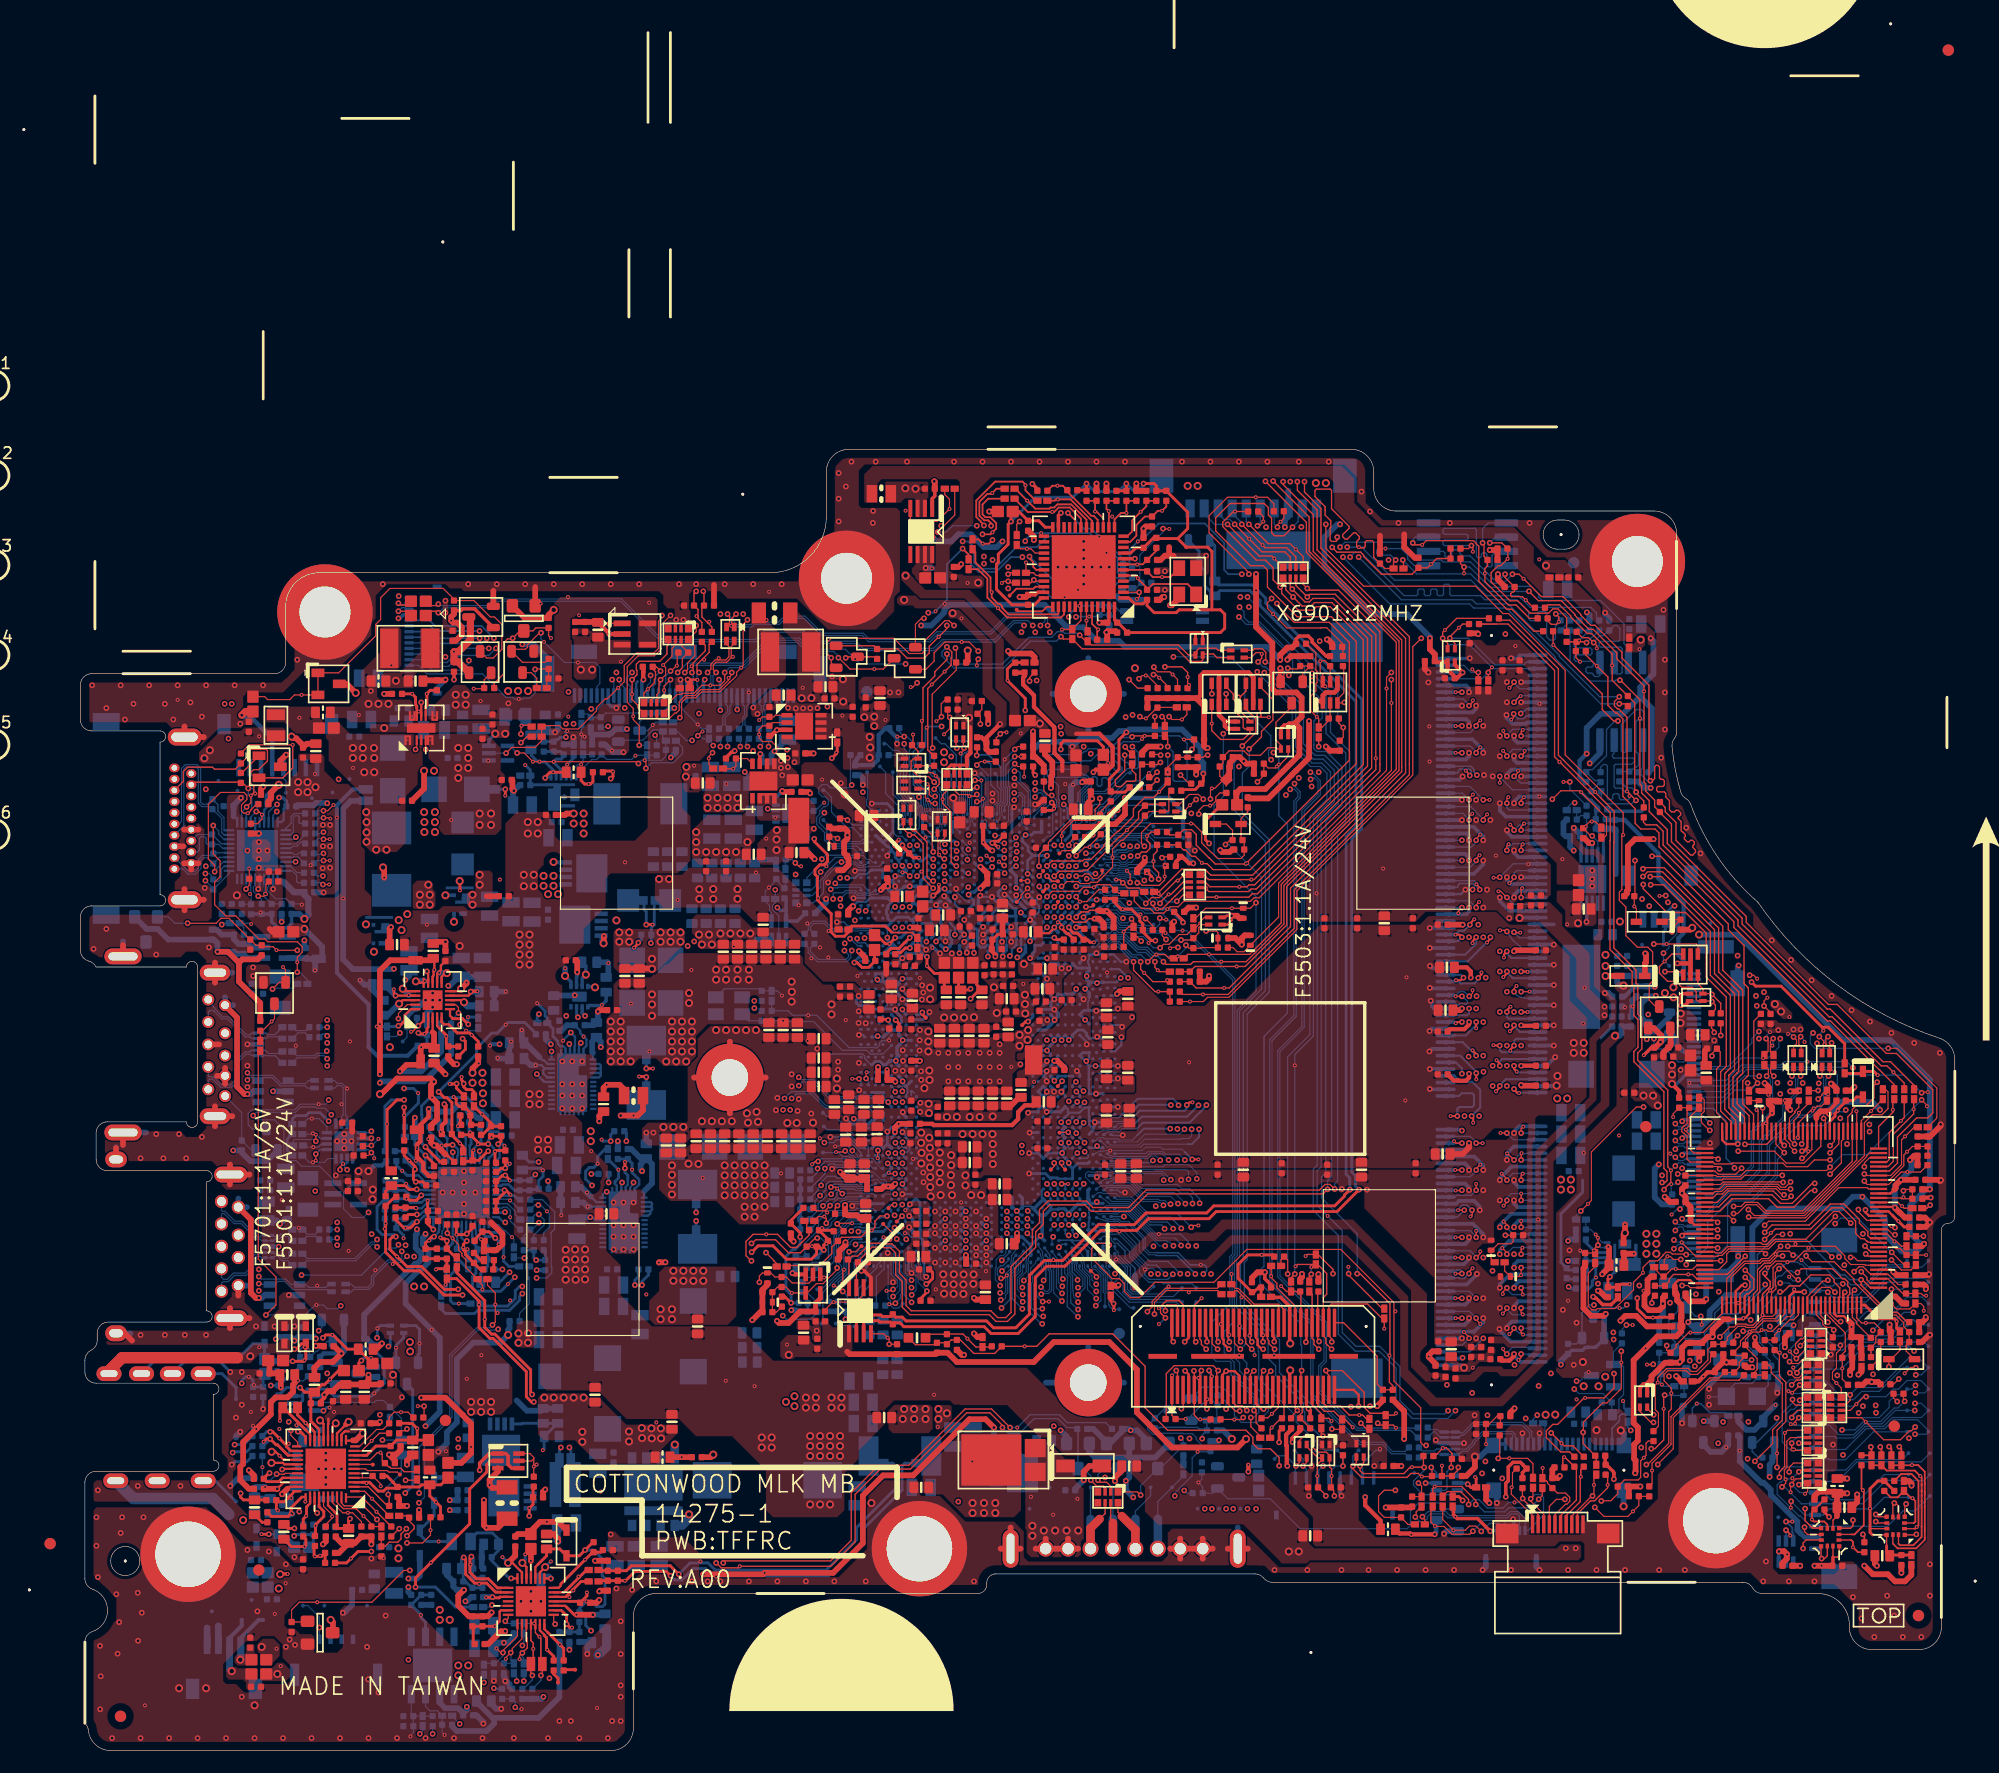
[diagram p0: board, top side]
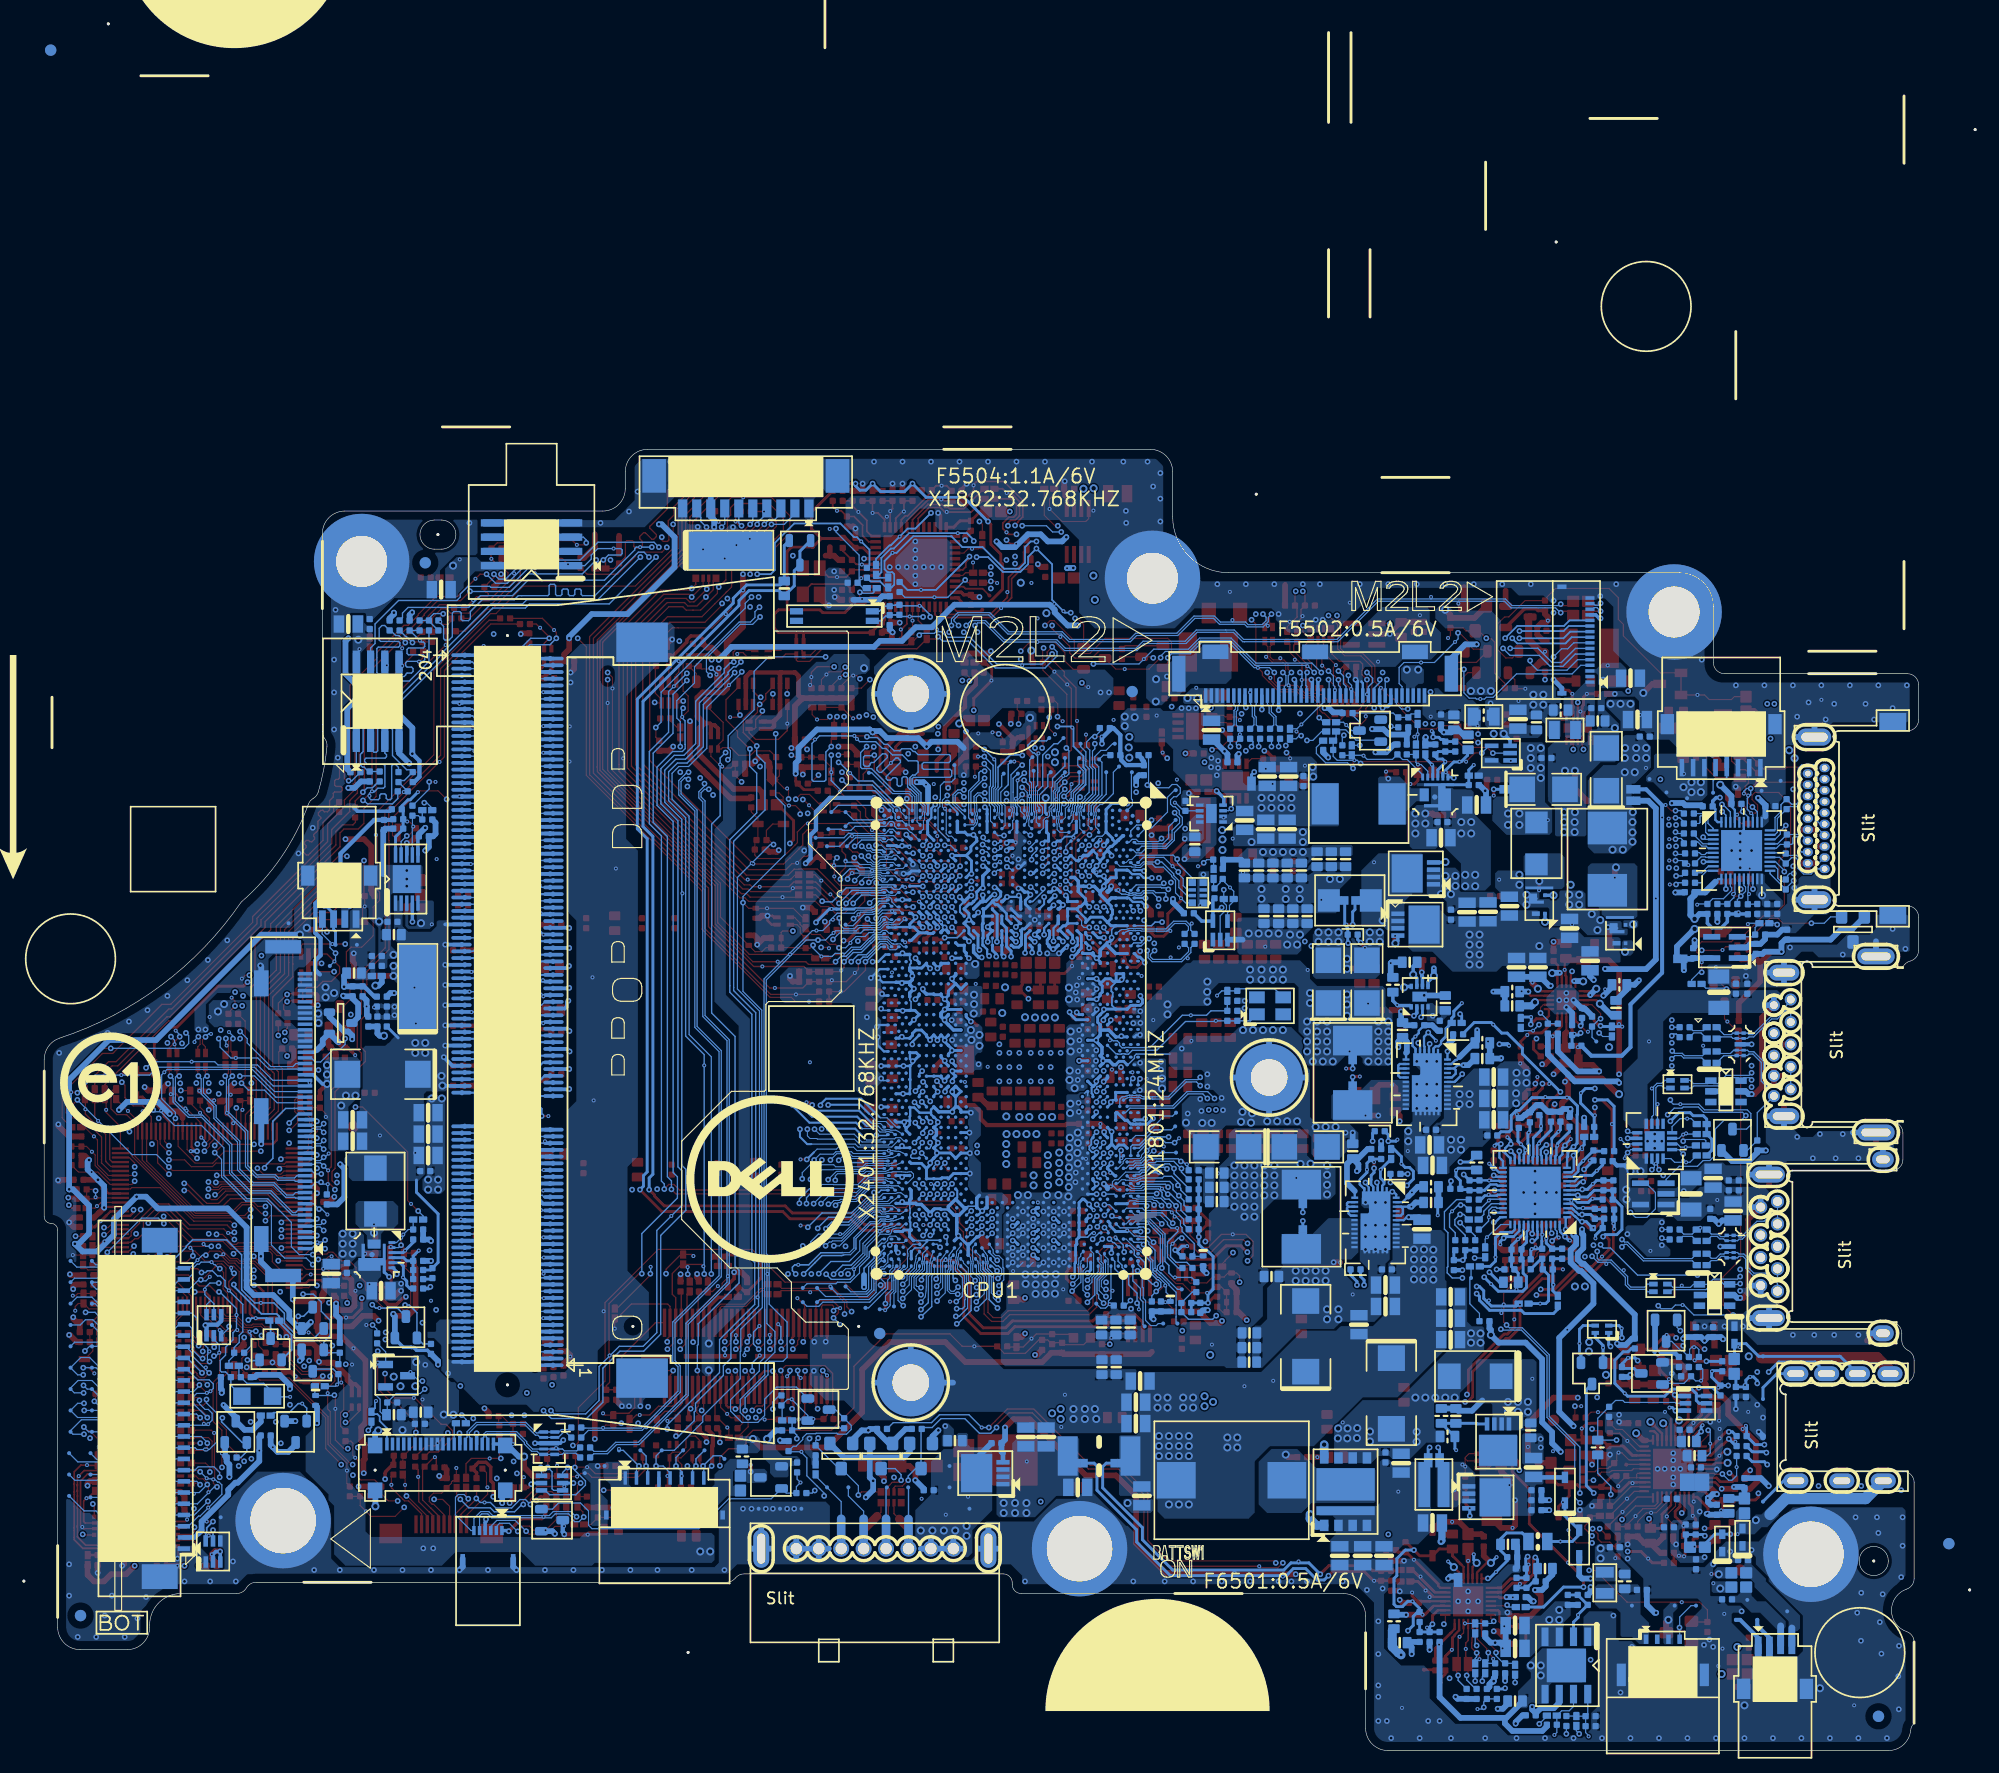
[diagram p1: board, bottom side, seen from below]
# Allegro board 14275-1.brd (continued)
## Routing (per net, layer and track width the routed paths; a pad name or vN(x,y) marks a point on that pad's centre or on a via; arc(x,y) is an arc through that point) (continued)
+VCCCLK5: length 9.6
  TOP w0.254: v2(79.36,67.91) 79.25,67.81 C2122.1 78.29,67.99 R2111.2
  L3 w0.127: v2(75.42,72.11) 75.94,71.59 75.94,70.49 76.36,70.07
  L3 w0.254: v2(79.36,67.91) 78.52,67.91 76.36,70.07
  BOTTOM w0.254: CPU1.L19 75.42,72.64 v2(75.42,72.11)
+VCCCOREG0: length 1.2
  TOP w0.254: v2(75.06,65.8) 75.06,65.63 TP701.1
  BOTTOM w0.254: CPU1.K32 74.86,65.61 v2(75.06,65.8)
+VCCCOREG1: length 1.5
  TOP w0.254: TP707.1 84.28,64.99 v2(84.49,64.99)
  BOTTOM w0.254: v2(84.49,64.99) 84.91,65.41 CPU1.AK32
+VCCDSW_1P0: length 3
  TOP w0.254: C2103.1 85.92,83.81 86.62,83.81 86.77,83.97 v1(86.8,83.97) 86.8,84.3 v2(86.59,84.51)
  BOTTOM w0.127: v2(86.59,84.51) 86.57,84.51 85.69,83.63 CPU1.AL1
+VCCFUSEPRG: length 3.6
  TOP w0.254: v2(72.63,72.46) 72.63,72.44 72.13,71.93 v1(72.13,71.92) 72.12,71.93 71.77,71.93 71.01,72.69 R703.1
  BOTTOM w0.254: v2(72.63,72.46) 73.15,72.46 CPU1.G20
+VCCGT: length 16.9
  BOTTOM w0.114: v2(80.76,46.11) 81.09,45.79 CPU1.AC67 ; CPU1.W71 79.26,43.19 78.93,43.51 ; CPU1.AC71 81.09,43.19 v2(80.76,43.51) ; CPU1.AA71 80.17,43.19 79.85,43.51 ; v2(79.85,44.81) 80.17,44.49 CPU1.AA69 ; v2(76.19,46.11) 76.51,45.79 CPU1.N67 ; v2(79.85,46.11) 80.17,45.79 CPU1.AA67 ; CPU1.AC69 81.09,44.49 v2(80.76,44.81) ; CPU1.AA66 80.17,46.44 v2(79.85,46.76) ; CPU1.U71 78.34,43.19 v2(78.02,43.51)
  BOTTOM w0.127: CPU1.A53 69.47,53.71 68.48,54.7 v2(66.86,54.7) ; 74.07,58.39 CPU1.J43 74.19,58.75 74.35,58.59 ; CPU1.A58 69.78,51.36 69.41,51.36 69.22,51.55 68.9,51.55 68.45,52 67.28,52 67.14,51.86 v2(67.01,51.86) ; v2(68.82,48.56) 69.01,48.75 CPU1.A62
  BOTTOM w0.203: CPU1.J60 v2(73.28,49.61)
  BOTTOM w0.254: v2(68.94,56.33) 69.04,56.23 69.87,56.23 CPU1.A48
  BOTTOM w0.305: v2(69.36,46.27) 69.36,46.27 CPU1.A66
  vias: v1(55.48,51.05) v1(62.47,51.45) v1(74.23,52.75) v1(76.26,41.12) v1(78.52,48.86) v1(80.73,42.74) v2(74.89,57.75) v2(74.86,56.94) v2(75.14,51.53) v2(75.17,50.67) v2(76.19,48.06) v2(76.19,46.76) v2(76.19,44.81) v2(76.19,43.51) v2(77.1,48.06) v2(77.1,46.76) v2(77.1,46.11) v2(77.1,44.81) v2(77.1,43.51) v2(78.02,48.06) v2(78.02,46.76) v2(78.02,46.11) v2(78.02,44.81) v2(78.93,47.41) v2(78.93,46.76) v2(79.85,48.06) v2(79.85,44.16) v2(80.76,47.41) v2(80.76,44.16) v3(52.74,52.16) v3(52.74,51.33) v3(52.74,50.44) v3(52.74,49.57) v3(54.21,52.32) v3(55.1,52.3) v3(57.44,52.16) v3(57.44,51.28) v3(57.44,50.39) v3(57.44,49.5) v3(58.33,52.16) v3(58.33,51.28) v3(58.33,50.39) v3(58.33,49.5) v3(59.21,52.16) v3(59.21,51.28) v3(59.21,50.39) v3(59.21,49.5) v3(59.21,48.48) v3(59.21,47.59) v3(60.1,52.16) v3(60.1,51.28) v3(60.1,50.39) v3(60.1,49.5) v3(60.1,48.48) v3(60.1,47.59) v3(60.99,52.16) v3(60.99,51.28) v3(60.99,50.39) v3(60.99,49.5) v3(60.99,48.48) v3(74.95,54.18) v3(74.96,55.09) v3(74.99,53.28) v3(74.96,52.34) v3(75.62,57.66) v3(75.65,56.83) v3(75.67,54.63) v3(75.72,53.74) v3(75.72,52.88) v3(75.75,51.99) v3(75.76,51.12) v3(75.76,50.23) v3(75.8,49.4) v3(76.61,53.31) v3(76.61,52.39) v3(76.61,51.5) v3(76.61,50.67) v3(76.69,49.52) v3(76.92,42.45) v3(76.99,41.62) v3(76.99,40.73) v3(77.63,53.08) v3(77.63,52.19) v3(77.6,51.3) v3(77.6,50.41) v3(77.71,49.52) v3(77.84,41.56) v3(77.84,40.72) v3(77.86,42.45) v3(78.74,42.45) v3(78.72,41.56) v3(78.72,40.71) v3(78.9,51.28) v3(78.9,50.39) v3(79.41,49.52) v3(79.63,42.45) v3(79.61,41.61) v3(80.3,49.52)
+VCCIO: length 80
  TOP w0.381: R9906.1 107.93,28.6 107.49,28.15 107.49,27.21 107.55,27.15 107.55,25.42 v2(107.6,25.37) ; R801.1 75.95,55.87 76.07,55.76 83.06,55.76 83.6,56.3 83.6,56.92 84.2,57.52 84.92,57.52 PC1035.1
  L3 w0.305: v2(107.6,25.37) 107.6,25.59 107.14,26.05 105.82,26.05 105.42,26.46 98.1,26.46 94.39,30.17 87.94,30.17 84.87,33.24 84.87,42 83.53,43.34 83.53,44.09 82.02,45.6 82.02,48.98 82.78,49.73 82.78,56.93 83.85,58.01 83.85,58.9 84.49,59.53
  L4 w0.102: 75.85,72.36 75.85,71.72
  L6 w0.508: v2(86.14,60.57) 84.84,60.57 84.61,60.8 84.61,62.3 85.27,62.96 85.27,65.35 84.92,65.7 v3(84.23,65.7)
  BOTTOM w0.254: v2(86.14,59.66) 86.14,59.83 CPU1.AM42 86.14,60.41 v2(86.14,60.57) 86.13,60.58 CPU1.AL42
  vias: v1(67.93,92.27) v1(84.06,68.34) v3(70.36,90.37) v3(70.42,89.43) v3(70.36,88.51) v3(84.21,67.38) v3(84.21,66.54)
+VCCMPHYGTAON_1P0_LS_SIP: length 12
  L6 w0.254: v2(82.23,70.78) 82.07,70.94 82.07,70.99 81.62,71.45 80.17,71.45 79.01,72.61 78.92,72.61 v2(78.8,72.74)
  BOTTOM w0.102: CPU1.AF20 82.58,72.42 82.58,71.8 CPU1.AF21
  BOTTOM w0.178: v2(77.12,72.15) 77.12,73.32 CPU1.N18
  BOTTOM w0.254: CPU1.T20 78.52,72.58 78.64,72.58 v2(78.8,72.74) ; v2(82.23,70.78) 82.23,71 82.57,71.34 CPU1.AF21
  BOTTOM w0.305: CPU1.P15 77.04,76.18 v2(77.01,76.18) ; CPU1.N17 CPU1.N18 ; CPU1.N15 76.59,75.69 v2(76.28,75.38) 76.63,75.04 CPU1.N16 ; v2(77.12,75.36) 77.44,75.04 CPU1.P16 ; v2(78.8,72.74) 78.45,73.09 CPU1.T19
  vias: v1(61.14,81.3) v2(65.39,82.19) v3(62.08,82.06) v3(62.06,81.22) v3(62.06,80.28)
+VCCPAZIO: length 38
  TOP w0.254: v2(84.23,92.73) 84.23,93.8 82.66,95.37 v1(82.66,95.4) 82.63,95.42 82.63,96.41 83.2,96.98 R2101.2 83.36,97 R2102.2
  L4 w0.254: v2(83.73,71.37) 84.65,71.37 85.17,71.88 85.17,72.42 82.99,74.6 82.99,75.98 82.9,76.07 82.9,78.42 82.89,78.43 82.89,82.34 81.14,84.09 79.71,84.09 79.22,84.58 79.22,89.1 79.41,89.29 79.41,91.4 79.83,91.82 79.83,91.82 80.17,92.17 83.73,92.17 84.23,92.68 v2(84.23,92.73)
  BOTTOM w0.254: v2(83.73,71.37) 83.85,71.49 83.85,72.7 CPU1.AJ19
+VCCPDSW_3P3: length 33.7
  TOP w0.254: v2(95.83,72.21) 95.49,72.21 94.72,72.98 R1703.1 94.72,73.68 94.44,73.96 94.44,74.26 93.7,75.01 v1(92.91,75.01) 92.79,75.01 92.23,75.56 R1707.1 92.13,75.96 91.45,75.96 R1723.1 ; R1711.2 91.19,89.49 90.67,90.01 87.67,90.01 87.41,89.75 v2(87.41,89.25)
  L3 w0.254: v2(80.91,70.78) 80.91,70.94 81.44,71.47 83.09,71.47 83.84,72.22 v2(83.84,74.71)
  L4 w0.254: v2(95.83,72.21) 95.83,72.01 95.71,71.89 95.71,71.55 95.12,70.96 93.23,70.96 92.34,71.85 86.52,71.85 86.27,72.1
  BOTTOM w0.254: v2(80.91,70.78) 80.91,71.28 81.31,71.69 81.31,72.91 81.31,72.91 81.31,73.32 CPU1.AD18 CPU1.AD17 ; CPU1.AJ17 84.16,74.39 v2(83.84,74.71)
+VCCPRTC_3P3: length 36
  TOP w0.254: C2117.1 98.3,73.98 v2(98.3,73.82) ; v2(100.62,80.87) 100.29,81.2 100.29,82.91 101.7,84.31 R2106.2 ; C2118.1 87,72.29 v2(86.82,72.47)
  L3 w0.254: v2(86.82,72.47) 91.47,72.47 92.1,73.09 98,73.09 98.3,73.4 v2(98.3,73.82) 98.59,74.11 98.59,76.93 100.62,78.97 v2(100.62,80.87)
  BOTTOM w0.127: CPU1.AK19 85.7,72.47 v2(86.82,72.47) ; CPU1.BB14 92,75.73 92.68,75.73 93.23,75.17 93.35,75.17 93.41,75.11 94.8,75.11 94.9,75.01
  BOTTOM w0.254: v2(98.3,73.82) 97.1,75.02 v1(96.91,75.02) 96.47,75.02 96.46,75.01 94.9,75.01
+VCCSA: length 2
  TOP w0.508: R735.1 71.84,69.23
  BOTTOM w0.127: CPU1.G27 73.29,68.03 v2(73.29,67.9) 73.29,67.76 CPU1.G28
  vias: v1(53.25,75.84) v1(60.23,78.28) v1(64.04,75.36) v1(65.95,71.6) v1(69.27,69.06) v1(74.84,68.88) v2(75.04,68.22) v2(75.01,66.95) v2(75.14,67.58) v3(51.59,77.69) v3(52.48,77.69) v3(55.18,76.78) v3(55.18,75.93) v3(56.42,76.8) v3(56.42,75.91) v3(58.58,76.8) v3(58.58,75.93) v3(75.75,68.01) v3(75.75,66.97) v3(84.11,70.12)
+VCCSFR: length 1.3
  BOTTOM w0.203: CPU1.K20 74.96,72.37 74.96,71.85 CPU1.K21
  BOTTOM w0.254: CPU1.K21 75.39,71.42 v2(75.39,71.39)
  vias: v1(75.95,71.57)
+VCCST_CPU: length 84.3
  TOP w0.254: R603.2 67.07,46.38 R723.1 66.64,45.58 R726.1 66.28,45.07 v2(66.28,44.62) 66.17,44.62 65.87,44.93 R727.1 65.63,44.26 65.18,43.81 62.93,43.81 61.74,45 60.42,45 59.86,44.43 v2(59.84,44.43)
  L4 w0.254: v2(67.44,73.86) 67.42,73.88 65.79,73.88 64.55,72.64 64.55,63.6 60.51,59.56 60.51,58.77 58.81,57.07 58.81,56.56 58.91,56.46 58.91,55.64 59.29,55.26 60.99,55.26 61.85,54.41 61.85,47.76 59.81,45.72 59.62,45.72 59.32,45.42 59.32,44.95 v2(59.84,44.43) 59.98,44.43 60.58,43.84 60.58,43.42 54.76,37.61 48.73,37.61 45.46,40.88 42.79,40.88 41.45,42.22 41.45,42.9 v2(40.63,43.72)
  BOTTOM w0.127: v2(67.44,73.86) 68.07,73.86 68.39,73.53 CPU1.A18
  BOTTOM w0.254: v1(65.21,44.96) 65.21,44.97 65.66,44.97 66.01,44.62 v2(66.28,44.62) 65.72,44.06 R419.1 ; PR4621.1 PR4622.1 40.42,43.94 v2(40.63,43.72) PC4610.1 41.43,44.48 PR4623.2
+VCCSTG: length 84.8
  TOP w0.254: v2(63.35,39.91) 62.8,40.46 R1722.1 ; R703.2 70.8,70.47 C4008.1 70.28,69.82 69.67,69.82 69.24,70.25 v2(68.99,70.25) ; R4042.2 67.47,89.05 v1(67.39,88.97) 67.39,88.87 v2(66.99,88.46) ; R423.2 63.33,47.25 C717.1 64.17,46.15 v2(64.17,45.79)
  L4 w0.254: v2(63.35,39.91) 62.97,40.29 62.97,42.95 61.7,44.22 61.7,46.22 63,47.51 63,54.57 61.32,56.25 61.32,57.09 61.12,57.29 61.12,59.31 65.18,63.37 65.18,69.56 65.92,70.3 68.76,70.3 68.81,70.25 v2(68.99,70.25) 69.1,70.25 70.47,71.61 70.47,72.64 69.61,73.5 68.83,73.5 68.49,73.85 68.49,74.44 68.15,74.77 66.89,74.77 65.96,75.7 65.96,77.41 66.45,77.9 66.48,77.9 66.86,78.28 66.86,82.49 67.06,82.7 67.06,85.92 66.96,86.02 66.96,86.63 67.06,86.74 67.06,88.39 v2(66.99,88.46)
  BOTTOM w0.254: v2(68.99,70.25) 68.99,70.32 69.41,70.73 69.59,70.73 CPU1.A22 ; PR4624.1 R401.1 64.83,39.91 R2440.1 v2(63.35,39.91) 63.35,40.66 62.9,41.12 62.9,44.06 63.51,44.67 63.71,44.67 64.17,45.13 v2(64.17,45.79) 64.18,45.8 R421.2 R416.2 R417.2 R408.2 R422.2 R409.2
+VDD18: length 30.5
  TOP w0.203: 22.64,21.3 22.08,21.87 HDA27.38 ; HDA27.18 21.28,28.63 21.11,28.8
  TOP w0.254: C2728.1 20,31.95 v2(19.59,32.35) ; C2728.1 20.54,31.63 C2727.1 20.54,29.37 21.11,28.8 ; C2728.1 21.52,32.61 21.75,32.61 v1(22.26,33.11) 23.02,33.88 R2725.2 ; 22.64,21.3 22.88,21.07 22.88,20.08 C2712.1 22.93,19.81 C2726.1 23.91,20.54 v2(24.04,20.67)
  L6 w0.254: v2(24.04,20.67) 23.78,20.92 23.78,25.49 19.59,29.69 v2(19.59,32.35)
  BOTTOM w0.254: R2916.1 18.36,32.35 v2(19.59,32.35)
+VDDQ_CPU_CLK: length 0.6
  BOTTOM w0.254: v2(86.16,61.46) 86.16,61.35 CPU1.AM40
  vias: v1(85.02,59.61)
AV1_TP: length 5.9
  BOTTOM w0.102: TP2307.1 93.33,87.17 91.47,85.31 90.02,85.31 89.73,85.02 CPU1.AV1
AV71_TP: length 2
  TOP w0.102: TP2304.1 90.58,42.26 v2(90.58,42.22)
  BOTTOM w0.102: v2(90.58,42.22) 90.58,42.31 89.8,43.09 CPU1.AV71
AVDD5V: length 28.8
  TOP w0.203: 18.03,24.31 HDA27.29
  TOP w0.254: 18.03,24.31 17.69,23.97 16.61,23.97 C2713.1 16.35,24.29 16.8,24.74 v2(16.86,24.74) ; R2722.2 R2726.2 23.79,35.78 22.52,37.05 v1(22.46,37.05) 21.88,37.05 v2(21.62,36.8)
  L4 w0.254: v2(16.86,24.74) 16.86,24.41 17.18,24.1 18.07,24.1 18.57,24.61 18.57,27.65 17.24,28.99 17.24,30.64 16.29,31.59 16.29,33.11 16.67,33.5 19.11,33.5 21.62,36 v2(21.62,36.8)
GND: length 1427.7
  TOP w0.114: v2(160.05,21.05) 160.26,20.84 U7001.7 ; U7002.6 153.83,18.77 153.58,18.51 v2(153.58,18.02) ; U7002.5 153.96,19.27 153.7,19.53 v2(153.7,19.91) ; U7002.7 155.18,17.16 v2(155.23,17.11) 155.48,17.11 155.74,17.37 U7002.8 ; U7001.8 160.18,20.28 v2(160.05,20.41) ; U7001.5 162.08,21.81 161.83,22.07 v2(161.71,22.07) 161.58,21.93 U7001.6
  TOP w0.203: v2(109.48,30.48) 109.48,30.61 109.3,30.79 XDP1.49 ; KBC24.64 146.36,54.43 146.71,54.07 v2(147.75,54.07) ; RN1703.1 102.25,73.63 102.62,74 v2(102.62,74.42) 102.2,74.42 102.05,74.28 RN1703.2 ; XDP1.38 106.3,36.92 106.43,36.8 v2(106.43,36.45) ; XDP1.59 113.51,32.16 113.95,31.72 v2(113.95,30.7) ; v2(142.79,45.91) 142.95,46.07 KBC24.84 ; XDP1.14 100.3,36.92 100.43,36.8 v2(100.43,36.45) ; XDP1.7 98.8,33.53 v2(98.48,33.85) ; XDP1.26 103.3,36.58 v2(103.43,36.45) ; KBC24.124 157.16,40.73 v2(157.29,40.86) ; XDP1.20 101.8,36.75 101.91,36.64 101.91,36.26 v2(102.39,35.78) ; v2(105.44,35.78) 105.32,35.78 104.93,36.16 104.93,36.67 104.8,36.8 XDP1.32 ; XDP1.31 104.8,30.92 105.28,30.45 v2(105.48,30.45) 105.53,30.45 105.69,30.6 106.13,30.6 106.3,30.78 XDP1.37 ; KBC24.17 159.45,47.67 159.14,47.98 v2(159.14,48.2) ; v2(100.43,30.47) 100.3,30.6 XDP1.13 ; KBC24.100 147.56,40.94 148.11,41.5 v2(148.39,41.5) ; XDP1.19 101.8,33.49 v2(102.14,33.83) 102.9,33.83 103.3,33.43 XDP1.25 ; KBC24.51 151.56,54.28 v2(151.9,53.94) ; v2(86.82,73.38) 86.82,73.35 86.34,72.87 85.5,72.87 PC1038.2 ; v2(97.43,36.45) 97.3,36.58 XDP1.2 ; U4001.11 v2(30.39,93.44) ; XDP1.50 109.3,36.47 v2(109.25,36.42) ; PU4401.22 v2(41.94,15.33) ; v2(98.45,36.44) 98.8,36.8 XDP1.8
  TOP w0.254: v2(155.89,20.84) 155.48,21.24 R7019.1 ; v2(29.81,56.42) 29.7,56.31 PG4601.2 ; C2121.2 81.78,72.76 C2120.2 ; C9901.2 106.86,28.48 v2(106.86,27.48)
  TOP w0.305: U6901.35 85.34,103.26 85.12,103.03 C6903.2 ; C9904.2 106.14,41.52 105.59,42.07 v2(105.59,42.64) ; U4101.1 75.94,111.61 76.17,111.84 C4102.2 ; PQ4407.4 38.45,25.17 38.13,25.49 38.13,26.26 37.91,26.48 PQ4407.1 36.45,26.48 35.59,25.62 v2(35.59,24.99) ; U6901.47 91.69,100.71 C6904.2 ; v2(87.41,110.33) 87.19,110.11 U6901.23 ; v2(58.33,89.12) 58.2,88.99 58.03,88.99 57.55,88.51 C1719.2 ; v2(69.63,42.77) 69.88,42.77 70.48,42.17 THM261.5 ; v2(109.48,30.48) 109.63,30.32 C9903.2 ; v2(84.87,112.92) 85.31,112.48 R6908.1 ; U6901.8 v2(94.01,106.26)
  TOP w0.356: U1701.3 63.75,42.45 63.74,42.46 63.58,42.46 v2(63.48,42.56) ; v2(21.75,31.72) 21.75,31.46 21.43,31.15 C2727.2
  TOP w0.381: v2(81.57,70.78) 81.57,70.96 81.25,71.28 C2108.2 81.25,72.23 C2121.2 ; v2(127.8,35.35) 127.78,35.33 127.78,35.15 127.39,34.77 126.71,34.77 C1206.2 ; C4033.2 61.57,90.47 v2(62.08,90.98) 62.1,91 U4002.3 ; PR4652.2 32.23,55.71 32.55,56.04 32.55,57.52 v2(32.44,57.63) ; U5501.2 v2(47.15,99.54) 47.15,99.56 C5505.2 ; C1211.2 128.44,61.05 v2(128.44,61.05) ; EC5501.2 50.2,96.55 50.2,96.15 50.17,96.13 50.17,95.58 50.2,95.55 v2(50.2,95.47) ; C1212.2 128.48,64.61 v2(128.44,64.65) ; v2(123.8,60.34) 123.8,59.99 123.52,59.71 122.86,59.71 122.83,59.73 122.43,59.73 122.05,60.11 122.05,60.13 C1221.2 ; R2449.1 142.53,58.79 v3(141.89,59.43) ; C1207.2 123.6,69.82 123.95,69.47 v2(123.95,68.91) ; v2(85.1,84.34) 85.38,84.34 85.77,84.74 C2103.2 ; v2(123.8,64.95) 123.8,64.73 123.38,64.31 122.09,64.31 C1213.2
  TOP w0.406: Q1701.4 112.06,94.6 111.79,94.33 111.03,94.33 110.76,94.06 Q1701.1 110.59,93.56 v2(110.13,93.56)
  TOP w0.508: EC8915.2 30.64,85.76 v3(30.64,87.34) ; v2(94.14,112.95) R6914.1 R6916.1 ; EC8926.2 27.57,73.27 v2(27.69,73.4) ; C1154.2 87.73,60.86 87.1,61.49 v2(86.82,61.49) ; C2405.2 141.08,40.37 v2(141.08,39.85) 141.08,39.6 140.74,39.26 139.82,39.26 139.43,39.65 139.43,40.54 139.71,40.81 139.71,41.95 140.01,42.26 R2436.2 ; R2717.2 23.04,17.62 C2726.2 ; USB2.4 14.08,40.56 ; v2(144.32,34.76) 144.32,35.22 C2420.2 C2413.2 ; v2(106.97,96.48) 107,96.45 Q1802.S ; v2(157.77,33.5) 157.77,33.9 157.96,34.09 R2454.2 157.89,35.08 C2428.2 ; 13.33,37.66 USB2.11 ; USB2.11 15.07,38.55 ; USB2.11 13.33,39.44 ; v2(163.24,23.62) 163.24,23.8 163.01,24.03 R7007.1 ; C2402.2 149.68,58.79 C2423.2 150.53,59.12 v2(150.15,59.51) ; 57.9,56.81 HS1.1 ; HS1.1 57.9,63.19 ; HS1.1 61.09,60 ; HS1.1 54.71,60 ; EC1705.2 103.79,72.68 103.54,72.42 v2(103.54,71.85) 102.95,72.43 EC1711.2 ; PR4517.2 32.8,61.69 33.31,61.18 v2(33.56,61.18) ; 9.88,78.54 HDMI1.2 ; HDMI1.2 9.24,79.1 ; HDMI1.2 10.52,79.1 ; v2(123.16,66.15) 123.02,66.01 C1209.2 ; C2713.2 15.46,24.54 v2(15.02,24.99) ; EC6503.2 123.54,24.48 124.31,25.25 v3(124.31,26.21) ; v2(80.25,78.79) 80.84,78.2 C2107.2 C2106.2 80.7,77.31 v2(80.25,76.86) ; PC4524.2 31.6,72.1 v2(32.54,72.1) PC4513.2 ; v2(68.15,48.63) 68.17,48.62 R406.2 68.26,47.85 68.39,47.72 69.22,47.72 69.5,47.44 PC1033.2 ; C2409.2 R2448.2 164.89,54.74 165.84,55.69 v2(165.84,55.82) ; v2(115.6,30.7) 116.11,31.21 R9931.2 ; v2(135.29,40.99) 135.4,40.99 135.97,40.42 PC5110.2 ; v2(105.59,42.64) 104.94,42.64 104.44,42.14 C9902.2 ; v2(97.14,102.1) 97.31,102.1 97.95,102.74 X6901.4 ; 67.51,78.48 68.01,78.48 68.49,78.95 68.49,79.48 68.38,79.59 68.38,79.72 C2116.2 68.09,80 EC1702.2 68.09,81.01 68.38,81.3 v2(68.38,81.6) 68.38,81.96 68.14,82.2 EC1706.2 66.94,82.2 66.78,82.35 R1717.2 ; C2411.2 156.55,59.02 156.12,59.45 v2(156.05,59.45) ; v2(42.58,18.64) 42.58,18.89 42.17,19.3 PC4422.2 ; v2(25.69,33.5) 25.69,33.01 C2708.2 ; C1220.2 127.9,71.34 v2(127.8,71.25) ; C4032.2 64.62,88.89 v2(65.36,88.89) ; PD4301.3 23.74,95.09 v3(24.54,94.29) ; 98.05,17.11 BATT1.7 ; BATT1.7 98.94,18 ; BATT1.7 98.05,18.89 ; BATT1.7 97.16,18 ; C9905.2 108.74,42.05 108.9,42.21 v2(108.9,42.49) ; v2(128.44,59.33) 128.49,59.28 C1222.2 ; C2429.2 165.64,50.88 165.78,50.75 v2(165.87,50.84) ; 9.28,74.91 HDMI1.20 ; HDMI1.20 9.28,76.79 ; HDMI1.20 10.99,75.85 ; C2708.2 26.66,32.63 C2722.2 ; C2708.2 C2706.2 23.11,32.63 C2711.2 22.07,32.04 v2(21.75,31.72) ; v2(16.3,85.93) 16.1,85.73 C5701.1 ; R2445.1 142.73,32.92 v2(142.27,33.38) ; 12,70.24 USB1.11 12,68.46 ; v2(96.3,89.5) 95.16,89.5 94.65,88.99 R1825.2 ; v2(92.23,24.02) 92.23,24.35 92.84,24.96 EC8931.2 ; 82.04,18 BATT1.9 ; BATT1.9 83.81,18 ; BATT1.9 82.93,19.88 ; 12.9,59.44 USB1.4 ; USB1.4 12.19,60.15 ; USB1.4 12.9,60.86 ; EC5504.2 56.48,103.92 ; C7007.2 158.4,22.17 v2(158.4,22.83) ; EC2502.2 126.97,103.78 126.37,104.38 v2(126.37,104.87) ; v2(92.54,41.5) 92.48,41.43 R602.2 ; v2(141.24,49.37) 141.69,48.91 C2410.2 ; C715.2 83.7,58.24 82.94,57.47 PC1008.2 ; 10.52,82.1 HDMI1.8 9.24,82.1 ; EC8903.2 22.64,36.04 v2(23.27,35.4) 22.51,34.64 21.37,34.64 20.86,34.13 C2728.2 ; EC4301.2 20.19,89.76 EC4302.2 19.84,89.63 19.23,90.25 18.97,90.25 v3(18.83,90.39) ; v2(79.66,40.35) 79.81,40.2 PC1034.2 ; v2(92.41,67.46) 92.64,67.68 PC1058.2 ; 97.44,106.52 97.06,106.52 ; 97.06,106.52 TP6901.1 ; 97.06,106.52 96.68,106.52 96.3,106.14 C6902.2 ; v3(50.96,69.69) 50.93,69.72 PC1012.2 PC1013.2 ; R2510.2 144.81,62.39 144.81,61.21 C2417.2 ; PQ4301.E 36.81,103.4 ; C1148.2 78.96,44.13 v2(78.93,44.16) ; 10.99,90.35 HDMI1.21 9.28,91.29 ; v2(86.52,85.82) 86.52,85.94 86.54,85.97 86.54,86.86 86.65,86.96 86.65,88.13 85.99,88.79 C1106.2 ; C4102.2 76.17,113.1 v2(76.12,113.15) ; C4015.2 38.51,86.47 38.51,85.69 v2(38.64,85.57) ; R1823.2 80.93,92.36 v2(80.93,91.53) ; v2(92.46,83.85) 92.23,83.85 R2019.2 ; v2(68.21,45.31) 68.21,45.08 67.66,44.54 67.66,43.91 C2608.2 ; v2(83.5,46.11) 83.5,45.44 PC1044.2 ; C2726.2 23.3,18.48 22.77,19.02 C2712.2 ; C2726.2 24.45,18.48 C2701.1 C2723.1 v2(25.94,18.38) ; v2(164.88,37.05) 164.81,37.05 164.17,36.42 EC1707.2 ; v2(164.81,42.46) 164.73,42.38 C2414.2 ; v2(59.9,38.37) 60.61,39.08 R1719.2 EC1708.2 C1711.2 60.8,41.08 61.25,41.52 EC1709.2 ; C6907.2 v2(94.77,108.93) 94.96,109.12 R6918.1 ; 9.18,80.61 8.39,80.61 HDMI1.5 ; C1182.2 64.86,80.05 v2(65.45,79.47) ; 12,55.66 USB1.12 ; USB1.12 13.54,56.55 ; USB1.12 12,57.44 ; 4.6,36.54 3.95,37.2 USB2.12 ; PD4304.A 89.95,25.37 89.44,24.86 v2(89.44,24.1) ; R6910.1 v2(90.58,112.95) ; C4101.2 78.28,105.52 v2(78.52,105.76) ; v2(123.8,54.15) 123.8,53.75 123.22,53.18 C1208.2 ; C6905.2 92.3,99.79 91.57,99.79 v2(91.47,99.69) 91.54,99.62 R6907.2 ; EC8906.2 43.21,83.41 43.34,83.53 v3(43.97,83.53) ; v2(46.13,65.88) 46.26,66.01 EC1001.2 ; R1816.2 EC1808.2 107.92,97.57 v2(107.6,97.25) ; C2721.2 28.42,22.47 C2714.2 v2(29.12,21.81) ; EC8913.2 24.23,55.15 ; C7003.2 v2(162.34,15.84) ; C6903.2 84.3,102.84 v2(83.73,102.84) ; R402.2 v2(110.37,42.46) ; v2(161.29,37.97) 161.29,37.4 C2426.2 EC6601.2 ; EC1902.2 EC1901.1 100.36,68.55 100.62,68.8 v2(100.62,69.06) ; v2(125.64,107.03) 126.21,107.03 EC2503.2 EC2501.2 ; BATT1.8 100.05,18.89 ; BATT1.8 100.94,18 ; BATT1.8 99.16,18 ; BATT1.8 100.05,17.11 ; C6906.2 96.22,102.58 96.48,102.84 v2(96.63,102.84) ; Q2505.S 141.73,64.01 141.76,63.97 141.76,63.12 141.76,62.87 C2421.2 141.12,62.22 C2416.2 ; v2(120.17,96.11) 119.86,96.42 EC8910.2 ; C1102.2 74.83,61.5 v2(74.84,61.49) ; 102.29,18 BATT1.10 104.06,18 ; EC1712.2 111.6,98.67 111.22,99.05 v2(111.12,99.05) ; C1805.2 EC1806.2 103.93,87.98 103.72,88.2 v2(103.71,88.2) 103.35,88.56 C1806.2 102.74,88.34 102.46,88.06 EC1807.2 102.41,87.68 G1801.1 ; USB2.10 15.07,51.35 ; USB2.10 13.33,52.24 ; USB2.10 13.33,50.46 ; C2710.2 29.12,25.85 v2(29.12,25.49) ; C2709.2 26.58,29.18 v2(26.7,29.3) ; PR4501.2 35.47,61.31 34.96,60.8 v3(34.96,60.42) ; R6912.1 v2(91.47,112.95) ; R2611.2 79.98,36.86 v2(79.66,37.18) ; R1715.2 EC1703.2 C1701.2 99.47,87.53 v2(99.47,87.01) ; v2(46.26,56.1) 46.26,56.58 PC4709.2 ; v2(111.03,89.5) 111.4,89.13 C1710.2 ; C2406.2 143.1,40.44 143.49,40.05 144.74,40.05 144.92,40.23 v2(144.94,40.23) ; v2(102.62,74.42) 103.11,74.42 103.34,74.2 EC1704.2 ; D2601.A v3(135.96,69.06) ; R601.2 70.12,50.76 PC1074.2 PC1069.2 68.31,51 v2(67.72,51.58) ; USB1.13 3.8,71.81 ; C7004.2 159.98,16.66 v2(160.15,16.48) ; USB1.7 12.36,62.95 ; C2112.2 94.2,78.55 94.88,79.23 v2(94.88,79.6) ; C716.2 68.45,74.89 68.83,75.26 v2(68.89,75.26) ; C1183.2 82.2,72.8 C2120.2 ; C5516.2 30.6,95.41 C4002.2 32.48,95.41 v2(32.54,95.47) ; v2(134.78,80.91) 134.5,80.91 134.06,81.34 PC5119.2 ; C717.2 63.33,45.63 v2(63.58,45.38) ; C4001.2 v2(27.08,94.2) ; C1216.2 124.56,99.6 v2(124.62,99.54) ; v2(65.06,85.34) 64.93,85.46 C4031.2 ; EC8907.2 36.23,76.17 ; v2(44.29,69.38) 44.29,70.32 EC8908.2 ; v2(117.76,25.37) C6503.2 ; PC4527.2 31.55,61.28 v2(32.54,60.29) ; v2(123.22,73.63) C1210.2 ; C2117.2 98.78,75.15 v2(99.47,75.15) ; C5505.2 46.09,100.62 C5507.2 C5508.1 ; C4008.2 69.97,70.69 v2(69.4,71.27) ; v2(15.91,81.76) 15.89,81.74 R5414.1 ; C1104.2 89.85,84.5 v2(90.2,84.85) 90.08,84.98 R1502.2 ; EC2701.2 28.04,25.86 v2(27.51,26.38) 28.13,26.38 28.54,26.8 C2707.2 ; C6901.2 85,108.24 v2(85,107.92) ; C2418.2 164.47,46.68 v2(164.88,47.08) 164.45,47.52 C2412.2 ; USB1.14 3.8,53.98 ; C6904.2 v2(90.84,100.55) ; PD4302.1 40.55,103.73 ; EC2708.2 v2(30.19,21.45) ; USB2.13 3.18,53.72
  L3 w0.508: 127.17,95.88 v2(127.17,95.25) ; 127.17,95.88 128.07,95.88 128.44,95.51 v2(128.44,95.25) v2(128.44,93.45) 129.41,93.45 129.98,92.88 129.98,87.95 129.31,87.28 129.31,78.72 v2(128.44,77.85) 129.32,76.97 129.32,60.21 v2(128.44,59.33) ; 127.17,95.88 126.31,96.74 122.46,96.74 120.94,95.22 v2(120.17,95.22) 118.33,95.22 112.62,89.5 v2(111.03,89.5) 111.03,88.99 110.2,88.17 109.7,88.17 108.87,87.34 108.87,86.96 v2(108.62,86.71) 108.49,86.84 107.88,86.84 106.33,85.28 106.33,83.15 99.47,76.29 v2(99.47,75.15) 99.47,73.59 99.25,73.36 99.25,71.28 98.95,70.98 ; HDMI1.2 10.52,79.1 ; HDMI1.2 9.88,78.54 ; HDMI1.2 9.24,79.1 ; 100.05,17.11 BATT1.8 ; BATT1.8 100.94,18 ; BATT1.8 99.16,18 ; BATT1.8 100.05,18.89 ; 98.05,17.11 BATT1.7 ; BATT1.7 98.05,18.89 ; BATT1.7 97.16,18 ; BATT1.7 98.94,18 ; USB1.13 3.8,71.94 ; 12,55.66 USB1.12 12,57.44 ; USB1.4 12.9,60.86 ; USB1.4 13.61,60.15 ; USB1.4 12.9,59.44 ; USB1.4 12.19,60.15 ; 104.06,18 BATT1.10 102.29,18 ; 13.33,52.24 USB2.10 13.33,50.46 ; HDMI1.20 9.28,76.79 ; HDMI1.20 9.28,74.91 ; HDMI1.20 10.99,75.85 ; 9.28,89.41 HDMI1.21 ; HDMI1.21 10.99,90.35 ; HDMI1.21 9.28,91.29 ; USB1.14 5.86,55.1 ; 82.04,18 BATT1.9 ; BATT1.9 83.81,18 ; BATT1.9 82.93,19.88 ; 12.58,45.71 USB2.7 12.58,44.19 ; USB2.12 4.46,37.2 ; 13.33,37.66 USB2.11 ; USB2.11 13.33,39.44 ; USB2.11 15.07,38.55 ; 14.08,42.21 USB2.4 14.08,40.69 ; 12,68.46 USB1.11 12,70.24 ; USB1.7 11.4,63.66 ; USB2.13 3.18,53.66
  L4 w0.508: HDMI1.21 10.99,90.35 ; HDMI1.21 9.28,89.41 ; HDMI1.21 9.28,91.29 ; BATT1.7 98.94,18 ; BATT1.7 97.16,18 ; BATT1.7 98.05,17.11 ; BATT1.7 98.05,18.89 ; 12,70.24 USB1.11 12,68.46 ; USB2.4 14.08,42.21 ; USB2.4 14.84,41.45 ; USB2.4 14.08,40.69 ; 99.16,18 BATT1.8 ; BATT1.8 100.94,18 ; BATT1.8 100.05,18.89 ; BATT1.8 100.05,17.11 ; USB1.7 12.21,62.95 ; USB1.13 3.8,72.06 ; USB1.12 13.54,56.55 ; USB1.12 12,57.44 ; USB1.12 12,55.66 ; USB2.11 15.07,38.55 ; USB2.11 13.33,37.66 ; USB2.11 13.33,39.44 ; HDMI1.2 10.52,79.1 ; HDMI1.2 9.88,78.54 ; HDMI1.2 9.24,79.1 ; BATT1.9 82.93,19.88 ; BATT1.9 82.04,18 ; BATT1.9 83.81,18 ; USB1.14 5.73,55.1 ; 12.58,44.19 USB2.7 12.58,45.71 ; 104.06,18 BATT1.10 102.29,18 ; 12.9,59.44 USB1.4 ; USB1.4 12.19,60.15 ; USB1.4 12.9,60.86 ; 9.28,76.79 HDMI1.20 9.28,74.91 ; 13.33,50.46 USB2.10 13.33,52.24 ; USB2.12 4.46,37.2 ; USB2.13 3.18,53.66
  L6 w0.508: 82.04,18 BATT1.9 ; BATT1.9 82.93,19.88 ; BATT1.9 83.81,18 ; BATT1.8 100.94,18 ; BATT1.8 100.05,17.11 ; BATT1.8 99.16,18 ; BATT1.8 100.05,18.89 ; v2(15.02,24.99) 16.03,23.98 20.1,23.98 v2(21.24,25.11) ; USB2.4 14.08,42.21 ; USB2.4 14.08,40.69 ; USB2.4 14.84,41.45 ; HS1.1 59.91,60 ; HS1.1 57.9,57.99 ; HS1.1 57.9,62.01 ; HS1.1 55.89,60 ; BATT1.7 98.94,18 ; BATT1.7 98.05,17.11 ; BATT1.7 97.16,18 ; BATT1.7 98.05,18.89 ; 12.19,60.15 USB1.4 ; USB1.4 12.9,60.86 ; USB1.4 12.9,59.44 ; 13.33,50.46 USB2.10 13.33,52.24 ; 12.58,45.71 USB2.7 12.58,44.19 ; 12,55.66 USB1.12 12,57.44 ; HDMI1.8 10.79,82.1 ; USB2.11 13.33,39.44 ; USB2.11 15.07,38.55 ; USB2.11 13.33,37.66 ; HDMI1.2 10.2,79.1 10.57,79.47 ; 104.06,18 BATT1.10 102.29,18 ; HDMI1.20 9.28,76.79 ; HDMI1.20 10.99,75.85 ; HDMI1.20 9.28,74.91 ; 12,70.24 USB1.11 12,68.46
  BOTTOM w0.089: CPU1.B62 70.3,49.01 69.78,49.01 69.67,48.96 68.48,48.96 v2(68.15,48.63) ; v2(84.11,41.9) 84.5,42.3 84.5,43.29 84.47,43.43 84.47,43.59 84.52,43.78 84.52,43.95 CPU1.AK69 ; 68.36,51.58 68.61,51.33 68.93,51.33 69.7,51.02 69.82,50.97 70.02,50.97 70.15,51.03 70.36,51.03 CPU1.B58
  BOTTOM w0.102: CPU1.B66 70.34,46.27 69.93,45.87 69.43,45.87 69.38,45.81 68.71,45.81 v2(68.21,45.31) ; CPU1.G5 73.26,81.51 72.79,81.51 CPU1.F4
  BOTTOM w0.114: 66.74,62.09 69.74,62.09 69.9,61.93 69.9,61.72 70.48,61.14 CPU1.B39
  BOTTOM w0.127: v2(82.12,39.46) 82.86,40.2 82.86,42.35 83.4,42.89 CPU1.AG71 ; CPU1.AW64 89.94,47.9 89.91,47.93 89.91,48.31 89.94,48.35 CPU1.AW62 ; CPU1.D18 71.94,73.17 v2(71.94,72.48) ; CPU1.AT68 89.15,45.46 89.16,45.47 CPU1.AV68 ; CPU1.AT68 88.38,45.49 87.26,45.49 CPU1.AP68 ; CPU1.AT68 88.41,45.35 88.77,44.99 88.77,44.98 88.93,44.81 89.47,44.81 CPU1.AV69 ; v2(88.89,41.96) 88.89,42.18 88.41,42.66 CPU1.AT71 ; CPU1.AW32 89.82,66.1 89.82,66.77 89.94,66.88 CPU1.AW30 ; CPU1.AK63 84.74,48.53 84.1,48.53 CPU1.AH63 ; CPU1.AM71 86.07,43.5 86.07,42.11 v2(85.87,41.91) ; v2(92.49,59.91) 92.3,59.73 CPU1.BB43 ; CPU1.K67 74.08,45.77 73.69,46.15 CPU1.G66 ; v2(93.12,49.75) 92.7,49.75 92.49,49.96 CPU1.BB60 ; CPU1.AP70 87.46,44.01 87.46,42.16 v2(87.58,42.04) ; CPU1.BB64 v2(93.02,47.61) ; v2(95.62,52.6) 95.43,52.42 94.17,52.42 94.02,52.56 CPU1.BB55
  BOTTOM w0.152: v2(49.31,50.64) 49.31,50.52 49.02,50.23 PU4803.5 ; CPU1.AW26 89.94,70.07 89.83,70.18 89.83,70.42 89.94,70.52 CPU1.AW23 ; CPU1.L4 75.47,81.48 76.11,81.48 CPU1.N6 ; v2(73.29,53.33) 73.44,53.34 73.69,53.34 73.93,53.58 73.93,53.86 73.75,54.04 73.75,54.5 CPU1.G52 73.55,54.69 73.55,54.87 v2(73.29,55.14) ; CPU1.D26 71.58,68.48 71.97,68.09 71.97,67.69 71.85,67.57 71.85,67.19 71.92,67.12 71.92,66.44 CPU1.D30
  BOTTOM w0.178: CPU1.G45 73.61,58.47 73.72,58.59 73.72,59.09 CPU1.G43 ; CPU1.AW66 89.88,46.49 89.88,47.1 89.94,47.16 CPU1.AW64 ; CPU1.AM60 85.7,49.92 85.7,49.29 CPU1.AM61
  BOTTOM w0.203: CPU1.AR45 87.8,58.39 v2(87.45,58.73) 87.44,58.74 87.44,58.74 87.42,58.76 87.8,59.14 CPU1.AR43 ; CPU1.AW43 89.9,59.79 ; 89.9,59.79 89.9,60.99 CPU1.AW41 ; 89.9,59.79 89.9,59.02 89.94,58.98 CPU1.AW45 v2(90.53,58.55) ; CPU1.AR52 87.42,54.26 v2(87.42,54.19) ; IOBD1.6 142.95,47.25 v2(142.79,47.41) ; CPU1.L17 CPU1.L18 CPU1.K18 ; 49.66,95.32 49.66,95.27 49.55,95.16 LCD1.29 ; CPU1.BA28 92.35,68.49 v2(92.74,68.88) ; CPU1.AW12 88.8,77.07 v2(88.77,77.04) ; CPU1.BB26 92.62,69.67 v2(93.4,68.88) ; U5701.35 15.58,82.08 v2(15.91,81.76) ; v2(90.64,63.63) 90.52,63.51 CPU1.AW36 ; CPU1.AP42 87.32,60.12 87.33,60.13 87.7,60.13 87.71,60.12 CPU1.AR42 CPU1.AT42 ; CPU1.B10 70.47,78.49 70.11,78.13 69.41,78.13 69.07,77.79 v2(68.36,77.79) ; 88.04,56.86 88.04,57.13 CPU1.AR46 ; 88.04,56.86 89.07,56.86 89.53,57.33 89.93,57.33 ; 88.04,56.86 88.04,56.71 CPU1.AR48 87.76,56.47 87.43,56.13 v2(87.43,56.02) 87.43,55.89 87.77,55.55 ; CPU1.AW18 CPU1.BA18 91.19,73.41 91.23,73.38 91.81,73.38 91.84,73.41 CPU1.BB18 ; CPU1.K70 CPU1.K71 75.23,43.44 75.23,42.41 v2(75.41,42.23) ; CPU1.G6 73.24,79.87 73.24,79.61 CPU1.F8 72.96,79.19 v2(73.28,78.87) ; CPU1.K16 75.02,74.94 74.26,74.18 CPU1.H18 ; v2(92.41,67.46) 92.27,67.31 CPU1.BB30 ; 89.93,57.33 89.9,57.3 89.9,56.56 89.94,56.53 CPU1.AW49 ; 89.93,57.33 CPU1.AW47 ; CPU1.E46 72.02,57.67 v2(72.02,57.8) 71.83,57.99 CPU1.D45 ; PU4803.31 45.9,47.28 45.64,47.54 v2(45.46,47.54) ; 89.92,62.21 89.92,61.66 89.72,61.46 v2(89.68,61.46) 89.68,61.28 89.93,61.03 CPU1.AW41 ; CPU1.AH13 83.97,75.96 CPU1.AJ15 ; CPU1.AW49 90.29,56.14 90.41,56.02 v2(90.43,56.02) 90.43,55.68 CPU1.AW50 90.2,55.52 89.94,55.78 CPU1.AW49 ; CPU1.AP18 87.15,73.71 v2(86.82,73.38) ; CPU1.AM45 CPU1.AM46 ; v2(142.79,45.91) 142.95,45.75 IOBD1.3 ; U5701.15 15.98,76.93 v2(15.86,76.8) ; CPU1.AD20 81.71,72.42 81.71,71.81 CPU1.AD21 ; v2(87.66,84.34) 88.02,83.99 88.02,83.16 88.34,82.84 CPU1.AT2 ; CPU1.G10 73.61,78.37 73.19,77.95 v2(72.63,77.95) ; CPU1.AW41 v2(90.49,61.03) CPU1.BA41 ; v2(82.86,70.83) 83.04,71.01 83.04,71.42 CPU1.AG21 83.45,71.83 83.45,72.4 CPU1.AG20 ; v2(44.61,63.09) 44.45,62.92 PU4701.5 ; CPU1.B14 70.4,76.01 70.05,75.65 69.27,75.65 v2(68.89,75.26) ; v2(92.8,63.59) 92.8,62.89 92.24,62.33 CPU1.BB38 ; PU4701.3 43.65,62.94 v2(43.59,62.99) ; v2(92.87,64.52) 92.71,64.68 CPU1.BB34 ; PU4701.31 41.36,59.6 41.29,59.68 41.21,59.76 40.69,60.28 v2(40.69,60.31) ; CPU1.AH64 83.84,47.74 v2(83.47,48.1) 83.6,48.1 83.88,48.39 CPU1.AH63 ; DIMM1.133 123.07,76.35 v2(123.48,76.75) ; CPU1.AP58 CPU1.AR58 88.37,50.98 ; U5701.8 v2(19.18,79.23) ; CPU1.AW53 90.47,53.74 v2(90.63,53.9) ; CPU1.L8 75.1,79.33 CPU1.J8 ; v2(87.47,77.95) 87.8,77.63 CPU1.AR11 ; CPU1.AP63 CPU1.AN63
  BOTTOM w0.229: CPU1.AB18 81.31,74.15 81.31,74.62 CPU1.AD16
  BOTTOM w0.254: CPU1.AL32 v2(86.82,66.07) 86.5,66.39 CPU1.AN30 86.5,66.66 v2(86.82,66.98) ; CPU1.D39 71.28,61.44 70.86,61.44 CPU1.B39 ; 71.54,78.49 CPU1.D10 ; 71.54,78.49 CPU1.D11 71.99,77.81 CPU1.E11 72.63,77.82 v2(72.63,77.95) ; 71.54,78.49 CPU1.B10 ; CPU1.BB6 CPU1.BA6 91.07,80.59 90.69,80.59 v2(90.62,80.65) 90.6,80.63 CPU1.AW6 ; CPU1.N6 76.79,81.09 v2(77.07,80.8) ; CPU1.AT2 CPU1.AT4 88.34,81.7 CPU1.AR5 ; CPU1.D34 71.14,63.62 v2(71.07,63.69) 71,63.62 CPU1.B34 ; 87.47,63.43 87.47,63.46 CPU1.AR35 88.12,63.46 v2(88.12,63.34) 88.45,63.67 CPU1.AT35 88.9,64.23 89.4,64.23 89.69,63.93 89.69,63.75 CPU1.AW36 ; 87.47,63.43 v2(87.47,63.32) ; 87.47,63.43 87.15,63.76 CPU1.AP35 86.82,63.46 v2(86.82,63.32) ; CPU1.N10 76.85,78.83 v2(76.99,78.83) ; CPU1.U67 78.8,45.46 v2(78.93,45.46) ; CPU1.E15 72.31,75.61 71.98,75.28 71.98,75.05 71.86,74.94 71.86,74.57 71.98,74.45 71.98,74.17 CPU1.E18 ; v2(90.63,53.9) 90.79,53.74 CPU1.BA53 ; v2(74.09,42.57) 74.09,42.57 74.07,42.57 73.8,42.84 CPU1.H71 ; CPU1.AW26 89.27,69.76 89.27,69.76 88.87,69.76 CPU1.AT23 88.45,70.05 v2(88.12,69.72) ; CPU1.D62 CPU1.B62 ; CPU1.BA32 90.6,65.98 v2(90.57,65.95) 90.53,65.98 CPU1.AW32 89.47,65.98 CPU1.AU32 89.56,65.14 v2(89.57,65.14) 89.57,65.14 89.92,64.78 CPU1.AW34 ; v2(86.82,66.98) 87.15,67.31 CPU1.AP28 87.21,67.38 87.74,67.38 CPU1.AR28 CPU1.AT28 ; v2(86.82,66.98) 86.5,67.31 CPU1.AN28 86.5,67.7 CPU1.AM27 ; v2(84.58,51.44) 84.58,51.44 CPU1.AL58 86.04,51.44 CPU1.AN58 86.58,51.06 87.07,51.06 CPU1.AP58 ; CPU1.AW16 89.77,74.64 v2(89.42,74.3) 89.42,74.19 89.94,73.67 CPU1.AW18 89.58,73.41 CPU1.AU20 ; CPU1.AL38 v2(86.17,62.41) ; v2(86.17,62.41) 86.5,62.08 CPU1.AN38 ; v2(86.17,62.41) 86.17,62.54 CPU1.AN37 86.82,63.19 v2(86.82,63.32) ; CPU1.AP63 87.22,48.3 87.73,48.3 CPU1.AR63 ; CPU1.AW14 90.56,75.83 90.58,75.86 v2(90.6,75.86) 90.62,75.83 CPU1.BA14 ; PR4656.1 v2(47.09,50.64) ; v2(80.25,78.79) 80.04,78.79 CPU1.W9 ; v2(87.47,78.87) 87.48,78.87 87.48,79 CPU1.AR8 ; CPU1.AK8 86.17,79.78 v2(86.17,79.78) 86.17,79.65 CPU1.AM8 ; CPU1.AK8 84.44,79.32 v2(84.44,78.16) 84.58,78.16 CPU1.AK11 ; CPU1.AK8 84.49,80.2 84.49,80.56 CPU1.AH6 83.97,81.34 v2(84.26,81.63) 84.8,81.63 CPU1.AJ4 CPU1.AL4 ; CPU1.AF17 CPU1.AG17 ; CPU1.AG17 83.36,74.44 83.36,74.99 CPU1.AG16 83.22,75.04 CPU1.AF15 ; CPU1.AG17 CPU1.AG18 83.47,73.67 83.47,73.15 CPU1.AG19 CPU1.AG20 ; CPU1.AJ15 84.45,75.48 84.64,75.48 CPU1.AK16 84.66,74.62 84.66,74.06 v2(84.66,74.06) 84.57,74.06 CPU1.AJ18 ; v2(69.37,67.28) 69.37,67.13 69.2,66.95 69.2,66.63 69.4,66.43 69.77,66.43 69.78,66.44 70.04,66.44 70.05,66.43 70.23,66.43 CPU1.B30 CPU1.D30 72.6,66.1 v2(72.63,66.07) 72.63,65.94 CPU1.F32 73.18,65.38 73.18,64.92 CPU1.F33 ; CPU1.F27 72.51,68.8 72.04,68.8 71.82,68.58 CPU1.D26 71.54,68.62 CPU1.D25 CPU1.C25 ; CPU1.F27 72.96,68.48 v2(73.28,68.81) 73.29,68.81 CPU1.J25 ; CPU1.F27 72.78,68.17 72.78,67.62 CPU1.F28 72.96,67.3 v2(73.28,66.98) CPU1.J28 ; CPU1.AK18 84.66,73.32 84.66,72.86 CPU1.AJ20 ; CPU1.AL52 84.62,55.09 v2(84.62,55.09) ; v2(84.66,70.63) 84.91,70.87 84.91,71.1 CPU1.AK22 85.08,71.27 CPU1.AK21 85.62,71.79 CPU1.AM21 ; CPU1.AR23 87.8,70.15 87.47,69.82 v2(87.47,69.72) 87.15,70.05 CPU1.AP23 CPU1.AN23 ; CPU1.W13 79.41,76.53 v2(79.18,76.3) 79.18,76.25 79.63,75.79 79.63,75.46 CPU1.V16 ; CPU1.AW57 90.43,51.26 90.57,51.12 v2(90.61,51.12) 90.61,51.14 90.73,51.26 CPU1.BA57 ; v2(87.52,53.27) 86.31,53.27 CPU1.AM55 85.83,52.81 CPU1.AL55 84.59,53.26 v2(84.58,53.25) ; v2(87.52,53.27) 87.52,53.08 CPU1.AR55 88.11,52.49 v2(88.11,52.39) 88.11,52.23 CPU1.AT56 ; v2(87.52,53.27) 87.52,53.45 CPU1.AR53 87.42,54.09 v2(87.42,54.19) ; CPU1.AD19 CPU1.AD20 ; v2(75.69,65.83) 75.69,65.72 75.12,65.15 CPU1.J32 ; v2(77.1,45.46) 76.97,45.46 CPU1.N68 ; CPU1.AR16 87.48,74.43 87.48,74.3 v2(87.47,74.3) ; CPU1.D48 71.58,56.82 CPU1.D47 71.44,56.86 70.76,56.19 CPU1.B48 70.23,55.85 70.05,55.85 70.04,55.84 69.78,55.84 69.77,55.85 69.4,55.85 69.39,55.85 68.74,55.85 68.25,56.34 v2(68.25,56.35) ; v2(83.47,48.1) 83.19,48.39 CPU1.AF63 ; v2(90.49,78.17) 90.02,78.17 CPU1.AW10 89.78,78.41 CPU1.AU10 ; CPU1.AB21 80.84,71.79 80.67,71.62 80.22,71.62 CPU1.Y21 79.98,71.86 79.98,72.36 CPU1.Y20 79.97,72.52 79.97,73 CPU1.Y19 79.89,73.25 79.71,73.25 CPU1.V18 ; CPU1.AU20 89.07,72.9 88.47,72.9 CPU1.AT20 88.38,72.92 88.3,72.84 87.88,72.84 CPU1.AR20 ; CPU1.AU20 89.8,72.22 CPU1.AW21 ; CPU1.Y17 80.24,74.39 CPU1.AB16 ; CPU1.U66 78.63,46.28 78.77,46.28 v2(78.93,46.11) ; CPU1.AP42 87.15,60.03 v2(86.83,59.71) ; CPU1.AR15 88.12,75.34 v2(88.12,75.21) ; CPU1.E50 72.31,55.54 v2(71.94,55.17) 71.94,55.17 71.94,54.07 CPU1.D53 71.3,53.98 70.83,53.98 CPU1.B53 ; CPU1.AU15 88.78,75.35 88.78,75.21 v2(88.77,75.21) ; v2(79.16,78.2) 78.92,78.2 CPU1.U10 ; CPU1.T2 CPU1.T4 77.57,81.69 CPU1.R6 77.89,81.09 v2(78.12,80.86) ; CPU1.G48 73.31,56.76 v2(73.31,56.91) ; CPU1.B18 CPU1.D18 72,73.53 CPU1.E18 ; CPU1.F68 CPU1.D69 71.93,44.46 71.96,44.42 v2(71.96,44.36) ; CPU1.L2 CPU1.L4 ; v2(86.82,63.32) 86.8,63.35 86.8,63.48 CPU1.AN35 ; CPU1.AD21 81.73,70.95 v2(81.57,70.78) ; CPU1.BA66 CPU1.AY66 90.46,46.41 CPU1.AW66 89.95,46.26 89.95,45.81 CPU1.AV68 ; v2(85.6,45.89) 84.84,45.14 CPU1.AK68 84.61,45.14 CPU1.AH67 83.83,45.79 v2(83.5,46.11) ; v2(90.64,63.63) 90.78,63.63 90.9,63.51 CPU1.BA36 ; CPU1.P21 77.68,71.93 77.68,72.27 77.54,72.41 CPU1.P20 77.48,72.5 77.48,73.03 CPU1.P19 ; v2(78.93,44.81) 78.8,44.81 CPU1.U69 ; v2(85.48,77.03) 85.48,76.95 CPU1.AM13 ; CPU1.AW50 90.26,55.28 CPU1.AW51 ; CPU1.AW38 89.92,62.21 89.36,62.21 CPU1.AU38 89.58,61.46 v2(89.68,61.46) ; v2(77.1,47.41) 76.97,47.41 CPU1.N65 ; CPU1.AF10 83.26,78.85 v2(83.41,78.85) ; CPU1.AF4 CPU1.AF2 CPU1.AF1 83.04,83.9 83.24,84.1 v2(83.24,84.1) ; v2(73.3,59.66) 73.3,59.48 73.58,59.21 CPU1.G43 74.07,59.67 CPU1.J42 ; CPU1.N13 76.8,76.84 v2(77.05,76.84) 77.35,76.53 CPU1.R13 ; CPU1.D45 71.58,58.03 CPU1.D44 CPU1.B44 ; CPU1.BA45 v2(90.53,58.55) ; 68.36,51.58 v2(67.72,51.58) ; v2(73.31,63.32) CPU1.J35 ; CPU1.AF15 82.43,75.83 82.18,75.83 81.83,76.18 CPU1.AD13 82.25,76.95 v2(82.38,76.95) ; CPU1.AF15 82.29,75.41 82.1,75.41 CPU1.AD16 ; v2(83.42,76.89) 83.61,76.89 CPU1.AH13 ; CPU1.AD8 82.15,79.78 v2(82.36,79.57) ; CPU1.L17 CPU1.L16 CPU1.K16 74.81,75.25 74.68,75.25 CPU1.H15 74.26,75.93 CPU1.J13 ; v2(84.49,56.86) 84.6,56.92 CPU1.AL48 85.37,57.1 85.65,57.38 CPU1.AM46 ; CPU1.U64 78.8,48.06 v2(78.93,48.06) ; CPU1.F8 72.64,79.65 72.64,79.91 CPU1.E6 72.31,80.34 72.04,80.61 71.91,80.61 CPU1.D6 71.86,81.23 71.86,81.32 72.4,81.86 CPU1.F4 CPU1.F2 CPU1.F1 72.43,83.9 71.91,84.42 v2(70.55,84.42) ; CPU1.L8 75.62,79.78 75.94,79.47 v2(76.04,79.47) ; CPU1.B14 CPU1.D14 ; CPU1.L20 76.51,73.09 CPU1.N19 76.26,73.52 76.08,73.52 CPU1.L18 ; CPU1.AP38 87.15,61.82 v2(86.82,61.49) 86.82,61.36 CPU1.AN40 ; CPU1.F23 72.96,70.31 v2(73.28,70.64) ; v2(74.84,61.49) CPU1.J38 ; v2(78.93,44.16) 78.9,44.16 78.57,43.84 CPU1.U70 ; CPU1.E18 72.77,74.3 73.8,74.3 CPU1.H18 ; v2(90.61,48.91) 90.74,48.78 CPU1.BA62 ; CPU1.AW8 89.65,79.2 89.65,79.01 v2(89.65,79) ; CPU1.AM27 86.17,68.68 v2(86.17,68.81) ; CPU1.AM27 85.83,68.35 CPU1.AL28 85.37,67.9 CPU1.AK27 ; CPU1.D58 71.65,51.23 CPU1.E56 72.31,52 v2(71.96,52.34) ; CPU1.G55 73.31,53.11 v2(73.29,53.33) ; CPU1.G22 73.65,71.05 74.49,71.05 CPU1.K22 ; v2(86.82,78.87) 86.82,78.74 CPU1.AP10 ; CPU1.G58 73.61,50.85 v2(73.28,50.52) 73.28,50.39 CPU1.G60 ; CPU1.AA68 80.63,45.46 v2(80.76,45.46) ; CPU1.G63 73.95,48.59 v2(73.95,48.69) 74.41,49.15 CPU1.K61 74.85,48.84 CPU1.K63 CPU1.K64 CPU1.K65 CPU1.K66 CPU1.K67 75.05,45.56 CPU1.K68 75.16,45.05 CPU1.K70 ; CPU1.AW55 89.82,52.35 88.9,52.35 CPU1.AT56 ; 88.37,50.98 CPU1.AT58 CPU1.AT56 ; v2(90.43,56.02) 91.11,56.02 CPU1.BA49 ; CPU1.AM45 85.39,58.75 CPU1.AL45 85.83,59.21 CPU1.AM43 ; CPU1.AA2 CPU1.AA4 ; CPU1.B22 CPU1.D22 ; CPU1.AV70 CPU1.AV69 ; CPU1.B66 CPU1.D66 72.09,46.79 72.09,47.01 CPU1.E65
  BOTTOM w0.305: v2(86.84,65.13) 86.84,65.23 86.5,65.57 CPU1.AN32 ; v2(86.84,65.13) 87.15,65.44 CPU1.AP32 87.15,65.74 v2(86.82,66.07) ; v2(86.84,65.13) 86.81,65.01 CPU1.AN33 86.04,64.24 CPU1.AL35 ; 86.82,73.3 86.5,72.97 CPU1.AN20 ; 86.82,73.3 87.15,72.97 CPU1.AP20 ; 86.82,73.3 v2(86.82,73.38) ; v2(80.25,76.86) 80.02,76.86 CPU1.W13 ; v2(87.47,74.3) 87.47,74.17 CPU1.AP18 ; 72.96,64.23 CPU1.F33 ; 72.96,64.23 CPU1.F35 73.31,63.43 v2(73.31,63.32) 73.31,63.22 CPU1.F37 72.8,62.71 72.8,62.11 CPU1.F38 72.7,61.69 v2(72.7,61.49) ; 72.96,64.23 72.19,64.23 CPU1.D34 ; LCD1.28 50.05,95.32 v2(50.2,95.47) ; v2(44.29,69.38) 44.29,69.05 44.23,68.99 PU5002.6 ; CPU1.D14 71.97,76.01 CPU1.E15 72.96,76.32 CPU1.F13 ; IOBD1.18 142.95,53.25 v2(142.8,53.1) ; v2(123.35,27.4) U6001.3 U6001.8 121.1,27.4 v2(120.82,27.68) ; CPU1.E53 72.28,53.72 71.94,54.07 ; CPU1.AW23 90.46,70.97 v2(90.58,71.09) 90.71,70.97 CPU1.BA23 ; CPU1.AW28 89.94,68.28 v2(89.57,67.91) 89.94,67.54 CPU1.AW30 ; CPU1.AW28 89.71,68.72 v2(89.71,69.04) 89.71,69.31 89.94,69.54 CPU1.AW26 ; CPU1.AW28 90.52,68.49 v2(90.63,68.42) 90.65,68.49 CPU1.BA28 ; v2(57.06,92.74) 57.06,92.93 57.05,92.94 LCD1.14 57.05,95.35 v2(56.93,95.47) ; CPU1.G6 74.05,79.8 74.44,79.8 CPU1.J8 ; PC5113.2 132.82,41.19 v2(132.67,41.34) ; v2(83.42,76.89) 83.42,77.96 CPU1.AF10 ; CPU1.C25 70.89,68.89 v2(71.05,68.73) 71.2,68.58 CPU1.D26 ; 83.73,49.5 83.96,49.26 CPU1.AH63 ; HDD1.24 126.13,27.33 HDD1.20 ; 74.91,77.06 74.45,77.06 74.43,77.04 v2(73.93,77.04) 73.48,77.04 73.02,76.58 CPU1.F13 ; 74.91,77.06 CPU1.J13 ; 74.91,77.06 CPU1.J11 75.25,77.83 CPU1.L11 ; v2(73.93,75.21) 74.26,75.54 CPU1.H15 ; CPU1.C5 70.95,81.55 71.35,81.15 71.37,81.15 CPU1.D6 ; LCD1.34 47.05,93.35 47.32,93.08 47.65,93.08 v2(47.78,92.94) 48.05,93.21 LCD1.32 ; v2(55.66,95.47) 55.55,95.36 LCD1.17 ; CPU1.F13 72.64,76.91 v2(72.64,77.04) 72.64,77.17 CPU1.E11 ; CPU1.U63 78.61,48.39 v2(78.93,48.06) ; v2(142.8,54.6) 142.95,54.75 IOBD1.21 ; v2(59.98,92.99) 60.05,93.06 LCD1.8 ; CPU1.AW62 90.48,48.78 v2(90.61,48.91) ; CPU1.AW62 89.94,49.09 89.82,49.21 89.82,49.94 CPU1.AW60 ; CPU1.AW62 89.41,48.78 89.31,48.69 88.9,48.69 CPU1.AT63 88.12,47.91 ; v2(130.08,28.29) 130.05,28.26 HDD1.14 ; v2(84.66,74.06) 84.76,74.06 CPU1.AK18 ; CPU1.P21 77.54,71.71 77.27,71.44 v2(77.15,71.44) 77.04,71.44 CPU1.N21 ; U3401.14 25.94,54.57 v2(25.94,54.58) ; TP1.4 112.3,22.95 112.33,22.92 112.33,22.8 v2(112.43,22.7) ; v2(72.7,61.49) 72.15,61.49 71.8,61.14 CPU1.D39 ; v2(72.7,61.49) 72.7,61.29 CPU1.F40 ; v2(80.76,46.76) 80.61,46.76 80.3,47.07 CPU1.AA65 ; 83.05,49.33 CPU1.AF63 ; CPU1.E6 71.94,79.88 v2(71.94,79.77) ; IOBD1.32 143.12,60.25 142.3,59.43 v3(141.89,59.43) ; v2(127.72,20.62) 127.72,20.41 127.79,20.34 DB3.4 ; v2(88.12,47.78) 88.12,47.91 ; 88.12,47.91 CPU1.AR63 ; CPU1.G10 73.61,78.47 73.28,78.8 v2(73.28,78.87) ; CPU1.AL64 85.53,47.74 CPU1.AK63 85.08,48.39 CPU1.AM61 86.5,48.5 CPU1.AN63 86,47.74 CPU1.AL64 ; CPU1.AL64 CPU1.AL65 CPU1.AL66 85.75,46.04 v2(85.6,45.89) 85.6,45.82 CPU1.AM68 ; CPU1.E21 72.31,71.79 CPU1.D22 ; CPU1.E21 72.22,72.01 71.94,72.29 v2(71.94,72.48) ; CPU1.E21 72.96,71.36 CPU1.F22 72.96,70.86 73.18,70.64 v2(73.28,70.64) 73.61,70.96 CPU1.G22 ; CPU1.T21 78.38,71.1 v2(78.37,71.09) ; CPU1.AN43 86.8,58.91 v2(86.8,58.74) ; v2(58.55,92.8) LCD1.11 ; v2(86.83,59.71) 86.83,59.79 CPU1.AN42 ; v2(88.77,67.9) 88.77,67.76 CPU1.AT28 ; U4004.3 36.42,90.07 v3(36.99,90.65) ; v2(73.3,59.66) 73.3,59.78 CPU1.F42 ; v2(28.35,100.93) 28.47,100.93 28.79,101.25 HOMBD1.13 ; HDD1.17 128.55,28.28 v2(128.56,28.29) ; CPU1.AM25 85.85,69.13 v2(86.17,68.81) ; CPU1.AM43 86.15,58.91 v2(86.15,58.73) 86.15,58.6 CPU1.AM45 ; PU5102.8 v2(134.78,80.91) ; LCD1.21 53.55,95.42 v2(53.5,95.47) ; CPU1.AR46 87.36,56.94 v2(86.14,56.94) 86.14,57.09 CPU1.AM46 ; CPU1.AR50 87.77,55.55 87.56,55.34 87.56,54.87 CPU1.AR52 ; v2(134.27,73.88) 134.28,73.89 PU5102.4 ; CPU1.AK68 CPU1.AK69 ; v2(142.8,56.1) 142.95,56.25 IOBD1.24 ; CPU1.AL2 CPU1.AL4
  BOTTOM w0.33: v2(124.43,93.15) 124.43,92.87 124.11,92.55 DIMM1.187 ; DIMM1.46 127.56,47.85 126.53,46.83 v2(126.53,46.65) ; DIMM1.11 124.24,37.35 125.07,38.17 v2(125.07,38.55) ; v2(125.07,45.75) 125.07,46.03 124.14,46.95 DIMM1.43 ; DIMM1.170 127.57,87.45 127.17,87.05 v2(127.17,86.85) ; DIMM1.162 128.27,85.05 127.8,84.59 v2(127.8,84.45) ; DIMM1.60 127.57,52.05 126.53,51.02 v2(126.53,50.85) ; DIMM1.179 124.1,90.15 125.07,89.18 v2(125.07,88.95) ; v2(123.8,45.75) 123.8,45.48 123.47,45.15 DIMM1.37 ; v2(125.07,51.75) 125.07,52.15 124.27,52.95 DIMM1.63 ; v2(127.8,46.65) 127.8,46.84 128.22,47.25 DIMM1.44 ; DIMM1.3 123.15,34.95 v2(123.22,35.02) ; v2(123.8,49.95) 123.8,50.19 123.44,50.55 DIMM1.55 ; DIMM1.167 122.94,86.55 v2(123.22,86.84) ; DIMM1.173 123.52,88.35 123.8,88.63 v2(123.8,88.95) ; v2(126.53,41.25) 126.53,41.54 127.44,42.45 DIMM1.28 ; DIMM1.48 128.12,48.45 128.12,48.45 127.8,48.77 v2(127.8,49.05) ; v2(127.17,37.65) 127.17,37.81 127.61,38.25 DIMM1.14 ; DIMM1.136 127.55,77.25 127.17,77.63 v2(127.17,77.85) ; v2(123.16,55.27) 123.08,55.35 DIMM1.71 ; v2(127.8,35.35) 127.8,35.21 128.37,34.65 DIMM1.2 ; v2(127.8,80.25) 127.8,80.02 128.18,79.65 DIMM1.144 ; DIMM1.128 128.61,74.85 128.61,74.86 128.51,74.86 128.5,74.86 127.4,74.86 126.53,75.73 v2(126.53,76.05) ; v2(123.16,84.75) DIMM1.161 ; v2(128.44,95.25) DIMM1.196 ; v2(126.5,37.58) 126.5,37.46 127.51,36.45 DIMM1.8 ; v2(123.8,38.55) 123.8,38.34 123.4,37.95 DIMM1.13 ; v2(127.8,76.05) 127.8,76.28 128.18,76.65 DIMM1.134 ; DIMM1.26 128.26,41.85 127.8,41.39 v2(127.8,41.25) ; v2(128.44,77.85) DIMM1.138 ; v2(127.8,43.05) 127.8,43.31 128.14,43.65 DIMM1.32 ; v2(127.8,50.85) 127.8,50.65 128.21,50.25 DIMM1.54 ; DIMM1.20 128.22,40.05 127.8,39.64 v2(127.8,39.45) ; DIMM1.178 128.11,89.85 127.8,90.15 v2(127.8,90.45) ; v2(123.16,93.15) DIMM1.189 ; DIMM1.185 123.54,91.95 123.8,91.7 v2(123.8,91.35) ; DIMM1.25 123.59,41.55 124.5,42.46 v2(124.5,42.49) ; DIMM1.155 v2(123.16,82.95) ; DIMM1.153 124.2,82.35 125.07,81.49 v2(125.07,81.15) ; v2(127.17,82.05) 127.17,81.9 127.61,81.45 DIMM1.150 ; DIMM1.66 127.79,53.85 127.17,53.23 v2(127.17,52.65) ; DIMM1.195 123.54,94.95 123.8,94.7 v2(123.8,94.35) ; v2(123.16,36.75) DIMM1.9 ; v2(123.8,75.15) 123.8,74.79 123.56,74.55 DIMM1.127 ; DIMM1.49 122.64,48.75 122.89,49.01 124.24,49.01 124.75,48.51 v2(124.75,48.18) ; DIMM1.184 128.97,91.65 128.86,91.54 127.66,91.54 127.13,92.07 v2(127.13,92.32) ; v2(123.8,40.33) 123.8,40.08 123.47,39.75 DIMM1.19 ; v2(126.53,44.25) 126.53,44.6 127.38,45.45 DIMM1.38 ; DIMM1.31 123.33,43.35 123.8,43.81 v2(123.8,43.95) ; DIMM1.156 127.09,83.25 126.53,83.8 v2(126.53,84.45) ; v2(128.44,93.45) DIMM1.190 ; DIMM1.172 128.06,88.05 127.8,88.31 v2(127.8,88.65) ; DIMM1.139 124.21,78.15 125.07,79 v2(125.07,79.35) ; DIMM1.61 123.42,52.35 123.8,51.97 v2(123.8,51.75) ; v2(123.8,54.15) 123.8,53.91 123.44,53.55 DIMM1.65 ; DIMM1.151 122.92,81.75 122.93,81.77 123.59,81.77 123.8,81.56 v2(123.8,81.15) ; DIMM1.72 128.27,55.65 127.89,55.28 127.89,55.14 v2(127.8,55.05) ; v2(128.44,86.85) DIMM1.168 ; v2(123.8,79.35) 123.8,79.61 123.45,79.95 DIMM1.145
  BOTTOM w0.356: v2(14.89,62.96) EU3601.3
  BOTTOM w0.381: R4203.2 137.67,67.21 138.58,68.13 R4207.2 ; Q1702.1 152.63,37.81 v2(152.73,37.92) 152.68,37.97 151.66,37.97 151.33,38.3 Q1702.4 ; v2(21.75,31.72) 21.64,31.61 U2901.1 ; C4026.2 21.69,35.4 v2(23.27,35.4) ; v2(40.67,42.83) PC4610.2
  BOTTOM w0.406: v2(17.69,44.93) EU3603.3 ; HOMBD1.17 31.8,94.71 32.54,95.45 v2(32.54,95.47)
  BOTTOM w0.508: HS3.1 86.08,32.8 ; HS3.1 89.85,35.99 ; HS3.1 93.04,32.8 ; 14.84,41.45 USB2.4 14.08,40.69 ; 54.71,60 HS1.1 ; HS1.1 57.9,63.19 ; HS1.1 57.9,56.81 ; HS1.1 61.09,60 ; PC4511.2 PC4512.2 33.73,68.98 32.93,68.18 v2(32.8,68.18) ; v2(145.2,32.25) 145.2,32.29 145.19,32.3 145.19,32.58 146.1,33.49 148.12,33.49 148.32,33.29 C2424.1 ; 9.28,91.29 HDMI1.21 10.99,90.35 ; USB1.14 5.86,55.1 ; C3513.2 17.51,47.26 v2(17.81,46.96) 18.26,47.4 R3501.2 ; 98.05,17.11 BATT1.7 ; BATT1.7 98.05,18.89 ; BATT1.7 97.16,18 ; BATT1.7 98.94,18 ; C2610.2 101.44,27.59 v2(101.51,27.65) ; v3(137.32,28.54) 137.6,28.26 HDD1.22 ; v2(107.37,109.06) 107.37,109.7 107.68,110 DB1.8 107.68,112.31 ; 9.28,74.91 HDMI1.20 ; HDMI1.20 9.28,76.79 ; HDMI1.20 10.99,75.85 ; D4303.1 87.92,28.01 v2(87.38,28.54) ; PC5304.2 PC5302.2 37.32,9.62 v2(37.75,9.62) 38.16,9.62 38.64,10.1 PC4435.2 ; EC8909.2 69.5,86.95 69.76,86.7 v2(69.76,86.07) ; Q6503.S 121.8,19.56 v2(121.57,19.33) ; v2(48.42,88.99) 47.47,88.99 46.77,89.69 PC5220.2 ; PC5219.2 39.15,86.07 v2(38.64,85.57) 38.56,85.49 PC5214.2 ; v2(23.27,35.4) 23.5,35.62 Q4007.S ; v2(130.08,16.1) 129.79,16.39 DB3.8 ; v2(30.77,66.9) 30.07,66.2 PR4502.2 29.94,66.13 29.75,66.13 29.12,65.5 PR4503.2 ; v2(43.94,90.34) 43.94,90.31 43.97,90.28 PR5209.1 PR5213.2 ; 13.54,56.55 USB1.12 12,55.66 ; PC5303.2 36.63,4.16 37.07,3.73 v2(37.52,3.73) ; IOBD1.53 v2(147.75,54.07) ; C4014.2 66.47,75.61 v2(66.47,75.91) ; USB2.11 13.33,39.44 ; USB2.11 13.33,37.66 ; USB2.11 15.07,38.55 ; v3(137.57,21.77) 137.57,22.8 137.6,22.83 HDD1.21 ; BATT1.10 103.18,19.88 ; BATT1.10 104.06,18 ; BATT1.10 102.29,18 ; v2(132.62,45.43) 132.75,45.56 PR5106.1 PC5138.2 ; v3(124.31,26.21) 124.79,26.21 125.78,27.2 HDD1.24 ; C5702.1 19.35,84.27 20.8,84.27 21.01,84.47 21.98,84.47 v2(22,84.45) ; v2(45.46,47.54) 44.51,47.54 PC4806.2 ; v2(19.97,72.23) 19.97,71.66 PC5309.2 ; v2(35.92,2.41) 35.92,2.53 35.31,3.14 PC5301.2 ; v2(21.69,76.5) 20.89,76.5 C5703.1 ; R2417.2 140.75,38.5 141.08,38.83 v2(141.08,39.85) ; PR4520.2 30.89,65.75 v2(31.4,66.26) ; USB1.11 12,70.24 ; USB1.11 12,68.46 ; USB1.11 13.54,69.35 ; C7002.2 12.16,73.18 12.6,72.74 PC5307.2 13.68,72.33 14.1,71.91 PC5308.2 14.98,71.91 15.3,71.6 PU5302.2 ; EC2506.2 134.53,101.24 v2(134.3,101.47) ; PC4436.2 v2(36.86,6.22) ; 82.04,18 BATT1.9 ; BATT1.9 83.81,18 ; BATT1.9 82.93,19.88 ; EC4305.2 90.31,28.67 91.47,27.51 D4302.1 91.78,27.37 92.86,28.45 EC4306.2 93.5,28.67 v2(93.63,28.54) 94.22,28.54 95.03,27.73 D4301.1 ; BATT1.8 100.94,18 ; BATT1.8 100.05,18.89 ; BATT1.8 99.16,18 ; BATT1.8 100.05,17.11 ; HS2.1 93.04,94.2 ; HS2.1 89.85,97.39 ; HS2.1 86.66,94.2 ; HS2.1 89.85,91.01 ; v2(45.19,8.6) 45.19,9.21 PC4438.2 45.54,9.68 PR4445.2 ; v2(147.83,69.99) 147.75,69.91 IOBD1.54 ; PC4437.2 37.75,6.57 37.88,6.44 v2(37.88,6.19) 37.93,6.14 38.04,6.14 38.26,5.92 38.26,5.68 38.45,5.49 PR4404.2 ; v2(139.99,85.82) 139.44,85.82 138.86,86.39 EC2504.2 ; PC4807.2 v2(50.45,55.09) ; v2(89.44,24.1) 88.69,23.35 EC4304.2 ; v2(156.78,44.01) 156.78,44.03 156.8,44.05 KB1.28 ; R4301.2 EC4307.1 ; v2(142.78,29.18) 142.78,30.64 C2403.2 ; v2(41.94,62.96) 41.5,63.4 PR4653.1 ; C2604.2 140.37,69.08 v2(140.37,68.09) 140.33,68.13 C2503.2 R4207.2 ; USB2.13 3.18,53.79 ; PC5120.2 132.21,82.71 132.21,81.72 132.43,81.5 PC5116.2 132.81,80.55 v2(133.13,80.23) ; C6501.2 24.23,12.99 23.53,12.29 v2(23.4,12.29) ; 13.33,52.24 USB2.10 15.07,51.35 ; v2(125,16.1) 125.29,16.39 DB3.7 ; HDD1.23 126.27,22.93 v2(126.27,22.07) ; SPI252.4 135.46,88.92 v2(134.55,88) ; USB2.12 4.46,37.2 ; PC4305.2 v2(32.93,21.43) ; C1718.2 61.61,88.82 v2(61.88,89.08) 62.92,90.13 C5514.2 ; Q2408.S 144.15,34.93 v2(144.32,34.76) ; v2(29.24,14.57) 29.24,14.13 PR5304.2 ; v2(46.13,65.88) 46.13,65.03 PC4707.2 45.76,64.66 PC4708.2 ; v2(63.48,42.56) 63.79,42.87 EC401.2 ; PC4522.2 29.29,69.03 v2(28.96,68.7) ; EC1701.2 R1714.2 R604.2 68.36,38.6 v2(68.21,38.45) ; C1804.1 92.39,102.9 92.7,102.58 94.98,102.58 ; PC1054.2 60.41,79.42 C4034.2 62,78.63 EC4001.2 ; IOBD1.52 147.78,45.57 v2(147.78,44.06) 147.78,43.58 146.55,42.35 IOBD1.51 145.41,42.35 144.94,41.88 v2(144.94,40.23) ; PC5111.2 136.7,82.19 EC8914.2 136.87,82.01 136.87,78.13 ; v2(135.92,101.44) 135.92,101.31 136.3,100.93 EC2505.2 ; EU3602.2 v2(17.18,58.77) ; PC4808.2 v2(47.91,54.32) ; PC4303.2 PC4304.2 v2(32.93,22.32) ; v2(44.08,67.33) 44.06,67.32 42.21,67.32 PC5001.2 ; v2(151.28,31.89) 151.27,31.9 151.27,32.16 151.35,32.24 C2425.1 ; PR4661.2 v2(29.81,56.42) ; PG4410.2 41.76,15.51 v2(41.94,15.33) ; USB1.13 3.8,72.15 ; C1803.1 91.73,99.94 v2(91.47,99.69) ; U4005.3 60.27,72.29 ; v2(25.69,33.5) 25.88,33.31 C4027.2 ; PC5226.2 40.57,90.54 41.03,91 C5503.2 41.66,90.77 v2(42.32,90.77) 42.58,91.03 EC5502.2 ; LCD1.45 41.65,97.38 40.41,98.61 v2(39.4,98.61) ; v2(132.62,43.66) PR5104.2 ; v2(17.94,73.88) R5418.1 ; EU3604.2 v2(18.57,40.61)
  BOTTOM w0.635: PC4411.2 42.5,18.71 v2(42.58,18.64)
  vias: v1(5.75,4.03) v1(8.67,93.67) v1(17.33,12.19) v1(23.91,44.54) v1(25.51,23.84) v1(35.52,61.26) v1(37.4,77.64) v1(44.46,101.21) v1(44.95,90.38) v1(45.54,53.45) v1(46.06,3.8) v1(47.39,89.14) v1(48.55,15.13) v1(50.45,40.66) v1(51.34,29.25) v1(54.71,87.8) v1(58.25,71.67) v1(61.4,103.3) v1(64.83,63.26) v1(73.57,110.53) v1(75.9,95.04) v1(76.11,31.72) v1(91.98,110) v1(96.43,104.62) v1(96.88,68.67) v1(100.36,76.88) v1(110.2,76.42) v1(116.14,78.63) v1(117.23,39.16) v1(120.25,91.3) v1(120.27,88.17) v1(126.19,79.77) v1(129.07,79.02) v2(1.05,94.96) v2(1.18,71.47) v2(1.43,20.8) v2(1.43,18.26) v2(1.56,15.46) v2(1.75,9.33) v2(1.81,6.63) v2(1.76,3.68) v2(2.32,92.93) v2(2.32,73.25) v2(2.83,1.11) v2(3.21,13.94) v2(3.31,8.64) v2(3.46,11.45) v2(3.59,94.96) v2(3.59,19.4) v2(3.72,20.8) v2(3.97,91.92) v2(4.73,93.31) v2(5.11,14.06) v2(5.14,9.79) v2(5.37,52.8) v2(5.37,37.05) v2(5.37,1.11) v2(5.47,12.29) v2(5.62,20.8) v2(6.13,94.96) v2(6.76,70.96) v2(6.76,54.96) v2(7.4,52.8) v2(7.53,93.31) v2(7.53,37.05) v2(7.91,1.11) v2(8.29,91.92) v2(8.67,94.96) v2(8.8,54.96) v2(9.3,37.05) v2(9.43,52.8) v2(9.81,93.44) v2(10.45,1.11) v2(10.83,92.17) v2(10.83,54.7) v2(11.08,76.9) v2(11.21,94.96) v2(11.18,78.83) v2(11.21,37.05) v2(11.46,71.6) v2(12.99,1.11) v2(13.75,94.96) v2(14.26,91.53) v2(14.38,4.79) v2(14.89,80.23) v2(14.89,61.05) v2(14.89,59.15) v2(14.89,17.87) v2(15.4,69.82) v2(15.4,69.06) v2(15.53,1.11) v2(15.65,37.81) v2(15.78,12.41) v2(15.91,80.99) v2(15.91,80.23) v2(15.91,79.47) v2(15.91,78.71) v2(15.91,42.89) v2(15.91,40.99) v2(16.29,94.96) v2(16.67,80.23) v2(16.8,17.75) v2(17.3,37.81) v2(18.07,1.11) v2(18.32,16.6) v2(18.32,9.24) v2(18.65,9.9) v2(19.08,37.81) v2(19.13,9.42) v2(19.34,97.25) v2(20.61,1.11) v2(20.94,49.88) v2(21.62,82.52) v2(21.62,80.61) v2(21.6,78.66) v2(21.88,26.51) v2(21.88,25.88) v2(21.88,25.11) v2(21.88,24.35) v2(21.88,23.72) v2(22,65.12) v2(22,63.09) v2(22,61.04) v2(22.26,82.52) v2(22.26,80.61) v2(22.26,78.71) v2(22.64,25.11) v2(22.77,51.28) v2(22.89,54.32) v2(22.89,47.08) v2(22.89,45.05) v2(23.15,1.11) v2(23.27,25.11) v2(23.53,54.96) v2(23.53,54.32) v2(23.53,53.69) v2(24.16,54.32) v2(25.56,9.24) v2(25.66,6.34) v2(25.69,1.11) v2(25.94,17.11) v2(25.97,46.04) v2(26.58,5.17) v2(26.7,29.94) v2(26.96,103.98) v2(27.21,12.03) v2(28.23,1.11) v2(28.38,102.91) v2(28.99,45.05) v2(29.75,44.04) v2(30.77,1.11) v2(31.4,67.53) v2(31.4,66.9) v2(32.04,66.9) v2(32.54,102.51) v2(32.54,101.44) v2(33.31,1.11) v2(33.69,27.78) v2(33.69,27.02) v2(34.58,103.98) v2(35.85,1.11) v2(37.12,103.98) v2(38.64,1.11) v2(39.66,103.98) v2(41.69,1.11) v2(41.82,6.44) v2(42.2,103.98) v2(42.7,2.63) v2(42.96,61.44) v2(42.96,59.4) v2(42.96,58.39) v2(42.96,57.24) v2(43.72,2.63) v2(43.85,61.44) v2(43.85,59.4) v2(43.85,58.39) v2(43.85,57.24) v2(44.48,1.11) v2(44.74,103.98) v2(44.74,61.44) v2(44.74,59.4) v2(44.74,58.39) v2(44.74,57.24) v2(47.02,1.11) v2(47.28,103.98) v2(47.28,19.27) v2(47.4,2.63) v2(47.53,48.86) v2(47.53,46.83) v2(47.53,45.81) v2(47.53,44.67) v2(47.78,14.45) v2(48.17,11.52) v2(48.17,8.6) v2(48.17,5.81) v2(48.17,4.79) v2(48.17,2.63) v2(48.42,48.86) v2(48.42,46.83) v2(48.42,45.81) v2(48.42,44.67) v2(49.18,14.32) v2(49.31,48.86) v2(49.31,46.83) v2(49.31,45.81) v2(49.31,44.67) v2(49.82,103.98) v2(51.09,55.09) v2(51.34,15.08) v2(53.12,100.81) v2(53.37,103.98) v2(53.75,100.81) v2(54.52,15.08) v2(54.9,103.98) v2(55.91,15.08) v2(56.41,89.59) v2(57.06,101.31) v2(57.06,15.08) v2(57.44,103.98) v2(59.09,101.31) v2(59.6,15.08) v2(59.98,103.98) v2(59.98,89.12) v2(60.08,66.83) v2(60.08,66.19) v2(60.36,92.42) v2(62.01,57.09) v2(62.14,58.18) v2(62.14,15.08) v2(62.52,103.98) v2(63.41,60.29) v2(63.41,59.2) v2(63.94,57.02) v2(64.04,58.08) v2(64.68,15.08) v2(65.16,56.79) v2(65.64,37.43) v2(65.69,62.58) v2(66.66,77.39) v2(67.01,95.75) v2(67.22,15.08) v2(67.6,113.89) v2(67.6,111.6) v2(67.6,109.57) v2(67.72,77.79) v2(67.77,75.28) v2(68.14,71.96) v2(68.24,112.69) v2(68.74,114.9) v2(69.91,72.43) v2(70.01,15.08) v2(70.21,39.39) v2(70.64,109.44) v2(70.67,110.51) v2(70.9,114.9) v2(72.17,94.33) v2(72.44,41.75) v2(72.93,94.33) v2(73.69,114.9) v2(77.88,114.9) v2(78.8,74.06) v2(79.66,15.08) v2(80.25,79.45) v2(80.42,114.9) v2(81.31,85.31) v2(81.31,84.68) v2(82.71,105.51) v2(82.71,103.6) v2(82.96,114.9) v2(83.27,86.04) v2(83.9,99.71) v2(85.12,99.7) v2(85.12,86.28) v2(85.5,114.9) v2(86.42,99.7) v2(86.77,28.92) v2(87.15,105.5) v2(87.92,105.5) v2(88.04,114.9) v2(88.68,105.5) v2(89.44,107.79) v2(89.44,107.03) v2(89.44,106.27) v2(89.44,105.5) v2(89.44,104.74) v2(89.44,103.98) v2(90.2,105.5) v2(90.58,114.9) v2(90.96,105.5) v2(91.73,105.5) v2(92.23,42.51) v2(93.12,114.9) v2(93.76,65.37) v2(95.43,42.49) v2(95.66,44.95) v2(95.87,48.53) v2(96.68,105.12) v2(96.68,103.47) v2(97.79,55.42) v2(97.77,52.65) v2(98.13,50.87) v2(98.2,114.9) v2(98.71,42.49) v2(98.87,27.82) v2(99.35,80.23) v2(99.47,44.99) v2(100.24,21.56) v2(100.36,106.52) v2(100.74,114.9) v2(100.79,42.49) v2(100.87,21.56) v2(102.14,21.56) v2(102.78,21.56) v2(103.28,114.9) v2(104.05,21.56) v2(104.81,21.56) v2(105.7,109.06) v2(105.82,114.9) v2(106.46,16.1) v2(107.47,85.18) v2(107.86,113.12) v2(108.62,114.9) v2(108.85,109.09) v2(109.38,16.1) v2(109.51,22.7) v2(109.76,85.95) v2(109.76,25.37) v2(110.4,87.22) v2(111.28,114.9) v2(112.43,16.1) v2(112.46,50.05) v2(114.21,112.24) v2(114.69,50) v2(114.84,16.1) v2(114.97,110.46) v2(114.97,30.7) v2(117.38,16.1) v2(117.51,109.44) v2(119.92,16.1) v2(122.08,109.44) v2(122.46,16.1) v2(123.39,56.56) v2(123.8,72.51) v2(123.76,61.87) v2(124.29,29.89) v2(124.43,84.75) v2(124.43,82.95) v2(124.43,66.15) v2(124.43,36.75) v2(124.47,67.25) v2(124.62,73.63) v2(124.7,56.56) v2(125.07,91.35) v2(125.13,86.96) v2(125.07,75.15) v2(125.07,72.51) v2(125.07,64.95) v2(125.07,61.95) v2(125.08,60.52) v2(125.07,49.95) v2(125.07,43.95) v2(125.07,40.33) v2(125.28,68.9) v2(125.4,76.75) v2(125.7,82.95) v2(125.9,86.85) v2(125.9,61.05) v2(125.9,59.25) v2(125.89,42.77) v2(126.53,90.45) v2(126.53,88.65) v2(126.53,71.25) v2(126.53,69.45) v2(126.53,65.85) v2(126.53,49.05) v2(126.53,39.45) v2(127.03,99.54) v2(127.17,93.45) v2(127.17,67.65) v2(127.17,64.65) v2(127.17,62.85) v2(127.17,61.05) v2(127.17,59.25) v2(127.38,74.22) v2(127.54,16.1) v2(127.8,69.45) v2(127.8,65.85) v2(127.8,44.25) v2(127.85,34.38) v2(128.44,62.85) v2(129.19,109.44) v2(131.1,33.62) v2(132.62,16.1) v2(134.78,78.45) v2(134.78,77.69) v2(134.78,77.06) v2(135.16,16.1) v2(135.29,41.62) v2(137.7,16.1) v2(139.86,75.28) v2(140.75,16.1) v2(140.93,88.51) v2(141,51.28) v2(141.13,101.69) v2(141.26,97.25) v2(141.26,94.33) v2(141.26,91.03) v2(142.69,44.71) v2(142.79,51.91) v2(143.03,16.1) v2(143.16,82.26) v2(144.43,79.98) v2(145.19,30.83) v2(145.65,63.3) v2(149.64,63.47) v2(150.02,15.08) v2(150.27,16.86) v2(150.78,72.23) v2(151.29,59.53) v2(151.37,64.23) v2(152.31,15.08) v2(152.43,59.51) v2(152.51,70.48) v2(152.72,64.28) v2(153.36,64.28) v2(153.54,59.51) v2(154.34,68.67) v2(154.59,15.08) v2(154.82,63.04) v2(154.97,59.48) v2(156.12,67.28) v2(156.12,63.09) v2(157.13,26.36) v2(157.89,66.01) v2(158.02,13.68) v2(158.78,11.78) v2(159.54,64.99) v2(159.93,10.13) v2(161.07,13.81) v2(161.45,63.98) v2(161.7,12.03) v2(162.47,10.13) v2(163.48,63.09) v2(164.12,10.13) v2(164.88,16.6) v2(164.88,13.81) v2(165.77,62.2) v3(8.8,5.56) v3(11.21,5.56) v3(15.53,4.03) v3(27.08,91.15) v3(28.38,74.03) v3(28.63,73.15) v3(29.14,74.57) v3(30.26,76.29) v3(30.26,75.41) v3(30.64,83.66) v3(30.66,82.77) v3(30.66,81.88) v3(31.02,77.18) v3(31.15,76.29) v3(31.15,75.41) v3(31.53,87.34) v3(31.6,83.66) v3(31.6,82.77) v3(31.6,81.88) v3(34.96,76.29) v3(34.96,75.41) v3(34.96,59.53) v3(35.59,78.07) v3(35.59,77.18) v3(35.85,60.42) v3(35.85,59.53) v3(35.88,58.59) v3(35.88,57.7) v3(37.88,90.65) v3(39.05,37.19) v3(39.05,36.35) v3(39.9,37.2) v3(39.91,36.36) v3(41.29,77.97) v3(41.29,77.08) v3(41.36,31.46) v3(41.69,76.34) v3(42.18,77.97) v3(42.18,77.08) v3(42.2,31.46) v3(42.58,76.34) v3(43.09,31.46) v3(43.97,82.64) v3(43.97,31.46) v3(44.75,28.42) v3(44.75,27.53) v3(44.86,83.53) v3(44.86,82.64) v3(44.86,81.76) v3(44.86,31.46) v3(45.5,55.21) v3(45.5,54.32) v3(48.04,72.94) v3(48.04,72.1) v3(48.93,72.94) v3(48.93,72.1) v3(48.91,28.45) v3(48.91,27.56) v3(50.04,28.75) v3(50.07,27.86) v3(50.91,28.72) v3(50.93,27.83) v3(50.96,70.58) v3(51.72,72.94) v3(51.72,72.1) v3(51.72,39.34) v3(51.72,38.45) v3(51.75,28.72) v3(51.77,27.83) v3(51.98,55.59) v3(52.61,72.94) v3(52.61,72.1) v3(52.74,39.34) v3(52.74,38.45) v3(52.86,55.59) v3(52.86,42.77) v3(52.86,41.88) v3(53.5,72.94) v3(53.5,72.1) v3(53.75,55.59) v3(53.75,42.77) v3(53.75,41.88) v3(54.03,87.69) v3(53.97,86.83) v3(54.64,42.77) v3(54.64,41.88) v3(54.9,81.88) v3(54.9,80.99) v3(54.9,80.1) v3(55.15,72.74) v3(55.4,71.85) v3(55.4,56.1) v3(55.53,42.77) v3(55.53,41.88) v3(55.79,80.1) v3(56.04,72.74) v3(56.29,71.85) v3(56.29,56.1) v3(56.67,80.1) v3(56.67,64.23) v3(57.06,72.84) v3(57.18,56.1) v3(57.56,80.1) v3(57.56,64.23) v3(57.94,72.84) v3(58.07,56.1) v3(58.45,80.1) v3(58.45,64.23) v3(58.83,72.84) v3(59.34,64.23) v3(59.42,56.81) v3(59.47,80.99) v3(59.52,55.97) v3(59.72,72.84) v3(60.23,64.23) v3(60.28,56.94) v3(60.41,56.05) v3(63.02,55.95) v3(63.86,55.95) v3(65.31,55.97) v3(67.98,95.51) v3(68,93.52) v3(70.52,22.07) v3(73.31,29.56) v3(73.44,30.45) v3(74.33,30.45) v3(74.33,29.56) v3(75.34,30.45) v3(75.34,29.56) v3(77,65.35) v3(77.25,56.48) v3(77.88,65.35) v3(78.14,56.48) v3(78.65,54.96) v3(78.77,65.35) v3(79.28,56.48) v3(79.53,54.96) v3(79.66,65.37) v3(80.17,56.48) v3(80.42,54.96) v3(81.33,56.53) v3(81.31,54.96) v3(81.34,54.07) v3(81.34,53.18) v3(81.34,52.29) v3(81.44,68.04) v3(81.69,65.75) v3(131.65,58.13) v3(131.99,50.89) v3(131.99,50.01) v3(132.54,58.13) v3(132.87,50.89) v3(132.87,50.01) v3(135.16,28.57) v3(135.96,70.94) v3(135.96,69.94) v3(137.24,73.91) v3(139.35,58.39) v3(139.61,46.07) v3(139.61,45.18) v3(139.61,44.29) v3(140.2,58.39) v3(140.49,46.07) v3(140.49,45.18) v3(140.49,44.29) v3(140.62,57.5) v3(141.89,61.11) v3(141.89,60.27)
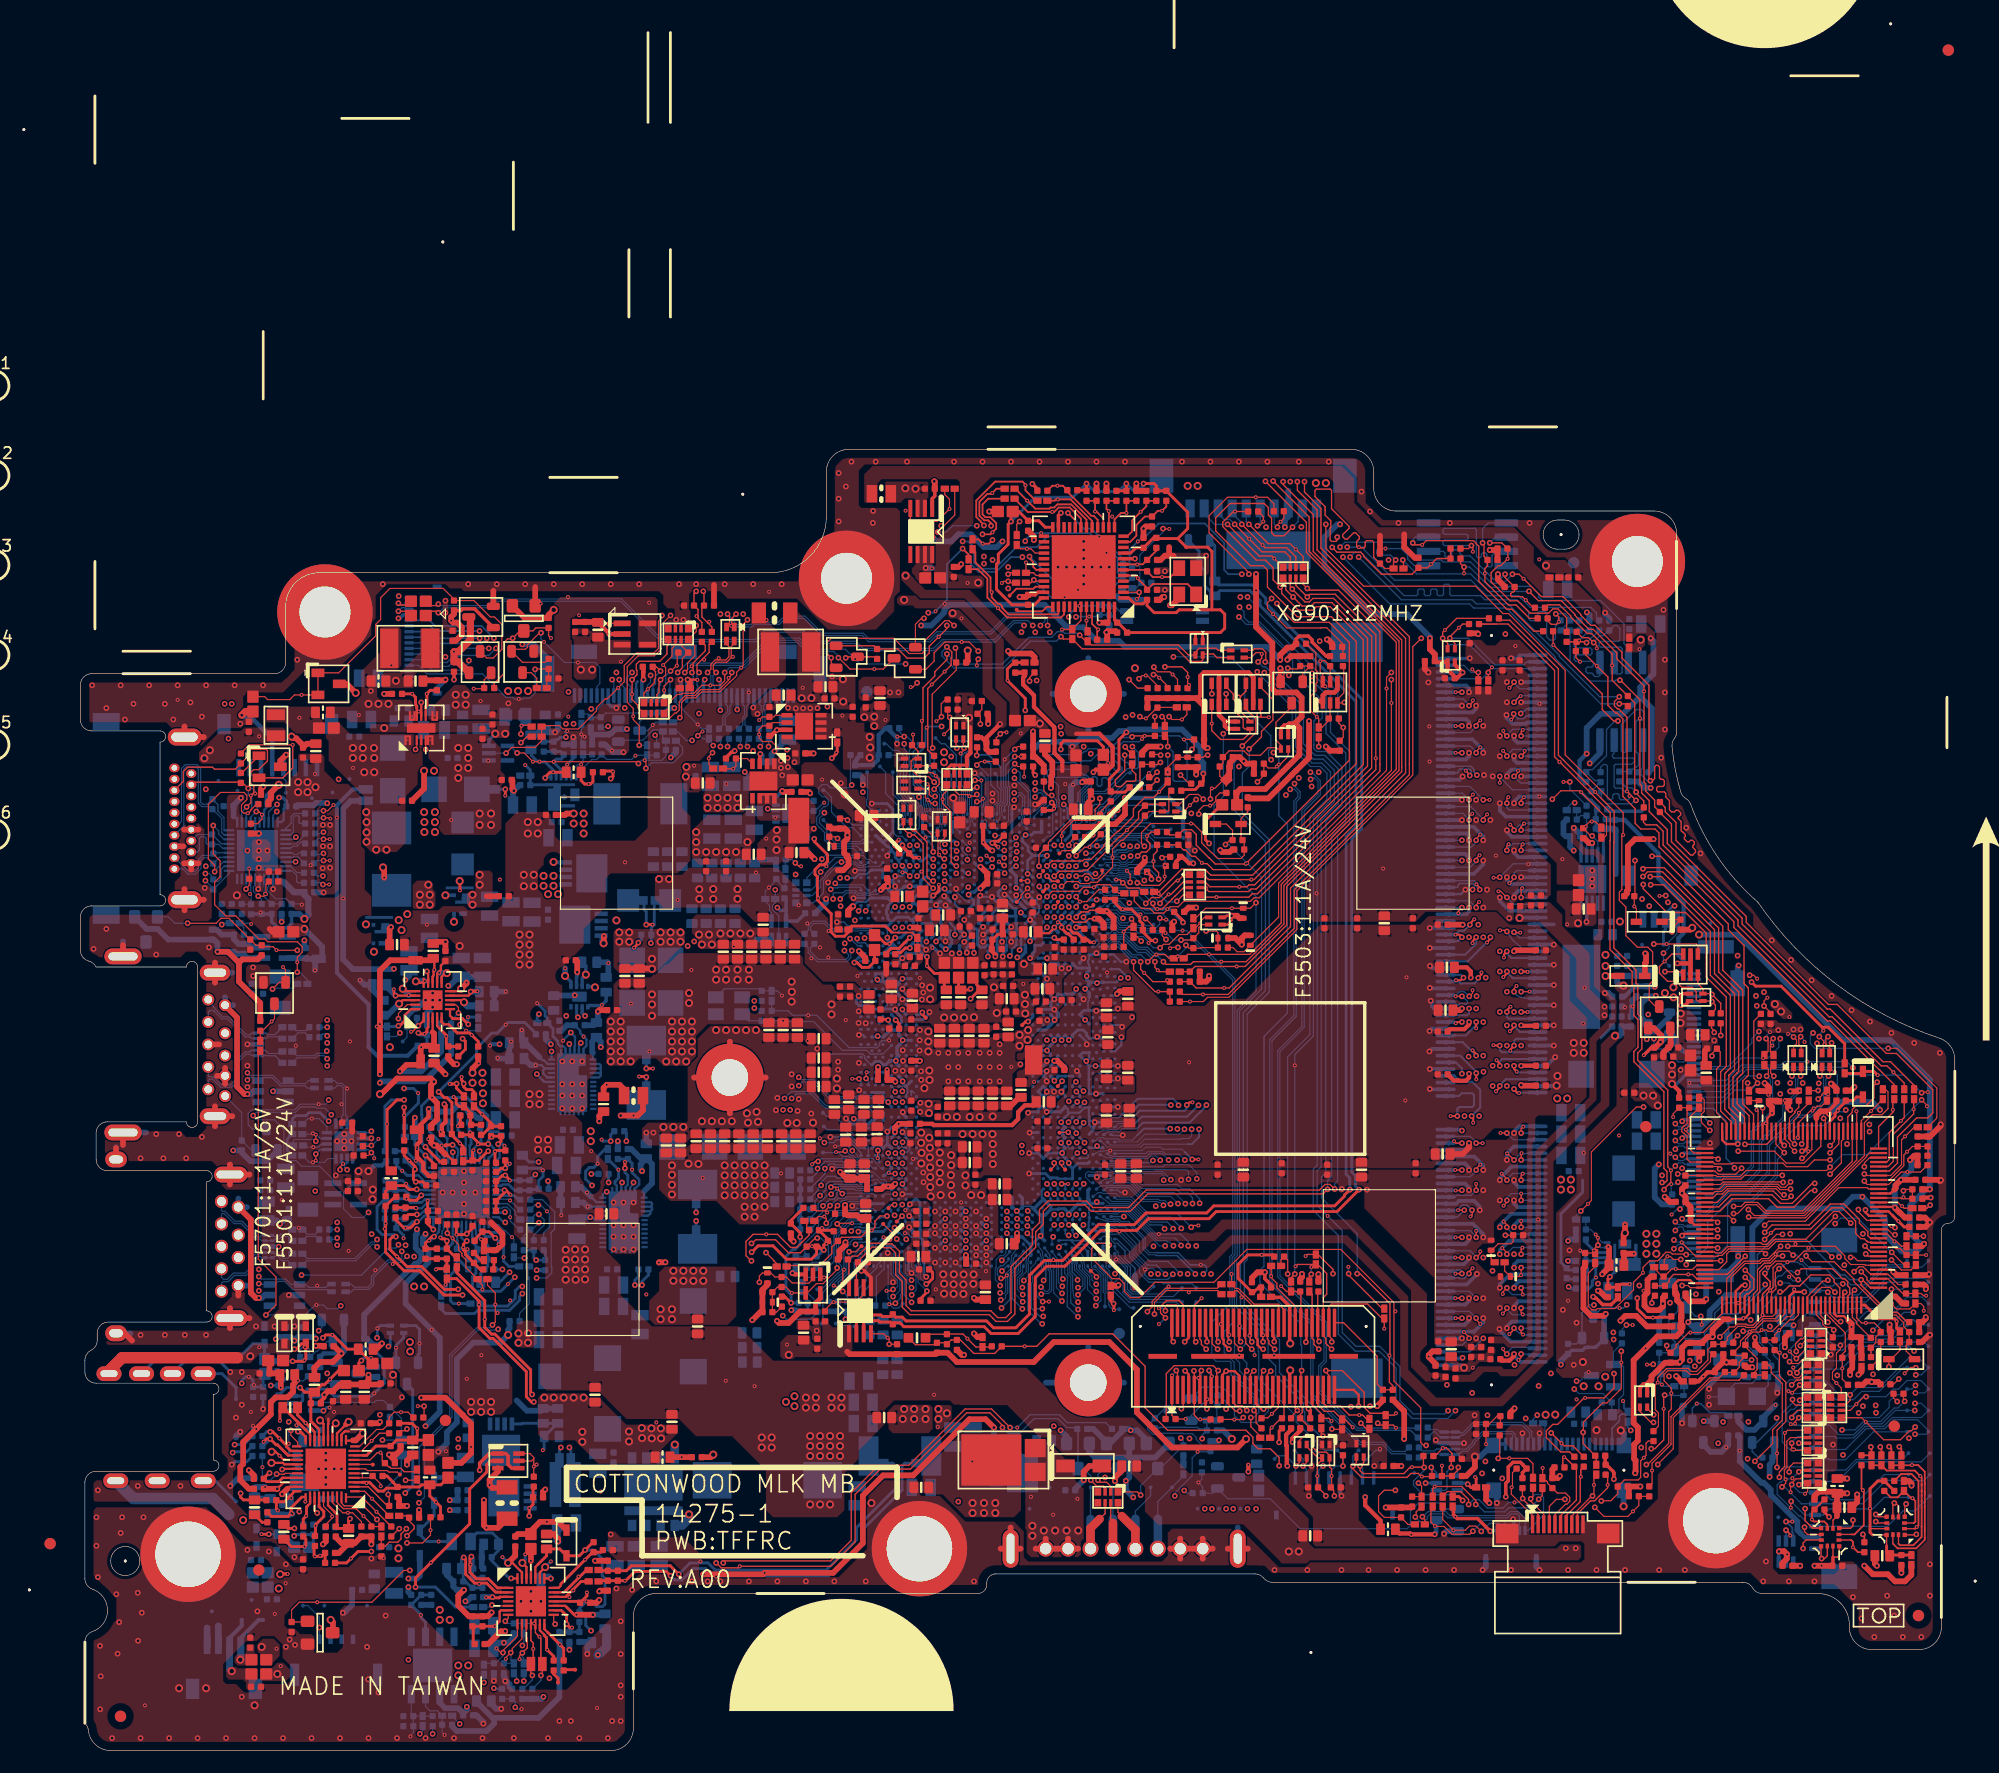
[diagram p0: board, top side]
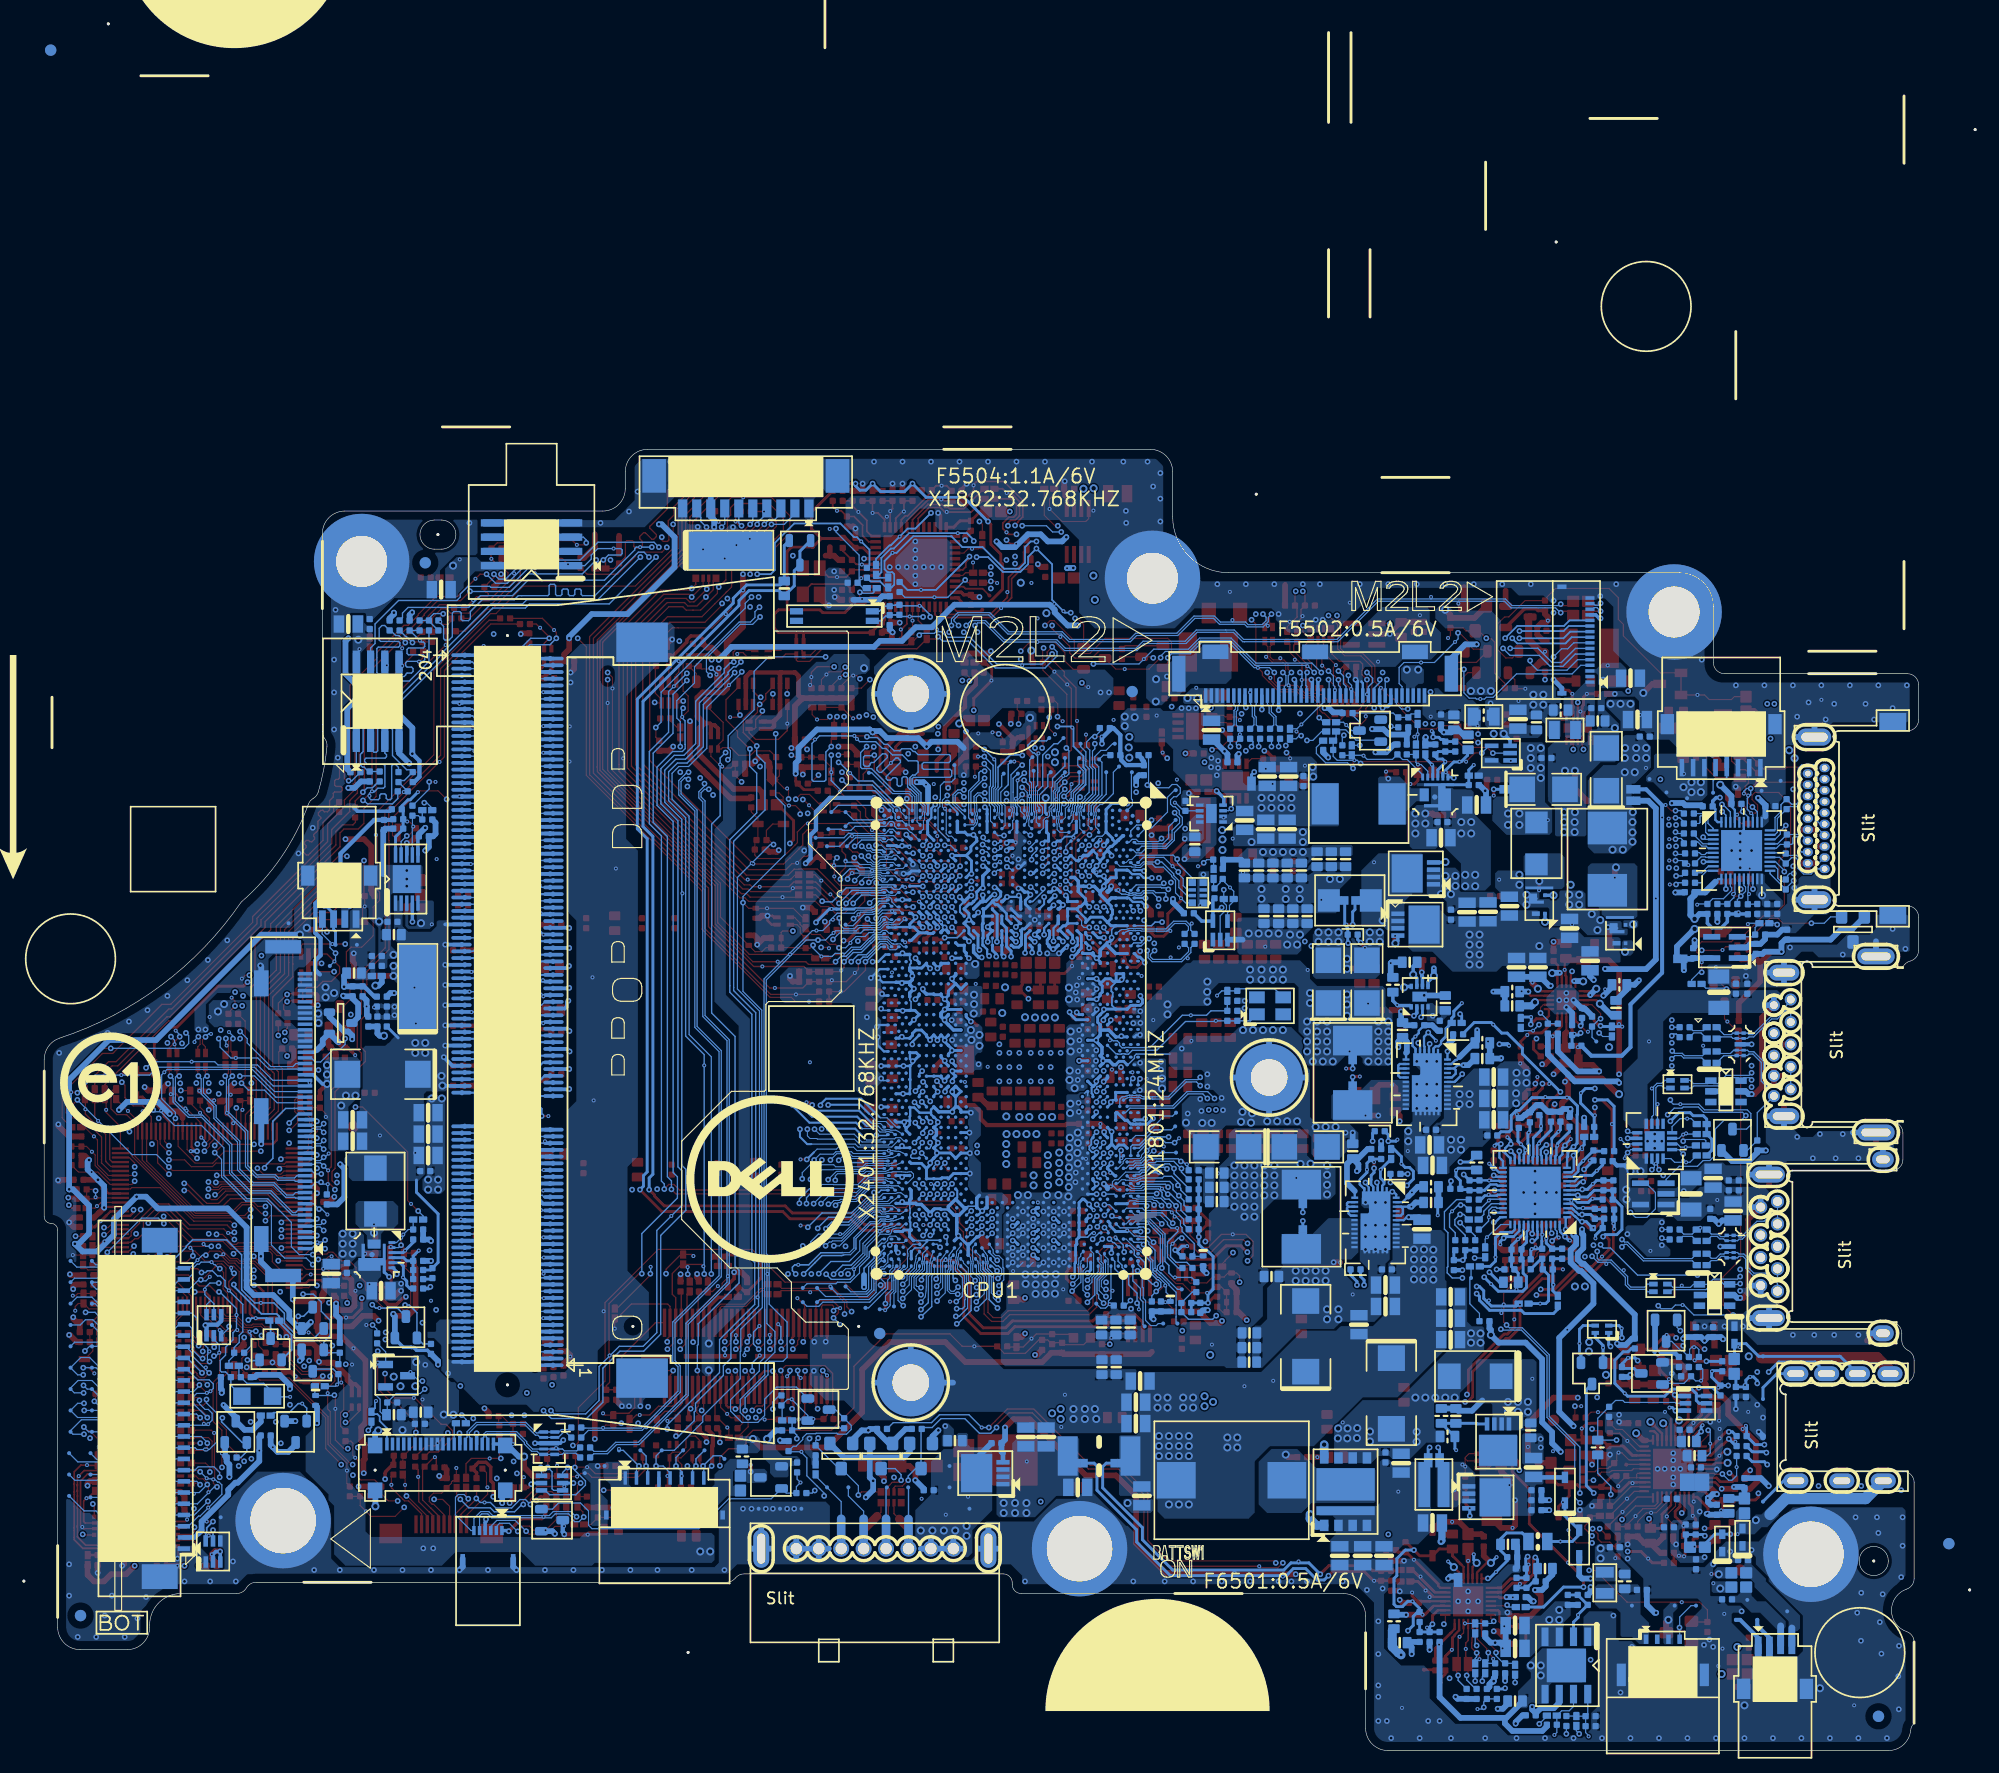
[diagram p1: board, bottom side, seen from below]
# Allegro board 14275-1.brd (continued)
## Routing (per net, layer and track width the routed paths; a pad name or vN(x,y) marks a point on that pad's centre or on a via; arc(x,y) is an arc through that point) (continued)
V0.85A_VID0: length 1.8
  TOP w0.14: TP2101.1 86.63,77.5 v2(86.17,77.95)
  BOTTOM w0.254: v2(86.17,77.95) 86.17,77.92 86.5,77.6 CPU1.AN11
V0.85A_VID1: length 1.2
  TOP w0.254: v2(86.17,77.04) 86.17,76.93 TP2102.1
  BOTTOM w0.254: v2(86.17,77.04) 86.17,76.91 CPU1.AN13
VCC_CORE: length 1.2
  BOTTOM w0.203: CPU1.A34 69.73,63.8 v2(69.41,63.8)
  BOTTOM w0.254: v2(73.28,66.07) 73.28,65.94 CPU1.G32
  vias: v1(49.08,66.59) v1(50.73,62.32) v1(54.46,69.59) v1(68.23,65.12) v1(72.09,63.32) v1(82.99,60.95) v2(67.55,61.41) v2(67.55,60.7) v2(69.38,65.91) v2(69.37,64.86) v2(69.4,61.31) v2(69.42,58.87) v2(70.01,64.84) v2(72.65,60.6) v2(73.31,62.43) v2(73.34,61.49) v2(73.31,60.6) v2(74.84,64.23) v2(74.81,63.32) v2(74.81,62.41) v2(74.94,60.55) v2(74.96,59.78) v2(76.49,62.2) v2(77.38,62.2) v2(77.38,60.93) v2(77.38,59.66) v2(78.26,62.2) v2(78.26,60.93) v2(78.26,59.66) v2(79.15,62.2) v2(79.15,59.66) v2(80.17,62.2) v2(80.17,60.93) v2(80.17,59.66) v2(81.06,62.2) v2(81.06,60.93) v2(81.06,59.66) v2(81.95,62.96) v2(81.95,62.2) v2(81.95,60.93) v2(81.95,59.66) v2(83.8,61.18) v2(86.2,65.12) v2(86.16,63.34) v3(47.28,64.99) v3(47.28,64.1) v3(47.28,63.21) v3(47.28,62.32) v3(47.28,61.44) v3(48.17,64.99) v3(48.17,64.1) v3(48.17,63.21) v3(48.17,62.32) v3(48.17,61.44) v3(49.05,61.44) v3(50.96,67.4) v3(50.96,66.52) v3(50.96,65.5) v3(52.23,61.43) v3(52.74,64.99) v3(52.74,64.1) v3(52.74,63.21) v3(52.74,62.32) v3(53.12,61.43) v3(53.63,64.99) v3(53.63,64.1) v3(53.63,63.21) v3(53.63,62.32) v3(54.01,61.43) v3(54.26,67.53) v3(54.26,66.64) v3(54.52,64.99) v3(54.52,64.1) v3(54.52,63.21) v3(54.52,62.32) v3(56.67,69.61) v3(56.67,68.73) v3(57.56,69.61) v3(57.56,68.73) v3(58.58,69.61) v3(58.58,68.73) v3(59.6,69.61) v3(59.6,68.73) v3(63.41,68.55) v3(63.42,67.64) v3(63.41,66.77) v3(66.96,66.52) v3(66.96,65.63) v3(67.44,59.91) v3(67.44,59.02) v3(75.24,59.05) v3(75.6,64.1) v3(75.6,63.21) v3(75.6,62.32) v3(75.68,60.62) v3(75.7,59.78) v3(83.72,63.8) v3(83.72,62.83) v3(84.44,63.35) v3(84.49,64.23)
VCC_SENSE: length 71.1
  TOP w0.254: PR4648.1 34.2,58.39 33.53,59.05 v2(33.53,59.45) 33.51,59.43 33.1,59.43 33.1,59.43 v1(32.93,59.43) ; R719.2 72.99,64.8 v2(72.68,65.12)
  L3 w0.254: v2(54.72,72.13) 54.74,72.1 54.74,71.62 55.15,71.21 63.05,71.21 66.1,68.17 70.14,68.17 72.04,66.26 72.04,65.86 72.68,65.22 v2(72.68,65.12)
  L4 w0.254: v2(54.72,72.13) 54.52,72.33 54.52,78.96 53.8,79.67 49.1,79.67 48.04,80.74 40.04,80.74 38.39,79.09 38.39,73.88 37.75,73.25 37.75,65.45 34.45,62.15 34.45,61.34 33.73,60.62 33.73,59.86 33.53,59.67 v2(33.53,59.45)
  BOTTOM w0.254: CPU1.E32 72.68,65.24 v2(72.68,65.12)
VCCGT_SENSE: length 62.7
  TOP w0.254: R721.2 74.9,40.29 75.47,40.86 v2(75.47,40.96) ; PR4617.1 33.56,42.59 36.05,40.1 36.05,38.44 v1(36.05,38.44) 36.05,38.44 36.05,37.73 36.65,37.13 36.95,37.13 40.14,33.94 40.14,31.87 v2(40.27,31.74)
  L6 w0.254: v2(75.47,40.96) 75.22,40.72 75.22,35.79 73.23,33.8 61.96,33.8 59.04,30.88 45.68,30.88 45.27,30.47 40.31,30.47 39.92,30.87 39.92,31.39 v2(40.27,31.74)
  BOTTOM w0.089: v2(75.47,40.96) 74.68,41.75 74.68,42.92 74.69,42.96 74.74,43.1 74.74,43.1 74.74,43.29 74.68,43.42 74.68,43.63 CPU1.J70
VCCRTCEXT: length 4.8
  TOP w0.254: v2(95.49,77.69) 95.49,77.93 C2112.1
  BOTTOM w0.089: v2(95.49,77.69) 95.49,77.82 v1(95.08,78.22) 93.4,78.22 93.32,78.3 92.51,78.3 92.39,78.18 91.96,78.18 CPU1.BB10
VCCSA_SENSE: length 96.4
  TOP w0.254: R735.2 71.84,71.08 72.24,71.49 72.31,71.49 72.33,71.51 72.97,71.51 73.5,72.04 73.51,72.04 v2(73.93,72.46)
  L3 w0.254: v2(39.4,40.73) 39.28,40.86 37.86,40.86 36.1,42.62 36.1,46.75 35.77,47.08 35.77,51.5 34.58,52.69 34.58,54.48 36.57,56.47 36.57,61.79 35.97,62.39 35.97,64.74 36.99,65.75 36.99,73.58 37.75,74.35 37.75,79.78 38.46,80.49 47.49,80.49 49.01,78.96 62.14,78.96 66.33,74.77 67.96,74.77 68.54,74.19 68.54,73.8 68.83,73.5 70.17,73.5 71.34,72.33 71.34,72.29 71.65,71.98 71.65,71.98 71.7,71.93 72.81,71.93 73.21,72.32 73.79,72.32 v2(73.93,72.46)
  BOTTOM w0.254: 37.19,39.25 35.43,39.25 35.14,38.96 32.56,38.96 32.16,39.35 PR4607.1 ; 37.19,39.25 v1(37.19,39.01) ; 37.19,39.25 38.25,39.25 39.15,40.14 39.15,40.48 v2(39.4,40.73) ; v2(73.93,72.46) 74.26,72.79 CPU1.H20
VCCSTG_EN_R: length 33.5
  TOP w0.102: U4002.2 61.71,91.65 C4033.1 60.84,91.36 60.51,91.03 v1(60.51,90.59) 60.51,90.27 60.82,89.95 61.62,89.95 62.25,89.32 62.89,89.32 v2(62.99,89.22) ; v2(39.28,89.86) 39.81,90.39 R4017.2
  L3 w0.102: v2(39.28,89.86) 42.15,89.86 43.16,90.88 44.12,90.88 44.46,90.54 48.87,90.54 49.72,91.38 54.79,91.38 55.48,90.7 61.59,90.7 61.83,90.45 62.36,90.45 62.9,89.91 62.9,89.31 v2(62.99,89.22)
VCCSTU_EN: length 6.4
  BOTTOM w0.102: R4024.1 62.85,76.94 R4026.2 62.27,77.37 62.27,77.47 EC4001.1 61.85,77.53 61.85,77.41 v1(61.39,76.94) 61.06,76.61 R4023.2 61.06,75.72 61.44,75.34 61.44,74.86 61.61,74.69 U4005.4
VCCSTU_EN_R: length 9
  TOP w0.102: v2(63.74,79.14) 64.04,78.83 v1(64.24,78.83)
  L4 w0.102: v2(61.27,83.97) 61.27,83.94 63.3,81.91 63.3,80.05 63.74,79.62 v2(63.74,79.14)
  BOTTOM w0.102: R4024.2 62.85,79.38 C4034.1 63.46,79.42 v2(63.74,79.14) ; v2(61.27,83.97) 61.32,83.97 61.5,83.78 U4006.3
VDD_HDA: length 14.2
  TOP w0.203: 25.11,23.91 HDA27.3
  TOP w0.254: R2727.2 31.15,22.7 v1(31.71,22.14) 32.1,21.75 R2918.1 ; R2727.2 32.14,23.69 R2713.2 ; R2727.2 30.41,23.69 30.22,23.5 C2721.1 ; C2721.1 28.17,23.39 27.29,23.39 27.03,23.13 26.55,23.13 25.77,23.91 25.11,23.91 ; C2721.1 27.89,23.89 27.89,23.91 27.33,24.48 R2701.1
VDD_IO: length 10.2
  TOP w0.203: 25.18,26.31 HDA27.9
  TOP w0.254: 25.18,26.31 25.51,26.31 26.35,27.15 C2707.1 28.19,27.68 C2710.1 ; R2723.1 29.29,29.18 29.31,29.15 29.58,29.15 v1(30.03,28.71) 30.03,28.09 C2710.1 ; C2710.1 R2715.2
VSS_AY71: length 5.2
  TOP w0.254: R602.1 91.85,40.1 v2(92.11,39.85) 92.13,39.82 v1(92.13,39.26)
  BOTTOM w0.089: CPU1.AY71 91.26,43.02 91.26,42.92 91.54,42.65 91.54,41.87 91.53,41.86 91.53,41.1 92.11,40.52 v2(92.11,39.85)
VSS_SENSE: length 69.8
  TOP w0.254: v2(72.02,65.12) 71.95,65.18 R720.1 ; v1(33.98,60.04) 33.98,59.77 34.17,59.58 v2(34.17,59.45) 34.17,59.17 34.42,58.92 34.89,58.92 35.08,58.73 PR4645.1
  L3 w0.254: v2(54.13,71.72) 54.26,71.6 54.26,71.57 54.99,70.83 62.9,70.83 65.95,67.79 69.98,67.79 71.66,66.1 71.66,65.47 v2(72.02,65.12)
  L4 w0.254: v2(34.17,59.45) 34.17,59.8 34.11,59.86 34.11,60.46 34.83,61.18 34.83,61.99 38.13,65.3 38.13,73.09 38.77,73.72 38.77,78.93 40.19,80.36 47.88,80.36 48.95,79.29 53.65,79.29 54.13,78.8 v2(54.13,71.72)
  BOTTOM w0.254: v2(72.02,65.12) 72.02,64.99 CPU1.E33
VSSGT_SENSE: length 62.8
  TOP w0.254: R722.1 75.72,42.89 75.98,42.64 75.98,42.08 75.49,41.6 v2(75.41,41.6) ; v2(40.42,31.08) 40.21,31.08 39.76,31.53 39.76,33.78 36.79,36.75 36.49,36.75 35.54,37.7 35.54,39.76 v1(35.54,39.76) 35.54,39.76 35.54,40.07 33.55,42.07 PR4618.1
  L6 w0.254: v2(75.41,41.6) 75.09,41.6 74.84,41.35 74.84,35.95 73.08,34.18 61.8,34.18 58.88,31.26 45.52,31.26 45.12,30.85 40.65,30.85 v2(40.42,31.08)
  BOTTOM w0.089: v2(75.41,41.6) 74.87,42.14 74.87,42.93 74.93,43.06 74.93,43.31 74.87,43.43 74.87,43.89 74.69,44.07 74.69,44.26 CPU1.J69
VSSSA_SENSE: length 90.4
  TOP w0.254: R734.1 72.79,71.13 73.12,71.13 73.54,71.55 v2(73.95,71.55)
  L3 w0.254: v2(73.95,71.55) 73.95,71.71 73.72,71.94 73.37,71.94 72.97,71.55 71.54,71.55 71.49,71.6 70.96,72.13 70.96,72.17 70.01,73.12 68.68,73.12 68.15,73.64 68.15,74.03 67.8,74.39 66.17,74.39 61.98,78.58 48.85,78.58 47.33,80.1 38.61,80.1 38.13,79.62 38.13,74.19 37.37,73.43 37.37,65.6 36.35,64.58 36.35,62.55 36.95,61.95 36.95,56.31 34.96,54.32 34.96,52.85 36.15,51.66 36.15,47.24 36.48,46.91 36.48,42.78 38.02,41.24 39.28,41.24 v2(39.4,41.37)
  BOTTOM w0.254: v1(38.31,40.13) 38.45,39.98 ; 38.45,39.98 38.1,39.63 35.87,39.63 PR4604.2 ; 38.45,39.98 38.77,40.3 38.77,40.99 39.15,41.37 v2(39.4,41.37) ; CPU1.H21 73.95,71.7 v2(73.95,71.55)
0D675V_PWR:
  vias: v1(132.54,73.65) v3(133.51,73.75)
0D675V_S0: length 4.6
  BOTTOM w0.305: v2(123.86,97.38) 123.83,97.35 DIMM1.203 ; v2(127.54,97.38) 128.05,97.38 128.32,97.65 DIMM1.204
  vias: v1(127.92,98.47) v1(130.08,93.31) v1(130.08,85.06) v1(132.11,79.47)
1D0V_S5: length 48.6
  TOP w0.305: v3(107.86,33.9) 107.8,33.85 XDP1.43 ; R9927.1 106.19,40.4 106.99,40.4 107.8,39.6 XDP1.44 107.8,36.34 v3(107.86,36.29)
  TOP w0.508: v2(137.29,38.32) 137.73,38.75 138.72,38.75 139.66,37.81 R2402.1
  L3 w0.508: v2(121.83,32.61) 121.44,32.99 108.76,32.99 v3(107.86,33.9)
  L4 w0.508: v2(137.29,38.32) 137.27,38.32 137.22,38.37 136.31,38.37 135.07,37.13 132.34,37.13 128.91,33.7 127.56,33.7 126.96,34.3 124.66,34.3 123.59,33.23 122.44,33.23 v2(121.83,32.61)
  BOTTOM w0.254: CPU1.AF19 82.99,72.67 v2(82.99,72.1) ; v2(79.03,71.14) 79.03,71.6 CPU1.V21
  BOTTOM w0.305: CPU1.V20 78.88,72.1 v2(78.8,72.1) ; CPU1.AF19 82.65,73.09 v2(82.99,73.42) 82.68,73.74 CPU1.AF18
  vias: v1(57.59,86.18) v1(71.77,91.88) v1(98.83,94.99) v2(62.45,88.23) v2(62.45,87.6) v2(62.56,86.94) v2(63.05,88.49) v2(63.09,92.96) v2(63.08,87.67) v2(63.77,92.9) v2(64.43,92.91) v2(65.07,92.92) v2(65.71,92.93) v3(55.91,84.93) v3(55.91,84.04) v3(56.8,84.93) v3(56.8,84.04) v3(57.69,84.93) v3(57.69,84.04) v3(58.58,84.93) v3(58.58,84.04) v3(69.88,92.12) v3(70.77,92.17) v3(70.77,91.33) v3(94.01,96.49)
1D0V_S5_PWRGD: length 1.9
  BOTTOM w0.102: PR5211.1 44.66,89.85 v1(44.66,90.6) R4029.1
1D5V_PWR: length 3.5
  BOTTOM w0.508: PU5302.5 20.1,70.65 PC5309.1 20.16,70.58 PG5304.1 20.94,69.59 v1(20.91,69.56)
1D5V_S0: length 166.3
  TOP w0.508: R2713.1 33.97,25.65 34.83,26.51 v1(34.83,27.07) 34.83,29.15 34.09,29.89 34.09,29.91 32.54,31.46 v2(30.39,31.46) ; v2(82.71,98.01) 82.92,97.8 84.75,97.8 85.06,97.49 R2102.1
  L3 w0.508: v3(19.97,73.25) 20.34,73.25 20.94,73.84 20.94,84.42 21.7,85.18 21.7,89.46 23.93,91.69 25.81,91.69 26.42,92.3 27.95,92.3 28.61,92.95 28.61,94.47 29.1,94.95 29.1,95.85 31.39,98.14 32.77,98.14 35.07,100.44 39.33,100.44 40.8,98.97 43.92,98.97 44.5,98.39 46.01,98.39 46.26,98.65 48.03,98.65 49.02,97.66 53.2,97.66 53.21,97.64 65.58,97.64 66.38,98.45 70.24,98.45 73.36,101.57 73.86,101.57 74.72,102.43 74.72,106.91 v2(75.98,108.17)
  L4 w0.508: v2(30.39,31.46) 30.51,31.59 30.51,37.76 23.78,44.49 23.78,49.36 22.13,51.01 22.13,54.58 21.27,55.44 21.27,69.58 20.61,70.25 20.61,72.74 20.1,73.25 v3(19.97,73.25)
  L6 w0.508: v2(82.71,98.01) 82.07,98.65 82.07,107.66 v2(82.2,107.79)
  BOTTOM w0.508: v2(82.2,107.79) 81.69,107.28 80.55,107.28 79.41,108.43 78.26,108.43 77.63,107.79 76.36,107.79 v2(75.98,108.17) ; v3(19.97,73.25) 20.23,72.99 20.23,72.99 21.55,71.67 PG5304.2
1D5V_VDD: length 10.3
  TOP w0.508: 16.87,73.25 17.13,72.99 R5701.2
  L6 w0.508: v2(17.71,84.96) 17.66,85.01 14.38,85.01 v2(14.31,84.93)
  BOTTOM w0.203: C5702.2 18.12,83.93 18.12,82.98 17.91,82.77 U5701.40 ; U5701.12 v2(17.18,76.8)
  BOTTOM w0.305: v2(17.71,84.96) 18.04,84.96 18.36,84.64 C5702.2
  BOTTOM w0.508: v2(14.31,84.93) 13.66,84.28 C5716.2 13.66,83.27
  vias: v1(16.06,74.72) v3(13.95,76.24)
1D8S_EN#: length 5
  BOTTOM w0.102: Q4007.D 22.02,36.48 21.14,35.6 21,35.6 R4044.2 20.42,35.15 20.42,35.77 20.23,35.96 v1(20.02,35.96) 19.79,35.96 19.59,35.76 R4041.1
1D8S_EN_R#: length 5.4
  BOTTOM w0.102: Q4006.G 22.35,32.64 22.26,32.73 20.92,32.73 C4022.2 19.88,32.96 19.45,32.96 19.43,32.97 v1(19.4,32.97) 19.4,33.01 19.25,33.16 19.25,34.02 19.43,34.19 R4041.2
1D8V_S5_PWROK: length 161.1
  TOP w0.102: v2(53.44,92.08) 53.6,92.24 53.6,93.43 54.01,93.85 54.86,93.85 55.39,94.38 57.02,94.38 57.91,95.27 57.93,95.27 58.5,95.84 58.5,96.13 v1(58.9,96.52) 59.09,96.71 59.09,100.42 v2(59.47,100.81)
  L6 w0.102: v2(59.47,100.81) 59.4,100.74 54.32,100.74 53.95,100.37 51.52,100.37 51.04,100.86 43.55,100.86 42.93,100.23 35.4,100.23 33.21,98.04 32.34,98.04 30.48,96.18 27.66,96.18 26.89,95.41 23.7,95.41 19.43,91.14 18.82,91.14 13.88,86.19 13.88,84.19 14.33,83.74 14.33,78.57 15.34,77.56 15.34,76.13 14.95,75.74 14.95,72.05 16.05,70.95 16.05,66.88 16.67,66.26 16.67,47.45 18.81,45.3 18.81,42.68 24.93,36.56 24.93,36.11 26.33,34.7 27.42,34.7 29.37,32.75 29.37,30.71 29.75,30.33 29.75,22.79 30.02,22.52 30.36,22.52 30.94,21.94 30.94,18.18 34.75,14.37 34.75,9.54 33.15,7.94 33.15,3.04 v2(33.81,2.38)
  BOTTOM w0.102: v2(53.44,92.08) 53.03,91.67 R4030.1 ; v2(33.81,2.38) 33.14,3.05 PR5308.1
1D35V_S3: length 46.8
  BOTTOM w0.127: v2(92.49,66.13) 92.34,65.98 91.93,65.98 91.92,65.98 CPU1.BB32 ; CPU1.BB51 91.97,54.83 92.87,54.83 92.89,54.86 v2(92.92,54.86)
  BOTTOM w0.203: CPU1.AU42 89.1,60.32 v2(88.84,60.58) ; v2(89.71,62.95) 89.71,63.17 CPU1.AU35 ; CPU1.BB23 92.1,70.97 92.74,70.33 v2(93.25,70.33)
  BOTTOM w0.254: 133.92,50.87 133.92,49.77 131.99,47.84 131.99,43.52 PC5112.1 132.66,42.84 PR5103.1 ; R4206.1 135.54,63.53 ; v2(92.49,61.03) CPU1.BB41 ; v2(86.17,70.64) CPU1.AL23 ; CPU1.BB47 v2(92.49,57.37) ; v2(89.43,66.97) 89.1,67.31 CPU1.AU28 ; CPU1.AU23 89.1,70.26 89.42,70.59 v2(89.42,70.64)
  BOTTOM w0.33: DIMM1.93 120.49,64.35 v2(120.28,64.14) ; DIMM1.112 v2(131.35,70.05) ; v2(120.29,73.33) 120.32,73.35 DIMM1.123 ; v2(120.29,58.98) 120.32,58.95 DIMM1.75 ; DIMM1.81 120.3,60.75 v2(120.29,60.76) ; v2(120.26,62.32) 120.49,62.55 DIMM1.87 ; v2(120.37,66.84) 120.37,66.83 120.51,66.69 120.51,66.33 120.69,66.15 DIMM1.99 ; v2(131.35,62.85) DIMM1.88 ; DIMM1.76 131.58,59.25 v3(131.6,59.28) ; v2(120.29,71.55) DIMM1.117 ; v2(131.35,64.65) DIMM1.94 ; DIMM1.82 130.71,61.05 v2(131.48,61.82) ; DIMM1.105 120.34,67.95 v2(120.29,67.99) ; v2(131.35,66.45) DIMM1.100 ; DIMM1.124 131.35,73.65 ; v2(120.32,69.94) 120.51,69.75 DIMM1.111 ; v2(131.35,71.85) DIMM1.118 ; DIMM1.106 v2(131.35,68.25)
  vias: v1(91.52,69.36) v1(91.8,53.49) v1(98.84,61.36) v1(118.12,57.96) v1(118.22,68.93) v1(133.97,64.81) v1(137.17,54.83) v3(131.68,60.14) v3(133.13,63.09) v3(133.13,62.2) v3(134.02,63.09) v3(134.02,62.2)
1D35V_VTT_PWRGD: length 184.3
  TOP w0.102: PR5107.1 135.03,43.15 134.42,42.54 134.42,39.62 134.75,39.29 135.11,39.29 135.23,39.4 136.79,39.4 138.46,41.08 138.46,41.75 v1(139.3,42.59) 139.3,43.07 139.88,43.66 140.61,43.66 141.09,44.13 141.09,44.17 141.35,44.43 141.74,44.43 141.91,44.26 143.12,44.26 v2(143.16,44.21)
  L4 w0.102: v2(157.38,57.11) 157.38,59.87 154.03,63.22 154.03,65.24 147.84,71.43 147.11,71.43 141.24,77.3 141.24,79.21 140.11,80.33 139.96,80.33 137.14,83.15 137.14,90.19 136.23,91.1 136.23,98.06 135.34,98.95 135.34,98.95 135.09,99.21 135.08,99.21 133.36,100.93 133.36,101.4 131.64,103.12 130.27,103.12 129.4,103.98 128.18,103.98 128,104.16 125.81,104.16 125.69,104.29 115.42,104.29 111.7,100.56 105.59,100.56 104.2,101.95 v2(104.17,101.95)
  L6 w0.102: v2(54.53,90.05) 54.53,90.63 54.86,90.96 60.45,90.96 61.59,92.1 61.59,92.6 61.59,93.09 63.32,94.82 66.16,94.82 66.62,94.36 68.45,94.36 69.1,95.01 73.62,95.01 74.09,94.55 74.96,94.55 75.47,95.06 83.43,95.06 86.46,98.09 100.57,98.09 102.85,100.37 102.85,101.24 103.1,101.49 103.71,101.49 v2(104.17,101.95)
  BOTTOM w0.102: v2(157.38,57.11) 157.37,57.11 157.21,56.95 156.71,56.95 155.48,55.72 153.07,55.72 151.09,53.74 151.09,51.25 149.02,49.19 147.17,49.19 145.07,47.09 145.07,44.91 144.37,44.21 v2(143.16,44.21) ; R4011.1 53.21,90.85 54.01,90.05 v2(54.53,90.05)
3D3V_AUX_KBC_33: length 3.9
  TOP w0.203: 150.81,56.8 150.37,56.37 150.37,55.93 150.36,55.92 KBC24.54
  TOP w0.508: 150.81,56.8 v1(150.81,56.84) 150.81,57.36 150.53,57.64 C2423.1 150.58,57.94 151.29,57.94 R2462.1
3D3V_AUX_KBC_R: length 5.3
  TOP w0.305: R2478.1 122.41,21.67 122.41,21.02 v1(122.58,20.85) 122.74,20.68 124.56,20.68 v2(125.69,19.55)
  BOTTOM w0.305: v2(125.69,19.55) 125.75,19.61 DB3.1
3D3V_AUX_S5: length 364.2
  TOP w0.305: R1727.1 108.38,99.08 108.66,99.36 109.46,99.36 109.81,99.01 109.81,98.82 111.06,97.57 R1726.2
  TOP w0.508: R1727.1 108.03,98.33 107.6,98.33 106.97,97.69 v2(106.97,97.24) ; PG4533.1 29.06,61.13 v2(28.48,60.55) ; R2463.1 158.91,32.61 159.21,32.9 159.65,32.9 v2(159.69,32.86) 160.26,32.86 R1737.1
  L3 w0.381: v2(13.62,53.5) 15.21,51.91 15.21,50.92 15.15,50.86 15.15,41.75 15.26,41.64 15.26,39.99 15.78,39.46 16.75,39.46 17.67,38.54 19.38,38.54 20.23,37.69 20.23,34.13 21.62,32.73 25.94,32.73 29.75,28.92 v2(30.77,28.92)
  L3 w0.508: v2(23.02,86.58) 22.69,86.91 22.69,89.05 23.78,90.14 27.72,90.14 29.75,92.17 29.75,93.9 32.7,96.85 33.17,96.85 34.18,97.86 35.07,97.86 35.78,97.15 39.68,97.15 39.72,97.11 42.82,97.11 44.3,95.62 45.93,95.62 46.41,96.11 v2(47.78,96.11) ; v2(139.64,63.41) 139.64,63.56 136.71,66.49 136.71,67.73 136.71,67.73 136.71,68.35 136.71,68.35 136.71,71.31 135.92,72.1 135.92,81.3 134.28,82.93 134.28,86.89 133.08,88.09 133.08,95.44 131.03,97.5 131.03,97.86 128.7,100.18 128.18,100.18 126.82,101.54 123.42,101.54 123.26,101.69 113.19,101.69 113.02,101.52 109.92,101.52 106.97,98.57 v2(106.97,97.24)
  L4 w0.508: v2(47.78,96.11) 49.46,97.78 65.6,97.78 66.01,98.19 71.83,98.19 72.67,99.03 73.68,99.03 v2(74.95,100.3) ; v2(158.91,46.07) 153.83,46.07 149.26,50.64 146.42,50.64 144.3,52.75 144.3,56.94 143.24,58.01 141.64,58.01 139.64,60 v2(139.64,63.41)
  L6 w0.508: v2(158.91,46.07) 158.45,45.61 158.45,44 159.45,43 159.45,38.41 159.15,38.1 159.15,33.28 159.52,32.9 159.65,32.9 v2(159.69,32.86) ; v2(30.77,28.92) 32.16,28.92 32.8,28.29 32.8,24.83 33.69,23.95 33.69,21.81 35.85,19.65 35.85,15.59 41.18,10.25 42.32,10.25 v2(43.59,8.98) ; v2(23.02,86.58) 23.73,85.87 23.73,76.24 22.84,75.36 22.84,67.76 26.12,64.48 26.96,64.48 28.65,62.79 28.65,60.71 v2(28.48,60.55) 28.1,60.17 28.1,49.5 28.67,48.93 29.76,48.93 30.77,47.92 v2(30.77,46.07)
  BOTTOM w0.508: v2(139.64,63.41) 139.64,63.75 140,64.1 140.36,64.1 141.67,65.42 D2501.1 ; PR4468.1 v2(43.59,8.98) ; v2(28.48,60.55) 30.39,60.55 32.16,62.32 PR4522.1 ; v2(30.77,28.92) 32.04,30.19 32.04,36.8 v1(31.32,37.52) 28.99,39.85 28.99,41.65 30.11,42.77 30.28,42.77 31.02,43.51 31.02,44.62 30.53,45.11 30.53,45.7 30.77,45.94 v2(30.77,46.07) ; v2(13.62,53.5) R2452.2 14.38,53.31 15.15,52.55 16.62,52.55 Q2415.G ; v2(74.95,100.3) 75.85,100.3 77.02,101.47 77.02,101.7 77.47,102.15 85.96,102.15 87.35,100.75 87.35,100.74 87.96,100.14 89.4,100.14 90.62,98.93 92.59,98.93 93.12,98.39 105.82,98.39 v2(106.97,97.24)
3D3V_CAMERA_S0:
  vias: v1(43.49,92.17)
3D3V_GSEN2: length 13.7
  TOP w0.114: 159.54,19.78 159.55,19.78 U7001.9 ; 159.77,19.22 U7001.10 161.02,18.26
  TOP w0.254: 159.77,19.22 159.54,19.45 v1(159.54,21.58) 159.54,23.34 160.24,24.03 R7005.1 R7006.2 ; 161.02,18.26 161.02,17.64 C7004.1 161.36,17.43 C7003.1 R7004.2
3D3V_MCU: length 81.2
  TOP w0.254: 97.82,108.04 TP6902.1 100.49,107.28 100.87,106.9 100.87,101.69 ; 97.82,108.04 95.98,108.04 R6902.2 95.66,108.11 C6907.1 94.1,107.22 93.63,106.75 U6901.9 ; 97.82,108.04 98.71,108.93 98.71,110.39 R6919.2 R6917.2 95.92,112.74 95.71,112.95 v2(94.77,112.95) ; U6901.1 93.46,102.75 93.99,102.23 94.74,102.23 C6906.1 95.09,102.08 95.73,101.44 97.7,101.44 97.95,101.69 100.87,101.69 ; 100.87,101.69 101.63,101.69 102.01,101.31 102.01,100.04 101.63,99.66 100.05,99.66 ; RN6901.2 99.4,99.66 ; 99.4,99.66 C6905.1 93.31,99.73 92.49,100.55 C6904.1 92.19,100.79 U6901.48 ; 99.4,99.66 100.05,99.66 ; U6901.36 85.67,102.75 85.06,102.14 C6903.1 83.05,102.14 81.67,103.52 81.67,105.77 81.83,105.93 81.83,106.65 82.71,107.54 82.71,109.31 v2(82.96,109.57) 82.96,110.31 R6901.2 83.66,110.46 C6901.1 85.44,109.63 86.02,109.06 U6901.24 ; R6909.2 89.63,112.36 R6911.2 v2(89.69,112.95) ; 100.05,99.66 RN6901.1 ; v2(93.25,112.95) R6915.2 R6913.2
  BOTTOM w0.254: v2(82.96,109.57) 85.12,111.73 88.47,111.73 v2(89.69,112.95) 90.41,112.24 92.54,112.24 v2(93.25,112.95) 93.83,112.36 94.39,112.36 94.77,112.74 v2(94.77,112.95)
3D3V_RUN_FFS: length 19.8
  TOP w0.114: 156.6,20.9 156.24,20.54 U7002.2 ; U7002.10 156.8,17.41 156.62,17.24 156.24,17.24 U7002.9
  TOP w0.305: 156.24,17.24 156.24,16.54 C7006.1
  TOP w0.508: C7006.1 v1(155.23,16.48) v2(154.59,16.48) ; R7011.2 156.47,23.08 154.97,23.08 154.59,22.7 R7020.1 ; R7011.2 156.6,22.9 C7007.1 156.6,20.9 ; R7011.2 v2(157.51,22.93)
  L3 w0.508: v2(157.51,22.93) 157.51,22.57 156.62,21.68 156.62,17.49 155.61,16.48 v2(154.59,16.48)
3D3V_S0: length 380
  TOP w0.305: PR5102.2 137.07,40.36 136.46,39.76 136.45,39.76 136.45,39.76 135.7,39.76 135.13,40.33 135.01,40.33 134.89,40.46 v2(134.86,40.46)
  TOP w0.356: 102.03,91.32 102.27,91.08 RN2602.2 ; v2(99.22,79.09) 98.83,79.09 98.25,79.67 R1902.1 98.04,79.6 97.66,79.21 R1607.1 ; RN2602.1 102.07,91.73 102.03,91.77 ; EC8910.1 120.84,97.03 RN1810.1 121.88,96.37 122.52,95.73 C1203.1 122.71,95.6 v2(123.22,96.11) 122.53,96.8 RN1810.2
  TOP w0.381: R2460.2 164.31,49.29 v2(164.95,49.29) ; v2(81.98,91.51) 80.77,90.29 R2046.1 80.32,90.33 R2044.1
  TOP w0.406: Q1801.2 Q1801.5 104.55,95.71 104.15,96.11 101.38,96.11 ; 99.54,93.76 99.85,94.07 99.85,95.8 100.16,96.11 101.38,96.11 ; 101.38,96.11 101.51,95.98 Q2601.5 Q2601.2 101.51,92.3 102.03,91.77 102.03,91.32
  TOP w0.508: v2(84.93,90.85) R2049.1 R2048.1 85.09,88.61 85.88,87.82 R2043.1 ; R2046.1 80.77,89.27 81.01,89.02 81.57,89.02 R2042.1 ; R1829.1 R2006.1 90.49,82.33 90.53,82.37 90.75,82.37 R1833.1 92.25,82.58 93.12,83.45 v2(93.12,84.93) ; R7004.1 163.23,15.65 162.65,15.08 161.77,15.08 161.13,15.72 159.8,15.72 v2(159.04,16.48) ; R1818.2 95.13,93.81 R1830.1 R1817.1 R1832.1 R1831.1 R1820.1 99.47,93.82 100.17,93.12 R1821.1 100.17,89.57 100.36,89.38 v2(100.49,89.38) ; v3(103.92,27.78) 103.16,27.02 97.31,27.02 94.18,30.15 94.18,33.96 91.73,36.42 86.77,36.42 85,34.64 78.14,34.64 77.31,35.46 R2609.1 76.23,35.34 R2604.1 68.57,35.34 68.36,35.55 ; R2429.2 137.85,76.38 137.85,76.61 137.95,76.71 137.95,80.61 138.59,81.25 v2(140.24,81.25) ; EC8910.1 120.75,97.74 120.3,98.18 v2(120.3,99.15) ; R7011.1 v2(157.51,24.25) ; R5420.1 16.76,84.61 16.99,84.84 C5701.2 16.99,85.4 v3(17.69,86.1) ; R7018.1 v2(153.32,16.48) ; v2(158.15,59.15) 157.83,58.83 R2430.2 ; R2456.2 164.33,41.54 164.52,41.36 v2(164.52,41.14) ; R405.1 102.68,80.32 102.47,80.11 101.78,80.11 v2(101.62,80.27) ; R6901.1 v2(81.02,110.46)
  L3 w0.508: v2(113.27,30.65) 113.27,30.91 114.04,31.69 122.31,31.69 124.57,33.96 126.95,33.96 127.21,33.7 128.41,33.7 130.18,35.48 130.82,35.48 131.58,36.23 131.58,38.82 131.5,38.9 131.5,39.72 132.11,40.33 134.73,40.33 v2(134.86,40.46) ; 154.59,22.45 154.59,17.75 v2(153.32,16.48) 153.95,15.84 158.4,15.84 v2(159.04,16.48) ; 154.59,22.45 156.39,24.25 v2(157.51,24.25) 157.93,24.67 157.93,27.35 159.19,28.61 160.71,28.61 161.78,29.67 163.79,29.67 164.25,30.14 164.25,36.35 162.78,37.83 162.78,39.4 v2(164.52,41.14) 163.67,41.98 163.67,48.67 164.29,49.29 v2(164.95,49.29) ; 154.59,22.45 154.18,22.85 151.37,22.85 150.59,23.63 v2(150.59,24.4)
  L3 w0.762: v3(19.97,74.14) 19.97,83.64 18.45,85.16 18.45,85.41 17.76,86.1 v3(17.69,86.1)
  L4 w0.508: v2(52.63,88.53) 52.36,88.81 51.59,88.81 50.12,90.28 48.58,90.28 48.07,90.79 48.07,91.53 48.52,91.98 48.52,92.48 v2(48.53,92.95) ; v2(99.22,79.09) 100.35,80.22 101.58,80.22 v2(101.62,80.27) ; v2(100.49,89.38) 99.63,90.24 97.54,90.24 97.11,90.67 96.12,90.67 95.22,89.78 95.22,85.89 94.27,84.93 v2(93.12,84.93) 93.12,85.92 90.18,88.87 v2(90.08,88.87) ; v2(113.27,30.65) 112.38,30.65 110.55,28.82 107.31,28.82 106.27,27.78 v3(103.92,27.78)
  L6 w0.508: v2(48.53,92.95) 48.52,93.16 47.94,93.74 42.66,93.74 41.18,95.22 ; 153.7,66.52 154.85,66.52 158.78,62.58 158.78,60.42 158.15,59.78 v2(158.15,59.15) 158.4,58.9 161.32,58.9 163.85,56.37 163.85,49.97 164.52,49.29 v2(164.95,49.29)
  L6 w0.762: v3(33.46,93.24) 32.39,92.17 22.83,92.17 17.69,87.02 v3(17.69,86.1)
  BOTTOM w0.203: U5701.37 16.38,83.86 16.68,84.16 R5413.1 ; 18.12,77.44 17.86,77.69 U5701.11
  BOTTOM w0.305: R5411.1 15.25,74.58 R5415.1 R5417.1 17.05,73.88 17.58,73.35 18.42,73.35 18.83,73.75 R5419.1
  BOTTOM w0.33: v2(123.22,96.11) 123.18,96.15 DIMM1.199
  BOTTOM w0.381: v2(93.12,84.93) 97.06,84.93 98.3,83.69 98.3,82.11 98.83,81.58 98.83,80.73 98.77,80.68 98.77,79.53 v2(99.22,79.09) ; v2(72.8,89.76) 72.8,90.26 72.1,90.96 R1608.1 71.79,91.15 71.16,90.53 R1606.1 71.09,88.66 71.09,88.3 70.64,87.85 69.08,87.85 EC8909.1
  BOTTOM w0.406: EC8909.1 69.07,88.18 69.23,88.34 69.23,88.44 R1503.1
  BOTTOM w0.508: v2(31.91,26.64) 32.67,27.4 32.67,28.38 33.56,29.27 33.56,34.89 35.04,36.37 37.45,36.37 v3(38.13,37.05) 38.13,37.51 38.26,37.63 PR4614.1 ; v2(112.3,109.31) 112.05,109.31 110.9,108.17 110.9,105.5 115.09,101.31 118.28,101.31 120.3,99.29 v2(120.3,99.15) ; v2(52.63,88.53) 53.08,88.98 R4005.1 ; R5419.1 19.53,74.58 v3(19.97,74.14) ; R5413.1 16.68,85.1 v3(17.69,86.1) ; v2(150.59,24.4) 150.59,25.5 150.84,25.75 R2489.2 150.98,26.27 150.98,27.44 Q2414.G
  BOTTOM w0.559: v3(19.97,74.14) 20.33,74.49 20.33,75.92 19.96,76.29 C5703.2 19.03,76.52 18.12,77.44
  vias: v1(32.59,26.69) v1(35.67,93.57) v1(50.71,102.33) v1(63,36.19) v1(78.54,100.93) v1(152.36,65.4) v2(38.16,93.35) v3(27.59,62.71) v3(33.46,94.13) v3(34.35,94.13) v3(34.35,93.24) v3(63.15,35.27) v3(77.75,101.39) v3(98.71,112.74) v3(99.6,112.74) v3(151.06,66.55) v3(151.61,65.89)
3D3V_S5: length 415.3
  TOP w0.381: R9909.1 108.74,28.53 108.06,27.84 v2(108.06,27.5) ; 88.78,90.65 90.85,90.65 92.02,89.47 92.02,87.84 91.61,87.45 R1711.1 90.53,87.45 v2(90.3,87.22)
  TOP w0.406: U1701.5 65.96,40.32 65.54,39.9 C1702.1
  TOP w0.508: v2(12.22,71.21) 13.14,71.21 14.13,70.23 ; v3(143.69,73.35) 143.53,73.18 R2433.2 ; R5721.1 16.03,66.64 14.13,68.55 14.13,70.23 ; v2(164.37,45.18) 164.15,44.96 R2434.1 ; 38.51,102.05 39.59,100.97 PR4305.1 41.74,101.24 v3(42.2,101.69) ; R2461.1 127.48,30.13 v2(127.85,30.51) ; v2(97.51,73.9) 97.34,73.73 R1724.1 ; PR5110.1 134.14,43.15 133.99,43 133.99,39.44 134.67,38.75 135.8,38.75 v2(135.97,38.93) ; 14.13,70.23 14.43,70.53 15.8,70.53 R7001.2 ; R1709.1 R2484.2 164.21,38.19 164.51,38.5 v2(164.51,38.63) ; R9929.1 118.02,30.26 v2(118.02,27.78) ; v2(152.43,58.77) 153.13,58.77 R2409.2 ; v2(62.1,38.3) 62.28,38.12 63.14,38.12 64.16,39.15 C1702.1 ; R2499.2 v2(164.87,50.03)
  L3 w0.508: v2(13.2,90.22) 13.2,89 11.82,87.62 11.82,85.43 11.21,84.82 11.21,80.1 12.61,78.71 12.61,77.96 11.77,77.12 11.77,72.69 12.22,72.23 v2(12.22,71.21) ; v2(62.1,38.3) 61.16,37.36 57.4,37.36 55.52,35.48 43.64,35.48 42.93,34.77 36.42,34.77 30.64,40.55 30.64,40.61 ; v3(102.65,27.78) 103.41,27.02 106.08,27.02 106.25,26.84 107.4,26.84 v2(108.06,27.5) 108.16,27.4 117,27.4 117.38,27.78 v2(118.02,27.78) 119.4,29.17 121.15,29.17 121.63,28.68 126.03,28.68 v2(127.85,30.51) 127.92,30.57 127.92,31.47 130.86,34.41 v2(131.99,34.41) ; v2(138.98,41.45) 138.5,41.45 v2(135.97,38.93)
  L4 w0.152: v2(90.3,87.22) 90.31,87.21 90.31,86.01 90.21,85.91 88.47,84.17 88.47,82.87 86.75,81.15 86.63,81.15 86.36,80.89 86.36,80.43 86.56,80.23 89.13,80.23 89.35,80.45 89.83,80.45 91.14,79.14 91.14,77.75 92.29,76.6 92.29,73.78 92.85,73.23 94.62,73.23 95.15,73.75 97.36,73.75 v2(97.51,73.9)
  L4 w0.508: v2(62.14,75.15) 60.99,76.29 60.99,82.14 60.22,82.92 60.22,84.94 57.44,87.72 55.68,87.72 54.01,89.39 53.37,89.39 51.62,91.14 51.62,91.14 51.26,91.5 49.15,91.5 v2(48.72,91.07) ; v2(164.37,45.18) 163.86,44.67 163.86,39.61 164.51,38.97 v2(164.51,38.63) ; v2(13.2,90.22) 13.2,92.13 13.75,92.68 13.76,92.68 14.13,93.05 14.13,93.06 14.64,93.57 16.67,93.57 17.43,94.33 18.35,94.33 21.12,97.1 21.84,97.1 25.03,97.1 26.88,98.95 32.04,98.95 ; v2(152.43,58.77) 152.43,58.63 153.3,57.76 153.3,55.8 154.65,54.45 154.65,51.79 155.95,50.49 157.75,50.49 v2(158.86,49.38) ; v2(135.97,38.93) 136.15,39.11 138.16,39.11 139.07,38.19 v2(143.33,38.19) ; v2(140.71,52.26) 140.71,52.15 140.33,51.77 140.33,49.26 141.31,48.28 141.31,42.94 139.82,41.45 v2(138.98,41.45)
  L6 w0.508: v3(34.58,87.6) 37.74,87.6 38.18,87.17 40.32,87.17 42.64,89.48 47.13,89.48 v2(48.72,91.07)
  BOTTOM w0.305: 135.84,36.71 135.09,35.96 134.39,35.96 134.37,35.93 134.15,35.93 133.9,35.68 132.94,35.68 R2488.2 ; 62.91,74.9 62.39,74.9 v2(62.14,75.15) ; 62.91,74.9 62.91,75.84 R4026.1 ; 62.91,74.9 U4005.5 63.91,73.95 C4014.1 ; PR5118.2 136.29,83.74 139.17,83.74 139.48,84.04
  BOTTOM w0.508: 36.89,2.91 40.85,2.91 42.7,4.77 PR4424.1 ; 36.89,2.91 36.89,2.42 36.21,1.75 33.55,1.75 33.14,2.16 PR5302.1 ; 36.89,2.91 36.75,2.91 35.53,4.14 35.53,4.2 PC5303.1 ; v2(131.99,34.41) 131.99,34.73 R2488.2 ; R2607.1 101.89,28.54 v3(102.65,27.78) ; v2(48.72,91.07) 48.7,91.05 47.7,91.05 47.31,90.67 47.23,90.67 47.13,90.57 45.63,90.57 ; PU5302.1 14.89,70.65 PC5308.1 13.91,71.02 13.72,71.21 v2(12.22,71.21) 12.22,71.98 11.91,72.29 C7002.1 7.84,72.29 6.89,73.25 5.9,73.25 LIDSW1.2 ; 45.63,90.57 45.5,90.7 R4031.1 ; 45.63,90.57 PR5212.1 ; PR4519.1 33.05,62.07 31.26,60.28 31.26,60.27 30.66,59.66 26.83,59.66 v2(26.7,59.53) ; v2(140.71,52.26) 140.34,51.89 140.34,49.33 140.98,48.69 R2498.2 ; v3(144.3,72.74) 147.73,72.74 157.13,63.34 161.33,63.34 164.88,59.79 164.88,50.03 v2(164.87,50.03) 164.54,50.03 163.1,48.59 163.1,46.1 164.02,45.18 v2(164.37,45.18) 163.69,44.5 162.36,44.5 160.89,45.97 160.89,47.34 v2(158.86,49.38) 158.02,49.38 156.98,48.33 150.75,48.33 149.05,46.64 149.05,44.33 149.05,43.8 149.05,43.8 149.05,43.08 149.05,43.08 149.05,41.92 149.05,41.92 149.05,41.27 149.03,41.25 149.03,41.23 148.4,40.61 146.69,40.61 145.24,39.16 145.24,38.51 144.35,37.62 Q2412.G 143.9,37.62 v2(143.33,38.19) ; v2(135.97,38.93) 135.97,38.86 135.84,38.72 Q2413.G 135.84,36.71
  vias: v1(33.05,82.95) v1(36.35,88.23) v3(29.75,41.37) v3(30.64,41.37) v3(33.69,89.38) v3(33.69,87.6) v3(33.69,86.71) v3(33.69,7.59) v3(33.69,6.7) v3(34.58,89.38) v3(34.58,88.49) v3(34.58,7.59) v3(35.59,83.53) v3(35.59,82.52) v3(36.61,83.53) v3(36.61,82.52) v3(38.13,94.46) v3(39.02,94.46) v3(39.91,94.46) v3(73.55,112.53) v3(73.57,104.74) v3(74.45,112.49) v3(110.14,113) v3(111.03,113) v3(142.67,65.7) v3(142.65,64.86)
3D3V_S5_KBC: length 493.3
  TOP w0.203: KBC24.5 161.42,42.87 v2(161.62,42.67) ; KBC24.43 154.76,56.38 ; v2(161.75,48.41) 161.69,48.47 KBC24.19 ; 143.54,47.21 143.89,46.87 KBC24.82 ; 161.7,50.01 161.36,49.67 KBC24.22 ; KBC24.115 153.56,38.41 ; 147,38.45 148.28,38.45 148.76,38.93 KBC24.103
  TOP w0.254: v2(123.22,22.29) 122.88,22.64 R2478.2
  TOP w0.305: C2411.1 156.55,57.73 155.91,57.09 v2(155.91,56.76) ; RN2603.2 143.06,66.44 v2(142.71,66.44) 142.71,67.34 142.85,67.48 RN2603.1 ; R2442.1 135.93,25.52 R2453.1 136.04,25.48 136.67,24.85 136.69,24.77 136.7,24.73 136.71,24.69 v2(136.71,24.2) ; R2420.1 128.56,24.77 R2403.1 128.61,25.46 128.61,25.48 128.38,25.7 127.71,25.7 127.29,25.27 127.29,24.04 127.07,23.83 v2(127.07,22.62)
  TOP w0.356: RN2402.1 139.68,32.66 139.34,32.66 139.03,32.34 RN2402.2
  TOP w0.508: 147,38.45 146.44,38.45 145.51,37.52 v2(145.51,36.88) 145.5,36.87 145.08,36.87 C2420.1 C2413.1 143.22,36.35 142.78,35.91 142.78,34.84 v2(142.6,34.66) 142.51,34.58 R2415.2 141.28,34.58 140.06,33.36 140.06,33.04 139.68,32.66 ; v2(78.77,35.27) 78.58,35.27 R2608.1 ; R2441.1 131.22,25.05 R2439.1 131.69,24.29 v2(131.88,24.48) ; 143.54,47.21 143.54,48.47 C2410.1 143.1,49.37 v2(142.78,49.69) 142.78,50.07 R2495.2 ; R2455.2 R2424.2 163.48,53.03 v2(163.1,52.65) ; v2(161.75,48.41) 161.84,48.32 161.84,48.3 162.17,47.98 162.18,47.98 162.64,47.52 C2412.1 ; 154.76,56.38 154.76,56.61 155.14,56.99 155.68,56.99 v2(155.91,56.76) ; 161.7,50.01 161.83,50.13 161.83,50.41 v2(162.31,50.88) 162.31,50.88 C2429.1 ; v2(152.43,57.12) 152.24,57.31 R2462.2 ; R2443.1 148.52,34.17 v2(149.05,34.17) ; C2414.1 161.91,42.38 v2(161.62,42.67) ; v2(139.07,23.54) R2438.1 138.04,23.44 R2425.1 ; R2480.2 118.65,21.67 R2414.2 v2(116.36,21.67) ; R2427.2 162.43,39.86 161.8,40.49 v2(161.42,40.49)
  L3 w0.508: v2(156.24,27.27) 156.96,27.27 158.92,29.24 160.45,29.24 161.33,30.12 161.33,31.4 162.74,32.81 162.74,33.45 162.07,34.12 162.07,40.09 161.68,40.49 v2(161.42,40.49) ; v2(161.75,48.41) 162.59,47.57 162.59,43.63 v2(161.62,42.67)
  L4 w0.508: v2(149.05,34.17) 149.27,34.17 149.81,34.71 149.81,35.46 151.35,37 154.01,37 155.71,35.3 v2(156.04,35.3) ; v2(78.26,22.19) 79.48,23.41 82.64,23.41 84.65,21.41 92.69,21.41 v2(93.86,22.57) 93.89,22.55 93.89,22.51 95.15,21.25 99.41,21.25 99.81,20.85 115.54,20.85 v2(116.36,21.67) 116.58,21.46 119.35,21.46 119.38,21.48 119.98,21.48 120.01,21.46 122.38,21.46 v2(123.22,22.29) 123.22,22.3 123.62,22.7 126.99,22.7 v2(127.07,22.62) 127.65,23.21 130.61,23.21 v2(131.88,24.48) 136.43,24.48 v2(136.71,24.2) 137.37,23.54 v2(139.07,23.54) 140.16,23.54 140.99,24.37 149.66,24.37 150.4,25.11 150.4,25.29 150.99,25.88 151.59,25.88 151.73,25.75 154,25.75 155.45,27.19 156.16,27.19 v2(156.24,27.27) ; v2(161.62,42.67) 161.48,42.52 160.66,42.52 158.36,40.23 149.96,40.23 149.51,39.78 149.1,39.78 147.55,39.78 145.52,37.75 145.52,36.9 v2(145.51,36.88) ; v2(41.28,4.79) 39.58,3.09 32.85,3.09 27.85,8.1 27.85,15.46 30.13,17.75 30.13,20.17 30.83,20.87 30.83,23.22 30.13,23.92 30.13,29.07 26.7,32.49 26.7,34.01 21.33,39.39 18.9,39.39 17.35,40.93 17.35,43.85 17.05,44.15 17.05,45.56 16.03,46.58 16.03,57.47 16.44,57.87 16.44,63.82 15.22,65.05 15.22,66.95 14.71,67.46 14.71,70.77 14.13,71.35 14.13,72.03 13.52,72.64 13.52,74.26 12.63,75.15 12.63,76.82 13.52,77.71 13.52,79.06 12.73,79.85 12.73,87.94 18.26,93.47 18.71,93.47 21.48,96.23 25.55,96.23 26.18,96.87 29.07,96.87 32.04,93.91 32.04,93.62 33.15,92.5 34.65,92.5 34.87,92.72 40.05,92.72 42.42,95.09 43.73,95.09 44.33,94.48 49.41,94.48 50.86,93.03 52.86,93.03 v2(52.95,92.94) ; v2(145.27,54.15) 146.97,55.85 151.16,55.85 v2(152.43,57.12) ; v2(142.71,66.44) 142.97,66.44 143.42,66 143.42,61.44 v2(142.65,60.67)
  L6 w0.508: v2(78.26,22.19) 77.5,22.95 72.87,22.95 68.17,18.26 48.8,18.26 44.48,13.94 44.48,7.99 v2(41.28,4.79) ; v2(142.78,49.69) 142.78,50.07 144.56,51.84 144.56,53.22 145.27,53.93 v2(145.27,54.15) ; v2(149.05,34.17) 147.77,34.17 147.1,33.5 143.29,33.5 142.6,34.18 v2(142.6,34.66) ; v2(163.1,52.65) 163.1,54.45 v2(160.43,57.12) 160.18,56.86 158.86,56.86 157.64,55.64 153.91,55.64 v2(152.43,57.12) ; v2(93.2,24.05) 93.2,24.05 92.54,23.39 89.25,23.39 88.49,24.15 87.49,24.15 83.48,28.16 81.18,28.16 79.97,29.37 79.97,31.67 78.65,32.99 78.65,35.15 v2(78.77,35.27)
  BOTTOM w0.508: D4303.2 89.95,26.64 90.46,26.13 93.5,26.13 ; D4301.2 95.82,26.13 93.5,26.13 ; D4302.2 93.5,26.13 ; 93.5,26.13 93.5,24.35 v2(93.2,24.05) 93.2,23.23 v2(93.86,22.57) ; v2(161.75,48.41) 161.75,50.33 v2(162.31,50.88) 163.23,51.8 163.23,52.52 v2(163.1,52.65) ; PR4414.1 PR4432.1 40.3,4.62 41.1,4.62 v2(41.28,4.79) ; v2(160.43,57.12) 159.72,57.83 156.98,57.83 v2(155.91,56.76) ; R4032.1 51.41,92.55 52.19,92.55 52.58,92.94 v2(52.95,92.94)
  vias: v1(143.44,59.53)
3D3V_S5_PCH: length 154.6
  TOP w0.254: 78.39,87.85 RN1807.2 ; 78.39,87.85 79.04,87.85 RN1807.1 ; 78.39,87.85 77.89,87.85 ; v2(100.11,87.09) 100.11,86.39 R1814.1 99.38,85.67 98.24,85.67 R2039.1 ; v2(85.12,86.96) 84.93,87.15 R2041.1 ; RN1807.4 77.24,87.49 77.62,87.87 77.87,87.87 77.89,87.85 ; 77.89,87.85 RN1807.3 ; v2(93.25,90.77) 92.59,90.11 92.59,87.48 91.73,86.62 91.73,85.63 R2007.1 91.92,85.44 93.11,85.44 R1824.1
  TOP w0.381: 79.04,87.85 79.04,88.63 79.34,88.93 79.34,91.22
  TOP w0.406: 143.54,70.17 v2(142.37,70.17) ; 143.54,70.17 Q2604.5 ; 143.54,70.17 Q2604.2
  TOP w0.508: R2040.1 79.1,97.14 v3(79.1,98.06) ; R2501.2 115.86,108.3 ; v2(109.53,91.76) 109.53,88.51 108.36,87.34 108.35,87.34 107.98,86.97 107.98,86.96 105.9,84.88 104.16,84.88 R404.1 ; R1835.1 118.97,106.33 118.02,107.28 118.02,108.43
  L3 w0.305: v2(103.28,87.72) 103.79,87.22 105.82,87.22 109.53,90.93 v2(109.53,91.76)
  L4 w0.254: v3(79.1,98.06) 79.1,97.76 78.24,96.89 76.41,96.89 75.93,97.38 73.35,97.38 72.5,96.53 69.86,96.53 68.04,94.72 66.67,94.72 66.45,94.5 63.75,94.5 62.47,93.21 62.47,92.25 63.74,90.98 63.74,88.93 64.37,88.29 64.37,86.37 63.74,85.73 63.74,80.23 64.58,79.38 64.58,78.66 64.05,78.12 63.79,78.12 v2(63.76,78.1)
  L4 w0.305: v2(100.11,87.09) 102.65,87.09 v2(103.28,87.72)
  L4 w0.508: v2(142.37,70.17) 142.3,70.1 139.57,70.1 138.59,71.08 138.59,74.14 136.13,76.6 136.13,81.3 135.16,82.26 135.16,87.72 135.19,87.74 135.19,88.27 134.75,88.71 134.44,88.71 v2(134.28,88.87)
  BOTTOM w0.381: v2(134.28,88.87) 133.65,88.24 133.65,86.81 134.11,86.34 R1834.1
  BOTTOM w0.508: v2(100.11,87.09) 100.11,88.03 99.85,88.29 99.85,89.39 98.21,91.03 93.5,91.03 v2(93.25,90.77) 93.14,90.89 92.6,90.89 91.98,90.26 90.18,90.26 90.17,90.25 89.18,90.25 v2(88.44,89.5) 88,89.94 85.68,89.94 85.12,89.38 ; v2(134.28,88.87) 134.28,91.16 135.54,92.42 137.52,92.42 139.04,93.95 ; 139.04,93.95 140.09,92.9 140.09,87.51 R2502.2 ; 139.04,93.95 139.04,94.78 140.24,95.98 140.24,98.9 v2(139.99,99.15)
  vias: v1(79.09,104.09) v3(79.22,92.07) v3(80.04,104.11)
3D3V_SEN_S0:
  vias: v1(30.16,92.63)
3D3V_SPIVCC1:
  vias: v1(130.05,106.19) v3(130.65,105.63)
3D3V_SPIVCC2:
  vias: v1(139,98.19) v3(139.1,99.03)
81208_AGND: length 18.6
  TOP w0.381: PC4630.2 31.08,51.21 30.57,51.73 30.57,52.36 30,52.93 v1(30,53.61) 30,54.02 30.31,54.32 PG4601.1 30.31,55.77 31.05,56.51 v2(31.05,57.19)
  TOP w0.508: PR4613.2 35.97,45.37 PR4672.1 PR4602.2 37.09,44.61 37.62,45.14 37.62,46.07 36.61,47.08
  BOTTOM w0.508: PR4664.2 31.08,56.53 31.08,56.95 31.05,56.98 v2(31.05,57.19) 31.69,57.19 PR4659.2 PR4662.2 33.06,56.95 33.65,57.54 PR4658.2 34.08,57.54 34.53,57.1 34.53,57.03 PR4660.2 34.8,56.9 35.01,56.69 35.09,56.69 35.38,56.39 PR4663.2
  vias: v2(32.29,49.75) v2(33.18,49.75) v2(34.2,51.66) v2(34.2,50.64) v2(34.2,49.75) v2(34.2,48.74) v2(34.2,47.85) v2(35.21,49.75)
+DC_IN: length 4.1
  BOTTOM w0.508: 38.89,31.21 39.81,30.3 41.05,30.3 PC4302.1 PR4308.1
  vias: v1(19.21,62.83) v1(19.46,46.6) v1(20.53,78.94) v1(20.91,87.06) v1(34.44,33.14) v1(35.74,35.25) v3(19.41,86.33) v3(19.41,85.44) v3(20.25,86.33) v3(20.25,85.44) v3(20.96,85.88) v3(34.83,31.08) v3(34.83,30.19) v3(35.72,31.08) v3(35.72,30.19) v3(36.61,31.08) v3(36.61,30.19)
+RTC_VCC: length 8.3
  TOP w0.305: v1(139.38,61.99) 140.05,62.67 R2504.1
  TOP w0.508: Q2505.G 140.26,64.42 140.93,63.75 140.93,63.29 140.87,63.23 v2(140.87,63.15) 140.38,62.67 R2504.1
  BOTTOM w0.305: IOBD1.36 142.98,62.25 142.78,62.45
  BOTTOM w0.508: v2(140.87,63.15) 140.98,63.26 141,63.26 141.65,63.92 D2501.2 141.73,63.92 142.27,63.37 142.27,62.96 142.78,62.45
+SDC_IN: length 18.7
  TOP w0.508: PR4435.1 41.24,23.07 v2(41.44,23.27)
  L4 w0.508: v2(41.44,23.27) 41.38,23.34 35.84,23.34 35.21,22.71 35.21,21.82 36.13,20.91 36.13,15.23 34.32,13.43 v2(34.32,13.3)
  BOTTOM w0.508: v2(34.32,13.3) 34.45,13.3 34.83,13.68 PR4439.1
  vias: v1(40.67,25.49)
+V_VREF_PATH1: length 2.2
  TOP w0.508: R4211.1 120.54,35.59 120.2,35.25 v1(120.2,35.12) 120.2,35.09 120.81,34.48 C4202.2
+V_VREF_PATH3: length 2
  BOTTOM w0.508: C4201.2 138.34,65.56 138.34,66.31 v1(138.36,66.34) 138.36,66.88 R4207.1
+VCHGR:
  vias: v1(79.51,25.77) v3(79.53,22.07) v3(79.53,21.18) v3(80.55,22.07) v3(80.55,21.18) v3(81.57,22.07) v3(81.57,21.18)
A5_TP: length 5.8
  BOTTOM w0.102: TP2309.1 66.33,85.62 66.96,84.98 66.96,83.66 68.36,82.26 68.87,82.26 CPU1.A5
A67_TP: length 9.4
  BOTTOM w0.102: CPU1.A67 68.9,45.6 68.63,45.32 68.63,45.13 68.38,44.89 68.35,44.89 68.07,44.6 68.07,42.77 67.68,42.38 67.63,42.38 66.83,41.58 66.83,41.49 66.19,40.85 66.19,39.71 66.19,39.7 66.19,39.28 66.19,38.66 66.2,38.65 66.2,38.19 TP2311.1
A70_TP: length 7.4
  BOTTOM w0.102: TP2310.1 67.78,38.07 67.96,37.89 68.45,37.89 68.92,38.35 68.92,40.12 69.12,40.33 69.12,41.24 69.21,41.33 69.21,42.94 69.59,43.32 CPU1.A70
AC_PRESENT: length 160.6
  TOP w0.102: D2404.A 163.49,34.89 162.77,35.62 162.77,36.15 EC1707.1 R1709.2 162.55,37.79 162.55,38.14 161.87,38.82 161.09,38.82 158.11,41.8 158.11,42.04 157.3,42.85 157.07,42.85 156.34,43.58 154.37,43.58 v2(153.85,44.1)
  L3 w0.102: v2(153.85,44.1) 153.35,43.61 153.35,43.36 153.04,43.05 152.9,43.05 152.49,42.65 152.49,39.88 150.62,38.01 v2(150.62,37.81) ; v2(146.06,40.9) 146.2,41.05 146.2,42.54 146.67,43.01 146.67,44.09 146.54,44.21 146.54,48.86 146.56,48.88 146.56,52.82 146.17,53.21 146.17,55.93 144.67,57.44 141.44,57.44 140.97,56.97 140.4,56.97 139.56,57.8 138.52,57.8 138.32,57.6 131.43,57.6 130.51,58.52 130.51,83.48 131.65,84.62 131.65,84.98 130.89,85.74 130.89,87.25 131.06,87.42 131.06,94.58 127.83,97.81 127.32,97.81 127.22,97.71 124.71,97.71 124.2,98.22 121.31,98.22 121.05,97.95 115.77,97.95 110.32,92.49 108.98,92.49 105.34,88.85 103.36,88.85 101.3,86.79 101.3,84.5 100.97,84.17 100.08,84.17 100.06,84.14 98.84,84.14 97.47,82.77 97.47,77.36 96.7,76.59 94.73,76.59 94.61,76.47 94.43,76.47 v2(93.52,75.56)
  L4 w0.102: v2(146.06,40.9) 146.1,40.86 148.56,40.86 149,41.3 149,42.26 150.13,43.39 153.14,43.39 v2(153.85,44.1)
  BOTTOM w0.089: v2(93.52,75.56) 93.13,75.94 92.37,75.94 91.98,76.09 91.81,76.09 91.71,76.07 91.54,75.89 91.54,75.67 91.08,75.21 CPU1.AY15
  BOTTOM w0.102: v2(150.62,37.81) 150.62,37.69 Q1702.3 ; v1(154.07,44.82) 153.85,44.6 v2(153.85,44.1)
ACAV_IN: length 4.8
  TOP w0.254: R2469.2 161.92,37.66 161.92,38.24 161.91,38.25 v1(161.91,38.27) 161.91,38.3 161.71,38.49 160.31,38.49 159.09,39.72 KBC24.128
ACOK_IN: length 20.6
  TOP w0.254: PQ4407.2 36.56,25.83 36.23,25.49 36.23,24.83 34.7,23.31 34.7,20.21 v1(31.25,16.76) 29.88,15.39 v2(29.88,14.57)
  BOTTOM w0.254: PR4475.1 33.43,12.79 31.66,14.57 v2(29.88,14.57)
AD+: length 23.5
  TOP w0.508: PR4444.1 36.35,9.49 37.5,10.64 v2(37.88,10.64) ; PR4418.1 37.23,19.86 v1(36.2,19.86) 35.97,20.08 v2(35.97,22.32)
  L4 w0.508: v2(35.97,22.32) 36.89,21.41 36.89,14.85 35.85,13.81 35.85,12.09 37.3,10.64 v2(37.88,10.64)
  BOTTOM w0.406: PC4306.1 34.27,24.35 PD4406.A
AD+_G_1: length 4.6
  TOP w0.102: PQ4407.6 40.07,26.48 40.42,26.13 40.42,26.02 ; 40.42,26.02 40.22,25.83 PQ4407.5 ; 40.42,26.02 v1(40.42,25.32) PR4423.1
AD+_G_2: length 3.5
  TOP w0.254: PR4423.2 40.35,23.46 PR4435.2 40.35,21.95 v1(40.02,21.61) 40.01,21.6 v2(40.01,20.92)
  BOTTOM w0.254: PU4405.4 40.01,21.51 v2(40.01,20.92)
AD_IA: length 133.7
  TOP w0.102: v2(139.61,25.49) 139.71,25.49 141.6,27.38 141.6,30.22 141.83,30.45 v1(141.83,31.86) 141.83,32.31 141.18,32.96 141.18,33.54 141.5,33.86 143.16,33.86 143.49,33.53 144.17,33.53 145.32,34.69 145.32,35.08 R2421.1
  L3 w0.102: v2(139.61,25.49) 140.11,24.99 140.11,21.76 135.59,17.24 117.14,17.24 115.08,19.3 115.08,19.41 114.79,19.7 106.81,19.7 105.66,20.85 94.66,20.85 93.06,22.45 85.22,22.45 83.67,24 74.31,24 67.4,17.09 58.39,17.09 57.38,18.1 55.73,18.1 55.63,18.21 47.8,18.21 42.91,13.31 42.91,11.24 42.5,10.84 40.9,10.84 39.43,9.37 v2(39.4,9.37)
  BOTTOM w0.102: v2(39.4,9.37) 39.53,9.49 PR4472.1
ALERT#: length 4.8
  TOP w0.102: R2603.2 66.38,39.29 67.06,39.97 v1(67.15,39.97) 67.16,39.97 69.12,39.97 69.83,40.68 THM261.6
ALL_SYS_PWRGD: length 240.9
  TOP w0.102: v2(60.53,41.75) 60.53,42.31 60.8,42.58 EC1709.1 61.55,42.58 61.91,42.22 R1716.1 62.92,42.22 63.45,41.69 64.36,41.69 64.38,41.66 64.94,41.66 65.31,42.04 U1701.2 ; v2(49.75,87.99) 49.58,88.16 v1(40.34,88.16) 39.57,88.93 v2(38.93,88.93) ; R2481.1 154.91,58.83 v2(154.92,58.85)
  L3 w0.102: v2(139.15,27.02) 139.94,27.81 140.84,27.81 140.86,27.83 151.3,27.83 152.22,28.75 153.85,28.75 154.82,29.72 154.82,32.15 153.87,33.11 152.1,33.11 151.03,34.18 151.03,35.69 152.48,37.14 153.06,37.14 153.51,37.59 153.51,38.51 154.8,39.8 154.8,42.17 155.26,42.63 155.46,42.83 155.46,43.41 155.47,43.43 155.47,44.78 155.46,44.79 155.46,50.27 155.12,50.61 155.12,51.86 154.49,52.49 154.49,58.39 154.92,58.82 v2(154.92,58.85)
  L4 w0.102: v2(139.15,27.02) 138.09,27.02 135.9,29.2 133.76,29.2 132.11,27.55 124.43,27.55 124.12,27.86 122.54,27.86 120.81,26.13 119.29,26.13 118.09,24.94 117.09,24.94 115.95,23.79 111.59,23.79 111.46,23.66 109.07,23.66 108.4,22.99 106.3,22.99 105.32,23.97 99.89,23.97 99.35,24.52 94.83,24.52 93.06,24.52 92.77,24.23 92.77,23.66 92.14,23.03 85.48,23.03 82.39,26.12 72.91,26.12 70.01,29.03 70.01,31.33 69.29,32.06 69.29,32.06 66.36,34.99 65.89,34.99 63.47,37.41 63.47,38.53 60.53,41.47 v2(60.53,41.75) 60.96,42.18 60.96,43.92 60.66,44.22 60.66,46.14 62.15,47.64 62.15,54.99 60.94,56.2 60.94,56.27 60.81,56.4 60.81,57.16 60.81,59.43 64.88,63.5 64.88,71.42 66.78,73.32 67.29,73.32 67.4,73.42 67.75,73.42 68,73.68 68,74.08 67.62,74.47 61.96,74.47 60.46,75.96 60.46,82.07 59.79,82.74 59.79,84.77 57.77,86.78 56.01,86.78 54.13,88.66 53.38,88.66 52.81,88.1 49.86,88.1 v2(49.75,87.99)
  BOTTOM w0.102: v2(38.93,88.93) 38.3,89.57 U4004.4 ; v2(49.75,87.99) 50.04,88.28 51.83,88.28 52.19,88.64 R4005.2 52.19,90.02 R4002.1 52.18,90.03 51.93,90.28 R4011.2 51.78,91 51.07,91 50.15,90.07 48.08,90.07 D4002.1
ALS_INT#: length 109.6
  TOP w0.102: R6927.2 83.47,109.31 v2(83.73,109.57) ; R1902.2 96.5,79.67 v2(96.43,79.6)
  L3 w0.102: v2(96.43,79.6) 96.52,79.69 96.52,83.5 99.04,86.02 99.04,87.19 99.52,87.68 99.52,91.27 99.09,91.7 99.09,96.52 102.22,99.65 102.22,107.81 100.36,109.67 83.83,109.67 v2(83.73,109.57)
  L6 w0.102: v2(47.4,95.47) 48.09,94.79 61.85,94.79 63.08,96.01 66.66,96.01 66.92,96.27 73.21,96.27 73.3,96.18 82.02,96.18 83.29,97.45 83.29,107.87 83.73,108.3 v2(83.73,109.57)
  BOTTOM w0.089: 93.5,78.67 93.49,78.65 92.59,78.65 92.59,78.66 92.12,78.66 92.01,78.69 91.79,78.69 CPU1.BA9
  BOTTOM w0.102: v2(47.4,95.47) 47.55,95.32 LCD1.33 ; 93.5,78.67 93.54,78.71 94.39,78.71 94.54,78.85 96.64,78.85 v1(96.69,78.91) 96.69,79.33 v2(96.43,79.6)
ALS_INT#_HUB: length 2.7
  TOP w0.102: R6927.1 83.81,107.13 v1(84.39,107.13) 84.74,107.13 85.12,106.75 U6901.28
ALWON: length 27.5
  TOP w0.102: KBC24.121 155.96,38.94 156.45,38.45 156.47,38.45 156.67,38.25 156.92,38.25 v2(156.92,38.24) ; v1(138.39,37.94) v2(137.83,37.94)
  L4 w0.102: v2(156.92,38.24) 156.93,38.25 156.93,38.66 155.79,39.79 150.35,39.79 149.9,39.35 148.92,39.35 148.48,39.35 146.91,37.78 146.91,36.9 146.3,36.3 145.27,36.3 144.97,36.6 144.9,36.6 143.09,36.6 141.99,35.5 139.55,35.5 137.83,37.23 v2(137.83,37.94)
  BOTTOM w0.102: v2(137.83,37.94) 137.45,37.56 137.45,37.22 R4009.2
AUD_AGND: length 21.5
  TOP w0.203: v2(17.99,25.06) 18.04,25.11 HDA27.27
  TOP w0.508: v2(21.62,18.38) 21.88,18.64 C2729.1 ; EC8903.1 21.63,36.09 v2(20.99,36.09)
  L6 w0.635: HPMIC1.6 8.2,34.73 ; HPMIC1.MS 6.85,22.87
  BOTTOM w0.254: C2730.1 14.83,25.75 13.75,25.75 v2(13.49,25.49) ; EC2908.2 v2(16.29,30.45) ; v2(13.37,33.75) 12.48,34.64 9.24,34.64 HPMIC1.6
  BOTTOM w0.508: v2(20.99,36.72) 20.85,36.86 EC2703.1 19.4,36.86 v2(19.08,36.54) 18.76,36.86 EC2705.1 17.62,36.86 v2(17.43,36.67) ; v2(13.37,23.59) 14.07,24.29 EC2905.2 ; AFTP2908.1 13.88,28.03 v2(14.26,28.42)
  vias: v1(15.2,30.19) v1(15.48,32.58) v1(17.74,28.67) v1(20.05,22.19) v1(21.37,17.37) v2(1.56,23.21) v2(5.11,23.59) v2(8.92,23.59) v2(13.88,29.69) v2(14.38,33.75) v2(14.38,30.83) v2(18.57,29.3) v2(19.08,17.24) v2(19.51,21.3)
AUD_HP1_JACK_L: length 14
  TOP w0.203: 18.75,26.71 HDA27.23
  TOP w0.254: R2921.2 16.55,22.35 C2907.2 14.54,22.35 14.28,22.6 v2(14.28,22.93) ; 18.75,26.71 18.37,27.1 18.37,27.2 v1(17.74,27.83) 17.15,28.42 v2(16.92,28.42)
  L3 w0.254: v2(16.92,28.42) 16.22,28.42 14,26.2 14,23.21 v2(14.28,22.93)
  BOTTOM w0.254: v2(16.92,28.42) 16.61,28.42 R2908.1
AUD_HP1_JACK_L1: length 16.7
  L4 w0.254: v2(19.06,19.14) 18.17,19.14 16.67,20.64 16.67,21.94 14.26,24.35 14.26,26.76 v2(13.75,27.27)
  BOTTOM w0.254: v2(13.75,27.27) 14.57,27.27 R2908.2 15.34,28.86 15.4,28.92 v1(15.4,28.95) ; v2(19.06,19.14) 19.17,19.26 R2919.1 EC2907.1 20.76,18.51 R2907.1
AUD_HP1_JACK_R: length 21.1
  TOP w0.203: 18.52,26.31 HDA27.24
  TOP w0.254: v1(16.34,27.53) 16.59,27.78 v2(16.92,27.78) 17.45,27.25 17.58,27.25 18.52,26.31 ; C2908.2 18.5,19.81 v2(19.08,19.81)
  L3 w0.254: v2(19.08,19.81) 15.98,19.81 15.83,19.65 14.14,19.65 13.62,20.17 13.62,21.2 14.79,22.37 14.79,23.82 14.51,24.1 14.51,25.99 16.3,27.78 v2(16.92,27.78)
  BOTTOM w0.254: R2910.1 16.29,27.15 v2(16.92,27.78)
AUD_HP1_JACK_R1: length 13
  L3 w0.254: v2(14.38,32.73) 13.24,31.59 13.24,26.89 v2(13.57,26.56)
  BOTTOM w0.254: R2909.1 16.29,33.43 EC2908.1 R2920.1 15.4,33.02 15.1,33.31 v1(15.02,33.31) 14.72,33.31 14.38,32.98 v2(14.38,32.73) ; R2910.2 14.83,26.64 13.65,26.64 v2(13.57,26.56)
AUD_PC_BEEP: length 4
  TOP w0.203: HDA27.36 21.28,21.94
  TOP w0.254: 21.28,21.94 21.28,21.75 21.7,21.32 21.7,20.87 20.96,20.14 v1(20.96,20.03) 20.96,19.18 C2720.2
AUD_PC_BEEP_C: length 2.9
  TOP w0.254: C2720.1 20.83,18.17 20.83,17.39 v1(20.91,17.32) 21.51,17.32 R2717.1 R2721.2
AUD_PC_BEEP_R: length 20.8
  TOP w0.254: v2(25.94,17.75) 24.75,17.75 v1(24.11,17.11) 23.73,16.73 R2721.1
  L4 w0.254: v2(25.94,17.75) 26.7,17.75 27.03,18.07 27.03,21.02 v2(28.96,22.96)
  BOTTOM w0.254: v2(28.96,22.96) 29.62,23.62 29.62,32.16 D2701.3
AUD_PORTA_L_R_B: length 15.1
  TOP w0.254: v2(16.8,19.29) 16.14,19.29 v1(16.14,19.29)
  L4 w0.254: v2(16.8,19.29) 14.04,22.04 12.96,22.04 HPMIC1.1
  BOTTOM w0.254: HPMIC1.1 12.02,24.05 AFTP2906.1 ; v2(16.8,19.29) ED2902.2 17.52,19.3 18.17,19.3 19.06,18.41 R2907.2
AUD_PORTA_R_R_B: length 13.5
  BOTTOM w0.254: HPMIC1.2 7,35.15 AFTP2907.1 14.26,35.15 15.38,36.27 ED2901.2 16.42,34.93 R2909.2
AUD_SENSE_A: length 18.3
  TOP w0.203: v2(21.11,21.18) 20.88,21.41 HDA27.35
  L4 w0.254: v2(21.11,21.18) 19.46,22.83 19.46,27.4 19.98,27.91 19.98,28.66 18.7,29.94 18.7,30.82 v2(16.97,32.54)
  BOTTOM w0.254: R2924.2 17.56,33.87 18.35,33.87 v1(18.42,33.8) 18.45,33.78 18.45,33.29 17.7,32.54 R2916.2 v2(16.97,32.54)
AUD_SPK_L+: length 22.8
  TOP w0.203: HDA27.12 24.26,27.63 24.29,27.65
  TOP w0.508: 24.29,27.65 24.54,27.65 v3(25.18,28.29)
  L4 w1.016: v3(25.18,28.29) 26.04,27.43 26.04,27.31 26.45,26.9 26.45,21.86 25.55,20.97 25.55,20.92 24.42,19.78 24.42,15.97 22.89,14.45 v3(17.69,14.45)
  vias: v1(18.3,14.92)
AUD_SPK_L+_C: length 1.7
  BOTTOM w0.61: SPK1.3 12.3,11.11
AUD_SPK_L-: length 22
  TOP w0.203: 23.68,29.08 22.88,28.27 HDA27.14
  TOP w0.305: v1(18.47,15.74) 17.84,15.74 v3(17.81,15.72)
  TOP w0.508: v3(23.91,29.3) 23.68,29.08
  L4 w1.016: v3(17.81,15.72) 22.26,15.72 23.15,16.6 23.15,21.81 24.54,23.21 24.54,26.26 23.91,26.89 v3(23.91,29.3)
AUD_SPK_L-_C: length 1.5
  BOTTOM w0.61: 11.3,10.92 SPK1.4
AUD_SPK_R+: length 26.7
  TOP w0.203: HDA27.17 21.68,29.12 v3(21.37,29.43)
  L3 w1.016: v3(21.37,29.43) 21.37,28.52 24.29,25.6 24.29,24.48 23.02,23.21 23.02,17.37 16.16,10.51 v3(16.16,9.24)
  vias: v1(17.48,9.09)
AUD_SPK_R+_C: length 4.6
  BOTTOM w0.356: AFTP2904.1 15.91,11.65 14.3,10.05 SPK1.1
  BOTTOM w0.61: v3(14.26,8.1) 14.3,8.14 SPK1.1
AUD_SPK_R-: length 28.6
  TOP w0.203: HDA27.15 22.48,28.89 v3(22.77,29.18)
  L3 w1.016: v3(22.77,29.18) 22.77,29.05 23.5,28.31 23.5,28.31 25.56,26.26 25.56,22.57 24.92,21.94 24.92,17.48 17.43,9.98 17.43,6.95 v3(17.56,6.83)
  vias: v1(17.86,7.54)
AUD_SPK_R-_C: length 5.1
  BOTTOM w0.356: AFTP2903.1 14.38,11.14 13.3,10.06 SPK1.2
  BOTTOM w0.61: SPK1.2 13.3,7.27 v3(13.49,7.08)
AUX_EN_WOWL: length 101.5
  TOP w0.102: v2(96.22,74.21) 96.36,74.07 v1(96.79,74.07)
  L4 w0.102: v2(140.28,63.47) 140.28,63.56 138.84,64.99 137.93,64.99 136,66.92 135.41,66.92 133.53,68.8 133.53,72.46 132.09,73.91 132.09,83.93 132.33,84.17 132.33,85.39 131.9,85.82 131.9,94.9 129.69,97.11 129.69,97.49 126.73,100.45 119.47,100.45 113.35,94.33 113.35,93.47 112.82,92.94 111.32,92.94 110.98,92.59 110.98,92.58 110.49,92.09 110.47,92.09 107.36,88.97 107.36,88.7 107.36,88.24 105.91,86.79 104.33,86.79 103.99,86.45 103.99,86.45 103.74,86.2 103.74,86.2 103.38,85.85 99.34,85.85 98.42,84.93 98.42,84.36 97.7,83.63 97.7,76.29 96.22,74.82 v2(96.22,74.21)
  BOTTOM w0.102: v2(96.22,74.21) 96.22,73.68 95.81,73.27 94.88,73.27 94.59,73.56 92.74,73.56 92.61,73.69 92.6,73.69 CPU1.BB17 ; v2(140.28,63.47) 140.28,62.95 140.68,62.54 141.3,62.54 142.46,61.39 142.92,61.39 143.29,61.75 IOBD1.35
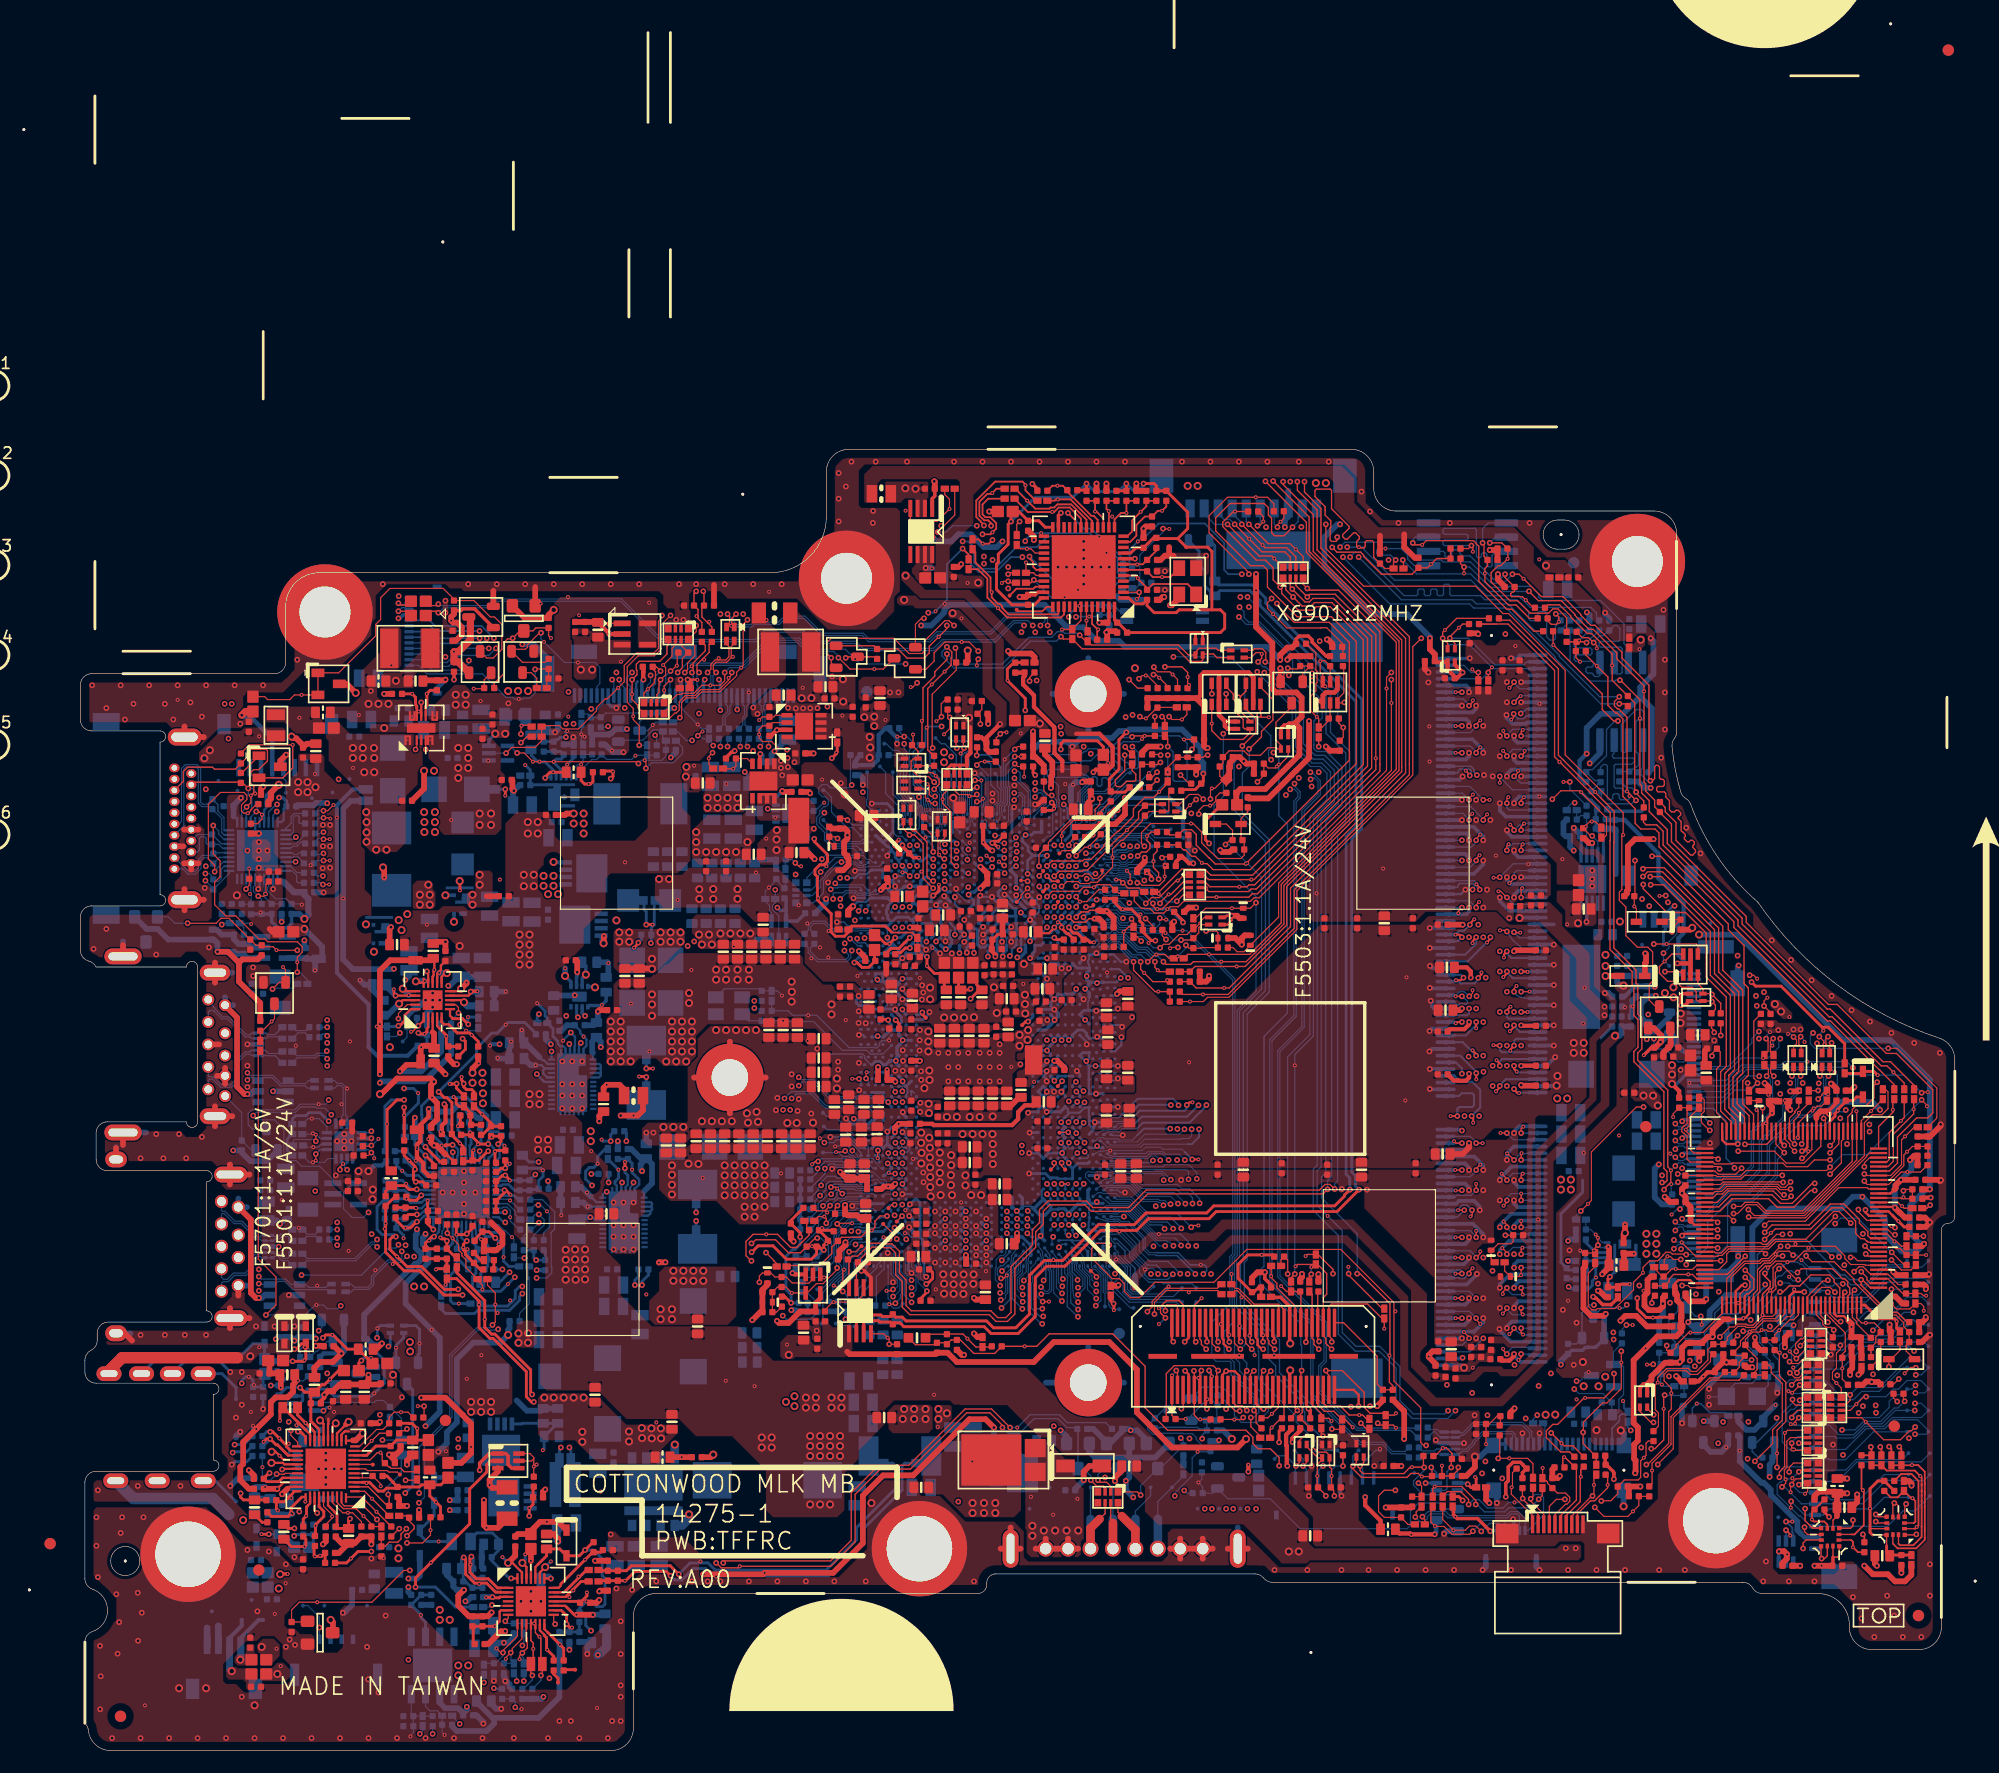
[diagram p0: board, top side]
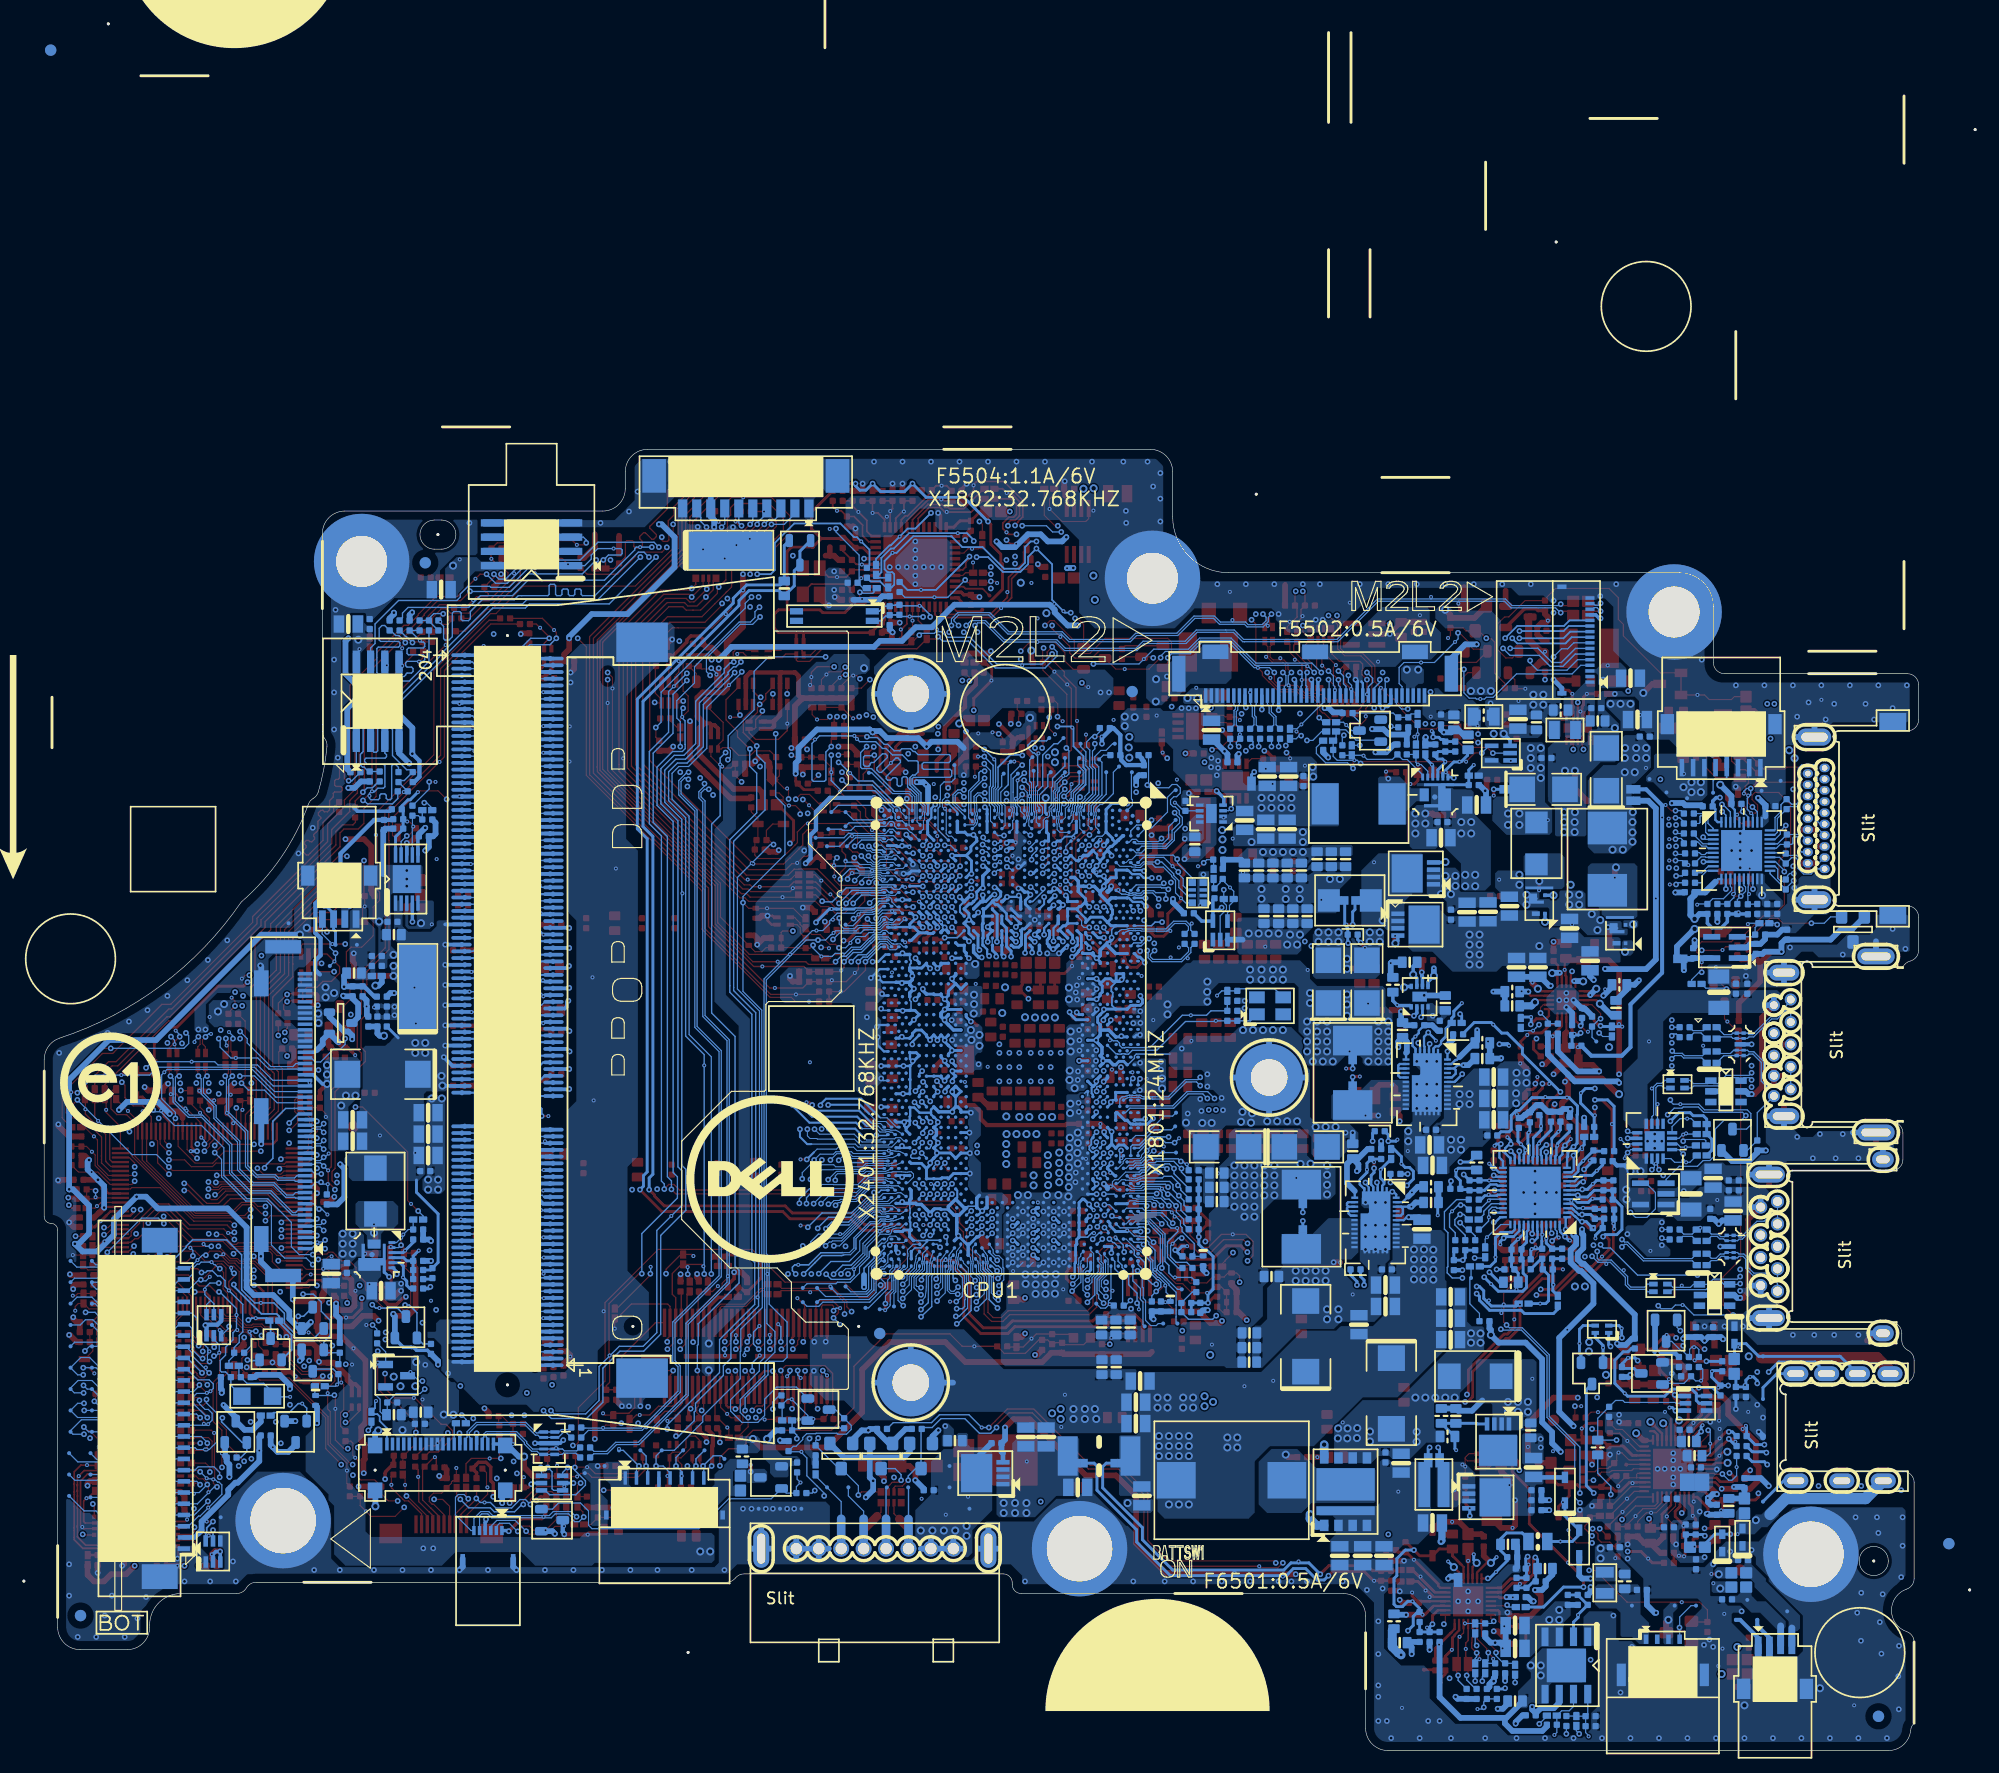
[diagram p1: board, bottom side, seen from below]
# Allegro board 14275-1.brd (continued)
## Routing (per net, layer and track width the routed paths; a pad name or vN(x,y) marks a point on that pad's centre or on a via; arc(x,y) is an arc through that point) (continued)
B71_TP: length 5.8
  BOTTOM w0.102: TP2312.1 69.15,37.97 69.15,39.99 69.37,40.22 69.37,41.19 70.05,41.87 CPU1.B71
BA1_TP: length 5.6
  BOTTOM w0.102: CPU1.BA1 91.84,83.81 92.29,84.26 96.33,84.26 TP2305.1
BA2_TP: length 4.5
  BOTTOM w0.102: CPU1.BA2 91.82,83.19 91.99,83.02 92.35,83.02 92.4,82.97 94.97,82.97 TP2306.1
BA71_TP: length 10.9
  BOTTOM w0.102: TP2303.1 99.1,39.6 98.05,39.6 97.68,39.97 93.5,39.97 92.4,41.08 92.37,41.08 92.12,41.32 92.12,41.67 92.65,42.2 92.65,42.69 92.41,42.93 92.21,42.93 91.96,43.19 CPU1.BA71
BAT1_LED#: length 32.6
  TOP w0.127: KBC24.1 159.56,41.27 158.85,41.98 v2(158.75,41.98) 158.75,41.5 161.19,39.06 161.98,39.06 162.84,38.19 R2484.1
  BOTTOM w0.127: v2(158.75,41.98) 157.74,41.98 157.31,42.4 156.92,42.4 154.44,44.89 154.44,44.97 153.88,45.52 150.83,45.52 149.5,44.2 149.5,41.08 148.33,39.91 v1(147.78,39.91) 146.62,39.91 145.69,38.98 145.69,38.09 144.78,37.18 144.78,36.87 144.61,36.7 143.1,36.7 Q2412.S
BAT2_LED#: length 27.2
  TOP w0.127: v2(150.17,42.54) 150.17,42.28 150.64,41.81 150.64,41.36 149.96,40.68 KBC24.106
  L4 w0.127: v2(150.17,42.54) 149.35,41.72 149.35,41.21 148.63,40.49 146.6,40.49 145.87,39.77 143.8,39.77 142.58,40.99 140.21,40.99 139.05,39.82 138.44,39.82 137.93,40.33 136.03,40.33 135.42,39.72 v2(134.93,39.72)
  BOTTOM w0.127: R2488.1 133.34,36.25 Q2413.S 133.87,39.04 134.55,39.72 v2(134.93,39.72) ; v1(150.43,43.04) 150.42,43.02 150.42,42.74 150.2,42.52 150.19,42.52 v2(150.17,42.54)
BATDRV#: length 49.9
  TOP w0.508: v2(46.26,13.43) 46.01,13.18 PR4409.2 ; v2(55.53,15.72) 60.87,15.72 v1(60.99,15.84) 67.11,15.84 69.76,18.49 69.76,22.73 71.56,24.53 74.24,24.53 79.24,29.54 80.7,29.54 v2(81.44,28.8)
  L3 w0.508: v2(55.53,15.72) 54.87,16.38 48.84,16.38 47.54,15.08 47.52,15.08 47.15,14.71 47.15,14.69 47.02,14.56 47.02,13.68 46.77,13.43 v2(46.26,13.43)
  BOTTOM w0.406: 81.63,26.51 PU4403.4
  BOTTOM w0.508: v2(81.44,28.8) 81.44,27.72 PC4424.2 81.76,26.64 81.63,26.51
BATT_WHITE_LED#: length 25.1
  TOP w0.127: v2(144.45,38.71) 144.45,38.65 144.54,38.57 v1(144.54,37.96)
  L3 w0.127: v2(144.45,38.71) 144.46,38.71 144.67,38.71 146.51,40.55 146.51,42.5 146.91,42.91 146.91,45.78 147.82,46.69 147.82,50.55 147.46,50.92 v2(147.46,51.94)
  BOTTOM w0.127: Q2412.D 143.98,38.71 v2(144.45,38.71) ; v2(147.46,51.94) 147.46,52.05 146.71,52.8 146.71,56.11 145.57,57.24 144.82,57.24 144.81,57.25 IOBD1.26
BB67_TP: length 9.7
  BOTTOM w0.102: CPU1.BB67 92.41,45.6 93.55,44.46 93.55,43.97 94.42,43.1 94.42,42.57 95.24,41.75 96.38,41.75 96.52,41.62 99.1,41.62 TP2302.1
BB70_TP: length 8.8
  BOTTOM w0.102: CPU1.BB70 92.51,43.65 93.14,43.02 93.14,41.06 93.15,41.05 93.15,41.05 93.71,40.48 97.44,40.48 TP2301.1
BEEP: length 178.4
  TOP w0.203: v2(153.47,53.43) 153.6,53.43 153.96,53.79 KBC24.45
  L3 w0.254: v2(146.45,29.3) 145.84,29.3 144.56,30.58 144.56,32.48 144.88,32.8 145.28,32.8 145.88,33.4 147.18,33.4 148.03,34.25 148.03,35.3 148.52,35.79 149.55,35.79 150.36,36.6 150.36,36.81 151.2,37.65 151.2,37.98 152.93,39.71 152.93,40.96 153.65,41.68 153.65,43.05 154.34,43.74 154.34,43.88 154.35,43.89 154.35,44.31 154.06,44.61 154.01,44.61 153.98,44.63 153.98,53.01 153.56,53.43 v2(153.47,53.43)
  L6 w0.254: v2(27.46,36.02) 28.09,36.02 32.32,31.79 37.67,31.79 39.88,29.58 45.64,29.58 46.05,29.99 59.41,29.99 62.17,32.76 77.95,32.76 79.33,31.38 79.33,29.11 81.17,27.27 83.39,27.27 87.2,23.46 88.17,23.46 88.88,22.75 92.8,22.75 94.45,24.4 102.72,24.4 103.59,23.53 106.06,23.53 106.45,23.13 107.67,23.13 108.61,24.07 116.58,24.07 116.86,24.35 118.14,24.35 120.05,26.26 123.4,26.26 126.67,29.52 126.67,30.68 127.41,31.42 132.28,31.42 134.05,29.65 135.55,29.65 136.2,28.99 136.2,23.99 137.16,23.03 140.74,23.03 146.45,28.74 v2(146.45,29.3)
  BOTTOM w0.254: RN2701.1 27.63,36.19 v2(27.46,36.02) ; v1(154.03,53.43) v2(153.47,53.43)
BKLGT_PWM: length 191.4
  TOP w0.102: v2(153.47,52.8) 153.58,52.8 154.36,53.58 KBC24.44 ; v2(29.37,16.06) 28.83,16.06 25.99,13.23 v1(21.11,13.23) 19.51,13.23 18.83,12.54 R6509.1 20.19,11.46 Q6501.G
  L3 w0.102: v2(29.37,16.06) 30.04,16.06 35.97,10.13 39.77,10.13 42.5,12.86 42.5,13.59 44.99,16.08 44.99,16.99 46.62,18.61 55.8,18.61 55.9,18.51 57.54,18.51 58.56,17.49 67.23,17.49 74.22,24.48 85.4,24.48 86.73,23.15 92.05,23.15 92.31,23.41 94.78,23.41 95.21,22.99 95.21,22.66 96.81,21.06 105.82,21.06 106.84,20.03 115.01,20.03 117.48,17.57 135.31,17.57 139.73,21.99 139.73,24.4 v2(139.58,24.56) ; v2(148.7,29.3) 148.24,28.85 144.62,28.85 144.13,29.34 144.13,32.65 144.71,33.23 145.1,33.23 145.72,33.85 147,33.85 147.54,34.39 147.54,35.52 148.25,36.23 149.37,36.23 149.89,36.74 149.89,37.68 152.29,40.09 152.29,42.83 153.41,43.96 153.41,44.28 153.47,44.34 v2(153.47,52.8)
  L6 w0.102: v2(148.7,29.3) 147.98,30.02 146.12,30.02 140.65,24.56 v2(139.58,24.56)
BKLT_CTRL: length 32.3
  TOP w0.114: R5502.1 70.83,97.5 D5502.3 68.33,97.5 68.24,97.41 v2(68.23,97.41) ; RN5501.5 49.7,92.99 49.7,93.17 49.18,93.69 v1(49.18,94.16) 49.18,94.38 49.18,94.38 v2(49.18,95.47) 49.62,95.91 49.62,96.29 49.56,96.35 49.56,96.85 49.82,97.1 51.64,97.1 52.29,97.75 52.29,98.45 52.4,98.55 RN5502.5
  L3 w0.114: v2(49.18,95.47) 49.31,95.47 50.51,96.67 52.79,96.67 52.8,96.66 67.49,96.66 68.23,97.4 v2(68.23,97.41)
BLON_OUT: length 164.9
  TOP w0.102: KBC24.30 159.51,52.87 159.04,52.39 v2(159.04,52.04) ; v2(58.07,96.11) 58.07,95.91 v1(57.79,95.63) 57.79,95.43 56.94,94.58 55.31,94.58 54.78,94.05 53.93,94.05 53.38,93.51 53.38,92.76 53.12,92.49 53,92.49 52.42,91.92 51.53,91.92 51.39,92.06 RN5501.7
  L3 w0.102: v2(58.07,96.11) 58.71,95.47 65.56,95.47 66.3,96.21 71.89,96.21 76.43,100.75 76.43,101.25 77.73,102.56 77.73,108.47 80.23,110.97 88.43,110.97 88.74,110.65 112.1,110.65 114.46,108.3 125.32,108.3 125.32,108.3 127.84,108.3 129.87,106.27 131.09,106.27 131.76,105.61 133.03,105.61 138.13,100.5 138.13,98.6 139.68,97.05 139.68,87.89 140.65,86.92 140.65,83.34 142.4,81.59 142.4,79.01 149.33,72.08 149.33,71.77 155.33,65.78 156.56,65.78 159.32,63.03 159.32,57.23 160.14,56.41 160.14,53.51 159.04,52.41 v2(159.04,52.04)
BLON_OUT_C: length 8
  TOP w0.102: RN5501.2 51.39,94.14 51.58,94.33 51.58,95.09 51.59,95.1 51.59,95.33 v2(51.72,95.46) 52.17,95.91 52.17,96.55 v1(51.95,96.77) 52.75,97.56 52.75,98.26 53.05,98.56 RN5502.6
  BOTTOM w0.102: v2(51.72,95.46) 51.72,94.96 51.55,94.79 LCD1.25
BOARD_ID: length 24.4
  TOP w0.102: R2468.1 140.11,23.81 v1(140.11,24.96) 140.11,25.61 141.8,27.3 141.8,29.76 145.26,33.22 145.73,33.22 145.74,33.22 146.08,33.22 R2444.1 146.64,33.71 C2408.2 147.89,34.17 147.89,34.62 148.37,35.11 R2443.2 147.61,35.21 R2494.2 147.99,36.1 147.99,36.5 148.23,36.74 149,37.52 149.3,37.52 150.09,38.3 151.3,38.3 151.96,38.96 KBC24.111
BOOST_MON: length 142.9
  TOP w0.102: R2423.1 151.47,35.28 151.47,33.4 152.03,32.83 152.03,29.34 151.25,28.55 v1(151.25,26.49) 151.25,26.49 v2(151.25,25.25)
  L3 w0.102: v2(151.25,25.25) 150.68,25.25 150.09,24.65 143.92,24.65 136.03,16.76 116.9,16.76 114.58,19.08 114.47,19.2 106.56,19.2 105.48,20.28 94.49,20.28 92.96,21.81 84.59,21.81 83.45,22.95 74.21,22.95 67.83,16.58 58.17,16.58 57.15,17.6 55.45,17.6 55.35,17.7 48.07,17.7 44.08,13.7 44.08,10.82 43.26,10 41.87,10 39.71,7.84 37.75,7.84 v2(35.97,6.06)
  BOTTOM w0.102: PR4473.1 v2(35.97,6.06)
BP_PWRGD_RST#: length 4.8
  TOP w0.114: R9926.2 106.06,28.66 v1(106.2,28.8) 107.03,29.62 C9901.1 107.3,29.81 XDP1.41
BQ24770_AGND: length 12.2
  TOP w0.508: v2(46.26,14.19) 46.32,14.26 PC4412.2 ; v2(34.2,14.32) 33.69,13.81 33.69,12.92 34.64,11.97 PR4411.2 PC4402.2 36.32,11.97 v2(36.66,12.31) ; PC4401.2 v2(45.88,16.92)
  BOTTOM w0.508: v2(34.2,14.32) 33.56,14.32 33.24,14.64 PC4418.1 32.65,15.68 PC4432.2 ; PC4410.2 35.78,18.22 PC4433.2 35.78,16.35 PC4416.1
  vias: v1(43.59,13.68) v2(39.28,13.3) v2(40.16,14.19) v2(40.16,13.3) v2(40.16,12.41) v2(41.05,13.3)
BT+: length 97.3
  TOP w0.508: BATT1.1 86.94,18 ; BATT1.1 86.05,18.89 ; BATT1.1 85.16,18 ; BATT1.2 88.05,18.89 ; BATT1.2 88.94,18 ; BATT1.2 87.16,18
  L3 w0.508: v2(46.13,8.53) 40.7,3.09 36.61,3.09 33.89,5.81 31.53,5.81 v2(29.24,8.1)
  L4 w0.508: v2(29.24,8.1) 28.61,8.73 28.61,14.84 29.11,15.33 v2(29.24,15.33)
  L6 w0.508: v2(46.13,8.53) 47.15,9.54 47.15,14.71 49.93,17.49 68.49,17.49 73.18,22.19 77.12,22.19 79.03,20.29 82.07,20.29 82.46,20.67 84.23,20.67 v3(84.87,20.03)
  BOTTOM w0.508: BATT1.1 86.94,18 ; BATT1.1 85.16,18 ; BATT1.1 86.05,18.89 ; v2(29.24,15.33) 30,15.33 30.26,15.59 PD4405.A ; PC4424.1 83.98,26.07 PU4403.5 ; 87.16,18 BATT1.2 ; BATT1.2 88.05,18.89 ; BATT1.2 88.94,18
  BOTTOM w0.787: PR4408.1 46.92,10.71 PC4438.1 46.92,9.24 46.39,8.71 46.31,8.71 v2(46.13,8.53)
  vias: v1(84.74,22.62) v1(86.72,21.02) v1(88.88,22.45) v3(84.87,19.14) v3(85.88,19.61) v3(86.9,19.61) v3(87.92,19.61) v3(88.96,19.61)
BT_RADIO_DIS#: length 122.7
  TOP w0.102: v2(79.92,87.85) 80.23,88.17 v1(80.62,88.17) 80.76,88.17 80.76,88.16 R2042.2
  L4 w0.102: v2(149.64,64.1) 146.79,64.1 142.86,68.04 142.86,68.25 142.33,68.78 141.71,68.78 141.66,68.73 139.76,68.73 137.75,70.73 137.75,72.25 135.29,74.71 135.29,78.84 134.07,80.06 134.07,83.24 134.26,83.43 134.26,85.85 134.26,86.47 133.36,87.36 133.36,89.72 133.76,90.12 133.76,95.8 131.8,97.76 131.8,98.07 128.98,100.89 128.54,100.89 127.49,101.95 123.55,101.95 123.4,102.1 118.78,102.1 113.15,96.46 109.43,96.46 107.6,94.63 100.69,94.63 99.53,93.48 93.56,93.48 91.95,95.08 91.95,95.8 91.47,96.28 87.97,96.28 85.33,93.64 85.33,92.27 83.47,90.42 83.37,90.42 80.8,87.85 v2(79.92,87.85)
  BOTTOM w0.089: 80.91,86.98 80.91,84.09 80.79,83.97 80.79,83.71 80.86,83.58 80.86,83.36 CPU1.AB2
  BOTTOM w0.102: v2(79.92,87.85) 80.04,87.85 80.91,86.98 ; IOBD1.34 144.65,61.25 144.92,60.98 146.89,60.98 149,63.09 149,63.47 v2(149.64,64.1)
C1_TP: length 3.6
  BOTTOM w0.102: CPU1.C1 70.09,84.28 70.09,84.75 70.17,84.84 70.17,87.18 TP2308.1
CAM_MIC_CBL_DET#: length 49.9
  TOP w0.102: v2(80.04,97.29) 79.92,97.17 v1(79.92,96.74)
  L3 w0.102: v2(79.18,81.6) 79.29,81.72 79.29,88.82 79.77,89.29 79.77,91.72 79.99,91.94 79.99,97.24 v2(80.04,97.29)
  L6 w0.102: v2(50.83,95.85) 50.83,95.74 51.58,94.99 61.76,94.99 62.99,96.22 66.58,96.22 66.84,96.47 73.33,96.47 73.42,96.39 78.51,96.39 79.41,97.29 v2(80.04,97.29)
  BOTTOM w0.102: LCD1.27 50.55,94.96 50.83,95.24 v2(50.83,95.85) ; v2(79.18,81.6) 79.27,81.6 79.53,81.86 CPU1.W4
CAP_LED: length 12.6
  BOTTOM w0.406: KB1.2 153.71,19 153.37,19.34
  BOTTOM w0.508: 153.37,19.34 153.07,19.64 153.07,20.41 150.69,22.79 150.69,23.25 AFTP6525.1 150.06,23.88 149.84,23.88 147.92,25.8 v1(147.92,26.74) 147.92,27.96 R6513.2
CAP_LED#: length 38.7
  TOP w0.127: v1(139.66,34.41) 140.19,34.41 v2(140.21,34.44) ; KBC24.93 146.82,42.47 v2(148.42,44.06)
  L3 w0.127: v2(148.42,44.06) 148.42,43.45 147.2,42.22 147.2,42.09 147.19,42.09 147.19,40.26 147.19,40.17 142.93,35.91 141.9,35.91 140.43,34.44 v2(140.21,34.44)
  L4 w0.127: v2(151.21,29.66) 150.79,29.24 149.26,29.24 148.87,28.85 143.89,28.85 141.69,31.04 141.69,32.63 140.21,34.11 v2(140.21,34.44)
  BOTTOM w0.127: R2489.1 149.57,26.12 149.03,26.66 Q2414.S 149.45,27.46 151.29,29.3 151.29,29.59 v2(151.21,29.66)
CAP_LED#_R: length 5.3
  BOTTOM w0.508: v1(151.12,30.81) 150.02,29.71 Q2414.D 149.24,28.59 148.51,28.59 147.8,29.31 R6512.1
CAP_LED_Q: length 3.8
  BOTTOM w0.508: R6513.1 146.91,27.23 v1(146.72,27.04) 146.3,26.63 145.33,26.63 144.69,27.27 Q6505.C
CAP_LED_R#: length 5
  BOTTOM w0.127: R6512.2 146.64,30.13 145.26,30.13 144.46,30.93 v1(144.1,30.93) 143.7,30.53 Q6505.B
CBN: length 5.3
  TOP w0.203: HDA27.20 20.48,28.2 20.09,28.58
  TOP w0.254: 20.09,28.58 18.1,30.57 C2715.2 17.79,30.32 v1(17.79,29.41)
CBP: length 3.6
  TOP w0.203: HDA27.19 20.88,28.4 20.73,28.54
  TOP w0.254: 20.73,28.54 20.08,29.2 v1(20.08,29.21) 20.07,29.21 19.36,29.91 C2715.1
CFG: length 15.5
  TOP w0.102: v2(11.97,78.35) 11.97,78.91 11.41,79.47 11.41,84.35 12.48,85.41 14.59,85.41 14.84,85.16 14.84,84.78 14.36,84.3 14.36,83.76 14.55,83.57 v1(14.93,83.57) 14.96,83.57 15.18,83.79 15.18,83.85 15.7,84.37 R5420.2
  BOTTOM w0.102: v2(11.97,78.35) 11.97,78.45 12.75,79.23 U5701.23
CFG0: length 43.2
  TOP w0.114: R9608.1 v1(99.83,29.52) 99.69,29.52 99.3,29.91 XDP1.9 99.3,33.82 v2(99.27,33.85)
  L4 w0.114: v2(99.27,33.85) 98.83,33.41 93.33,33.41 91.45,35.3 88.07,35.3 87.49,34.71 82.15,34.71 80.82,36.04 79.65,36.04 79.01,36.68 75.2,36.68 73.38,38.5 72.52,38.5 71.62,39.4 71.62,40.01 71.52,40.1 71.52,40.52 71.52,43.75 v2(70.82,44.44)
  BOTTOM w0.114: v2(70.82,44.44) 70.9,44.52 70.9,44.89 70.9,44.89 70.9,45.05 71.45,45.6 CPU1.E68
CFG1: length 42.5
  TOP w0.114: XDP1.11 99.8,33.75 v2(99.93,33.88)
  L4 w0.114: v2(69.1,45.12) 71.28,42.81 71.28,40.62 71.28,40 71.37,39.91 71.37,39.3 72.42,38.26 73.28,38.26 75.1,36.44 78.91,36.44 79.55,35.79 80.72,35.79 82.05,34.47 87.59,34.47 88.17,35.05 91.35,35.05 93.23,33.17 99.23,33.17 v2(99.93,33.88)
  BOTTOM w0.114: v2(69.1,45.12) 69.29,45.31 69.94,45.31 CPU1.B67 ; v2(99.93,33.88) 99.93,33.49 v1(99.66,33.22)
CFG2: length 47.5
  TOP w0.114: XDP1.15 100.8,33.69 v2(100.62,33.88)
  L4 w0.114: v2(100.62,33.88) 99.67,32.93 93.13,32.93 91.25,34.81 88.27,34.81 87.69,34.23 81.95,34.23 80.62,35.55 79.45,35.55 78.81,36.19 75,36.19 73.18,38.02 72.72,38.02 72.72,38.02 72.32,38.02 71.13,39.2 71.13,39.81 71.04,39.89 71.04,39.91 71,39.95 71,40.68 67.77,43.91 67.77,45.49 68.19,45.91 68.32,45.91 v2(68.72,46.32)
  BOTTOM w0.114: v2(100.62,33.88) 100.62,33.62 v1(100.87,33.36) ; v2(68.72,46.32) 68.88,46.47 69.09,46.68 69.43,46.68 69.43,46.68 69.53,46.68 69.61,46.6 71.19,46.6 CPU1.D65
CFG3: length 61.1
  TOP w0.114: v1(67.16,41.45) 67.25,41.45 67.77,40.93 v2(67.97,40.93) ; XDP1.17 101.3,33.75 v2(101.43,33.88) 100.99,34.32 97.51,34.32 96.81,33.61 96.81,29.62 R9902.1
  L4 w0.114: v2(67.97,40.93) 67.53,41.37 67.53,41.75 67.79,42 68.72,42 70.02,40.71 70.36,40.71 70.76,40.31 70.76,39.85 70.8,39.81 70.8,39.79 70.89,39.71 70.89,39.1 72.22,37.78 72.82,37.78 73.08,37.78 74.9,35.95 78.71,35.95 79.35,35.31 80.52,35.31 81.85,33.99 85.53,33.99 88.73,30.79 90.68,30.79 92.37,32.47 100.02,32.47 v2(101.43,33.88)
  BOTTOM w0.089: 69.01,44.15 69.46,44.6 69.65,44.6 70.65,45.6 CPU1.D67
  BOTTOM w0.114: R604.1 68.36,40.54 v2(67.97,40.93) 67.55,41.34 67.55,41.74 67.8,41.98 67.88,41.98 68.47,42.57 68.47,43.6 69.01,44.15
CFG4: length 48.6
  TOP w0.114: XDP1.27 103.8,33.67 v2(103.98,33.85)
  L4 w0.114: v2(103.98,33.85) 102.27,32.14 92.38,32.14 90.78,30.55 88.63,30.55 85.43,33.74 81.75,33.74 80.44,35.05 79.57,35.05 79.35,34.84 78.59,34.84 78.17,35.26 75.26,35.26 73.08,37.43 72.05,37.43 72.02,37.46 70.65,38.83 70.65,39.61 70.56,39.69 70.56,39.71 70.26,40.01 v2(70.26,40.12)
  BOTTOM w0.114: CPU1.E70 71.66,43.6 71.66,42.95 70.96,42.25 70.96,39.77 R605.1 70.72,39.67 v2(70.26,40.12) ; v1(103.31,35.22) 103.98,34.55 v2(103.98,33.85)
CFG5: length 45.2
  TOP w0.114: v2(104.62,33.85) 104.3,33.54 XDP1.29 ; v1(71.6,45.75) 71.99,45.75 v2(72.14,45.6)
  L4 w0.114: v2(104.62,33.85) 104.09,34.38 93.05,34.38 91.65,35.78 87.87,35.78 87.29,35.19 82.35,35.19 79.92,37.62 74.94,37.62 73.18,39.38 72.53,39.38 72.22,39.7 72.22,40.08 72,40.3 72,43.13 72.4,43.54 72.4,45.34 v2(72.14,45.6)
  BOTTOM w0.114: v2(72.14,45.6) 71.82,45.29 71.72,45.29 71.31,44.88 CPU1.C68
CFG6: length 49.3
  TOP w0.114: v2(105.48,33.87) 105.3,33.69 XDP1.33
  L4 w0.114: v2(69.67,39.89) 69.63,39.84 69.63,39.35 70.03,38.95 70.19,38.95 71.94,37.19 71.95,37.19 72.98,37.19 75.16,35.01 78.07,35.01 78.49,34.59 79.49,34.59 79.71,34.81 80.34,34.81 81.65,33.5 85.33,33.5 88.53,30.3 90.88,30.3 92.48,31.9 103.51,31.9 v2(105.48,33.87)
  BOTTOM w0.114: CPU1.D68 71.36,43.62 71.01,43.27 71.01,43.06 70.43,42.47 70.43,41.53 69.67,40.78 v2(69.67,39.89) 69.51,39.73 v1(69.51,39.33)
CFG7: length 53.2
  TOP w0.114: v1(68.08,42.87) 67.97,42.76 v2(67.97,41.57) ; XDP1.35 105.8,33.51 v2(106.12,33.83)
  L4 w0.114: v2(106.12,33.83) 103.95,31.66 92.58,31.66 90.98,30.06 88.43,30.06 85.23,33.26 81.55,33.26 80.46,34.35 78.39,34.35 77.97,34.77 75.06,34.77 72.88,36.95 72.88,36.95 71.85,36.95 70.09,38.71 69.93,38.71 69.39,39.25 69.39,39.41 68.4,40.39 68.4,41.11 67.97,41.55 v2(67.97,41.57)
  BOTTOM w0.114: CPU1.C67 70.34,45.01 69.92,44.59 69.92,44.19 69.7,43.97 69.45,43.97 68.99,43.51 68.99,42.26 68.3,41.57 v2(67.97,41.57)
CFG8: length 42
  TOP w0.114: v2(99.43,36.44) 99.3,36.56 XDP1.10 99.3,39.68 v1(99.96,40.33)
  L4 w0.114: v2(72.45,40.48) 73.15,41.18 73.15,42.59 73.81,43.25 74.68,43.25 74.97,42.95 74.97,41.07 75.03,41.02 75.03,40.78 75.28,40.52 75.28,40.52 75.66,40.14 75.66,39.71 76.31,39.06 80.52,39.06 82.95,36.64 86.69,36.64 87.27,37.23 92.25,37.23 93.48,36 98.63,36 98.77,36.14 99.14,36.14 v2(99.43,36.44)
  BOTTOM w0.089: CPU1.F71 72.52,43.48 72.49,43.45 72.49,42.52 73.05,41.95 73.05,41 72.53,40.48 v2(72.45,40.48)
CFG9: length 43.4
  TOP w0.114: v2(72.66,39.88) 72.57,39.79 v1(72.11,39.79) ; XDP1.12 99.8,36.67 99.93,36.54 99.93,36.21 v2(100.36,35.78)
  L4 w0.114: v2(72.66,39.88) 72.66,39.98 73.39,40.72 73.39,42.49 73.91,43.01 74.28,43.01 74.58,42.7 74.58,41.12 74.79,40.92 74.79,40.64 75.42,40 75.42,39.61 76.21,38.82 80.42,38.82 82.85,36.4 86.79,36.4 87.37,36.98 92.15,36.98 93.37,35.76 98.73,35.76 98.75,35.78 v2(100.36,35.78)
  BOTTOM w0.089: 72.69,43.07 72.69,43.4 72.88,43.59 72.88,44.13 CPU1.G69
  BOTTOM w0.114: 72.69,43.07 72.68,43.05 72.68,42.6 73.24,42.03 73.24,40.77 73.1,40.63 73.1,40.32 v2(72.66,39.88)
CFG10: length 43.5
  TOP w0.114: v2(101.38,35.78) 100.89,36.27 100.89,36.92 100.8,37.02 XDP1.16 ; v2(72.45,41.11) 72.32,40.99 v1(71.86,40.99)
  L4 w0.114: v2(72.45,41.11) 72.91,41.57 72.91,42.69 73.71,43.49 74.78,43.49 75.85,42.42 75.85,41.2 75.9,41.14 75.9,39.81 76.41,39.31 80.62,39.31 83.05,36.88 86.59,36.88 87.17,37.47 92.35,37.47 93.58,36.25 96.22,36.25 96.87,36.89 100.61,36.89 100.95,36.56 100.95,36.21 v2(101.38,35.78)
  BOTTOM w0.089: CPU1.F70 72.58,44.13 72.26,43.81 72.26,43.34 72.26,43.34 72.26,42.49 72.86,41.89 72.86,41.38 72.6,41.12 72.45,41.12 v2(72.45,41.11)
CFG11: length 41.9
  TOP w0.114: v2(101.43,36.44) 101.3,36.56 XDP1.18
  L4 w0.114: v2(72.77,45.6) 72.77,45.08 72.9,44.95 73.72,44.95 73.84,44.82 73.84,44.54 73.72,44.42 72.83,44.42 72.7,44.29 72.7,43.96 72.83,43.83 74.85,43.83 74.96,43.72 74.98,43.72 76.09,42.61 76.09,41.3 76.15,41.24 76.15,39.91 76.51,39.55 80.72,39.55 83.15,37.12 86.49,37.12 87.07,37.71 92.45,37.71 93.49,36.67 96.3,36.67 96.76,37.13 100.73,37.13 v2(101.43,36.44)
  BOTTOM w0.114: v1(101.67,38.01) 101.43,37.77 v2(101.43,36.44) ; CPU1.G68 v2(72.77,45.6)
CFG12: length 40.8
  TOP w0.114: XDP1.28 103.8,36.8 103.88,36.72 103.88,36.32 v2(104.43,35.78)
  L4 w0.114: v2(104.43,35.78) 103.75,35.1 93.35,35.1 91.95,36.5 87.57,36.5 86.99,35.92 82.65,35.92 80.22,38.34 76.01,38.34 74.94,39.41 74.94,39.79 v2(74.11,40.63)
  BOTTOM w0.089: v2(74.11,40.63) 74.11,40.64 74.49,41.03 74.49,42.73 74.11,43.12 74.11,43.86 CPU1.H70
  BOTTOM w0.114: v1(104.68,35.25) 104.68,35.53 v2(104.43,35.78)
CFG13: length 39
  TOP w0.114: v2(104.43,36.44) 104.3,36.56 XDP1.30
  L4 w0.114: v2(74.09,41.27) 74.54,40.82 74.54,40.54 75.18,39.9 75.18,39.51 76.11,38.58 80.32,38.58 82.75,36.16 86.89,36.16 87.47,36.74 92.05,36.74 93.45,35.34 103.59,35.34 103.92,35.67 103.92,35.92 v2(104.43,36.44)
  BOTTOM w0.089: v2(74.09,41.27) 74.09,41.35 73.69,41.75 73.69,42.14 73.5,42.34 73.14,42.69 CPU1.G71
  BOTTOM w0.114: v1(104.22,36.99) 104.22,36.64 v2(104.43,36.44)
CFG14: length 47
  TOP w0.114: v2(105.43,36.44) 105.43,36.46 105.4,36.5 105.4,36.86 105.3,36.95 XDP1.34
  L4 w0.114: v2(74.09,41.93) 74.09,41.92 73.63,41.46 73.63,39.8 75.58,37.86 80.02,37.86 82.45,35.43 87.19,35.43 87.77,36.02 91.75,36.02 93.15,34.62 105.92,34.62 106.9,35.6 106.9,36.61 106.61,36.89 105.89,36.89 v2(105.43,36.44)
  BOTTOM w0.089: v2(74.09,41.93) 74.09,42 73.54,42.55 73.54,44.31 73.8,44.57 CPU1.H69
  BOTTOM w0.114: v2(105.43,36.44) 105.44,36.45 v1(105.44,37.03)
CFG15: length 43.1
  TOP w0.114: XDP1.36 105.8,37.05 105.82,37.03 105.82,36.67 105.95,36.54 105.95,36.29 v2(106.46,35.78)
  L4 w0.114: v2(106.46,35.78) 105.54,34.86 93.25,34.86 91.85,36.26 87.67,36.26 87.09,35.68 82.55,35.68 80.12,38.1 75.91,38.1 74.1,39.91 v2(74.1,39.96)
  BOTTOM w0.089: 72.88,42.97 72.88,43.34 73.14,43.6 CPU1.G70
  BOTTOM w0.114: v2(74.1,39.96) 73.44,40.61 73.44,42.12 72.88,42.68 72.88,42.97 ; v1(106.41,35.22) 106.41,35.73 v2(106.46,35.78)
CFG16: length 41.4
  TOP w0.114: v2(96.73,38.58) 96.43,38.87 96.43,38.89 96.29,39.03 96.29,39.59 96.81,40.1 97.95,40.1 98.3,39.75 XDP1.6
  L4 w0.114: v2(96.73,38.58) 96.63,38.48 95.13,38.48 94.92,38.69 93.57,38.69 93.57,38.68 93.21,38.68 92.72,38.19 86.87,38.19 86.29,37.61 83.35,37.61 81.44,39.52 81.44,45.03 81.2,45.26 81.2,47.59 80.29,48.5 78.98,48.5 78.98,48.5 78.75,48.5 78.75,48.5 76.92,48.5 76.63,48.21 76.63,47.88 76.35,47.6 74.65,47.6 74.17,47.13 73.15,47.13 72.58,47.7 v2(72.58,47.71)
  BOTTOM w0.114: v2(72.58,47.71) 72.25,48.05 CPU1.E63 ; v2(96.73,38.58) 96.17,38.02 v1(96.15,38.02)
CFG17: length 45.8
  TOP w0.114: v2(96.73,39.21) 96.73,39.6 96.86,39.72 97.67,39.72 97.8,39.59 XDP1.4
  L4 w0.114: v2(96.73,39.21) 96.37,39.57 94.12,39.57 93.47,38.93 90.3,38.93 89.44,39.78 89.44,42.03 89.01,42.46 88.27,42.46 88.14,42.34 88.14,39.41 88.02,39.29 86.98,39.29 86.85,39.41 86.85,42.35 86.72,42.48 84.43,42.48 84.3,42.6 84.3,42.97 84.12,43.15 83.6,43.15 83.47,43.02 83.47,41.45 83.34,41.32 82.77,41.32 82.64,41.45 82.64,44.49 82.52,44.62 82.25,44.62 81.44,45.43 81.44,47.69 81.43,47.7 80.39,48.74 79.08,48.74 79.08,48.74 78.65,48.74 78.65,48.74 76.61,48.74 76.41,48.54 75.71,48.54 75.41,48.25 73.7,48.25 v2(73.27,48.67)
  BOTTOM w0.114: v2(96.73,39.21) 96.5,39.44 v1(96.15,39.44) ; v2(73.27,48.67) 72.9,48.3 CPU1.F63
CFG18: length 49.2
  TOP w0.114: XDP1.24 102.8,37.02 102.89,36.94 102.89,36.3 v2(103.41,35.78)
  L4 w0.114: v2(72.58,46.62) 72.33,46.62 71.48,47.48 71.48,48.17 72.43,49.12 74.13,49.12 74.47,48.78 76.31,48.78 76.51,48.98 78.55,48.98 78.55,48.99 79.18,48.99 79.18,48.98 79.63,48.98 79.63,48.99 80.07,48.99 80.07,48.98 80.49,48.98 81.6,47.87 81.68,47.8 81.68,47.39 81.68,47.39 81.68,45.53 82.35,44.86 82.74,44.86 84.87,42.74 89.07,42.74 89.83,41.99 89.83,39.74 90.4,39.17 92.92,39.17 93.6,39.84 96.81,39.84 98.66,38 101.49,38 102.88,36.61 102.88,36.32 v2(103.41,35.78)
  BOTTOM w0.114: CPU1.E66 72.25,46.29 v2(72.58,46.62) ; v1(103.34,37.85) 103.34,37.84 103.86,37.32 103.86,36.84 103.87,36.84 103.87,36.27 103.86,36.26 103.86,36.23 v2(103.41,35.78)
CFG19: length 41.4
  TOP w0.114: XDP1.22 102.3,36.83 102.33,36.81 102.33,36.54 v2(102.43,36.44)
  L4 w0.114: v2(102.43,36.44) 101.49,37.37 96.47,37.37 96.04,36.95 93.56,36.95 92.55,37.95 86.97,37.95 86.39,37.36 83.25,37.36 80.8,39.81 76.78,39.81 76.39,40.2 76.39,41.34 76.33,41.4 76.33,42.71 75.11,43.92 75.11,46.68 74.99,46.81 74.44,46.81 74.32,46.68 74.32,45.71 74.19,45.58 v2(73.63,45.58)
  BOTTOM w0.114: v2(73.63,45.58) 73.05,46.15 CPU1.F66 ; v2(102.43,36.44) 102.42,36.45 v1(102.42,37.05)
CFG_RCOMP: length 2.4
  TOP w0.508: v2(72.63,50.52) 72.4,50.29 v1(72.02,50.29) 71.63,50.29 71.41,50.06 R601.1
  BOTTOM w0.406: v2(72.63,50.52) 72.31,50.2 CPU1.E60
CHARGER_SRC:
  vias: v1(46.39,23.08)
CHG_AMBER_LED#: length 26.7
  L3 w0.127: v2(145.26,55.95) 144.73,55.42 144.73,50.9 143.83,50.01 143.83,42.95 143.38,42.49 143.38,41.42 142.82,40.86 139.95,40.86 138.84,39.74 v2(137.85,39.74)
  BOTTOM w0.127: IOBD1.25 144.46,56.75 v2(145.26,55.95) ; v2(137.85,39.74) 137.56,39.45 v1(137.22,39.45) 135.61,39.45 Q2413.D
CLK_PCI_LPC: length 63.3
  TOP w0.114: v2(108.06,109.06) 107.3,108.3 106.46,108.3 106.19,108.57 106.19,109.85 105.91,110.14 105.91,110.8 105.53,111.18 102.48,111.18 101.21,109.9 101.21,108.73 104.3,105.63 105.44,105.63 105.82,105.25 105.82,103.73 106.29,103.26 106.29,103.26 107.35,102.2 108.47,101.08 111.53,101.08 111.82,100.79 111.82,100.79 113.74,98.87 113.74,87.98 104.3,78.53 100.98,78.53 100.44,79.07 100.04,79.07 v1(99.98,79.13) 99.39,79.72 99.08,79.72 98.52,80.28 98.41,80.28 98.39,80.3 98.33,80.3 EC1802.1 R1804.2
  BOTTOM w0.114: v2(108.06,109.06) 108.56,109.56 108.56,109.92 108.93,110.29 DB1.9
CLK_PCI_LPC_MEC: length 125.9
  TOP w0.114: v2(106.67,102.26) 106.67,102.12 108.2,100.58 111.33,100.58 113.12,98.79 113.12,88.28 v1(103.89,79.05) 103.87,79.03 101.18,79.03 100.65,79.57 100.62,79.57 99.78,80.4 99.78,80.41 99.48,80.72 99.48,81.67 99.06,82.09 98.35,82.09 EC1801.1 97.12,81.63 R1805.2 ; v2(140.11,79.72) 140.88,79.72 146.19,74.41 146.91,73.69 146.91,73.17 148.31,71.78 148.31,68.38 148.41,68.27 148.59,68.09 148.69,67.99 148.69,60.19 148.59,60.09 148.19,59.69 148.19,57.67 149.16,56.7 KBC24.57
  L3 w0.114: v2(106.67,102.26) 106.67,102.85 106.15,103.37 106.15,103.78 107.64,105.27 110.07,105.27 110.15,105.19 120.77,105.19 121.52,105.94 123.53,105.94 123.77,105.7 128.24,105.7 131.03,102.91 131.58,102.91 135.47,99.02 135.47,97.96 136.56,96.87 136.56,92.92 137.5,91.97 137.5,90.78 137.52,90.77 137.52,84.39 139.45,82.46 139.45,80.38 v2(140.11,79.72)
CLK_TP_SIO: length 92.7
  TOP w0.114: RN6502.2 108.67,27.65 109.06,28.03 109.63,28.03 109.89,27.78 109.89,27.02 110.3,26.6 111.07,26.6 111.36,26.32 RN6501.4 111.36,25.3 111.54,25.11 v1(111.54,24.48) 111.54,23.53 EC6501.1 111.73,23.21 111.73,22.76 v2(111.79,22.7) ; v2(154.62,50.56) 154.39,50.56 152.6,48.78 151.55,48.78 150.79,49.54 147.13,49.54 146.05,48.47 KBC24.78
  L3 w0.114: v2(111.79,22.7) 112.45,22.05 115.37,22.05 116.5,20.92 117.05,20.92 117.47,21.33 121.46,21.33 122.78,20.01 125.91,20.01 126.4,19.52 130.75,19.52 131.19,19.96 134.24,19.96 136.03,21.76 136.03,22.87 135.53,23.37 135.53,25.17 137.68,27.31 137.99,27.31 138.55,27.31 139.38,28.14 140.7,28.14 140.72,28.17 151.16,28.17 152.07,29.08 152.07,29.37 152.07,32.6 150.69,33.99 150.69,35.83 151.14,36.28 151.14,36.48 152.14,37.48 152.92,37.48 153.17,37.73 153.17,38.85 154.47,40.14 154.47,42.31 155.12,42.97 155.12,43.55 155.14,43.57 155.14,44.64 155.12,44.65 155.12,50.06 v2(154.62,50.56)
CLKREQ_PCIE#1: length 126.3
  TOP w0.102: R1829.2 88.12,80.88 v2(88.12,80.7)
  L3 w0.102: v2(151.54,58.54) 151.54,58.64 152,59.1 152,63.01 v2(151.54,63.47)
  L4 w0.102: v2(151.54,58.54) 149.85,58.54 149.06,59.33 149.06,59.69 148.81,59.94 145.03,59.94 143.58,58.49 141.77,58.49 140.85,59.41 140.85,62.11 141.49,62.75 141.49,64.74 139.94,66.29 138.26,66.29 136.3,68.25 136.29,68.25 135.11,68.25 134.87,68.49 134.87,73.98 133.68,75.17 133.68,78.03 132.49,79.22 132.49,83.15 132.73,83.39 132.73,85.65 132.3,86.09 132.3,95.13 130.1,97.33 130.1,97.65 126.8,100.96 119.15,100.96 111.54,93.35 111.16,93.35 110.57,92.76 110.57,92.75 110.32,92.49 109.36,92.49 106.95,90.08 106.95,89.14 106.95,88.51 105.78,87.34 104.17,87.34 103.16,86.33 99.09,86.33 96.17,83.41 90.83,83.41 v2(88.12,80.7)
  BOTTOM w0.102: CPU1.AT7 88.45,80.37 v2(88.12,80.7) ; IOBD1.33 147.07,60.75 148.06,61.74 v1(150.02,61.74) 150.45,61.74 151.42,62.71 151.42,63.34 v2(151.54,63.47)
CLKREQ_PCIE#2: length 22.7
  TOP w0.102: R1830.2 94.25,94.71 v2(93.49,95.47)
  L3 w0.102: v2(88.1,79.76) 88.11,79.76 88.57,80.23 88.98,80.23 89.21,80.01 89.21,79.79 89.46,79.54 90.5,79.54 91.12,80.16 91.12,84.07 91.84,84.78 91.84,92.85 93.49,94.5 v2(93.49,95.47)
  BOTTOM w0.102: CPU1.AT8 88.45,79.39 88.1,79.74 v2(88.1,79.76)
CLKREQ_PCIE#3: length 28.7
  TOP w0.102: v2(95.7,96.58) 95.7,96.49 96.03,96.16 97.13,96.16 v1(97.36,95.93) 97.81,95.49 R1831.2
  L3 w0.102: v2(88.12,77.95) 88.56,78.39 88.95,78.39 89.17,78.17 89.89,78.17 90.31,77.74 91.16,77.74 91.74,78.32 91.74,83.74 92.46,84.46 92.46,92.4 95.17,95.1 95.47,95.1 96.09,95.73 96.09,96.18 v2(95.7,96.58)
  BOTTOM w0.102: v2(88.12,77.95) 88.45,78.28 CPU1.AT10
CLKREQ_PCIE#4: length 23.8
  TOP w0.102: R1832.2 96.92,94.9 v1(96.18,95.64) 95.9,95.92 v2(95.66,95.92)
  L3 w0.102: v2(95.66,95.92) 92.26,92.51 92.26,84.54 91.54,83.82 91.54,79.9 90.01,78.37 89.26,78.37 88.79,78.84 v2(88.76,78.84)
  BOTTOM w0.102: CPU1.AU8 89.1,79.2 88.79,78.89 88.79,78.87 v2(88.76,78.84)
CLKREQ_PCIE#5: length 3.7
  TOP w0.102: R1833.2 90.96,81.65 89.97,80.66 v1(89.97,80.54) 89.52,80.54 88.78,79.79 88.78,79.77 v2(88.78,79.77)
  BOTTOM w0.102: v2(88.78,79.77) 88.78,79.78 88.78,79.79 89.1,80.11 CPU1.AU7
CLKREQ_PEG#0: length 24.3
  TOP w0.102: R1817.2 96.03,94.92 95.12,95.83 95.01,95.83 95.01,95.84 v1(94.98,95.84) 94.97,95.83 94.65,95.83 v2(94.38,95.55)
  L3 w0.102: v2(88.12,78.84) 88.59,79.3 88.95,79.3 89.22,79.03 89.22,78.82 89.47,78.57 89.93,78.57 91.34,79.98 91.34,83.91 92.06,84.63 92.06,92.6 94.49,95.03 94.49,95.44 v2(94.38,95.55)
  BOTTOM w0.102: CPU1.AR10 87.8,78.54 88.09,78.84 v2(88.12,78.84)
CLKRUN#: length 96.6
  TOP w0.102: v2(145.45,61.92) 145.45,62.13 R2510.1 146.18,62.29 146.18,61.1 145.86,60.77 145.86,56.86 146.76,55.96 KBC24.63 ; R1819.2 98.63,92.35 v1(98.2,91.92) 97.31,91.92 v2(97.06,92.17)
  L4 w0.102: v2(145.45,61.92) 144.43,62.94 144.43,65.75 143.25,66.93 142.55,66.93 142.2,66.58 140.22,66.58 139.16,67.65 139.16,68.18 137.34,70 137.34,72.08 134.09,75.33 134.09,78.25 133.66,78.68 133.66,83.41 133.85,83.6 133.85,86.26 132.71,87.41 132.71,95.33 130.51,97.54 130.51,97.94 126.91,101.54 123.38,101.54 123.23,101.69 118.95,101.69 111.74,94.48 109.56,94.48 105.67,90.59 102.48,90.59 102.09,90.2 101.6,90.2 99.76,92.03 97.2,92.03 v2(97.06,92.17)
CLKRUN#_R: length 22.7
  TOP w0.102: R1819.1 96.04,93 R1818.1 95.99,92.98 95.03,92.02 v1(94.99,92.02) 94.6,92.02 v2(94.45,92.17)
  L3 w0.102: v2(89.71,77.72) 89.95,77.48 91.52,77.48 91.95,77.91 91.95,81.05 92.89,81.99 92.89,84.2 92.67,84.42 92.67,90.85 93.07,91.26 93.65,91.26 94.45,92.05 v2(94.45,92.17)
  BOTTOM w0.102: v2(89.71,77.72) 90.19,77.72 CPU1.AW11
CMP_VIN0: length 3.2
  TOP w0.114: R2470.2 162.58,48.35 v1(162.4,48.53) 162.36,48.53 162.03,48.87 KBC24.20
CMP_VIN0_R: length 123.7
  TOP w0.114: v2(106.86,25.39) 106.86,26.13 106.09,26.9 105,26.9 104.53,27.37 104.53,27.93 103.9,28.56 96.92,28.56 94.92,30.56 94.92,34.26 92.03,37.15 86.36,37.15 85.25,36.04 v1(84.18,36.04) C2612.1 81.5,35.4 79.65,35.4 78.45,36.61 R2608.2 77.63,36.61 C2613.1 77.12,36.35 R2609.2 76.19,36.18 74.43,36.18 R2610.1 ; R2494.1 147.35,36.61 v2(147.73,36.99) ; v2(164.9,48.63) 164.63,48.35 R2470.1
  L3 w0.114: v2(106.86,25.39) 106.86,25.37 107.37,24.86 109.87,24.86 110.27,25.26 110.27,25.61 111.33,26.66 117.93,26.66 119.63,28.36 120.79,28.36 121.2,27.95 126.35,27.95 127.93,29.54 127.93,29.55 128.65,30.27 128.65,31.03 129.87,32.25 129.87,32.34 130,32.47 v2(130,32.5)
  L4 w0.114: v2(130,32.5) 130,32.94 130.61,33.55 130.61,34.28 132.73,36.4 135.16,36.4 136.48,37.72 136.84,37.72 137.1,37.46 137.1,37.21 139.34,34.98 142.25,34.98 142.51,35.23 142.51,35.24 143.34,36.07 144.75,36.07 145.14,35.69 146.44,35.69 147.73,36.98 v2(147.73,36.99) 147.73,37.51 148.46,38.24 148.46,38.56 148.72,38.82 149.04,38.82 149.04,38.82 150.17,38.82 150.61,39.27 155.43,39.27 156.3,38.4 156.3,38.12 156.96,37.46 v2(159.8,37.46)
  L6 w0.102: v2(164.9,48.63) 163.41,47.14 v2(163.41,39.07)
  BOTTOM w0.114: v2(159.8,37.46) 160.9,38.56 162.06,38.56 162.56,39.07 v2(163.41,39.07)
CMP_VOUT0: length 70.2
  TOP w0.114: R2476.1 133.05,27.17 132.27,27.17 v1(132.04,27.4) v2(131.12,28.31) ; KBC24.85 145.83,45.67 v2(145.96,45.79)
  L3 w0.114: v2(125.44,29.89) 124.95,29.89 124.47,29.41 121.94,29.41 121.46,29.9 119.1,29.9 117.86,28.66 116.92,28.66 116.43,28.17 111.26,28.17 110.96,28.47 110.59,28.47 110.59,28.47 100.67,28.47 v2(100.01,27.81) ; v2(131.12,28.31) 131.13,28.32 132.14,28.32 138.54,34.72 138.54,35.45 141.24,38.15 142.24,38.15 144.24,40.15 144.25,40.15 144.56,40.46 144.56,40.47 144.89,40.8 144.89,41.81 145.26,42.18 145.26,45.1 v2(145.96,45.79)
  L4 w0.114: v2(131.12,28.31) 130.84,28.31 130.41,28.75 130.15,28.75 129.38,29.51 129.38,29.83 129.07,30.14 128.25,30.14 127.8,29.7 125.64,29.7 v2(125.44,29.89)
  BOTTOM w0.114: R2602.2 R2607.2 ; R2607.2 100.3,28.67 99.73,28.67 99.59,28.81 98.51,28.81 98.5,28.82 96.21,28.82 96.12,28.73 R2615.2 ; R2607.2 100.01,28.12 v2(100.01,27.81)
CMP_VOUT1: length 40.5
  TOP w0.114: R2475.1 132.76,26.62 131.97,26.62 130.68,27.91 130.68,28.5 131.26,29.08 131.69,29.08 134.05,31.44 v1(134.14,31.44) 135.85,31.44 136.72,32.31 v2(136.72,33.61) ; v2(145.96,46.42) 145.91,46.47 KBC24.83
  L3 w0.114: v2(145.96,46.42) 145.85,46.32 145.73,46.32 144.73,45.32 144.73,42.4 144.36,42.03 144.36,41.03 144.02,40.7 v2(144.02,40.68) 144.01,40.68 142.01,38.68 141.64,38.68 141.02,38.68 138,35.67 138,34.99 136.72,33.7 v2(136.72,33.61)
  BOTTOM w0.114: v2(144.02,40.68) 143.1,40.68 142.4,39.98 142.4,39.16 141.61,38.37 141.61,36.98 142.18,36.41 Q2408.G 141.92,35.46 R2417.1 140.75,34.58 R2418.1
CODEC_BITCLK_R: length 5.5
  TOP w0.114: HDA27.40 22.88,22.12 23.43,21.57 24.57,21.57 v1(25.24,20.9) 25.94,20.2 C2723.2 R2720.2
CODEC_SDOUT_R: length 4
  TOP w0.114: HDA27.1 25.34,23.11 v1(26,22.45) R2719.2
CP_VNEG: length 2.9
  TOP w0.203: 19.87,28.18 20.08,27.97 HDA27.21
  TOP w0.254: v2(19.39,28.44) 19.61,28.44 19.87,28.18
  BOTTOM w0.254: v1(19.26,29) 19.39,28.87 v2(19.39,28.44) 19.82,28.01 C2724.2
CP_VPOS: length 4.6
  TOP w0.102: v2(18.76,28.55) 18.76,28.1 19.36,27.5 HDA27.22
  BOTTOM w0.102: v2(18.76,28.55) 18.58,28.37 v1(18.58,27.36) 18.58,26.54 18.83,26.28 C2725.2
CPU_A16_TP: length 3.7
  BOTTOM w0.089: CPU1.BB9 92.58,78.92 92.66,78.83 93.29,78.83 93.45,78.99 93.92,78.99
  BOTTOM w0.102: 93.92,78.99 94.39,78.99 94.59,79.19 95.51,79.19 TP1902.1
CPU_D1_TP: length 6.1
  BOTTOM w0.089: CPU1.M2 75.55,83.36 75.55,83.58 75.49,83.71 75.46,83.77 75.46,84 75.43,84.03 75.43,84.28 75.35,84.36 75.35,85.36
  BOTTOM w0.102: TP1801.1 74.96,88.36 74.96,87.85 74.48,87.36 74.48,86.23 75.35,85.36
CPU_D4_TP: length 5.3
  BOTTOM w0.089: 79.1,86.27 79.08,86.26 79.08,83.51 CPU1.V1
  BOTTOM w0.102: 79.1,86.27 79.25,86.43 79.25,88.31 TP1804.1
CPU_D5_TP: length 4.6
  BOTTOM w0.089: TP1805.1 78.9,86.08 78.91,86.07 78.91,83.74 78.84,83.68 78.84,83.67 78.8,83.59 78.8,83.39 78.85,83.29 78.85,83.12 79.06,82.84 CPU1.V2
CPU_D6_TP: length 3.8
  BOTTOM w0.089: CPU1.M1 75.75,84.05 75.61,84.19 75.61,84.36 75.61,84.36
  BOTTOM w0.102: TP1806.1 74.84,86.15 75.55,85.43 75.55,84.42 75.61,84.36
CPU_DP1_CTRL_CLK: length 86.1
  TOP w0.114: 75.13,78.35 75.13,77.77 v2(76.02,76.87) ; 75.13,78.35 75.13,80.85 74.35,81.63 v2(73.92,81.63) 73.37,82.18 RN801.3 ; 75.13,78.35 v1(74.99,78.35)
  L3 w0.114: v2(73.92,81.63) 73.92,81.95 73.74,82.13 73.74,85.21 74.11,85.58 74.11,91.65 72.49,93.27 69.51,93.27 68.15,91.91 68.15,91.16 67.69,90.7 67.04,90.7 66.28,91.47 63.4,91.47 61.31,93.55 50.62,93.55 48.82,91.74 44.18,91.74 43.97,91.53 v2(43.97,91.53)
  L6 w0.102: v2(43.97,91.53) 43.46,92.04 42.5,92.04 42.04,91.59 34.88,91.59 33.74,90.44 22,90.44 18.32,86.76 18.32,84.25 18.17,84.09 17.79,84.09 v2(17.53,84.35)
  BOTTOM w0.114: U5701.38 16.78,83.67 17.46,84.35 v2(17.53,84.35) ; v2(76.02,76.87) 75.69,76.53 CPU1.L13
CPU_DP1_CTRL_DATA: length 89.8
  TOP w0.114: 75.2,81.26 75.47,80.99 75.47,77.91 75.86,77.52 v2(76.03,77.52) ; 75.2,81.26 v1(75.34,81.4) ; 75.2,81.26 74.48,81.99 74.18,81.99 74.02,82.15 RN801.4
  L3 w0.114: v2(43.28,91.53) 43.84,92.09 48.67,92.09 50.48,93.89 61.46,93.89 63.54,91.81 66.42,91.81 67.19,91.05 67.55,91.05 67.81,91.3 67.81,92.05 69.37,93.61 72.63,93.61 74.45,91.79 74.45,85.44 74.08,85.07 74.08,82.27 75.06,81.3 75.06,78.61 75.6,78.07 75.6,77.96 v2(76.03,77.52)
  L6 w0.102: v2(43.28,91.53) 43.08,91.74 42.63,91.74 42.17,91.28 35.01,91.28 33.86,90.14 22.13,90.14 18.62,86.63 18.62,84.12 18.29,83.79 17.58,83.79 v2(17.51,83.71)
  BOTTOM w0.114: CPU1.L12 75.9,77.52 v2(76.03,77.52) ; U5701.39 17.18,83.38 v2(17.51,83.71)
CPU_DP1_HPD: length 87.1
  TOP w0.102: v2(74.59,95.19) 74.21,94.8 v1(74.03,94.8)
  L3 w0.102: v2(74.59,95.19) 74.59,95.17 73.77,94.35 73.77,93.24 74.99,92.01 74.99,89.46 75.48,88.98 75.48,84.16 75.6,84.04 75.6,79.26 v2(76.03,78.83)
  L6 w0.102: v2(74.59,95.19) 74.55,95.19 74.32,95.42 68.94,95.42 68.28,94.77 66.78,94.77 66.33,95.23 63.15,95.23 61.18,93.26 61.18,92.27 60.28,91.37 53.66,91.37 52.36,90.06 48.47,90.06 47.45,89.05 42.81,89.05 40.45,86.68 38.05,86.68 37.57,87.17 36.56,87.17 35.21,85.82 33.31,85.82 32.67,86.45 32.67,87.6 31.78,88.49 27.85,88.49 27.21,87.85 22.89,87.85 22,86.96 22,85.8 19.21,83.01 v2(19.21,81.43)
  BOTTOM w0.102: v2(76.03,78.83) 75.87,78.83 CPU1.L9 ; v2(19.21,81.43) 19.02,81.23 U5701.3
CPU_DP2_CTRL_CLK: length 2.8
  TOP w0.089: RN803.4 77.07,81.4 76.65,80.98 76.65,80.37 76.89,80.13 v2(77.07,80.13)
  BOTTOM w0.114: CPU1.N7 76.77,80.44 v2(77.07,80.13)
CPU_DP2_CTRL_DATA: length 3.3
  TOP w0.089: v2(77.03,79.48) 76.93,79.48 v1(76.56,79.85) 76.46,79.96 76.46,81.05 76.41,81.1 RN803.3
  BOTTOM w0.114: CPU1.N8 76.8,79.48 v2(77.03,79.48)
CPU_POPIRCOMP: length 4.5
  TOP w0.127: v1(90.41,74.16) 89.92,74.16 89.61,73.85 88.57,73.85 v2(88.12,74.3)
  TOP w0.508: R412.1 91.22,73.75 90.81,74.16 v1(90.41,74.16)
  BOTTOM w0.305: v2(88.12,74.3) 88.12,74.43 CPU1.AT16
CSI2_COMP: length 2.1
  TOP w0.508: R1501.1 71.98,77.69 v2(71.98,77.05) 71.67,77.05 71.35,76.72 v1(71.35,76.72)
  BOTTOM w0.406: v2(71.98,77.05) 72.03,76.99 72.03,76.81 72.26,76.58 CPU1.E13
CTL1: length 2.3
  BOTTOM w0.102: R3401.2 20,53.8 v1(20.76,53.8) 21.22,53.8 21.5,54.07 U3401.6
CTL2: length 2.4
  BOTTOM w0.102: U3401.7 21.37,54.57 20.93,55.01 v1(20.73,55.01) 20.68,54.96 R3406.2
CTL3: length 3.2
  BOTTOM w0.102: R3402.2 20.27,56.33 v1(20.63,56.33) 21.26,56.33 21.98,55.62 U3401.8
DAT_TP_SIO: length 87.3
  TOP w0.114: v2(111.03,22.7) 111.03,22.76 EC6502.1 110.27,23.53 v1(110.27,24.48) 110.27,25.49 110.7,25.93 RN6501.3 110.33,26.09 109.32,27.1 RN6502.1 ; v2(154.62,49.93) 154.24,49.93 152.75,48.44 151.26,48.44 150.5,49.2 147.27,49.2 146.14,48.07 KBC24.79
  L3 w0.114: v2(111.03,22.7) 111.17,22.7 111.61,23.14 115.54,23.14 116.65,22.03 121.24,22.03 122.84,20.43 126.03,20.43 126.6,19.86 130.61,19.86 131.86,21.11 131.86,22.75 132.19,23.08 132.96,23.08 137.53,27.66 138.13,27.66 138.41,27.66 139.24,28.49 140.56,28.49 140.58,28.51 151.01,28.51 151.73,29.23 151.73,32.45 150.35,33.83 150.35,35.97 150.8,36.42 150.8,36.62 151.64,37.47 151.64,37.8 154.12,40.28 154.12,42.53 154.78,43.18 154.78,43.7 154.79,43.71 154.79,44.49 154.62,44.67 v2(154.62,49.93)
DBC_EN_R: length 4.6
  BOTTOM w0.102: R5503.1 55.41,91.09 v1(55.03,91.48) 53.05,93.45 LCD1.22
DBC_PANEL_EN: length 52.9
  TOP w0.102: R2043.2 85.88,85.57 86.3,85.15 v2(86.6,85.15) ; v2(55.05,90.47) 55.42,90.85 v1(55.46,90.85)
  L3 w0.102: v2(86.6,85.15) 86.95,85.5 86.95,86.43 86.44,86.93 86.44,91.48 85.72,92.2 85.72,94.92 v2(85.25,95.39)
  L6 w0.102: v2(55.05,90.47) 55.21,90.64 60.6,90.64 62,92.03 62,92.92 63.69,94.62 65.97,94.62 66.43,94.16 68.53,94.16 69.19,94.81 73.54,94.81 74,94.35 75.04,94.35 75.56,94.86 84.74,94.86 85.05,95.17 85.05,95.19 v2(85.25,95.39)
  BOTTOM w0.089: CPU1.AM5 86.2,81.51 86.48,81.51 86.69,81.72 86.69,82.04 86.68,82.05 86.68,83.77 87.03,84.12 87.03,84.72 v2(86.6,85.15)
  BOTTOM w0.102: v2(55.05,90.47) 55.22,90.47 55.49,90.2 R5503.2
DC_IN_D: length 3.5
  TOP w0.508: 38.04,23.46 37.99,23.41 36.73,23.41 v1(36.48,23.66) 36.48,24.14 37.22,24.88 PQ4407.3
DCBATOUT: length 2.2
  TOP w0.203: PC4513.1 32.14,69.98 32.14,69.6 31.81,69.28 31.81,68.95 31.8,68.94 PU4503.12
  vias: v1(30.89,73.63) v1(38.39,63.21) v1(57.54,32.96) v1(59.6,94.33) v1(60.1,32.48) v1(139.35,40.99) v2(132.42,18.03) v2(133.31,18.03) v3(33.81,71.72) v3(39.15,72.74) v3(39.15,71.85) v3(39.15,70.96) v3(39.15,70.07) v3(39.53,78.07) v3(39.53,77.06) v3(39.88,82.77) v3(39.88,81.76) v3(40.04,72.74) v3(40.04,71.85) v3(40.04,70.96) v3(40.04,70.07) v3(40.04,58.51) v3(40.04,57.63) v3(40.42,78.07) v3(40.42,77.06) v3(40.77,82.77) v3(40.77,81.76) v3(40.8,54.45) v3(40.8,53.56) v3(40.93,58.51) v3(40.93,57.63) v3(41.69,54.45) v3(41.69,53.56) v3(43.26,44.64) v3(43.26,43.76) v3(43.26,42.87) v3(43.26,41.98) v3(44.1,44.67) v3(44.1,43.78) v3(44.15,42.87) v3(44.15,41.98) v3(44.99,44.67) v3(44.99,43.78) v3(44.99,42.89) v3(44.99,42) v3(60.74,27.91) v3(60.74,27.02) v3(61.63,27.91) v3(61.63,27.02) v3(64.68,31.46) v3(64.68,30.57) v3(65.06,28.03) v3(65.06,27.15) v3(65.06,26.26) v3(65.06,21.94) v3(65.56,31.46) v3(65.56,30.57) v3(65.95,28.03) v3(65.95,27.15) v3(65.95,26.26) v3(65.95,21.94) v3(66.83,28.03) v3(66.83,27.15) v3(66.83,26.26) v3(66.83,21.94) v3(66.96,31.46) v3(66.96,30.57) v3(67.72,28.03) v3(67.72,27.15) v3(67.72,26.26) v3(67.85,31.46) v3(67.85,30.57) v3(107.73,17.75) v3(108.62,17.75)
DCBATOUT_LCD:
  vias: v1(64.4,94.74) v3(64.3,93.81) v3(65.17,93.83)
DCIN_EN: length 4.7
  BOTTOM w0.102: U5701.13 16.78,77.04 16.67,76.93 16.67,76.67 17.4,75.94 18.36,75.94 R5419.2 19.68,75.47 v1(19.74,75.41)
DDC_CLK_HDMI: length 18.6
  TOP w0.114: HDMI1.15 9.18,86.4 9.18,87.27 9.57,87.67 11.78,87.67 11.94,87.5 13.81,87.5 R5707.2 14.85,88.53 14.85,88.94 15.1,89.19 15.16,89.25 16.57,89.25 16.68,89.14 16.68,88.23 15.89,87.45 15.44,87.45 15.16,87.17 15.16,86.26 15.46,85.97 15.46,85.4 v1(15.2,85.14) 15.2,84.5 v2(14.81,84.12)
  BOTTOM w0.114: v2(14.81,84.12) 14.38,83.68 U5701.32
DDC_CLK_PH1: length 10.4
  TOP w0.114: D5701.2 18.05,86.72 18.58,87.24 18.58,87.25 18.93,87.6 v1(18.93,89.66) 15.04,89.66 14.31,88.92 R5707.1
DDC_DATA_HDMI: length 9.7
  TOP w0.114: v2(14.97,85.77) 14.47,86.26 R5706.2 14.24,86.33 10.11,86.33 HDMI1.16
  BOTTOM w0.114: v1(15.58,85.31) 15.58,85.52 15.33,85.77 v2(14.97,85.77) 14.97,85.21 15.27,84.91 15.27,83.91 14.78,83.42 U5701.33
DDC_DATA_PH2: length 2.2
  TOP w0.114: D5701.1 14.39,87.15 R5706.1
DDCBUF: length 3.4
  BOTTOM w0.102: U5701.14 16.38,76.46 v1(16.47,76.37) 16.47,76.02 16.5,76.02 R5417.2 R5418.2
DDR0_PAR: length 1.4
  TOP w0.102: TP501.1 87.31,55.11 v2(88.07,55.11)
  BOTTOM w0.102: CPU1.AT52 88.34,54.74 88.34,54.84 v2(88.07,55.11)
DDR1_PAR: length 1.2
  TOP w0.102: TP502.1 87.51,59.61 v2(87.51,59.68)
  BOTTOM w0.102: CPU1.AP43 87.15,59.32 87.5,59.68 v2(87.51,59.68)
DDR3_DRAMRST#: length 4.6
  TOP w0.102: v2(128.44,43.05) 128.44,42.4 v1(128.43,42.39) 128.3,42.26 ED1217.1 126.97,42.77 R1204.2
  BOTTOM w0.102: DIMM1.30 v2(128.44,43.05)
DDR_VREF_S3: length 3.5
  BOTTOM w0.305: PU5102.6 133.78,79.95 133.79,79.96 133.79,81.41 PC5116.1
  BOTTOM w0.508: R4204.1 136.24,67.53 v2(135.9,67.53) ; PC5116.1 133.7,81.69 v2(133.13,82.26)
  vias: v1(129.95,47.34)
DMIC_CLK: length 127
  TOP w0.114: R5504.2 56.29,100.17 55.95,100.51 ; v2(55.53,103.35) 55.59,103.28 EC5504.1 55.4,101.89 55.4,101.06 55.95,100.51 ; v2(29.12,28.67) 28.96,28.52 28.65,28.52 R2716.2 ; v1(56.06,100.63) 55.95,100.51
  L4 w0.114: v2(13.49,93.31) 12.57,92.39 12.57,88.96 11.97,88.35 11.97,88.26 11.97,85.18 11.4,84.62 11.4,80.04 12.75,78.69 12.75,78.03 11.86,77.14 11.86,73.21 13.36,71.71 13.36,71.04 13.89,70.51 13.89,70.48 13.89,67.19 14.45,66.63 14.45,64.58 15.67,63.36 15.67,58.19 14.96,57.48 14.96,56.01 15.49,55.47 15.49,46.35 16.51,45.34 16.51,43.93 16.76,43.68 16.76,41.26 16.82,41.21 16.82,40.71 18.67,38.85 20.93,38.85 24.61,35.17 24.61,33.82 29.12,29.32 v2(29.12,28.67)
  L6 w0.102: v2(55.53,103.35) 55.1,102.91 54.46,102.91 54.16,103.22 35.44,103.22 35.13,102.91 35.13,102.91 32.29,100.07 31.53,100.07 31.22,99.76 29.76,98.3 26.79,98.3 25.94,97.45 22.91,97.45 18.97,93.52 13.7,93.52 v2(13.49,93.31)
DMIC_CLK_C: length 5.7
  TOP w0.114: 55.51,97.35 56.05,97.9 56.05,98.6 R5504.1 ; 55.51,97.35 v1(55.61,97.25) ; 55.51,97.35 54.97,96.81 54.97,96.29 v2(55.15,96.11)
  BOTTOM w0.114: v2(55.15,96.11) 54.97,95.93 54.97,94.96 55.05,94.88 LCD1.18
DMIC_CLK_R: length 3.8
  TOP w0.114: R2716.1 26.65,28.29 v1(25.97,27.6) 25.08,26.71 HDA27.10
DMIC_DATA: length 132
  TOP w0.114: v1(54.92,101.14) 55.06,101.14 ; 55.06,101.14 55.06,100.92 55.4,100.57 R5505.2 ; 55.06,101.14 55.06,101.72 EC5503.1 54.71,103.16 v2(54.9,103.35) ; v2(28.99,24.1) 29.94,24.1 R2714.2
  L4 w0.114: v2(28.99,24.1) 29.55,24.66 29.55,27.6 28.61,28.54 28.61,29.34 24.27,33.68 24.27,35.02 20.79,38.51 18.53,38.51 16.47,40.56 16.47,41.07 16.42,41.12 16.42,43.54 16.16,43.8 16.16,45.2 15.15,46.21 15.15,53.4 14.62,53.94 14.62,57.62 15.33,58.33 15.33,63.21 14.1,64.44 14.1,66.49 13.55,67.05 13.55,70.36 13.54,70.37 13.02,70.89 13.02,71.56 11.52,73.06 11.52,77.28 12.41,78.17 12.41,78.55 11.06,79.9 11.06,84.76 11.62,85.32 11.62,88.4 11.62,88.4 11.62,88.49 12.23,89.1 12.23,92.68 v2(12.86,93.31)
  L6 w0.102: v2(54.9,103.35) 54.7,103.54 35.28,103.54 32.19,100.45 31.43,100.45 29.62,98.65 26.7,98.65 25.81,97.76 22.77,97.76 18.83,93.82 13.37,93.82 v2(12.86,93.31)
DMIC_DATA_C: length 5.6
  TOP w0.114: 54.62,96.67 54.62,96.95 55.71,98.04 55.71,98.53 R5505.1 ; 54.62,96.67 54.62,96.21 v2(54.52,96.11) ; 54.62,96.67 v1(54.49,96.67)
  BOTTOM w0.114: v2(54.52,96.11) 54.63,95.99 54.63,94.96 54.55,94.88 LCD1.19
DMIC_DATA_R: length 7
  TOP w0.114: R2714.1 29.81,24.86 28.86,24.86 28.56,25.16 27.7,25.16 27.56,25.3 27.47,25.3 EC2701.1 26.91,25.86 26.91,26.41 v1(26.75,26.56) 26.47,26.56 25.83,25.91 HDA27.8
DS3_PWRCTL: length 6.9
  TOP w0.102: R4102.2 77.06,111.97 77.48,111.55 v1(77.48,110.69) 76.36,109.57 74.24,109.57 73.99,109.82 U4101.4
E51_TXD_R: length 39.4
  TOP w0.102: v2(119.01,20.82) 119.08,20.9 119.08,21.28 119.55,21.75 R2482.1 ; JTAG1.8 132.96,20.91 134.74,22.7 v2(134.8,22.7) 134.93,22.83 v1(134.93,23.68) 134.93,24.39 R2467.1
  L4 w0.102: v2(134.8,22.7) 135.06,22.95 136,22.95 136.33,22.62 136.33,21.08 135.64,20.39 128.1,20.39 127.8,20.08 127.44,20.08 127.13,20.39 119.44,20.39 v2(119.01,20.82)
  BOTTOM w0.102: v2(119.01,20.82) 119.42,20.41 119.81,20.41 120.07,20.67 120.07,20.83 120.35,21.1 121.55,21.1 121.9,20.75 127.2,20.75 127.55,21.1 128.1,21.1 128.29,20.91 DB3.5
E71_TP: length 4.9
  BOTTOM w0.102: CPU1.E71 72,40.31 72.23,40.09 72.23,39.7 72.48,39.45 72.91,39.45 TP2313.1
EAPD#: length 7.1
  TOP w0.102: R2704.1 29.2,30.17 v1(28.58,30.17) 27.97,30.17 27.53,29.72 R2723.2 26.98,28.63 26.4,28.63 24.89,27.11 HDA27.11
EC5048_TX: length 5.8
  TOP w0.114: R2453.2 136.15,24.42 v1(136.15,23.69) 136.15,23.43 135.41,22.69 135.41,22.69 135.15,22.43 135.15,22.43 134.99,22.26 134.62,22.26 133.46,21.1 JTAG1.9
EC_AGND: length 27.6
  TOP w0.203: KBC24.112 152.36,40.51 152.74,40.89 v2(153.68,40.89)
  TOP w0.356: v2(149.27,36.83) 149.32,36.78 C2427.2
  TOP w0.381: R2445.2 144.25,32.92 v1(144.68,33.35) 145.06,33.73 145.69,33.73 R2444.2
  TOP w0.508: C2408.1 v2(146.75,34.6) ; v2(146.75,34.6) 146.46,34.89 C2435.2 ; v2(146.75,34.6) 146.4,34.6 145.72,33.92 145.72,33.8 R2444.2 ; C2427.2 149.78,35.7 C2441.2 ; C2422.2 151.94,36.8 v2(151.94,35.96)
  L4 w0.508: v2(151.94,35.96) 151.62,35.96 150.65,34.99 150.65,34.39 149.66,33.4 147.5,33.4 146.75,34.16 v2(146.75,34.6) 146.91,34.6 149.13,36.83 v2(149.27,36.83)
  L6 w0.508: v2(153.68,40.89) 153.49,40.89 153.13,40.53 153.13,39.45 153.49,39.09 153.49,37.4 v2(151.94,35.96)
EC_MUTE#: length 162.8
  TOP w0.102: v1(30.08,30.7) v2(30.64,30.7) 30.64,29.75 R2704.2 ; v2(155.78,38.18) 155.74,38.18 155.16,38.77 KBC24.119
  L3 w0.102: v2(155.78,38.18) 155.75,38.16 155.75,38.16 154.77,37.18 154.77,34.04 155.2,33.61 155.2,29.77 153.98,28.55 152.3,28.55 151.15,27.39 v2(146.01,27.39)
  L6 w0.102: v2(146.01,27.39) 145.86,27.39 141.06,22.6 136.98,22.6 135.77,23.81 135.77,28.81 135.38,29.2 133.88,29.2 132.09,30.99 127.59,30.99 127.18,30.58 127.18,24.09 126.66,23.56 124.11,23.56 123.76,23.21 118.24,23.21 117.8,23.64 117.05,23.64 116.85,23.44 108.87,23.44 107.93,22.5 106.19,22.5 105.79,22.89 103.24,22.89 102.37,23.76 96.6,23.76 94.98,22.14 93.1,22.14 93.07,22.12 88.62,22.12 87.98,22.75 86.97,22.75 83.16,26.56 83.16,26.56 80.98,26.56 78.7,28.85 78.7,31.12 77.69,32.12 62.44,32.12 59.67,29.36 46.31,29.36 45.91,28.95 39.58,28.95 39.1,29.43 33.86,29.43 32.66,30.64 30.7,30.64 v2(30.64,30.7)
EC_SPI_CLK: length 5
  TOP w0.114: KBC24.32 160.31,55.63 161.58,56.9 v1(161.58,57.12) 161.58,57.94 R2485.2
EC_SPI_CS0#: length 85.4
  TOP w0.114: v2(117.89,106.14) 117.95,106.08 R2490.2 ; v2(129.14,103.35) 129.98,102.51 130.88,102.51 132.01,102.51 133.23,101.3 133.23,101.21 134.49,99.95 134.87,99.95 136.96,97.86 136.96,97.34 139.4,94.9 v1(139.4,94.44) 139.4,86.33 139.55,86.18 139.55,85.52 140.34,84.73 140.34,84.14 R2491.2 140.81,83.62 141.84,82.59 141.84,81.02 148.51,74.35 148.51,73.84 155.83,66.52 156.62,66.52 156.62,66.52 160.99,62.15 161.91,62.15 165.14,58.91 165.14,56.86 164.68,56.4 163.69,56.4 161.99,54.7 161.99,52.99 161.99,52.99 161.99,52.69 161.99,52.69 161.99,52.38 161.27,51.67 KBC24.27
  BOTTOM w0.114: v2(129.14,103.35) 129.12,103.33 125.5,103.33 123.93,104.9 119.13,104.9 v2(117.89,106.14)
EC_SPI_MISO: length 7
  TOP w0.114: KBC24.29 161.03,52.47 161.25,52.69 161.25,55.09 v1(162.3,56.13) 162.59,56.43 R2487.2
EC_SPI_MOSI: length 7.8
  TOP w0.114: KBC24.28 161.15,52.07 161.62,52.54 161.62,54.94 163.43,56.75 v1(163.43,57.17) 163.43,58.03 R2486.2
EC_VTT: length 116.5
  TOP w0.203: 142.15,41.4 142.15,41.63 142.45,41.94 143.49,41.94 143.77,41.67 KBC24.95
  TOP w0.508: 142.15,41.4 142.15,40.8 C2406.1 142.34,40.61 142.34,40.13 142.72,39.75 R2492.2 142.72,38.48 142.7,38.46 142.7,37.93 142.72,37.91 R2402.2 142.72,37.37 142.27,36.92 140.6,36.92 v1(139.53,35.86) 138.47,34.8 138.47,29.2 138.84,28.82 138.84,27.61 138.51,27.28 138.51,26 138.64,25.87 138.64,24.9 138.61,24.76 v2(138.61,24.73)
  L3 w0.508: v2(91.35,24.35) 91.68,24.68 94.41,24.68 95.84,23.25 95.84,22.92 97.13,21.63 99.3,21.63 99.85,22.19 105.07,22.19 105.71,21.56 106.76,21.56 107.45,20.87 114.88,20.87 117.55,18.2 131.1,18.2 131.68,18.79 135.63,18.79 138.44,21.6 138.44,23.8 138.61,23.97 138.61,24.73 v2(138.61,24.73)
  L4 w0.508: v2(63.38,39.26) 63.68,38.96 63.68,38.95 63.9,38.73 63.9,37.63 66.11,35.42 66.54,35.42 69.72,32.24 69.72,32.24 70.44,31.51 70.44,29.21 73.06,26.59 82.56,26.59 85.68,23.46 91.09,23.46 91.47,23.84 91.47,24.22 v2(91.35,24.35)
  BOTTOM w0.508: R2440.2 63.82,39.24 63.6,39.24 63.58,39.26 v2(63.38,39.26)
EC_WAKE#: length 127.5
  TOP w0.102: KBC24.35 157.96,52.53 153.53,48.1 150.28,48.1 149.52,48.86 148.39,48.86 148.04,48.51 v2(147.38,48.51) ; R1732.1 93.95,75.72 94.6,75.07 95.33,75.07 95.74,74.66 96.59,74.66 97.16,75.23 97.87,75.23 98.36,75.71 104.31,75.71 104.62,76.02 105.08,76.02 116.44,87.38 v1(116.44,94.68) 116.44,95.68 v2(116.87,96.11)
  L4 w0.102: v2(116.87,96.11) 119.11,98.34 122.46,98.34 122.82,98.7 124.34,98.7 124.89,98.14 126.74,98.14 127.03,98.44 127.75,98.44 129.02,97.17 129.02,96.83 131.22,94.62 131.22,86.08 131.17,86.02 131.17,85.59 131.65,85.11 131.65,84.45 131.41,84.21 131.41,73.61 132.44,72.58 132.44,66.31 137.52,61.23 137.52,57.2 138.83,55.89 141.14,55.89 141.87,56.62 142.88,56.62 143.23,56.28 143.23,52.4 147.12,48.51 v2(147.38,48.51)
ECVBAT: length 6.5
  TOP w0.203: 157.61,38.33 157.22,38.73 156.56,38.73 156.36,38.93 KBC24.122
  TOP w0.508: R2472.1 158.78,35.85 R2451.2 R2496.2 158.66,36.86 C2428.1 v1(157.89,37.76) 157.89,38.05 157.61,38.33
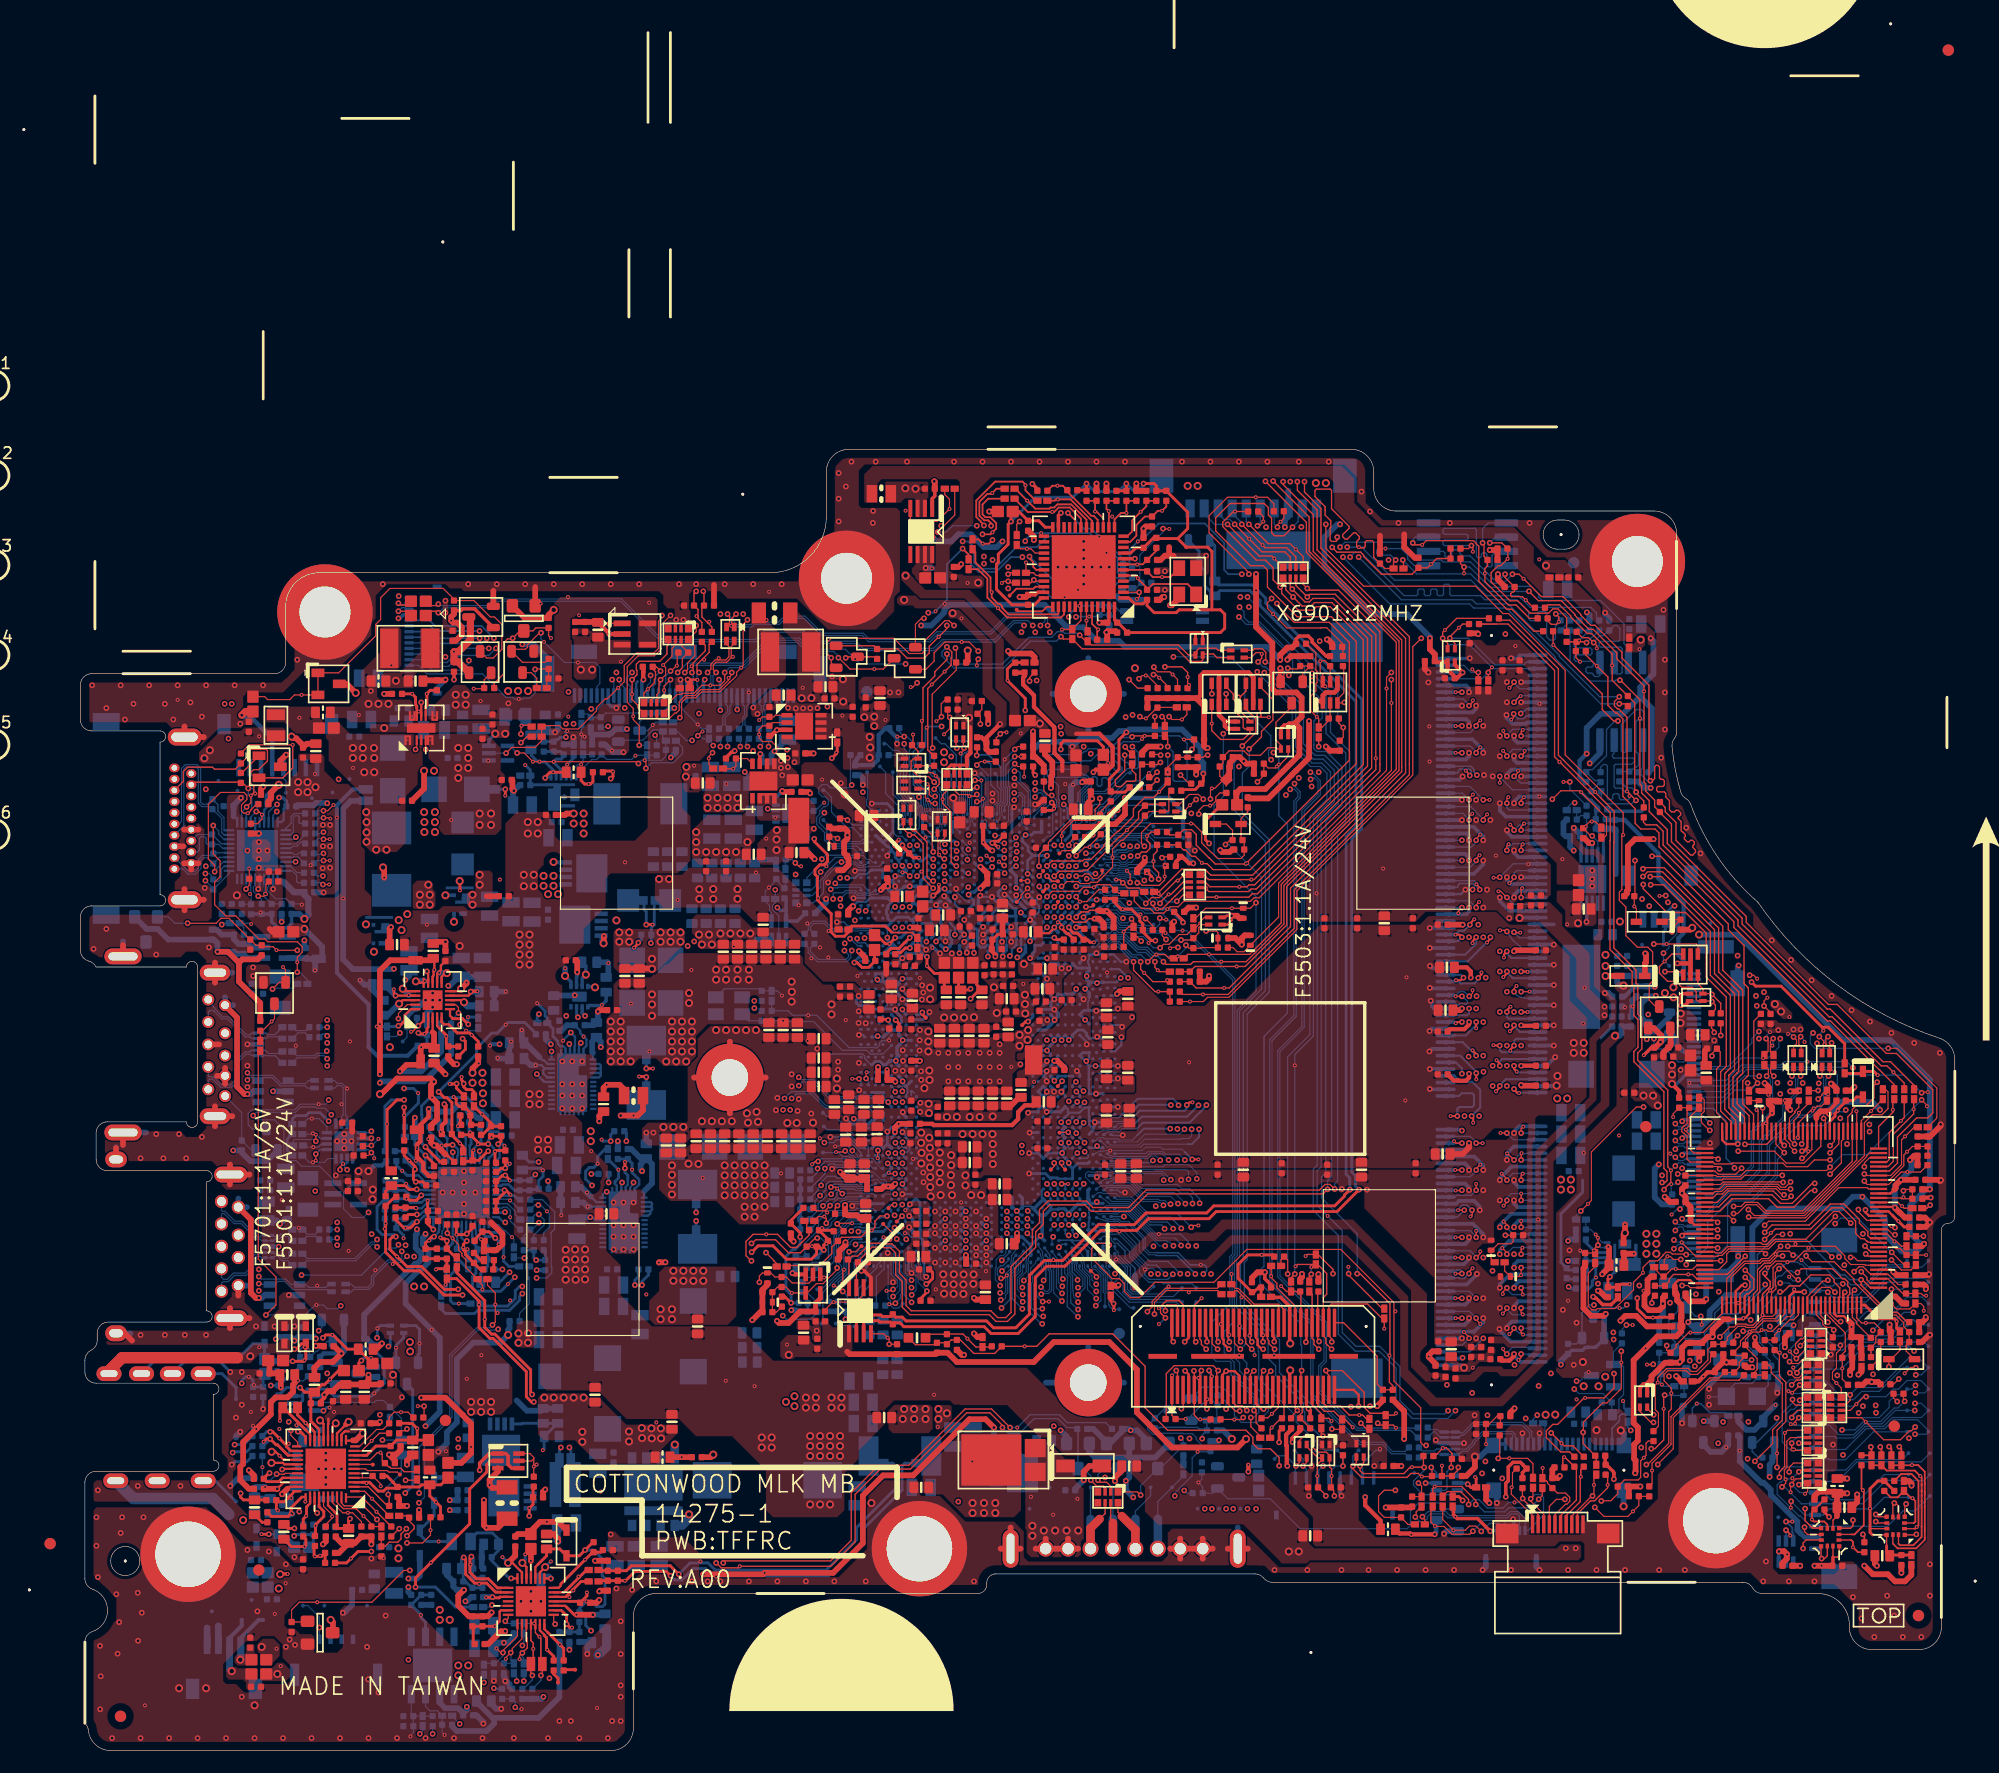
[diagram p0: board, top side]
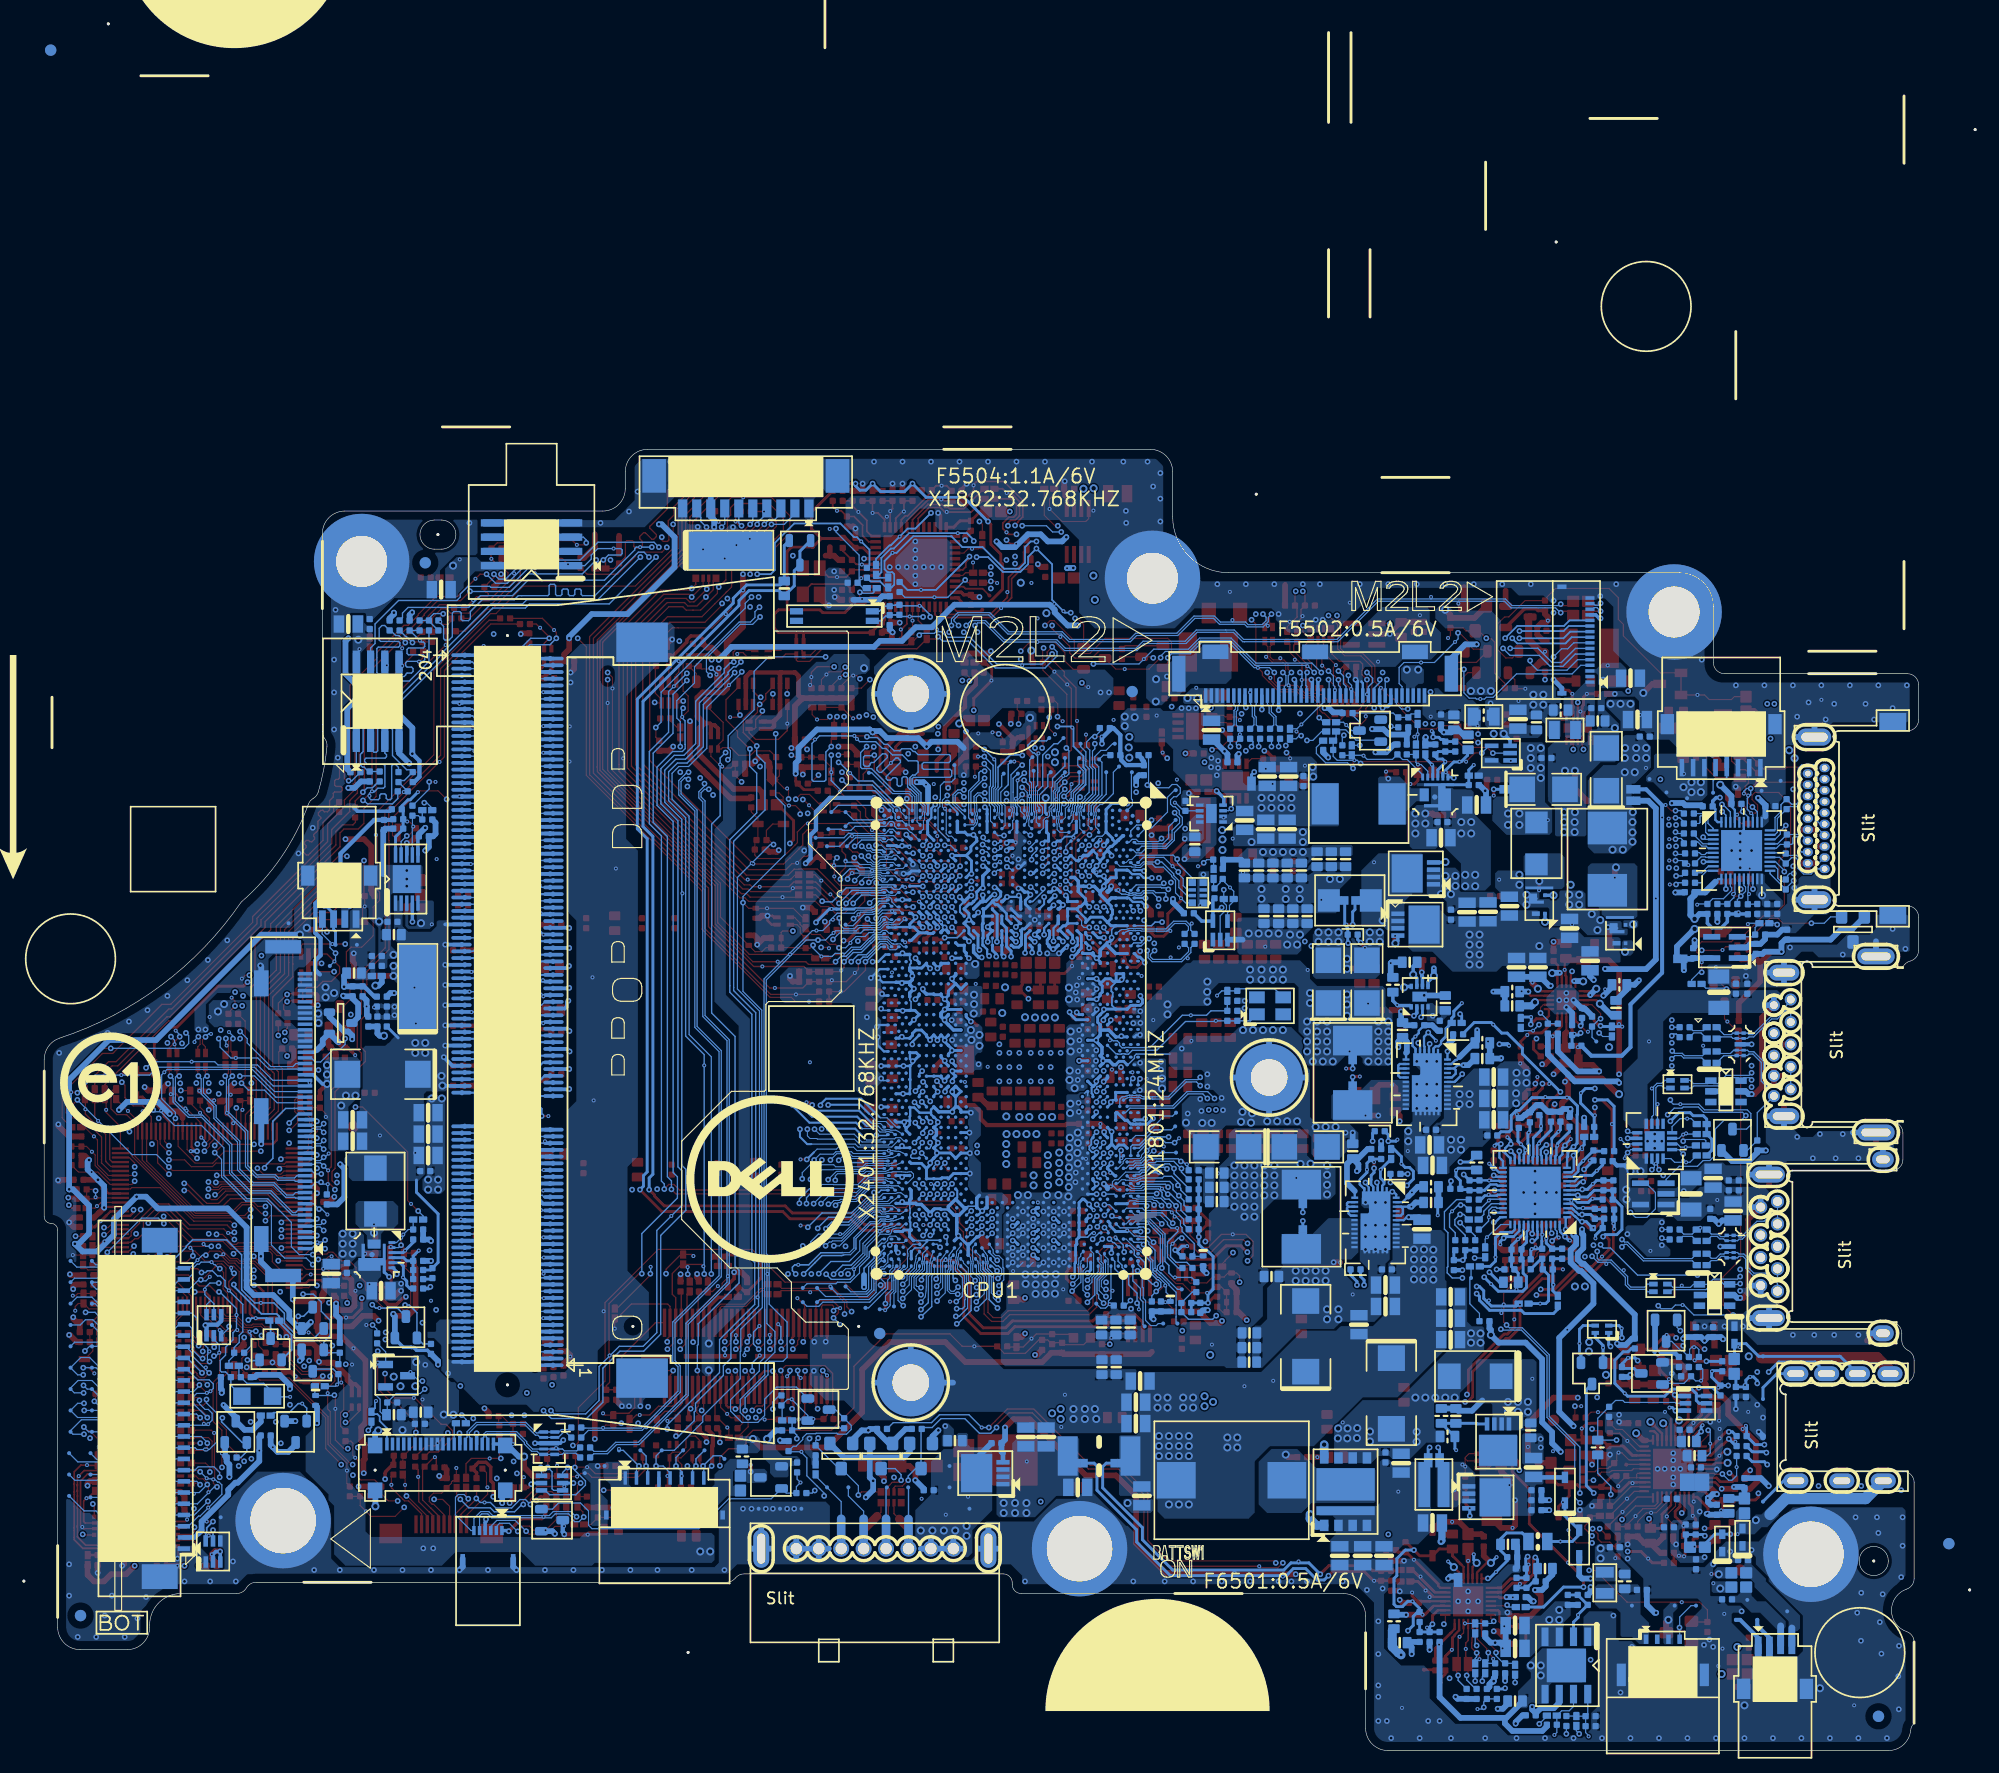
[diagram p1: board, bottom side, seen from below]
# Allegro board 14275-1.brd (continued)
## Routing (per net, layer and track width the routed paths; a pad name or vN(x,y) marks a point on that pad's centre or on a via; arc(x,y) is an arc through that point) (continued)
EDP_AUX: length 3.3
  BOTTOM w0.102: C5510.1 57.49,91.42 57.49,92.09 57.9,92.51 57.9,93.11 58.05,93.25 LCD1.12
EDP_AUX#: length 3.3
  BOTTOM w0.102: LCD1.13 57.55,93.25 57.7,93.11 57.7,92.59 57.28,92.18 57.28,91.45 C5511.1
EDP_AUX_DN: length 47.7
  L4 w0.102: v2(72.65,57.82) 72.93,57.54 72.93,57.43 72.55,57.05 71.34,57.05 70.73,57.65 63.65,57.65 63.56,57.56 63.09,57.56 v2(62.64,57.12)
  L6 w0.102: v2(62.64,57.12) 62.24,57.52 61.84,57.52 61.16,58.21 61.16,64.2 60.59,64.77 60.59,73.37 60,73.95 60,85.11 57.26,87.85 57.26,88.92 57.06,89.12 v2(57.06,89.5)
  BOTTOM w0.102: C5511.2 57.06,90.07 v2(57.06,89.5) ; v2(72.65,57.82) 72.65,57.95 CPU1.E45
EDP_AUX_DP: length 47.7
  L4 w0.102: v2(73.29,57.82) 73.13,57.66 73.13,57.35 72.63,56.85 71.25,56.85 70.65,57.45 63.74,57.45 63.41,57.12 v2(63.28,57.12)
  L6 w0.102: v2(57.69,89.5) 57.69,89.11 57.47,88.89 57.47,87.94 60.22,85.2 60.22,74.04 60.8,73.46 60.8,64.86 61.37,64.29 61.37,58.3 61.93,57.74 62.43,57.74 62.61,57.56 62.84,57.56 v2(63.28,57.12)
  BOTTOM w0.102: v2(73.29,57.82) 73.29,57.96 CPU1.F45 ; v2(57.69,89.5) 57.69,90.07 C5510.2
EDP_COMP: length 2.5
  TOP w0.508: R801.2 72.96,55.87 v1(72.94,55.86) 72.61,55.53 v2(72.61,55.14)
  BOTTOM w0.254: v2(72.61,55.14) 72.61,55.14 72.61,54.94 CPU1.E52
EDP_DISP_UTIL: length 5.1
  BOTTOM w0.102: CPU1.B52 69.79,54.83 68.99,54.83 67.27,56.56 66.5,56.56 TP801.1
EDP_HPD: length 46.5
  TOP w0.102: v2(53.25,96.11) 53.66,96.52 53.66,97.35 R5506.2 53.55,98.54 RN5502.7
  L3 w0.102: v2(76.03,78.16) 75.39,78.8 75.39,83.92 75.19,84.13 75.19,88.89 74.79,89.29 74.79,91.93 73.51,93.21 73.51,96.81 v2(73.57,96.87)
  BOTTOM w0.102: v2(76.03,78.16) 75.71,78.48 CPU1.L10 ; v2(73.57,96.87) 69.5,96.87 v1(69.07,97.3) 68.19,98.18 65.1,98.18 64.1,99.18 61.3,99.18 59.07,96.95 54.08,96.95 v2(53.25,96.11)
EDP_HPD_CONN: length 4.4
  TOP w0.102: v2(52.61,96.23) 52.65,96.23 53.13,96.72 v1(53.17,96.72) 53.2,96.75 53.2,97.78 R5506.1
  BOTTOM w0.102: v2(52.61,96.23) 52.17,95.8 52.17,94.96 52.05,94.84 LCD1.24
EDP_TX0: length 3.2
  BOTTOM w0.102: LCD1.10 59.05,93.25 59.2,93.11 59.2,92.28 59.05,92.13 59.05,91.43 C5509.1
EDP_TX0#: length 3.2
  BOTTOM w0.102: LCD1.9 59.55,93.25 59.4,93.11 59.4,92.19 59.25,92.04 59.25,91.43 C5506.1
EDP_TX0_DN: length 42.4
  L6 w0.102: v2(63.41,58.13) 63.15,58.39 63.15,58.64 62.1,59.7 62.1,64.45 61.42,65.12 61.42,73.71 60.84,74.3 60.84,86.86 60.19,87.51 60.19,87.89 59.21,88.87 59.21,89.25 v2(59.47,89.5)
  BOTTOM w0.102: C5506.2 59.34,89.95 59.34,89.63 v2(59.47,89.5) ; CPU1.C47 70.71,56.86 70.31,57.27 66.4,57.27 65.13,58.54 63.81,58.54 v2(63.41,58.13)
EDP_TX0_DP: length 42.5
  L6 w0.102: v2(62.77,58.13) 62.94,58.3 62.94,58.55 61.88,59.61 61.88,64.36 61.21,65.03 61.21,73.62 60.62,74.21 60.62,86.77 59.97,87.42 59.97,87.8 59,88.78 59,89.34 v2(58.83,89.5)
  BOTTOM w0.102: C5509.2 58.83,90.07 v2(58.83,89.5) ; v2(62.77,58.13) 63.38,58.74 65.22,58.74 66.49,57.47 70.52,57.47 CPU1.C46
EDP_TX1: length 3.2
  BOTTOM w0.102: C5504.1 60.83,91.43 60.83,92.63 60.7,92.76 60.7,93.11 60.55,93.25 LCD1.7
EDP_TX1#: length 3.2
  BOTTOM w0.102: LCD1.6 61.05,93.25 60.9,93.11 60.9,92.84 61.03,92.72 61.03,91.43 C5501.1
EDP_TX1_DN: length 41.2
  L6 w0.102: v2(61.35,89.5) 61.35,89.07 61.46,88.96 61.46,85.03 62.05,84.45 62.05,83.27 61.46,82.68 61.46,74.56 62.05,73.97 62.05,65.46 62.72,64.79 62.72,60.37 63.23,59.86 63.88,59.86 v2(64.04,60.02)
  BOTTOM w0.089: CPU1.D46 71.21,58.08 71.04,58.25 70.96,58.29 70.85,58.29 arc(70.83,58.29) 70.81,58.29 70.55,58.37 70.41,58.41 arc(70.39,58.41) 70.38,58.42 70.36,58.42 arc(70.35,58.43) 70.34,58.43 70.08,58.43 arc(70.06,58.42) 70.03,58.41 70.03,58.41 arc(70,58.4) 69.97,58.39 69.89,58.39 arc(69.85,58.39) 69.82,58.4 69.77,58.42 arc(69.75,58.43) 69.73,58.43 69.43,58.43 arc(69.35,58.41) 69.28,58.37 arc(69.18,58.3) 69.06,58.27 68.32,58.27 68.31,58.28 68.29,58.28
  BOTTOM w0.102: C5501.2 61.37,89.53 v2(61.35,89.5) ; v2(64.04,60.02) 64.25,59.81 65.37,59.81 66.89,58.28 68.29,58.28
EDP_TX1_DP: length 41.1
  L6 w0.102: v2(64.04,59.28) 63.67,59.65 63.14,59.65 62.5,60.28 62.5,64.7 61.83,65.37 61.83,73.88 61.25,74.47 61.25,82.77 61.83,83.36 61.83,84.36 61.25,84.94 61.25,88.87 v2(60.61,89.5)
  BOTTOM w0.089: CPU1.C45 70.66,58.11 70.58,58.17 70.32,58.25 70.13,58.25 70.04,58.21 69.79,58.21 69.69,58.25 69.51,58.25 arc(69.43,58.23) 69.36,58.19 arc(69.26,58.12) 69.14,58.09 68.32,58.09 68.31,58.08 68.29,58.08
  BOTTOM w0.102: C5504.2 60.83,89.86 60.83,89.72 v2(60.61,89.5) ; 68.29,58.08 66.81,58.08 65.28,59.61 64.37,59.61 v2(64.04,59.28)
EDP_VDD_EN: length 30.9
  TOP w0.102: v2(80.04,98.01) 79.23,98.82 v1(78.57,98.82) 77.07,98.82 76.11,97.86 76.11,97.12 75.37,96.39 D5501.1
  L3 w0.102: v2(79.16,76.98) 79.66,76.98 80.72,78.03 80.72,90.56 81.36,91.2 81.36,96.69 v2(80.04,98.01)
  BOTTOM w0.102: CPU1.U13 79.08,76.98 v2(79.16,76.98)
EDRAM_OPIO_RCOMP: length 0.6
  BOTTOM w0.305: CPU1.H66 74.2,46.33 v2(73.88,46.65)
  vias: v1(73.51,46.13)
EMMC_RCOMP: length 4.4
  TOP w0.508: R1502.1 89.38,86.39 v2(89.31,86.33)
  BOTTOM w0.203: CPU1.AT1 88.31,83.53 88.31,84.55
  BOTTOM w0.508: 88.31,84.55 88.31,85.93 v1(88.49,86.11) 88.7,86.33 v2(89.31,86.33)
EOPIO_RCOMP: length 0.6
  BOTTOM w0.305: CPU1.H65 74.2,47.35 v2(73.89,47.65)
  vias: v1(73.54,48.18)
EQ: length 3.2
  BOTTOM w0.102: R5412.2 R5411.2 15.22,76.26 v1(15.12,76.36) 15.12,76.4 15.2,76.47 15.2,76.98 15.18,77 U5701.17
EXT_PWR_GATE#: length 53.9
  TOP w0.102: v2(90.87,84.88) 90.87,84.33 90.46,83.91 90.46,83.25 90.34,83.13 88.46,83.13 86.29,80.97 86.29,80.7 R1731.2 85.45,79.86 v2(85.45,78.84) ; v2(56.35,88.96) 56.02,88.63 v1(56.02,88.45) 56.02,87.93 R1733.1
  L6 w0.102: v2(56.35,88.96) 56.35,89.05 55.98,89.41 55.98,89.89 56.17,90.09 61.95,90.09 62.43,89.6 62.43,88.99 61.88,88.44 61.88,86.76 62.62,86.02 65.36,86.02 67.57,83.81 68.8,83.81 69.37,83.24 69.78,83.24 72.16,83.24 72.81,83.89 74.14,83.89 81.9,83.89 82.12,83.67 84.06,83.67 84.3,83.91 87.84,83.91 88.35,84.42 90.44,84.42 90.87,84.85 v2(90.87,84.88)
  BOTTOM w0.102: v2(85.45,78.84) 85.45,78.81 CPU1.AM10
FALL_INT2: length 4.4
  TOP w0.508: v2(151.42,17.75) 151.44,17.77 151.88,17.77 v1(152.16,17.49) 152.12,17.46 152.12,17.09 151.73,16.71 R7018.2
  BOTTOM w0.305: Q7001.3 151.4,17.73 v2(151.42,17.75) 151.8,17.75 152.05,17.49 Q7001.2
FAN1_PWM: length 4.1
  TOP w0.102: R2614.1 155.21,57.45 154.81,57.45 v1(154.41,57.05) 154.24,57.05 153.16,55.96 KBC24.47
FAN1_TACH: length 5
  TOP w0.203: 155.96,56.09 KBC24.40
  TOP w0.254: 155.96,56.09 156.42,56.55 156.42,56.79 v1(156.67,57.04) 156.67,57.16 157.39,57.87 R2430.1 158.02,57.94 158.34,58.26 D2403.A
FAN_PWM1_C: length 28.5
  TOP w0.102: v2(154.92,58.08) 155.25,58.41 155.25,58.49 155.6,58.83 R2614.2
  L4 w0.102: v2(154.92,58.08) 154.11,58.89 154.11,61.34 152.09,63.36 152.09,65.09 152.2,65.21 152.2,66.19 150.33,68.06 146.3,68.06 143.5,70.86 141.36,70.86 v2(141.13,71.09)
  BOTTOM w0.102: FAN1.4 142.3,73.19 142.32,73.17 142.32,72.8 141.62,72.1 141.62,71.58 v2(141.13,71.09) 141.13,70.45 AFTP2602.1
FAN_TACH1: length 3.2
  TOP w0.254: R2613.1 157.31,60.36 158.72,60.36 D2403.K 159.89,60.55 160.2,60.24 160.21,60.24 v1(160.23,60.22)
FAN_TACH1_C: length 27.6
  TOP w0.254: v2(148.98,68.51) 149.34,68.15 151.61,68.15 155.28,64.48 155.82,64.48 157.28,63.02 R2613.2
  L3 w0.254: v2(148.98,68.51) 148.97,68.51 148.12,68.51 147.23,69.4 147.23,72.18 144.63,74.77 142.65,74.77 v2(142.12,75.3)
  BOTTOM w0.254: v2(142.12,75.3) 141.99,75.3 141.3,74.61 FAN1.3 141.3,73.18 141.13,73.01 AFTP2601.1
FAN_VCC_1: length 2.1
  TOP w0.508: v2(139.5,71.06) 139.58,70.99 139.58,70.27 139.48,70.17 139.48,69.08 D2601.K
FFS_INT1_D: length 8
  TOP w0.114: U7002.12 157.89,19.27
  TOP w0.152: R7015.1 158.78,23.34 v1(158.91,23.21) 158.91,23.15 158.99,23.07 158.99,20.1 158.15,19.27 157.89,19.27
FFS_INT2: length 150.6
  TOP w0.152: v2(79.9,88.72) 79.94,88.76 R2044.2
  L3 w0.152: v2(148.9,38.38) 148.9,38.39 150.67,40.16 150.67,42.6 150.64,42.63 150.64,42.93 150.64,43.29 150.68,43.33 150.68,45.19 151.28,45.8 151.28,46.21 151.29,46.21 151.29,49.16 151.11,49.34 151.11,56.69 150.77,57.03 150.77,58.41 151.43,59.07 151.48,59.07 151.75,59.34 151.75,60.22 149.18,62.78 149.18,66.13 v2(149.45,66.39)
  L4 w0.152: v2(79.9,88.72) 81.31,88.72 85.07,92.48 85.07,93.95 87.7,96.57 91.65,96.57 92.26,95.97 92.26,95.27 93.8,93.73 99.36,93.73 100.51,94.89 107.42,94.89 109.25,96.72 113.04,96.72 118.74,102.42 123.54,102.42 123.76,102.2 127.72,102.2 128.67,101.25 129.2,101.25 132.14,98.31 132.14,97.94 134.14,95.93 134.14,90.14 133.62,89.61 133.62,88.1 134.58,87.14 134.58,83.39 134.32,83.13 134.32,80.17 135.54,78.95 135.54,74.82 138,72.35 138,70.84 139.86,68.98 141.56,68.98 141.61,69.03 142.44,69.03 143.11,68.36 143.11,68.15 145.32,65.94 148.42,65.94 148.87,66.38 149.44,66.38 v2(149.45,66.39)
  BOTTOM w0.089: 82.07,85.94 82.07,85.88 82.27,85.68 82.27,84.54 81.94,84.22 81.94,83.68 81.98,83.58 81.98,83.17 81.91,83.04 CPU1.AC2
  BOTTOM w0.114: 82.07,85.94 82.07,87.66
  BOTTOM w0.152: 82.07,87.66 80.96,88.77 79.95,88.77 v2(79.9,88.72) ; D7001.3 146.92,38.2 R7008.2 147.26,38.55 v1(148.24,38.55) 148.61,38.55 148.78,38.38 v2(148.9,38.38)
FFS_INT2_D: length 3
  TOP w0.114: U7002.11 157.86,18.77
  TOP w0.152: R7017.1 158.46,17.68 v1(158.02,18.13) 158.02,18.61 157.86,18.77
FFS_INT2_Q: length 22.6
  TOP w0.152: v1(152.61,20.41) v2(152.05,20.41)
  L4 w0.152: v2(138.21,28.54) 138.44,28.54 139.61,27.37 140.23,27.37 142.68,24.92 149.31,24.92 v2(149.76,25.37)
  L6 w0.152: v2(152.05,20.41) 152.05,21.45 149.77,23.73 149.77,25.37 v2(149.76,25.37)
  BOTTOM w0.152: v2(138.21,28.54) 137.93,28.82 R6001.1 ; v2(152.05,20.41) 152.61,19.86 152.61,19.45 152.7,19.36 Q7001.6
FFS_INT2_Q_R: length 4.8
  BOTTOM w0.152: HDD1.1 136.55,28.74 137.19,29.38 137.19,29.79 137.4,29.99 137.71,29.99 R6001.2 137.61,30.52 137.61,31.07 v1(137.52,31.16)
FFS_SCL: length 118.4
  TOP w0.114: U7002.1 157.81,19.83 158.02,20.03 v2(158.02,20.54) ; v2(141,50.64) 141.27,50.64 141.44,50.81 141.44,51.62 141.17,51.9 141.17,58.73 138.49,61.41 138.49,62.32 138.86,62.69 138.86,65.16 138.49,65.52 138.49,68.11 138.34,68.27 138.34,69.44 136.36,71.41 136.36,81.11 136.39,81.14 136.39,83.6 134.63,85.36 134.63,85.39 131.88,88.13 v1(131.86,88.13) 131.86,88.16 131.42,88.6 131.42,96.29 127.29,100.42 R7014.2
  L4 w0.114: v2(136.68,36.65) 136.51,36.48 136.51,35.6 141.63,30.48 141.63,29.7 142.83,28.5 149.01,28.5 149.4,28.89 153.24,28.89 155.06,30.7 v2(158.91,30.7)
  L6 w0.102: v2(158.02,20.54) 156.12,22.45 156.12,25.97 159.16,29.02 159.16,30.45 v2(158.91,30.7) ; v2(136.68,36.65) 136.48,36.85 136.23,37.1 136.23,38.04 136.48,38.3 136.48,40.1 138.87,42.49 140.29,42.49 141.13,43.33 141.13,46.19 141.03,46.29 141.03,46.29 140.5,46.82 140.5,50.14 v2(141,50.64)
FFS_SDA: length 117.7
  TOP w0.114: R7016.2 126.63,100.77 127.43,100.77 131.76,96.43 131.76,88.74 132.22,88.28 132.22,88.28 v1(135.05,85.45) 135.05,85.43 136.73,83.74 136.73,80.99 136.7,80.97 136.7,71.55 138.68,69.58 138.68,68.42 138.84,68.26 138.84,65.66 139.2,65.3 139.2,62.55 138.83,62.18 138.83,61.55 141.51,58.87 141.51,52.04 141.78,51.76 141.78,50.67 141.19,50.07 v2(141.19,50.01) ; v2(153.76,21.57) 153.76,20.49 154.42,19.83 U7002.4
  L4 w0.114: v2(136.66,37.28) 136.17,36.79 136.17,35.46 141.29,30.34 141.29,29.56 142.69,28.16 149.16,28.16 149.55,28.55 153.39,28.55 155.2,30.36 158.27,30.36 v2(158.53,30.11)
  L6 w0.102: v2(141.19,50.01) 140.81,49.62 140.81,46.94 141.33,46.42 141.33,46.41 141.43,46.31 141.43,43.2 140.42,42.18 139,42.18 136.78,39.97 136.78,38.17 136.53,37.92 136.53,37.41 v2(136.66,37.28) ; v2(153.76,21.57) 155.24,21.57 155.81,22.14 155.81,26.1 158.86,29.15 158.86,29.77 v2(158.53,30.11)
FFS_SDO: length 4.2
  TOP w0.152: U7002.3 155.74,20.14 155.46,20.42 154.53,20.42 v1(154.36,20.59) 154.36,21.27 R7020.2 R7019.2
FIVR_EN_R: length 10.4
  TOP w0.102: R9906.2 107.93,29.76 v2(108.49,30.32) 108.3,30.51 XDP1.45 ; R9608.2 102.86,29.52 v1(102.87,29.51) 103.48,29.51 v2(103.66,29.69)
  L3 w0.102: v2(103.66,29.69) 104.1,29.25 107.34,29.25 108.41,30.32 v2(108.49,30.32)
GPD2/LAN_WAKE#: length 8.2
  TOP w0.102: R1732.2 92.55,76.42 R1707.2 91.79,77.18 90.58,77.18 v1(90.35,76.96) 89.41,76.96 89.06,76.6 86.65,76.6 v2(86.17,76.13)
  BOTTOM w0.102: v2(86.17,76.13) 85.85,75.8 CPU1.AM15
GPD11/LANPHYPC: length 8.2
  TOP w0.102: v2(96.78,72.31) 96.46,72.63 R1724.2
  BOTTOM w0.089: CPU1.AW17 90.45,74.07 90.85,73.67 91.25,73.67 91.4,73.62 91.59,73.62 91.6,73.62 91.81,73.67 91.98,73.67 92.13,73.62 92.57,73.18 92.7,73.18
  BOTTOM w0.102: 92.7,73.18 94,73.18 94.3,72.87 96.22,72.87 v2(96.78,72.31)
GPP_B2/VRALERT#: length 1.2
  TOP w0.102: TP1708.1 85.83,78.33 v2(85.47,77.98)
  BOTTOM w0.102: CPU1.AM11 85.85,77.6 v2(85.47,77.98)
GPP_B4/CPU_GP3: length 7.3
  BOTTOM w0.102: CPU1.AY5 90.99,81.16 91.38,81.56 92.22,81.56 92.22,81.57 95.22,81.57 96.17,80.61 TP404.1
GPP_B18/GSPI0_MOSI: length 7.4
  TOP w0.102: R2007.2 90.9,83.66 R2019.1 90.41,82.92 88.53,82.92 87.48,81.87 v1(87.48,81.53) 87.47,81.51 v2(87.47,80.7)
  BOTTOM w0.102: v2(87.47,80.7) 87.8,80.37 CPU1.AR7
GPP_B22: length 8.1
  BOTTOM w0.102: CPU1.AN5 86.5,81.15 87.34,81.99 87.34,82.01 87.42,82.08 87.42,84.01 87.26,84.17 87.26,84.75 87.2,84.8 87.2,86.02 86.87,86.35 86.21,86.35 85.91,86.66 85.91,87.8 TP2018.1
GPP_B23/SML1ALERT#: length 29.2
  TOP w0.102: R1837.2 77.12,93.69 76.74,93.31 76.74,92.2 v2(76.77,92.17) 76.36,91.76 v1(76.31,91.76)
  L3 w0.102: v2(86.82,80.7) 89.26,83.14 89.26,85.56 89.74,86.04 89.74,86.51 89.21,87.04 89.21,88.05 89.44,88.28 v2(89.44,89.5)
  L6 w0.102: v2(76.77,92.17) 77.2,92.6 79.67,92.6 80.13,92.14 82.35,92.14 82.72,91.78 84.68,91.78 85,92.09 85.91,92.09 86.24,91.76 86.24,90.62 87.05,89.81 87.78,89.81 87.91,89.93 88.81,89.93 89.24,89.5 v2(89.44,89.5)
  BOTTOM w0.102: v2(86.82,80.7) 86.3,80.7 CPU1.AM7
GPP_C2/SMBALERT#: length 17.9
  TOP w0.102: R1836.2 77.31,92.3 v2(77.5,92.11) 77.5,91.1 v1(76.99,90.6)
  L3 w0.089: 77.69,81.63 77.69,80.37 77.69,79.88 77.67,79.85 77.67,78.62 v2(78.09,78.2)
  L3 w0.102: 77.69,81.63 77.29,82.03 77.29,85.79 78.06,86.56 78.06,88.82 77.5,89.38 v2(77.5,92.11)
  BOTTOM w0.102: v2(78.09,78.2) 77.8,78.48 CPU1.R10
GPP_C5/SML0ALERT#: length 11
  TOP w0.102: R1822.2 80.36,92.8 R1823.1 80.23,92.17 v2(80.23,91.51) ; v2(79.92,84.6) 80.22,84.6 v1(80.47,84.85)
  L3 w0.102: v2(79.92,84.6) 80.42,85.1 80.42,88.81 80.23,89 v2(80.23,91.51)
  BOTTOM w0.102: v2(79.92,84.6) 79.73,84.4 CPU1.W1
GPP_E0/SATAXPCIE0/SATAGP0: length 4.9
  BOTTOM w0.089: 72.99,84.69 73.5,84.18 73.55,84.08 73.55,83.71 73.5,83.6 73.5,83.38 73.55,83.28 73.55,83.07 73.56,83.04 CPU1.H2
  BOTTOM w0.102: TP1602.1 72.42,85.26 72.99,84.69
GPP_E1/SATAXPCIE1/SATAGP1: length 9.3
  BOTTOM w0.089: CPU1.H3 74.03,82.46 74.03,82.92 73.98,83.04 73.98,83.29 74.03,83.42 74.03,83.57 73.98,83.69 73.98,84.32 73.21,85.08
  BOTTOM w0.102: TP1603.1 71.85,89.76 72.45,89.16 72.89,89.16 73.44,88.61 73.44,88.05 73.09,87.7 73.09,85.2 73.21,85.08
GPP_E2/SATAXPCIE2/SATAGP2: length 7
  BOTTOM w0.089: 73.37,82.35 73.37,83.24 73.32,83.34 73.32,83.63 73.36,83.72 73.36,83.92 73.31,84.01 72.99,84.33 72.77,84.33
  BOTTOM w0.102: CPU1.G4 73.1,82.07 73.37,82.35 ; 72.77,84.33 71.79,85.31 71.79,87.22 TP1604.1
GPP_E3/CPU_GP0: length 5.2
  BOTTOM w0.102: CPU1.A6 69.79,80.84 67.38,80.84 66.86,81.37 66.86,82.34 TP403.1
GSEN2_INT1: length 13.5
  TOP w0.114: 162.08,18.44 U7001.12
  TOP w0.152: R7012.2 R7009.2 161.03,24.96 163.53,24.96 v1(164.02,24.47) 164.14,24.35 164.14,23.72 164.14,23.62 164.14,23.1 164.14,22.24 164.14,19.97 164.14,19.97 164.14,19.04 163.4,18.31 162.21,18.31 162.08,18.44
GSEN2_INT1_C: length 218.7
  TOP w0.152: R6925.2 85.17,111.42 84.25,112.35 v1(84.25,112.79) 84.25,112.87 83.99,113.12 81.55,113.12 79.86,111.44 79.86,109.97 80.28,109.55 80.28,109.52 80.55,109.25 v2(80.55,109.21) ; R7009.1 160.56,26.96 v2(160.46,27.07)
  L3 w0.152: v2(94.22,80.61) 94.22,81.16 94.86,81.81 94.86,84.55 97.11,86.8 97.11,87.36 97.46,87.71 97.46,91.13 98.33,92 98.33,96.32 98.33,96.84 101.45,99.96 101.45,107.5 100.48,108.48 94.58,108.48 94.13,108.93 84.13,108.93 84.03,108.83 81.48,108.83 81.37,108.73 80.8,108.73 80.55,108.98 80.55,109.21 v2(80.55,109.21)
  L4 w0.152: v2(80.55,109.21) 80.98,109.65 82.15,109.65 82.71,110.2 84.49,110.2 85.5,109.19 88.17,109.19 89.82,110.84 113.49,110.84 115.6,108.73 128.12,108.73 130.28,106.57 130.99,106.57 131.83,105.73 133.17,105.73 137.32,101.59 137.32,99.63 139.22,97.73 139.22,87.85 140.54,86.53 140.54,83.66 143.49,80.71 143.49,78.56 149.89,72.16 149.89,71.82 155.76,65.96 155.76,65.95 156.11,65.6 156.52,65.6 161.97,60.15 161.97,59 164.15,56.83 164.15,49.37 163.14,48.36 163.14,41.12 162.94,40.93 162.94,37.75 164.7,36 164.7,27.85 163.42,26.58 160.95,26.58 v2(160.46,27.07)
  BOTTOM w0.089: CPU1.BA7 91.82,79.85 92.37,79.85 92.58,80.07 93.29,80.07 93.44,80.21 93.75,80.21 94.15,80.61 v2(94.22,80.61)
GSEN2_INT1_C_HUB: length 5.4
  TOP w0.152: R6925.1 86.85,111.42 86.96,111.54 v1(87.13,111.54) 88.27,111.54 90.19,109.62 U6901.17
GSEN2_INT2: length 13.4
  TOP w0.114: 161.58,18.45 U7001.11
  TOP w0.152: R7013.2 R7010.2 163.27,25.43 v1(163.28,25.45) 163.83,25.45 164.42,24.86 164.42,23.84 164.42,23.84 164.42,23.74 164.42,22.99 164.42,22.99 164.42,22.82 164.42,22.82 164.42,22.13 164.42,22.13 164.42,21.75 164.42,21.75 164.42,19.85 164.42,19.85 164.42,19.59 164.42,19.59 164.42,18.97 164.42,18.96 164.42,18.79 163.66,18.03 162,18.03 161.58,18.45
GSEN2_INT2_C: length 205
  TOP w0.152: v2(162.15,27.09) 162.34,26.9 R7010.1 ; v2(81.31,107.92) 80.98,107.59 v1(80.45,107.59) 80.05,107.98 R6926.2
  L3 w0.152: v2(81.31,107.92) 81.57,108.17 81.61,108.17 81.71,108.27 84.26,108.27 84.36,108.38 93.9,108.38 94.35,107.92 100.24,107.92 100.9,107.27 100.9,100.26 97.77,97.14 97.77,96.09 97.77,92.23 97,91.46 96.05,91.46 94.97,90.37 94.97,88.46 94.3,87.8 94.3,82.06 v2(92.96,80.71)
  L4 w0.152: v2(81.31,107.92) 81.67,108.27 84.11,108.27 84.36,108.53 88.29,108.53 90.07,110.31 113.63,110.31 115.51,108.43 127.92,108.43 130.15,106.2 130.91,106.2 131.65,105.45 132.95,105.45 137.04,101.37 137.04,99.49 138.92,97.61 138.92,87.45 139.48,86.89 139.48,83.94 143.08,80.33 143.08,78.52 149.49,72.12 149.49,71.84 155.48,65.84 155.48,65.83 156.04,65.27 156.32,65.27 161.69,59.9 161.69,58.88 163.87,56.71 163.87,49.49 162.86,48.48 162.86,41.23 162.67,41.04 162.67,37.54 164.42,35.78 164.42,27.97 163.34,26.89 162.35,26.89 v2(162.15,27.09)
  BOTTOM w0.089: CPU1.AY7 91,80.05 91.32,80.37 92.12,80.37 92.46,80.71 v2(92.96,80.71)
GSEN2_INT2_C_HUB: length 12.3
  TOP w0.152: U6901.38 87.19,101.35 87.13,101.29 82.75,101.29 82.18,101.86 82.18,102.01 81.95,102.23 81.81,102.23 81.24,102.8 v1(81.24,103.27) 81.14,103.38 81.14,104.58 79.79,105.93 79.79,106.84 R6926.1
GSEN_INT1: length 122.7
  TOP w0.152: v2(81.19,109.19) 81.19,109.42 80.93,109.67 80.56,109.67 80.14,110.09 80.14,111.32 80.85,112.03 81.21,112.03 v1(81.29,112.11) 81.67,112.49 R6921.2
  L3 w0.152: v2(93.62,79.74) 93.62,79.59 94.07,79.14 95.07,79.14 95.34,79.41 95.34,80.13 95.54,80.33 95.54,84.34 97.62,86.42 97.62,87.15 97.97,87.5 97.97,90.79 98.84,91.66 98.84,96.63 101.97,99.76 101.97,107.7 100.28,109.39 84.19,109.39 83.91,109.11 81.26,109.11 v2(81.19,109.19)
  L4 w0.152: v2(81.19,109.19) 81.19,108.54 79.55,106.9 79.55,105.65 78.71,104.81 77.98,104.81 72.93,99.76 72.36,99.76 71.53,98.93 65.7,98.93 65.29,98.52 48.86,98.52 47.62,97.28 46.75,97.28 46.47,97.55 41.56,97.55 39.49,99.62 36.67,99.62 36.23,99.18 v2(36.23,99.15)
  BOTTOM w0.089: CPU1.BA8 91.28,79.45 92.55,79.45 92.81,79.19 93.14,79.19 93.38,79.42 93.38,79.43 93.62,79.67 v2(93.62,79.74)
  BOTTOM w0.152: v2(36.23,99.15) 36.05,98.98 36.05,98.97 35.78,98.7 31.48,98.7 30.93,99.25 HOMBD1.9
GSEN_INT1_HUB: length 8.6
  TOP w0.152: U6901.18 89.69,109.73 88.32,111.09 87.09,111.09 86.81,110.81 86.49,110.81 86.39,110.71 85.12,110.71 v1(84.41,111.42) 83.34,112.49 R6921.1
GSEN_INT2: length 118
  TOP w0.152: v2(80.42,108.43) 81.13,108.43 v1(81.31,108.6) 81.64,108.93 81.64,109.42 81.11,109.95 80.68,109.95 80.42,110.2 80.42,111.09 80.93,111.6 R6922.2
  L3 w0.152: v2(93.58,80.61) 93.58,80.92 94.58,81.92 94.58,87.69 95.24,88.35 95.24,90.25 96.17,91.18 97.11,91.18 98.05,92.12 98.05,96.2 98.05,97.02 101.18,100.15 101.18,107.38 100.36,108.2 94.47,108.2 94.01,108.65 84.25,108.65 84.15,108.55 81.59,108.55 81.49,108.45 80.45,108.45 v2(80.42,108.43)
  L4 w0.152: v2(35.59,99.15) 35.59,99.17 36.33,99.9 39.64,99.9 41.58,97.96 46.46,97.96 46.87,97.55 47.5,97.55 48.75,98.8 65.18,98.8 65.58,99.21 71.41,99.21 72.25,100.04 72.82,100.04 77.9,105.13 78.64,105.13 79.27,105.76 79.27,107.27 v2(80.42,108.43)
  BOTTOM w0.152: v2(35.59,99.15) 31.66,99.15 31.06,99.75 HOMBD1.10 ; v2(93.58,80.61) 93.58,80.61 93.58,80.61 93.52,80.61 93.19,80.28 92.38,80.28 CPU1.BB7
GSEN_INT2_HUB: length 7.8
  TOP w0.152: R6922.1 83.28,111.59 84.46,110.41 86.62,110.41 86.63,110.42 v1(86.64,110.42) 86.82,110.42 87.21,110.81 88.21,110.81 89.19,109.83 U6901.19
GSENSOR_CS: length 8
  TOP w0.114: U7001.2 163.48,19.78 163.48,19.78
  TOP w0.152: 163.48,19.78 163.56,19.78 v1(163.71,19.93) 163.86,20.08 163.86,24.04 163.25,24.65 162.32,24.65 R7006.1
GSENSOR_SDO: length 6.5
  TOP w0.114: 163.46,20.29 163.45,20.28 U7001.3
  TOP w0.152: R7005.2 161.39,22.57 162,22.57 R7007.2 163.21,22.5 v1(163.33,22.5) 163.58,22.24 163.58,20.41 163.46,20.29
GYRO_DRDY: length 105.6
  TOP w0.152: v2(78.65,107.16) 79.18,106.62 R6924.2
  L3 w0.152: v2(83.98,106.39) 83.98,104.11 86.88,101.21 86.88,99.51 86.36,98.98 86.36,98.41 85.98,98.03 85.98,92.31 86.7,91.59 86.7,87.13 87.41,86.42 87.41,85.23 v2(87.66,84.98)
  L4 w0.152: v2(86.82,77.04) 87.28,77.5 87.93,77.5 88.96,77.5 89.25,77.79 89.25,77.96 90.11,78.81 90.11,79.19 89.84,79.46 89.46,79.46 89.3,79.29 87.93,79.29 87.9,79.33 87.28,79.33 87.28,79.32 87.01,79.32 87.01,79.33 86.36,79.33 86.36,79.32 85.98,79.32 84.92,80.39 84.92,81.17 87.05,83.3 87.05,84.37 87.47,84.8 87.48,84.8 v2(87.66,84.98) ; v2(36.86,99.17) 37.37,99.17 38.57,97.97 39.78,97.97 40.55,97.2 46.43,97.2 46.64,97 47.74,97 48.98,98.24 65.41,98.24 65.82,98.65 71.64,98.65 72.48,99.49 73.05,99.49 75.01,101.45 75.58,101.45 v2(75.59,101.44)
  BOTTOM w0.152: v2(75.59,101.44) 76.1,101.44 v1(76.23,101.57) 77.25,102.58 77.25,105.76 v2(78.65,107.16) 79.38,106.42 79.38,105.77 80.08,105.08 81.63,105.08 82.95,106.39 v2(83.98,106.39) ; CPU1.AP13 87.15,76.71 v2(86.82,77.04) ; v2(36.86,99.17) 35.77,100.26 31.61,100.26 31.12,100.75 HOMBD1.12
GYRO_DRDY_HUB: length 12.1
  TOP w0.152: R6924.1 80.01,105.31 80.86,104.47 80.86,102.79 v1(81.79,101.85) 82.63,101.01 87.42,101.01 87.69,101.28 U6901.39
GYRO_INT: length 78.9
  L4 w0.152: v2(35.58,99.8) 35.96,100.18 40.03,100.18 40.61,99.6 40.61,99.45 40.88,99.19 42.35,99.19 42.65,99.49 45.93,99.49 46.34,99.08 64.82,99.08 65.23,99.49 71.3,99.49 72.13,100.32 72.7,100.32 76.11,103.73 76.11,106.7 77.2,107.79 v2(78.65,107.79)
  BOTTOM w0.152: R7002.2 93.44,104.23 92.59,104.23 92.04,103.69 R7003.2 91.56,103.69 91.32,103.93 91.32,104.88 91.49,105.05 91.92,105.05 92.18,105.32 92.18,106.05 91.57,106.66 91.57,106.67 v1(91.47,106.77) 91.1,106.77 89.63,108.25 86.21,108.25 85.25,107.28 83.44,107.28 81.52,105.36 80.19,105.36 79.66,105.89 79.66,107.28 79.15,107.79 v2(78.65,107.79) ; HOMBD1.11 31.2,100.25 31.64,99.8 v2(35.58,99.8)
GYRO_INT_C: length 45.8
  L3 w0.152: v2(84.23,107.82) 84.64,107.41 85.01,107.41 85.88,106.54 85.88,105.76 90.08,101.57 90.08,99.59 92.42,97.24 92.42,93.79 91.59,92.96 91.59,84.89 90.79,84.09 90.79,81.52 89.64,80.37 v2(89.64,79.99)
  BOTTOM w0.152: R7003.1 91.88,104.55 92.69,104.55 R6923.2 92.7,104.81 92.46,105.05 92.46,106.32 91.63,107.16 91.36,107.16 89.99,108.53 v1(85.66,108.53) 84.84,108.53 84.23,107.92 v2(84.23,107.82) ; v2(89.64,79.99) 89.66,79.97 90.17,79.97 CPU1.AW7
GYRO_INT_C_HUB: length 8.7
  TOP w0.152: U6901.20 88.69,109.7 88.68,109.7 v2(88.04,110.33)
  BOTTOM w0.152: v2(88.04,110.33) 89.44,108.93 90.12,108.93 v1(90.84,108.22) 91.62,107.44 91.75,107.44 92.95,106.24 R6923.1
GYRO_INT_P11: length 148.8
  L3 w0.152: v2(159.49,55.81) 159.04,55.36 159.04,53.35 157.36,51.67 157.36,46.06 158.7,44.72 158.7,44.06 159.72,43.03 159.72,38.22 159.34,37.84 159.34,34.01 v2(159.81,33.54)
  L4 w0.152: v2(148.98,34.82) 149,34.83 149,35.41 151.05,37.46 154.66,37.46 156.45,35.67 158.01,35.67 159.82,33.86 159.82,33.54 v2(159.81,33.54) ; v2(103.54,104.87) 103.54,104.34 106.07,101.81 106.86,101.81 106.87,101.82 109.63,101.82 110.04,102.23 112.43,102.23 115.56,105.36 119.98,105.36 120.78,106.17 123.95,106.17 124.56,105.56 128.02,105.56 128.68,104.9 129.88,104.9 130.41,104.36 132.05,104.36 135.24,101.18 135.24,101.16 136.05,100.34 136.05,99.28 137.94,97.4 137.94,84.2 141.9,80.24 141.9,77.84 147.58,72.15 148.05,72.15 154.69,65.51 154.69,65.47 155.84,64.33 156.08,64.33 159.67,60.74 159.67,56 v2(159.49,55.81)
  BOTTOM w0.152: v2(148.98,34.82) 148.94,34.77 147.96,34.77 D7001.1 ; v2(103.54,104.87) 102.34,104.87 101.97,105.24 101.97,107.66 100.24,109.39 96.12,109.39 94.9,108.17 94.65,108.17 v1(94.27,107.79) 93.53,107.05 93.53,105.67 R7002.1
H_CATERR#: length 2
  TOP w0.102: TP401.1 72.35,48.66 v2(72.59,48.66)
  BOTTOM w0.102: CPU1.D63 72.12,48.66 v2(72.59,48.66)
H_CPU_SVIDALRT#: length 9.6
  BOTTOM w0.089: 66.96,47.08 67.62,47.74 69.87,47.74 70.2,48.08 CPU1.B63
  BOTTOM w0.114: 66.96,47.08 66.96,46.89 66.65,46.58 66.11,46.58 v1(66.11,46.58) 66.05,46.52 66.05,46.26 66.96,45.35 66.96,43.97 66.01,43.02 R728.2
H_CPU_SVIDCLK: length 5.3
  TOP w0.114: v2(66.49,47.01) 66.49,47.43 v1(66.32,47.6) 65.81,47.6 R732.1
  BOTTOM w0.114: v2(66.49,47.01) 67.42,47.93 69.44,47.93 CPU1.A63
H_CPU_SVIDDAT: length 12.2
  TOP w0.114: R709.1 63.06,43.24 65.91,43.24 66.99,44.32 66.99,44.89 R726.2 67.86,45.76 69.57,45.76 70.18,46.37 v1(70.55,46.37) 70.83,46.65 70.83,47.19 71.29,47.66 v2(71.91,47.66)
  BOTTOM w0.114: v2(71.91,47.66) 71.77,47.51 CPU1.D64
H_CPUPWRGD: length 8.7
  TOP w0.102: v2(68.52,44.47) 68.53,44.47 69.15,44.47 TP1705.1
  BOTTOM w0.102: CPU1.A68 69.42,44.78 69.39,44.78 69.07,44.47 v2(68.52,44.47) 68.52,43.94 68.27,43.68 68.27,42.65 67.8,42.18 67.71,42.18 67.09,41.55 67.09,40.86 66.71,40.48 EC1701.1 R1714.1
H_PECI: length 114.9
  TOP w0.114: v2(140.09,39.9) 140.09,40.27 R2437.2
  L3 w0.114: v2(140.09,39.9) 138.99,38.8 137.11,38.8 135.03,36.72 135.03,34.85 133.75,33.57 133.09,33.57 131.52,32.01 130.39,32.01 129.19,30.81 129.19,29.95 v2(128.85,29.61)
  L4 w0.114: v2(128.85,29.61) 128.81,29.57 128.51,29.27 128.28,29.27 127.42,28.4 119.92,28.4 115.82,24.3 111.46,24.3 111.27,24.11 108.88,24.11 108.26,23.49 106.44,23.49 105.51,24.42 100.29,24.42 99.75,24.97 95.02,24.97 93.9,24.97 93.9,24.97 85.9,24.97 83.22,27.65 81.57,27.65 80.3,28.92 73.16,28.92 72.63,29.46 72.63,30.25 66.74,36.14 66.32,36.14 64.55,37.9 64.55,39 64.33,39.22 64.33,39.23 63.94,39.62 63.94,40.63 63.94,42.72 62.23,44.43 62.23,46 63.53,47.29 63.53,51.57 66.15,54.2 v2(66.33,54.2)
  BOTTOM w0.114: CPU1.A54 69.59,53.3 68.43,54.45 67.39,54.45 67.14,54.2 v2(66.33,54.2) 66.31,54.2 v1(65.92,54.58)
H_PROCHOT#: length 208.4
  TOP w0.114: v2(140.04,26.92) 140.37,26.92 141.15,27.69 v1(141.15,30.46) 141.15,31.6 v2(141.23,31.69)
  L4 w0.114: v2(40.67,42.13) 42.45,40.35 45.24,40.35 48.51,37.08 59.37,37.08 61.06,38.77 v2(62.62,38.77) 62.62,37.5 65.58,34.54 66.17,34.54 68.83,31.87 68.83,31.87 69.56,31.15 69.56,28.84 72.72,25.67 82.2,25.67 85.29,22.58 91.11,22.58 92.33,22.58 93.41,23.66 93.68,23.66 94.08,24.07 94.27,24.07 94.27,24.07 94.65,24.07 99.16,24.07 99.71,23.52 105.13,23.52 106.11,22.54 108.59,22.54 109.25,23.21 111.64,23.21 111.72,23.29 116.08,23.29 116.45,23.66 117.41,23.66 117.87,23.2 120.37,23.2 121.77,24.6 121.77,25.42 122.41,26.06 123.4,26.06 124.09,26.75 137.72,26.75 137.9,26.57 139.33,26.57 139.51,26.75 139.87,26.75 v2(140.04,26.92)
  L6 w0.102: v2(19.72,42.39) 19.85,42.39 25.37,36.86 25.37,36.29 26.52,35.15 27.72,35.15 29.81,33.06 29.81,30.89 30.26,30.45 30.26,23.72 31.59,22.38 31.59,18.7 35.71,14.59 35.71,10.01 v2(39.53,6.19) ; v2(40.67,42.13) 40.55,42.13 37.75,44.93 35.58,44.93 30.77,44.93 30.21,45.48 28.81,45.48 28.58,45.25 28.56,45.25 28.55,45.26 28.52,45.26 v2(28.35,45.1)
  BOTTOM w0.114: PR4469.1 v2(39.53,6.19) ; v2(141.23,31.69) 141.26,31.65 C2403.1 142.97,31.72 R2416.2 ; R403.1 64.75,40.87 R401.2 PR4624.2 65.09,38.45 62.94,38.45 v2(62.62,38.77) ; v2(19.72,42.39) 25.05,42.39 27.47,44.8 28.11,44.8 28.35,45.04 v2(28.35,45.1) ; PR4668.2 41.19,49.12 42.27,48.04 42.27,46.48 41.96,46.17 41.96,43.14 42.02,43.08 42.02,42.59 41.57,42.13 v2(40.67,42.13)
H_PROCHOT#_EC: length 4.7
  BOTTOM w0.114: Q2408.D 142.97,34 141.32,34 R2418.2 140.88,32.73 v1(140.98,32.63) 141.13,32.48 R2416.1
H_PROCHOT#_R: length 10.8
  BOTTOM w0.089: 67.18,46.07 68.5,47.39 70.21,47.39 70.39,47.21 70.65,46.95 CPU1.C65
  BOTTOM w0.114: 67.18,46.07 67.18,43.6 66.83,43.25 66.83,42.58 66.43,42.18 v1(66.29,42.18) 64.81,42.18 R403.2
H_VCCST_PWRGD: length 16.5
  TOP w0.102: v2(67.46,43.02) 67.46,42.88 66.2,41.62 65.61,41.62 64.79,40.8 U1701.4 v1(63.43,40.8) 62.9,41.33 R1716.2 62.16,41.33 C1711.1 EC1708.1 R1719.1 62.04,39.08 R1722.2
  BOTTOM w0.089: CPU1.B65 70.05,46.95 69.79,47.21 68.61,47.21 68.16,46.76
  BOTTOM w0.102: 68.16,46.76 67.39,45.99 67.39,43.09 v2(67.46,43.02)
HDA_BITCLK: length 8.4
  TOP w0.114: R1907.2 95.61,68.55 v1(94.83,69.32) 94.52,69.64 v2(94.52,70.33)
  BOTTOM w0.089: 92.36,71.93 92.07,71.93 91.89,71.74 91.89,71.56 91.71,71.39 91.18,71.39 CPU1.AY22
  BOTTOM w0.114: 92.36,71.93 92.52,71.93 93.71,70.74 94.11,70.74 v2(94.52,70.33)
HDA_CODEC_BITCLK: length 252.9
  TOP w0.114: R1907.1 EC1901.2 99.47,67.98 v1(101.96,67.98) 102.41,67.98 107.88,73.45 107.88,76.88 118.14,87.14 118.14,87.82 118.14,99.15 110.25,107.03 110.25,110.59 108.49,112.35 v2(108.49,113.12) ; R2720.1 EC2709.1 27.15,18.19 27.54,18.59 28.3,18.59 28.58,18.87 28.58,19.3 v2(29.06,19.78)
  L6 w0.102: v2(29.06,19.78) 29.06,20.47 27.01,22.52 27.01,23.28 27.95,24.22 27.95,30.48 27.57,30.86 27.57,31.13 26.42,32.27 25.67,32.27 22.77,35.17 22.77,37.28 16.91,43.14 16.91,43.53 15.62,44.82 15.62,55.33 14.46,56.49 14.46,68.31 14.31,68.46 14.31,70.56 11.64,73.23 11.64,73.84 11.64,74.28 12.38,75.03 12.38,77.13 13.06,77.81 13.06,82.9 12.66,83.3 12.66,86.63 18.34,92.31 18.95,92.31 23.22,96.58 26.41,96.58 27.18,97.34 29.99,97.34 31.88,99.23 32.64,99.23 35.64,102.23 43.05,102.23 43.2,102.38 53.81,102.38 54.12,102.08 56.13,102.08 56.56,102.51 59.65,102.51 60.53,101.62 64.94,101.62 65.37,101.19 70.12,101.19 72.39,103.46 72.39,105.32 74.37,107.31 74.37,109.98 78.3,113.91 103.82,113.91 104.86,112.87 105.32,112.41 106.18,112.41 106.79,113.02 106.79,113.3 107.04,113.56 108.06,113.56 v2(108.49,113.12)
HDA_CODEC_RST#: length 250.8
  TOP w0.114: R1911.1 EC1902.1 99.37,69.9 v1(103.08,69.9) 103.84,69.9 107.53,73.59 107.53,77.02 117.79,87.28 117.79,87.68 117.79,87.68 117.79,99.01 109.91,106.89 109.91,110.18 107.22,112.87 v2(107.22,113.12) ; v2(27.44,22.83) 27.44,22.73 27.53,22.64 C2714.1 27.37,21.81 25.67,23.51 HDA27.2
  L6 w0.102: v2(27.44,22.83) 27.44,22.95 28.25,23.77 28.25,30.61 27.87,30.99 27.87,31.25 26.55,32.57 26,32.57 24.29,34.28 24.29,35.14 23.07,36.36 23.07,37.41 17.22,43.26 17.22,43.66 15.93,44.95 15.93,62.85 14.97,63.8 14.97,68.27 14.62,68.62 14.62,70.18 14.62,70.18 14.62,70.69 11.94,73.36 11.94,74.16 12.69,74.9 12.69,77.01 13.37,77.69 13.37,77.72 13.37,83.02 12.96,83.43 12.96,86.5 18.46,92 19.07,92 23.34,96.27 26.53,96.27 27.3,97.04 30.12,97.04 32,98.93 32.77,98.93 35,101.16 42.42,101.16 43.33,102.08 53.68,102.08 53.69,102.07 53.99,101.77 56.25,101.77 56.69,102.2 59.52,102.2 60.41,101.31 64.81,101.31 65.25,100.88 70.24,100.88 72.7,103.33 72.7,105.2 74.68,107.18 74.68,109.86 78.43,113.61 103.7,113.61 105.19,112.11 106.31,112.11 107.22,113.02 v2(107.22,113.12)
  BOTTOM w0.114: v2(27.44,22.83) 27.44,23.57 28.61,24.73 R2917.1
HDA_CODEC_SDIN0: length 5.1
  TOP w0.114: R2718.2 26.41,21.28 v1(26.4,21.28) 26.4,21.29 25.09,22.6 HDA27.42
HDA_CODEC_SDOUT: length 251.7
  TOP w0.114: v2(29.12,19.14) 29.75,19.78 29.75,20.03 29.31,20.48 EC2708.1 29.15,20.92 R2719.1 ; v2(109.13,113.12) 109.13,112.2 110.59,110.73 110.59,107.18 118.48,99.29 118.48,87.97 118.48,87 108.22,76.74 108.22,73.31 102.32,67.4 v1(100.08,67.4) 98.27,67.4 R1912.1
  L6 w0.102: v2(109.13,113.12) 108.36,112.36 106.88,112.36 106.4,111.88 105.1,111.88 104.24,112.74 103.6,113.38 78.53,113.38 74.91,109.76 74.91,107.08 72.92,105.1 72.92,103.24 70.34,100.65 65.15,100.65 64.72,101.09 60.31,101.09 59.42,101.97 56.78,101.97 56.35,101.54 53.89,101.54 53.62,101.81 53.58,101.85 43.53,101.85 42.62,100.93 35.1,100.93 32.86,98.7 32.1,98.7 30.21,96.81 27.4,96.81 26.63,96.04 23.44,96.04 19.17,91.78 18.56,91.78 13.19,86.41 13.19,83.53 13.6,83.12 13.6,78.32 13.6,77.59 12.92,76.91 12.92,74.81 12.17,74.06 12.17,73.46 12.43,73.2 14.54,71.08 14.85,70.78 14.85,70.09 14.85,68.72 15.4,68.17 15.4,63.85 16.16,63.09 16.16,45.04 17.44,43.76 17.44,43.36 23.37,37.43 23.37,36.49 24.59,35.27 24.59,34.61 25.28,33.93 25.87,33.93 28.1,31.69 28.1,31.08 28.53,30.65 28.53,21.63 29.5,20.67 29.5,19.53 v2(29.12,19.14)
HDA_CODEC_SYNC: length 247.7
  TOP w0.114: R1908.1 98.71,70.98 v1(100.62,70.98) 104.24,70.98 107.05,73.79 107.05,77.22 117.31,87.48 117.31,98.81 109.3,106.82 109.3,109.5 v2(105.65,113.15) ; HDA27.41 23.28,22.06 23.53,21.81 25.23,21.81 v2(26.44,20.6)
  L6 w0.102: v2(26.44,20.6) 26.44,23.47 27.24,24.26 27.24,25.73 26.85,26.11 26.85,26.66 27.36,27.17 27.36,30.31 27.03,30.64 27.03,30.91 26.2,31.74 25.88,31.74 25.43,31.74 22.23,34.94 22.23,37.05 20.87,38.41 19.83,38.41 16.36,41.88 16.36,43.31 15.08,44.6 15.08,55.1 13.93,56.25 13.93,68.09 13.72,68.29 13.72,70.4 11.08,73.04 11.08,74.48 11.85,75.25 11.85,77.36 11.85,77.36 11.85,77.48 12.4,78.03 12.4,82.72 12.12,83 12.12,86.85 18.12,92.84 18.42,92.84 18.42,92.84 18.73,92.84 22.99,97.11 26.19,97.11 26.96,97.88 29.77,97.88 31.66,99.76 32.42,99.76 35.57,102.91 54.03,102.91 54.34,102.61 55.66,102.61 56.09,103.04 59.89,103.04 60.78,102.15 65.16,102.15 65.59,101.72 69.9,101.72 71.84,103.67 71.84,105.53 73.84,107.53 73.84,110.23 74.26,110.65 78.08,114.47 80.24,114.47 80.24,114.47 80.6,114.47 80.6,114.47 82.78,114.47 82.78,114.47 83.14,114.47 83.14,114.47 83.48,114.47 83.92,114.47 85.32,114.47 87.86,114.47 89.05,114.47 90.4,114.47 90.4,114.47 90.76,114.47 98.38,114.47 100.92,114.47 103.46,114.47 104.32,114.47 v2(105.65,113.15)
HDA_RST#: length 8.7
  TOP w0.114: R1911.2 96.17,69.44 v1(96.04,69.56) 95.79,69.82 v2(95.79,70.33)
  BOTTOM w0.089: CPU1.AW22 90.5,71.65 90.76,71.91 91.07,71.91 91.09,71.89 91.38,71.89 91.41,71.92 91.52,71.92 91.93,72.33 92.13,72.33
  BOTTOM w0.114: v2(95.79,70.33) 94.97,71.15 94.24,71.15 93.39,72 93.35,72 93.02,72.33 92.66,72.33 92.13,72.33
HDA_SDIN0: length 255.2
  TOP w0.114: v2(106.33,113.18) 109.54,109.97 109.54,106.95 109.67,106.79 117.55,98.91 117.55,87.38 107.29,77.12 107.29,73.69 103.93,70.33 v1(101.71,70.33) 99.21,70.33 98.97,70.09 96.79,70.09 v2(96.55,70.33) ; v2(28.43,19.78) 28.43,19.79 R2718.1
  L6 w0.102: v2(106.33,113.18) 105.87,112.72 105.45,112.72 103.95,114.22 78.18,114.22 74.07,110.11 74.07,107.43 72.09,105.45 72.09,103.59 69.99,101.49 65.5,101.49 65.07,101.92 60.66,101.92 59.77,102.81 56.43,102.81 56,102.38 54.24,102.38 53.94,102.69 43.08,102.69 42.93,102.53 35.51,102.53 32.51,99.54 31.75,99.54 29.87,97.65 27.05,97.65 26.28,96.88 23.09,96.88 18.82,92.61 18.21,92.61 12.35,86.75 12.35,83.18 12.76,82.77 12.76,77.97 12.08,77.3 12.08,77.27 12.08,77.26 12.08,75.15 11.33,74.41 11.33,73.72 11.34,73.72 11.34,73.11 14.01,70.43 14.01,68.33 14.15,68.19 14.15,56.36 15.32,55.2 15.32,44.7 16.61,43.41 16.61,41.97 19.93,38.64 20.97,38.64 22.46,37.15 22.46,35.04 25.54,31.96 26.3,31.96 27.26,31 27.26,30.74 27.59,30.41 27.59,27.07 27.08,26.56 27.08,26.2 27.46,25.82 27.46,24.17 26.7,23.41 26.7,22.07 28.43,20.34 v2(28.43,19.78)
  BOTTOM w0.089: 92.03,72.54 91.87,72.54 91.56,72.22 CPU1.BA21
  BOTTOM w0.114: 92.03,72.54 92.03,72.54 92.74,72.54 93.11,72.54 93.44,72.2 93.47,72.2 94.26,71.42 94.99,71.42 95.62,70.79 96.08,70.79 v2(96.55,70.33)
HDA_SDOUT: length 7.9
  TOP w0.114: v2(93.89,70.33) 93.89,69.57 95.8,67.66 v1(96.09,67.66) R1912.2 R1909.2
  BOTTOM w0.114: CPU1.BB22 92.51,71.65 93.83,70.33 v2(93.89,70.33)
HDA_SPKR_R: length 4.6
  BOTTOM w0.254: RN2701.3 29.91,37.89 30.23,37.56 v1(30.23,36.29) 30.23,35.4 30.1,35.27 D2701.2
HDA_SYNC: length 7.3
  TOP w0.114: v2(95.16,70.33) 95.79,70.96 v1(95.92,70.96) 96.71,70.96 97.04,70.63 R1908.2
  BOTTOM w0.089: 92.11,72.13 91.98,72.13 91.56,71.72 CPU1.BA22
  BOTTOM w0.114: v2(95.16,70.33) 94.54,70.94 93.79,70.94 92.61,72.13 92.11,72.13
HDD_DEVSLP: length 203.6
  TOP w0.102: v1(140.77,76.19) 141.31,76.19 v2(141.33,76.22)
  L3 w0.102: v2(141.33,76.22) 144.34,76.22 147.9,72.66 147.9,72.47 155.28,65.09 156.29,65.09 158.86,62.53 158.86,60.47 157.72,59.33 157.72,58.85 158.42,58.14 158.42,53.09 157.11,51.77 157.11,45.96 158.45,44.62 158.45,43.95 159.47,42.93 159.47,38.5 157.33,36.37 157.33,32.84 156.68,32.19 156.68,29.85 153.1,26.28 148.89,26.28 v2(148.63,26.01)
  L4 w0.102: v2(129.88,29.91) 129.91,29.91 130.09,29.72 130.09,29.72 130.53,29.28 132.97,29.28 133.56,29.86 137.79,29.86 138.62,29.02 138.62,28.72 139.64,27.71 140.25,27.71 142.75,25.21 147.15,25.21 147.95,26.01 v2(148.63,26.01)
  L6 w0.102: v2(141.33,76.22) 140.75,76.8 140.75,78.07 139.43,79.39 139.43,79.69 138.77,80.34 138.77,82.77 138.77,83.11 137.69,84.2 137.69,86.86 137.08,87.47 137.08,89.35 136.34,90.09 136.34,97.16 136.05,97.45 136.05,98.82 135.25,99.61 131.65,103.22 131.32,103.42 130.25,103.42 129.31,104.36 128.84,104.36 127.86,104.36 127.85,104.36 125.75,104.36 118.17,104.36 111.23,97.42 110.02,97.42 107.23,94.63 101.96,94.63 101.71,94.38 101.71,93.97 99.98,92.25 99.98,88.99 99.22,88.23 98.59,88.23 96.24,85.88 95.06,85.88 92.46,88.48 92.46,88.83 91.28,90.01 89.02,90.01 88.89,90.14 87.82,90.14 87.7,90.01 87.15,90.01 86.63,90.52 86.44,90.71 86.44,91.84 85.99,92.3 84.75,92.3 84.5,92.04 82.74,92.04 82.44,92.35 80.21,92.35 79.75,92.8 76.79,92.8 73.74,89.76 v2(73.44,89.76)
  BOTTOM w0.102: v2(73.44,89.76) 73.44,89.3 73.65,89.09 73.65,87.77 73.37,87.5 73.37,85.25 74.36,84.26 74.36,83.88 CPU1.J1 ; v2(129.88,29.91) 129.5,29.52 129.5,29.51 129.51,29.5 R6002.1
HDD_DEVSLP_R: length 1.9
  BOTTOM w0.102: R6002.2 130.55,29.03 HDD1.13
HDD_EN_PCH: length 8.8
  BOTTOM w0.089: 74.07,85.31 74.33,85.06 74.33,84.87 74.73,84.46 74.73,84.23 74.77,84.14 74.77,84.13 74.77,84.13 74.86,84.04 74.86,83.67 74.83,83.59 74.83,83 74.78,82.96 74.78,82.22 CPU1.J4
  BOTTOM w0.102: TP1802.1 74.71,89.5 74.24,89.03 74.24,88.17 74.24,88.17 74.24,87.8 73.95,87.5 73.95,85.44 74.07,85.31
HDD_FALL_INT: length 182.5
  TOP w0.152: R7015.2 R7012.1 159.67,27 v2(159.61,27.06)
  L3 w0.152: v2(80.55,106.45) 80.54,106.45 80.1,106 80.1,105.91 78.77,104.59 78.77,100.54 77.77,99.54 77.25,99.54 76.31,98.6 76.31,91.76 v2(76.77,91.29)
  L4 w0.152: v2(159.61,27.06) 160.1,27.55 162.4,27.55 162.61,27.34 163.39,27.34 164.12,28.07 164.12,35.69 162.39,37.42 162.39,41.16 162.55,41.32 162.55,48.57 163.59,49.6 163.59,56.59 161.41,58.77 161.41,59.75 156.32,64.84 156.05,64.84 155.2,65.69 155.2,65.73 149.18,71.74 149.18,72.03 142.65,78.56 142.65,80.2 139.17,83.68 139.17,86.61 138.61,87.17 138.61,97.45 136.76,99.31 136.76,101.25 132.94,105.07 130.42,105.07 130.09,105.4 130.09,105.75 128.55,107.29 126.67,107.29 125.84,108.12 114.89,108.12 112.99,110.03 90.18,110.03 88.31,108.16 86.07,108.16 85.12,107.21 83.45,107.21 83.29,107.06 81.16,107.06 v2(80.55,106.45)
  BOTTOM w0.089: CPU1.M3 75.46,82.8 75.46,82.89 75.36,82.99 75.36,83.57 75.3,83.69 75.25,83.73 75.25,84.2 75.17,84.29 75.17,85.21 74.76,85.62
  BOTTOM w0.152: 74.76,85.62 74.26,86.11 74.26,87.45 74.46,87.65 74.46,88.26 74.45,88.26 74.45,88.64 75.34,89.53 75.34,91.09 v1(75.45,91.2) 75.54,91.29 v2(76.77,91.29)
HDMI_CLK: length 106.1
  L6 w0.102: v2(73.28,52.35) 73.24,52.35 72.8,51.91 72.5,51.91 70.85,50.26 70.85,45.08 70.39,44.62 70.39,44.14 68.84,42.59 68.04,42.59 62.76,37.31 62.01,37.31 58.23,33.52 35.23,33.52 30.29,38.47 27.46,38.47 20.73,45.19 20.73,46.68 18.88,48.52 18.88,67.83 17.9,68.82 17.9,72.83 18.45,73.37 18.45,75.63 20.78,77.97 v2(21.62,77.97)
  BOTTOM w0.102: C5709.1 20.82,78.21 21.06,77.97 v2(21.62,77.97) ; CPU1.G56 73.49,51.89 73.28,52.09 v2(73.28,52.35)
HDMI_CLK#: length 105.5
  TOP w0.102: v2(21.62,77.21) v1(22.18,77.21)
  L6 w0.102: v2(72.64,52.36) 70.63,50.35 70.63,45.17 70.17,44.71 70.17,44.23 68.75,42.81 67.95,42.81 62.67,37.52 61.92,37.52 58.14,33.74 35.32,33.74 30.38,38.68 27.55,38.68 20.95,45.28 20.95,46.77 19.1,48.61 19.1,67.92 18.12,68.91 18.12,72.74 18.66,73.28 18.66,75.54 20.87,77.76 21.18,77.76 21.24,77.69 21.24,77.31 21.34,77.21 v2(21.62,77.21)
  BOTTOM w0.102: v2(72.64,52.36) 72.64,52.21 CPU1.F56 ; C5714.1 21.47,77.36 v2(21.62,77.21)
HDMI_CLK#_R: length 2.4
  BOTTOM w0.102: U5701.10 18.87,78.43 19.29,78.01 19.29,77.46 19.39,77.36 C5714.2
HDMI_CLK#_R_C: length 11.8
  L6 w0.102: v2(11.14,77.55) 10.94,77.75 9.83,77.75 9.01,78.57 9.01,83.23 HDMI1.12
  BOTTOM w0.102: U5701.21 13.24,78.16 R5705.1 11.84,76.85 v2(11.14,77.55)
HDMI_CLK_R: length 1.9
  BOTTOM w0.102: C5709.2 19.34,78.25 18.75,78.83 U5701.9
HDMI_CLK_R_C: length 11.1
  L6 w0.102: v2(11.14,78.19) 10.93,77.97 9.92,77.97 9.23,78.66 9.23,83.15 9.39,83.3 9.68,83.3 HDMI1.10
  BOTTOM w0.102: v2(11.14,78.19) 11.5,78.19 11.69,78 11.69,77.81 R5705.2 12.01,77.49 12.28,77.49 12.55,77.76 12.55,78.58 12.81,78.83 U5701.22
HDMI_DATA0: length 122.8
  TOP w0.102: v1(22.28,83.08) 22.21,83.15 v2(21.67,83.15)
  L6 w0.102: v2(21.67,83.15) 21.52,83 21.22,83 21.16,83.05 21.16,83.46 21.05,83.57 20.69,83.57 19.97,82.85 19.97,78.62 15.74,74.4 15.74,72.24 16.68,71.3 16.68,67.53 17.86,66.36 17.86,48.06 19.7,46.21 19.7,44.43 26.69,37.44 29.71,37.44 34.65,32.49 58.66,32.49 62.44,36.28 63.51,36.28 66.61,39.37 68.03,39.37 71.56,42.9 72.77,42.9 75.01,45.14 75.01,49.11 74.35,49.77 74.35,51.5 73.92,51.94 73.92,54.3 73.73,54.49 73.55,54.49 v2(73.3,54.24)
  BOTTOM w0.102: CPU1.G53 73.47,53.72 73.46,53.73 73.36,53.73 73.21,53.88 73.21,54.15 v2(73.3,54.24) ; C5711.1 20.92,82.78 21.29,83.15 v2(21.67,83.15)
HDMI_DATA0#: length 124.4
  TOP w0.102: v2(21.67,83.79) 22.05,83.79 v1(22.56,84.3)
  L6 w0.102: v2(72.66,54.19) 72.68,54.21 72.68,54.23 73.15,54.7 73.82,54.7 74.14,54.39 74.14,52.03 74.57,51.59 74.57,49.86 75.23,49.2 75.23,45.05 72.86,42.68 71.65,42.68 68.12,39.15 66.69,39.15 63.6,36.06 62.53,36.06 58.75,32.28 34.57,32.28 29.62,37.22 26.6,37.22 19.49,44.34 19.49,46.12 17.64,47.97 17.64,66.27 16.47,67.44 16.47,71.21 15.53,72.15 15.53,74.48 19.76,78.71 19.76,82.94 20.61,83.79 v2(21.67,83.79)
  BOTTOM w0.102: CPU1.F53 v2(72.66,54.19) ; C5708.1 21.18,83.79 v2(21.67,83.79)
HDMI_DATA0#_R: length 2.8
  BOTTOM w0.102: C5708.2 19.05,83.53 18.78,83.26 18.78,82.67 18.32,82.21 U5701.1
HDMI_DATA0#_R_C: length 15.4
  BOTTOM w0.102: U5701.30 12.86,82.03 12.8,82.09 12.8,83.18 12.27,83.71 12.27,84.32 R5703.2 11.31,84.36 10.91,84.36 10.72,84.55 10.72,87.58 10.4,87.89 9.34,87.89 9.01,87.56 9.01,82.84 8.78,82.6 HDMI1.9
HDMI_DATA0_R: length 3.8
  BOTTOM w0.102: U5701.2 18.75,81.63 18.98,81.86 18.98,83.18 19.13,83.33 19.44,83.33 19.49,83.28 19.49,82.72 19.56,82.64 C5711.2
HDMI_DATA0_R_C: length 15.4
  BOTTOM w0.102: U5701.29 12.82,81.63 12.59,81.86 12.59,83.1 11.93,83.76 R5703.1 11.54,84.16 10.82,84.16 10.52,84.47 10.52,87.49 10.32,87.69 9.43,87.69 9.22,87.48 9.22,82.44 HDMI1.7
HDMI_DATA1: length 114.9
  TOP w0.102: v2(21.67,81.25) v1(22.23,81.25)
  L6 w0.102: v2(73.28,51.44) 73.22,51.44 73.06,51.28 73.06,51.26 72.98,51.17 72.98,51.05 73.08,50.95 73.6,50.95 73.73,50.82 73.73,49.51 74.39,48.85 74.39,45.4 72.59,43.59 71.24,43.59 67.87,40.22 66.32,40.22 63,36.9 62.18,36.9 58.4,33.12 34.91,33.12 29.97,38.06 27.11,38.06 20.33,44.85 20.33,46.46 18.48,48.31 18.48,67.66 17.34,68.8 17.34,71.66 16.38,72.62 16.38,74.15 20.66,78.43 20.66,81.53 20.8,81.67 21.11,81.67 21.19,81.59 21.19,81.35 21.29,81.25 v2(21.67,81.25)
  BOTTOM w0.102: v2(73.28,51.44) 73.28,51.14 73.27,51.12 73.27,51.06 73.19,50.98 CPU1.F58 ; C5712.1 20.92,81.06 21.18,81.31 21.61,81.31 v2(21.67,81.25)
HDMI_DATA1#: length 116.2
  TOP w0.102: v1(72.07,51.5) 72.14,51.43 72.62,51.43 v2(72.63,51.44)
  L6 w0.102: v2(21.67,81.88) 20.71,81.88 20.44,81.62 20.44,78.52 16.16,74.24 16.16,72.54 17.13,71.57 17.13,68.71 18.26,67.57 18.26,48.22 20.11,46.38 20.11,44.76 27.02,37.85 29.88,37.85 34.82,32.9 58.49,32.9 62.27,36.68 63.09,36.68 66.41,40 67.96,40 71.33,43.38 72.68,43.38 74.61,45.31 74.61,48.94 73.95,49.6 73.95,50.91 73.72,51.14 73.72,51.61 73.46,51.87 73.1,51.87 72.67,51.44 v2(72.63,51.44)
  BOTTOM w0.102: CPU1.E58 v2(72.63,51.44) ; C5715.1 21.55,81.76 v2(21.67,81.88)
HDMI_DATA1#_R: length 2.2
  BOTTOM w0.102: U5701.4 19.23,80.83 20.03,81.64 C5715.2
HDMI_DATA1#_R_C: length 4
  BOTTOM w0.102: U5701.27 12.58,80.83 R5704.2 10.45,81.67 HDMI1.6
HDMI_DATA1_R: length 2
  BOTTOM w0.102: U5701.5 18.75,80.43 18.95,80.63 19.31,80.63 19.68,81 19.9,81 C5712.2
HDMI_DATA1_R_C: length 5.2
  BOTTOM w0.102: U5701.26 12.69,80.43 12.34,80.78 11.74,80.78 R5704.1 11.32,80.78 11.21,80.89 11.21,81.35 11.09,81.46 10.74,81.46 10.6,81.32 10.6,80.28 10.42,80.1 HDMI1.4
HDMI_DATA2: length 109
  TOP w0.102: v1(22.23,79.34) v2(21.67,79.34)
  L6 w0.102: v2(72.66,53.26) 72.2,52.8 71.53,52.8 70.22,51.49 70.22,45.34 69.77,44.88 69.77,44.74 68.7,43.67 67.37,43.67 64.12,40.42 63.94,40.42 63.21,40.42 61.37,38.58 61.37,37.56 57.96,34.14 35.76,34.14 30.81,39.09 27.86,39.09 21.39,45.56 21.39,46.89 21.36,46.93 21.36,46.93 19.51,48.78 19.51,68.17 18.57,69.11 18.57,72.16 19.08,72.66 19.08,74.44 20.4,75.76 22.05,75.76 22.89,76.6 22.89,78.96 22.51,79.34 v2(21.67,79.34)
  BOTTOM w0.102: C5707.1 21.08,79.34 v2(21.67,79.34) ; CPU1.F55 v2(72.66,53.26)
HDMI_DATA2#: length 108.4
  L6 w0.102: v2(72.02,53.27) 71.77,53.02 71.44,53.02 70.01,51.58 70.01,45.43 69.55,44.97 69.55,44.83 68.61,43.88 67.28,43.88 64.03,40.63 63.12,40.63 61.16,38.67 61.16,37.65 57.87,34.36 35.85,34.36 30.9,39.31 27.95,39.31 21.61,45.65 21.61,46.99 19.72,48.87 19.72,68.26 18.79,69.2 18.79,72.07 19.3,72.57 19.3,74.35 20.49,75.55 22.14,75.55 23.11,76.51 23.11,79.05 22.6,79.56 22.33,79.56 22.23,79.66 22.23,80.1 22.16,80.18 21.88,80.18 v2(21.67,79.98)
  BOTTOM w0.102: C5710.1 20.91,79.89 21.58,79.89 v2(21.67,79.98) ; CPU1.E55 72.1,52.81 72.02,52.89 v2(72.02,53.27)
HDMI_DATA2#_R: length 1.8
  BOTTOM w0.102: U5701.6 18.9,80.03 19.06,79.88 19.36,79.88 19.54,80.05 19.86,80.05 C5710.2
HDMI_DATA2#_R_C: length 6.5
  BOTTOM w0.102: U5701.25 11.91,80.03 R5702.2 11.68,79.8 10.87,79.8 10.55,79.48 10.55,78.72 10.18,78.34 9.67,78.34 8.41,79.6 HDMI1.3
HDMI_DATA2_R: length 1.9
  BOTTOM w0.102: U5701.7 18.96,79.63 19.01,79.67 19.39,79.67 19.93,79.13 C5707.2
HDMI_DATA2_R_C: length 6.6
  BOTTOM w0.102: U5701.24 12.4,79.63 R5702.1 11.32,79.6 10.95,79.6 10.75,79.39 10.75,78.63 10.26,78.14 9.58,78.14 9.12,78.6 HDMI1.1
HDMI_EC_DET#: length 187.2
  TOP w0.102: v2(146.13,51.86) 145.93,52.07 KBC24.69 ; R5723.1 15.86,62.21 15.86,43.81 17.43,42.23 17.43,39.72 v2(16.54,38.83)
  L3 w0.102: v2(125.25,25.77) 126.1,26.62 127.8,26.62 130.03,28.85 131.88,28.85 134.58,31.55 134.58,33.63 140.28,39.34 141.74,39.34 143.62,41.22 143.62,42.39 144.08,42.85 144.08,49.8 146.13,51.85 v2(146.13,51.86)
  L6 w0.102: v2(23.21,39.66) 25.82,37.05 25.82,36.74 26.97,35.59 27.91,35.59 32.54,30.96 32.95,30.96 34.25,29.66 39.19,29.66 39.7,29.15 45.82,29.15 46.23,29.56 59.59,29.56 62.35,32.33 77.77,32.33 78.9,31.2 78.9,28.93 81.06,26.76 83.25,26.76 86.98,23.03 87.99,23.03 88.7,22.32 92.98,22.32 94.63,23.97 102.54,23.97 103.41,23.09 105.88,23.09 106.27,22.7 107.85,22.7 108.79,23.64 116.76,23.64 116.96,23.84 117.89,23.84 118.32,23.41 122.1,23.41 123.41,24.72 124.2,24.72 v2(125.25,25.77)
  BOTTOM w0.102: v2(23.21,39.66) 22.95,39.39 22.01,39.39 21.68,39.72 v1(21.04,39.72) 20.92,39.72 20.03,38.83 v2(16.54,38.83)
HDMI_EC_DET#_C: length 3.9
  TOP w0.102: R5723.2 R5721.2 16.22,64.17 v1(17.05,64.99) 17.3,65.25 Q5704.D
HGNDA: length 21.5
  TOP w0.203: HDA27.25 18.26,25.91 18.2,25.98 18.07,25.98 v1(17.76,26.28) 17.41,26.64 v3(17.05,26.64)
  L3 w1.016: v3(17.05,26.64) 16.42,26.64 15.91,26.13 15.91,21.94 v3(14.51,20.54)
  BOTTOM w1.016: 13.24,21.05 11.82,22.47 4.73,22.47 HPMIC1.3
HGNDB: length 25.1
  TOP w0.203: HDA27.26 18.19,25.51 18.06,25.65 v3(17.03,25.65)
  TOP w1.016: HPMIC1.4 2.55,33.85 3.72,35.02 14,35.02
  L4 w1.016: v3(15.15,35.15) 15.27,35.02 15.27,27.02 16.06,26.23 16.06,26.23 16.64,25.65 v3(17.03,25.65)
  vias: v1(15.93,35.96)
HOME_BTN#: length 4.9
  TOP w0.102: KBC24.3 161.13,42.07 162.45,40.74 R2427.1 R2401.1 164.11,40.74 164.3,40.55 v1(164.55,40.55)
HOME_BTN#_C: length 230.2
  TOP w0.102: v2(161.41,39.85) 161.89,39.37 163.1,39.37 R2401.2 164.07,39.86 164.33,39.59 v1(164.33,39.21)
  L3 w0.102: v2(32.54,97.5) 29.24,94.2 29.24,92.79 28.19,91.74 26.91,91.74 26,90.82 23.86,90.82 22.26,89.22 22.26,85.36 22.69,84.93 22.69,78.35 22.13,77.79 22.13,76.29 21.6,75.76 21.6,66.36 21.45,66.21 21.45,59.84 22.77,58.52 22.77,57.7 21.7,56.63 21.7,54.2 22.97,52.93 23.65,52.93 24.21,52.37 24.21,49.19 24.42,48.99 24.42,45.49 35.77,34.13 43.57,34.13 43.96,34.52 78.05,34.52 81.67,30.91 83.32,30.91 87.15,27.07 95.4,27.07 98.37,24.1 105.36,24.1 106.37,23.08 108.7,23.08 109.06,23.44 110.46,23.44 110.92,23.9 115.92,23.9 117.05,22.78 117.41,22.78 117.43,22.8 121.56,22.8 123.06,21.3 126.76,21.3 126.96,21.51 128.58,21.51 129.49,20.61 130.3,20.61 131.05,21.36 131.05,23 131.88,23.83 132.58,23.83 136.58,27.83 136.58,28.85 141.09,33.35 141.61,33.35 v2(141.62,33.36)
  L4 w0.102: v2(161.41,39.85) 160.33,38.76 160.33,38.26 160.32,38.26 160.32,37.92 160.33,37.92 160.33,37.24 159.99,36.91 156.28,36.91 154.45,38.74 150.85,38.74 150.37,38.26 149.76,38.26 146.66,35.16 146.32,35.16 145.17,35.16 144.92,35.16 144.53,35.54 143.56,35.54 143.03,35.02 143.03,34.29 142.72,33.98 142.23,33.98 v2(141.62,33.36)
  BOTTOM w0.102: v2(32.54,97.5) 31.83,98.22 31.27,98.22 30.74,98.75 HOMBD1.8
HOST_DEBUG_TX: length 48.1
  TOP w0.102: v2(137.37,35.6) v1(137.37,34.59) 137.37,32.27 136.08,30.99 135.7,30.99 133.99,29.28 133.99,28.67 133.97,28.64 v2(133.97,28.37) 133.97,27.36 R2442.2 135.13,26.19 R2467.2 ; v2(145.96,47.08) 145.77,47.27 KBC24.81 ; R2480.1 R2482.2 119.56,23.59 119.31,23.84 v2(119.29,23.84)
  L3 w0.102: v2(145.96,47.08) 145.75,46.88 145.65,46.88 144.28,45.51 144.28,42.77 143.82,42.31 143.82,41.13 141.82,39.13 140.83,39.13 137.37,35.67 v2(137.37,35.6)
  L4 w0.102: v2(119.29,23.84) 119.79,24.35 120.43,24.35 120.97,24.89 120.97,25.26 122.22,26.51 123.22,26.51 123.9,27.2 132.37,27.2 133.48,28.31 133.92,28.31 v2(133.97,28.37)
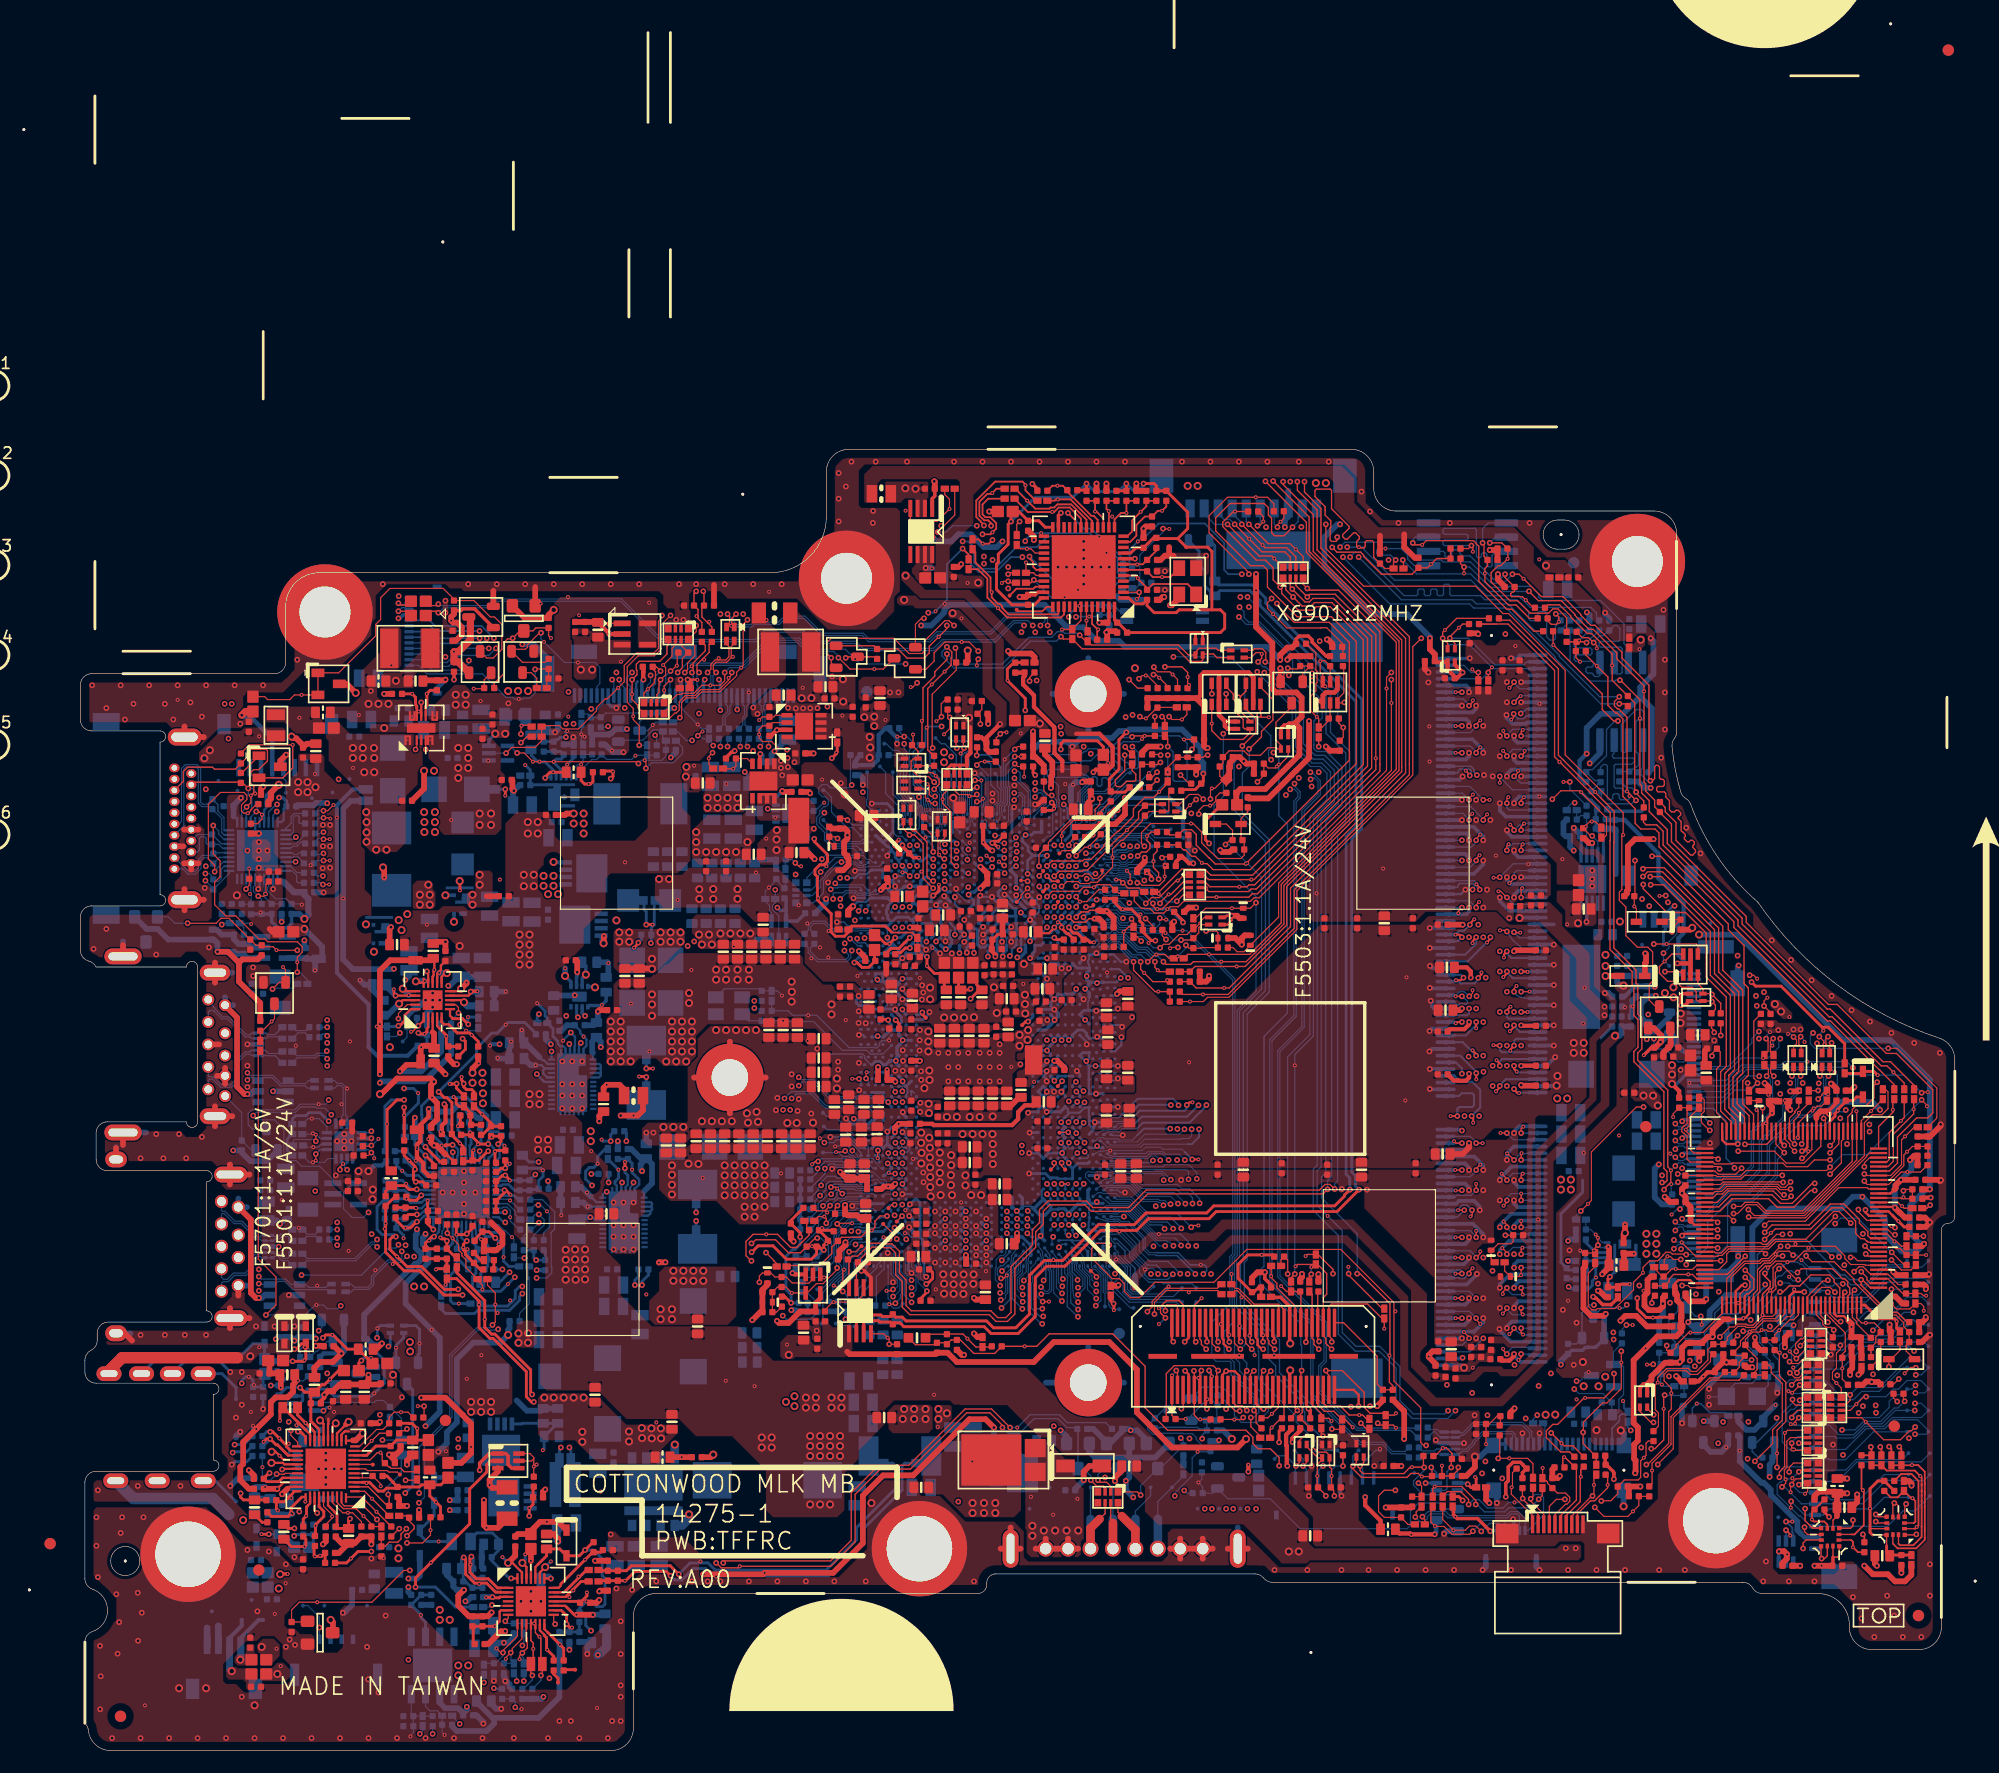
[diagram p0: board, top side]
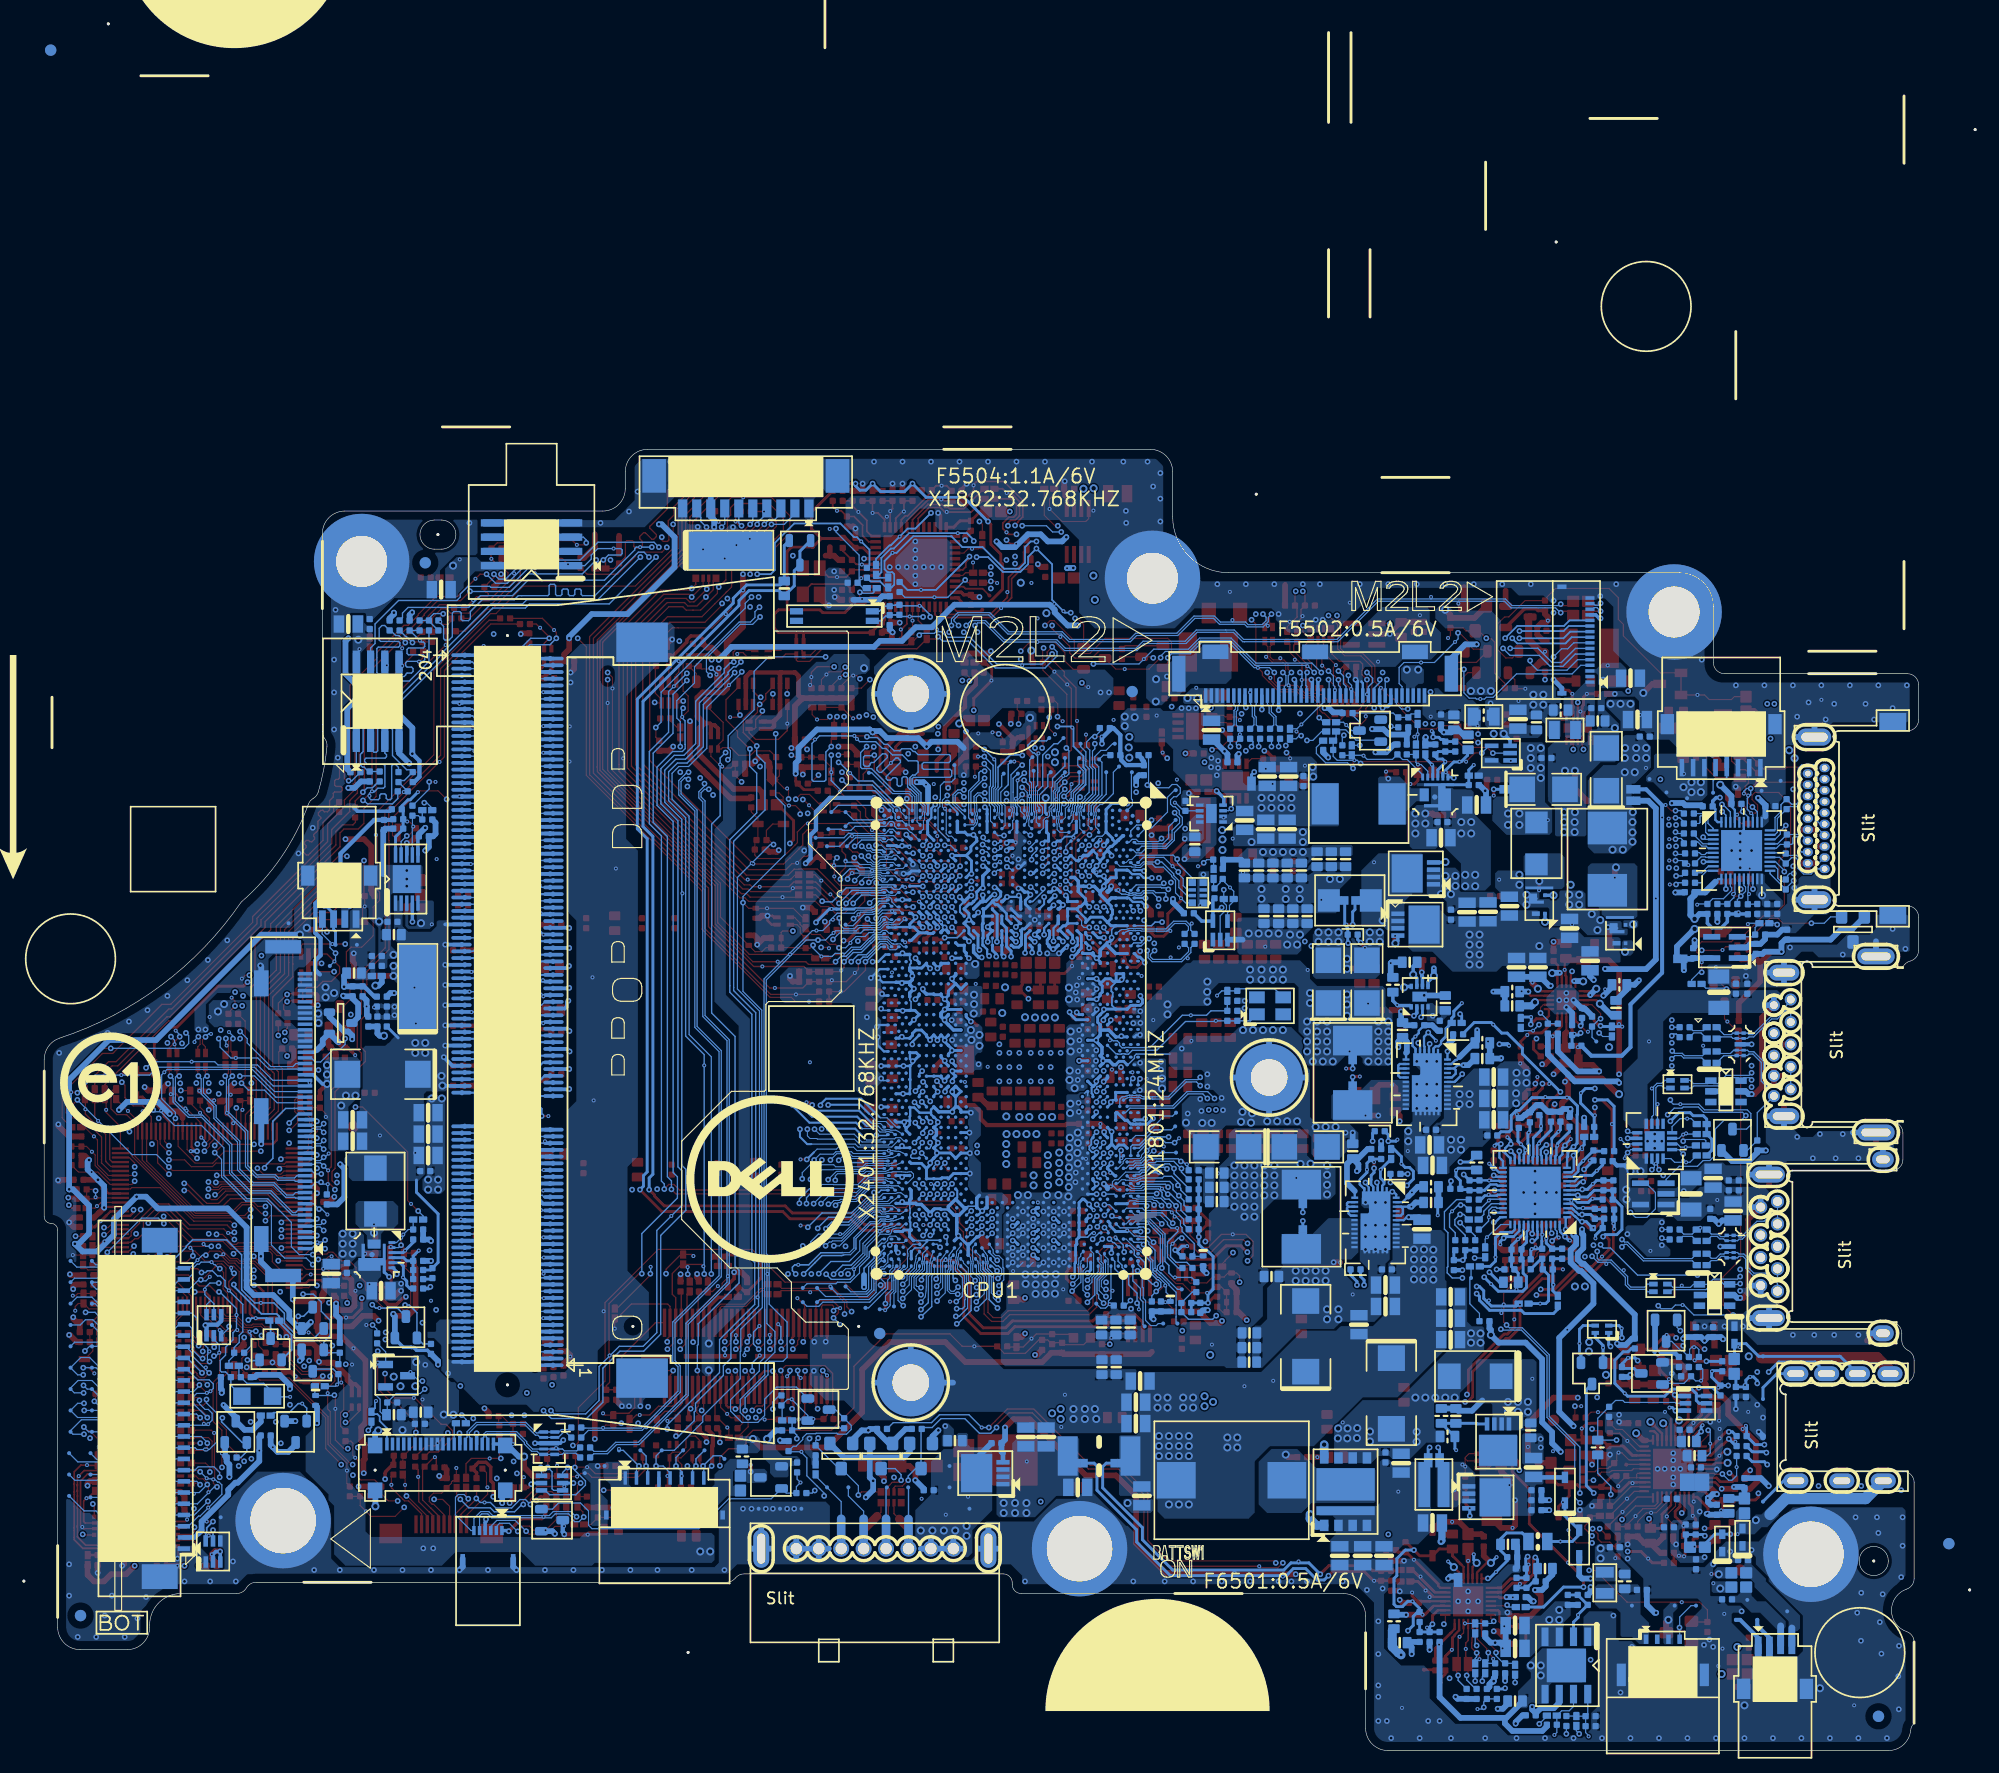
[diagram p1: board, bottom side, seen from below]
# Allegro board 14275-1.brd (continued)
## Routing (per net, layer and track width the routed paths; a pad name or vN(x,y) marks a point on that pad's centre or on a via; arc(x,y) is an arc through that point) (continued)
HPD_HDMI_CON: length 30.9
  TOP w0.102: v2(19.34,69.39) v1(19.34,70.28) 19.34,70.73 19.77,71.16 19.77,71.67 19.34,72.1 16.7,72.1 16.45,72.36 15.91,72.36 13.86,74.4 12.97,74.4 11.97,75.41 11.97,77.41 12.45,77.9 12.45,79.32 11.84,79.93 v2(11.84,82.47)
  L4 w0.102: HDMI1.19 8.5,87.72 10.45,87.72 11.18,86.99 v2(11.18,85.69)
  L6 w0.102: v2(11.18,85.69) 11.34,85.53 11.37,85.53 11.64,85.26 11.64,82.67 v2(11.84,82.47)
  BOTTOM w0.102: v2(11.84,82.47) 12.33,81.98 12.33,81.71 12.8,81.23 U5701.28 ; R5722.2 20.24,68.71 19.56,69.39 v2(19.34,69.39)
HPD_HDMI_CON_C: length 5.3
  TOP w0.102: v2(17.13,67.89) 17.72,68.48 Q5704.G 18.29,69.62 v1(18.07,69.84)
  BOTTOM w0.102: R5722.1 18.97,67.96 17.2,67.96 v2(17.13,67.89)
HSIO_OUT:
  vias: v1(61.96,83.18)
HSIOPC_R: length 3.6
  TOP w0.102: R1733.2 57.32,87.52 v1(58.2,87.52) 58.44,87.76 C1719.1 59.45,88.44 U1702.4
HSYNC_LCD: length 16.7
  TOP w0.102: R5517.1 41.44,97.01 39.42,97.01 Q5502.S 38.62,98.18 39.68,98.18 39.85,98.35 39.85,98.56 40.93,99.64 v2(41.07,99.64)
  BOTTOM w0.102: LCD1.36 46.05,94.86 46.31,95.12 46.31,96.56 45.88,97 43.16,97 v1(41.33,98.83) 41.05,99.1 41.05,99.63 v2(41.07,99.64)
HSYNC_R: length 2.3
  TOP w0.102: Q5502.D 40.19,96.09 40.69,95.6 R5516.1
HSYNC_TPNL: length 17.8
  TOP w0.102: R5516.2 41.57,95.42 R5518.2 41.74,95.59 R5517.2 40.58,96.43 v2(40.54,96.39)
  BOTTOM w0.102: HOMBD1.4 30.12,96.75 30.89,95.98 35.85,95.98 37.93,93.9 38.54,93.9 38.69,93.74 v1(39.08,93.74) 39.42,93.74 39.5,93.82 40.06,93.82 40.54,94.3 v2(40.54,96.39)
HUB_PA1: length 6.2
  TOP w0.152: U6901.11 93.59,107.75 94.14,108.3 94.14,109.25 94.9,110.01 R6918.2 96.04,110.52 v1(96.43,110.52) 96.81,110.9 R6919.1
HUB_PA2: length 5.1
  TOP w0.152: U6901.12 93.33,108.26 93.76,108.68 93.76,109.66 v1(94.52,110.42) 95.03,110.93 R6916.2 R6917.1
HUB_PA3: length 4
  TOP w0.152: R6914.2 R6915.1 v1(93.25,110.33) 92.76,110.33 92.19,109.76 U6901.13
HUB_PA4: length 3.3
  TOP w0.152: R6913.1 R6912.2 91.47,110.7 v1(91.68,110.49) 91.69,110.48 U6901.14
HUB_PA5: length 3.7
  TOP w0.152: R6911.1 R6910.2 90.46,111.28 90.46,110.58 90.46,110.58 v1(90.46,110.45) 90.59,110.45 91.19,109.85 U6901.15
HUB_PA6: length 6.7
  TOP w0.152: R6908.2 86.65,112.76 v1(87.1,112.76) 87.59,112.76 R6909.1 87.98,112.23 90.13,110.07 90.33,110.07 90.69,109.72 U6901.16
I2C0_SCL: length 9
  TOP w0.114: v2(76.11,85.7) 76.55,86.13 76.55,86.59 v1(76.26,86.89) 75.97,87.18 74.87,87.18 74.67,87.38 RN2007.1 74.68,87.79 R2020.1
  BOTTOM w0.089: CPU1.N3 76.61,82.39 76.61,82.6 76.67,82.73 76.67,82.93 76.64,83.03 76.64,83.31 76.67,83.38 76.67,83.58 76.63,83.7 76.62,83.71 76.59,83.75 76.59,84.26 76.59,84.26 76.59,85.23 76.12,85.7 v2(76.11,85.7)
I2C0_SCL_R: length 13.3
  TOP w0.114: RN6503.3 113.75,25.68 v2(113.44,25.37) 113.44,25.11 114.21,24.35 118.26,24.35 118.62,24.71 119.26,24.71 119.54,24.43 v1(119.59,24.43) 120.44,24.43 R6505.2 120.49,25.18 v2(120.43,25.24)
  BOTTOM w0.114: AFTP6534.1 113.44,26.26 v2(113.44,25.37) 113.3,25.22 TP1.3 ; Q6504.6 120.89,24.78 v2(120.43,25.24)
I2C0_SCL_TCH_PAD: length 100.4
  TOP w0.114: v2(122.84,25.24) 122.84,25.05 EC6503.1 R6505.1 v1(121.38,25.39)
  L3 w0.089: v2(79.16,80.33) 79.77,79.72 79.77,78.67 79.97,78.46 79.97,77.75 79.63,77.41 78.97,77.41 78.84,77.28 78.84,77.26 78.73,77.15 78.73,76.09 79.16,75.67
  L3 w0.114: v2(122.84,25.24) 122.4,25.68 121.76,25.68 120.86,24.78 110.55,24.78 110.09,24.33 108.7,24.33 108.34,23.96 106.84,23.96 106.58,24.22 106.58,24.49 105.4,25.66 103.45,25.66 103.38,25.6 98.12,25.6 95.66,28.06 93.15,28.06 91.88,29.33 87.54,29.33 84.11,32.76 84.11,38.04 83.09,39.06 83.09,43.91 81.54,45.46 81.54,45.68 81.54,45.68 81.54,46.44 81.54,46.44 81.54,47.09 81.54,47.09 81.54,48.5 81.54,49.5 82.3,50.25 82.3,57.26 83.17,58.14 83.17,67.6 80.45,70.33 80.45,71.47 80.04,71.88 80.04,74.79 79.16,75.67
  BOTTOM w0.114: v2(79.16,80.33) 79.16,80.56 CPU1.U6 ; Q6504.1 122.76,25.16 v2(122.84,25.24)
I2C0_SDA: length 12.1
  TOP w0.114: v1(74.23,90.57) 74.23,89.72 R2021.1 74.67,89.09 RN2007.2 74.27,88.43 74.06,88.22 74.06,87.49 74.71,86.84 75.61,86.84 v2(76.11,86.33)
  BOTTOM w0.089: 76.74,85.43 76.77,85.4 76.77,84.19 76.77,83.92 76.81,83.88 76.81,83.72 76.85,83.63 76.85,83.34 76.83,83.3 76.81,83.27 76.81,83.07 76.85,82.98 76.85,82.69 76.8,82.59 76.8,82.1 76.55,81.85 75.76,81.85 CPU1.M4
  BOTTOM w0.114: 76.74,85.43 76.61,85.56 76.61,85.83 v2(76.11,86.33)
I2C0_SDA_R: length 18.3
  TOP w0.114: R6506.2 119.73,25.3 119.77,25.27 ; 119.77,25.27 v2(119.79,25.24) ; 119.77,25.27 v1(118.7,25.27) 118.68,25.24 118.52,25.24 117.98,24.69 114.35,24.69 114.08,24.96 v2(114.08,25.37) 114.4,25.69 RN6503.4
  BOTTOM w0.114: Q6504.3 122.44,23.19 122.05,22.81 119.7,22.81 118.85,23.66 118.85,24.03 119.79,24.98 v2(119.79,25.24) ; TP1.2 114.3,25.15 v2(114.08,25.37) 115.48,26.76 AFTP6535.1
I2C0_SDA_TCH_PAD: length 102.4
  TOP w0.114: R6506.1 120.76,26.26 v1(121.47,26.97) 121.49,26.99 121.77,26.99 122.27,26.5 EC6504.1 122.21,25.94 v2(122.21,25.24)
  L3 w0.089: v2(79.08,79.42) 79.08,78.9 79.65,78.33 79.65,77.97 79.41,77.72 78.83,77.72 78.52,77.41 78.52,77.03 78.53,77.02 78.53,75.81 78.79,75.55
  L3 w0.114: v2(122.21,25.24) 121.8,25.24 121,24.44 110.69,24.44 110.23,23.98 108.84,23.98 108.48,23.62 106.65,23.62 104.96,25.32 103.59,25.32 102.98,24.71 98.53,24.71 95.52,27.71 93,27.71 91.73,28.99 87.4,28.99 83.75,32.63 83.75,37.61 82.75,38.61 82.75,43.77 81.2,45.31 81.2,45.53 81.2,45.54 81.2,46.58 81.2,48.64 81.2,48.64 81.2,49.64 81.96,50.4 81.96,57.12 81.96,57.41 82.83,58.28 82.83,67.46 80.11,70.18 80.11,71.33 79.69,71.74 79.69,74.65 78.79,75.55
  BOTTOM w0.114: Q6504.4 121.68,23.19 121.83,23.34 121.83,24.86 v2(122.21,25.24) ; CPU1.U7 78.63,80.22 79.08,79.77 v2(79.08,79.42)
I2C1_SCL: length 6.5
  TOP w0.114: RN2008.2 75.27,86.4 75.68,86 75.68,85.23 75.85,85.06 76.19,85.06 v2(76.19,85.06)
  BOTTOM w0.089: CPU1.N2 76.07,83.18 76.07,83.98 75.79,84.26 75.79,84.66 v2(76.19,85.06) 76.18,85.06 75.77,85.47 75.75,85.49 75.57,85.67 75.57,86.09 v1(75.52,86.15)
I2C1_SDA: length 3.4
  TOP w0.114: RN2008.1 75.13,85.75 75.33,85.55 75.33,84.97 v1(75.55,84.75) 75.87,84.43 v2(76.19,84.43)
  BOTTOM w0.089: v2(76.19,84.43) 76.41,84.2 CPU1.N1
I_ADP: length 20.2
  TOP w0.102: KBC24.110 151.56,38.96 151.1,38.5 149.99,38.5 149.2,37.72 148.52,37.72 148.41,37.82 147.78,37.82 146.82,36.87 146.82,36.59 C2435.1 R2421.2 145.09,35.74 145.09,34.81 144.07,33.8 143.61,33.8 143.34,34.06 141.42,34.06 140.62,33.26 v1(140.62,32.81) 140.4,32.59 140.4,30.39 140.68,30.11 140.68,28.92 R2471.1
I_BATT: length 5.1
  TOP w0.102: C2441.1 R2423.2 151.04,37.07 v1(151.45,37.48) 152.37,38.4 152.72,38.4 153.16,38.84 KBC24.114
I_SYS: length 10.8
  TOP w0.102: R2497.2 R2422.2 149.2,33.69 149.49,33.98 149.49,34.95 148.43,36.01 C2427.1 148.43,36.66 149.08,37.31 149.71,37.31 v1(149.89,37.49) 150.32,37.49 150.44,37.37 150.83,37.37 152.14,38.68 152.44,38.68 152.76,39 KBC24.113
ICSP_CLK_R: length 8
  TOP w0.102: R2466.2 121.44,20.6 v1(122.41,19.64) 123.46,19.64 123.83,20.01 124.42,20.01 v2(124.89,19.54)
  BOTTOM w0.102: DB3.2 126.79,19.97 126.5,20.26 125.64,20.26 124.91,19.54 v2(124.89,19.54)
ICSP_CLOCK: length 47.1
  TOP w0.114: v2(123.76,21.94) 123.76,22.38 123.05,23.09 121.86,23.09 121.44,22.68 R2466.1 ; JTAG1.2 129.96,21.05 128.58,22.42 v2(128.58,22.47) 128.56,22.5 R2420.2 ; KBC24.101 147.96,40.71 148.31,41.06 148.58,41.06 148.83,41.32 148.83,41.77 v2(148.42,42.18)
  L3 w0.114: v2(148.42,42.18) 147.89,41.65 147.89,39.89 143.22,35.22 142.19,35.22 136.04,29.07 136.04,28.05 134.89,26.9 133.68,26.9 130.47,23.68 130.47,22.47 130.47,22.04 130.1,21.67 129.4,21.67 129.22,21.84 129.21,21.84 v2(128.58,22.47)
  BOTTOM w0.114: v2(128.58,22.47) 128.23,22.12 v1(127.84,22.12) 127.32,22.12 126.83,21.63 125.43,21.63 124.68,22.38 124.19,22.38 v2(123.76,21.94)
ICSP_CLR: length 56.2
  TOP w0.102: R2465.1 129.5,25.57 129.02,26.05 v1(127.39,26.05) v2(126.39,26.05) 126.52,26.18 R2477.1 ; v2(145.96,44.8) 145.89,44.87 KBC24.87 ; v2(117.23,23.21) 116.24,23.21 115.73,22.7 115.73,21.3 116.25,20.78 R2414.1 118.36,20.16 R2483.2
  L3 w0.102: v2(145.96,44.8) 145.79,44.63 145.79,41.96 145.42,41.59 145.42,40.1 144.98,39.66 144.5,39.66 143.76,38.92 143.76,38 142.95,37.18 141.02,37.18 139.07,35.23 139.07,34.51 132.36,27.8 132.1,27.8 130.34,26.05 v2(126.39,26.05)
  L4 w0.102: v2(126.39,26.05) 126.23,26.21 125.07,26.21 123.85,24.99 123.27,24.99 121.04,22.75 117.68,22.75 v2(117.23,23.21)
ICSP_DATA: length 46.2
  TOP w0.114: KBC24.102 148.36,40.53 148.55,40.72 148.72,40.72 149.17,41.17 149.17,42.06 v2(148.42,42.82) ; R2474.1 130.33,22.73 v2(130,22.4) ; v2(124.39,21.94) 124.39,22.29 123.15,23.54 v1(120.73,23.54) 120.56,23.36 R2464.2
  L3 w0.114: v2(148.42,42.82) 147.54,41.94 147.54,40.02 143.08,35.56 142.05,35.56 135.7,29.21 135.7,28.19 134.75,27.24 133.5,27.24 130.03,23.77 130.03,22.42 v2(130,22.4)
  BOTTOM w0.114: v2(124.39,21.94) 124.51,21.94 125.17,21.28 126.97,21.28 127.33,21.64 129.25,21.64 v2(130,22.4)
ICSP_DATA_R: length 9.9
  TOP w0.102: R2464.1 120.4,21.6 120.4,20.36 v1(120.76,20.01) 120.78,19.98 121.56,19.98 122.26,19.28 123.87,19.28 v2(124.14,19.55)
  BOTTOM w0.102: DB3.3 127.29,19.98 126.75,20.52 125.1,20.52 v2(124.14,19.55)
ICSP_MCLR_R: length 33.2
  TOP w0.102: v2(135.01,21.68) 135.82,20.87 137.95,20.87 v1(138.41,21.33) 138.93,21.85 R2425.2 138.94,22.66 R2468.2 ; v2(119.64,20.85) 119.64,20.8 119.86,20.58 R2483.1 ; R2465.2 129.5,22.65 v2(129.29,22.45) 129.29,22.24 130.46,21.08 JTAG1.3
  L4 w0.102: v2(129.29,22.45) 130.05,21.68 v2(135.01,21.68)
  BOTTOM w0.102: v2(129.29,22.45) 129.67,22.83 130.18,22.83 130.44,22.58 130.44,21 129.05,19.61 DB3.6 128.79,20.7 128.18,21.3 127.47,21.3 127.11,20.95 122.08,20.95 121.72,21.3 120.14,21.3 119.69,20.85 v2(119.64,20.85)
ILIM_HI: length 2.4
  TOP w0.102: R3404.2 25.69,53.05 v2(25.94,53.31)
  BOTTOM w0.102: U3401.16 25.67,53.57 v2(25.94,53.31) 26.19,53.05 v1(26.19,52.8)
ILIM_LO: length 2.6
  TOP w0.102: R3403.2 25.88,53.88 v2(25.94,53.94)
  BOTTOM w0.102: U3401.15 25.81,54.07 v2(25.94,53.94) 25.99,53.94 v1(26.58,54.53)
ILIM_SEL: length 3.4
  BOTTOM w0.102: U3401.4 22.08,52.77 21.75,52.44 v1(20.73,52.44) 20.39,52.44 R3405.2
INT2_SELECT: length 54.4
  TOP w0.152: v2(152.05,19.65) 152.43,19.27 v1(152.43,19.17) ; v2(158.91,19.27) 159.04,19.14 R7017.2 ; v2(161.24,27.09) 161.45,26.88 R7013.1
  L4 w0.152: v2(152.05,19.65) 152.76,20.36 155.91,20.36 157,19.27 v2(158.91,19.27)
  L6 w0.152: v2(161.24,27.09) 158.91,24.76 v2(158.91,19.27) ; v2(150.2,41.55) 150.16,41.51 150.16,38.61 149.73,38.18 149.73,37.93 148.82,37.02 148.82,36.64 149.73,35.73 149.73,34.38 150.4,33.7 150.4,33.24 150.81,32.84 150.81,30.2 150.53,29.93 150.53,25.33 150.07,24.87 150.07,23.88 152.54,21.41 152.54,20.14 v2(152.05,19.65)
  BOTTOM w0.152: v2(150.2,41.55) 150.2,41.41 150.06,41.27 150.06,41.26 147.73,38.93 146.39,38.93 146.15,38.69 R7008.1 146.15,38.17 145.05,37.07 145.05,35.71 D7001.2 ; Q7001.5 v2(152.05,19.65)
INT_TP#: length 142.1
  TOP w0.102: v2(148.7,48.23) 149.23,47.7 153.7,47.7 159.04,53.04 159.04,55.98 159.73,56.67 159.79,56.67 159.81,56.69 160.61,56.69 161.14,57.22 161.14,58.72 160.9,58.96 R2431.1 ; v2(102.08,80.77) 102.48,81.17 R410.1 102.71,82.04 102.15,82.6 D401.K ; R6511.2 v2(112.55,25.37)
  L3 w0.102: v2(112.55,25.37) 112.99,25.8 121.24,25.8 121.46,26.02 122.68,26.02 123.37,25.32 123.37,24.67 124.62,23.43 127.94,23.43 129.21,23.43 133.36,27.58 134.33,27.58 134.6,27.85 134.6,29.1 139.68,34.17 139.68,34.98 141.27,36.57 143.26,36.57 146.95,40.27 146.95,42.32 147.35,42.72 147.35,45.59 148.27,46.51 148.27,47.8 v2(148.7,48.23)
  BOTTOM w0.102: v2(102.08,80.77) 102.36,80.77 v1(104.02,79.11) 105.3,77.83 105.3,67.89 103.33,65.92 103.33,44.04 103.08,43.79 103.08,39.49 105,37.57 105,35.61 105.05,35.56 105.05,33.15 108.39,29.81 108.39,29.3 110.93,26.76 AFTP6536.1 112.55,26.26 v2(112.55,25.37) 111.92,25.37 111.3,24.75 TP1.5
ISET: length 4.1
  TOP w0.102: R5414.2 15.79,82.63 16.19,83.03 v1(16.19,83.43) 15.91,83.71 v2(15.68,83.71)
  BOTTOM w0.102: U5701.34 15.18,83.21 v2(15.68,83.71) 15.79,83.83 R5413.2
ITP_PMODE: length 118
  TOP w0.102: R9933.1 107.04,43.76 R9932.2 107.63,43.72 v2(107.63,42.49)
  L3 w0.102: v2(69.76,85.44) 71.03,85.44 72.17,84.3 72.17,80.49 72.63,80.02 v2(72.63,78.87)
  L4 w0.102: v2(104.91,96.17) 103.88,95.14 100.41,95.14 99.25,93.98 93.9,93.98 92.51,95.37 92.51,96.11 91.8,96.83 87.51,96.83 85.14,94.46 82.08,94.46 81.06,93.44 70.44,93.44 69.33,92.33 69.33,91.14 68.49,90.29 68.49,88.99 69.04,88.44 69.04,87.86 70.19,86.72 70.19,85.87 v2(69.76,85.44)
  BOTTOM w0.102: v2(104.91,96.17) 104.91,96.12 v1(106.06,94.98) 108.03,93 108.03,89.35 109.66,87.72 110.52,87.72 111.13,87.12 111.13,84.82 109.61,83.3 109.61,63.83 107.63,61.85 v2(107.63,42.49) ; v2(72.63,78.87) 72.31,79.19 CPU1.E8
JTAG_CLK: length 15.3
  TOP w0.102: v2(135.59,22.25) 135.61,22.27 136.43,22.27 137.05,22.89 R2438.2 137.64,24.12 138.87,24.12 139.1,24.35 139.1,25.83 v1(139.38,26.1) 139.58,26.31 139.58,27.4 139.77,27.59 R2471.2 ; JTAG1.4 130.96,21.77 131.58,22.4 v2(132.34,22.4)
  L4 w0.102: v2(132.34,22.4) 132.49,22.25 v2(135.59,22.25)
JTAG_PU: length 5.9
  TOP w0.102: JTAG1.1 129.46,20.96 127.57,22.85 127.57,23.44 v1(127.59,23.46) 127.67,23.54 127.67,24.77 R2403.2
JTAG_RST#: length 4.2
  TOP w0.102: v1(125.31,27.31) C2419.1 R736.1 125.59,29.12 126.29,29.81 R2461.2 126.59,29.05 R2477.2
JTAG_TDO: length 7.1
  TOP w0.102: v1(130.36,25.19) 130.36,24.31 R2474.2 130.58,24.05 130.69,24.05 130.79,23.94 130.79,23.83 R2439.2 131.67,22.95 132.39,22.95 132.77,22.58 132.77,22.22 132.52,21.96 132.39,21.96 131.46,21.03 JTAG1.5
KB_BL_CTRL#: length 1.2
  TOP w0.508: Q6501.D 22.51,10.53 22.51,11.45 v3(22.31,11.65)
KB_CLOSE#_2: length 209.2
  TOP w0.102: v2(9.56,73.75) 12.1,73.75 12.54,74.2 13.24,74.2 C7001.1 15.65,71.79 R7001.1 16.29,71.66 17.19,71.66 v1(17.48,71.37) 17.51,71.34 v2(19.34,71.34) ; KBC24.23 159.41,50.07 159.29,50.19 156.76,50.19 153.76,47.19 150.5,47.19 v2(150.15,46.83)
  L3 w0.102: v2(150.15,46.83) 149.71,46.4 149.71,39.81 147.3,37.39 147.3,36.01 144.93,33.64 143.52,33.64 142.8,32.92 141.08,32.92 137.41,29.26 137.28,29.26 136.79,28.76 136.79,27.74 132.67,23.62 131.96,23.62 131.32,22.98 131.32,21.34 130.38,20.4 129.4,20.4 128.5,21.3 127.05,21.3 126.85,21.1 122.98,21.1 121.48,22.6 117.52,22.6 117.49,22.57 116.96,22.57 115.86,23.68 110.98,23.68 110.54,23.24 109.15,23.24 108.71,22.8 108.37,22.8 108.3,22.88 106.24,22.88 105.32,23.79 98.39,23.79 95.67,26.51 87.28,26.51 83.37,30.42 81.77,30.42 77.87,34.32 44.04,34.32 43.65,33.93 35.69,33.93 24.15,45.46 24.15,48.74 21.75,51.14 21.75,52.8 21.5,53.05 21.5,56.71 22.56,57.78 22.56,58.44 21.24,59.76 21.24,69.06 19.34,70.96 v2(19.34,71.34)
  BOTTOM w0.102: LIDSW1.3 7.85,74.32 8.41,73.75 v2(9.56,73.75)
KB_DISABLE: length 178.4
  TOP w0.102: v2(96.51,108.93) 96.54,108.91 v1(97.07,108.91) ; v2(146.15,36.87) 147.04,37.76 147.43,37.76 147.69,38.02 148.5,38.02 148.6,37.92 149.1,37.92 149.89,38.71 149.92,38.71 150.86,38.71 151.16,39 KBC24.109
  L3 w0.102: v2(92.98,79.67) 92.98,79.71 93.44,80.18 94.07,80.18 94.08,80.18 94.43,80.18 94.46,80.15 95.01,80.15 95.29,80.43 95.29,84.45 97.36,86.53 97.36,87.26 97.72,87.61 97.72,90.9 98.58,91.77 98.58,96.73 101.71,99.86 101.71,107.6 100.38,108.93 v2(96.51,108.93) ; v2(146.15,36.87) 146.15,37.51 148.85,40.21 148.85,47.04 149.43,47.63 149.43,54.48 148.22,55.7 148.22,56.64 144.99,59.87 144.99,61.24 143.34,62.89 141.77,62.89 139.94,64.73 139.94,65.45 v2(139.77,65.62)
  L4 w0.102: v2(92.98,79.67) 92.98,79.59 93.6,78.96 95.54,78.96 95.79,79.22 95.79,82.52 98.22,84.95 98.22,85.01 98.54,85.33 99.33,86.12 103.25,86.12 104.21,87.09 105.92,87.09 107.16,88.32 107.16,88.61 107.16,90 109.45,92.29 110.4,92.29 110.78,92.66 110.78,92.68 111.24,93.14 111.77,93.14 119.33,100.7 126.76,100.7 129.9,97.57 129.9,97.19 132.1,94.99 132.1,85.9 132.53,85.47 132.53,83.7 132.29,83.46 132.29,78.56 133.08,77.77 133.08,75.81 132.56,75.29 132.56,73.82 133.76,72.61 133.76,69.31 135.07,68 136.26,68 138.63,65.63 139.76,65.63 v2(139.77,65.62)
  BOTTOM w0.089: v2(92.98,79.67) 92.97,79.67 91.53,79.67 91.38,79.82 91.1,79.82 90.76,79.49 CPU1.AY8
  BOTTOM w0.102: v2(96.51,108.93) 96.51,108.64 94.45,106.58 94.45,104.24 R2022.1 94.1,103.63 R6920.1
KB_DISABLE_HUB: length 3.9
  TOP w0.102: v1(94.19,102.66) 94.42,102.89 94.42,103.22 v2(94.39,103.26) U6901.2
  BOTTOM w0.102: R6920.2 93.12,103.38 93.12,103.27 93.23,103.17 94.11,103.17 94.2,103.26 v2(94.39,103.26)
KBC_BEEP_R: length 2.9
  BOTTOM w0.254: D2701.1 v1(28.13,35.91) 28.13,36.12 28.83,36.81 RN2701.4
KBC_PWRBTN#: length 36.7
  TOP w0.102: R2432.1 160.34,34.9 v2(160.34,35.22) 160.5,35.38 EC6601.1
  L4 w0.102: v2(160.34,35.22) 160.34,36.68 160.73,37.07 160.73,38.09 162.13,39.49 162.13,41.26 162.3,41.43 162.3,44.21 161.13,45.38 159.3,45.38 159.27,45.41 158.91,45.41 158.89,45.38 151.11,45.38 150.65,44.93 148.79,44.93 146.74,46.98 146.74,47.2 145.67,48.27 v2(142.6,48.27)
  BOTTOM w0.102: IOBD1.9 143.08,48.75 v2(142.6,48.27) 142.34,48.27 v1(141.85,47.78)
KSI0: length 37.4
  TOP w0.102: KBC24.98 146.76,42.06 148.33,43.63 149.64,43.63 149.87,43.86 150.48,43.86 v2(151.57,44.95) ; v1(162.63,33.62) 163.16,34.15 163.6,34.15 v2(163.62,34.13) ; v1(152.6,31.89) 153.19,32.48 153.19,32.51 153.27,32.58 v2(153.27,32.6) 153.28,32.6 RN2403.8
  L6 w0.102: v2(153.27,32.6) 153.19,32.6 152.55,33.24 152.22,33.24 151.39,34.06 151.39,36.28 152.02,36.92 152.02,41.41 152.04,41.44 152.04,41.79 152.02,41.81 152.02,43.16 151.32,43.87 151.32,44.7 v2(151.57,44.95)
  BOTTOM w0.102: v2(153.27,32.6) 153.28,32.58 153.28,32.51 153.79,32 KB1.15 155.78,32 156.49,31.29 158.06,31.29 158.8,32.02 160.37,32.02 162.48,34.13 AFTP6512.1 v2(163.62,34.13)
KSI1: length 37.3
  TOP w0.102: v2(152.69,44.16) 152.33,44.52 151.42,44.52 150.56,43.66 149.96,43.66 149.73,43.42 148.41,43.42 147.16,42.17 KBC24.99 ; RN2403.7 153.52,33.25 153.3,33.03 153.11,33.03 153.1,33.03 152.98,33.03 v2(152.56,32.61)
  L6 w0.102: v2(152.69,44.16) 153.1,43.75 153.23,43.75 154.52,42.46 154.52,34.84 153.87,34.19 153.87,32.57 153.46,32.16 153.37,32.16 153,32.16 v2(152.56,32.61)
  BOTTOM w0.102: AFTP6501.1 162.49,43.3 160.88,43.3 159.11,41.53 157.82,41.53 157.24,42.11 156.44,42.11 155.55,43 KB1.26 154.16,43 v1(153.44,43.72) 152.99,44.16 v2(152.69,44.16)
KSI2: length 37.8
  TOP w0.102: RN2403.6 153.6,33.75 153.47,33.61 153.47,33.48 153.22,33.23 152.83,33.23 v2(152.4,33.67) ; v2(152.2,44.95) 156.45,44.95 157.29,44.11 157.29,43.87 157.83,43.33 159.06,43.33 159.12,43.27 KBC24.6
  L6 w0.102: v2(152.2,44.95) 152.2,43.92 152.58,43.55 153.15,43.55 154.32,42.38 154.32,35.36 153.06,34.1 152.83,34.1 v2(152.4,33.67)
  BOTTOM w0.102: v1(152.9,45.15) 152.69,44.95 v2(152.2,44.95) ; v2(152.4,33.67) 153.93,35.2 153.93,35.47 154.45,36 KB1.19 155.64,36 155.91,35.73 156.69,35.73 156.72,35.7 157.08,35.7 157.09,35.71 157.14,35.71 158.11,36.68 161.58,36.68 AFTP6508.1
KSI3: length 33.5
  TOP w0.102: KBC24.7 158.43,43.67 158.13,43.97 v2(157.81,43.97) ; RN2403.5 153.63,34.4 153.03,33.8 v2(153.03,33.67) 152.69,34.01 v1(152.69,34.15)
  L3 w0.102: v2(156.62,33.45) 156.62,35.45 156.45,35.63 156.45,36.44 158.78,38.78 158.78,41.15 157.69,42.25 157.69,43.69 157.81,43.81 v2(157.81,43.97)
  L4 w0.102: v2(156.62,33.45) 153.77,33.45 153.54,33.67 v2(153.03,33.67)
  BOTTOM w0.102: v2(153.03,33.67) 154.36,35 KB1.18 155.48,35 155.74,34.74 156.99,34.74 158.66,36.41 164.38,36.41 AFTP6509.1
KSI4: length 37.8
  TOP w0.102: KBC24.104 149.16,40.68 149.51,41.03 149.51,42.85 150.11,43.45 150.64,43.45 151.28,44.09 v2(151.75,44.09) ; RN2404.8 154.05,35.39 153.17,34.51 152.53,34.51 v2(152.37,34.67)
  L6 w0.102: v2(152.37,34.67) 152.53,34.51 153.11,34.51 153.11,34.52 153.16,34.52 153.41,34.77 153.41,34.81 154.11,35.52 154.11,42.29 153.06,43.34 152.49,43.34 v2(151.75,44.09)
  BOTTOM w0.102: v2(151.75,44.09) 151.7,44.14 151.23,44.14 v1(151.12,44.25) ; AFTP6505.1 164.17,40.43 162.85,40.43 161.83,39.41 157.79,39.41 157.38,39 KB1.22 153.94,39 153.5,38.56 153.5,36.88 153.14,36.53 153.14,36.52 152.51,35.89 152.51,35.34 152.55,35.3 152.55,34.85 v2(152.37,34.67)
KSI5: length 38.6
  TOP w0.102: RN2404.7 153.85,36.04 153.72,35.91 153.72,35.69 v2(152.98,34.95) 152.38,35.55 v1(152.38,35.59) ; v2(156.13,44.01) 155.61,44.53 153.67,44.53 152.76,43.63 151.11,43.63 150.67,43.19 150.21,43.19 149.71,42.7 149.71,40.87 149.56,40.71 KBC24.105
  L3 w0.102: v2(152.98,34.95) 152.97,34.95 152.4,35.52 152.4,36.56 152.77,36.94 153.14,36.94 153.71,37.51 153.71,37.88 155.05,39.21 155.05,39.23 155.07,39.26 155.07,41.2 155.37,41.5 156.04,41.5 156.29,41.75 156.29,43.85 v2(156.13,44.01)
  BOTTOM w0.102: v2(152.98,34.95) 153.11,34.95 153.93,35.76 153.93,36.28 153.93,36.29 153.93,36.59 153.93,36.6 153.93,37.64 154.29,38 KB1.21 155.07,38 156.1,36.96 157.05,36.96 159.23,39.14 161.87,39.14 162.57,39.85 AFTP6506.1
KSI6: length 27.5
  TOP w0.102: v2(153.14,41.97) 153,41.97 151.87,43.1 151.87,43.14 151.62,43.39 151.26,43.39 150.9,43.03 150.9,41.28 150.67,41.05 150.36,40.74 KBC24.107 ; RN2404.6 153.78,36.54 v2(153.34,36.1)
  L3 w0.102: v2(153.34,36.1) 153.34,36.56 155.77,39 v2(155.77,40.86)
  BOTTOM w0.102: v1(152.34,42.23) 152.34,42.21 152.68,41.87 153.04,41.87 v2(153.14,41.97) 153.32,41.97 154.29,41 KB1.24 155.64,41 v2(155.77,40.86) 156.25,40.39 159.27,40.39 160.98,42.11 164.4,42.11 AFTP6503.1
KSI7: length 31.2
  TOP w0.102: v2(152.97,35.58) 152.97,35.86 152.9,35.92 152.9,36.28 153.32,36.69 153.51,36.69 154.01,37.19 RN2404.5 ; KBC24.108 150.76,40.77 151.16,41.17 151.16,41.44 151.1,41.5 151.1,42.62 v2(151.44,42.96)
  L3 w0.102: v2(157.11,41.61) 156.44,41.61 156.13,41.29 155.6,41.29 155.34,41.04 155.34,38.85 152.83,36.34 152.83,35.72 v2(152.97,35.58)
  BOTTOM w0.102: AFTP6502.1 164.19,43.1 160.97,43.1 158.49,40.62 157.98,40.62 157.73,40.87 157.73,41.24 157.36,41.61 v2(157.11,41.61) 156.43,41.61 156.23,41.42 155.6,41.42 155.02,42 KB1.25 154.34,42 153.88,42.46 153.88,42.95 153.88,42.95 153.47,43.37 153.29,43.37 153.11,43.55 152.38,43.55 152.37,43.54 v1(152.18,43.54) 151.96,43.32 151.87,43.32 151.51,42.96 v2(151.44,42.96)
KSO0: length 26.7
  TOP w0.102: v2(156.9,36.13) 156.9,35.78 156.55,35.42 156.55,34.11 156.19,33.75 156.19,33.11 v1(156.55,32.76) 156.98,32.32 RN2412.8 ; v2(158.76,42.69) 159.27,42.18 159.27,41.96 159.57,41.67 KBC24.2
  L3 w0.102: v2(156.9,36.13) 156.9,36.46 159.24,38.79 159.24,42.22 v2(158.76,42.69)
  BOTTOM w0.102: AFTP6507.1 163.89,37.94 163.43,38.41 162.76,38.41 161.34,36.98 157.8,36.98 156.95,36.13 v2(156.9,36.13) 156.89,36.14 156.29,36.14 155.43,37 KB1.20
KSO1: length 30.9
  TOP w0.102: KBC24.14 161.11,46.47 161.59,45.99 v2(161.77,45.99) ; RN2412.7 157.37,30.83 157.77,31.22 v2(157.77,31.72)
  L6 w0.102: v2(161.77,45.99) 160.82,45.04 160.82,42.73 161.99,41.56 161.99,35.12 v2(163.62,33.5)
  BOTTOM w0.102: KB1.16 155.5,33 156.78,31.72 v2(157.77,31.72) 158.41,32.36 160.37,32.36 163.04,35.03 163.85,35.03 AFTP6511.1 164.12,33.5 v2(163.62,33.5)
KSO2: length 33
  TOP w0.102: v2(159.19,31.55) 158.99,31.55 v1(158.32,30.88) 157.77,30.32 RN2412.6 ; KBC24.15 161.16,46.87 161.4,46.62 v2(161.77,46.62)
  L6 w0.102: v2(163.59,31.89) 164.07,32.37 164.07,34.37 162.23,36.21 162.23,46.16 v2(161.77,46.62)
  BOTTOM w0.102: v2(163.59,31.89) 163.59,31.89 164.42,31.89 AFTP6513.1 164.75,32.32 164.08,32.99 162.84,32.99 162.08,32.23 161.63,32.23 160.95,31.55 v2(159.19,31.55) 158.9,31.55 158.06,30.7 156.33,30.7 156.03,31 KB1.14
KSO3: length 44.6
  TOP w0.102: KBC24.16 159.27,47.27 158.5,48.03 v2(158.5,48.23) ; RN2412.5 158.47,29.67 158.47,29.67 158.79,29.67 v1(159.16,29.3) 160.76,27.7 162.25,27.7 163.06,28.51 163.24,28.51 163.57,28.83 v2(163.57,28.84)
  L6 w0.102: v2(163.57,28.84) 164.28,29.56 164.28,35.49 162.69,37.08 162.69,47.19 162.31,47.57 160.48,47.57 159.41,48.63 158.91,48.63 v2(158.5,48.23)
  BOTTOM w0.102: KB1.9 155.87,26 155.95,25.92 157.35,25.92 159.84,28.42 AFTP6518.1 163.14,28.42 v2(163.57,28.84)
KSO4: length 40.5
  TOP w0.102: v1(152.86,29.13) 152.86,29.34 v2(153.19,29.67) RN2409.8 ; KBC24.37 157.16,54.5 156.99,54.33 156.99,52.4 v2(155.98,51.39)
  L6 w0.102: v2(163.6,32.55) 163.09,33.06 163.09,33.69 160.65,36.12 160.65,37.86 160.31,38.2 160.31,46.14 159.1,47.35 158.17,47.35 157.38,48.15 157.38,49.99 v2(155.98,51.39)
  BOTTOM w0.102: v2(153.19,29.67) 153.52,30 KB1.13 155.86,30 156.19,29.67 160.34,29.67 161.25,30.58 161.25,31.13 161.85,31.73 162.35,31.73 AFTP6514.1 163.27,32.23 v2(163.6,32.55)
KSO5: length 44.5
  TOP w0.102: KBC24.38 156.76,54.07 v2(155.98,53.29) ; RN2409.7 153.07,30.32 152.56,29.81 v2(152.56,29.69)
  L6 w0.102: v2(155.98,53.29) 158.07,51.2 158.07,48.05 158.36,47.76 160,47.76 160.69,47.07 162.21,47.07 162.48,46.8 162.48,36.61 v2(163.47,35.62)
  BOTTOM w0.102: v2(163.47,35.62) 163.05,36.04 AFTP6510.1 159.01,36.04 156.97,34 KB1.17 154.37,34 153.42,33.05 152.39,33.05 152.03,32.68 152.03,32.29 v1(152.28,32.03) 152.3,32.03 152.49,31.84 153.51,31.84 153.78,31.56 153.78,30.91 v2(152.56,29.69)
KSO6: length 53.9
  TOP w0.102: v2(155.98,53.93) 156.36,54.31 KBC24.39 ; v2(152.63,31.3) 152.63,31.06 152.9,30.79 153.08,30.79 153.08,30.79 153.44,30.79 153.47,30.83 RN2409.6
  L6 w0.102: v2(163.56,28.2) 164.48,29.13 164.48,35.58 162.89,37.17 162.89,47.28 162.4,47.77 161.38,47.77 158.47,50.68 158.47,51.44 v2(155.98,53.93)
  BOTTOM w0.102: v2(163.56,28.2) 163.56,28.2 164.54,28.2 AFTP6517.1 164.75,28.52 163.79,29.49 161.64,29.49 160.85,28.7 159.2,28.7 157.34,26.84 155.62,26.84 155.46,27 KB1.10 153.65,27 153.49,26.84 v1(152.61,26.84) 152.38,26.84 151.71,27.51 151.71,30.08 152.63,31 v2(152.63,31.3)
KSO7: length 47.1
  TOP w0.102: v2(152.81,53.43) 152.38,53.87 152.38,54.08 151.96,54.5 KBC24.50 ; RN2409.5 153.45,31.48 153.26,31.29 v2(153.26,31.22)
  L6 w0.102: v2(152.81,53.43) 152.81,52.71 154.45,51.08 154.84,51.08 155.14,50.77 155.14,49.59 157.15,47.58 157.15,46.79 157.55,46.39 158.18,46.39 158.3,46.5 159.09,46.5 159.9,45.69 159.9,37.99 160.25,37.64 160.25,35.95 162.57,33.63 162.57,31.81 163.06,31.32 163.06,30.79 v2(163.53,30.32)
  BOTTOM w0.102: v2(163.53,30.32) AFTP6515.1 161.79,30.32 160.59,29.12 159.05,29.12 158.08,28.15 156.77,28.15 155.92,29 KB1.12 152.58,29 v1(152.48,29.1) 152.13,29.46 152.13,30.07 152.47,30.41 152.76,30.41 153.26,30.92 153.26,31.21 153.26,31.22 v2(153.26,31.22)
KSO8: length 46.8
  TOP w0.102: RN2410.8 152.85,26.75 v1(152.76,26.84) 152.56,27.04 v2(152.56,27.4) ; KBC24.46 153.56,54.18 v2(153.45,54.07)
  L6 w0.102: v2(153.45,54.07) 154.07,54.07 155.51,52.63 155.51,49.51 157.39,47.64 157.39,46.84 157.64,46.59 158.1,46.59 158.21,46.7 159.17,46.7 160.11,45.77 160.11,38.07 160.45,37.73 160.45,36.04 162.77,33.72 162.77,31.89 163.55,31.11 v2(163.55,30.96)
  BOTTOM w0.102: v2(152.56,27.4) 152.56,27.46 153.1,28 KB1.11 156.39,28 156.53,27.86 158.08,27.86 159.12,28.9 160.75,28.9 161.54,29.69 164.12,29.69 AFTP6516.1 164.12,30.96 v2(163.55,30.96)
KSO9: length 45.6
  TOP w0.102: v1(141.99,56.48) 141.99,56.78 R2449.2 R2450.1 143.22,57.11 143.22,57.1 143.23,57.09 143.23,55.92 143.01,55.7 142.96,55.7 142.75,55.49 142.75,55.19 142.92,55.03 142.98,55.03 143.23,54.78 143.23,52.73 143.5,52.47 KBC24.68 145.53,52.47 145.7,52.29 147.18,52.29 147.26,52.37 151.78,52.37 152.1,52.05 153.98,52.05 154.58,52.66 v2(155.98,52.66)
  L6 w0.102: v2(161.45,41.13) 161.45,41.39 160.6,42.23 160.6,46.37 159.42,47.55 158.26,47.55 157.58,48.23 157.58,51.06 v2(155.98,52.66)
  BOTTOM w0.102: KB1.23 159.21,40 160.96,41.75 AFTP6504.1 162.85,41.53 162.45,41.13 v2(161.45,41.13)
KSO10: length 53.9
  TOP w0.102: RN2410.7 v2(153.19,27.4) ; KBC24.72 146.33,50.87 146.41,50.95 148.03,50.95 148.36,51.28 v2(151.72,51.28) ; v2(152.51,22.22) 152.48,22.19 v1(152.48,21.66)
  L6 w0.102: v2(152.51,22.22) 152.37,22.22 151.03,23.57 151.03,24.54 151.28,24.8 151.76,24.8 152.16,24.4 152.51,24.4 152.77,24.66 152.77,25.04 153.19,25.46 v2(153.19,27.4) 151.93,28.67 151.93,29.42 151.92,29.42 151.92,29.95 151.93,29.95 151.93,32.34 151.92,32.34 151.92,32.83 150.19,34.57 150.19,37.99 150.86,38.66 150.86,42.65 150.81,42.7 150.81,43.22 150.86,43.28 150.86,46.02 151.37,46.53 151.37,50.83 151.72,51.18 v2(151.72,51.28)
  BOTTOM w0.102: AFTP6523.1 160.81,22.57 159.79,21.55 155.92,21.55 155.37,21 KB1.4 153.72,21 153.58,21.14 153.58,21.14 153.32,21.39 153.32,21.39 152.51,22.21 v2(152.51,22.22)
KSO11: length 61.2
  TOP w0.102: v2(151.7,23.51) 152.03,23.84 v1(152.03,24.17) 151.9,24.3 151.9,25.01 152.13,25.24 152.13,27.58 152.45,27.9 RN2410.6 ; KBC24.74 146.13,50.07 146.56,50.49 151.34,50.49 151.61,50.22 151.98,50.22 v2(152.46,50.69)
  L6 w0.102: v2(152.46,50.69) 155.33,47.82 155.33,34.33 154.82,33.82 154.82,24.13 153.55,22.87 152.51,22.87 151.87,23.51 v2(151.7,23.51)
  BOTTOM w0.102: AFTP6522.1 164.37,24.1 160.98,24.1 158.89,22 KB1.5 153.44,22 153.44,22 151.93,23.51 v2(151.7,23.51)
KSO12: length 58.6
  TOP w0.102: RN2410.5 152.19,28.55 v1(151.95,28.32) 151.95,28.3 151.92,28.27 151.92,25.32 151.68,25.08 151.68,25.07 151.46,24.84 v2(151.46,24.37) ; KBC24.75 145.53,49.67 145.7,49.84 146.3,49.84 146.75,50.29 151.26,50.29 151.53,50.01 152.41,50.01 v2(152.46,50.06)
  L6 w0.102: v2(152.46,50.06) 152.48,50.06 155.13,47.4 155.13,34.41 154.62,33.9 154.62,24.22 153.47,23.07 152.59,23.07 152.13,23.54 152.13,23.7 v2(151.46,24.37)
  BOTTOM w0.102: AFTP6519.1 162.4,25.94 158.3,25.94 157.36,25 KB1.8 153.66,25 153.37,25.29 151.97,25.29 151.46,24.77 v2(151.46,24.37)
KSO13: length 50
  TOP w0.102: KBC24.76 145.53,49.27 145.87,49.61 146.36,49.61 146.84,50.08 151.17,50.08 151.7,49.55 v2(151.87,49.55) ; v1(153.75,22.89) 153.98,23.12 RN2411.8 153.33,23.83 v2(153.21,23.71)
  L6 w0.102: v2(151.87,49.55) 151.87,49.4 154.72,46.55 154.72,34.58 154.21,34.07 154.21,24.71 v2(153.21,23.71)
  BOTTOM w0.102: v2(153.21,23.71) 153.5,24 KB1.7 156.65,24 158.39,25.73 164.1,25.73 AFTP6520.1
KSO14: length 51.8
  TOP w0.102: v2(152.51,49.41) 152.5,49.41 152.21,49.12 151.69,49.12 150.93,49.88 146.92,49.88 145.91,48.87 KBC24.77 ; RN2411.7 153.58,24.48 153.32,24.22 152.94,24.22 152.56,23.84 v2(152.56,23.72) 152.46,23.62 v1(152.46,23.03)
  L6 w0.102: v2(152.51,49.41) 154.93,47 154.93,34.5 154.41,33.98 154.41,24.3 153.38,23.27 153,23.27 v2(152.56,23.72)
  BOTTOM w0.102: v2(152.56,23.72) 153.28,23 KB1.6 155.42,23 156.06,22.36 158.57,22.36 160.81,24.61 AFTP6521.1
KSO15: length 50.1
  TOP w0.102: v2(151.74,46.02) 151.21,46.02 150.33,45.13 149.97,45.13 149.83,45.27 KBC24.86 ; v2(153.2,24.86) 153.32,24.98 RN2411.6
  L6 w0.102: v2(153.2,24.86) 153.63,25.28 153.63,27.58 152.13,29.08 152.13,29.5 152.13,29.51 152.13,29.87 152.13,29.87 152.13,32.42 152.13,32.43 152.13,32.91 151.06,33.98 151.06,42.73 151.01,42.78 151.01,43.14 151.06,43.19 151.06,45.34 v2(151.74,46.02)
  BOTTOM w0.102: AFTP6524.1 163.54,21.36 162.49,21.36 161.11,19.98 158.99,19.98 158.97,20 KB1.3 154.24,20 153.34,20.91 153.2,20.91 151.26,22.84 151.26,23.68 151.51,23.93 151.64,23.93 151.93,24.22 152.57,24.22 v1(152.62,24.28) v2(153.2,24.86)
KSO16: length 185.5
  TOP w0.102: KBC24.92 146.05,42.87 146.77,43.58 146.77,44.27 146.99,44.49 150.02,44.49 v2(150.22,44.29) ; v2(152.33,24.83) 152.33,25.24 152.72,25.63 RN2411.5
  L4 w0.102: v2(21.32,10.97) 21.32,9.67 22.32,8.67 26.66,8.67 33.38,1.95 36.43,1.95 36.89,2.41 40.62,2.41 47.35,9.14 47.35,14.63 49.46,16.73 55.66,16.73 56.17,16.22 67.25,16.22 73.73,22.7 77.15,22.7 78.09,21.76 78.44,21.76 79.28,22.6 82.3,22.6 84.18,20.72 94.26,20.72 94.57,20.41 105.55,20.41 105.78,20.18 125.99,20.18 126.45,19.72 127.72,19.72 128.18,20.19 137.62,20.19 141.37,23.93 151.64,23.93 152.33,24.63 v2(152.33,24.83)
  L6 w0.102: v2(150.22,44.29) 150.6,43.91 150.6,42.61 150.65,42.56 150.65,38.74 149.98,38.07 149.98,34.48 151.72,32.74 151.72,32.26 151.72,32.26 151.72,30.04 151.72,30.03 151.72,27.63 152.33,27.01 v2(152.33,24.83)
  BOTTOM w0.102: KBLIT1.4 21.3,10.95 v2(21.32,10.97) 21.3,10.98 21.3,11.91 20.28,12.92 AFTP6528.1
L_BKLT_CTRL: length 36.1
  TOP w0.114: D5502.1 70.74,98.49 R5502.2 72.89,98.2 73.7,97.39 75.21,97.39 75.68,97.85 75.68,98.45 v1(76.51,99.28) 77.25,100.02 v2(77.25,100.3)
  L3 w0.114: v2(77.04,78.17) 77.03,78.17 76.56,78.65 76.56,84.17 76.63,84.24 76.63,86.44 76.45,86.61 76.45,90.45 75.72,91.19 75.72,98.77 v2(77.25,100.3)
  BOTTOM w0.114: v2(77.04,78.17) 77.23,78.17 CPU1.R11
L_BKLT_EN: length 171.6
  TOP w0.102: R2435.2 141.19,43.77 v1(141.48,44.06) 141.5,44.04 141.75,44.04 142.01,43.78 v2(142.67,43.78)
  L3 w0.089: v2(77.04,77.51) 77.48,77.94 77.48,79.93 77.5,79.95 77.5,80.62 77.5,80.62 77.5,81.35 77.47,81.37
  L3 w0.102: v2(77.63,88.61) 77.62,88.6 77.62,86.4 77.08,85.87 77.08,81.76 77.47,81.37 ; v2(157.25,43.28) 157.25,43.83 157.25,43.83 157.25,44.65 156.9,45 156.9,45.46 156.9,51.86 158.22,53.17 158.22,58.05 157.51,58.76 157.51,59.41 158.53,60.43 158.53,62.43 156.23,64.73 155.24,64.73 147.7,72.27 147.7,72.58 144.54,75.74 141.65,75.74 v2(141.52,75.61)
  L4 w0.102: v2(142.67,43.78) 143.94,43.78 144.49,43.23 148.22,43.23 148.59,43.6 152.73,43.6 153.67,44.53 155,44.53 156.15,43.37 157.12,43.37 157.22,43.28 v2(157.25,43.28)
  L6 w0.102: v2(77.63,88.61) 79.19,88.61 79.72,89.15 82.23,89.15 82.76,89.68 84.63,89.68 86.97,87.34 89.22,87.34 90.18,86.38 92.82,86.38 94.23,84.97 97.73,84.97 99.22,86.45 100.08,86.45 101.76,88.13 101.76,89.85 103.79,91.88 105.25,91.88 106.2,92.83 106.2,93.32 110.1,97.22 111.31,97.22 118.25,104.16 119.44,104.16 119.44,104.16 129.23,104.16 130.17,103.22 131.26,103.22 131.52,103.06 135.17,99.41 135.75,98.83 135.75,97.46 136.13,97.08 136.13,90 136.87,89.26 136.87,87.39 137.48,86.78 137.48,84.11 138.57,83.02 138.57,80.26 139.22,79.61 139.22,79.31 140.54,77.99 140.54,77.04 140.54,76.27 141.2,75.61 v2(141.52,75.61)
  BOTTOM w0.102: CPU1.R12 77.38,77.18 v2(77.04,77.51)
L_BKLT_EN_EC: length 5.4
  TOP w0.102: KBC24.91 144.1,43.27 143.72,42.89 142.43,42.89 142.39,42.94 v1(142.23,42.94) 141.87,42.94 141.19,42.26 R2436.1 141.03,42.26 140.3,42.99 R2435.1
LCD_BRIGHTNESS: length 7
  TOP w0.114: RN5501.4 50.24,94.27 v1(50.6,94.63) 51.17,95.2 51.17,95.49 51.27,95.59 51.27,96.18 51.02,96.42 EC5501.1 51.34,96.61 v2(51.72,96.23)
  BOTTOM w0.114: v2(51.72,96.23) 51.27,95.78 51.27,95.1 51.05,94.88 LCD1.26
LCD_TST: length 162
  TOP w0.102: D5502.2 66.94,96.95 66.94,97.39 v2(66.94,97.42) 66.61,97.75 66.61,98.82 66.94,99.15 72.52,99.15 73.87,97.8 75.04,97.8 75.27,98.03 75.27,98.93 77.07,100.73 77.43,100.73 77.66,100.5 77.68,100.5 v2(77.88,100.3) ; RN5501.8 52.04,92.53 52.52,93.01 52.52,93.46 53.21,94.15 53.57,94.15 53.67,94.25 54.69,94.25 55.4,94.96 v1(56.17,94.96) 57.03,94.96 57.43,95.37 57.43,95.77 57.44,95.78 v2(57.44,96.11) ; v2(161.17,62.6) 161.96,62.6 163.75,60.82 163.75,60.82 165.5,59.07 165.5,56.44 165.46,56.41 165.46,56.34 R2419.2
  L4 w0.102: v2(77.88,100.3) 79.31,98.87 86.74,98.87 87.59,98.87 92.67,98.87 92.67,98.87 101.27,98.87 102.76,100.36 102.76,101.97 103.17,102.38 104.63,102.38 106.25,100.76 111.61,100.76 115.34,104.49 125.91,104.49 125.96,104.44 128.24,104.44 128.31,104.37 129.36,104.37 130.41,103.32 131.72,103.32 133.56,101.48 133.56,101.1 136.43,98.23 136.43,91.41 137.34,90.49 137.34,83.24 140.05,80.54 140.2,80.54 141.44,79.29 141.44,77.39 147.19,71.64 147.92,71.64 154.24,65.32 154.24,64.2 v2(154.46,63.98)
  BOTTOM w0.102: v2(66.94,97.42) 66.72,97.63 66.72,97.67 66.62,97.78 64.93,97.78 63.93,98.78 61.47,98.78 59.23,96.54 57.87,96.54 v2(57.44,96.11) ; v2(154.46,63.98) 154.22,63.73 154.22,63.03 154.64,62.6 v2(161.17,62.6)
LCD_TST_C: length 3.7
  TOP w0.102: RN5501.1 v1(52.04,94.52) 52.04,94.9 v2(52.61,95.47)
  BOTTOM w0.102: v2(52.61,95.47) 52.55,95.41 LCD1.23
LCD_TST_EN: length 145.7
  TOP w0.102: D5501.2 74.44,100.4 74.96,100.92 75.19,100.92 v2(75.2,100.93) ; v2(159.04,51.4) 159.17,51.27 KBC24.26 161.38,51.27 162.35,52.23 162.35,54.44 v1(162.67,54.76) 163.48,55.57 R2419.1
  L3 w0.102: v2(75.2,100.93) 75.69,100.93 77.53,102.77 77.53,108.55 80.2,111.22 112.1,111.22 114.74,108.58 128.02,108.58 130.12,106.48 131.32,106.48 131.93,105.86 133.26,105.86 138.43,100.68 138.43,98.73 139.88,97.28 139.88,88.05 140.85,87.08 140.85,83.56 142.91,81.5 142.91,78.91 149.66,72.15 149.66,71.85 155.45,66.07 156.57,66.07 159.52,63.11 159.52,57.31 160.34,56.49 160.34,52.71 v2(159.04,51.4)
LCDVDD:
  vias: v1(44.36,97) v1(48.19,97.07) v3(44.61,96.36) v3(45.63,96.36)
LDO_AVDD: length 3.2
  TOP w0.102: HDA27.37 21.68,21.78 22.44,21.01 v1(22.44,20.87) 22.44,20.73 21.88,20.16 C2729.2
LDO_VDD_CORE: length 4.2
  TOP w0.102: HDA27.39 22.48,22.1 23.38,21.2 v1(23.85,21.2) 24.27,21.2 25.05,20.41 C2701.2
LID_CL_SIO#: length 50.3
  TOP w0.102: KBC24.41 155.56,56.2 v2(155.4,56.36) ; D2402.K 141.19,74.07 R2433.1 141.89,73.31 v2(141.89,72.98)
  L3 w0.102: v2(155.4,56.36) 155.4,57.55 156.55,58.69 156.55,60.22 153.91,62.86 153.91,64.74 150.57,68.08 149.16,68.08 149.16,68.07 148.8,68.07 148.79,68.08 148.43,68.08 148.41,68.05 147.85,68.05 146.72,69.18 146.72,71.6 144.18,74.14 143.16,74.14 142.02,72.99 141.9,72.99 v2(141.89,72.98)
  BOTTOM w0.102: v2(155.4,56.36) 155.4,56.89 156.63,58.12 156.63,60.23 v1(156.39,60.47) 156.15,60.72 148.54,60.72 146.57,58.75 IOBD1.29
LINE1-L_C: length 1.4
  TOP w0.254: R2912.2 16.2,20.35 C2907.1
LINE1-L_R: length 3.2
  TOP w0.254: C2908.1 18.8,18.18 v1(19.97,18.18) 20.1,18.31 20.1,18.85 R2913.2
LINE1_L: length 4.6
  TOP w0.203: HDA27.33 19.74,22.6
  TOP w0.254: R2912.1 17.04,20.87 18.51,20.87 v1(18.81,21.17) 18.78,21.2 18.78,21.64 19.74,22.6
LINE1_R: length 2.9
  TOP w0.203: HDA27.34 20.48,22.04 20.28,21.84
  TOP w0.254: R2913.1 19.87,20.64 20.13,20.91 v1(20.13,20.93) 20.16,20.96 20.16,21.72 20.28,21.84
LPC_FRAME#_DEBUG: length 3.4
  TOP w0.114: v2(104.93,109.19) 105.11,109.19 105.46,109.54 v1(105.46,109.57) 105.46,110 R6801.2
  BOTTOM w0.114: DB1.6 105.18,110.73 105.18,109.43 v2(104.93,109.19)
LPC_LAD0: length 122.1
  TOP w0.114: RN6801.1 107.46,104.26 107.46,103.49 v2(108.11,102.84) 108.92,102.03 109.71,102.03 110.02,102.34 111.56,102.34 114.74,99.16 114.74,87.76 104.63,77.64 v1(104.39,77.64) 100.59,77.64 100.56,77.67 100.55,77.67 100.13,78.08 RN1806.8 ; KBC24.59 148.36,56.45 147.33,57.48 147.33,60.05 147.68,60.4 147.83,60.55 147.83,67.63 147.73,67.74 146.04,69.42 146.04,72.82 146.04,73.33 141.03,78.34 139.72,78.34 v2(139.3,77.92)
  L3 w0.114: v2(108.11,102.84) 108.48,103.21 108.48,104.09 108.79,104.41 109.71,104.41 109.99,104.13 125.57,104.13 125.74,103.97 127.73,103.97 129.06,102.64 129.58,102.64 133.38,98.84 133.38,98.52 135.52,96.38 135.52,91.3 136.65,90.17 136.65,84.03 138.59,82.1 138.59,79.96 139.74,78.81 139.74,78.36 v2(139.3,77.92)
LPC_LAD0_C: length 9.5
  TOP w0.114: RN6801.8 107.21,105.49 v1(106.43,106.27) 106.2,106.5 105.08,106.5 v2(102.27,109.31)
  BOTTOM w0.114: v2(102.27,109.31) 101.13,109.31 100.18,110.26 DB1.2
LPC_LAD0_R: length 9.5
  TOP w0.114: RN1806.1 98.39,78.08 97.86,77.56 v1(97.83,77.56) 97.7,77.56 96.18,76.04 95.5,76.04 v2(94.98,75.52)
  BOTTOM w0.089: CPU1.AY13 90.99,76.5 91.25,76.23 91.64,76.23 91.78,76.27 92.02,76.27 92.11,76.23 93.44,76.23 93.48,76.27
  BOTTOM w0.114: 93.48,76.27 94.23,76.27 v2(94.98,75.52)
LPC_LAD1: length 122.2
  TOP w0.114: KBC24.60 147.96,56.32 146.96,57.32 146.96,60.2 147.32,60.56 147.46,60.7 147.46,67.48 147.36,67.58 145.68,69.27 145.68,72.66 145.68,73.18 140.95,77.91 v2(139.95,77.91) ; RN6801.2 107.86,103.72 v2(108.04,103.54) 108.04,103.53 109.17,102.4 109.56,102.4 109.87,102.71 111.72,102.71 115.11,99.31 115.11,87.6 104.68,77.17 104.17,77.17 104,77 v1(103.32,77) 103.31,77.01 100.69,77.01 100.26,77.43 RN1806.7
  L3 w0.114: v2(139.95,77.91) 140.11,78.07 140.11,78.97 138.96,80.12 138.96,82.25 137.02,84.19 137.02,90.56 136.05,91.53 136.05,96.64 134.35,98.34 134.09,98.34 133.83,98.59 133.83,99.09 132.61,100.31 132.61,101.08 131.49,102.2 130.97,102.2 129.06,104.11 128.33,104.11 128.1,104.34 125.89,104.34 125.53,104.7 109.94,104.7 109.87,104.77 108.64,104.77 108.04,104.18 v2(108.04,103.54)
LPC_LAD1_C: length 9.4
  TOP w0.114: RN6801.7 107.86,106.39 107.39,106.86 105.35,106.86 v1(104.2,108.02) v2(102.9,109.31)
  BOTTOM w0.114: v2(102.9,109.31) 102.47,109.75 101.96,109.75 101.43,110.28 DB1.3
LPC_LAD1_R: length 8.8
  TOP w0.114: RN1806.2 98.33,77.43 97.41,76.52 97.41,76.52 97.21,76.33 v1(97.01,76.33) 96.99,76.33 96.25,75.59 v2(96.25,75.52)
  BOTTOM w0.114: CPU1.BA13 91.78,76.5 92.06,76.77 92.37,76.77 92.46,76.68 95.09,76.68 v2(96.25,75.52)
LPC_LAD2: length 118.6
  TOP w0.114: v2(139.99,77.18) 141.14,77.18 145.31,73.02 145.31,72.51 145.31,72.51 145.31,70.56 145.31,70.25 145.31,70.25 145.31,69.11 146.71,67.71 147.09,67.33 147.09,60.85 146.7,60.46 146.59,60.35 146.59,57.16 147.56,56.2 KBC24.61 ; RN1806.6 100.23,76.93 100.59,76.58 104.13,76.58 104.36,76.81 104.84,76.81 115.48,87.45 115.48,87.76 v1(115.48,88.46) 115.48,99.47 111.87,103.08 109.62,103.08 v2(109.38,102.84) 108.36,103.86 RN6801.3
  L3 w0.114: v2(109.38,102.84) 109.49,102.95 123.78,102.95 123.94,102.79 127.34,102.79 128.7,101.43 129.22,101.43 132.28,98.38 132.28,98.06 134.42,95.93 134.42,90.39 135.55,89.26 135.55,87.29 135.55,84.76 135.55,84.76 135.55,83.44 137.2,81.78 137.2,78.71 139.14,76.77 139.57,76.77 v2(139.99,77.18)
LPC_LAD2_C: length 8.7
  TOP w0.114: RN6801.6 108.36,106.41 107.54,107.23 105.62,107.23 v1(105.39,107.46) v2(103.54,109.31)
  BOTTOM w0.114: v2(103.54,109.31) 103.54,109.44 102.68,110.3 DB1.4
LPC_LAD2_R: length 8.2
  TOP w0.114: RN1806.3 98.35,76.93 97.57,76.15 97.56,76.15 97.31,75.9 97.31,75.89 96.44,75.03 v1(95.99,75.03) 95.89,75.03 95.61,75.3 v2(95.61,75.52)
  BOTTOM w0.114: CPU1.BB13 92.24,76.47 94.66,76.47 v2(95.61,75.52)
LPC_LAD3: length 118.4
  TOP w0.114: v2(139.33,77.21) 139.33,76.83 141.44,74.71 143.09,74.71 144.94,72.87 144.94,72.36 144.94,72.36 144.94,70.71 144.94,70.71 144.94,70.1 144.94,70.1 144.94,68.96 146.34,67.56 146.72,67.17 146.72,61.01 146.22,60.51 146.22,57.01 147.16,56.08 KBC24.62 ; RN1806.5 100.04,76.08 v1(101.28,76.08) 104.17,76.08 104.47,76.38 104.93,76.38 115.85,87.3 115.85,87.91 115.85,99.75 112.15,103.45 109.53,103.45 v2(109.38,103.6) 109.01,103.97 RN6801.4
  L3 w0.114: v2(109.38,103.6) 109.66,103.31 123.94,103.31 124.09,103.16 127.49,103.16 128.85,101.8 129.37,101.8 132.65,98.53 132.65,98.22 134.78,96.08 134.78,90.54 135.92,89.41 135.92,83.59 137.57,81.93 137.57,78.96 v2(139.33,77.21)
LPC_LAD3_C: length 8.5
  TOP w0.114: RN6801.5 109.01,106.43 v1(108.36,107.08) 107.84,107.6 105.89,107.6 v2(104.17,109.31)
  BOTTOM w0.114: v2(104.17,109.31) 103.93,109.56 103.93,110.73 DB1.5
LPC_LAD3_R: length 9.3
  TOP w0.114: RN1806.4 98.32,76.28 97.75,75.72 v2(97.74,75.72)
  BOTTOM w0.114: CPU1.AY12 90.89,76.77 91.07,76.77 91.07,76.77 91.36,76.77 91.57,76.97 92.46,76.97 92.52,76.9 95.6,76.9 v1(96.13,76.37) 96.85,75.66 97.69,75.66 v2(97.74,75.72)
LPC_LFRAME#: length 138.2
  TOP w0.114: R6801.1 v1(102.93,110.46) 102.79,110.46 101.83,109.49 101.83,109.13 104.83,106.13 105.65,106.13 106.33,105.44 106.33,104.36 v2(106.97,103.73) 107.09,103.61 107.09,103.16 108.59,101.66 109.25,101.66 109.25,101.66 109.87,101.66 110.18,101.97 111.41,101.97 114.36,99.02 114.36,87.9 104.8,78.33 104.5,78.04 100.77,78.04 100.24,78.57 99.83,78.57 99.82,78.59 98.19,78.59 96.15,76.55 R1801.1 ; v2(139.3,78.61) 139.41,78.71 141.19,78.71 146.41,73.49 146.41,72.97 146.41,72.97 146.41,69.57 147.66,68.32 148.09,67.89 148.09,67.89 148.2,67.78 148.2,60.4 148.05,60.25 147.7,59.89 147.7,57.8 147.7,57.8 147.7,57.66 148.76,56.6 KBC24.58
  L3 w0.114: v2(139.3,78.61) 138.71,78.61 137.95,79.36 137.95,82.21 136.28,83.88 136.28,89.9 135.15,91.03 135.15,96.23 133.01,98.37 133.01,98.68 129.53,102.17 129.01,102.17 127.58,103.6 125.37,103.6 125.2,103.77 109.83,103.77 109.56,104.04 109,104.04 108.85,103.88 108.85,102.95 108.29,102.4 107.67,102.4 107.42,102.66 107.42,103.28 v2(106.97,103.73)
LPC_LFRAME#_R: length 4.8
  TOP w0.114: v1(92.34,77.64) 92.65,77.64 v2(92.93,77.37) 92.93,77.35 93.4,76.89 94.37,76.89 94.51,76.75 94.64,76.75 R1801.2
  BOTTOM w0.114: CPU1.BA12 91.35,77.17 92.74,77.17 92.93,77.37 v2(92.93,77.37)
LPSS_UART2_CTS#: length 12.2
  TOP w0.114: R2046.2 81.65,90.28 v2(82.01,90.64) 82.15,90.77 v1(82.56,90.77)
  L3 w0.114: v2(82.01,90.64) 81.16,89.79 81.16,86.42 81.75,85.83 81.75,83.15 81.54,82.94 v2(81.54,81.57)
  BOTTOM w0.114: v2(81.54,81.57) 82.09,81.57 CPU1.AD4
LPSS_UART2_RXD: length 6.6
  TOP w0.114: R2048.2 v2(83.29,88.61)
  BOTTOM w0.089: CPU1.AD1 82.38,84.05
  BOTTOM w0.114: 82.38,84.05 82.38,84.14 82.65,84.4 82.65,85.82 82.51,85.97 82.51,87.83 v2(83.29,88.61) v1(83.85,88.61)
LPSS_UART2_TXD: length 7.7
  TOP w0.114: R2049.2 83.55,89.5 v2(83.29,89.25)
  BOTTOM w0.089: CPU1.AD2 82.16,83.38 82.16,83.61 82.12,83.72 82.12,84.14 82.44,84.47 82.44,85.76 82.3,85.9 82.3,86.31 82.29,86.33
  BOTTOM w0.114: v2(83.29,89.25) v1(82.4,88.36) 82.29,88.24 82.29,86.33
LVDS_VDD_EN_R: length 35.5
  TOP w0.102: U5501.1 47.21,100.49 v2(47.15,100.42) ; v2(67.57,97.43) 67.68,97.33 67.7,97.33 68.61,96.41 v1(70.77,96.41) 71.57,96.41 D5501.3 ; v2(53.88,96.11) 54.12,96.35 54.12,96.95 54.77,97.59 54.77,98.48 RN5502.8 54.9,99.75 v2(54.9,100.3)
  L6 w0.102: v2(47.15,100.42) 51.18,100.42 51.43,100.17 54.77,100.17 v2(54.9,100.3)
  BOTTOM w0.102: v2(53.88,96.11) 54.52,96.74 59.15,96.74 61.39,98.98 64.01,98.98 65.01,97.98 67.16,97.98 67.57,97.57 v2(67.57,97.43)
M_A_A0: length 47.8
  TOP w0.178: v1(129.01,65.83) 128.46,65.83 v2(128.44,65.85)
  L6 w0.165: v2(128.44,65.85) 128.44,66.13 127.9,66.67 121.37,66.67 120.73,67.31 120.31,67.31 120.02,67.6 119.69,67.6 119.53,67.43 119.53,66.93 119.36,66.76 119.03,66.76 118.87,66.93 118.87,67.6 118.7,67.76 109.61,67.76 100.98,59.14 98.93,59.14 97.9,58.11 v2(97.9,57.52)
  BOTTOM w0.089: 92.64,56.48 92.56,56.41 91.95,56.41 91.12,55.58 CPU1.AY50
  BOTTOM w0.178: 92.64,56.48 94.27,58.11 97.41,58.11 97.9,57.62 v2(97.9,57.52) ; v2(128.44,65.85) 128.44,65.85 129.9,65.85 DIMM1.98
M_A_A1: length 48.6
  TOP w0.178: v2(98.63,57.55) 98.87,57.79 v1(99.14,57.79)
  L6 w0.165: v2(98.63,57.55) 98.63,58.11 99.14,58.62 101.2,58.62 109.82,67.24 112.54,67.24 112.71,67.07 112.71,66.33 112.87,66.17 113.2,66.17 113.37,66.33 113.37,67.07 113.53,67.24 113.86,67.24 114.03,67.07 114.03,66.33 114.19,66.17 114.52,66.17 114.69,66.33 114.69,67.07 114.85,67.24 115.18,67.24 115.35,67.07 115.35,66.33 115.51,66.17 115.84,66.17 116.01,66.33 116.01,67.07 116.17,67.24 116.5,67.24 116.67,67.07 116.67,66.33 116.83,66.17 117.35,66.17 117.52,66.33 117.52,67.06 117.68,67.23 118.02,67.23 118.18,67.06 118.18,66.33 118.35,66.17 121.16,66.17 121.16,66.16 121.22,66.16 121.7,65.69 123.62,65.69 123.8,65.86 v2(123.8,66.15)
  BOTTOM w0.089: 93.38,55.97 93.3,55.9 92.53,55.9 CPU1.BB50
  BOTTOM w0.178: v2(123.8,66.15) 123.8,65.72 123.63,65.55 DIMM1.97 ; 93.38,55.97 94.44,57.04 98.44,57.04 98.63,57.24 v2(98.63,57.55)
M_A_A2: length 50
  TOP w0.178: v1(127.49,66.31) 127.17,65.99 v2(127.17,65.85)
  L6 w0.165: v2(99.68,57.52) 99.68,57.13 99.84,56.97 102.51,56.97 109.4,63.86 109.4,64.45 109.56,64.6 109.93,64.6 110.09,64.45 110.09,63.94 110.25,63.78 110.58,63.78 110.75,63.61 110.75,63.39 110.91,63.23 111.24,63.23 111.41,63.39 111.41,63.61 111.57,63.78 111.9,63.78 112.07,63.61 112.07,63.39 112.23,63.23 112.56,63.23 112.73,63.39 112.73,63.61 112.89,63.78 113.22,63.78 113.39,63.61 113.39,63.39 113.55,63.23 113.88,63.23 114.05,63.39 114.05,63.62 114.22,63.78 116.63,63.78 116.76,63.91 119.27,63.91 119.96,64.6 120.47,64.6 120.74,64.33 120.74,64.12 120.9,63.97 124.23,63.97 124.73,64.47 126.31,64.47 127.17,65.33 v2(127.17,65.85)
  BOTTOM w0.089: CPU1.AY51 90.95,55.19 91.19,55.31 91.63,55.31 91.76,55.35 91.99,55.35 92.13,55.32 92.4,55.32 92.75,55.67 93.78,55.67
  BOTTOM w0.178: 93.78,55.67 94.62,56.51 98.66,56.51 v2(99.68,57.52) ; DIMM1.96 127.33,65.25 127.17,65.41 v2(127.17,65.85)
M_A_A3: length 49.1
  TOP w0.178: v2(123.16,64.95) 122.72,64.95 v1(122.61,64.84)
  L6 w0.165: v2(123.16,64.95) 122.96,65.15 121.44,65.15 120.95,65.65 112.19,65.65 112.02,65.81 112.02,66.54 111.86,66.7 111.53,66.7 111.36,66.54 111.36,65.81 111.2,65.65 110.86,65.65 110.7,65.81 110.7,66.55 110.53,66.72 110.2,66.72 110.04,66.55 110.04,65.81 109.87,65.65 108.97,65.65 107.66,64.34 107.66,64.11 107.8,63.97 107.8,63.74 107.57,63.5 107.33,63.5 107.2,63.64 106.96,63.64 106.73,63.41 106.73,63.17 106.87,63.04 106.87,62.8 106.63,62.57 106.4,62.57 106.26,62.71 106.03,62.71 105.79,62.47 105.79,62.24 105.93,62.1 105.93,61.87 105.7,61.64 105.47,61.64 105.33,61.77 105.09,61.77 104.86,61.54 104.86,61.31 105,61.17 105,60.93 104.77,60.7 104.53,60.7 104.39,60.84 104.16,60.84 103.93,60.61 103.93,60.37 104.06,60.23 104.06,60 103.83,59.77 103.6,59.77 103.46,59.91 103.23,59.91 102.99,59.67 102.99,59.44 103.13,59.3 103.13,59.07 102.9,58.83 102.66,58.83 102.52,58.97 102.29,58.97 101.42,58.1 99.36,58.1 99.16,57.89 99.16,57.12 98.99,56.95 98.35,56.95 98.18,56.79 98.18,56.15 97.99,55.95 97.03,55.95 96.87,56.12 96.87,57.28 97.14,57.55 v2(97.21,57.55)
  BOTTOM w0.089: CPU1.BA50 92.06,56.08 92.87,56.08 93.53,56.74
  BOTTOM w0.178: v2(97.21,57.55) 97.19,57.58 94.37,57.58 93.53,56.74 ; v2(123.16,64.95) DIMM1.95
M_A_A4: length 49.7
  TOP w0.178: v2(127.8,64.65) 127.8,64.49 v1(127.44,64.13)
  L6 w0.165: v2(127.8,64.65) 127.8,64.95 127.97,65.11 128.88,65.11 129.07,64.92 129.07,64.29 128.69,63.91 124.93,63.91 124.45,63.43 124.43,63.41 119.51,63.41 119.09,63 119.09,62.86 118.93,62.69 118.19,62.69 118.02,62.86 118.02,63.1 117.86,63.26 117.53,63.26 117.36,63.1 117.36,62.86 117.2,62.69 116.87,62.69 116.7,62.86 116.7,63.1 116.54,63.26 116.21,63.26 116.04,63.1 116.04,62.86 115.88,62.69 115.55,62.69 115.38,62.86 115.38,63.1 115.21,63.26 114.88,63.26 114.72,63.1 114.72,62.86 114.55,62.69 110.32,62.69 110.15,62.86 110.15,63.1 109.99,63.26 109.66,63.26 109.49,63.1 109.49,62.86 109.33,62.69 108.97,62.69 102.71,56.43 99.2,56.43 98.43,55.66 98.43,55.39 v2(98.43,55.39)
  BOTTOM w0.089: CPU1.BB52 94.19,54.25 94.89,54.95 97.99,54.95 v2(98.43,55.39)
  BOTTOM w0.178: v2(127.8,64.65) 127.82,64.63 127.82,64.58 128.35,64.05 DIMM1.92
M_A_A5: length 50.4
  TOP w0.178: v1(124.43,64.39) v2(124.43,64.95)
  L6 w0.165: v2(124.43,64.95) 124.43,64.93 123.99,64.49 121.35,64.49 120.71,65.12 119.36,65.12 119.2,64.96 119.2,64.61 119.04,64.45 118.69,64.45 118.54,64.61 118.54,64.96 118.37,65.12 118.04,65.12 117.88,64.96 117.88,64.6 117.71,64.43 117.38,64.43 117.22,64.6 117.22,64.96 117.05,65.12 116.72,65.12 116.56,64.96 116.56,64.51 116.39,64.35 116.06,64.35 115.89,64.51 115.89,64.96 115.73,65.12 115.4,65.12 115.23,64.96 115.23,64.47 115.07,64.31 114.74,64.31 114.57,64.47 114.57,64.96 114.41,65.12 114.08,65.12 113.91,64.96 113.91,64.49 113.75,64.32 113.42,64.32 113.25,64.49 113.25,64.96 113.09,65.12 112.76,65.12 112.59,64.96 112.59,64.47 112.43,64.3 112.1,64.3 111.93,64.47 111.93,64.96 111.77,65.12 111.44,65.12 111.27,64.96 111.27,64.47 111.11,64.3 110.78,64.3 110.61,64.47 110.61,64.96 110.45,65.12 109.18,65.12 108.38,64.32 108.38,63.57 103.11,58.31 102.37,58.31 101.61,57.55 v2(100.39,57.55)
  BOTTOM w0.089: 94.19,55.44 92.89,55.44 92.59,55.14 92.11,55.14 91.97,55.18 91.79,55.18 91.67,55.13 91.52,55.13 CPU1.BA51
  BOTTOM w0.178: DIMM1.91 123.5,63.75 124.43,64.68 v2(124.43,64.95) ; 94.19,55.44 94.72,55.98 98.88,55.98 100.21,57.3 100.21,57.37 v2(100.39,57.55)
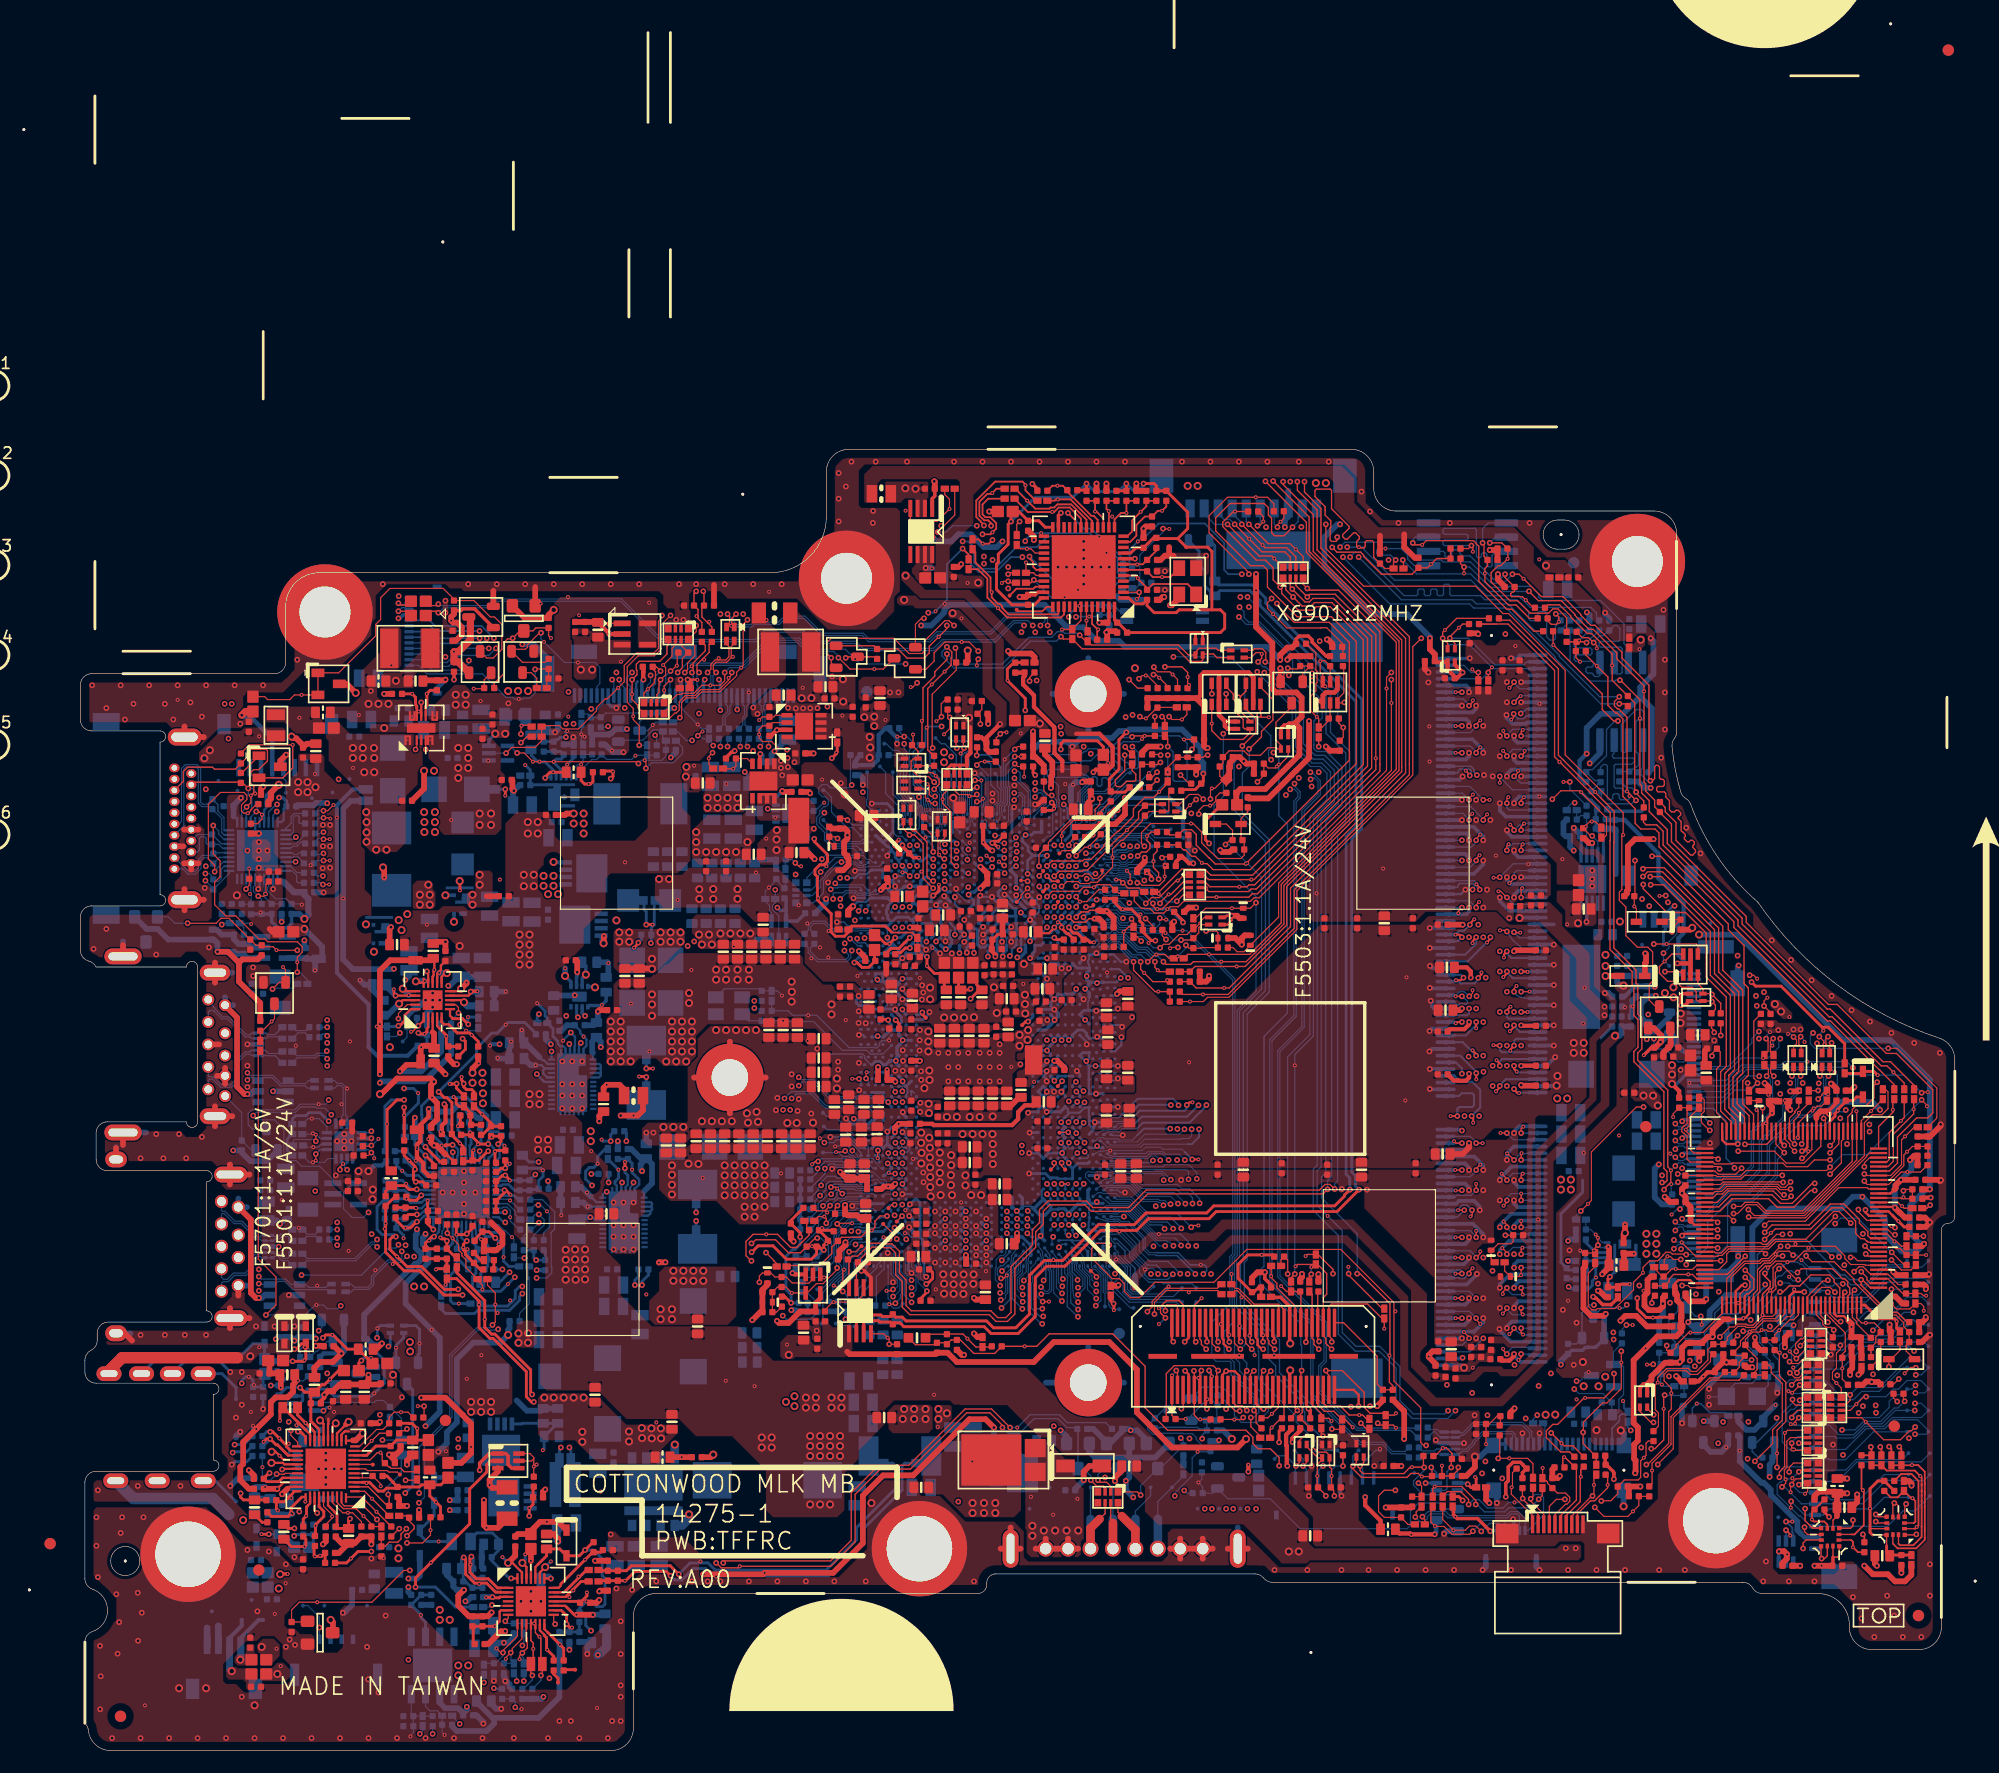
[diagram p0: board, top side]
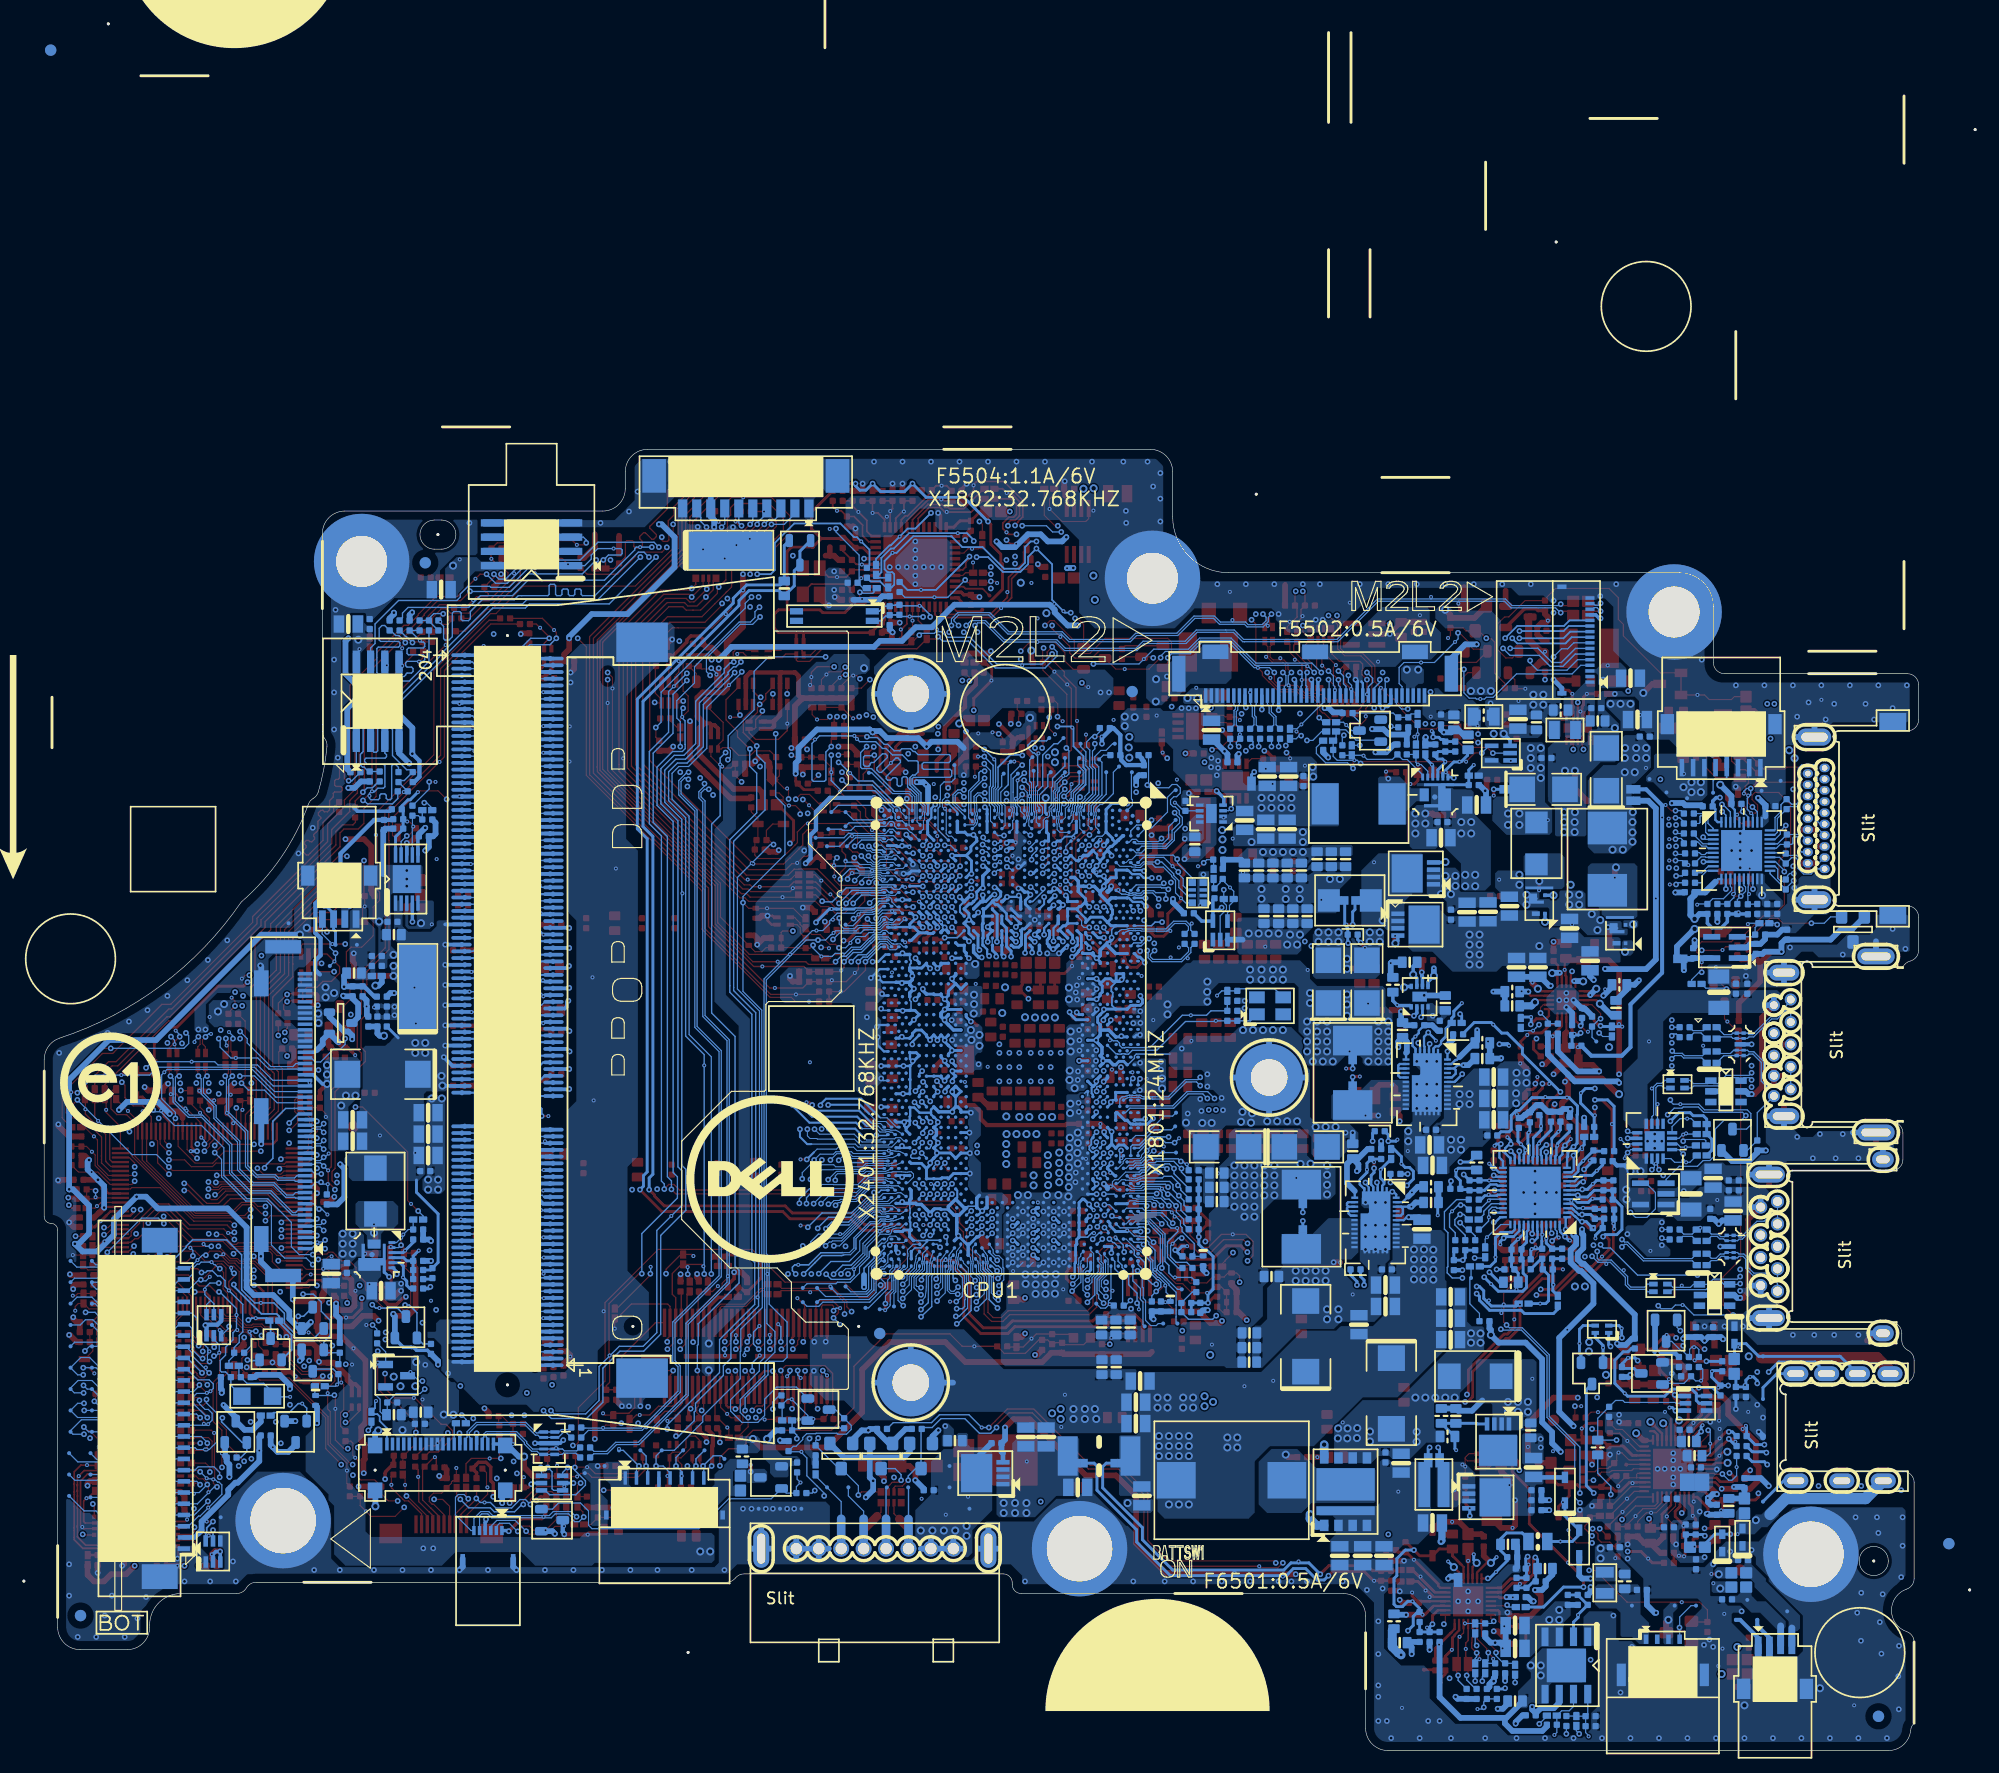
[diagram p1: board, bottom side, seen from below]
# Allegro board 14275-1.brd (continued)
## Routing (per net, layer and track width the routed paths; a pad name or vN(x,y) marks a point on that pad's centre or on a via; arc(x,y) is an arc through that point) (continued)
M_A_A6: length 49.2
  TOP w0.178: v1(127.48,62.38) 127.48,62.49 127.64,62.66 127.64,62.68 v2(127.8,62.85)
  L6 w0.165: v2(127.8,62.85) 127.8,63.22 127.64,63.39 125.46,63.39 124.95,62.88 119.87,62.88 119.14,62.15 115.96,62.15 115.79,61.99 115.79,61.64 115.63,61.47 115.3,61.47 115.13,61.64 115.13,61.99 114.97,62.15 114.64,62.15 114.47,61.99 114.47,61.64 114.31,61.47 113.98,61.47 113.81,61.64 113.81,61.99 113.65,62.15 113.32,62.15 113.15,61.99 113.15,61.64 112.99,61.47 112.66,61.47 112.49,61.64 112.49,61.99 112.33,62.15 112,62.15 111.83,61.99 111.83,61.64 111.67,61.47 111.34,61.47 111.17,61.64 111.17,61.99 111,62.15 110.67,62.15 110.51,61.99 110.51,61.64 110.34,61.47 110.01,61.47 109.85,61.64 109.85,61.99 109.68,62.15 109.16,62.15 102.91,55.9 99.4,55.9 99.06,55.56 v2(99.06,55.39)
  BOTTOM w0.089: CPU1.BA52 91.84,53.98 94.33,53.98 94.86,54.5 95.86,54.5 95.87,54.51 98.18,54.51 98.23,54.57 98.83,54.57 99.06,54.8 v2(99.06,55.39)
  BOTTOM w0.178: v2(127.8,62.85) 127.8,63.26 127.99,63.45 DIMM1.90
M_A_A7: length 51.2
  TOP w0.178: v2(126.53,62.85) 126,62.85 v1(125.97,62.88)
  L6 w0.165: v2(97.16,55.44) 97.16,55.4 97.7,54.86 103.34,54.86 108.37,59.88 109.07,59.88 109.34,59.61 112.74,59.61 113.57,60.43 119.96,60.43 120.1,60.29 121.64,60.29 121.81,60.46 121.81,61.22 121.95,61.36 122.76,61.36 122.79,61.39 125.56,61.39 125.74,61.57 128.87,61.57 129.04,61.74 129.04,62.22 128.87,62.39 126.7,62.39 126.53,62.55 v2(126.53,62.85)
  BOTTOM w0.089: 94.22,54.86 93.79,54.43 92.59,54.43 92.48,54.54 91.29,54.54 91.18,54.64 90.76,54.64 90.48,54.35 CPU1.AW52
  BOTTOM w0.178: v2(97.16,55.44) 94.8,55.44 94.22,54.86 ; DIMM1.86 126.73,62.25 126.53,62.44 v2(126.53,62.85)
M_A_A8: length 49.9
  TOP w0.178: v1(124.11,62.43) 124.43,62.11 v2(124.43,61.95)
  L6 w0.165: v2(124.43,61.95) 124.43,62.17 124.27,62.33 122.88,62.33 122.71,62.17 122.71,62.05 122.55,61.88 122.22,61.88 122.05,62.05 122.05,62.17 121.89,62.33 121.37,62.33 121.2,62.17 121.2,61.12 121.04,60.95 120.75,60.95 120.49,61.22 120.49,61.65 120.32,61.81 120,61.81 119.84,61.65 119.84,61.12 119.67,60.95 118.82,60.95 118.65,61.12 118.65,61.47 118.49,61.63 118.15,61.63 117.99,61.47 117.99,61.12 117.82,60.95 117.3,60.95 117.14,61.12 117.14,61.47 116.97,61.63 116.64,61.63 116.48,61.47 116.48,61.12 116.31,60.95 112.86,60.95 112.69,60.79 112.69,60.3 112.53,60.13 112.2,60.13 112.03,60.3 112.03,60.79 111.87,60.95 111.54,60.95 111.37,60.79 111.37,60.3 111.21,60.13 110.88,60.13 110.71,60.3 110.71,60.79 110.54,60.95 110.21,60.95 110.05,60.79 110.05,60.3 109.88,60.13 109.55,60.13 109.39,60.3 109.39,60.79 109.22,60.95 108.7,60.95 103.13,55.38 99.74,55.38 v2(99.73,55.39)
  BOTTOM w0.089: 98.72,54.06 94.79,54.06 94.53,53.8 91.54,53.8 90.99,54.35 CPU1.AY52
  BOTTOM w0.178: DIMM1.89 123.23,63.15 v2(124.43,61.95) ; 98.72,54.06 99.08,54.06 99.73,54.71 v2(99.73,55.39)
M_A_A9: length 48.7
  TOP w0.178: v2(124.44,60.39) v1(124.44,59.84)
  L6 w0.165: v2(124.44,60.39) 124.44,60.7 124.29,60.86 123.38,60.86 123.38,60.86 123.01,60.86 122.98,60.84 122.54,60.84 122.4,60.7 122.4,59.8 122.24,59.63 119.98,59.63 119.7,59.91 119.18,59.91 119.02,59.75 119.02,59.2 118.85,59.03 118.52,59.03 118.36,59.2 118.36,59.75 118.19,59.91 113.78,59.91 112.96,59.09 108.31,59.09 103.56,54.34 97.48,54.34 97.11,54.71 96.11,54.71 95.94,54.54 95.94,53.46 96.11,53.3 98.23,53.3 98.46,53.08 v2(98.46,52.65)
  BOTTOM w0.089: CPU1.BB54 94.97,53.22 95.13,53.38 96.52,53.38 96.74,53.17 97.94,53.17 v2(98.46,52.65)
  BOTTOM w0.178: v2(124.44,60.39) 124.44,60.52 123.01,61.95 DIMM1.85
M_A_A10: length 50.8
  TOP w0.178: v2(124.62,68.88) 124.62,68.91 124.9,69.19 v1(124.9,69.36)
  L6 w0.165: v2(88.78,55.04) 88.86,55.04 88.9,54.99 91.5,54.99 93.55,57.05 93.55,57.75 97.83,62.03 99.87,62.03 108.4,70.57 111.7,70.57 111.87,70.73 111.87,71.28 112.03,71.45 112.36,71.45 112.53,71.28 112.53,70.73 112.69,70.57 113.02,70.57 113.19,70.73 113.19,71.28 113.35,71.45 119.35,71.45 119.72,71.08 121.02,71.08 121.53,70.57 122.31,69.79 124.45,69.79 124.62,69.63 v2(124.62,68.88)
  BOTTOM w0.178: DIMM1.107 122.9,68.55 123.06,68.38 124.26,68.38 124.57,68.69 124.57,68.82 v2(124.62,68.88) ; CPU1.AT50 88.78,55.22 v2(88.78,55.04)
M_A_A11: length 49.5
  TOP w0.178: v1(126.24,61.54) 126.53,61.25 v2(126.53,61.05)
  L6 w0.165: v2(126.53,61.05) 126.53,60.56 126.26,60.29 125.55,60.29 125.13,59.87 123.93,59.87 123.68,59.63 123.68,58.84 123.43,58.59 121.33,58.59 120.74,57.99 115.95,57.99 115.38,57.42 113.96,57.42 113.79,57.58 113.79,57.83 113.63,57.99 113.3,57.99 113.13,57.83 113.13,57.58 112.97,57.42 112.27,57.42 112.1,57.25 112.1,56.67 111.94,56.5 111.61,56.5 111.44,56.67 111.44,57.25 111.28,57.42 110.95,57.42 110.78,57.25 110.78,56.67 110.62,56.5 110.29,56.5 110.12,56.67 110.12,57.25 109.96,57.42 109.63,57.42 109.46,57.25 109.46,56.67 109.3,56.5 108.96,56.5 108.8,56.67 108.8,57.25 108.63,57.42 108.11,57.42 102.88,52.18 97.56,52.18 97.09,52.65 v2(97.01,52.65)
  BOTTOM w0.089: CPU1.BA54 91.72,53.07 92.14,52.96 95.04,52.96 95.28,53.21 96.45,53.21 v2(97.01,52.65)
  BOTTOM w0.178: DIMM1.84 129.9,61.65 126.74,61.65 126.53,61.45 v2(126.53,61.05)
M_A_A12: length 50.5
  TOP w0.178: v2(99.12,52.7) v1(99.68,52.7)
  L6 w0.165: v2(99.12,52.7) 99.12,53.5 99.43,53.82 99.95,53.82 100.12,53.65 100.12,52.87 100.28,52.7 100.61,52.7 100.78,52.87 100.78,53.65 100.94,53.82 101.27,53.82 101.44,53.65 101.44,52.87 101.6,52.7 101.93,52.7 102.1,52.87 102.1,53.65 102.26,53.82 103.78,53.82 108.47,58.51 108.99,58.51 109.16,58.35 109.16,58.12 109.32,57.95 109.65,57.95 109.82,58.12 109.82,58.35 109.98,58.51 110.31,58.51 110.48,58.35 110.48,58.12 110.64,57.95 110.98,57.95 111.14,58.12 111.14,58.35 111.31,58.51 111.64,58.51 111.8,58.35 111.8,58.12 111.97,57.95 112.3,57.95 112.46,58.12 112.46,58.35 112.63,58.51 113.99,58.51 114.15,58.68 114.15,59.22 114.32,59.39 114.65,59.39 114.81,59.22 114.81,58.68 114.98,58.51 115.31,58.51 115.48,58.68 115.48,59.24 115.62,59.39 115.99,59.39 116.14,59.24 116.14,58.68 116.3,58.51 116.63,58.51 116.8,58.68 116.8,59.2 116.96,59.37 117.29,59.37 117.46,59.2 117.46,58.68 117.62,58.51 120.52,58.51 121.12,59.11 123,59.11 123.16,59.27 v2(123.16,60.34)
  BOTTOM w0.089: CPU1.AW54 90.52,53.26 90.78,53.39 90.92,53.43 91.09,53.43 91.25,53.44 91.47,53.48 94.65,53.48 94.95,53.79 96.3,53.79 96.48,53.62 98.2,53.62 98.48,53.33
  BOTTOM w0.178: v2(123.16,60.34) 123.16,60.81 122.62,61.35 DIMM1.83 ; 98.48,53.33 v2(99.12,52.7)
M_A_A13: length 53.3
  TOP w0.178: v2(123.16,72.51) 122.93,72.74 v1(122.59,72.74)
  L6 w0.165: v2(123.16,72.51) 122.67,72.51 120.76,74.42 119.89,74.42 119.04,73.58 118.52,73.58 118.36,73.74 118.36,74.11 118.19,74.28 117.86,74.28 117.7,74.11 117.7,73.74 117.53,73.58 117.2,73.58 117.04,73.74 117.04,74.11 116.87,74.28 116.54,74.28 116.38,74.11 116.38,73.74 116.21,73.58 115.88,73.58 115.72,73.74 115.72,74.11 115.55,74.28 115.22,74.28 115.06,74.11 115.06,73.74 114.89,73.58 114.56,73.58 114.4,73.74 114.4,74.11 114.23,74.28 113.9,74.28 113.74,74.11 113.74,73.74 113.57,73.58 113.24,73.58 113.08,73.74 113.08,74.11 112.91,74.28 112.58,74.28 112.42,74.11 112.42,73.74 112.25,73.58 111.21,73.58 110.29,72.65 109.77,72.65 109.6,72.82 109.6,73.96 109.44,74.13 109.11,74.13 108.94,73.96 108.94,72.82 108.78,72.65 107.54,72.65 99,64.12 96.77,64.12 93.66,61.01 93.39,61.01 92.91,61.49 92.3,61.49 92.01,61.2 92.01,59.35 90.44,57.79 v2(89.51,57.79)
  BOTTOM w0.178: v2(89.51,57.79) 89.11,57.38 CPU1.AU46 ; DIMM1.119 122.8,72.15 v2(123.16,72.51)
M_A_A14: length 50.5
  TOP w0.178: v2(127.8,61.05) 127.8,60.76 v1(128.05,60.52)
  L6 w0.165: v2(127.8,61.05) 127.98,60.88 127.98,60.86 128.25,60.59 128.9,60.59 129.07,60.42 129.07,59.96 128.9,59.79 128.24,59.79 128.22,59.77 127.77,59.77 127.61,59.93 127.61,60.14 127.44,60.3 127.11,60.3 126.95,60.14 126.95,59.93 126.79,59.77 125.76,59.77 125.35,59.35 124.4,59.35 124.24,59.19 124.24,58.24 124.07,58.07 121.85,58.07 121.26,57.47 116.17,57.47 114.63,55.93 113.61,55.93 113.45,56.09 113.45,56.69 113.28,56.86 112.95,56.86 112.79,56.69 112.79,56.09 112.62,55.93 107.36,55.93 103.1,51.66 97.34,51.66 97.17,51.83 96.44,51.83 96.27,52 v2(96.27,52.62)
  BOTTOM w0.089: CPU1.AY54 91.46,52.86 91.81,52.86 92.11,52.79 95.14,52.79 95.36,53 95.89,53 v2(96.27,52.62)
  BOTTOM w0.178: DIMM1.80 128.17,60.45 127.8,60.82 v2(127.8,61.05)
M_A_A15: length 48.7
  TOP w0.178: v2(126.53,59.25) 126.53,59.11 v1(126.19,58.77)
  L6 w0.165: v2(99.52,50.97) 99.7,51.14 103.31,51.14 107.54,55.37 114.8,55.37 116.38,56.95 121.47,56.95 122.05,57.53 122.07,57.53 122.09,57.55 124.76,57.55 124.92,57.71 124.92,58.64 125.09,58.8 125.42,58.8 125.58,58.64 125.58,57.44 125.75,57.28 127.12,57.28 127.28,57.44 127.28,58.48 126.71,59.06 126.71,59.08 126.54,59.25 v2(126.53,59.25)
  BOTTOM w0.089: CPU1.BA55 91.52,52.35 91.62,52.35 91.81,52.3 91.98,52.3 92.11,52.34 93.86,52.34 94.15,52.05 96.54,52.05 96.72,52.22 98.82,52.22 99.52,51.52 v2(99.52,50.97)
  BOTTOM w0.178: v2(126.53,59.25) 126.53,59.31 127.08,59.85 DIMM1.78
M_A_BS0: length 50.3
  TOP w0.178: v2(123.3,68.9) 123.07,68.67 v1(122.64,68.67)
  L6 w0.165: v2(89.52,54.2) 89.71,54.39 91.64,54.39 94.08,56.83 94.08,57.54 98.05,61.51 100.08,61.51 108.62,70.05 113.83,70.05 114,70.21 114,70.76 114.16,70.93 114.49,70.93 114.66,70.76 114.66,70.21 114.82,70.05 115.15,70.05 115.32,70.21 115.32,70.76 115.48,70.93 115.81,70.93 115.98,70.76 115.98,70.21 116.14,70.05 116.47,70.05 116.64,70.21 116.64,70.76 116.8,70.93 117.13,70.93 117.3,70.76 117.3,70.21 117.46,70.05 117.79,70.05 117.96,70.21 117.96,70.76 118.12,70.93 118.45,70.93 118.62,70.76 118.62,70.21 118.78,70.05 119.31,70.05 119.82,70.56 120.73,70.56 121.09,70.2 122.02,69.27 122.93,69.27 v2(123.3,68.9)
  BOTTOM w0.178: v2(89.52,54.2) 89.52,54.22 CPU1.AU52 ; v2(123.3,68.9) 123.3,68.93 123.08,69.15 DIMM1.109
M_A_BS1: length 51.9
  TOP w0.178: v2(127.17,69.45) 127.17,69.27 v1(126.85,68.95)
  L6 w0.165: v2(127.17,69.45) 127.17,69.47 126.71,69.93 126.44,69.93 126.02,70.35 122.66,70.35 122.65,70.36 122.57,70.36 121.3,71.64 120.92,72.01 111.86,72.01 111.35,71.5 111.35,71.49 110.95,71.09 108.19,71.09 99.65,62.55 97.62,62.55 92.95,57.89 92.95,57.18 91.28,55.51 89.12,55.51 89.07,55.56 88.55,55.56 88.54,55.57 v2(88.09,56.02)
  BOTTOM w0.178: v2(88.09,56.02) 88.45,56.38 CPU1.AT48 ; DIMM1.108 127.71,68.85 127.17,69.39 v2(127.17,69.45)
M_A_BS2: length 49.8
  TOP w0.178: v2(124.02,56.56) 124.17,56.42 v1(124.17,55.97)
  L6 w0.165: v2(98.79,50.92) 98.79,50.69 98.97,50.51 99.85,50.51 99.96,50.62 103.53,50.62 107.76,54.85 108.28,54.85 108.44,54.68 108.44,54.02 108.61,53.86 108.94,53.86 109.1,54.02 109.1,54.68 109.27,54.85 109.6,54.85 109.76,54.68 109.76,54.15 109.93,53.99 110.26,53.99 110.42,54.15 110.42,54.68 110.59,54.85 110.92,54.85 111.08,54.68 111.08,54.25 111.25,54.08 111.58,54.08 111.74,54.25 111.74,54.68 111.91,54.85 112.24,54.85 112.4,54.68 112.4,54.26 112.57,54.1 112.9,54.1 113.06,54.26 113.06,54.68 113.23,54.85 115.02,54.85 116.6,56.43 121.71,56.43 122.3,57.03 123.58,57.03 124.02,56.58 v2(124.02,56.56)
  BOTTOM w0.089: CPU1.AY55 91.19,52.17 91.59,52.17 91.79,52.12 92,52.12 92.13,52.16 93.78,52.16 94.13,51.81 96.72,51.81 96.75,51.78 98.62,51.78 98.79,51.61 v2(98.79,50.92)
  BOTTOM w0.178: v2(124.02,56.56) 124.8,57.34 124.8,58.9 124.08,59.62 123.03,59.62 122.5,60.15 DIMM1.79
M_A_CAS#: length 51.6
  TOP w0.178: v1(124.11,71.98) 124.11,72.16 124.27,72.31 124.27,72.34 v2(124.43,72.51)
  L6 w0.165: v2(88.78,56.05) 88.78,56.08 88.5,56.36 88.5,56.86 88.89,57.25 90.64,57.25 96.98,63.59 99.22,63.59 107.75,72.13 110.5,72.13 111.43,73.05 119.26,73.05 120.1,73.9 120.51,73.9 123.01,71.41 124.81,71.41 124.98,71.57 124.98,71.94 124.6,72.31 124.6,72.33 v2(124.43,72.51)
  BOTTOM w0.178: v2(88.78,56.05) 88.78,56.15 CPU1.AU48 ; DIMM1.115 123.45,70.95 124.43,71.93 v2(124.43,72.51)
M_A_CKE0: length 48.9
  TOP w0.178: v1(122.16,56.56) 122.16,56.56 v2(122.75,56.56)
  L6 w0.165: v2(122.75,56.56) 122.75,56.37 122.29,55.9 121.14,55.9 120.82,55.58 120.48,55.58 120.16,55.9 119.82,55.9 119.49,55.58 119.16,55.58 118.83,55.9 118.5,55.9 118.17,55.58 117.84,55.58 117.51,55.9 116.81,55.9 114.95,54.04 114.72,54.04 114.54,54.22 114.31,54.22 114.07,53.98 114.07,53.75 114.25,53.58 114.25,53.34 113.83,52.92 112.96,52.92 112.8,53.09 112.8,53.3 112.63,53.47 112.3,53.47 112.14,53.3 112.14,53.09 111.97,52.92 111.64,52.92 111.48,53.09 111.48,53.3 111.31,53.47 110.98,53.47 110.82,53.3 110.82,53.09 110.65,52.92 110.32,52.92 110.16,53.09 110.16,53.3 109.99,53.47 109.66,53.47 109.5,53.3 109.5,53.11 108.68,52.3 108.27,52.3 107.29,53.27 106.93,53.27 106.66,53 106.66,52.64 107.43,51.87 107.43,51.64 107.19,51.41 106.96,51.41 106.12,52.24 105.89,52.24 103.63,49.99 96.78,49.99 96.58,50.19 v2(96.58,50.84)
  BOTTOM w0.089: v2(96.58,50.84) 96.58,51.23 96.37,51.43 94.01,51.43 93.8,51.63 92.1,51.63 91.87,51.72 91.6,51.9 CPU1.BA56
  BOTTOM w0.178: v2(122.75,56.56) 122.75,57.21 122.92,57.37 124.07,57.37 124.24,57.54 124.24,58.43 124.07,58.6 123.14,58.6 122.9,58.35 DIMM1.73
M_A_CKE1: length 48.6
  TOP w0.178: v1(128.25,58.62) 128.1,58.62 127.8,58.91 v2(127.8,58.98)
  L6 w0.165: v2(97.21,50.89) 97.1,51.01 97.1,51.06 96.84,51.31 96.21,51.31 95.8,50.9 95.8,49.89 96.22,49.47 103.85,49.47 105.24,50.86 107.98,50.86 109.52,52.4 114.39,52.4 117.04,55.06 122.18,55.06 123.07,55.95 127.09,55.95 127.8,56.67 v2(127.8,58.98)
  BOTTOM w0.089: v2(97.21,50.89) 96.48,51.63 94.06,51.63 93.79,51.9 CPU1.BB56
  BOTTOM w0.178: v2(127.8,58.98) 128.13,58.65 DIMM1.74
M_A_CLK0: length 50.8
  TOP w0.102: v2(123.16,67.24) v1(122.6,67.24)
  L6 w0.102: v2(88.12,54.2) 88.12,52.99 88.26,52.85 88.91,52.2 90.07,52.2 90.39,52.52 92.57,52.52 92.86,52.81 93,52.81 93.24,52.58 93.56,52.58 93.92,52.94 93.92,53.26 93.69,53.5 93.69,53.64 94.09,54.04 94.23,54.04 94.44,53.83 94.76,53.83 95.12,54.19 95.12,54.51 94.91,54.72 94.91,54.87 96.2,56.15 96.2,57.37 98.74,59.91 100.84,59.91 109.36,68.43 120.47,68.43 121.32,67.58 121.66,67.24 v2(123.16,67.24)
  BOTTOM w0.102: DIMM1.101 122.46,66.75 122.74,66.47 122.87,66.47 122.98,66.58 123.34,66.58 123.39,66.53 123.54,66.53 123.65,66.65 123.65,66.8 123.5,66.95 123.45,67 123.21,67.24 v2(123.16,67.24) ; CPU1.AT53 88.38,53.65 88.19,53.65 88.09,53.75 88.09,53.84 88.02,53.92 88.02,54.09 v2(88.12,54.2)
M_A_CLK1: length 50.6
  TOP w0.102: v2(127.8,67.65) 127.8,67.95 v1(128.02,68.17)
  L6 w0.102: v2(88.87,53.27) 88.92,53.23 89.41,52.93 89.7,52.93 90.01,53.24 92.25,53.24 95.47,56.47 95.47,57.67 98.44,60.64 100.43,60.64 108.94,69.15 120.77,69.15 121.73,68.19 127.26,68.19 127.52,67.94 v2(127.8,67.65)
  BOTTOM w0.102: v2(127.8,67.65) 128.05,67.33 128.21,67.24 128.39,67.16 128.74,67.09 128.98,67.05 129.9,67.05 DIMM1.102 ; CPU1.AT55 88.84,53.26 88.85,53.26 88.86,53.27 v2(88.87,53.27)
M_A_CLK#0: length 50.8
  TOP w0.102: v1(124.11,67.79) 124.11,67.53 v2(123.82,67.24)
  L6 w0.102: v2(123.82,67.24) 123.82,67.53 123.68,67.67 122.98,67.67 122.76,67.46 121.75,67.46 121.47,67.73 120.56,68.64 109.27,68.64 100.75,60.13 98.65,60.13 95.98,57.46 95.98,56.24 94.7,54.96 94.7,54.63 94.91,54.42 94.91,54.28 94.67,54.05 94.53,54.05 94.32,54.26 94,54.26 93.47,53.73 93.47,53.59 93.47,53.41 93.71,53.17 93.71,53.03 93.47,52.79 93.33,52.79 93.09,53.03 92.77,53.03 92.48,52.74 90.3,52.74 89.98,52.42 89,52.42 88.46,52.96 88.42,53 88.41,53 88.34,53.08 88.34,53.71 v2(88.83,54.2)
  BOTTOM w0.102: CPU1.AU53 v2(88.83,54.2) ; v2(123.82,67.24) 123.39,67.62 123.28,67.65 123.15,67.69 122.98,67.64 122.89,67.59 122.61,67.35 DIMM1.103
M_A_CLK#1: length 50.7
  TOP w0.102: v2(128.44,67.65) 128.45,67.66 v1(129.19,67.66)
  L6 w0.102: v2(128.44,67.65) 128.44,67.96 128.31,68.09 127.67,68.09 127.35,68.41 121.82,68.41 120.86,69.37 108.85,69.37 100.34,60.85 98.35,60.85 95.26,57.76 95.26,56.56 92.16,53.46 89.6,53.46 v2(89.53,53.38)
  BOTTOM w0.102: v2(128.44,67.65) DIMM1.104 ; v2(89.53,53.38) 89.85,53.07 89.85,52.91 89.74,52.81 CPU1.AU55
M_A_CS#0: length 55
  TOP w0.178: v1(126.91,70.71) 126.91,70.96 127,71.06 127,71.08 v2(127.17,71.25)
  L6 w0.165: v2(88.79,58.74) 88.79,58.98 89.38,59.57 89.38,60.94 89.21,61.1 89.21,61.82 89.44,62.04 90.6,62.04 91.62,63.05 93.5,63.05 96.12,65.68 96.54,65.68 100.78,69.92 101.02,69.92 101.07,69.86 101.31,69.86 101.54,70.1 101.54,70.33 101.48,70.39 101.48,70.62 101.72,70.86 101.95,70.86 102.01,70.8 102.24,70.8 102.48,71.03 102.48,71.26 102.42,71.32 102.42,71.56 104.92,74.06 106.69,74.06 108.62,75.98 121.67,75.98 123.01,74.64 124.32,74.64 126.23,72.73 126.23,71.88 126.4,71.71 127,71.71 127.17,71.55 v2(127.17,71.25)
  BOTTOM w0.178: DIMM1.114 128.43,70.65 128.43,70.65 127.58,70.65 127.17,71.06 v2(127.17,71.25) ; v2(88.79,58.74) 89.1,58.43 CPU1.AU45
M_A_CS#1: length 56.6
  TOP w0.178: v1(124.26,74.11) 123.87,73.72 v2(123.87,73.62)
  L6 w0.165: v2(89.43,58.79) 89.53,58.89 89.53,58.98 90.96,60.42 90.96,61.67 91.83,62.53 93.71,62.53 96.34,65.16 98.56,65.16 98.93,65.53 98.93,65.76 98.33,66.36 98.33,66.59 98.56,66.83 98.8,66.83 99.4,66.23 99.63,66.23 99.86,66.46 99.86,66.69 99.26,67.29 99.26,67.53 99.5,67.76 99.73,67.76 100.33,67.16 100.56,67.16 100.93,67.53 100.93,67.76 100.61,68.09 100.61,68.32 100.84,68.56 101.07,68.56 101.4,68.23 101.63,68.23 102,68.6 102,68.83 101.63,69.21 101.63,69.44 101.86,69.68 102.09,69.68 102.47,69.3 102.7,69.3 102.94,69.53 102.94,69.77 102.56,70.14 102.56,70.38 102.79,70.61 103.03,70.61 103.4,70.23 103.64,70.23 104.01,70.6 104.01,70.84 103.83,71.01 103.83,71.24 104.07,71.47 104.3,71.47 104.47,71.3 104.71,71.3 105.08,71.67 105.08,71.91 104.72,72.26 104.72,72.49 104.95,72.73 105.19,72.73 105.54,72.37 105.78,72.37 108.86,75.46 121.37,75.46 122.74,74.09 123.64,74.09 123.87,73.86 v2(123.87,73.62)
  BOTTOM w0.178: DIMM1.121 122.6,72.75 122.92,73.08 123.34,73.08 123.71,73.45 123.71,73.46 v2(123.87,73.62) ; CPU1.AU43 89.1,59.12 v2(89.43,58.79)
M_A_DIMA_ODT0: length 55.2
  TOP w0.114: v2(127.17,73.02) 127.07,73.12 v1(126.55,73.12)
  L6 w0.102: v2(127.17,73.02) 127.04,73.33 127,73.38 126.92,73.54 126.41,74.61 125.85,75.5 125.46,75.89 125.31,75.96 124.44,76.14 123.54,76.27 123.2,76.38 122.9,76.54 122.33,76.88 121.93,77.01 108.16,77.01 105.32,75.32 105.05,75.2 104.69,75.12 104.52,75.07 104.42,75.01 104.31,74.94 99.58,70.21 94.47,67.11 94.12,66.9 92.76,65.54 90.17,64.52 88.77,63.13 88.1,61.94 88.08,61.87 88.05,61.78 88.05,59.85 v2(88.11,57.87)
  BOTTOM w0.114: DIMM1.116 128.87,71.25 127.79,72.16 127.67,72.28 v2(127.17,73.02) ; CPU1.AT45 v2(88.11,57.87)
M_A_DIMA_ODT1: length 56.7
  TOP w0.114: v2(127.8,72.95) 127.84,72.92 v1(128.36,72.92)
  L6 w0.102: v2(88.75,59.62) 88.75,59.74 88.4,60.08 88.4,61.7 89.13,62.43 89.13,62.98 90.24,64.09 93.52,64.09 95.77,66.34 96.21,66.34 104.49,74.62 106.27,74.62 108.31,76.65 121.85,76.65 122.72,75.78 122.92,75.58 125.26,75.58 125.54,75.31 125.54,74.34 126.74,73.14 126.74,72.63 127.16,72.2 128.6,72.2 128.76,72.37 128.76,72.65 128.46,72.95 v2(127.8,72.95)
  BOTTOM w0.114: v2(88.75,59.62) 88.72,59.62 88.45,59.35 CPU1.AT43 ; v2(127.8,72.95) 128.3,72.45 DIMM1.120
M_A_DQ0: length 57.4
  TOP w0.114: v1(126.8,40.71) 126.8,40.88 v2(127.17,41.25)
  L6 w0.102: v2(127.17,41.25) 126.74,41.68 126.29,41.68 125.78,41.17 121.21,41.17 115.16,35.12 109.99,35.12 109.36,34.49 109.36,33.73 108.84,33.22 97.18,33.22 96.63,33.76 93.37,33.76 92.05,35.08 91.47,35.67 91.22,35.91 87.66,35.91 86.18,37.39 86.18,38.36 v2(85.83,38.71)
  BOTTOM w0.089: 84.79,39.44 84.79,41.67 84.89,41.77 84.89,42.69 CPU1.AL71
  BOTTOM w0.114: v2(85.83,38.71) 85.53,38.71 85.16,39.08 84.79,39.44 ; DIMM1.22 127.65,40.65 127.17,41.13 v2(127.17,41.25)
M_A_DQ1: length 57.9
  TOP w0.114: v2(85.79,40.03) 85.79,40.02 v1(86.34,40.02)
  L6 w0.102: v2(124.43,40.33) 124.06,39.95 arc(123.9,39.87) 123.73,39.85 121.88,39.85 arc(121.53,39.79) 121.22,39.62 115.62,34.02 113.11,34.02 112.43,33.91 111.93,33.76 111.36,33.35 110.91,32.98 110.19,32.26 110.06,32.17 109.98,32.13 109.89,32.11 94.29,32.11 arc(93.4,32.31) 92.69,32.88 90.76,34.81 86.13,34.81 84.98,35.95 84.98,39.22 v2(85.79,40.03)
  BOTTOM w0.089: 85.25,40.85 85.23,40.87 85.23,41.53 85.25,41.55 85.25,42.15 85.86,42.77 85.86,43.27 85.79,43.41 85.79,43.61 85.83,43.72 85.83,43.95 85.77,44.14 85.77,44.48 85.39,44.99 CPU1.AL68
  BOTTOM w0.114: v2(85.79,40.03) 85.74,40.03 85.25,40.51 85.25,40.85 ; v2(124.43,40.33) 123.81,40.95 DIMM1.23
M_A_DQ2: length 58.3
  TOP w0.114: v1(122.56,43.95) v2(123.16,43.95)
  L6 w0.102: v2(86.72,45.8) 86.72,44.18 86.82,44.08 87.18,44.08 87.28,43.97 87.28,43.77 87.18,43.67 86.82,43.67 86.72,43.57 86.72,40.87 87.04,40.55 87.04,39.34 87.44,38.95 87.44,38.08 88.34,37.17 91.74,37.17 93.8,35.11 94.71,35.11 97.24,35.11 97.36,35.23 107.03,35.23 107.28,35.47 107.28,36.54 108.88,38.15 111.64,38.15 111.83,38.34 111.83,38.97 111.97,39.11 112.34,39.11 112.44,39.01 112.44,38.25 112.54,38.15 112.87,38.15 112.97,38.25 112.97,39.01 113.07,39.11 113.44,39.11 113.54,39.01 113.54,38.62 113.66,38.51 113.96,38.51 114.08,38.62 114.08,39.01 114.18,39.11 115.09,39.11 115.2,39.01 115.2,38.5 115.31,38.39 115.62,38.39 115.73,38.5 115.73,39.01 115.83,39.11 116.16,39.11 116.26,39.01 116.26,38.49 116.38,38.38 116.64,38.38 116.8,38.54 116.8,39.01 116.9,39.11 117.3,39.11 122.14,43.95 v2(123.16,43.95)
  BOTTOM w0.114: v2(123.16,43.95) DIMM1.33 ; v2(86.72,45.8) 86.62,45.7 CPU1.AN68
M_A_DQ3: length 57.4
  TOP w0.114: v2(128.44,44.25) 128.44,44.71 v1(128.56,44.82)
  L6 w0.102: v2(87.54,41.39) 88.09,40.84 88.09,40.33 88.1,40.32 88.1,39.56 88.5,39.15 88.5,38.5 88.75,38.24 89.43,38.24 89.46,38.27 92.25,38.27 92.4,38.13 94.2,36.32 95.19,36.32 95.99,37.12 98.57,37.12 99.7,38.25 107.12,38.25 109.08,40.21 116.84,40.21 121.74,45.12 129.56,45.12 129.68,45 129.68,43.72 129.56,43.61 129.08,43.61 v2(128.44,44.25)
  BOTTOM w0.089: CPU1.AN69 86.9,44.09 87.05,43.89 87.18,43.73 87.18,41.74 v2(87.54,41.39)
  BOTTOM w0.114: DIMM1.34 v2(128.44,44.25)
M_A_DQ4: length 58
  TOP w0.114: v1(128.58,40.66) 128.53,40.71 128.53,41.16 v2(128.44,41.25)
  L6 w0.102: v2(128.44,41.25) 128,40.8 121.36,40.8 115.31,34.75 110.14,34.75 109.72,34.34 109.72,33.57 109,32.85 97.03,32.85 96.48,33.39 93.22,33.39 91.07,35.54 87.5,35.54 86.07,36.98 85.94,37.16 85.8,37.54 85.75,37.74 v2(85.75,38.04)
  BOTTOM w0.089: CPU1.AL70 85.18,43.63 85.13,43.44 84.71,43.02 84.71,41.9 84.46,41.65 84.46,39.68
  BOTTOM w0.114: v2(85.75,38.04) 85.65,38.04 84.46,39.24 84.46,39.68 ; DIMM1.24 128.44,41.25 v2(128.44,41.25)
M_A_DQ5: length 58.4
  TOP w0.114: v2(123.16,40.33) v1(122.56,40.33)
  L6 w0.102: v2(123.16,40.33) 123.15,40.33 123.04,40.44 121.52,40.44 115.47,34.38 110.3,34.38 110.09,34.18 110.09,33.81 110.19,33.71 110.56,33.71 110.67,33.59 110.67,33.29 110.56,33.17 110.19,33.17 110.09,33.07 110.09,32.72 109.85,32.48 96.63,32.48 96.43,32.68 96.43,32.93 96.33,33.03 95.96,33.03 95.86,32.92 95.86,32.58 95.76,32.47 95.43,32.47 95.32,32.58 95.32,32.92 95.22,33.03 94.89,33.03 94.79,32.92 94.79,32.58 94.69,32.47 94.36,32.47 94.26,32.58 94.26,32.92 94.16,33.03 93.83,33.03 93.67,32.87 93.22,32.87 90.91,35.17 87.2,35.17 86.99,35.39 86.76,35.39 86.55,35.17 86.28,35.17 85.35,36.11 85.35,37.33 85.34,37.34 85.34,39.26 85.47,39.39 v2(85.76,39.39)
  BOTTOM w0.089: CPU1.AL69 85.6,44.28 85.6,44.11 85.65,43.92 85.65,43.74 85.61,43.62 85.61,43.38 85.68,43.23 85.68,42.94 85.07,42.33 85.07,41.67 85,41.6 85,40.2 85.05,40.15
  BOTTOM w0.114: v2(123.16,40.33) 123.14,40.35 DIMM1.21 ; v2(85.76,39.39) 85.24,39.39 85.05,39.59 85.05,40.15
M_A_DQ6: length 56.7
  TOP w0.114: v1(126.75,44.8) 127.17,44.38 v2(127.17,44.25)
  L6 w0.102: v2(127.17,44.25) 127.17,43.37 127.06,43.25 125.87,43.25 125.76,43.37 125.76,44.51 125.52,44.75 121.9,44.75 116.99,39.85 109.23,39.85 107.27,37.89 99.85,37.89 98.98,37.01 98.98,36.33 98.61,35.96 97.13,35.96 96.62,36.48 95.87,36.48 95.23,35.85 94.15,35.85 92.1,37.91 89.46,37.91 89.43,37.87 88.6,37.87 88.13,38.34 88.13,39.25 87.91,39.48 87.91,39.49 87.9,39.5 87.9,39.9 87.91,39.91 87.91,40.24 87.9,40.25 87.9,40.37 v2(87.51,40.76)
  BOTTOM w0.089: CPU1.AN70 87.01,43.55 87.01,41.26 v2(87.51,40.76)
  BOTTOM w0.114: DIMM1.36 127.71,44.85 127.17,44.31 v2(127.17,44.25)
M_A_DQ7: length 55.7
  TOP w0.114: v1(124.8,44.49) 124.8,44.32 v2(124.43,43.95)
  L6 w0.102: v2(87.5,40.07) 87.5,39.4 87.8,39.1 87.8,38.23 88.49,37.54 91.89,37.54 92.14,37.29 93.95,35.48 94.56,35.48 95.39,35.48 95.5,35.6 95.83,35.6 95.93,35.7 95.93,36 96.04,36.11 96.35,36.11 96.47,36 96.47,35.7 96.57,35.6 97.94,35.6 97.94,35.6 99.46,35.6 100,36.14 100,37.17 100.34,37.52 107.43,37.52 109.39,39.48 109.76,39.48 109.86,39.38 109.86,38.62 109.96,38.52 110.29,38.52 110.39,38.62 110.39,39.38 110.49,39.48 110.82,39.48 110.92,39.38 110.92,38.62 111.03,38.52 111.36,38.52 111.46,38.62 111.46,39.38 111.56,39.48 117.15,39.48 122.05,44.38 124.27,44.38 124.43,44.23 v2(124.43,43.95)
  BOTTOM w0.089: v2(87.5,40.07) 86.77,40.8 86.77,43.13 CPU1.AN71
  BOTTOM w0.114: DIMM1.35 123.91,44.55 124.43,44.02 v2(124.43,43.95)
M_A_DQ8: length 51.1
  TOP w0.114: v2(124.43,45.75) v1(124.43,46.32)
  L6 w0.102: v2(88.94,39.32) 89.24,39.02 92.65,39.02 93,38.68 93.36,38.68 93.47,38.78 93.47,39.2 93.57,39.3 93.77,39.3 93.87,39.2 93.87,38.78 93.97,38.68 94.18,38.68 94.28,38.78 94.28,39.2 94.38,39.3 94.58,39.3 94.69,39.2 94.69,38.78 94.79,38.68 95.25,38.68 95.79,38.14 97.43,38.14 97.8,38.52 97.8,38.66 97.5,38.97 97.5,39.11 97.64,39.25 97.79,39.25 98.09,38.95 98.24,38.95 98.59,39.3 105.07,39.3 106.98,41.2 116.37,41.2 121.35,46.18 124,46.18 v2(124.43,45.75)
  BOTTOM w0.089: CPU1.AR70 87.93,43.6 87.97,43.41 88.02,43.2 88.02,42.49 88.28,42.23 88.28,40.24
  BOTTOM w0.114: v2(88.94,39.32) 88.28,39.92 88.28,40.24 ; DIMM1.41 123.9,46.35 124.43,45.82 v2(124.43,45.75)
M_A_DQ9: length 52.1
  TOP w0.114: v2(123.16,49.95) 123.14,49.93 122.64,49.93 122.64,49.93 v1(122.6,49.93)
  L6 w0.102: v2(123.16,49.95) 122.99,49.78 122.09,49.78 121.99,49.68 121.99,49.6 121.89,49.5 121.56,49.5 121.46,49.6 121.46,49.68 121.36,49.78 121.02,49.78 120.92,49.68 120.92,49.6 120.82,49.5 120.49,49.5 120.39,49.6 120.39,49.68 120.29,49.78 119.96,49.78 119.86,49.68 119.86,49.6 119.75,49.5 119.42,49.5 119.32,49.6 119.32,49.68 119.22,49.78 118.85,49.78 114.19,45.11 106.29,45.11 105.79,44.61 104.47,44.61 104.37,44.51 104.37,43.77 104.26,43.67 103.93,43.67 103.83,43.77 103.83,44.51 103.73,44.61 103.4,44.61 103.3,44.51 103.3,44.09 103.2,43.99 102.87,43.99 102.76,44.09 102.76,44.51 102.66,44.61 102.29,44.61 101.74,44.05 101.74,43.73 101.9,43.56 103.43,43.56 103.54,43.45 103.54,43.14 103.45,43.05 103.01,43.05 102.91,42.94 102.91,42.51 102.81,42.4 102.48,42.4 102.37,42.51 102.37,42.94 102.27,43.05 101.94,43.05 101.84,42.94 101.84,42.5 101.74,42.4 101.41,42.4 101.31,42.5 101.31,42.94 101.21,43.05 93.9,43.05 92.82,44.13 92.05,44.13 91.31,44.86 89.76,44.86 89.59,44.7 88.88,44.7 88.72,44.86 87.24,44.86 v2(87.24,44.87)
  BOTTOM w0.114: v2(87.24,44.87) 87.5,45.14 CPU1.AR68 ; DIMM1.53 v2(123.16,49.95)
M_A_DQ10: length 49.5
  TOP w0.114: v2(128.44,46.65) v1(128.44,47.21)
  L6 w0.102: v2(128.44,46.65) 128.44,46.92 127.91,47.45 125.76,47.45 125.24,46.93 121.02,46.93 116.09,42 115.65,42 115.55,42.11 115.55,42.62 115.45,42.72 115.24,42.72 115.14,42.62 115.14,42.11 115.04,42 114.84,42 114.73,42.11 114.73,42.63 114.63,42.73 114.43,42.73 114.33,42.63 114.33,42.11 114.23,42 106.74,42 104.77,40.04 93.29,40.04 93.03,40.3 v2(90.56,40.3)
  BOTTOM w0.089: CPU1.AU71 89.07,42.92 89.78,42.21 89.78,41.08 v2(90.56,40.3)
  BOTTOM w0.114: DIMM1.42 v2(128.44,46.65)
M_A_DQ11: length 51.2
  TOP w0.114: v1(126.88,47.16) 127.17,46.87 v2(127.17,46.65)
  L6 w0.102: v2(90.52,39.66) 90.77,39.41 92.79,39.41 93.05,39.67 104.92,39.67 106.89,41.64 116.26,41.64 121.18,46.55 124.59,46.55 124.69,46.45 124.69,46.28 124.79,46.18 124.99,46.18 125.09,46.28 125.09,46.45 125.2,46.55 125.96,46.55 126.1,46.69 126.1,46.83 126.36,47.08 126.74,47.08 v2(127.17,46.65)
  BOTTOM w0.089: CPU1.AU68 89.47,45.14 89.47,45.13 89.63,45.13 90.14,44.63 90.14,44.41 90.1,44.29 90.1,44.09 90.14,43.96 90.14,43.09 90.33,42.9 90.46,42.9 90.83,42.53 90.83,42.53 90.98,42.39 90.98,40.13 90.96,40.11
  BOTTOM w0.114: v2(127.17,46.65) 127.17,46.59 127.71,46.05 DIMM1.40 ; 90.96,40.11 v2(90.52,39.66)
M_A_DQ12: length 49.8
  TOP w0.114: v2(123.16,45.75) v1(122.59,45.75)
  L6 w0.102: v2(88.93,38.68) 88.95,38.66 92.39,38.66 94.09,36.95 94.95,36.95 95.78,37.78 97.58,37.78 98.74,38.93 105.7,38.93 105.85,39.08 105.85,39.55 106.04,39.74 106.29,39.74 106.94,39.1 107.08,39.1 107.33,39.35 107.33,39.49 106.67,40.16 106.67,40.3 106.81,40.44 106.96,40.44 107.59,39.81 107.74,39.81 107.88,39.95 107.88,40.1 107.45,40.52 107.45,40.67 107.62,40.84 108.04,40.84 108.15,40.72 108.15,40.64 108.25,40.54 108.45,40.54 108.56,40.64 108.56,40.72 108.67,40.84 116.54,40.84 121.45,45.75 v2(123.16,45.75)
  BOTTOM w0.089: 87.98,40.04 87.98,41.86 87.98,41.87 87.98,42.2 87.98,42.21 87.98,42.29 87.75,42.52 CPU1.AR71
  BOTTOM w0.114: 87.98,40.04 87.98,39.58 v2(88.93,38.68) ; DIMM1.39 123.16,45.75 v2(123.16,45.75)
M_A_DQ13: length 51.3
  TOP w0.114: v2(124.43,49.95) v1(124.43,50.51)
  L6 w0.102: v2(88.94,39.98) 88.46,40.45 88.46,42.14 90.03,43.71 92.71,43.71 93.88,42.54 94.62,42.54 94.87,42.3 95.14,42.03 103.27,42.03 105.48,44.24 105.94,44.24 106.44,44.74 114.34,44.74 118.14,48.54 118.73,49.13 123.61,49.13 v2(124.43,49.95)
  BOTTOM w0.089: v2(88.94,39.98) 88.57,40.44 88.54,40.57 88.49,40.97 88.46,41.33 88.46,42.32 88.2,42.58 88.2,43.22 88.15,43.43 88.15,43.49 88.06,43.85 CPU1.AR69
  BOTTOM w0.114: v2(124.43,49.95) 123.98,49.5 122.69,49.5 122.54,49.35 DIMM1.51
M_A_DQ14: length 49.9
  TOP w0.114: v2(128.44,49.05) v1(128.44,49.65)
  L6 w0.102: v2(90.57,40.93) 92.91,40.93 93.44,40.4 104.62,40.4 107.33,43.12 116.34,43.12 120.73,47.5 122.8,47.5 123.01,47.3 125.09,47.3 125.76,47.97 127.67,47.97 127.81,48.11 127.81,48.25 127.91,48.35 128.5,48.35 128.6,48.25 128.6,48.06 128.68,47.97 129.05,47.97 129.17,48.09 129.17,48.94 129.05,49.05 v2(128.44,49.05)
  BOTTOM w0.089: v2(90.57,40.93) 89.98,41.52 89.98,42.26 89.33,42.91 89.33,43.27 89.27,43.53 CPU1.AU70
  BOTTOM w0.114: DIMM1.50 v2(128.44,49.05)
M_A_DQ15: length 50.9
  TOP w0.114: v2(127.17,49.05) 127.17,48.87 126.88,48.58 126.88,48.58 v1(126.87,48.58)
  L6 w0.102: v2(127.17,49.05) 127.17,48.5 127.03,48.35 125.33,48.35 125.22,48.24 125.22,47.96 124.92,47.67 123.16,47.67 122.95,47.87 120.28,47.87 119.65,47.24 119.65,46.95 116.19,43.48 107.18,43.48 105.71,42.02 105.56,42.02 105.38,42.2 105.22,42.2 104.65,41.63 104.65,41.49 104.84,41.29 104.84,41.15 104.61,40.92 104.46,40.92 104.27,41.11 104.13,41.11 103.79,40.77 93.59,40.77 92.97,41.4 92.97,41.68 92.6,42.05 92.03,42.05 91.93,41.95 91.93,41.4 91.83,41.3 91.5,41.3 91.39,41.4 91.39,41.83 91.29,41.93 90.92,41.93 v2(90.56,41.57)
  BOTTOM w0.089: v2(90.56,41.57) 90.56,41.57 90.18,41.95 90.18,42.36 89.52,43.01 89.52,43.27 89.38,43.86 89.38,44.06 89.35,44.13 CPU1.AU69
  BOTTOM w0.114: DIMM1.52 127.56,49.65 127.17,49.26 v2(127.17,49.05)
M_A_DQ16: length 56.9
  TOP w0.114: v1(128.63,55.62) 128.44,55.43 v2(128.44,55.05)
  L6 w0.102: v2(128.44,55.05) 126.4,53.01 117.57,53.01 115.18,50.62 110.35,50.62 108.83,49.1 106.01,49.1 104.58,47.67 101.05,47.67 100.53,47.15 97.27,47.15 97.11,47 96.22,47 96.11,46.89 96.11,46.67 96.01,46.57 95.81,46.57 95.71,46.67 95.71,46.89 95.61,47 95.23,47 95.01,47.21 94.24,47.98 94.24,48.06 93.67,48.63 93.67,48.77 93.86,48.96 93.86,49.11 93.72,49.25 93.57,49.25 93.38,49.06 93.24,49.06 92.98,49.32 92.09,49.32 91.99,49.22 91.99,49.04 91.88,48.93 91.7,48.93 91.58,49.04 91.58,49.22 91.48,49.32 91.28,49.32 91.18,49.42 91.18,49.56 91.08,49.67 90.87,49.67 90.77,49.56 90.77,49.42 90.67,49.32 90.44,49.32 90.32,49.2 85.4,49.2 85.29,49.3 85.29,49.56 85.19,49.67 84.99,49.67 84.89,49.56 84.89,49.3 84.79,49.2 83.99,49.2 83.02,48.23 83.02,47.84 v2(82.59,47.41)
  BOTTOM w0.114: CPU1.AF65 82.92,47.09 v2(82.59,47.41) ; DIMM1.70 v2(128.44,55.05)
M_A_DQ17: length 56.2
  TOP w0.114: v2(127.17,55.05) 126.61,55.05 v1(126.6,55.06)
  L6 w0.102: v2(82.59,48.06) 82.59,48.32 84.31,50.03 92.77,50.03 92.91,50.18 93.3,50.18 94.61,48.88 94.61,48.14 95.38,47.36 96.96,47.36 97.11,47.52 100.37,47.52 100.89,48.04 104.43,48.04 105.86,49.46 108.68,49.46 110.2,50.99 115.03,50.99 117.43,53.39 125.51,53.39 125.86,53.74 125.86,53.88 125.54,54.2 125.54,54.34 125.69,54.48 125.83,54.48 126.15,54.17 126.29,54.17 126.43,54.31 126.43,54.46 126.28,54.6 126.28,54.75 126.43,54.89 126.57,54.89 126.72,54.74 126.86,54.74 v2(127.17,55.05)
  BOTTOM w0.114: v2(82.59,48.06) 82.92,47.74 CPU1.AF64 ; DIMM1.68 127.77,54.45 v2(127.17,55.05)
M_A_DQ18: length 56.6
  TOP w0.114: v1(124.8,52.24) 124.43,51.87 v2(124.43,51.75)
  L6 w0.102: v2(124.43,51.75) 124.43,51.36 124.35,51.28 118.27,51.28 114.46,47.47 113.84,47.47 113.74,47.37 113.74,46.62 113.64,46.52 113.43,46.52 113.33,46.62 113.33,47.37 113.23,47.47 112.86,47.47 112.76,47.37 112.76,46.6 112.66,46.5 112.45,46.5 112.35,46.6 112.35,47.33 112.25,47.43 112.04,47.43 111.94,47.33 111.94,46.6 111.84,46.5 111.64,46.5 111.54,46.6 111.54,47.33 111.43,47.43 111.23,47.43 111.13,47.33 111.13,46.6 111.03,46.5 106.72,46.5 106.62,46.6 106.62,47.05 106.51,47.15 106.36,47.15 106.21,47 106.21,46.6 106.11,46.5 105.72,46.5 105.26,46.04 104.95,46.04 101.76,46.04 99.87,44.15 95.33,44.15 92.18,47.3 90.48,47.3 89.6,48.18 86.61,48.18 85.84,47.41 85.47,47.41 85.37,47.51 85.37,47.73 85.26,47.83 85.06,47.83 84.96,47.73 84.96,47.51 84.86,47.41 v2(84.42,47.41)
  BOTTOM w0.114: DIMM1.57 123.91,51.15 124.43,51.68 v2(124.43,51.75) ; v2(84.42,47.41) 84.55,47.41 CPU1.AK65
M_A_DQ19: length 57
  TOP w0.114: v2(123.16,51.75) 122.57,51.75 v1(122.56,51.76)
  L6 w0.102: v2(84.45,48.11) 84.72,48.38 89.52,48.38 89.73,48.38 90.14,47.96 90.35,47.96 90.64,47.67 92.33,47.67 93.09,46.91 93.23,46.91 93.29,46.97 93.43,46.97 93.58,46.82 93.58,46.68 93.52,46.63 93.52,46.48 93.67,46.34 93.81,46.34 93.86,46.39 94.01,46.39 94.15,46.25 94.15,46.1 94.1,46.05 94.1,45.91 94.24,45.76 94.38,45.76 94.44,45.82 94.58,45.82 94.73,45.67 94.73,45.53 94.67,45.48 94.67,45.33 95.48,44.52 99.72,44.52 100.19,44.99 100.19,45.13 99.93,45.39 99.93,45.53 100.08,45.68 100.22,45.68 100.48,45.42 100.62,45.42 101.61,46.41 105.11,46.41 106.53,47.84 106.9,47.84 107,47.74 107,46.97 107.1,46.87 107.31,46.87 107.41,46.97 107.41,47.74 107.51,47.84 107.71,47.84 107.81,47.74 107.81,46.97 107.92,46.87 108.12,46.87 108.22,46.97 108.22,47.74 108.32,47.84 108.53,47.84 108.63,47.74 108.63,46.97 108.73,46.87 108.93,46.87 109.03,46.97 109.03,47.74 109.14,47.84 109.34,47.84 109.44,47.74 109.44,46.97 109.54,46.87 109.75,46.87 109.85,46.97 109.85,47.74 109.95,47.84 110.15,47.84 110.25,47.74 110.25,46.97 110.35,46.87 110.56,46.87 110.66,46.97 110.66,47.74 110.76,47.84 111.4,47.84 111.5,47.94 111.5,48.01 111.6,48.11 111.8,48.11 111.9,48.01 111.9,47.94 112,47.84 112.21,47.84 112.31,47.94 112.31,48.01 112.41,48.11 112.61,48.11 112.72,48.01 112.72,47.94 112.82,47.84 114.31,47.84 118.2,51.72 123.14,51.72 v2(123.16,51.75)
  BOTTOM w0.114: v2(84.45,48.11) 84.48,48.11 84.49,48.1 84.51,48.1 CPU1.AK64 ; v2(123.16,51.75) DIMM1.59
M_A_DQ20: length 56.3
  TOP w0.114: v2(123.16,54.15) 122.63,54.15 v1(122.46,54.32)
  L6 w0.102: v2(82.59,46.76) 82.16,47.19 82.16,48.41 82.51,48.76 82.51,48.9 82.3,49.11 82.3,49.26 82.45,49.4 82.59,49.4 82.8,49.19 82.94,49.19 83.09,49.34 83.09,49.48 82.88,49.69 82.88,49.83 83.02,49.97 83.17,49.97 83.37,49.77 83.52,49.77 83.66,49.91 83.66,50.05 83.45,50.26 83.45,50.41 83.6,50.55 83.74,50.55 83.95,50.34 84.09,50.34 84.71,50.96 85.08,50.96 85.18,51.06 85.18,51.4 85.28,51.5 85.49,51.5 85.59,51.4 85.59,51.06 85.69,50.96 90.03,50.96 90.44,50.55 91.04,50.55 91.14,50.65 91.14,51.09 91.24,51.19 91.45,51.19 91.55,51.09 91.55,50.65 91.65,50.55 91.85,50.55 91.95,50.65 91.95,51.09 92.05,51.19 92.26,51.19 92.36,51.09 92.36,50.65 92.46,50.55 93.45,50.55 94.98,49.03 94.98,48.29 95.53,47.73 96.81,47.73 96.96,47.89 100.22,47.89 100.74,48.41 104.28,48.41 105.71,49.83 108.52,49.83 110.05,51.36 114.82,51.36 117.47,54.01 122.72,54.01 122.87,54.15 v2(123.16,54.15)
  BOTTOM w0.114: v2(82.59,46.76) 82.92,46.44 CPU1.AF66 ; v2(123.16,54.15) 121.7,54.15 DIMM1.67
M_A_DQ21: length 56.3
  TOP w0.114: v2(124.43,54.15) 124.44,54.15 v1(125,54.15)
  L6 w0.102: v2(82.59,46.11) 81.79,46.91 81.79,49.26 84.4,51.87 86.15,51.87 86.47,51.56 92.97,51.56 95.38,49.14 95.38,48.4 95.69,48.1 96.65,48.1 96.81,48.25 100.07,48.25 100.59,48.77 104.13,48.77 105.55,50.2 108.37,50.2 109.9,51.73 114.67,51.73 117.32,54.37 122.57,54.37 122.78,54.58 124,54.58 v2(124.43,54.15)
  BOTTOM w0.114: v2(124.43,54.15) 124.43,54.23 123.91,54.75 DIMM1.69 ; CPU1.AF67 82.92,45.79 v2(82.59,46.11)
M_A_DQ22: length 54.6
  TOP w0.114: v1(126.7,51.43) 127.17,50.96 v2(127.17,50.85)
  L6 w0.102: v2(84.42,46.11) 85.02,46.11 85.27,46.36 89.7,46.36 89.81,46.26 89.81,46.09 89.91,45.99 90.11,45.99 90.21,46.09 90.21,46.26 90.31,46.36 92.08,46.36 95.03,43.41 100.18,43.41 102.01,45.25 105.52,45.25 106.04,45.77 113.93,45.77 118.58,50.42 125.5,50.42 125.6,50.32 125.6,49.23 125.7,49.13 125.9,49.13 126.01,49.23 126.01,50.32 126.11,50.42 127.01,50.42 127.17,50.58 v2(127.17,50.85)
  BOTTOM w0.114: v2(127.17,50.85) 127.17,50.92 127.7,51.45 DIMM1.58 ; v2(84.42,46.11) 84.46,46.07 84.46,46.07 84.74,45.79 CPU1.AK67
M_A_DQ23: length 55.1
  TOP w0.114: v2(128.44,50.85) 128.44,51.29 v1(128.58,51.43)
  L6 w0.102: v2(84.42,46.76) 85.75,46.76 86.28,47.3 89.97,47.3 90.33,46.93 92.03,46.93 95.18,43.78 100.02,43.78 101.86,45.62 105.37,45.62 105.88,46.14 113.77,46.14 118.53,50.89 124.67,50.89 125.06,51.28 127.8,51.28 128.2,51.69 128.98,51.69 129.19,51.48 129.19,50.26 129.09,50.16 128.54,50.16 128.44,50.26 v2(128.44,50.85)
  BOTTOM w0.114: v2(84.42,46.76) 84.55,46.76 CPU1.AK66 ; DIMM1.56 v2(128.44,50.85)
M_A_DQ24: length 71.2
  TOP w0.114: v1(82.58,42.36) 82.31,42.09 v2(82.08,42.09)
  L6 w0.102: v2(125.07,36.75) 124.11,35.79 122.98,35.79 120.11,32.93 120.11,32.78 120.53,32.37 120.53,32.22 120.38,32.08 120.24,32.08 119.82,32.49 119.68,32.49 119.42,32.23 119.42,32.09 119.92,31.59 119.92,31.45 119.77,31.3 119.63,31.3 119.13,31.8 118.99,31.8 118.84,31.66 118.84,31.52 119.34,31.02 119.34,30.87 119.2,30.73 119.05,30.73 118.56,31.23 118.41,31.23 114.21,27.02 104.86,27.02 104.59,26.75 87.81,26.75 81.22,33.35 81.22,41.25 81.85,41.88 81.86,41.88 v2(82.08,42.09)
  BOTTOM w0.114: DIMM1.5 123.87,35.55 v2(125.07,36.75) ; v2(82.08,42.09) 81.74,42.42 81.74,42.93 82.03,43.21 82.24,43.21 82.74,43.71 CPU1.AF70
M_A_DQ25: length 73.1
  TOP w0.114: v1(123.35,37.31) 123.8,36.86 v2(123.8,36.75)
  L6 w0.102: v2(81.99,41.45) 81.59,41.04 81.59,33.5 83.91,31.18 84.05,31.18 84.35,31.47 84.51,31.47 84.63,31.34 84.63,31.18 84.34,30.89 84.34,30.74 84.49,30.6 84.63,30.6 84.92,30.89 85.08,30.89 85.21,30.76 85.21,30.6 84.92,30.31 84.92,30.17 85.06,30.03 85.2,30.03 85.5,30.32 85.66,30.32 85.79,30.19 85.79,30.03 85.49,29.74 85.49,29.59 87.27,27.81 87.42,27.81 87.71,28.11 87.87,28.11 88,27.98 88,27.82 87.7,27.53 87.7,27.38 87.97,27.12 100.33,27.12 100.45,27.23 100.45,27.83 100.56,27.95 100.74,27.95 100.85,27.83 100.85,27.23 100.97,27.12 104.44,27.12 105.31,28 108.2,28 108.64,27.55 112.24,27.55 112.34,27.65 112.34,28.44 112.44,28.54 112.64,28.54 112.74,28.44 112.74,27.65 112.85,27.55 113.21,27.55 113.44,27.78 113.44,29.51 113.85,29.92 116.43,29.92 122.83,36.32 123.34,36.32 123.77,36.75 v2(123.8,36.75)
  BOTTOM w0.089: v2(81.99,41.45) 81.97,41.47 81.97,41.54 81.55,41.96 81.55,43 81.63,43.09 81.63,43.76 82,44.12 82.27,44.12 82.5,44.35 82.5,44.63 82.54,44.68 CPU1.AF68
  BOTTOM w0.114: v2(123.8,36.75) 123.2,36.15 DIMM1.7
M_A_DQ26: length 70.6
  TOP w0.114: v2(127.17,39.45) 127.17,39.32 v1(126.8,38.96)
  L6 w0.102: v2(127.17,39.45) 127.17,39.7 126.99,39.88 126.25,39.88 126.1,39.73 126.1,39.47 125.98,39.35 121.85,39.35 115.87,33.37 112.21,33.37 110.51,31.67 97.85,31.67 97.67,31.48 94.77,31.48 94.67,31.38 94.67,30.56 94.57,30.46 94.37,30.46 94.26,30.56 94.26,31.38 94.16,31.48 93.96,31.48 93.86,31.38 93.86,30.56 93.76,30.46 93.55,30.46 93.45,30.56 93.45,31.38 93.35,31.48 93.15,31.48 93.04,31.38 93.04,30.56 92.94,30.46 92.74,30.46 92.64,30.56 92.64,31.38 92.54,31.48 92.33,31.48 92.23,31.38 92.23,30.56 92.13,30.46 91.93,30.46 91.83,30.56 91.83,31.38 91.72,31.48 91.51,31.48 91.4,31.36 91.4,30.6 91.26,30.46 89.11,30.46 87.84,31.73 87.84,33.78 87.47,34.15 85.42,34.15 84.16,35.41 84.16,38.04 84.42,38.3 84.42,40.5 84.27,40.65 v2(84.01,40.65)
  BOTTOM w0.089: CPU1.AH71 84,43.12 84,42.6 83.53,42.14 83.53,41.12 v2(84.01,40.65)
  BOTTOM w0.114: DIMM1.16 127.67,38.85 127.17,39.35 v2(127.17,39.45)
M_A_DQ27: length 72.5
  TOP w0.114: v2(124.43,38.55) 124.43,38.41 v1(124.8,38.04)
  L6 w0.102: v2(124.43,38.55) 123.93,38.05 122.66,38.05 119.21,34.6 119.07,34.6 118.94,34.73 118.79,34.73 118.65,34.59 118.65,34.44 118.78,34.31 118.78,34.17 116.61,32 112.69,32 109.94,29.25 108.64,29.25 108.54,29.36 108.54,29.75 108.44,29.86 108.23,29.86 108.13,29.75 108.13,29.36 108.03,29.25 102.99,29.25 102.89,29.36 102.89,29.92 102.77,30.04 102.59,30.04 102.48,29.92 102.48,29.36 102.38,29.25 101.78,29.25 101.67,29.37 101.67,30.42 101.56,30.53 101.38,30.53 101.26,30.42 101.26,29.37 101.15,29.25 97.06,29.25 96.94,29.14 96.94,28.65 96.83,28.54 96.65,28.54 96.54,28.65 96.54,29.14 96.42,29.25 95.44,29.25 95.34,29.15 95.34,28.63 95.22,28.52 95.04,28.52 94.93,28.63 94.93,29.15 94.83,29.25 94.62,29.25 94.52,29.15 94.52,28.65 94.41,28.54 94.23,28.54 94.12,28.65 94.12,29.15 94.01,29.25 93.13,29.25 93.03,29.15 93.03,28.6 92.92,28.49 92.73,28.49 92.62,28.6 92.62,29.15 92.52,29.25 88.53,29.25 82.91,34.87 82.91,38.44 83.32,38.85 83.32,40.62 v2(83.98,41.28)
  BOTTOM w0.089: v2(83.98,41.28) 83.98,41.29 83.71,41.56 83.71,42.07 84.33,42.68 84.33,43.26 84.29,43.41 84.29,43.62 84.33,43.78 84.33,44.87 CPU1.AH68
  BOTTOM w0.114: DIMM1.17 123.83,39.15 v2(124.43,38.55)
M_A_DQ28: length 70.7
  TOP w0.114: v1(128.2,34.82) 128.44,35.06 v2(128.44,35.35)
  L6 w0.102: v2(128.44,35.35) 127.88,35.91 126.09,35.91 123.7,33.52 121.83,33.52 120.96,32.66 120.96,31.72 120.47,31.22 120.47,31.08 120.81,30.74 120.81,30.6 120.59,30.38 120.45,30.38 120.11,30.72 119.96,30.72 119.75,30.51 119.75,30.36 120.09,30.02 120.09,29.88 119.87,29.66 119.73,29.66 119.39,30 119.25,30 119.01,29.76 117.58,29.76 114.33,26.51 105.29,26.51 104.86,26.08 87.97,26.08 80.85,33.2 80.85,41.52 82.09,42.75 v2(82.16,42.75)
  BOTTOM w0.114: v2(82.16,42.75) 82.59,43.19 CPU1.AF71 ; v2(128.44,35.35) 128.41,35.35 129.8,35.35 DIMM1.4
M_A_DQ29: length 71.9
  TOP w0.114: v2(127.17,35.35) 126.83,35.69 v1(126.83,35.81)
  L6 w0.102: v2(127.17,35.35) 126.17,35.35 123.15,32.33 123.01,32.33 122.69,32.65 122.55,32.65 122.33,32.43 122.33,32.29 122.65,31.97 122.65,31.83 122.43,31.61 122.29,31.61 121.98,31.93 121.83,31.93 121.62,31.71 121.62,31.57 121.93,31.25 121.93,31.11 120.08,29.25 117.78,29.25 114.66,26.13 105.77,26.13 105.35,25.71 87.81,25.71 80.48,33.04 80.48,41.76 82.14,43.42 v2(82.14,43.7)
  BOTTOM w0.114: v2(82.14,43.7) 82.84,44.4 CPU1.AF69 ; v2(127.17,35.35) 127.17,35.45 127.67,35.95 129.8,35.95 DIMM1.6
M_A_DQ30: length 71.1
  TOP w0.114: v1(122.6,38.55) 122.69,38.55 v2(123.16,38.55)
  L6 w0.102: v2(123.16,38.55) 122.09,38.55 119.37,35.83 119.37,35.69 119.4,35.66 119.4,35.52 119.26,35.37 119.11,35.37 119.09,35.4 118.94,35.4 118.01,34.47 118.01,34.33 118.14,34.2 118.14,34.05 118,33.91 117.86,33.91 117.73,34.04 117.58,34.04 117.44,33.9 117.44,33.75 117.57,33.62 117.57,33.48 117.43,33.34 117.28,33.34 117.15,33.47 117.01,33.47 116.86,33.32 116.86,33.18 116.99,33.05 116.99,32.9 116.85,32.76 116.71,32.76 116.58,32.89 116.43,32.89 116.17,32.63 112.51,32.63 110.37,30.49 110.08,30.49 109.64,30.93 107.64,30.93 107.54,30.83 107.54,29.74 107.44,29.64 107.13,29.64 107.03,29.74 107.03,30.83 106.93,30.93 106.62,30.93 106.52,30.83 106.52,29.71 106.43,29.62 106.1,29.62 106.01,29.71 106.01,30.83 105.91,30.93 100.98,30.93 100.86,30.82 100.86,29.84 100.75,29.73 99.98,29.73 99.88,29.83 99.88,30.82 99.77,30.93 99.59,30.93 99.48,30.82 99.48,29.83 99.37,29.73 99.17,29.73 99.07,29.83 99.07,30.77 98.95,30.88 98.78,30.88 98.66,30.77 98.66,29.83 98.56,29.73 97.75,29.73 97.65,29.83 97.65,30.59 97.54,30.7 97.36,30.7 97.25,30.59 97.25,29.83 97.15,29.73 88.58,29.73 83.28,35.02 83.28,38.41 83.57,38.7 83.57,39.86 83.72,40.01 v2(84,40.01)
  BOTTOM w0.089: CPU1.AH70 83.86,43.63 83.86,43.46 83.8,43.24 83.8,42.72 83.29,42.22 83.29,40.72 v2(84,40.01)
  BOTTOM w0.114: DIMM1.15 v2(123.16,38.55)
M_A_DQ31: length 72.4
  TOP w0.114: v1(128.58,38.88) 128.44,39.02 v2(128.44,39.45)
  L6 w0.102: v2(128.44,39.45) 127.97,38.98 122,38.98 116.02,33 112.36,33 110.66,31.3 98.01,31.3 97.82,31.11 96.89,31.11 96.78,31 96.78,30.21 96.66,30.09 96.46,30.09 96.36,30.2 96.36,31.01 96.26,31.11 96.05,31.11 95.95,31.01 95.95,30.2 95.85,30.09 95.65,30.09 95.55,30.2 95.55,31.01 95.44,31.11 95.24,31.11 95.14,31.01 95.14,30.2 95.04,30.09 88.73,30.09 87.04,31.78 87.04,31.93 87.47,32.36 87.47,32.52 87.35,32.64 87.18,32.64 86.75,32.21 86.61,32.21 86.47,32.36 86.47,32.5 87.31,33.34 87.31,33.5 87.18,33.63 87.02,33.63 86.18,32.79 86.04,32.79 85.89,32.93 85.89,33.08 86.3,33.49 86.3,33.65 86.18,33.77 86.01,33.77 85.6,33.36 85.46,33.36 84.05,34.77 83.65,35.18 83.65,38.18 83.98,38.51 v2(83.98,39.38)
  BOTTOM w0.089: 83.09,40.35 83.09,42.26 83.62,42.8 83.62,43.26 83.67,43.45 83.67,44.09 CPU1.AH69
  BOTTOM w0.114: DIMM1.18 v2(128.44,39.45) ; 83.09,40.35 83.09,40.27 v2(83.98,39.38)
M_A_DQ32: length 63.6
  TOP w0.114: v1(122.84,74.64) 122.84,74.83 v2(123.16,75.15)
  L3 w0.102: v2(98.05,42.51) 98.51,42.06 98.75,42.06 99.68,41.13 101.27,41.13 108.64,48.5 108.64,50.04 112.91,54.31 112.91,55.56 117.04,59.68 117.04,62.67 117.14,62.77 117.89,62.77 117.99,62.87 117.99,63.08 117.89,63.18 117.14,63.18 117.04,63.28 117.04,63.48 117.14,63.58 117.89,63.58 117.99,63.69 117.99,63.89 117.89,63.99 117.14,63.99 117.04,64.09 117.04,64.3 117.14,64.4 117.91,64.4 118.02,64.5 118.02,64.7 117.91,64.8 117.14,64.8 117.04,64.91 117.04,65.27 118.3,66.54 118.3,72.6 120.86,75.15 v2(123.16,75.15)
  BOTTOM w0.089: 95.16,43.78 94.39,44.54 94.39,45.43 93.12,46.7 92.54,46.7 92.3,46.94 CPU1.BB65
  BOTTOM w0.114: v2(98.05,42.51) 96.96,43.6 95.34,43.6 95.16,43.78 ; DIMM1.129 v2(123.16,75.15)
M_A_DQ33: length 65.6
  TOP w0.114: v1(124.69,75.65) 124.43,75.39 v2(124.43,75.15)
  L3 w0.102: v2(97.39,42.46) 97.49,42.46 98.27,41.69 98.6,41.69 99.53,40.76 101.42,40.76 109.01,48.35 109.01,49.89 113.28,54.16 113.28,55.4 117.41,59.53 117.41,61.72 118.67,62.98 118.67,65.11 118.56,65.22 117.96,65.22 117.86,65.32 117.86,65.53 117.96,65.63 118.56,65.63 118.67,65.74 118.67,72.44 120.95,74.72 124,74.72 v2(124.43,75.15)
  BOTTOM w0.089: 94.77,43.02 93.75,44.05 93.75,44.87 92.58,46.04 92.08,46.04 92,46.02 91.81,46.02 91.65,46.06 91.56,46.23 91.56,46.3 91.53,46.4 91.42,46.51 91.3,46.55 91.16,46.59 90.75,46.59 90.4,46.94 CPU1.AW65
  BOTTOM w0.114: v2(97.39,42.46) 96.93,42 95.28,42 94.9,42.39 94.9,42.89 94.77,43.02 ; DIMM1.131 123.83,75.75 v2(124.43,75.15)
M_A_DQ34: length 66.5
  TOP w0.114: v1(125.98,77.82) 126.01,77.82 126.02,77.82 126.5,77.82 v2(126.53,77.85)
  L3 w0.102: v2(96.7,44.99) 96.84,44.99 98.38,43.45 101.19,43.45 107.39,49.65 107.39,50.56 111.65,54.83 111.65,56.08 115.78,60.21 115.78,65.79 117.05,67.06 117.05,73.12 121.78,77.85 123.12,77.85 123.22,77.75 123.22,77.5 123.34,77.38 123.51,77.38 123.63,77.5 123.63,77.75 123.73,77.85 123.93,77.85 124.04,77.75 124.04,77.47 124.15,77.35 124.33,77.35 124.44,77.47 124.44,77.75 124.54,77.85 v2(126.53,77.85)
  BOTTOM w0.089: CPU1.AW63 90.52,47.98 90.78,47.83 90.99,47.83 91.09,47.87 91.97,47.87 92.11,47.83 92.45,47.83 92.63,48.01 93.19,48.01 96.2,44.99 v2(96.7,44.99)
  BOTTOM w0.114: DIMM1.142 127.73,79.05 v2(126.53,77.85)
M_A_DQ35: length 64.9
  L3 w0.102: v2(123.16,79.35) 121.72,79.35 115.68,73.32 115.68,72.92 115.5,72.74 115.11,72.74 114.64,72.27 114.64,71.9 114.74,71.8 115.7,71.8 115.81,71.7 115.81,71.5 115.7,71.39 114.74,71.39 114.64,71.29 114.64,71.09 114.74,70.99 115.75,70.99 115.86,70.89 115.86,70.68 115.75,70.58 114.74,70.58 114.64,70.48 114.64,70.28 114.74,70.17 115.75,70.17 115.86,70.07 115.86,69.87 115.75,69.77 114.74,69.77 114.64,69.67 114.64,60.62 110.45,56.43 110.45,55.19 106.23,50.97 106.23,50.06 100.73,44.56 99.19,44.56 v2(98.76,44.99)
  BOTTOM w0.089: CPU1.AY63 91.46,48.57 93.38,48.57 95.9,46.04 v1(96.15,46.04) 96.15,46.04 98.08,46.04
  BOTTOM w0.114: DIMM1.143 v2(123.16,79.35) ; v2(98.76,44.99) 98.76,45.36 98.08,46.04
M_A_DQ36: length 64.7
  TOP w0.114: v1(126.42,76.6) 126.62,76.6 v2(127.17,76.05)
  L3 w0.102: v2(96.73,42.46) 97.16,42.03 97.4,42.03 98.11,41.32 98.45,41.32 99.38,40.39 101.57,40.39 109.53,48.35 109.53,49.89 113.7,54.06 113.7,55.31 117.78,59.38 117.78,61.57 119.04,62.83 119.04,69.44 121.13,71.52 121.13,72.17 123.02,74.06 125.18,74.06 v2(127.17,76.05)
  BOTTOM w0.089: 94.84,43.59 94.11,44.32 94.11,45.21 92.87,46.45 92.47,46.45 92.23,46.68 92.13,46.68 91.87,46.75 CPU1.BA65
  BOTTOM w0.114: v2(127.17,76.05) 127.29,75.93 127.29,75.93 127.77,75.45 DIMM1.130 ; v2(96.73,42.46) 95.92,43.27 95.16,43.27 94.84,43.59
M_A_DQ37: length 65
  TOP w0.114: v2(128.44,76.05) 128.44,76.79 v1(128.53,76.88)
  L3 w0.102: v2(96.07,42.49) 96.89,41.66 97.25,41.66 97.96,40.95 98.29,40.95 99.22,40.02 101.73,40.02 109.9,48.19 109.9,49.74 114.07,53.91 114.07,55.15 118.14,59.23 118.14,61.41 119.42,62.69 119.42,67.92 121.83,70.33 121.83,71.85 123.1,73.12 125.53,73.12 128.44,76.03 v2(128.44,76.05)
  BOTTOM w0.089: v2(96.07,42.49) 96.07,42.54 95.65,42.96 95.17,42.96 93.93,44.19 93.93,45.01 92.69,46.24 92.37,46.24 92.11,46.5 91.8,46.58 91.68,46.63 91.3,46.73 91.06,46.94 CPU1.AY65
  BOTTOM w0.114: DIMM1.132 v2(128.44,76.05)
M_A_DQ38: length 65
  TOP w0.114: v1(127.39,77.33) 127.8,77.74 v2(127.8,77.85)
  L3 w0.102: v2(97.44,45) 98.62,43.82 101.04,43.82 107.02,49.8 107.02,50.72 111.18,54.88 111.18,56.13 115.41,60.36 115.41,65.95 116.68,67.21 116.68,67.62 116.58,67.72 116.16,67.72 116.06,67.82 116.06,68.02 116.15,68.12 116.31,68.12 116.32,68.12 116.58,68.12 116.68,68.23 116.68,73.27 121.69,78.28 127.38,78.28 127.81,77.85 v2(127.8,77.85)
  BOTTOM w0.089: v2(97.44,45) 97.11,45.33 96.93,45.33 96.83,45.43 96.01,45.43 93.26,48.18 92.56,48.18 92.38,48.01 92.13,48.01 91.87,48.07 CPU1.BA63
  BOTTOM w0.114: DIMM1.140 128.04,78.45 127.8,78.21 v2(127.8,77.85)
M_A_DQ39: length 64
  TOP w0.114: v1(124.73,79.82) 124.43,79.52 v2(124.43,79.35)
  L3 w0.102: v2(124.43,79.35) 123.79,78.71 121.6,78.71 116.26,73.37 116.26,69.4 116.16,69.3 115.14,69.3 115.03,69.18 115.03,69.01 115.14,68.89 116.16,68.89 116.26,68.79 116.26,68.59 116.16,68.49 115.16,68.49 115.05,68.37 115.05,68 115.15,67.9 115.5,67.9 115.6,67.8 115.6,67.6 115.5,67.49 115.15,67.49 115.05,67.39 115.05,60.51 110.81,56.28 110.81,55.03 106.6,50.82 106.6,49.9 100.88,44.19 98.95,44.19 98.33,44.81 98.33,44.82 v2(98.13,45.03)
  BOTTOM w0.089: 97.65,45.62 97.57,45.69 96.01,45.69 93.3,48.39 92.34,48.39 CPU1.BB63
  BOTTOM w0.114: v2(98.13,45.03) 98.13,45.14 97.65,45.62 ; v2(124.43,79.35) 124.43,79.28 123.91,78.75 DIMM1.141
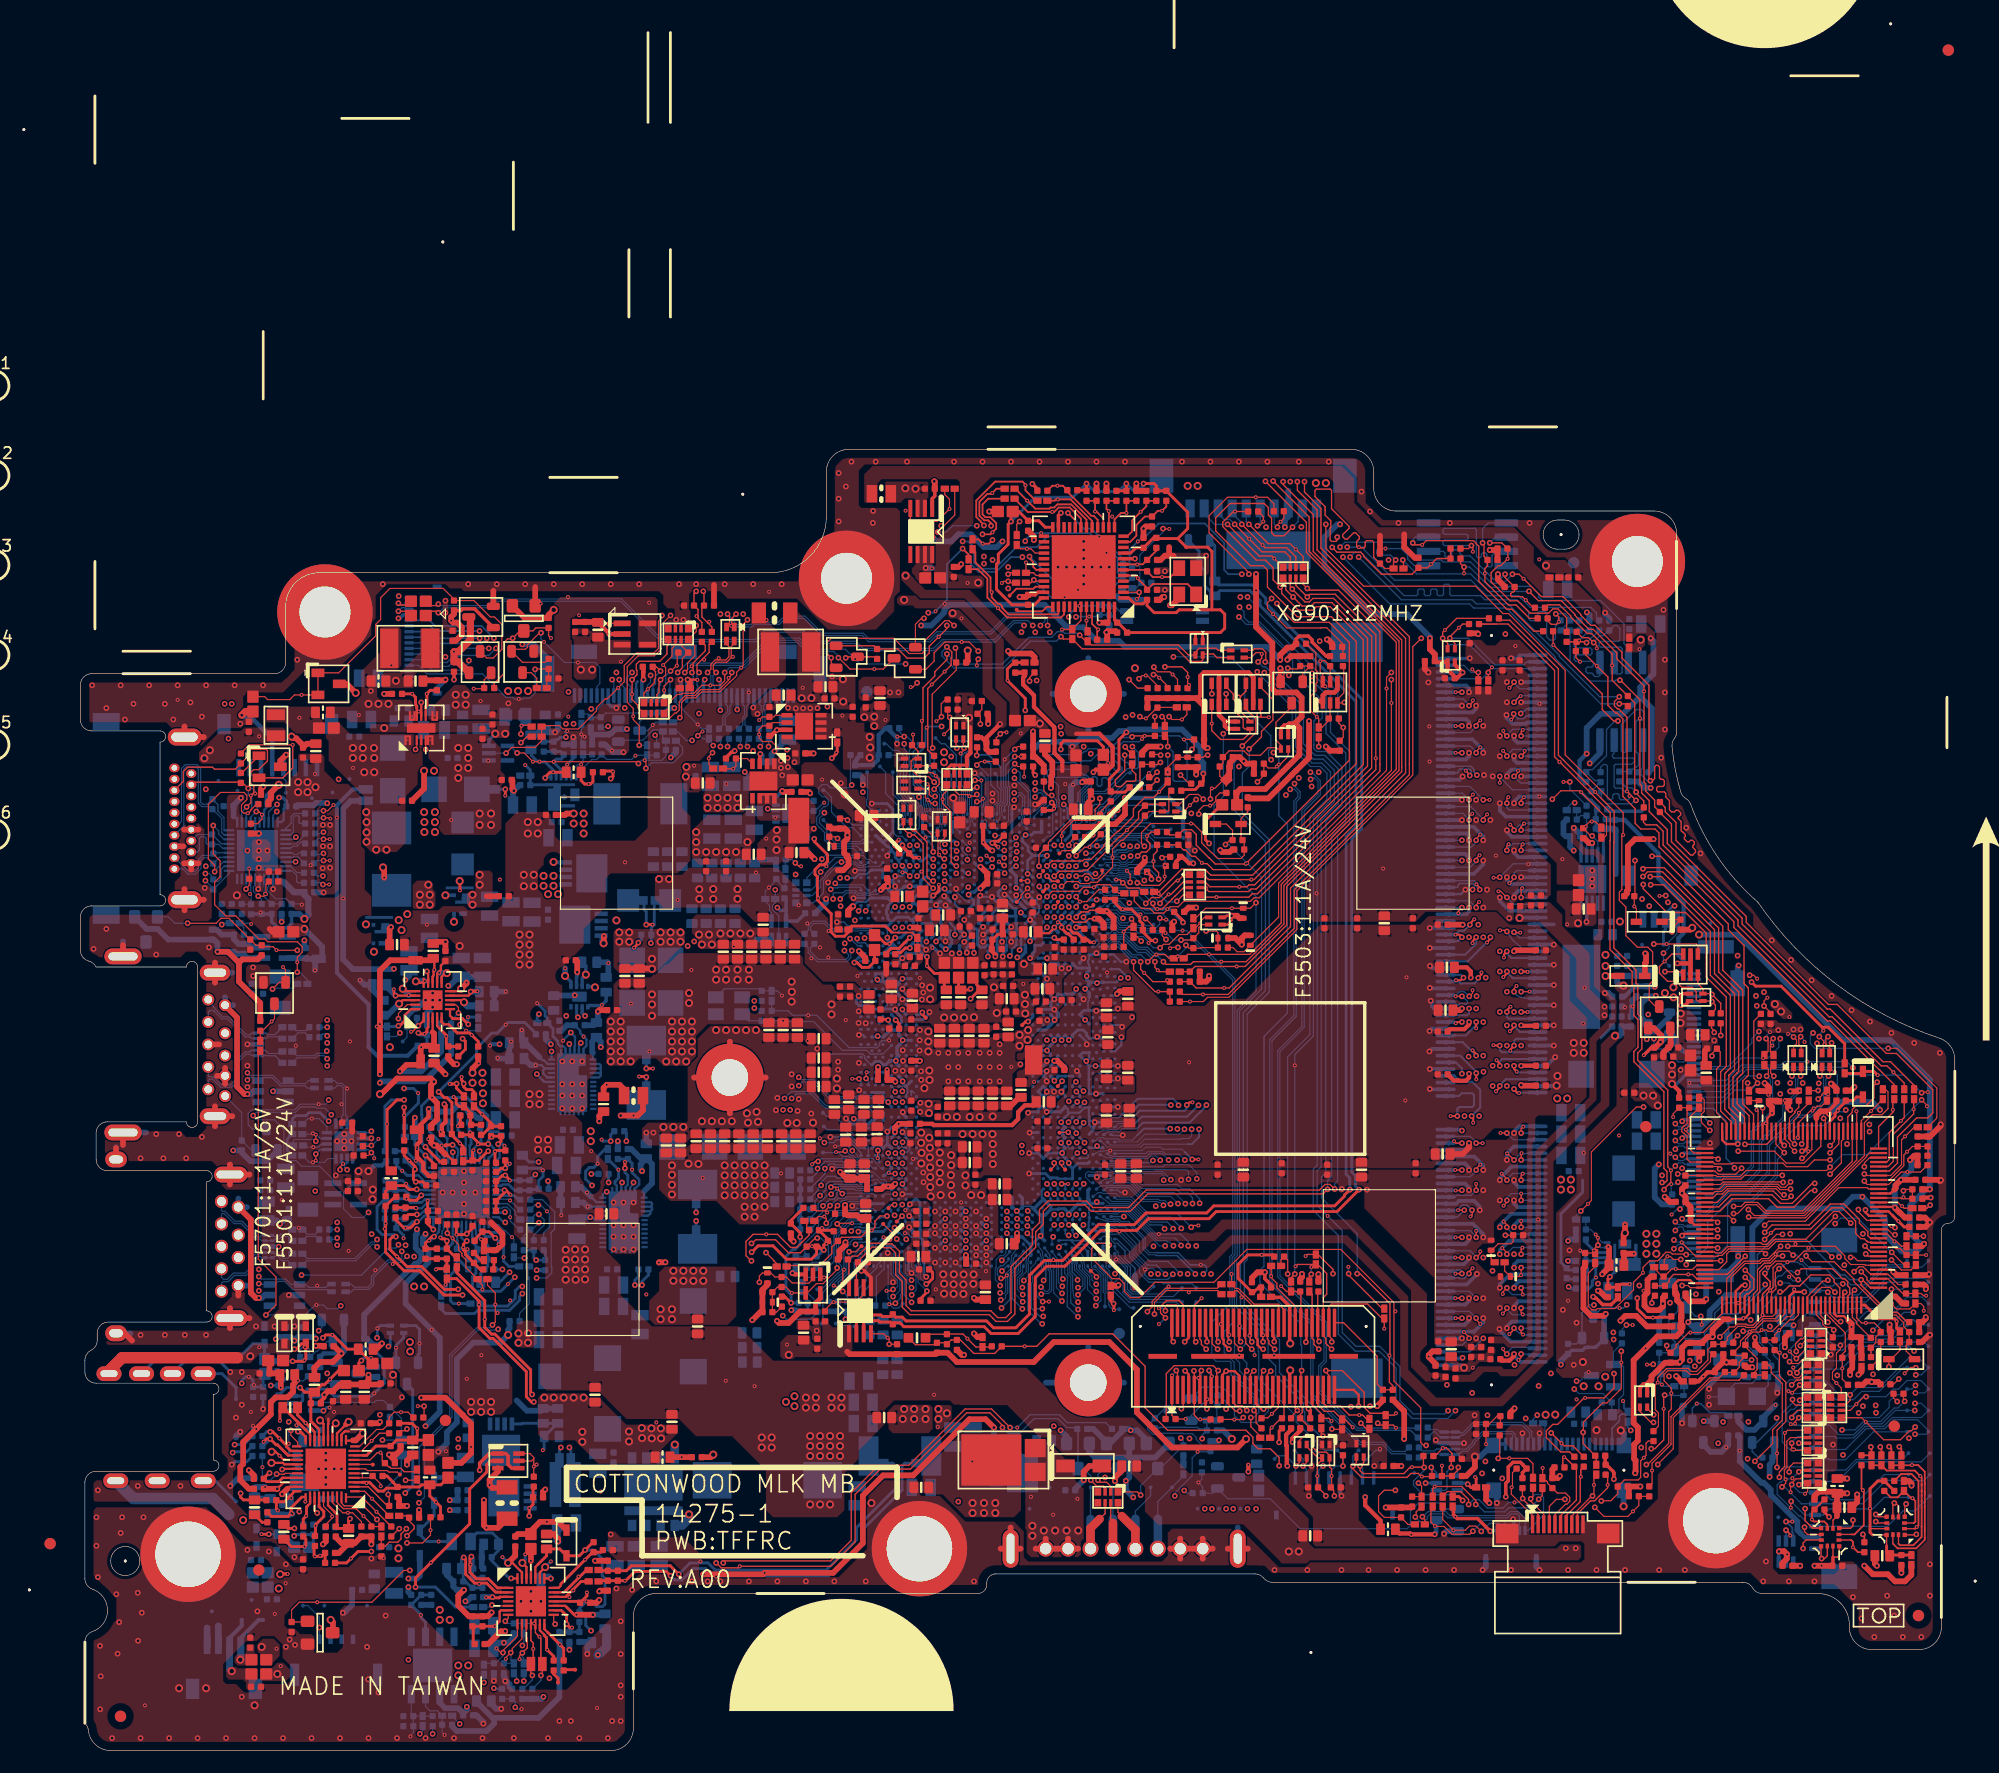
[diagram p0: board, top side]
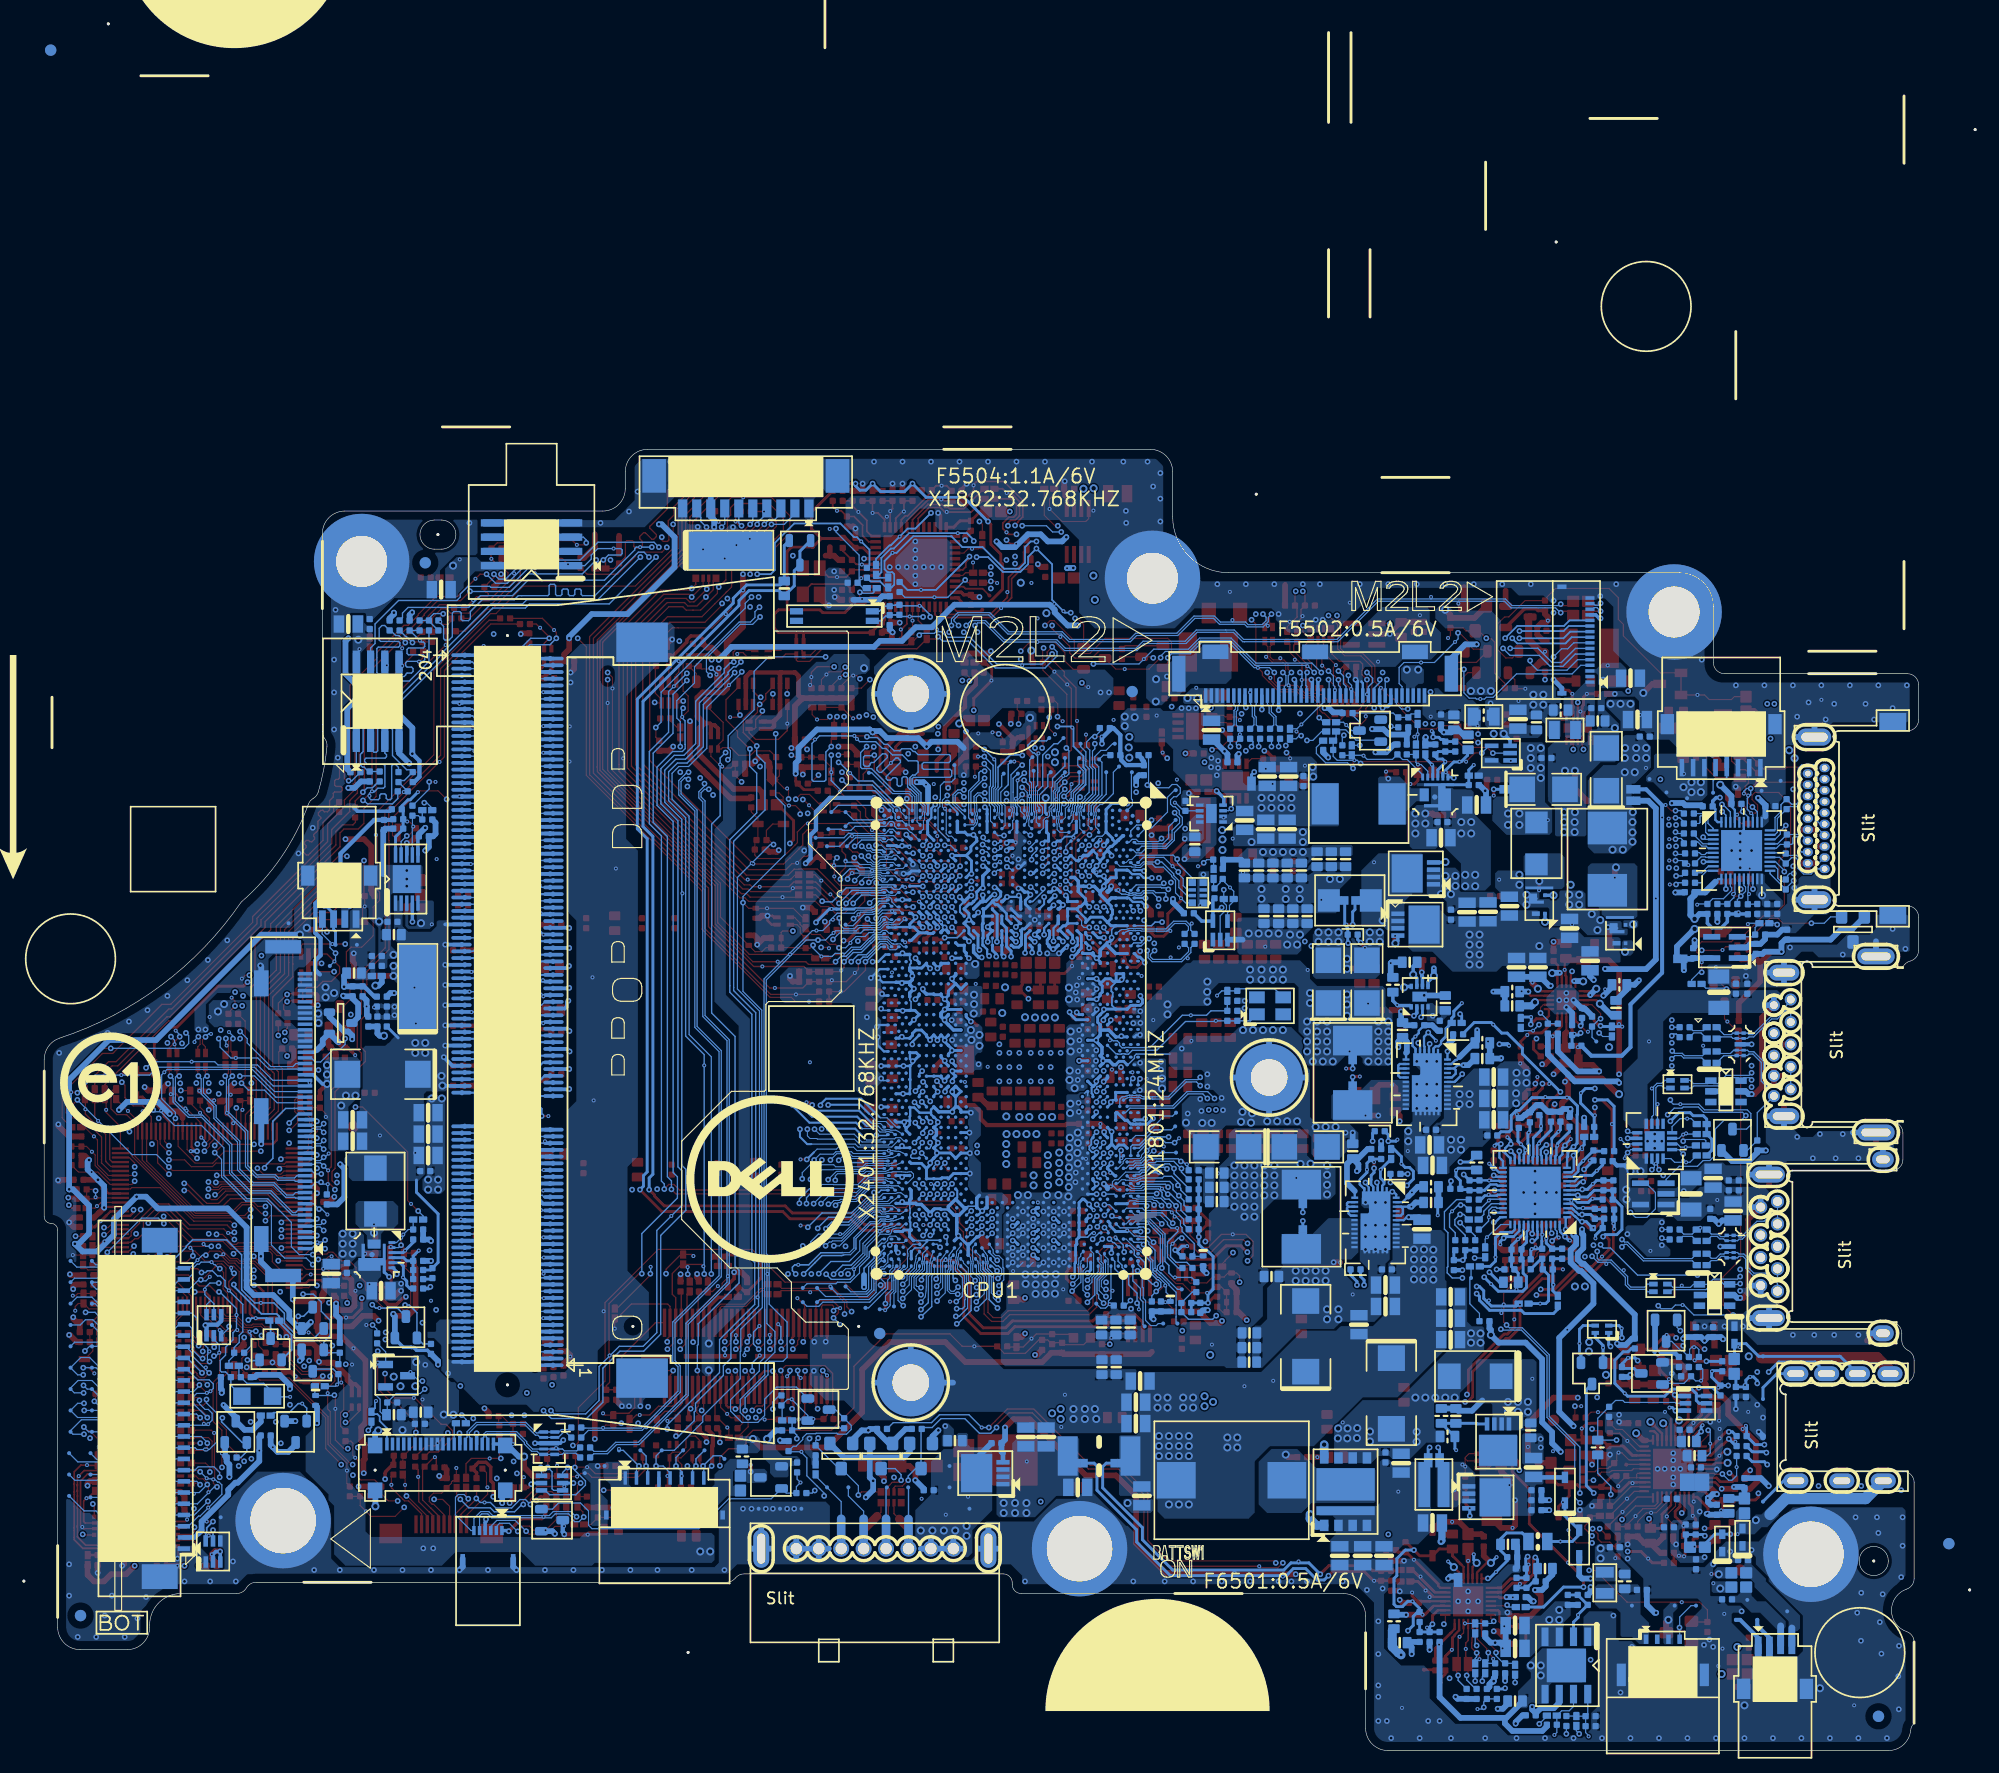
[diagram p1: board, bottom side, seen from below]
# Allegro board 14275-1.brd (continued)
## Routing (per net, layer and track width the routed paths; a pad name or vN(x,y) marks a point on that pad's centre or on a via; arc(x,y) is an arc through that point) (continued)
M_A_DQ40: length 63.7
  TOP w0.114: v1(124.8,81.65) 124.43,81.29 v2(124.43,81.15)
  L3 w0.102: v2(124.43,81.15) 123.96,80.68 121.07,80.68 113.23,72.84 113.23,61.14 112.92,60.84 112.78,60.84 112.3,61.32 112.16,61.32 112.01,61.18 112.01,61.03 112.49,60.55 112.49,60.41 112.23,60.15 112.09,60.15 111.82,60.42 111.68,60.42 111.53,60.27 111.53,60.13 111.8,59.86 111.8,59.72 109,56.91 109,55.67 107.19,53.86 104.8,51.47 104.8,50.58 100.44,46.22 98.85,46.22 98.6,46.47 98.6,46.82 98.43,46.98 97.64,46.98 97.42,46.75 v2(97.42,46.53)
  BOTTOM w0.089: 95.21,47.29 95.17,47.29 93.51,48.95 91.91,48.95 CPU1.BA61
  BOTTOM w0.114: DIMM1.147 124,80.55 124.43,80.98 v2(124.43,81.15) ; 95.21,47.29 95.38,47.11 96.91,47.11 97.42,46.6 v2(97.42,46.53)
M_A_DQ41: length 65.7
  TOP w0.114: v1(99.67,46.81) 99.18,46.81 v2(99.03,46.65)
  L3 w0.102: v2(99.03,46.65) 100.35,46.65 104.43,50.73 104.43,51.62 107.04,54.23 108.62,55.81 108.62,57.3 109.24,57.92 109.24,58.07 108.75,58.56 108.75,58.71 108.89,58.85 109.04,58.85 109.53,58.35 109.68,58.35 109.82,58.5 109.82,58.64 109.32,59.14 109.32,59.28 109.47,59.43 109.61,59.43 110.11,58.93 110.25,58.93 110.39,59.07 110.39,59.22 109.9,59.71 109.9,59.86 110.16,60.12 110.3,60.12 110.92,59.5 111.06,59.5 111.21,59.65 111.21,59.79 110.59,60.41 110.59,60.55 110.73,60.69 110.88,60.69 111.07,60.5 111.23,60.5 111.36,60.62 111.36,60.79 111.16,60.98 111.16,61.13 112.04,62.01 112.19,62.01 112.36,61.84 112.5,61.84 112.64,61.98 112.64,62.13 112.48,62.29 112.48,62.44 112.86,62.82 112.86,73.03 120.98,81.15 v2(123.16,81.15)
  BOTTOM w0.089: CPU1.AW61 90.72,49.72 90.76,49.73 91.01,49.73 91.22,49.65 92.31,49.65 92.62,49.34 93.71,49.34 94.82,48.23
  BOTTOM w0.114: v2(99.03,46.65) 97.76,47.92 95.13,47.92 94.82,48.23 ; DIMM1.149 v2(123.16,81.15)
M_A_DQ42: length 63.6
  TOP w0.114: v2(123.8,82.95) 123.8,83.24 v1(124.08,83.52)
  L3 w0.102: v2(97.85,48.76) 98.28,48.32 100.25,48.32 103.14,51.22 103.14,52.11 106.57,55.54 107.37,56.34 107.37,56.95 107.26,57.05 106.32,57.05 106.22,57.16 106.22,57.36 106.32,57.46 107.26,57.46 107.37,57.56 107.37,57.76 107.26,57.87 106.55,57.87 106.43,57.98 106.43,58.16 106.55,58.27 107.26,58.27 107.37,58.37 107.37,58.59 107.23,58.73 107.23,58.97 111.6,63.34 111.6,73.55 120.56,82.51 121.07,82.51 121.17,82.61 121.17,82.91 121.27,83.01 121.47,83.01 121.57,82.91 121.57,82.61 121.68,82.51 121.88,82.51 121.98,82.61 121.98,82.91 122.08,83.01 122.29,83.01 122.39,82.91 122.39,82.61 122.49,82.51 123.69,82.51 123.8,82.61 v2(123.8,82.95)
  BOTTOM w0.089: CPU1.BB59 93.56,50.62 94.78,49.4 97.21,49.4 v2(97.85,48.76)
  BOTTOM w0.114: v2(123.8,82.95) 123.8,83.02 123.27,83.55 DIMM1.157
M_A_DQ43: length 66.4
  TOP w0.114: v1(125.41,83.46) 125.07,83.12 v2(125.07,82.95)
  L3 w0.102: v2(125.07,82.95) 125.07,83.27 124.95,83.38 120.91,83.38 111.23,73.7 111.23,63.49 105.85,58.11 105.85,56.69 105.95,56.58 106.33,56.58 106.43,56.48 106.43,56.28 106.33,56.18 105.95,56.18 105.85,56.08 105.85,55.34 102.78,52.27 102.78,51.4 100.17,48.79 v2(99.78,48.79)
  BOTTOM w0.089: 98.88,50.08 98.19,50.08 97.8,50.47 96.76,50.47 96.74,50.44 94.57,50.44 93.56,51.46 92.07,51.46 91.84,51.54 91.56,51.54 91.44,51.6 90.68,51.6 90.33,51.56 90.12,51.56 89.98,51.6 89.8,51.6 89.6,51.4 89.6,51.12 90.1,50.62 CPU1.AW59
  BOTTOM w0.114: DIMM1.159 123.95,84.15 125.07,83.03 v2(125.07,82.95) ; 98.88,50.08 99.78,49.19 v2(99.78,48.79)
M_A_DQ44: length 63
  TOP w0.114: v2(128.44,80.25) 128.44,80.65 v1(128.58,80.79)
  L3 w0.102: v2(128.44,80.25) 128.44,80.53 128.1,80.87 127.08,80.87 126.9,80.68 125.23,80.68 124.82,80.28 121.19,80.28 113.6,72.69 113.6,60.99 109.37,56.76 109.37,55.52 107.34,53.49 105.24,51.39 105.24,50.5 100.59,45.85 98.39,45.85 98.14,46.09 v2(98.14,46.55)
  BOTTOM w0.089: CPU1.BB61 92.36,49.15 93.61,49.15 94.92,47.84
  BOTTOM w0.114: DIMM1.146 v2(128.44,80.25) ; v2(98.14,46.55) 98.14,46.58 97.18,47.54 95.22,47.54 94.92,47.84
M_A_DQ45: length 64.3
  TOP w0.114: v1(127.33,80.8) 127.17,80.64 v2(127.17,80.25)
  L3 w0.102: v2(127.17,80.25) 125.35,80.25 124.99,79.89 121.35,79.89 113.96,72.5 113.96,60.84 109.73,56.61 109.73,55.36 107.5,53.13 105.61,51.24 105.61,50.34 100.96,45.7 100.75,45.48 98.23,45.48 97.95,45.76 96.86,45.76 96.65,45.97 v2(96.65,46.51)
  BOTTOM w0.089: CPU1.AY61 91.58,48.91 91.74,48.75 93.45,48.75 95.34,46.86 95.41,46.86
  BOTTOM w0.114: 95.41,46.86 96.4,46.86 96.65,46.6 v2(96.65,46.51) ; DIMM1.148 127.7,80.85 127.17,80.32 v2(127.17,80.25)
M_A_DQ46: length 64.4
  TOP w0.114: v2(128.44,84.45) 128.44,84.74 v1(128.68,84.98)
  L3 w0.102: v2(128.44,84.45) 128.44,85.38 128.33,85.49 127.51,85.49 127.08,85.06 126.47,85.06 125.61,84.2 120.69,84.2 110.5,74.01 110.5,63.8 105.11,58.41 105.11,55.64 101.12,51.66 101.12,50.79 99.92,49.59 99.03,49.59 98.51,49.07 v2(98.51,48.76)
  BOTTOM w0.089: v2(98.51,48.76) 97.51,49.76 94.68,49.76 93.55,50.88 92.12,50.88 91.99,50.83 91.89,50.73 91.67,50.73 CPU1.BA59
  BOTTOM w0.114: DIMM1.160 v2(128.44,84.45)
M_A_DQ47: length 65.5
  TOP w0.114: v1(127.29,85) 127.17,84.87 v2(127.17,84.45)
  L3 w0.102: v2(127.17,84.45) 127.17,83.93 127.03,83.79 120.8,83.79 110.86,73.85 110.86,63.65 105.48,58.26 105.48,55.49 102.18,52.2 102.18,52.05 102.34,51.9 102.34,51.75 102.2,51.61 102.05,51.61 101.9,51.77 101.75,51.77 101.49,51.5 101.49,50.63 100.08,49.22 99.26,49.22 99.14,49.11 v2(99.14,48.76)
  BOTTOM w0.089: CPU1.AY59 91.32,50.93 91.41,50.97 91.81,50.97 92.09,51.06 93.62,51.06 94.57,50.11 97.65,50.11 98.05,49.71 98.71,49.71
  BOTTOM w0.114: v2(99.14,48.76) 99.14,49.28 98.71,49.71 ; v2(127.17,84.45) 127.17,84.06 127.38,83.85 DIMM1.158
M_A_DQ48: length 69.3
  TOP w0.114: v2(126.53,86.85) v1(126.53,86.28)
  L3 w0.102: v2(88.75,45.92) 89.06,45.61 90.86,45.61 92.41,47.16 93.19,47.16 93.64,47.61 93.64,48.39 94.3,49.05 94.3,49.7 94.93,50.33 94.93,51.2 95.87,52.14 99.17,52.14 103.37,56.34 103.37,59.12 108.75,64.51 108.75,74.77 120.27,86.29 126.38,86.29 126.53,86.44 v2(126.53,86.85)
  BOTTOM w0.114: v2(126.53,86.85) 126.53,86.78 127.66,85.65 DIMM1.164 ; CPU1.AT66 88.45,46.22 v2(88.75,45.92)
M_A_DQ49: length 68.6
  TOP w0.114: v2(127.17,88.65) 127.17,88.79 v1(126.83,89.12)
  L3 w0.102: v2(127.17,88.65) 126.67,88.15 120.36,88.15 107.49,75.29 107.49,66.09 104.32,62.92 104.32,61.85 104.31,61.85 102.09,59.62 102.09,56.85 100.08,54.84 98.5,54.84 98.4,54.74 98.4,54.59 98.28,54.48 98.1,54.48 97.99,54.59 97.99,54.74 97.89,54.84 96.18,54.84 93.64,52.3 93.64,50.88 92.69,49.93 92.69,49.34 90.21,46.86 v2(89.42,46.86)
  BOTTOM w0.114: v2(89.42,46.86) 89.1,46.54 CPU1.AU66 ; v2(127.17,88.65) 127.17,88.72 127.7,89.25 DIMM1.176
M_A_DQ50: length 71.7
  TOP w0.114: v2(124.43,88.95) 124.43,89.08 v1(124.79,89.44)
  L3 w0.102: v2(87.47,47.78) 88.3,48.61 89.67,48.61 92.54,51.47 92.54,52.76 96.87,57.09 100.54,57.09 100.98,57.54 100.98,58.09 100.88,58.19 98.55,58.19 98.43,58.3 98.43,58.58 98.55,58.69 100.87,58.69 100.98,58.81 100.98,61.14 106.05,66.21 106.05,73.63 106.36,73.93 106.36,75.71 120.03,89.38 124,89.38 v2(124.43,88.95)
  BOTTOM w0.114: DIMM1.177 123.91,89.55 124.43,89.02 v2(124.43,88.95) ; v2(87.47,47.78) 87.15,47.45 CPU1.AP65
M_A_DQ51: length 72.4
  TOP w0.114: v2(123.8,84.75) 123.8,84.88 v1(124.14,85.23)
  L3 w0.102: v2(86.82,47.78) 86.82,47.75 86.29,47.21 86.29,45.21 87.53,43.97 87.89,43.97 88,44.07 88,44.19 88.1,44.29 88.3,44.29 88.4,44.19 88.4,44.07 88.5,43.97 88.71,43.97 88.81,44.07 88.81,44.25 88.92,44.37 89.1,44.37 89.21,44.25 89.21,44.07 89.32,43.97 89.52,43.97 89.62,44.07 89.62,44.28 89.74,44.39 89.91,44.39 90.03,44.28 90.03,44.07 90.13,43.97 91.75,43.97 95.41,47.63 95.41,49.24 96.45,50.29 99.6,50.29 100.44,51.12 100.44,51.85 104.47,55.88 104.47,58.66 109.86,64.05 109.86,74.31 120.73,85.18 123.68,85.18 123.8,85.07 v2(123.8,84.75)
  BOTTOM w0.114: v2(86.82,47.78) 86.5,47.45 CPU1.AN65 ; DIMM1.163 123.2,85.35 v2(123.8,84.75)
M_A_DQ52: length 71.3
  TOP w0.114: v1(125.62,84.75) 125.56,84.75 125.56,84.75 125.07,84.75 v2(125.07,84.75)
  L3 w0.102: v2(125.07,84.75) 125.07,85.41 124.93,85.55 120.58,85.55 109.49,74.46 109.49,64.2 104.1,58.82 104.1,56.03 99.47,51.4 96.35,51.4 95.66,50.72 95.66,50.02 95.04,49.4 95.04,47.78 91.9,44.64 91.36,44.64 91.26,44.74 91.16,44.83 88.07,44.83 87.15,45.75 87.15,46.07 86.82,46.4 v2(86.82,46.86)
  BOTTOM w0.114: v2(125.07,84.75) 123.87,85.95 DIMM1.165 ; CPU1.AN66 86.5,46.54 v2(86.82,46.86)
M_A_DQ53: length 70.7
  TOP w0.114: v2(127.8,86.85) 128.16,87.21 v1(128.16,87.34)
  L3 w0.102: v2(127.8,86.85) 127.58,86.62 127.34,86.41 126.92,86.12 126.82,86.06 126.47,85.92 120.42,85.92 109.12,74.61 109.12,64.35 103.73,58.97 103.73,56.18 99.32,51.77 96.2,51.77 95.29,50.87 95.29,50.17 94.67,49.55 94.67,48.89 94.6,48.75 94.06,47.63 93.96,47.41 93.4,46.86 91.6,45.62 91.41,45.49 91.32,45.42 91.14,45.31 91,45.26 90.86,45.23 88.91,45.23 88.65,45.28 88.3,45.36 88.18,45.4 88,45.48 87.86,45.56 87.81,45.61 87.6,45.83 87.58,45.96 v2(87.47,46.86)
  BOTTOM w0.114: DIMM1.166 128.4,86.25 v2(127.8,86.85) ; CPU1.AP66 v2(87.47,46.86)
M_A_DQ54: length 70.4
  TOP w0.114: v2(128.44,88.65) 128.75,88.96 v1(128.75,89.12)
  L3 w0.102: v2(128.44,88.65) 128.95,88.65 129.06,88.76 129.06,89.21 128.95,89.33 126.49,89.33 125.68,88.52 120.2,88.52 107.12,75.44 107.12,66.24 103.95,63.07 103.95,62.01 103.94,62 101.72,59.78 101.72,57.23 101.48,56.99 100.85,56.36 97.18,56.36 93.27,52.45 93.27,51.04 91.78,49.54 91.78,48.95 90.17,47.34 89.21,47.34 v2(88.77,47.78)
  BOTTOM w0.114: v2(128.44,88.65) DIMM1.174 ; v2(88.77,47.78) 88.45,47.45 CPU1.AT65
M_A_DQ55: length 69.5
  TOP w0.114: v2(123.16,88.95) v1(122.6,88.95)
  L3 w0.102: v2(89.44,47.77) 90.08,47.77 91.41,49.1 91.41,49.69 92.91,51.19 92.91,52.6 97.03,56.72 100.69,56.72 101.22,57.25 101.35,57.38 101.35,60.01 101.53,60.19 101.53,60.55 101.35,60.72 101.35,60.99 101.61,61.25 101.76,61.25 102.14,60.87 102.29,60.87 102.43,61.01 102.43,61.15 102.05,61.54 102.05,61.68 102.19,61.83 102.33,61.83 102.72,61.44 102.86,61.44 103.01,61.58 103.01,61.73 102.62,62.12 102.62,62.26 102.76,62.4 102.91,62.4 103.29,62.02 103.44,62.02 103.58,62.16 103.58,62.3 103.2,62.69 103.2,62.83 106.42,66.06 106.42,66.81 106.52,66.91 106.65,66.91 106.76,67.01 106.76,67.21 106.65,67.32 106.52,67.32 106.42,67.42 106.42,67.62 106.52,67.72 106.65,67.72 106.76,67.82 106.76,68.03 106.65,68.13 106.52,68.13 106.42,68.23 106.42,68.43 106.52,68.54 106.65,68.54 106.76,68.64 106.76,68.84 106.65,68.94 106.52,68.94 106.42,69.04 106.42,69.25 106.52,69.35 106.65,69.35 106.76,69.45 106.76,69.65 106.65,69.75 106.52,69.75 106.42,69.86 106.42,70.06 106.52,70.16 106.65,70.16 106.76,70.26 106.76,70.47 106.65,70.57 106.52,70.57 106.42,70.67 106.42,70.87 106.52,70.97 106.65,70.97 106.76,71.08 106.76,71.28 106.65,71.38 106.52,71.38 106.42,71.48 106.42,71.68 106.52,71.79 106.65,71.79 106.76,71.89 106.76,72.09 106.65,72.19 106.52,72.19 106.42,72.29 106.42,72.5 106.52,72.6 106.65,72.6 106.76,72.7 106.76,72.9 106.65,73.01 106.52,73.01 106.42,73.11 106.42,73.48 106.72,73.78 106.72,75.56 120.11,88.95 v2(123.16,88.95)
  BOTTOM w0.114: DIMM1.175 v2(123.16,88.95) ; CPU1.AU65 89.1,47.43 v2(89.44,47.77)
M_A_DQ56: length 72.1
  TOP w0.114: v2(124.43,91.35) 124.43,91.47 v1(124.8,91.84)
  L3 w0.102: v2(124.43,91.35) 124.43,90.94 123.88,90.39 119.55,90.39 105.38,76.22 105.38,75.23 105.27,75.13 104.91,75.13 104.81,75.02 104.81,74.66 104.91,74.56 105.06,74.56 105.16,74.45 105.16,74.25 105.06,74.15 104.91,74.15 104.81,74.05 104.81,69.97 105.05,69.73 105.05,66.66 100.53,62.14 100.39,62.14 100.11,62.42 99.95,62.42 99.82,62.29 99.82,62.13 100.1,61.86 100.1,61.71 99.96,61.57 99.81,61.57 99.55,61.83 99.39,61.83 99.26,61.71 99.26,61.55 99.53,61.28 99.53,61.14 99.26,60.88 99.12,60.88 98.8,61.2 98.65,61.2 98.51,61.06 98.51,60.91 98.83,60.59 98.83,60.45 98.69,60.3 98.55,60.3 98.22,60.63 98.08,60.63 97.93,60.48 97.93,60.34 98.26,60.01 98.26,59.87 98.11,59.73 97.97,59.73 97.65,60.05 97.5,60.05 97.36,59.91 97.36,59.76 97.68,59.44 97.68,59.3 97.54,59.15 97.4,59.15 97.07,59.48 96.93,59.48 96.67,59.21 96.67,59.07 96.99,58.75 96.99,58.6 96.85,58.46 96.7,58.46 96.38,58.78 96.24,58.78 91.8,54.35 91.8,53.41 91.45,53.06 91.45,52.57 89.94,51.07 89.94,50.42 89.61,50.08 88.6,50.08 v2(88.12,49.61)
  BOTTOM w0.114: DIMM1.181 123.91,90.75 124.43,91.28 v2(124.43,91.35) ; v2(88.12,49.61) 88.45,49.28 CPU1.AT61
M_A_DQ57: length 71.4
  TOP w0.114: v1(128.6,90.99) 128.44,90.83 v2(128.44,90.45)
  L3 w0.102: v2(88.77,49.61) 89.71,49.61 91.38,51.28 91.38,51.85 91.81,52.28 91.81,52.91 93.93,55.02 93.93,55.16 93.6,55.48 93.6,55.63 93.75,55.77 93.89,55.77 94.18,55.49 94.34,55.49 94.46,55.61 94.46,55.77 94.22,56.01 94.22,56.18 94.35,56.3 94.51,56.3 94.71,56.1 94.87,56.1 95,56.23 95,56.39 94.82,56.57 94.82,56.73 94.95,56.85 95.11,56.85 95.31,56.65 95.47,56.65 95.6,56.78 95.6,56.94 95.39,57.15 95.39,57.31 95.52,57.43 95.68,57.43 95.84,57.28 96,57.28 96.24,57.52 96.24,57.68 96.06,57.86 96.06,58.02 96.19,58.15 96.35,58.15 96.63,57.87 96.77,57.87 105.42,66.51 105.42,69.88 105.18,70.12 105.18,73.74 105.74,74.31 105.74,76.06 119.7,90.02 124.31,90.02 124.41,90.12 124.41,90.39 124.53,90.51 124.7,90.51 124.82,90.39 124.82,90.12 124.92,90.02 125.12,90.02 125.23,90.12 125.23,90.53 125.34,90.65 125.52,90.65 125.63,90.53 125.63,90.12 125.73,90.02 128.01,90.02 v2(128.44,90.45)
  BOTTOM w0.114: DIMM1.180 v2(128.44,90.45) ; CPU1.AU61 89.1,49.28 v2(88.77,49.61)
M_A_DQ58: length 74.5
  TOP w0.114: v2(123.16,94.35) v1(122.6,94.35)
  L3 w0.102: v2(86.82,50.52) 86.38,50.97 86.38,51.34 86.48,51.44 87.29,51.44 87.41,51.56 87.41,51.73 87.29,51.85 86.48,51.85 86.38,51.95 86.38,53.37 86.48,53.48 86.94,53.48 87.04,53.58 87.04,53.78 86.94,53.88 86.48,53.88 86.38,53.98 86.38,54.59 86.48,54.69 87.29,54.69 87.41,54.81 87.41,55.43 87.52,55.54 89.74,55.54 89.95,55.75 89.95,56.48 90.08,56.62 90.45,56.62 90.78,56.94 90.78,57.59 92.04,58.85 92.56,58.85 98.83,65.12 98.97,65.12 99.04,65.06 99.18,65.06 99.33,65.2 99.33,65.34 99.26,65.41 99.26,65.55 99.64,65.93 99.78,65.93 100.1,65.61 100.24,65.61 100.39,65.75 100.39,65.9 100.07,66.22 100.07,66.36 100.21,66.5 100.36,66.5 100.67,66.19 100.82,66.19 100.96,66.33 100.96,66.47 100.54,66.89 100.54,67.06 100.67,67.18 100.83,67.18 101.25,66.76 101.39,66.76 101.54,66.9 101.54,67.05 100.99,67.59 100.99,67.75 101.12,67.88 101.28,67.88 101.82,67.34 101.97,67.34 102.23,67.6 102.23,67.74 101.66,68.31 101.66,68.45 101.93,68.72 101.93,74.36 102.64,75.08 102.64,76.43 119.21,92.99 122.07,92.99 123.16,94.08 v2(123.16,94.35)
  BOTTOM w0.114: v2(86.82,50.52) 87.15,50.2 CPU1.AP60 ; DIMM1.193 v2(123.16,94.35)
M_A_DQ59: length 74.7
  TOP w0.114: v2(123.8,93.15) 124.13,93.49 v1(124.13,93.62)
  L3 w0.102: v2(123.8,93.15) 124.23,93.58 124.23,94.53 123.97,94.78 122.9,94.78 121.48,93.36 119.05,93.36 102.41,76.71 102.41,76.71 102.27,76.58 102.27,75.23 101.78,74.73 101.78,74.73 101.56,74.52 101.56,68.87 100.17,67.47 100.17,67.47 99.45,66.75 99.45,66.61 99.55,66.51 99.55,66.36 99.41,66.22 99.26,66.22 99.16,66.32 99.02,66.32 98.87,66.18 98.87,66.04 98.97,65.93 98.97,65.79 98.83,65.64 98.69,65.64 98.58,65.75 98.44,65.75 98.3,65.6 98.3,65.46 98.4,65.36 98.4,65.21 98.26,65.07 98.11,65.07 98.01,65.17 97.87,65.17 97.72,65.03 97.72,64.89 97.82,64.78 97.82,64.64 97.68,64.49 97.54,64.49 97.43,64.6 97.29,64.6 97.15,64.45 97.15,64.31 97.25,64.21 97.25,64.06 97.11,63.92 96.96,63.92 96.86,64.02 96.72,64.02 96.57,63.88 96.57,63.73 96.67,63.63 96.67,63.49 96.53,63.34 96.39,63.34 96.28,63.45 96.14,63.45 96,63.3 96,63.16 96.1,63.06 96.1,62.91 95.96,62.77 95.81,62.77 95.71,62.87 95.56,62.87 95.42,62.73 95.42,62.58 95.52,62.48 95.52,62.34 95.38,62.19 95.24,62.19 95.13,62.3 94.99,62.3 94.85,62.15 94.85,62.01 94.95,61.91 94.95,61.76 94.81,61.62 94.66,61.62 94.56,61.72 94.41,61.72 94.27,61.58 94.27,61.43 94.37,61.33 94.37,61.19 94.23,61.04 94.09,61.04 94.01,61.12 93.84,61.12 93.72,61 93.72,60.84 93.8,60.76 93.8,60.61 92.67,59.48 92.15,59.48 91.79,59.12 91.64,59.12 91.44,59.32 91.28,59.32 91.15,59.2 91.15,59.03 91.36,58.83 91.36,58.69 90.41,57.74 90.41,57.22 90.17,56.99 87.76,56.99 86.01,55.24 86.01,50.68 v2(86.17,50.52)
  BOTTOM w0.114: v2(86.17,50.52) 86.5,50.2 CPU1.AN60 ; v2(123.8,93.15) 123.8,93.22 123.27,93.75 DIMM1.191
M_A_DQ60: length 74.3
  TOP w0.114: v2(127.8,95.25) 127.8,95.15 v1(127.4,94.74)
  L3 w0.102: v2(86.17,49.61) 85.95,49.61 85.27,50.29 85.27,57.42 85.62,57.77 87.2,57.77 88.62,59.19 89.22,59.19 89.25,59.22 89.71,59.22 100.79,70.3 100.79,76.14 118.8,94.15 121.16,94.15 122.53,95.52 125.39,95.52 126.09,94.82 127.65,94.82 127.8,94.97 v2(127.8,95.25)
  BOTTOM w0.114: v2(86.17,49.61) 86.5,49.28 CPU1.AN61 ; DIMM1.194 128.33,94.65 127.8,95.18 v2(127.8,95.25)
M_A_DQ61: length 73.6
  TOP w0.114: v1(128.4,94.01) 128.36,94.01 v2(127.8,93.45)
  L3 w0.102: v2(86.82,49.61) 86.39,50.04 86.04,50.04 85.64,50.44 85.64,55.39 87.61,57.35 89.69,57.35 89.91,57.57 89.98,57.85 90.1,58.54 90.12,58.71 90.2,58.82 90.35,58.98 90.81,59.42 91.29,59.81 91.9,60.19 92.75,60.64 93.29,61.12 101.19,69.02 101.19,74.69 101.91,76.73 118.92,93.75 121.32,93.75 122.72,95.15 124.04,95.15 124.09,95.13 125.02,94.74 125.15,94.67 126.06,94.29 126.68,94.11 126.97,94.03 127.27,93.89 127.42,93.81 127.54,93.73 v2(127.8,93.45)
  BOTTOM w0.114: DIMM1.192 128.33,94.05 127.8,93.52 v2(127.8,93.45) ; v2(86.82,49.61) 87.15,49.28 CPU1.AP61
M_A_DQ62: length 74
  TOP w0.114: v2(127.17,90.45) 126.85,90.77 v1(126.85,90.91)
  L3 w0.102: v2(88.77,50.52) 88.77,50.94 90.71,52.88 90.71,53.36 91.07,53.72 91.07,54.66 92.44,56.04 92.44,56.18 92.08,56.54 92.08,56.7 92.21,56.83 92.37,56.83 92.73,56.47 92.88,56.47 93.25,56.84 93.25,56.99 93.19,57.05 93.19,57.21 93.31,57.34 93.48,57.34 93.54,57.27 93.68,57.27 103.55,67.14 103.55,70.98 103.97,71.41 103.97,75.9 119.69,91.61 122.71,91.61 122.88,91.78 125.54,91.78 125.65,91.67 125.65,91.05 125.76,90.94 126.59,90.94 126.7,91.05 126.7,91.67 126.82,91.78 129.17,91.78 129.29,91.67 129.29,91 129.17,90.88 127.28,90.88 127.17,90.77 v2(127.17,90.45)
  BOTTOM w0.114: DIMM1.182 127.69,91.05 127.17,90.52 v2(127.17,90.45) ; v2(88.77,50.52) 88.45,50.2 CPU1.AT60
M_A_DQ63: length 73
  TOP w0.114: v2(123.16,91.35) 122.62,91.35 v1(122.6,91.33)
  L3 w0.102: v2(89.44,50.53) 89.44,51.09 91.08,52.72 91.08,53.21 91.43,53.57 91.43,54.5 99.99,63.06 100.14,63.06 100.46,62.74 100.6,62.74 100.75,62.88 100.75,63.02 100.42,63.35 100.42,63.49 100.57,63.64 100.71,63.64 101.03,63.31 101.18,63.31 101.32,63.46 101.32,63.6 101,63.92 101,64.07 101.14,64.21 101.29,64.21 101.61,63.89 101.75,63.89 101.9,64.03 101.9,64.17 101.57,64.5 101.57,64.64 101.72,64.79 101.86,64.79 102.18,64.46 102.33,64.46 102.47,64.61 102.47,64.75 102.15,65.07 102.15,65.22 102.29,65.36 102.44,65.36 102.76,65.04 102.9,65.04 103.05,65.18 103.05,65.32 102.72,65.65 102.72,65.79 102.87,65.94 103.01,65.94 103.34,65.61 103.48,65.61 103.62,65.76 103.62,65.9 103.3,66.22 103.3,66.37 103.44,66.51 103.59,66.51 103.91,66.19 104.05,66.19 104.2,66.33 104.2,66.48 103.92,66.76 103.92,67.25 103.97,67.3 104.57,67.3 104.68,67.42 104.68,67.77 104.57,67.88 104.02,67.88 103.92,67.98 103.92,68.19 104.02,68.29 104.57,68.29 104.68,68.4 104.68,68.58 104.57,68.69 104.02,68.69 103.92,68.8 103.92,69 104.02,69.1 104.57,69.1 104.68,69.21 104.68,69.39 104.57,69.51 104.02,69.51 103.92,69.61 103.92,69.81 104.02,69.91 104.24,69.91 104.34,70.02 104.34,70.39 104.24,70.49 104.04,70.49 103.92,70.61 103.92,70.79 104.04,70.9 104.24,70.9 104.34,71 104.34,75.74 119.46,90.86 119.84,90.86 119.94,90.96 119.94,91.14 120.05,91.24 120.25,91.24 120.35,91.14 120.35,90.96 120.45,90.86 120.66,90.86 120.76,90.96 120.76,91.14 120.86,91.24 121.06,91.24 121.16,91.14 121.16,90.96 121.26,90.86 121.47,90.86 121.57,90.96 121.57,91.14 121.67,91.24 121.87,91.24 121.98,91.14 121.98,90.96 122.08,90.86 122.67,90.86 v2(123.16,91.35)
  BOTTOM w0.114: v2(89.44,50.53) 89.44,50.41 CPU1.AU60 ; DIMM1.183 v2(123.16,91.35)
M_A_DQS_DN0: length 57.5
  TOP w0.127: v2(123.8,42.52) 123.8,42.68 v1(124.11,43)
  L6 w0.114: v2(123.8,42.52) 123.75,42.57 123.75,43.09 123.4,43.44 122.42,43.44 115.91,36.92 114.3,36.92 114.05,36.67 114.05,36.1 113.94,35.99 113.62,35.99 113.51,36.1 113.51,37.33 113.2,37.64 109.1,37.64 108.46,37 108.46,35.04 108.13,34.71 97.57,34.71 97.37,34.51 93.68,34.51 92.73,35.45 92.3,35.88 91.53,36.65 88.12,36.65 86.92,37.85 86.92,38.73 86.53,39.13 86.53,40.79 86.22,41.1 85.86,41.1 v2(85.63,41.32)
  BOTTOM w0.089: v2(85.63,41.32) 86.01,40.94 86.24,40.94 86.42,41.12 86.42,42.7 86.27,42.85 86.27,43.29 86.32,43.44 86.32,43.58 86.26,43.78 86.26,43.96 86.16,44.06 CPU1.AM70
  BOTTOM w0.127: v2(123.8,42.52) 123.35,42.08 122.98,42.08 122.91,42.15 DIMM1.27
M_A_DQS_DN1: length 51.2
  TOP w0.127: v1(122.82,48.18) v2(123.37,48.18)
  L6 w0.114: v2(123.37,48.18) 123.16,48.39 120.07,48.39 119.7,48.02 119.35,48.02 119.09,48.28 118.93,48.28 118.7,48.05 118.7,47.89 119.11,47.48 119.11,47.13 118.75,46.77 118.4,46.77 117.99,47.18 117.83,47.18 117.6,46.96 117.6,46.79 117.99,46.41 117.99,46.06 117.63,45.7 117.28,45.7 116.89,46.08 116.73,46.08 116.51,45.86 116.51,45.7 116.7,45.5 116.77,45.44 116.9,45.3 116.9,44.96 115.94,44 106.89,44 106.2,43.31 106.09,43.19 105.49,43.19 103.58,41.29 94.83,41.29 94.32,41.8 93.57,41.8 92.4,42.97 90.58,42.97 90.05,42.44 90.05,41.74 89.3,40.99 89.3,40.84 89.1,40.64 v2(88.94,40.64)
  BOTTOM w0.089: CPU1.AT69 88.41,44.69 88.8,44.3 88.8,43.79 88.85,43.61 88.85,43.42 88.8,43.24 88.8,43.22 88.8,42.94 89.56,42.19 89.56,41.26 v2(88.94,40.64)
  BOTTOM w0.127: DIMM1.45 122.75,47.55 v2(123.37,48.18)
M_A_DQS_DN2: length 55.9
  TOP w0.127: v2(128.44,52.65) 128.44,53.22 v1(128.48,53.26)
  L6 w0.089: 84.66,48.71 84.65,48.71 84.62,48.74 84.58,48.74 84.57,48.74 84.38,48.74 84.05,48.41 84.05,47.69 83.95,47.59 83.95,47.21 v2(83.5,46.76)
  L6 w0.114: v2(128.44,52.65) 127.62,51.83 126.7,51.83 126.27,52.25 117.97,52.25 114.08,48.35 113.37,48.35 113.12,48.6 113.12,49.19 113,49.3 112.69,49.3 112.57,49.19 112.57,48.95 112.32,48.7 111.82,48.7 111.57,48.95 111.57,49.09 111.45,49.21 111.14,49.21 111.02,49.09 111.02,48.6 110.77,48.35 106.32,48.35 104.89,46.93 101.4,46.93 100.76,46.29 99.84,46.29 99.05,45.5 95.62,45.5 93.5,47.63 93.5,47.75 93.06,48.18 90.2,48.18 89.67,48.71 84.66,48.71
  BOTTOM w0.102: DIMM1.62 v2(128.44,52.65) ; v2(83.5,46.76) 83.5,46.68 83.75,46.44 CPU1.AH66
M_A_DQS_DN3: length 71.2
  TOP w0.127: v2(127.8,37.65) 127.8,37.55 v1(127.39,37.13)
  L6 w0.114: v2(127.8,37.65) 127.3,37.14 126,37.14 125.61,37.53 122.87,37.53 116.82,31.48 112.9,31.48 112.22,30.81 112.22,30.46 112.7,29.98 112.7,29.82 112.48,29.59 112.31,29.59 111.84,30.07 111.49,30.07 110.16,28.74 109.64,28.74 109.28,28.39 108.97,28.39 108.62,28.74 97.77,28.74 97.01,27.98 89.08,27.98 84.57,32.49 84.22,32.49 84.01,32.28 83.85,32.28 83.65,32.49 83.65,32.65 83.85,32.86 83.85,33.21 83.51,33.55 83.16,33.55 82.95,33.35 82.79,33.35 82.59,33.55 82.59,33.71 82.79,33.92 82.79,34.27 82.4,34.66 82.4,38.81 82.96,39.37 82.96,40.51 82.69,40.78 82.02,40.78 v2(81.99,40.8)
  BOTTOM w0.089: CPU1.AG69 83.02,44.12 83.02,43.81 82.96,43.6 82.96,43.41 83.01,43.26 83.01,43.02 82.49,42.51 82.49,40.88 82.35,40.75 82.05,40.75 v2(81.99,40.8)
  BOTTOM w0.102: DIMM1.10 128.91,37.05 128.72,37.06 128.6,37.08 128.35,37.17 128.28,37.21 128.08,37.38 v2(127.8,37.65)
M_A_DQS_DN4: length 64.7
  L3 w0.114: v2(124.11,76.75) 124.33,76.53 124.33,76.33 124.22,76.22 122.52,76.22 122.29,76.46 121.63,76.46 121.4,76.22 120.88,76.22 117.56,72.9 117.56,66.85 116.3,65.58 116.3,59.99 112.17,55.87 112.17,54.62 107.9,50.35 107.9,48.81 103.97,44.88 103.67,44.88 103.18,44.39 103.18,44.09 102.81,43.72 102.33,43.72 101.96,43.34 101.96,42.86 100.96,41.87 99.99,41.87 99.85,42 99.85,42.23 v2(100.11,42.49)
  BOTTOM w0.089: CPU1.BA64 91.42,47.43 91.44,47.4 91.62,47.4 91.82,47.34 91.96,47.34 92.11,47.39 92.55,47.39 92.8,47.14 93.48,47.14 94.91,45.71 94.91,44.79 95.31,44.39 95.74,44.39 95.89,44.37 95.92,44.4 95.95,44.39
  BOTTOM w0.127: v2(100.11,42.49) 100.4,42.78 100.4,43.09 100.19,43.3 v1(99.88,43.3) 98.94,43.3 97.86,44.38 96.06,44.38 95.95,44.39 ; DIMM1.135 122.74,76.95 122.84,77.05 122.84,77.19 122.94,77.3 124.15,77.3 124.25,77.19 124.25,76.89 v2(124.11,76.75)
M_A_DQS_DN5: length 64.8
  TOP w0.127: v2(128.44,82.05) 128.44,82.38 v1(128.71,82.64)
  L3 w0.114: v2(97.19,48.71) 97.19,48.69 97.33,48.55 97.38,48.5 98.07,47.81 100.46,47.81 103.69,51.04 103.69,51.93 106.78,55.02 107.88,56.12 107.88,58.89 112.12,63.13 112.12,73.34 120.75,81.97 120.94,81.97 125.66,81.97 126.91,83.22 127.9,83.22 128.35,82.76 128.35,82.14 v2(128.44,82.05)
  BOTTOM w0.089: v2(97.19,48.71) 97.02,48.71 96.69,49.04 96.22,49.04 96.22,49.04 96.11,49.14 94.75,49.14 93.53,50.36 92.14,50.36 91.99,50.4 91.79,50.4 91.59,50.34 90.96,50.34 CPU1.AY60
  BOTTOM w0.102: v2(128.44,82.05) 128.44,82.05 DIMM1.152
M_A_DQS_DN6: length 70.6
  TOP w0.127: v1(123.5,87.35) 123.86,87 v2(123.86,86.92)
  L3 w0.114: v2(88.11,45.93) 88.11,46.22 88.42,46.54 88.8,46.54 89.22,46.12 90.65,46.12 93.79,49.26 93.79,49.92 94.39,50.51 94.39,51.99 95.62,53.23 96.49,53.23 96.74,53.48 96.74,53.98 96.85,54.09 97.17,54.09 97.28,53.98 97.28,53.48 97.53,53.23 99.52,53.23 102.85,56.56 102.85,59.33 105.75,62.24 105.75,62.59 105.48,62.86 105.48,63.03 105.71,63.25 105.87,63.25 106.14,62.98 106.49,62.98 107,63.48 107,63.83 106.78,64.04 106.78,64.2 107.01,64.43 107.17,64.43 107.38,64.22 107.73,64.22 108.24,64.72 108.24,74.98 120.66,87.41 123.95,87.41 124.01,87.34 124.01,87.07 v2(123.86,86.92)
  BOTTOM w0.127: v2(88.11,45.93) 87.94,45.93 87.8,46.07 CPU1.AR66 ; DIMM1.169 122.77,87.15 122.84,87.22 122.84,87.35 122.98,87.5 123.85,87.5 123.98,87.37 123.98,87.05 v2(123.86,86.92)
M_A_DQS_DN7: length 73.4
  TOP w0.127: v1(127.55,91.91) 127.58,91.91 127.77,92.09 127.77,92.42 v2(127.77,92.42)
  L3 w0.114: v2(127.77,92.42) 127.41,92.78 126.39,92.78 126,92.39 122.72,92.39 122.45,92.13 119.39,92.13 103.4,76.13 103.4,73.72 103.03,73.35 103.03,67.35 99.6,63.92 99.25,63.92 99.05,64.13 98.89,64.13 98.66,63.9 98.66,63.74 98.87,63.53 98.87,63.18 98.36,62.68 98.01,62.68 97.81,62.89 97.64,62.89 97.42,62.66 97.42,62.5 97.62,62.29 97.62,61.94 97.27,61.58 96.91,61.58 96.71,61.79 96.55,61.79 96.32,61.56 96.32,61.4 96.53,61.2 96.53,60.85 96.17,60.49 95.82,60.49 95.61,60.69 95.45,60.69 95.23,60.47 95.23,60.3 95.43,60.1 95.43,59.75 95.07,59.39 94.72,59.39 94.52,59.6 94.35,59.6 94.13,59.37 94.13,59.21 94.33,59 94.33,58.65 93.79,58.11 92.35,58.11 91.52,57.28 91.52,55.9 90.2,54.57 90.2,53.09 88.26,51.15 88.26,50.47 87.47,49.68 v2(87.47,49.61)
  BOTTOM w0.127: CPU1.AR61 v2(87.47,49.61) ; DIMM1.186 128.91,92.25 128.65,91.99 128.15,91.99 127.79,92.35 127.79,92.4 v2(127.77,92.42)
M_A_DQS_DP0: length 57.5
  TOP w0.127: v1(122.59,42.51) 122.6,42.52 v2(123.16,42.52)
  L6 w0.114: v2(123.16,42.52) 123.52,42.88 123.52,43 123.31,43.21 122.52,43.21 116,36.69 114.4,36.69 114.28,36.58 114.28,36.01 114.03,35.76 113.53,35.76 113.28,36.01 113.28,37.23 113.1,37.41 109.19,37.41 108.69,36.9 108.69,34.94 108.23,34.48 97.67,34.48 97.46,34.28 93.58,34.28 92.57,35.29 92.14,35.72 91.43,36.43 88.03,36.43 86.69,37.76 86.69,38.64 86.3,39.03 86.3,40.69 86.12,40.87 85.84,40.87 v2(85.66,40.68)
  BOTTOM w0.089: CPU1.AM69 86.15,44.53 86.44,44.16 86.44,43.81 86.5,43.6 86.5,43.41 86.45,43.26 86.45,42.92 86.59,42.78 86.59,41.03 86.32,40.75 85.73,40.75 v2(85.66,40.68)
  BOTTOM w0.127: DIMM1.29 122.63,42.75 122.72,42.85 123.05,42.85 123.16,42.73 v2(123.16,42.52)
M_A_DQS_DP1: length 51.3
  TOP w0.127: v1(123.93,47.62) 124.09,47.77 124.09,48.15 v2(124.06,48.18)
  L6 w0.114: v2(88.94,41.27) 89.26,41.27 89.82,41.83 89.82,42.53 90.49,43.2 92.5,43.2 93.67,42.03 94.41,42.03 94.93,41.52 103.49,41.52 105.39,43.42 105.99,43.42 106.11,43.54 106.8,44.23 115.84,44.23 116.67,45.05 116.67,45.21 116.54,45.34 116.28,45.6 116.28,45.95 116.64,46.31 116.99,46.31 117.37,45.93 117.54,45.93 117.76,46.15 117.76,46.31 117.37,46.7 117.37,47.05 117.73,47.41 118.09,47.41 118.5,47 118.65,47 118.88,47.23 118.88,47.38 118.47,47.8 118.47,48.15 118.83,48.51 119.18,48.51 119.44,48.25 119.6,48.25 119.97,48.62 123.62,48.62 v2(124.06,48.18)
  BOTTOM w0.089: CPU1.AT70 88.47,44.16 88.62,44.01 88.62,43.77 88.67,43.58 88.67,43.44 88.64,43.3 88.63,43.27 88.62,43.25 88.62,42.85 89.37,42.11 89.37,41.45 89.29,41.37 89.04,41.37 v2(88.94,41.27)
  BOTTOM w0.127: v2(124.06,48.18) 123.62,48.62 123.19,48.62 122.72,48.15 DIMM1.47
M_A_DQS_DP2: length 55.9
  TOP w0.127: v1(127.18,53.23) 127.22,53.23 v2(127.8,52.65)
  L6 w0.089: 84.66,48.94 84.64,48.94 84.64,48.94 84.46,48.94 84.31,48.94 83.87,48.5 83.87,47.78 v2(83.5,47.41)
  L6 w0.114: 84.66,48.94 89.76,48.94 90.29,48.41 93.16,48.41 93.73,47.84 93.73,47.72 95.72,45.73 98.96,45.73 99.75,46.52 100.67,46.52 101.3,47.15 104.8,47.15 106.22,48.58 110.68,48.58 110.79,48.7 110.79,49.19 111.04,49.43 111.55,49.43 111.8,49.19 111.8,49.04 111.91,48.93 112.23,48.93 112.34,49.04 112.34,49.28 112.59,49.53 113.1,49.53 113.35,49.28 113.35,48.7 113.46,48.58 113.98,48.58 117.88,52.48 126.37,52.48 126.79,52.06 127.52,52.06 127.82,52.35 127.82,52.64 v2(127.8,52.65)
  BOTTOM w0.102: DIMM1.64 128.96,53.25 128.26,53.1 v2(127.8,52.65)
  BOTTOM w0.127: CPU1.AH65 v2(83.5,47.41)
M_A_DQS_DP3: length 71.2
  TOP w0.127: v2(128.44,37.65) 128.44,37.26 v1(128.61,37.09)
  L6 w0.114: v2(128.44,37.65) 128.44,37.33 128.31,37.21 127.68,37.21 127.39,36.91 125.9,36.91 125.77,37.05 125.51,37.31 122.97,37.31 116.92,31.25 112.99,31.25 112.45,30.71 112.45,30.55 112.93,30.07 112.93,29.72 112.57,29.36 112.22,29.36 111.74,29.84 111.58,29.84 110.25,28.51 109.73,28.51 109.38,28.16 108.88,28.16 108.52,28.51 97.87,28.51 97.11,27.75 88.98,27.75 84.47,32.26 84.31,32.26 84.11,32.06 83.76,32.06 83.42,32.4 83.42,32.75 83.62,32.95 83.62,33.11 83.41,33.32 83.25,33.32 83.05,33.12 82.7,33.12 82.36,33.46 82.36,33.81 82.56,34.01 82.56,34.17 82.17,34.56 82.17,38.9 82.73,39.47 82.73,40.42 82.6,40.55 82.43,40.55 v2(82.05,40.17)
  BOTTOM w0.089: v2(82.05,40.17) 82.31,40.17 82.49,40.35 82.49,40.62 82.67,40.79 82.67,42.43 83.18,42.95 83.18,43.29 83.14,43.44 83.14,43.58 83.2,43.78 83.2,43.96 CPU1.AG70
  BOTTOM w0.102: DIMM1.12 v2(128.44,37.65)
M_A_DQS_DP4: length 65.3
  TOP w0.127: v1(124.45,77.23) 124.47,77.22 124.47,77.21 124.75,76.93 v2(124.75,76.75)
  L3 w0.114: v2(124.75,76.75) 124.56,76.57 124.56,76.24 124.32,75.99 122.42,75.99 122.19,76.23 121.73,76.23 121.5,75.99 120.98,75.99 117.79,72.81 117.79,66.75 116.53,65.49 116.53,59.9 112.4,55.77 112.4,54.53 108.13,50.26 108.13,48.71 104.07,44.65 103.76,44.65 103.41,44.3 103.41,43.99 102.91,43.49 102.42,43.49 102.18,43.25 102.18,42.77 101.06,41.64 99.9,41.64 99.63,41.91 99.63,42.26 v2(99.4,42.49)
  BOTTOM w0.089: CPU1.AY64 91.37,47.22 91.59,47.22 91.79,47.16 91.99,47.16 92.14,47.21 92.48,47.21 92.72,46.96 93.4,46.96 94.73,45.63 94.73,44.7 95.23,44.2 95.72,44.2 95.87,44.18 95.89,44.14 95.92,44.14
  BOTTOM w0.127: 95.92,44.14 96.04,44.13 97.76,44.13 98.38,43.5 v2(99.4,42.49) ; v2(124.75,76.75) 124.5,77 124.5,77.3 124.25,77.55 DIMM1.137
M_A_DQS_DP5: length 64.7
  TOP w0.127: v2(127.8,82.05) 127.8,82.2 v1(127.46,82.54)
  L3 w0.114: v2(127.8,82.05) 128.12,82.37 128.12,82.67 127.81,82.99 127.01,82.99 125.89,81.87 125.76,81.74 120.84,81.74 112.34,73.24 112.34,63.03 108.11,58.8 108.11,56.03 106.88,54.8 103.92,51.84 103.92,50.95 100.55,47.58 97.98,47.58 97.29,48.27 96.89,48.27 v2(96.55,48.61)
  BOTTOM w0.089: CPU1.BA60 91.44,50.16 91.62,50.16 91.82,50.23 91.96,50.23 92.11,50.18 93.46,50.18 94.69,48.95 96.03,48.95 96.05,48.93 96.14,48.85 96.32,48.85 96.38,48.78 v2(96.55,48.61)
  BOTTOM w0.102: v2(127.8,82.05) 128.27,82.51 128.68,82.51 128.82,82.65 DIMM1.154
M_A_DQS_DP6: length 70.7
  TOP w0.127: v1(88.73,46.86) 88.13,46.86 v2(88.12,46.86)
  L3 w0.114: v2(88.12,46.86) 88.22,46.77 88.89,46.77 89.31,46.35 90.55,46.35 93.56,49.36 93.56,50.01 94.16,50.61 94.16,52.09 95.53,53.46 96.4,53.46 96.51,53.57 96.51,54.07 96.76,54.32 97.26,54.32 97.51,54.07 97.51,53.57 97.63,53.46 99.42,53.46 102.62,56.65 102.62,59.43 105.53,62.33 105.53,62.49 105.25,62.77 105.25,63.12 105.61,63.48 105.96,63.48 106.24,63.2 106.4,63.2 106.77,63.57 106.77,63.73 106.55,63.95 106.55,64.3 106.91,64.66 107.26,64.66 107.48,64.45 107.64,64.45 108.01,64.81 108.01,75.07 120.57,87.64 124.04,87.64 124.24,87.44 124.24,87.22 v2(124.49,86.96)
  BOTTOM w0.127: v2(124.49,86.96) 124.24,87.22 124.24,87.47 123.96,87.75 DIMM1.171 ; v2(88.12,46.86) CPU1.AR65
M_A_DQS_DP7: length 73.3
  TOP w0.127: v1(88.04,50.51) 87.48,50.51 v2(87.47,50.52)
  L3 w0.114: v2(87.47,50.52) 87.55,50.44 87.9,50.44 88.03,50.57 88.03,51.25 89.97,53.18 89.97,54.67 91.29,55.99 91.29,57.37 92.26,58.34 93.7,58.34 94.11,58.75 94.11,58.91 93.9,59.11 93.9,59.46 94.26,59.82 94.61,59.82 94.82,59.62 94.98,59.62 95.2,59.84 95.2,60 95,60.21 95,60.56 95.36,60.92 95.71,60.92 95.91,60.72 96.07,60.72 96.3,60.94 96.3,61.1 96.09,61.31 96.09,61.66 96.45,62.02 96.8,62.02 97.01,61.81 97.17,61.81 97.4,62.04 97.4,62.2 97.19,62.4 97.19,62.75 97.55,63.11 97.9,63.11 98.11,62.91 98.27,62.91 98.64,63.28 98.64,63.44 98.43,63.64 98.43,64 98.79,64.36 99.14,64.36 99.35,64.15 99.51,64.15 102.8,67.45 102.8,73.45 103.17,73.81 103.17,76.23 119.3,92.35 122.36,92.35 122.62,92.62 125.91,92.62 126.3,93.01 127.84,93.01 v2(128.4,92.45)
  BOTTOM w0.127: v2(87.47,50.52) 87.68,50.52 87.8,50.41 CPU1.AR60 ; DIMM1.188 128.91,92.85 128.72,92.66 128.44,92.66 128.36,92.58 128.36,92.5 v2(128.4,92.45)
M_A_RAS#: length 50.7
  TOP w0.178: v2(128.44,69.45) 128.97,69.45 v1(129.01,69.41)
  L6 w0.165: v2(128.44,69.45) 128.44,69.72 128.79,70.07 128.79,70.29 128.62,70.45 126.65,70.45 126.22,70.89 122.79,70.89 121.23,72.45 121.14,72.53 111.64,72.53 110.72,71.61 107.97,71.61 99.43,63.07 97.2,63.07 90.86,56.73 90.2,56.73 v2(89.44,55.97)
  BOTTOM w0.178: v2(128.44,69.45) DIMM1.110 ; CPU1.AU50 89.44,55.89 v2(89.44,55.97)
M_A_WE#: length 51.9
  TOP w0.178: v2(125.7,72.51) 125.7,72.34 v1(125.4,72.04)
  L6 w0.165: v2(125.7,72.51) 125.54,72.67 125.54,72.69 125.08,73.15 122.94,73.15 121.14,74.94 109.08,74.94 98.78,64.64 96.55,64.64 93.93,62.01 92.08,62.01 91.48,61.42 91.48,60.2 90.05,58.77 90.05,58.68 89.68,58.31 89.3,58.31 88.99,58 88.99,57.96 v2(88.86,57.83)
  BOTTOM w0.178: v2(88.86,57.83) 88.45,57.42 CPU1.AT46 ; DIMM1.113 123.67,70.35 125.7,72.38 v2(125.7,72.51)
M_VREF_CA_DIMMA: length 1.6
  BOTTOM w0.33: v3(128.3,74.22) 128.33,74.25 DIMM1.126
  vias: v1(134.09,68.01) v2(135.87,66.31) v2(135.87,65.55)
M_VREF_DQ_DIM0: length 0.6
  BOTTOM w0.305: v2(90.98,44.4) 91.17,44.58 CPU1.AY68
  vias: v1(92.34,43.78)
M_VREF_DQ_DIMMA: length 1.7
  BOTTOM w0.305: v3(123.35,34.13) 123.13,34.35 DIMM1.1
  vias: v1(124.14,34.13)
MCU_BOOT0: length 3.2
  TOP w0.152: U6901.44 90.19,100.44 90.68,99.94 v1(90.74,99.94) 90.74,99.82 90.65,99.73 R6907.1
MCU_OSCI: length 7.8
  TOP w0.152: X6901.1 99.47,103.22 98.7,103.99 95.61,103.99 C6909.1 95.09,103.64 94.27,104.46 v1(94.27,104.51) 94.03,104.75 U6901.5
MCU_OSCO: length 5.6
  TOP w0.152: U6901.6 94.96,105.26 C6908.1 95.6,104.62 97.16,104.62 X6901.3
MCU_RST#: length 3.7
  TOP w0.152: R6902.1 95.92,106.97 C6902.1 94.71,105.75 94.23,105.75 v1(94.21,105.73) 94.2,105.73 94.17,105.75 U6901.7
ME_FWP_EC: length 119.3
  TOP w0.102: v2(147.38,47.24) 146.95,47.67 KBC24.80 ; R1909.1 v1(98.91,66.77) 100.11,66.77 100.49,67.15 102.4,67.15 108.46,73.21 108.46,76.64 118.78,86.96 118.78,98.39 v2(119.54,99.15)
  L3 w0.102: v2(147.38,47.24) 146.74,47.87 146.74,48.77 146.77,48.8 146.77,52.9 146.37,53.3 146.37,56.02 144.3,58.09 141.6,58.09 138.59,61.11 137.07,61.11 132.76,65.42 131.27,65.42 130.72,65.97 130.72,83.28 131.86,84.43 131.86,85.07 131.1,85.83 131.1,87.17 131.27,87.34 131.27,94.67 127.74,98.19 127.06,98.19 126.78,97.91 124.79,97.91 124.29,98.42 123.99,98.42 122.66,99.76 120.14,99.76 v2(119.54,99.15)
ME_SUS_PWR_ACK: length 108.9
  TOP w0.102: v2(99.47,84.78) 99.43,84.78 v1(98.91,84.27) 98.36,83.72 RN1702.1 ; v2(147.79,53.44) 151.01,53.44 152.07,52.37 153.65,52.37 155.16,53.87 KBC24.42
  L3 w0.102: v2(99.47,84.78) 99.47,85.54 102.9,88.97 102.9,91.19 105.81,94.1 106.86,94.1 109.59,96.83 109.59,99.21 110.48,100.09 112.88,100.09 113.65,100.86 122.92,100.86 123.22,100.55 126.27,100.55 126.86,99.97 127.21,99.97 127.83,99.35 128.29,99.35 130.19,97.45 130.19,97.09 132.24,95.04 132.24,87 132.11,86.87 132.11,86.13 132.79,85.45 132.79,83.7 131.92,82.83 131.92,72.76 132.29,72.38 132.29,67.2 137.42,62.07 141.69,62.07 142.56,61.21 143.08,61.21 144.18,60.11 144.18,59.53 147.3,56.4 147.3,53.91 147.77,53.44 v2(147.79,53.44)
ME_SUS_PWR_ACK_R: length 16
  TOP w0.102: v2(87.47,77.04) 87.51,77.04 87.94,77.47 88.95,77.47 89.13,77.29 89.95,77.29 90.07,77.41 90.66,77.41 92.01,78.76 v1(92.01,79.63) 92.01,80.38 92.78,81.15 92.92,81.15 94.67,82.9 94.67,83.11 R1708.1 95.27,83.72 RN1702.4 96.94,83.72 97.03,83.81 97.03,85.35 R2039.2
  BOTTOM w0.102: CPU1.AR13 87.47,76.91 v2(87.47,77.04)
MEM_SMBCLK: length 48.2
  TOP w0.114: v1(105.95,92.12) 105.27,92.12 v2(105.07,92.31) 105.07,92.48 105.2,92.61 Q1801.3 ; v2(78.14,89.38) 78.07,89.45 RN1811.3
  L3 w0.089: v2(78.11,80.19) 78.13,80.17 78.45,80.17 78.54,80.26 78.54,81.1 78.33,81.31 78.33,82.22 78.59,82.48 78.59,82.56
  L3 w0.114: 78.59,82.56 78.59,88.79 78.14,89.25 v2(78.14,89.38)
  L6 w0.102: v2(105.07,92.31) 104.83,92.55 103.56,92.55 103.18,92.17 102.32,92.17 101.17,91.03 101.17,90.14 101.4,89.91 101.4,88.49 100.46,87.55 99.35,87.55 98.89,87.09 98.89,86.71 97.45,85.27 94.59,85.27 91.85,88.02 89.31,88.02 89.09,87.8 86.95,87.8 84.76,89.99 82.63,89.99 82.33,89.68 79.71,89.68 78.98,88.94 78.57,88.94 v2(78.14,89.38)
  BOTTOM w0.114: v2(78.11,80.19) 77.87,80.44 CPU1.R7
MEM_SMBDATA: length 46.8
  TOP w0.114: RN1811.4 78.72,89.43 v2(78.77,89.38) 78.77,89.2 v1(78.47,88.89) ; Q1801.6 103.9,94.44 103.36,93.9 v2(103.23,93.9)
  L3 w0.089: 78.94,82.56 78.73,82.35 78.52,82.14 78.52,81.39 78.73,81.18 78.73,80.18 v2(78.09,79.54)
  L3 w0.114: v2(78.77,89.38) 78.94,89.21 78.94,82.56
  L6 w0.102: v2(103.23,93.9) 102.52,93.19 102.52,92.8 100.87,91.15 100.87,90.01 101.1,89.78 101.1,88.61 100.34,87.85 99.22,87.85 98.58,87.22 98.58,86.84 97.33,85.58 94.72,85.58 91.98,88.32 89.18,88.32 88.97,88.1 87.07,88.1 84.89,90.29 82.51,90.29 82.2,89.99 79.59,89.99 78.98,89.38 v2(78.77,89.38)
  BOTTOM w0.114: CPU1.R8 77.81,79.54 v2(78.09,79.54)
MIC_GND: length 3.2
  TOP w0.203: v2(54.13,95.47) 54.97,95.47 v1(55,95.45)
  TOP w0.508: R5501.1 54.32,95.28 v2(54.13,95.47)
  BOTTOM w0.305: LCD1.20 54.05,95.39 v2(54.13,95.47)
MICBIASB: length 3.3
  TOP w0.203: 18.89,22.89 19.11,23.11 HDA27.32
  TOP w0.254: 18.89,22.89 18.19,22.19 17.6,22.19 R2921.1 17.47,21.54 v1(17.6,21.41)
MSCLK: length 8.1
  TOP w0.114: R2441.2 132.15,25.39 132.15,26.04 v1(132.27,26.16) 132.34,26.16 R2475.2 133.37,25.13 133.37,22.33 132.66,21.63 132.64,21.63 131.96,20.94 JTAG1.6
MSDATA: length 5.8
  TOP w0.114: R2476.2 133.76,25.05 v1(133.76,24.41) 133.71,24.35 133.71,22.19 132.8,21.28 132.78,21.28 132.46,20.96 JTAG1.7
MSM#: length 1.3
  TOP w0.102: v2(86.81,52.38) 86.81,52.07 TP617.1
  BOTTOM w0.102: CPU1.AP56 87.15,52.04 v2(86.81,52.38)
MUTE_CTRL: length 27.4
  TOP w0.102: R2918.2 v1(31.21,19.65) 31.21,19.21 30.51,18.51 v2(29.12,18.51)
  L4 w0.102: v2(29.12,18.51) 29.62,19.02 29.62,23.08 29.12,23.59 28.23,23.59 28.1,23.72 28.1,26.89 27.31,27.68 v2(26.93,27.68)
  BOTTOM w0.102: v2(26.93,27.68) R2917.2 28.61,29.62 C2901.1 27.02,31.21 26.37,31.21 26.19,31.03 21.7,31.03 21.62,30.96 U2901.2
NCT7718_DXN: length 119.1
  TOP w0.254: 92.62,46.37 90.96,46.37 87.76,43.17 86.14,43.17 85.13,42.16 85.13,41.48 85.12,41.48 85.12,38.7 83.6,37.18 81.19,37.18 80.58,37.79 73.4,37.79 73.06,38.13 72.55,38.13 C2607.2 72.23,38.19 71.28,38.19 71.15,38.32 70.03,38.32 69.83,38.12 THM261.3 ; 92.62,46.37 94.16,46.37 95.21,47.42 100.62,47.42 101.25,48.05 112.03,48.05 v2(113.99,50.01) ; 92.62,46.37 v1(92.62,46.27)
  BOTTOM w0.254: v2(113.99,50.01) 113.68,50.32 113.68,51.25 113.35,51.58 113.35,81.29 114.22,82.17 114.22,93.74 105.67,102.29 105.67,102.72 104.48,103.91 101.47,103.91 C2606.2 101.12,107.42 Q2603.E
NCT7718_DXP: length 120.2
  TOP w0.254: v2(113.17,50.01) 112.69,49.52 112.69,49.42 111.82,48.56 101.04,48.56 100.41,47.92 95,47.92 93.95,46.88 90.75,46.88 87.55,43.68 86.75,43.68 ; 86.75,43.68 85.93,43.68 84.62,42.37 84.62,41.69 84.61,41.69 84.61,38.91 83.39,37.69 81.4,37.69 80.79,38.3 73.61,38.3 73.27,38.64 72.68,38.64 C2607.1 72.23,38.7 71.49,38.7 71.36,38.83 69.82,38.83 69.18,38.19 THM261.2 ; 86.75,43.68 v1(86.75,43.73)
  BOTTOM w0.254: v2(113.17,50.01) 113.17,51.04 112.84,51.37 112.84,81.5 113.72,82.38 113.72,93.53 105.16,102.08 105.16,102.51 104.27,103.4 101.59,103.4 C2606.1 100.24,103.83 100.24,105.17 Q2603.C 99.73,106.92 Q2603.B
P_SYS: length 172.3
  TOP w0.102: PR4632.1 36.29,41.49 36.99,40.79 v1(36.99,39.77) 36.99,38.19 v2(36.74,37.94) ; v2(140.62,25.49) 140.62,25.53 142,26.91 142,29.68 145.34,33.02 145.82,33.02 145.82,33.02 147.86,33.02 147.88,33.04 R2422.1
  L4 w0.102: v2(140.62,25.49) 140.19,25.06 139.35,25.06 138.58,25.84 129.16,25.84 126.63,23.31 123.22,23.31 121.85,21.94 116.71,21.94 116.54,22.1 116.07,22.1 115.25,21.28 105.87,21.28 104.88,22.27 96.98,22.27 96.04,23.21 94.34,23.21 94.14,23.01 93.68,23.01 92.6,21.93 90.83,21.93 84.74,21.93 81.64,25.02 72.14,25.02 67.11,30.04 66.74,30.04 66.33,30.46 66.33,31.46 64.2,33.58 44.78,33.58 43.09,35.27 38.51,35.27 36.74,37.05 v2(36.74,37.94)
  L6 w0.102: v2(38.89,6.19) 35.26,9.82 35.26,14.15 31.15,18.27 31.15,22.2 30.39,22.95 v2(30.19,22.95)
  BOTTOM w0.102: PR4474.1 38.64,6.83 38.89,6.57 v2(38.89,6.19) ; v2(36.74,37.94) 36.48,37.69 35.33,37.69 32.92,35.28 32.92,29.79 30.19,27.06 v2(30.19,22.95)
PANEL_SIZE1: length 168.9
  TOP w0.102: v2(159.04,50.77) 159.04,50.72 159.29,50.47 KBC24.24 161.21,50.47 162.32,51.58 v1(162.87,51.58) 164.05,51.58 R2455.1
  L4 w0.102: v2(103.41,102.84) 103.84,103.27 104.22,103.27 106.53,100.97 111.53,100.97 115.43,104.87 124.85,104.87 125.28,105.3 127.87,105.3 128.59,104.58 129.74,104.58 130.74,103.57 131.76,103.57 133.76,101.57 133.76,101.19 137.68,97.27 137.68,83.19 140.13,80.74 140.28,80.74 141.64,79.38 141.64,77.47 147.28,71.84 147.57,71.84 148.01,71.84 154.44,65.41 154.44,65.34 155.71,64.08 155.98,64.08 158.66,61.4 158.66,52.27 158.6,52.22 158.6,51.2 v2(159.04,50.77)
  L6 w0.102: v2(45.54,92.86) 45.55,92.85 46.01,92.85 46.56,92.3 50.64,92.3 52.93,94.58 61.93,94.58 62.98,95.63 66.49,95.63 66.62,95.51 66.64,95.51 66.83,95.32 67.19,95.32 67.44,95.57 67.44,95.73 67.78,96.07 73.11,96.07 73.28,95.91 83.27,95.91 86.06,98.7 86.21,98.7 100.31,98.7 102.24,100.63 102.24,101.74 103.34,102.84 v2(103.41,102.84)
  BOTTOM w0.102: v2(45.54,92.86) 45.55,92.85 46.09,92.85 46.55,93.31 LCD1.35
PBAT_PRES1#: length 10.8
  TOP w0.102: 92.84,20.9 92.5,21.24 RN4301.8
  TOP w0.762: BATT1.5 94.05,19.69 92.84,20.9
  BOTTOM w0.102: AFTP4306.1 95.41,22.7 94.05,21.34 94.05,20.67
  BOTTOM w0.762: BATT1.5 94.05,20.67
PBAT_PRES#: length 134.3
  TOP w0.102: v2(42.32,11.27) 42.2,11.4 PU4401.15 ; v2(94.52,22.78) 94.24,23.06 RN4301.1 ; v2(141.41,36.11) 141.41,35.7 141.65,35.46 R2415.1 142.25,35.95 142.25,36.15 143.37,37.27 v1(143.53,37.27) 144.65,37.27 146.36,38.98 KBC24.97
  L3 w0.102: v2(98.1,27.86) 99.24,28.99 107.95,28.99 108.21,29.25 112.57,29.25 113.12,28.7 116.21,28.7 117.99,30.48 121.39,30.48 121.68,30.76 126.51,30.76 130.59,34.84 132.52,34.84 136.92,39.25 138.76,39.25 139.9,40.39 141.25,40.39 v2(141.71,39.92) ; v2(94.52,22.78) 94.19,23.11 93.22,23.11 92.88,22.76 85.45,22.76 84,24.2 74.56,24.2 74.23,24.2 67.32,17.29 58.48,17.29 57.46,18.31 55.82,18.31 55.71,18.41 46.76,18.41 45.45,17.1 45.45,16.21 42.7,13.46 42.7,11.65 v2(42.32,11.27)
  L4 w0.102: v2(141.41,36.11) 142.03,36.72 142.52,36.72 143.82,38.02 143.82,38.37 142.27,39.92 v2(141.71,39.92)
  BOTTOM w0.102: v2(94.52,22.78) 94.52,23.62 D4301.3 96.26,25.14 EC4307.2 98.31,27.22 98.31,27.64 v2(98.1,27.86)
PBAT_SMBCLK1: length 10.1
  TOP w0.114: 90.86,20.64 91.35,21.13 91.35,21.13 RN4301.6
  TOP w0.762: BATT1.3 90.05,19.83 90.86,20.64
  BOTTOM w0.114: AFTP4308.1 90.05,23.44 90.05,20.64
  BOTTOM w0.762: BATT1.3 90.05,20.64
PBAT_SMBDAT1: length 9.7
  TOP w0.114: RN4301.7 91.85,20.5 92.05,20.29
  TOP w0.762: 92.05,20.29 BATT1.4
  BOTTOM w0.114: 92.05,20.67 92.05,23.39 AFTP4307.1
  BOTTOM w0.762: BATT1.4 92.05,20.67
PCH_ALW_ON: length 149.3
  TOP w0.102: R4102.1 77.95,110.14 76.99,109.19 v2(76.74,109.19) ; v1(164.62,57.44) 164.62,57.53 v2(164.14,58.01) ; v2(155.98,52.02) 155.67,51.71 148.5,51.71 147.97,51.17 145.88,51.17 145.79,51.27 KBC24.71 143.09,51.27 R2495.1
  L4 w0.102: v2(76.74,109.19) 78.65,111.09 113.59,111.09 115.68,109.01 128.48,109.01 130.66,106.83 131.2,106.83 132.04,105.99 133.33,105.99 137.57,101.75 137.57,99.79 140.11,97.25 140.11,87.65 140.95,86.81 140.95,83.66 143.75,80.86 143.75,78.69 150.15,72.29 150.15,71.95 156.17,65.93 156.95,65.93 163.68,59.2 163.68,58.46 v2(164.14,58.01)
  BOTTOM w0.102: v2(155.98,52.02) 157.09,53.13 159.26,53.13 v2(164.14,58.01)
PCH_BATLOW#: length 3.8
  TOP w0.102: R1723.2 90.77,76.74 89.71,75.68 v1(89.11,75.68) 88.77,76.02 v2(88.77,76.12)
  BOTTOM w0.102: v2(88.77,76.12) 89.1,76.45 CPU1.AU13
PCH_DPWROK: length 131.3
  TOP w0.102: v2(100.35,73.06) 101.28,73.06 101.41,72.93 EC1711.1 R1718.1 99.91,71.58 99.86,71.53 R1704.2 98.83,71.53 v2(98.56,71.8) ; v2(149.28,25.79) 150.86,27.37 150.86,28.59 151.72,29.45 151.72,32.71 150.73,33.7 150.73,34.18 150.56,34.35 R2497.1
  L6 w0.102: v2(100.35,73.06) 100.45,73.06 107.69,80.31 125.72,80.31 126.86,79.17 128.64,79.17 129.34,78.46 129.34,73.51 130.36,72.49 130.36,35.24 132.53,33.06 132.53,31.77 134.23,30.08 135.73,30.08 136.68,29.12 136.68,27.67 139.11,25.25 139.11,24.28 139.51,23.88 140.32,23.88 146.22,29.77 147.52,29.77 149.28,28.02 v2(149.28,25.79)
  BOTTOM w0.102: CPU1.BB20 92.33,72.73 92.82,72.73 93.19,72.73 93.52,72.4 93.55,72.4 94.34,71.62 95.14,71.62 95.68,71.07 96.58,71.07 96.86,70.8 97.81,70.8 v1(97.81,70.79) 98.56,71.54 v2(98.56,71.8)
PCH_JTAG_TCK: length 78.1
  TOP w0.114: v1(65.23,52.27) 65.46,52.5 65.74,52.5 v2(65.77,52.52) ; v2(114.15,29.18) 114.65,28.68 R9914.2
  L4 w0.114: v2(65.77,52.52) 64.44,51.19 64.44,46.86 63.14,45.56 63.14,44.81 64.86,43.1 64.86,40 65.25,39.61 66.54,38.32 66.54,37.76 72.19,32.1 72.64,31.65 76.93,31.65 77.17,31.41 79.23,31.41 80.33,30.32 80.94,30.32 81.49,29.76 83.53,29.76 86.57,26.73 106.28,26.73 106.3,26.75 111.01,26.75 113.44,29.18 v2(114.15,29.18)
  BOTTOM w0.114: R407.1 65.07,51.97 65.61,52.52 v2(65.77,52.52) 66,52.76 68.25,52.76 68.31,52.7 68.63,52.7 69.15,52.18 69.74,52.18 70.02,51.91 CPU1.B56
PCH_JTAG_TDI: length 75.8
  TOP w0.114: v1(109.23,44.09) 109.37,44.23 R9916.2 110.33,44.23 111.67,42.89 v2(111.67,42.51)
  L4 w0.114: v2(66.03,50.39) 66.45,50.39 66.73,50.67 67.09,50.67 67.3,50.46 68.19,50.46 68.85,51.11 68.85,51.87 68.45,52.27 68.31,52.27 68.02,52.57 67.81,52.57 67.28,53.09 67.28,53.83 69.12,55.66 69.3,55.66 69.73,56.09 75.3,56.09 75.33,56.06 76.11,56.06 82.34,49.83 82.66,49.83 83.98,48.51 83.98,44.65 85.17,43.47 90.6,43.47 91.55,42.52 91.55,41.36 92.3,40.61 97.07,40.61 98.98,38.7 108.8,38.7 111.67,41.56 v2(111.67,42.51)
  BOTTOM w0.089: 69.04,51.05 69.15,51.05 69.35,50.97 69.41,50.94 69.63,50.85 69.77,50.79 70.06,50.79 70.16,50.84 70.7,50.84 70.75,50.89 71.05,50.89 71.39,50.55 CPU1.D59
  BOTTOM w0.114: 69.04,51.05 67.42,51.05 67.28,51.19 66.58,51.19 66.03,50.65 v2(66.03,50.39) 65.78,50.13 65.78,49.97 65.07,49.26 R408.1
PCH_JTAG_TDO: length 89.4
  TOP w0.114: v2(110.4,35.78) 109.97,36.21 109.97,36.59 109.8,36.75 XDP1.52 109.8,40.67 R9919.2
  L4 w0.114: v2(65.72,51.89) 65.72,51.69 64.69,50.67 64.69,43.59 65.09,43.19 65.09,40.46 65.09,40.33 65.1,40.08 66.76,38.42 66.76,37.85 72.42,32.2 72.74,31.88 77.02,31.88 77.26,31.64 79.33,31.64 80.42,30.54 83.08,30.54 86.66,26.96 106.19,26.96 106.21,26.97 110.84,26.97 114.39,30.52 114.39,34.22 111.74,36.87 111.38,36.87 110.91,36.41 110.91,36.3 v2(110.4,35.78)
  BOTTOM w0.114: R409.1 65.72,51.57 v2(65.72,51.89) 65.76,51.89 66.4,52.53 67.94,52.53 68.05,52.41 68.63,52.41 69.07,51.98 69.52,51.98 CPU1.A56
PCH_JTAG_TMS: length 77.2
  TOP w0.114: R9917.2 116.05,39.4 113.06,42.39 v2(113.06,42.51)
  L4 w0.114: v2(66.93,49.6) 67.56,50.23 68.28,50.23 69.08,51.02 69.08,51.97 68.54,52.5 68.41,52.5 68.12,52.79 67.9,52.79 67.51,53.18 67.51,53.74 69.21,55.43 69.4,55.43 69.81,55.84 74.63,55.84 74.64,55.86 75.21,55.86 75.23,55.83 76.02,55.83 83.03,48.81 83.03,45.26 85.08,43.21 90.53,43.21 91.32,42.42 91.32,41.26 92.23,40.35 96.98,40.35 98.87,38.47 109.01,38.47 v2(113.06,42.51)
  BOTTOM w0.089: 69.12,50.29 69.29,50.12 70.16,50.12 70.34,50.29 70.39,50.29 70.5,50.41 70.74,50.41 CPU1.C59
  BOTTOM w0.114: v1(113.04,43.12) 113.04,42.54 v2(113.06,42.51) ; R416.1 65.07,47.48 65.76,48.17 65.76,48.74 66.02,49 66.06,49 66.66,49.6 v2(66.93,49.6) 67.62,50.29 69.12,50.29
PCH_PLTRST#: length 15
  TOP w0.114: R1713.2 96.68,86.14 96.68,85.97 v1(96.17,85.46) 95.67,84.96 94.88,84.96 93.88,83.96 93.88,83.28 92.53,81.94 92.45,81.94 91.22,80.71 91.22,80.57 90.09,79.44 89.47,79.44 89.34,79.31 88.59,79.31 88.59,79.31 87.29,79.31 86.64,79.31 86.61,79.28 86.58,79.28 v2(86.17,78.87)
  BOTTOM w0.114: CPU1.AN10 86.17,78.74 v2(86.17,78.87)
PCH_PLTRST#_EC: length 3.8
  TOP w0.102: KBC24.56 149.56,56.99 v1(149.43,57.12) 149.43,57.73 C2402.1 R2410.1
PCH_POPIRCOMP: length 5.3
  TOP w0.127: v2(88.77,74.3) 89.22,74.74 89.22,74.74 89.25,74.76 89.83,74.76 89.97,74.9 90.7,74.9
  TOP w0.508: 90.7,74.9 90.86,74.9 90.92,74.83 91.5,74.83 v1(91.51,74.83) 91.53,74.83 92.11,74.25 R413.1
  BOTTOM w0.305: CPU1.AU16 89.1,74.73 88.77,74.4 v2(88.77,74.3)
PCH_RSMRST#: length 125.3
  TOP w0.102: KBC24.88 145.68,44.47 145.78,44.37 146.29,44.37 146.84,44.93 150.41,44.93 151.07,45.59 153.81,45.59 156.28,48.05 156.79,48.05 v2(157.82,47.02) ; R1702.2 112.55,98.33 EC1712.1 112.49,98.71 111.11,100.09 110.6,100.09 110.58,100.08 107.57,100.08 v1(106.33,101.31) 105.82,101.82 105.82,102.33 v2(106.19,102.7)
  L3 w0.102: v2(159.5,55.18) 159.5,53.45 157.82,51.77 v2(157.82,47.02)
  L4 w0.102: v2(106.19,102.7) 106.84,102.7 106.85,102.69 107.1,102.44 107.1,102.44 107.46,102.08 109.25,102.08 109.84,102.66 112.5,102.66 115.45,105.61 119.27,105.61 120.1,106.44 124.03,106.44 124.47,106.01 126.93,106.01 126.93,106.01 127.35,106.01 127.35,106.01 128.28,106.01 128.99,105.29 129.84,105.29 130.52,104.62 132.15,104.62 135.49,101.28 135.49,101.26 136.3,100.45 136.3,99.39 138.19,97.5 138.19,84.3 142.27,80.22 142.27,77.82 147.69,72.41 148.16,72.41 154.95,65.62 154.95,65.58 155.94,64.58 156.19,64.58 161.07,59.71 161.07,56.78 159.5,55.22 v2(159.5,55.18)
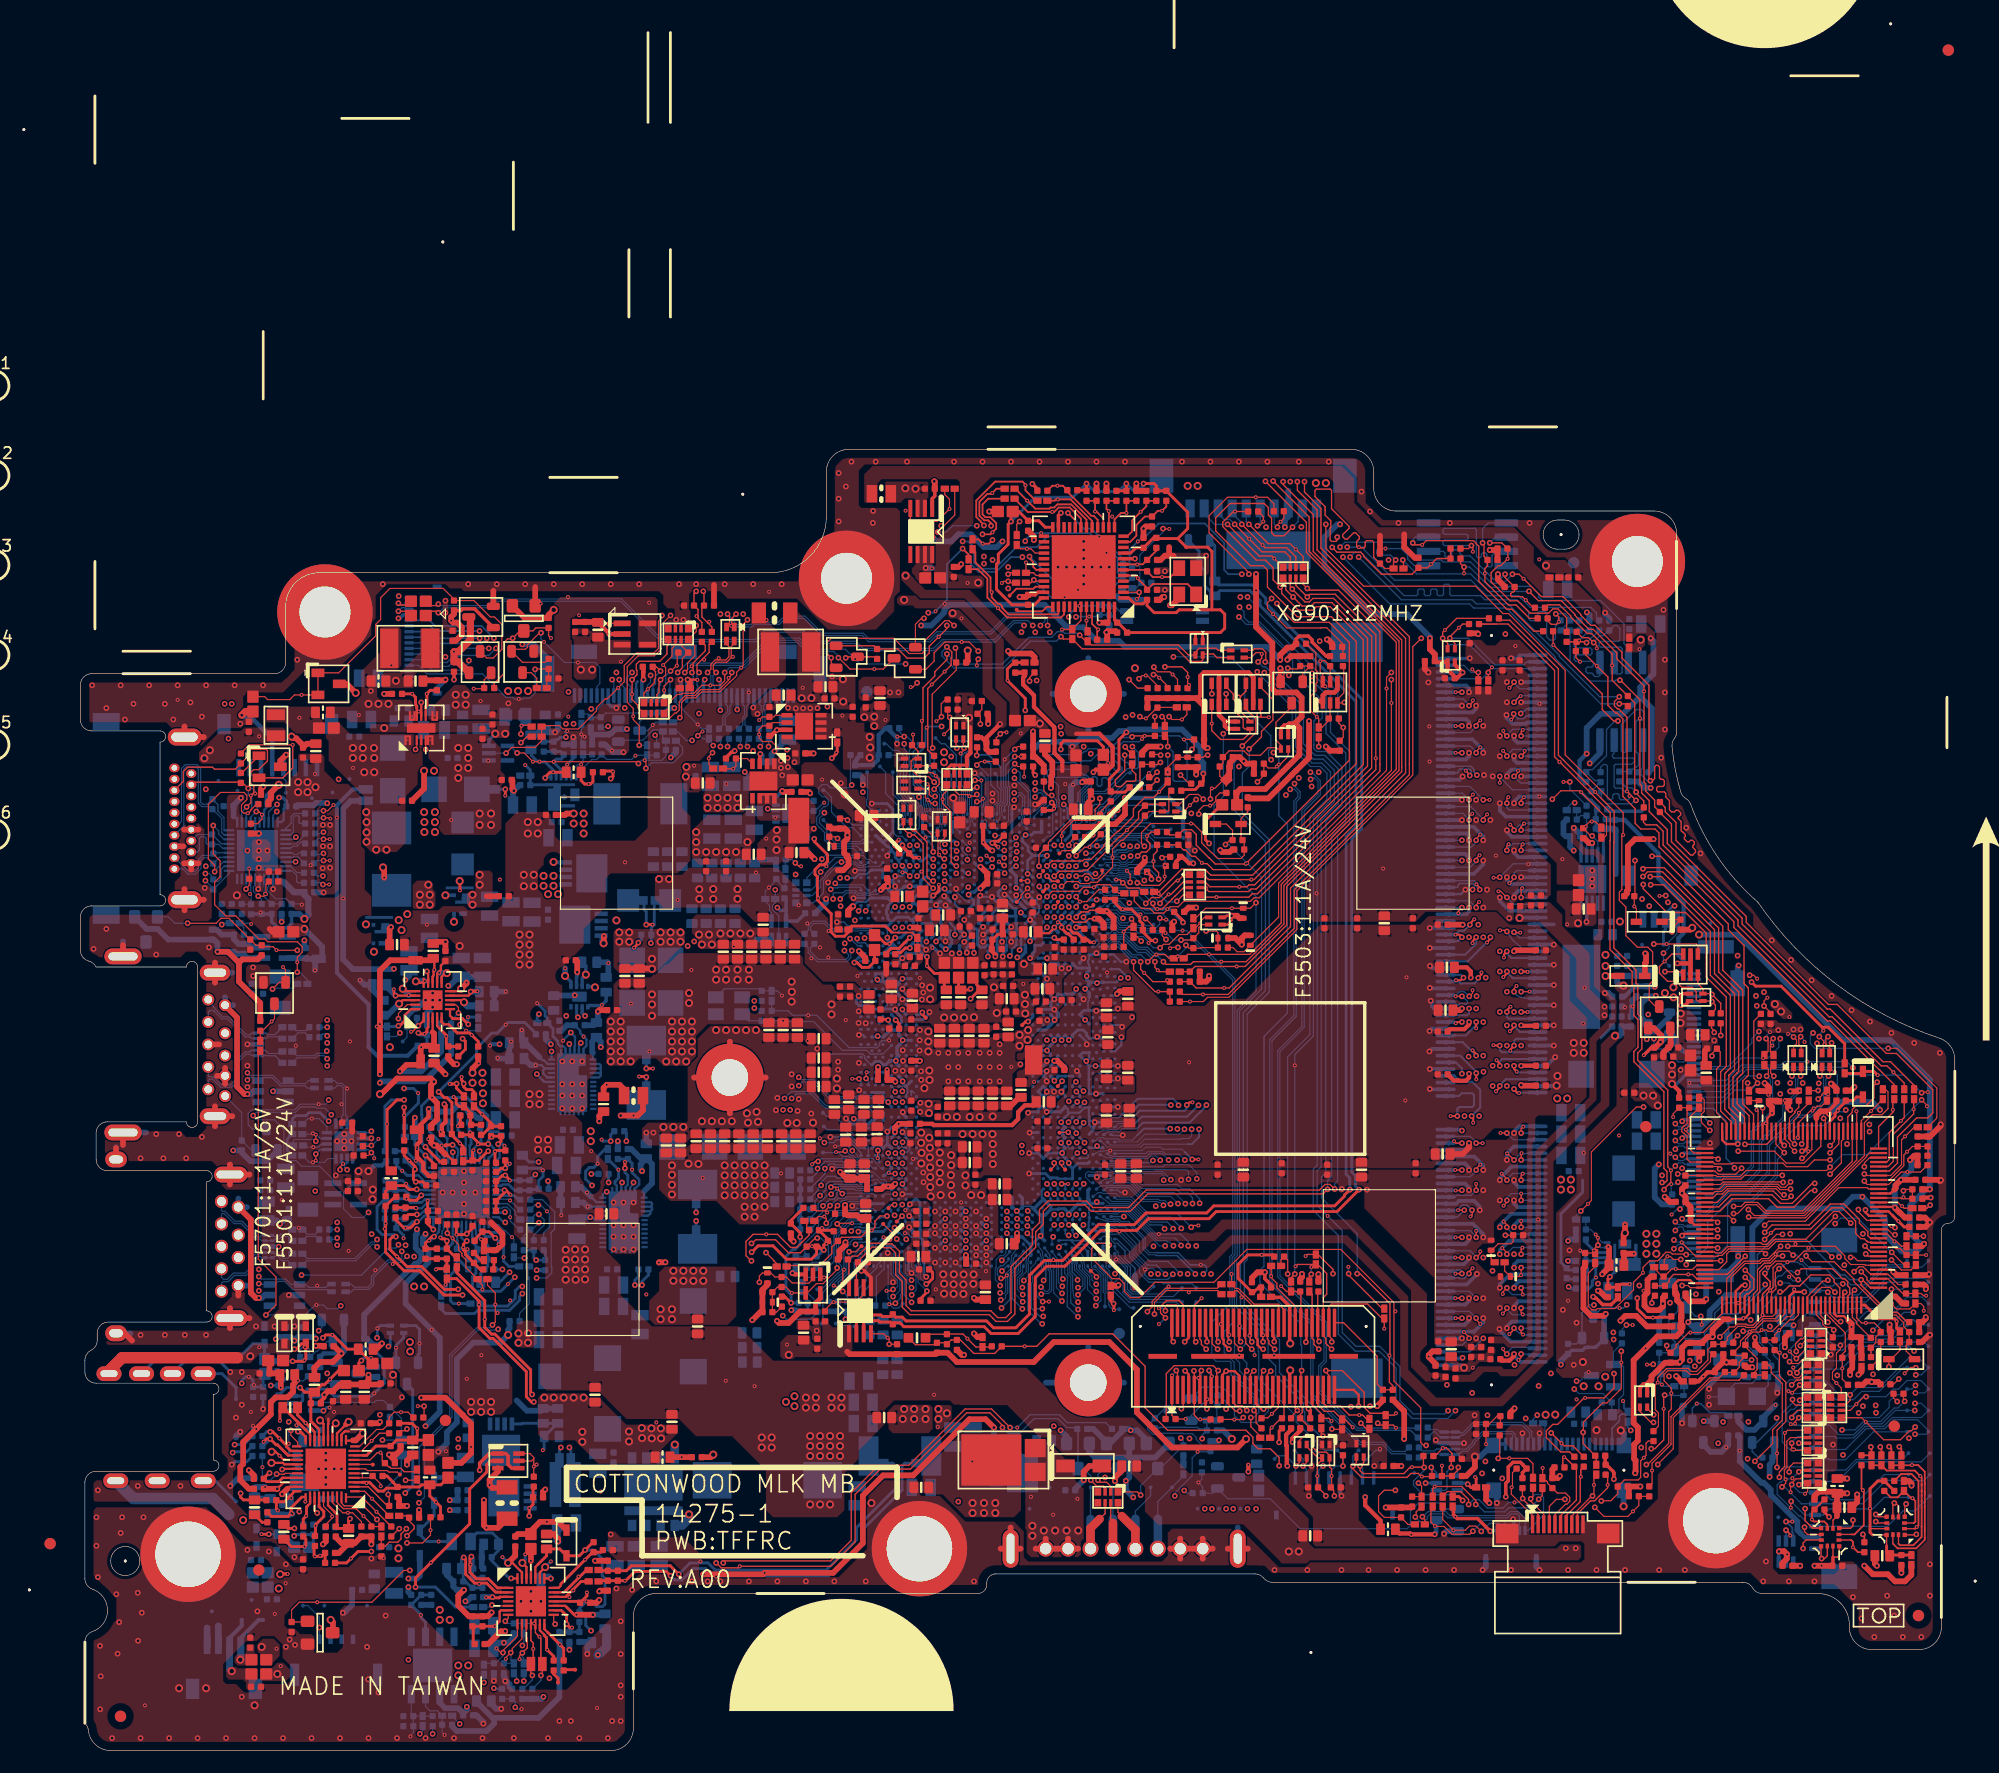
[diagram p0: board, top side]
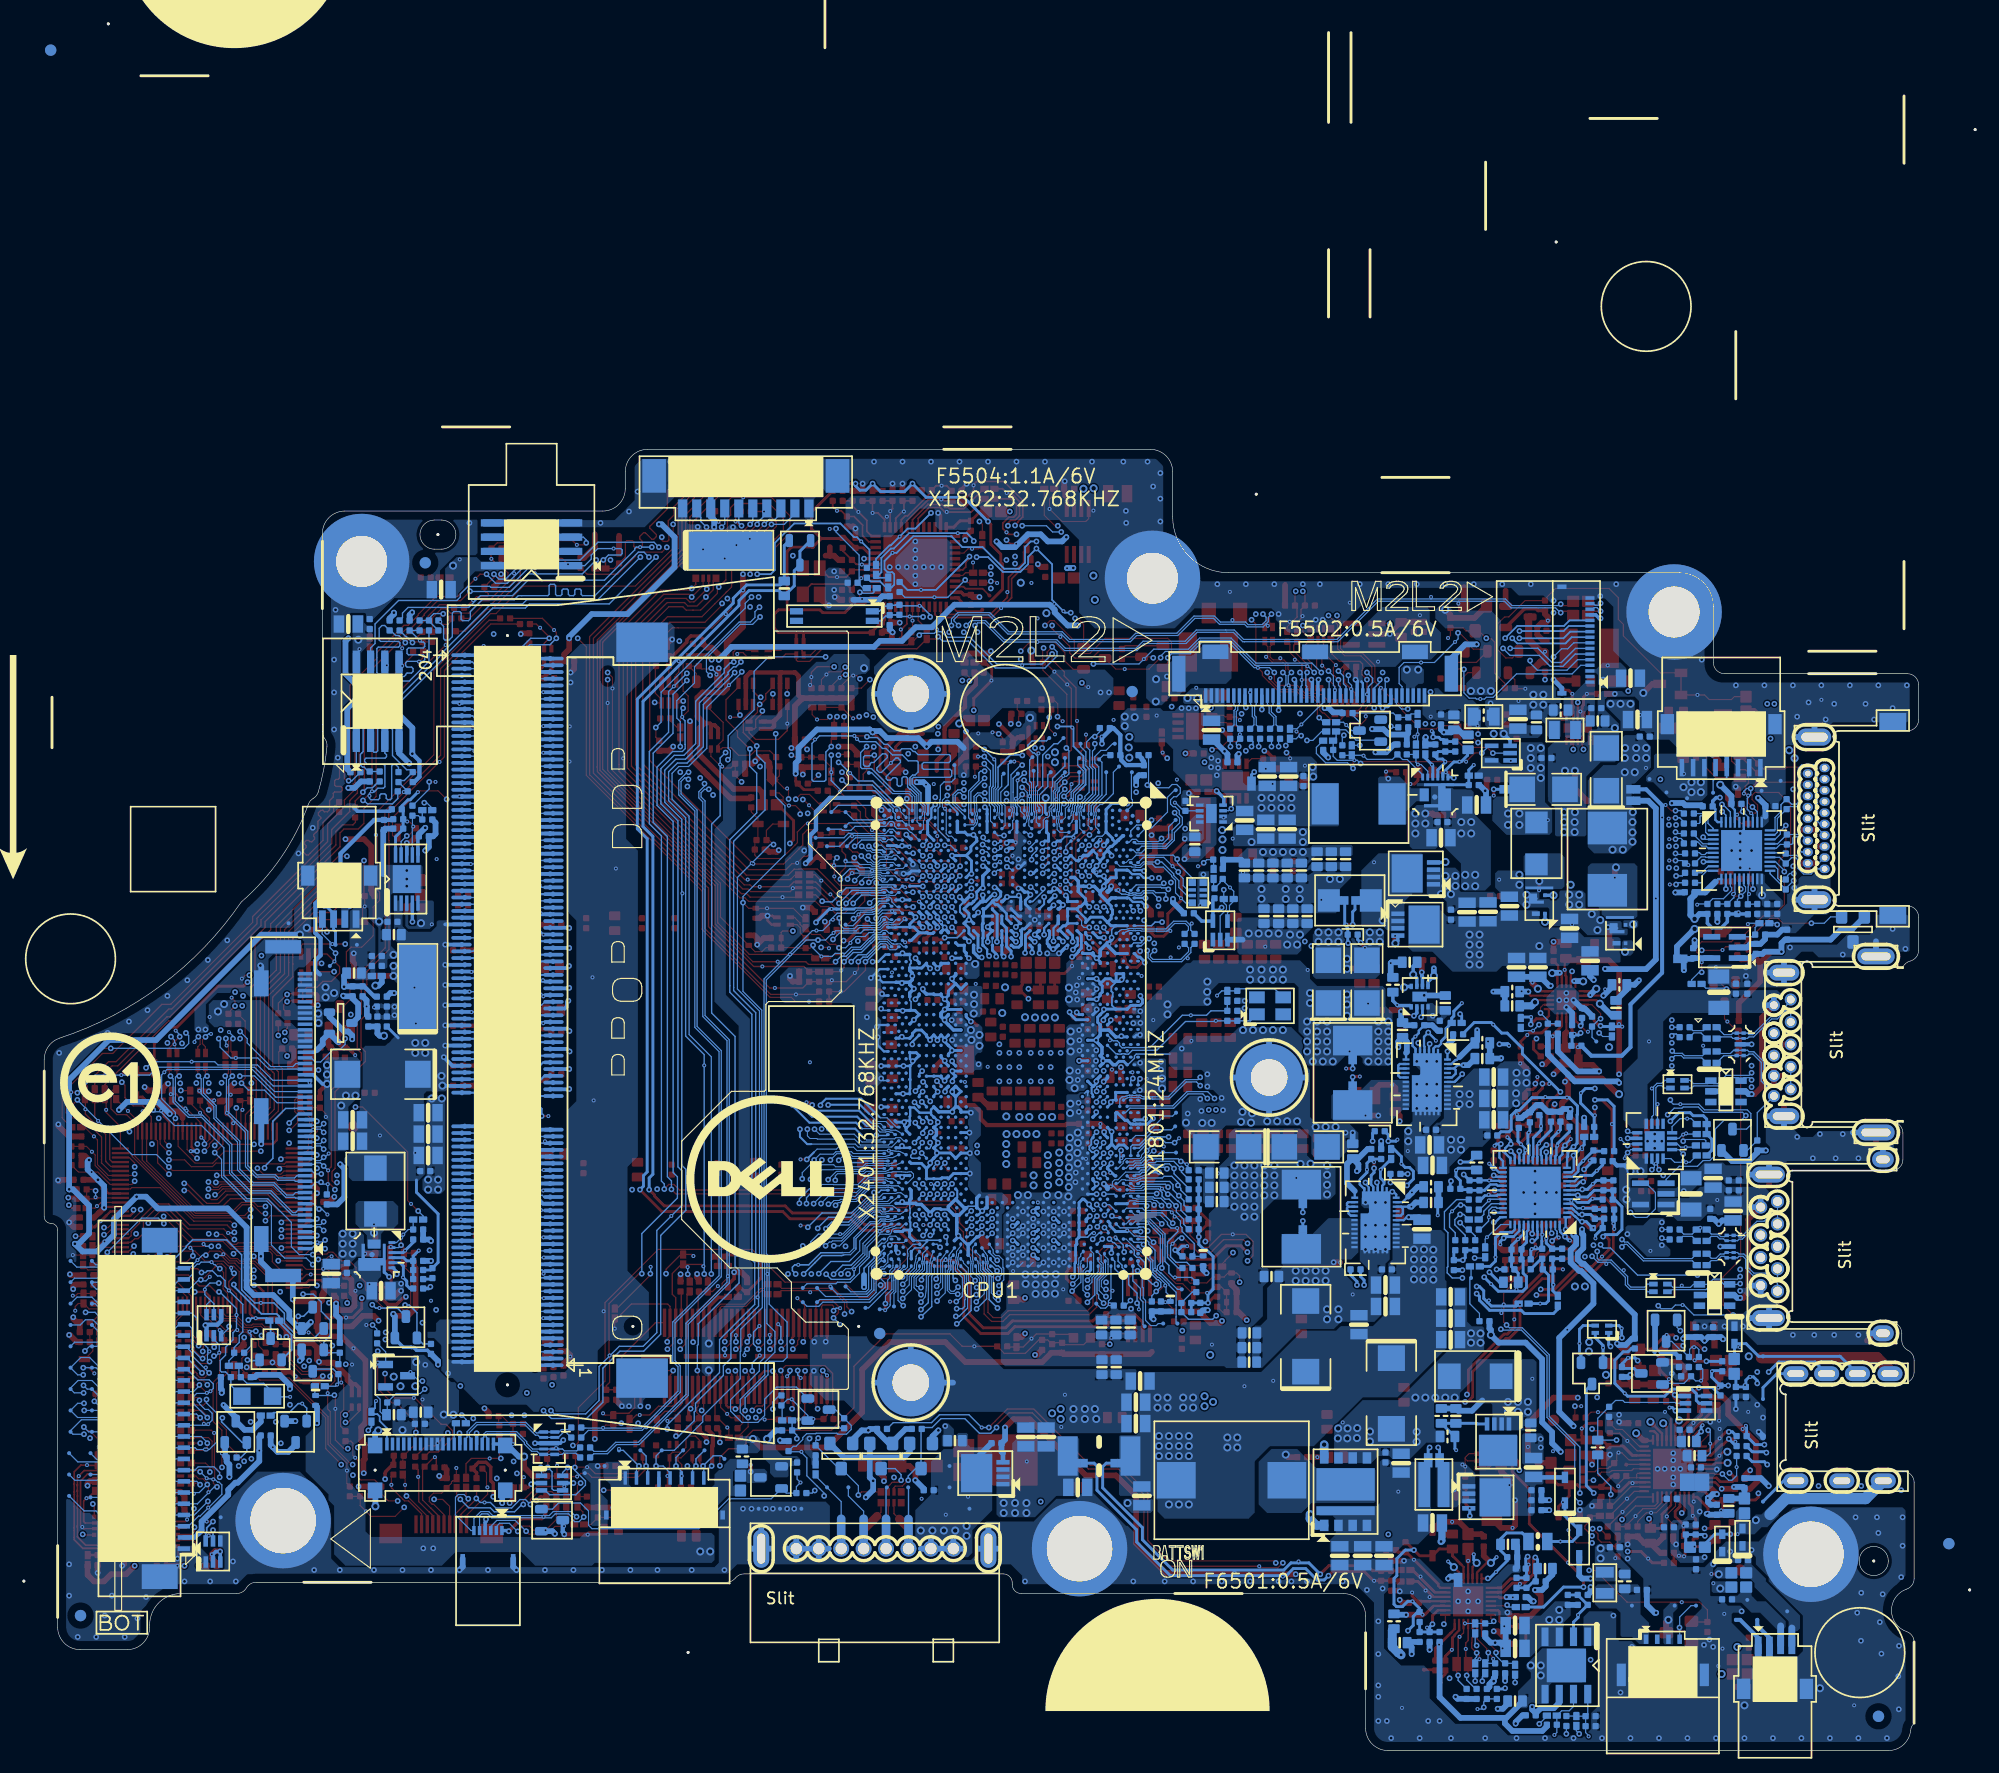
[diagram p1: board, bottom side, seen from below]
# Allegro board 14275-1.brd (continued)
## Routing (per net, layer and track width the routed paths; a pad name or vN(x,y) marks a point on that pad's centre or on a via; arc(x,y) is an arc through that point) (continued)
PCH_SMBCLK: length 108.5
  TOP w0.114: Q1801.4 105.2,94.81 106.31,93.7 106.31,91.88 105.29,90.86 105.29,90.37 104.22,89.29 v2(104.18,89.29) ; R9912.1 111.6,28.63 v2(111.56,28.67) ; R7014.1 123.22,100.42 v1(122.89,100.09) 122.08,99.28 v2(122.08,99.15) 122.53,98.7 RN1810.3
  L3 w0.114: v2(122.08,99.15) 121.64,98.72 121.06,98.72 120.63,98.29 114.22,98.29 105.23,89.29 104.19,89.29 v2(104.18,89.29)
  BOTTOM w0.114: DIMM1.202 128.94,97.05 128.68,96.79 126.09,96.79 123.73,99.15 v2(122.08,99.15) ; v2(111.56,28.67) 111.56,29.03 106.9,33.69 106.9,36.63 103.76,39.77 103.76,43.5 104.01,43.76 104.01,65.64 105.98,67.61 105.98,68.17 105.98,81.19 103.58,83.59 103.58,87.13 104.21,87.76 104.21,89.27 v2(104.18,89.29)
PCH_SMBDATA: length 110.1
  TOP w0.114: RN1810.4 121.88,98.72 v2(121.44,99.15) 121.44,99.69 v1(121.65,99.89) 122.69,100.93 R7016.1 ; R9911.1 110.62,28.19 v2(110.78,28.03) ; Q1801.1 103.9,92.86 104.78,91.99 104.78,90.75 v2(103.58,89.56)
  L3 w0.114: v2(103.58,89.56) 103.93,89.9 105.2,89.9 113.93,98.63 120.41,98.63 120.94,99.15 v2(121.44,99.15)
  BOTTOM w0.114: DIMM1.200 125.95,96.45 123.82,98.58 122.02,98.58 v2(121.44,99.15) ; v2(110.78,28.03) 110.52,28.03 109.15,29.41 109.15,30.18 109.04,30.3 109.04,30.96 106.55,33.44 106.55,34.29 105.88,34.96 105.88,37.17 103.42,39.63 103.42,43.65 103.67,43.9 103.67,65.78 105.64,67.75 105.64,68.03 105.64,68.03 105.64,81.05 102.84,83.85 102.84,88.04 103.58,88.78 v2(103.58,89.56)
PCH_THERMTRIP#: length 10.4
  BOTTOM w0.102: EC401.1 63.82,44.06 R419.2 64.74,44.25 64.57,44.41 64.57,45.21 65.66,46.29 65.66,46.63 65.81,46.77 65.81,47.2 v1(66.58,47.97) 66.75,48.15 69,48.15 69.21,48.35 70.61,48.35 CPU1.C63
PCH_WAKE#: length 4.5
  TOP w0.102: R1703.2 95.61,73.51 v2(94.95,74.17)
  BOTTOM w0.102: v2(94.95,74.17) 94.88,74.17 v1(94.5,74.54) 94.31,74.73 93.25,74.73 93.19,74.79 92.8,74.79 92.32,75.27 CPU1.BB15
PCI_CLK_LPC0: length 9.9
  TOP w0.114: R1804.1 95.98,80.17 95.66,79.85 v1(95.66,79.27) 95.66,78.73 96.12,78.27 v2(96.12,77.68)
  BOTTOM w0.089: 94.52,78.45 94.47,78.4 93.47,78.4 93.39,78.48 92.52,78.48 92.52,78.48 92.09,78.48 91.98,78.51 91.31,78.51 91.18,78.64 90.54,78.64 CPU1.AW9
  BOTTOM w0.114: v2(96.12,77.68) 96.12,77.77 95.31,78.58 95.24,78.58 95.23,78.58 94.65,78.58 94.52,78.45
PCI_CLK_LPC1: length 7.5
  TOP w0.114: v2(94.26,79.75) 94.61,80.1 95.04,80.1 95.34,80.41 95.34,80.87 95.08,81.13 v1(95.08,81.53) 95.44,81.88 R1805.1
  BOTTOM w0.089: CPU1.AY9 91.15,78.92 91.41,79.18 92.57,79.18 92.74,79.01 93.22,79.01 93.39,79.19 93.69,79.19
  BOTTOM w0.114: v2(94.26,79.75) 93.69,79.19
PCIE_CLK_XDP_N: length 47.9
  TOP w0.102: 97.01,41.21 101.36,41.21 R9923.1 ; 97.01,41.21 v1(97.01,41.37) ; 97.01,41.21 96.72,41.21 95.55,40.03 95.55,39.56 v2(95.12,39.13)
  L3 w0.102: v2(95.12,39.13) 95.55,39.56 95.55,39.96 95.03,40.48 92.49,40.48 91.47,41.5 91.47,42.34 90.77,43.03 86.47,43.03 84.92,44.59 84.92,46.15 85.17,46.41 85.17,48.65 83.67,50.15 83.67,52.34 83.47,52.54 83.47,53.24 83.47,53.49 v2(83.93,53.94)
  L6 w0.102: v2(73.28,58.77) 73.51,59.01 73.96,59.01 74.67,58.3 76.19,58.3 76.99,57.5 82.66,57.5 83,57.16 83,55.76 83.65,55.11 84.22,54.53 84.37,54.39 84.37,54.06 84.26,53.94 v2(83.93,53.94)
  BOTTOM w0.102: CPU1.F43 73.2,59.21 73.28,59.13 v2(73.28,58.77)
PCIE_CLK_XDP_P: length 48.4
  TOP w0.102: 98.81,41.01 96.81,41.01 95.75,39.95 v2(95.75,38.92) ; 98.81,41.01 v1(98.81,40.86) ; 98.81,41.01 101.4,41.01 R9913.1
  L3 w0.102: v2(83.93,53.31) 83.67,53.05 83.67,52.62 83.88,52.42 83.88,50.24 85.38,48.74 85.38,46.32 85.12,46.07 85.12,44.67 86.56,43.24 90.86,43.24 91.68,42.42 91.68,41.58 92.57,40.68 95.11,40.68 95.75,40.05 v2(95.75,38.92)
  L6 w0.102: v2(83.93,53.31) 84.59,53.97 84.59,54.48 84.38,54.69 83.22,55.85 83.22,57.24 82.75,57.71 77.08,57.71 76.28,58.51 74.76,58.51 74.05,59.22 73.12,59.22 72.64,58.75 v2(72.64,58.73)
  BOTTOM w0.102: v2(72.64,58.73) 72.64,58.88 CPU1.E43
PCIE_CLK_XDP_R_N: length 7.7
  TOP w0.102: v1(102.62,42.49) 102.62,41.59 R9923.2 102.99,41.19 103.24,41.19 104.64,39.8 106.81,39.8 107.3,39.3 XDP1.42
PCIE_CLK_XDP_R_P: length 6.5
  TOP w0.102: XDP1.40 106.8,39.3 106.84,39.33 106.84,39.48 106.72,39.59 104.55,39.59 103.63,40.52 ; R9913.2 102.91,40.99 103.16,40.99 103.63,40.52 ; 103.63,40.52 v1(103.51,40.4)
PCIE_RCOMPN: length 2.6
  TOP w0.305: v1(74.76,79.6) 74.26,79.6 R1604.1 73.88,80 73.28,80.6 v2(73.28,80.7)
  BOTTOM w0.305: v2(73.28,80.7) 73.28,80.83 CPU1.F5
PCIE_RCOMPP: length 2.1
  TOP w0.305: R1604.2 72.99,80.23 72.63,80.59 v2(72.63,80.7) 72.63,80.88 v1(72.96,81.2)
  BOTTOM w0.305: CPU1.E5 72.31,81.02 v2(72.63,80.7)
PCIE_RX_CPU_N5: length 131.1
  L6 w0.102: v2(73.28,75.21) 73.28,74.98 73.29,74.97 73.29,74.86 73.4,74.75 74.99,74.75 75.54,74.2 77.6,74.2 78.21,74.81 82.78,74.81 83.77,73.81 84.05,73.81 85.31,72.55 85.31,72.34 86.34,71.31 87.23,71.31 87.83,71.31 88.74,72.23 89.25,72.23 90.85,73.82 90.85,75.22 92.56,76.93 94.04,76.93 94.04,76.93 96.29,76.93 97.07,77.71 99.75,77.71 106.81,84.77 106.81,85.92 109.88,88.99 113.15,88.99 118.73,94.57 118.73,96.95 120.45,98.67 122.51,98.67 122.62,98.79 124.76,98.79 125.06,98.49 126.6,98.49 126.89,98.77 128.19,98.77 131.41,95.55 131.41,85.71 132.2,84.92 132.2,75.79 132.86,75.13 132.86,73.61 134.21,72.26 134.21,66.6 136.1,64.71 137.22,64.71 139.48,62.45 139.48,60.39 141.93,57.94 143.26,57.94 144.34,56.86 144.34,54.01 143.8,53.47 143.8,52.84 143.3,52.34 142.42,52.34 v2(142.19,52.11)
  BOTTOM w0.102: CPU1.F16 72.96,74.88 v2(73.28,75.21) ; v1(141.79,51.72) v2(142.19,52.11) 142.47,52.39 142.91,52.39 143.05,52.25 IOBD1.16
PCIE_RX_CPU_P5: length 131
  L6 w0.102: v2(142.19,52.89) 142.52,52.55 143.21,52.55 143.58,52.93 143.58,53.56 144.13,54.1 144.13,56.77 143.17,57.72 141.84,57.72 139.26,60.3 139.26,62.36 137.13,64.5 136.01,64.5 134,66.51 134,72.17 132.64,73.52 132.64,75.04 131.99,75.7 131.99,84.83 131.2,85.62 131.2,95.46 128.1,98.56 126.98,98.56 126.69,98.27 124.97,98.27 124.67,98.57 122.71,98.57 122.6,98.46 120.53,98.46 118.94,96.86 118.94,94.48 113.24,88.78 109.97,88.78 107.03,85.83 107.03,84.68 99.84,77.49 97.16,77.49 96.38,76.71 93.95,76.71 93.95,76.72 92.65,76.72 91.06,75.13 91.06,73.73 89.34,72.01 88.83,72.01 87.92,71.1 87.18,71.1 86.25,71.1 85.09,72.25 85.09,72.46 83.96,73.59 83.68,73.59 82.69,74.59 78.3,74.59 77.69,73.98 75.45,73.98 74.9,74.54 73.31,74.54 73.08,74.77 v2(72.63,75.21)
  BOTTOM w0.102: v1(141.74,53.22) 142.07,52.89 v2(142.19,52.89) 142.48,52.6 142.9,52.6 143.05,52.75 IOBD1.17 ; CPU1.E16 72.31,75.01 72.5,75.21 v2(72.63,75.21)
PCIE_TX_CPU_N5: length 7.3
  BOTTOM w0.089: 67.93,73.04 67.95,73.04 67.96,73.05 69.3,73.05 69.37,73.12 69.69,73.12 69.79,73.08 70.05,73.08 70.05,73.08 70.14,73.12 70.32,73.12 70.42,73.09 70.42,73.09 70.53,73.05 arc(70.57,73.03) 70.62,73.01 70.66,72.98 CPU1.C19
  BOTTOM w0.102: 66.85,73.21 v1(66.71,73.07) ; 66.85,73.21 67.01,73.04 67.93,73.04 ; 66.85,73.21 66.33,73.73 65.37,73.73 65.09,73.45 65.09,73.15 C1601.2
PCIE_TX_CPU_P5: length 8.3
  BOTTOM w0.089: CPU1.D19 71.53,72.86 71.04,73.2 70.69,73.2 70.35,73.3 70.1,73.3 70.01,73.26 69.82,73.26 69.72,73.3 69.28,73.3 69.22,73.24 67.96,73.24 67.95,73.25 67.93,73.25
  BOTTOM w0.102: 64.94,73.59 64.89,73.53 64.89,73.15 C1602.2 ; 64.94,73.59 v1(64.8,73.73) ; 64.94,73.59 65.29,73.93 66.41,73.93 67.1,73.25 67.93,73.25
PCIE_TX_WLAN_N5: length 138.2
  L6 w0.102: v2(68.11,71.32) 68.73,71.94 69.84,71.94 70.04,71.74 71.58,70.21 74.39,70.21 74.99,69.6 81.18,69.6 81.93,68.85 85.25,68.85 85.75,68.35 88.3,68.35 88.51,68.56 89.83,68.56 91.74,70.46 91.74,71.28 94.14,73.68 95.34,73.68 95.34,73.68 96.35,73.68 97.22,74.55 99.73,74.55 119.45,94.27 119.45,96.65 120.75,97.95 122.81,97.95 122.91,98.05 124.25,98.05 124.69,97.61 126.76,97.61 127.2,98.05 127.89,98.05 130.69,95.25 130.69,84.56 131.48,83.77 131.48,75.41 132.09,74.79 132.09,73.23 133.48,71.83 133.48,65.89 138.61,60.76 138.61,57.08 139.25,56.44 141.2,56.44 141.7,56.94 142.99,56.94 143.53,56.4 143.53,54.22 143.21,53.9 142.48,53.9 v2(142.19,53.61)
  BOTTOM w0.102: 66.68,70.53 65.78,70.53 65.08,71.22 65.08,71.56 C1601.1 ; 66.68,70.53 v1(66.68,70.71) ; 66.68,70.53 68.25,70.53 68.49,70.77 68.49,70.96 68.13,71.32 v2(68.11,71.32) ; IOBD1.19 143.05,53.75 142.91,53.9 142.47,53.9 v2(142.19,53.61)
PCIE_TX_WLAN_P5: length 137.3
  L6 w0.102: v2(142.19,54.39) 142.45,54.12 143.12,54.12 143.31,54.31 143.31,56.31 142.9,56.73 141.79,56.73 141.29,56.22 139.16,56.22 138.4,56.99 138.4,60.67 133.27,65.8 133.27,71.74 131.88,73.14 131.88,74.7 131.26,75.32 131.26,83.68 130.47,84.47 130.47,95.16 127.8,97.83 127.29,97.83 126.85,97.4 124.6,97.4 124.16,97.83 123,97.83 122.9,97.73 120.84,97.73 119.67,96.56 119.67,94.36 119.67,94.18 99.82,74.33 97.31,74.33 96.44,73.46 95.25,73.46 95.25,73.46 94.23,73.46 91.95,71.19 91.95,70.38 89.92,68.34 88.6,68.34 88.59,68.33 88.58,68.33 88.39,68.14 85.66,68.14 85.16,68.64 81.84,68.64 81.09,69.39 74.9,69.39 74.3,69.99 71.49,69.99 69.78,71.7 69.75,71.72 69.17,71.72 v2(68.76,71.32)
  BOTTOM w0.102: C1602.1 64.88,71.58 64.88,71.14 65.27,70.75 ; 65.27,70.75 65.69,70.33 68.33,70.33 68.69,70.68 68.69,71.24 v2(68.76,71.32) ; 65.27,70.75 v1(65.16,70.63) ; v2(142.19,54.39) 142.47,54.1 142.91,54.1 143.05,54.25 IOBD1.20
PECI_EC: length 5.2
  TOP w0.114: KBC24.94 144.09,42.07 143.71,42.44 v1(143.34,42.44) 142.03,42.44 141.64,42.06 141.64,41.82 C2405.1 R2437.1
PEG_CLK1_CPU: length 137.4
  TOP w0.102: v1(68.82,59.89) v2(69.41,59.89)
  L6 w0.102: v2(69.41,59.89) 69.67,59.63 69.67,59.37 70.01,59.02 71.15,59.02 71.79,59.66 71.79,61.56 70.48,62.87 70.48,64.14 70.82,64.48 70.82,67.2 72.89,69.27 73.89,69.27 74.49,68.66 79.64,68.66 81.03,67.28 82.96,67.28 83.6,67.91 84.74,67.91 85.24,67.41 87.78,67.41 88.93,66.26 89.69,66.26 92.31,68.88 92.31,69.35 92.68,69.72 92.68,70.89 94.53,72.74 99.25,72.74 121.19,94.68 121.19,95.34 122.42,96.58 128.04,96.58 129.75,94.86 129.75,84.17 130.54,83.38 130.54,74.94 131.15,74.32 131.15,72.71 131.43,72.43 132.54,71.32 132.54,65.5 137.48,60.57 137.48,56.6 138.7,55.38 141.92,55.38 v2(142.19,55.11)
  BOTTOM w0.102: CPU1.A42 69.59,59.7 v2(69.41,59.89) ; IOBD1.22 143.05,55.25 142.91,55.4 142.47,55.4 v2(142.19,55.11)
PEG_CLK1_CPU#: length 137.1
  TOP w0.102: v2(70.05,59.91) 70.05,60.43 v1(70.09,60.47)
  L6 w0.102: v2(70.05,59.91) 69.88,59.75 69.88,59.46 70.1,59.24 71.06,59.24 71.57,59.75 71.57,61.47 70.26,62.78 70.26,64.23 70.61,64.57 70.61,67.29 72.8,69.48 73.98,69.48 74.58,68.88 79.73,68.88 81.12,67.49 82.87,67.49 83.51,68.13 84.83,68.13 85.33,67.63 87.87,67.63 89.02,66.48 89.6,66.48 92.09,68.97 92.09,69.44 92.46,69.81 92.46,70.98 94.44,72.95 99.16,72.95 120.97,94.77 120.97,95.43 122.33,96.79 128.13,96.79 129.97,94.95 129.97,84.26 130.75,83.47 130.75,75.02 131.37,74.41 131.37,72.8 132.17,72 132.76,71.41 132.76,65.59 137.69,60.65 137.69,56.69 138.79,55.59 141.89,55.59 v2(142.19,55.89)
  BOTTOM w0.102: CPU1.B42 70.24,59.71 v2(70.05,59.91) ; v2(142.19,55.89) 142.47,55.6 142.91,55.6 143.05,55.75 IOBD1.23
PIRQA#: length 6.5
  TOP w0.102: R1607.2 96.66,78.76 v1(96.66,77.93) 96.66,77.9 96.65,77.9 96.65,77.6 96.18,77.13 94.65,77.13 94.43,77.36 v2(94.22,77.36)
  BOTTOM w0.089: CPU1.BB11 92.4,77.69 92.66,77.94 93.17,77.94 93.27,77.85 93.96,77.85 94.22,77.59 v2(94.22,77.36)
PLT_RST#: length 142.2
  TOP w0.102: R1713.1 96.93,87.66 R1715.1 EC1703.1 C1701.1 100.11,88.55 100.3,88.74 v2(100.49,88.74) ; v2(104.17,104.87) 104.17,105 100.62,108.55 100.62,110.08 102.27,111.73 v1(104.78,111.73) 105.82,111.73 106.39,111.16 R6802.1 ; R2410.2 149.41,59.49 v2(149.51,59.49) 149.51,59.62 149.18,59.94 149.18,65.03 149.81,65.66 EC6602.1
  L3 w0.102: v2(104.17,104.87) 102.9,103.6 102.9,101.76 103.15,101.5 103.45,101.5 103.71,101.24 103.71,100.81 99.3,96.39 99.3,91.79 99.87,91.22 99.87,89.36 v2(100.49,88.74)
  L4 w0.102: v2(100.49,88.74) 100.99,88.74 102.64,90.39 106,90.39 109.63,94.02 111.57,94.02 118.94,101.39 123.25,101.39 123.43,101.21 126.91,101.21 130.3,97.81 130.3,97.43 132.51,95.23 132.51,87.24 133.65,86.1 133.65,83.68 133.36,83.4 133.36,83.37 132.7,82.71 132.7,79.3 133.88,78.12 133.88,75.26 137.14,72 137.14,69.87 138.77,68.24 138.77,67.74 141.69,64.82 141.69,62.67 141.05,62.03 141.05,59.49 141.85,58.69 143.5,58.69 144.95,60.14 148.89,60.14 149.27,59.77 149.27,59.74 v2(149.51,59.49)
  BOTTOM w0.102: v2(149.51,59.49) 148.89,58.88 147.46,58.88 146.34,57.75 IOBD1.27
PLT_RST#_DEBUG: length 3.4
  TOP w0.102: v2(106.71,109.06) 106.71,109.26 v1(106.99,109.54) 107.28,109.84 R6802.2
  BOTTOM w0.102: DB1.7 106.43,110.73 106.43,109.35 v2(106.71,109.06)
PM_PCH_PWROK: length 11
  TOP w0.102: RN1703.3 100.21,74.28 99.72,73.79 99.72,73.66 99.38,73.31 R1706.2 98.66,72.75 97.95,72.75 97.07,71.87 96.56,71.87 v2(96.25,71.57)
  BOTTOM w0.102: v2(96.25,71.57) 95.65,71.57 v1(95.22,72) 95.22,72.1 94.75,72.57 93.92,72.57 93.56,72.92 92.9,72.92 92.56,72.92 92.37,73.11 92.04,73.11 91.77,72.85 CPU1.BA20
PM_RSMRST#: length 158.3
  TOP w0.102: R1720.2 162.52,31.25 v2(162.63,31.14) ; v2(104.62,30.32) 104.81,30.13 104.81,29.22 R9904.1 ; R1702.1 112.62,96.61 112.62,94.27 112.06,93.71 Q1701.3 112.63,93.39 v2(112.68,93.44) ; RN1703.4 99.98,73.63 99.7,73.35 99.7,72.9 R1704.1 99.05,72.26 v2(98.12,72.26)
  L3 w0.102: v2(112.68,93.44) 112.68,92.75 101.06,81.14 101.06,78.78 98.89,76.6 98.89,73.8 98.69,73.6 98.69,72.83 v2(98.12,72.26) ; v2(124.08,31.88) 123.65,31.88 122.93,31.17 121.51,31.17 121.23,30.88 117.57,30.88 116.8,30.11 110.95,30.11 109.85,31.22 108.24,31.22 106.83,29.8 105.13,29.8 v2(104.62,30.32)
  L4 w0.102: v2(157.05,28.58) 155.11,28.58 153.5,26.97 152.74,26.97 152.74,26.97 152.23,26.97 151.68,27.52 149.97,27.52 149.58,27.13 147.57,27.13 146.67,26.23 143.17,26.23 140.67,28.73 140.06,28.73 139.64,29.14 139.64,29.45 139.47,29.61 139.47,29.62 138,31.1 133.56,31.1 132.26,31.1 132.01,31.35 129.42,31.35 129.38,31.4 129.37,31.4 129.01,31.77 128.85,31.77 127.21,31.77 126.51,31.07 124.89,31.07 v2(124.08,31.88)
  BOTTOM w0.089: CPU1.AY17 91.15,74.07 91.43,73.79 91.56,73.79 91.78,73.85 92.02,73.85 92.16,73.79 92.23,73.77 92.62,73.37 92.64,73.37
  BOTTOM w0.102: 92.64,73.37 94.42,73.37 94.71,73.08 94.8,73.08 95.89,73.08 95.89,73.08 96.54,73.08 v1(96.73,72.89) 96.88,72.74 96.96,72.74 97.44,72.26 v2(98.12,72.26) 99.17,72.26 102.72,68.7 102.72,44.29 102.47,44.04 102.47,39.8 100.87,38.19 100.87,35.07 101.24,34.7 102.46,34.7 102.57,34.59 102.57,33.5 104.62,31.45 v2(104.62,30.32) ; v2(162.63,31.14) 162.03,30.54 161.71,30.54 160.51,29.34 158.97,29.34 158.21,28.58 v2(157.05,28.58)
PM_RSMRST#_M: length 31.1
  TOP w0.102: R1737.2 161.64,32.66 v2(162.11,33.12)
  L4 w0.102: v2(151.53,41.68) 152.18,41.68 152.53,41.33 156.22,41.33 156.94,42.04 157.29,42.04 157.85,41.48 158.34,41.48 158.5,41.33 158.79,41.33 160.57,43.11 161.91,43.11 162.09,42.93 162.09,41.51 161.93,41.35 161.93,39.58 160.53,38.18 160.53,37.16 159.91,36.53 159.91,34.46 160.4,33.97 160.4,33.44 160.85,32.99 161.97,32.99 v2(162.11,33.12)
  BOTTOM w0.102: 152.26,40.12 152.63,39.75 Q1702.6 ; 152.26,40.12 151.98,39.84 Q1702.5 ; 152.26,40.12 152.78,40.64 v1(152.78,41.1) 152.78,41.24 152.34,41.68 v2(151.53,41.68)
PM_RSMRST#_R: length 17.4
  TOP w0.102: v2(161.97,31.12) 161.63,31.45 R1720.1
  L4 w0.102: v2(161.97,31.12) 161.9,31.12 160.98,32.03 159.82,32.03 159.19,32.67 159.19,33.92 158.6,34.51 155.12,34.51 154.24,35.38 154.24,36.14 153.82,36.56 152.86,36.56 152.48,36.18 152.48,35.66 152.02,35.21 152,35.21 v2(151.97,35.17)
  BOTTOM w0.102: Q1702.2 151.98,36.65 151.49,36.16 151.49,35.48 v1(151.5,35.47) 151.79,35.17 v2(151.97,35.17)
PM_RSMRST_PWRGD_XDP: length 3.5
  TOP w0.102: XDP1.39 106.8,30.6 v1(106.22,30.02) 105.86,29.66 105.33,29.66 R9904.2
PME#: length 3.6
  TOP w0.102: TP1707.1 91.09,78.16 90.67,77.74 90.3,77.74 89.89,78.15 89.53,78.15 89.33,77.95 v2(88.77,77.95)
  BOTTOM w0.102: v2(88.77,77.95) 89.1,77.63 CPU1.AU11
POWER_SW_IN#: length 6.6
  TOP w0.102: R2432.2 159.63,35.53 159.61,35.55 R2451.1 160.05,36.35 160.05,36.86 C2426.1 160.5,37.55 159.93,38.12 v1(159.16,38.12) 158.79,38.12 158.36,38.55 KBC24.127
PQ3802_1: length 8.2
  TOP w0.305: PR4304.2 33.92,101.63 34.07,101.78 35.14,101.78 PQ4301.B
  TOP w0.508: PR4302.1 33.46,98.94 34,99.48 34,100.14 33.59,100.55 33.23,100.55 v1(33.05,100.73) 33.05,101.06 33.31,101.31 PR4304.2
PRE: length 4.6
  TOP w0.102: v2(15.86,76.17) 16.36,76.17 v1(16.54,76.35) 16.54,77.22 R5416.2
  BOTTOM w0.102: U5701.16 15.58,77.14 15.42,76.98 15.42,76.6 v2(15.86,76.17) 16.16,75.86 R5415.2
PROC_SELECT#: length 5.6
  TOP w0.102: R603.1 68.04,46.39 v2(67.47,46.96) 67.52,47.01 v1(68.79,47.01)
  BOTTOM w0.089: CPU1.C64 70.51,47.57 68.08,47.57 v2(67.47,46.96)
PS_ID: length 2.6
  TOP w0.102: PQ4302.S 36,95.46 PR4306.1 35.94,94.66 v1(35.06,94.66)
PS_ID_R: length 10.6
  TOP w0.635: PR4301.1 14.71,92.63 v2(14.38,92.3)
  BOTTOM w0.102: DCIN1.4 17.1,86.76 17.2,86.66 18.12,86.66 18.32,86.45 AFTP4305.1
  BOTTOM w0.406: v2(14.38,92.3) 14.54,92.14 15.17,92.14 17.1,90.22 DCIN1.4
PS_ID_R2: length 35.4
  TOP w0.102: PQ4302.D 36.22,97.4 36.8,97.4 37.57,98.17 37.57,100.4 36.91,101.06 36.54,101.06 35.08,102.52 PR4304.1 33.31,102.64 32.35,103.6 27.59,103.6 26.76,102.77 26.76,100.84 26.32,100.39 26.32,99.38 23.02,96.08 PD4301.1 PD4301.2 v1(19.72,94.11) 19.08,94.11 18.67,93.69 16.69,93.69 16.43,93.95 15.39,93.95 PR4301.2
PSID: length 180.8
  TOP w0.114: v2(160.18,59.58) 159.9,59.3 159.9,58.2 159.17,57.47 158.3,57.47 157.96,57.14 157.96,56.91 157.56,56.5 KBC24.36 ; PR4306.2 36.89,95.14 37.8,96.05 37.8,98.82 38.08,99.1 38.48,99.1 v2(38.54,99.16) 39.19,99.82 PD4302.3 40.34,99.82 40.6,100.08 PR4305.2 41.74,99.39 v1(41.95,99.18)
  L3 w0.114: v2(160.18,59.58) 160.18,62.77 156.66,66.29 155.99,66.29 143.29,78.99 143.29,81.5 141.07,83.72 141.07,87.17 140.44,87.81 140.44,98.81 140.44,98.81 140.44,99.28 140.44,99.28 140.44,99.5 140.13,99.81 139.76,99.81 133.41,106.17 132.04,106.17 131.48,106.72 130.34,106.72 128.19,108.88 114.77,108.88 112.17,111.47 80.13,111.47 77.3,108.64 77.3,103.94 71.25,97.88 66.62,97.88 65.81,97.08 52.98,97.08 52.97,97.09 48.79,97.09 48.54,97.33 46.84,97.33 46.47,97.7 44.32,97.7 43.65,98.36 40.43,98.36 39.63,99.15 38.55,99.15 v2(38.54,99.16)
PSID_DISABLE#_R_C: length 6.6
  TOP w0.635: PQ4301.C 34.77,100.92 34.77,99.02 33.71,97.96 v1(33.31,97.96) PR4303.2 33.67,97.06 PQ4302.G
PSYS: length 7.9
  TOP w0.102: v1(35.85,41.11) 35.85,41.47 35.4,41.92 PR4632.2 34.37,43.06 34.37,43.75 34.02,44.1 34.02,44.32 33.71,44.63 33.71,45.12 v2(32.71,46.12) 32.7,46.14 PR4615.1
  BOTTOM w0.102: PU4601.46 32.79,46.2 v2(32.71,46.12)
PTP_DIS#: length 53.8
  TOP w0.102: KBC24.90 v2(146.23,43.67)
  L3 w0.102: v2(110.78,25.37) 111.54,26.14 118.15,26.14 119.77,27.76 120.19,27.76 120.4,27.54 120.4,27.45 121.18,26.67 122.6,26.67 123.86,25.41 123.86,24.77 124.79,23.83 128.42,23.83 132.18,27.59 132.44,27.59 139.27,34.42 139.27,35.15 141.1,36.98 143.03,36.98 143.96,37.91 143.96,37.92 143.97,37.93 143.97,38.84 144.58,39.45 145.06,39.45 145.62,40.01 145.62,41.51 145.99,41.88 145.99,43.43 v2(146.23,43.67)
  BOTTOM w0.102: TP1.6 110.3,24.89 v2(110.78,25.37) 110.78,26.13 AFTP6537.1
PTP_INT#_EC: length 3.7
  TOP w0.102: KBC24.33 158.76,56.14 v1(159.64,57.02) R2431.2
PU4902_S5: length 5.1
  TOP w0.102: v2(134.78,81.54) 134.65,81.54 PC5119.1 134.56,82.82 v1(134.74,82.82) 135.05,82.82 PR5114.2
  BOTTOM w0.102: v2(134.78,81.54) 135.28,81.04 PU5102.9
PU4902_VCNTL: length 6.6
  BOTTOM w0.254: PU5102.10 135.78,81.45 135.1,82.14 PC5111.1 PR5117.1 135.1,83.79 PR5118.1 135.22,84.2 134.67,84.75 134.47,84.75 v1(133.79,85.44)
PURE_HW_SHUTDOWN#: length 66.1
  L3 w0.102: v2(133.38,32.94) 133.25,32.94 132.16,31.85 132.16,29.86 131.67,29.36 129.58,29.36 128.95,28.74 128.29,28.74 126.72,27.17 124.26,27.17 123.78,26.69 123.78,25.99 124.16,25.6 124.16,24.89 124.89,24.16 126.65,24.16 v2(126.75,24.26)
  L4 w0.102: v2(97.57,22.7) 97.7,22.57 105.01,22.57 106,21.58 115.12,21.58 115.95,22.41 116.67,22.41 116.83,22.24 121.25,22.24 123.18,24.17 124.62,24.17 124.63,24.16 126.65,24.16 v2(126.75,24.26)
  BOTTOM w0.102: v2(133.38,32.94) 133.69,32.94 134.17,33.42 D4001.3 ; Q2602.D 96.56,30.4 R2615.1 95.16,28.99 95.16,28.62 95.57,28.21 96.34,28.21 96.43,28.29 98.28,28.29 98.32,28.25 99.13,28.25 99.48,27.9 99.48,27.72 100.07,27.13 100.32,27.13 C2610.1 100.68,26.64 v1(99.6,26.64) 99.55,26.59 99.55,26.53 99.11,26.09 99.11,24.5 98.23,23.62 97.57,22.95 v2(97.57,22.7)
PWR_1D0V_BOOT: length 2.7
  TOP w0.254: PR5210.1 v1(42.15,87.22) 41.87,87.22 41.43,86.79 v2(41.43,86.71)
  BOTTOM w0.254: v2(41.43,86.71) 41.51,86.79 PU5202.6
PWR_1D0V_BOOT_A: length 2.9
  TOP w0.254: PC5217.1 45.69,86.37 45.48,86.16 v1(45.31,86.16) 44.95,86.16 44.63,86.48 PR5210.2
PWR_1D0V_BYP: length 3.9
  BOTTOM w0.254: PU5202.7 40.13,86.1 PC5219.1 PR5214.1 40.1,87.41 v1(39.66,87.86)
PWR_1D0V_EN: length 8.4
  BOTTOM w0.102: PU5202.1 44.21,86.98 45.58,88.35 46.01,88.35 PC5220.1 46.91,88.36 49.16,88.36 v1(49.49,88.69) 49.52,88.73 PR5215.2 PR5217.2
PWR_1D0V_FB: length 4.8
  BOTTOM w0.254: PC5218.2 PR5216.2 42.83,89.06 PR5213.1 43.09,88.61 42.86,88.39 42.43,88.39 v1(42.2,88.16) 42.2,88.09 42.86,87.42 PU5202.4
PWR_1D0V_FB_A: length 21.1
  L3 w0.254: v2(59.23,87.24) 59.21,87.24 59.19,87.22 56.04,87.22 53.3,89.96 50.19,89.96 50.03,90.13 49.61,90.13 49.44,89.96 44.28,89.96 44.15,89.83 43.73,89.83 43.44,90.13 43.44,90.19 v2(43.28,90.34)
  BOTTOM w0.254: v1(43.4,90.89) 43.28,90.77 v2(43.28,90.34) 43.27,90.33 42.78,90.33 42.59,90.14 42.39,90.14 PR5216.1 PC5218.1 ; v2(59.23,87.24) 59.23,87.23 59.47,86.99 PG5209.2
PWR_1D0V_ILIMT: length 2.3
  BOTTOM w0.254: PU5202.3 43.31,87.79 43.39,87.87 v1(43.39,87.89) 43.39,87.9 43.97,88.49 PR5209.2
PWR_1D0V_LDO: length 3.7
  BOTTOM w0.254: PC5226.1 40.21,89.17 40.21,88.72 40.77,88.16 v1(40.93,88.16) 40.95,88.13 41.43,88.13 42.41,87.16 PU5202.5
PWR_1D0V_PG: length 3.4
  BOTTOM w0.102: PU5202.2 43.76,87.31 44.36,87.9 v1(44.63,87.9) 44.81,88.08 PR5211.2 PR5212.2
PWR_1D0V_PH: length 1.7
  TOP w0.254: v2(47.28,86.65) 47.48,86.85 v1(47.48,87.27) 47.43,87.32 46.68,87.32 PC5217.2
PWR_1D5V_EN: length 3.9
  BOTTOM w0.102: v1(15.22,73.68) 15.15,73.75 PR5305.2 14.57,73.37 PC5307.1 14.77,72.55 PU5302.3
PWR_1D8V_EN: length 5.7
  BOTTOM w0.102: PR5307.2 PR5306.2 30.5,3.07 PR5301.1 ; PR5301.1 29.5,3.26 PU5301.8 ; PR5301.1 PC5306.1 29.69,1.61 29.42,1.34 v1(29.42,1.26)
PWR_1D8V_POK: length 4.7
  BOTTOM w0.102: v1(32.47,1.39) 32.25,1.61 PR5302.2 PR5308.2 31.82,3.55 31.15,3.55 30.77,3.93 PU5301.7
PWR_1D35V_BOOT: length 3.5
  TOP w0.508: v2(135.67,42.46) 136.28,43.07 PR5101.1 136.28,44.82 v1(136.2,44.9)
  BOTTOM w0.254: PU5101.6 136.02,43.04 135.67,42.69 v2(135.67,42.46)
PWR_1D35V_BOOT_R: length 2
  TOP w0.508: 137.6,44.33 137.64,44.29 v1(138.49,44.29) ; 137.6,44.33 PC5117.1 ; 137.6,44.33 PR5101.2
PWR_1D35V_BYP: length 4.1
  TOP w0.254: v1(138.11,41.57) 137.33,41.57 PR5102.1 PC5110.1 136.18,42.06 v2(136.35,42.23)
  BOTTOM w0.254: v2(136.35,42.23) 136.79,42.67 PU5101.7
PWR_1D35V_C_R: length 0.9
  BOTTOM w0.254: PR5108.1 132.58,42.03 PC5112.2
PWR_1D35V_EN: length 3.3
  BOTTOM w0.102: PU5101.1 135.69,45.29 135.09,45.89 v1(135.09,46) 134.64,46.45 PC5138.1 PR5105.2
PWR_1D35V_IMAX: length 2.5
  BOTTOM w0.254: PR5106.2 134.21,45.29 v1(134.93,44.57) 135.11,44.39 PU5101.3
PWR_1D35V_LDO_P5: length 3.7
  BOTTOM w0.254: PC5113.1 134.5,41.19 134.78,41.47 134.78,41.85 v1(135.11,42.18) 135.08,42.21 135.08,43.2 135.37,43.49 PU5101.5
PWR_1D35V_PGOOD: length 3.3
  TOP w0.102: PR5110.2 PR5107.2 135.03,44.8 v2(135.29,45.05) 135.29,45.7 v1(135.27,45.71)
  BOTTOM w0.102: PU5101.2 135.5,44.84 v2(135.29,45.05)
PWR_1D35V_PHASE: length 1.7
  TOP w0.508: v1(137.7,46.91) v3(137.7,46.15) 137.57,46.02 PC5117.2
PWR_1D35V_VFB: length 4.8
  BOTTOM w0.254: PU5101.4 135.06,43.94 134.78,43.66 PR5104.1 ; PR5108.2 PR5103.2 PR5104.1 ; PR5104.1 134.21,44.08 v1(133.71,44.57)
PWR_3D3V_CS2: length 4.8
  TOP w0.203: PU4503.5 32.2,64.95 32.42,64.74 32.83,64.74 32.96,64.61
  TOP w0.254: 32.96,64.61 33.59,63.98 34.7,63.98 v1(34.89,63.79) 35.47,63.21 PR4501.1
PWR_3D3V_DRVH2: length 9.8
  TOP w0.203: v3(33.94,67.91) 33.73,67.7 PU4503.10
  TOP w0.508: v3(33.94,67.91) 34.42,68.4 v1(34.42,68.47)
  L6 w0.635: v3(33.94,67.91) 34.96,68.93 34.96,72.48 33.56,73.88 v3(33.31,73.88)
  BOTTOM w0.305: PU4502.1 33.31,74.6 v3(33.31,73.88)
PWR_3D3V_DRVL2: length 10.3
  TOP w0.203: PU4503.11 32.2,68.97 32.54,69.31 v3(32.67,69.31)
  L6 w0.635: v3(32.67,69.31) 32.67,70.71 31.66,71.72 31.66,74.39 32.54,75.28 v3(32.54,76.25)
  BOTTOM w0.305: v3(32.54,76.25) PU4502.4
  BOTTOM w0.508: v1(31.99,69.34) 32.65,69.34 v3(32.67,69.31)
PWR_3D3V_EN2: length 4.2
  TOP w0.203: 33.13,65.32 32.95,65.5 PU4503.6
  TOP w0.254: v2(34.58,64.74) 34.07,65.25 33.21,65.25 33.13,65.32
  BOTTOM w0.254: v2(34.58,64.74) 34.54,64.78 34.54,65.32 34.55,65.34 v1(34.55,65.39) 35.38,65.39 PR4527.1
PWR_3D3V_FEEDBACK: length 27.3
  TOP w0.254: PR4512.1 34.32,62.52 34.32,63.21 v2(34.07,63.47) ; v1(37.88,85.13) v2(37.88,85.69)
  L4 w0.254: v2(34.07,63.47) 36.35,65.75 36.35,74.64 36.96,75.25 36.96,79.67 38.01,80.71 38.01,85.57 v2(37.88,85.69)
  BOTTOM w0.254: PG4530.2 v2(37.88,85.69)
PWR_3D3V_SW2: length 17.1
  TOP w0.203: PU4503.8 34.01,66.9 v3(34.2,66.71)
  TOP w0.254: v3(33.81,77.52) 33.83,77.5 v1(33.83,76.69)
  L6 w0.635: v3(33.81,77.52) 34.07,77.26 34.07,75.02 36.23,72.87 36.23,67.4 35.53,66.71 v3(34.2,66.71)
  BOTTOM w0.635: PC4517.2 34.52,66.39 v3(34.2,66.71)
PWR_3D3V_VBST2: length 3.5
  TOP w0.203: v2(34.79,67.66) 34.79,67.49 34.6,67.3 PU4503.9
  TOP w0.305: v2(34.79,67.66) 34.82,67.68 v1(35.39,67.68)
  BOTTOM w0.508: v2(34.79,67.66) PR4508.2
PWR_3D3V_VBST2_1: length 2.3
  BOTTOM w0.508: v1(37.92,67.66) PR4508.1 PC4517.1
PWR_3D3V_VFB2: length 3.9
  TOP w0.203: PU4503.4 31.8,64.59 32.04,64.36
  TOP w0.254: 32.04,64.36 32.62,63.77 v1(32.62,63.67) 32.62,62.95 PR4517.1 PR4512.2
PWR_5V3D3V_VREG3: length 5.1
  TOP w0.203: 31.4,64.04 PU4503.3
  TOP w0.508: 31.4,64.04 31.53,63.91 PC4527.1 31.3,62.83 30.51,62.83 v1(30.39,62.71) 30.33,62.66 PG4533.2
PWR_5V3D3V_VREG5: length 3.6
  TOP w0.203: PC4524.1 31.55,70.53 v1(31.55,69.6) 31.55,69.54 31.48,69.47 31.48,69.09 31.4,69.01 PU4503.13
  TOP w0.508: PG4534.1 31.27,70.45 PC4524.1
PWR_5V_CS1: length 2.6
  TOP w0.127: v1(29.48,64.08) 29.6,64.08 v2(30.13,64.61)
  TOP w0.203: PU4503.1 30.6,65.08 v2(30.13,64.61)
  BOTTOM w0.254: v2(30.13,64.61) 30,64.74 PR4502.1
PWR_5V_DRVH1: length 7.4
  TOP w0.203: PU4503.16 28.95,67.7 v3(28.73,67.91)
  L6 w0.635: v3(26.17,71.21) 26.17,68.74 26.82,68.1 28.55,68.1 v3(28.73,67.91)
  BOTTOM w0.508: v3(28.73,67.91) 29.27,67.38 v1(29.27,67.35)
PWR_5V_DRVL1: length 9
  TOP w0.203: PU4503.15 30.23,68.45 30.11,68.57 v3(29.9,68.57)
  L6 w0.635: v3(25.46,73.66) 26.26,73.66 29.9,70.02 v3(29.9,68.57)
  BOTTOM w0.508: v1(30.72,68.6) 29.93,68.6 v3(29.9,68.57)
PWR_5V_EN1: length 4.4
  TOP w0.203: 28.92,65.56 29.46,66.1 PU4503.20
  TOP w0.254: v2(28.35,64.61) 28.47,64.61 28.92,65.07 28.92,65.56
  BOTTOM w0.254: v2(28.35,64.61) 28.29,64.55 PR4521.1 27.32,64.53 v1(26.42,64.53)
PWR_5V_FEEDBACK: length 30.6
  BOTTOM w0.356: PR4515.1 29.18,61.94 26.45,61.94 25.69,62.71 25.69,66.52 22.87,69.34 v1(22.87,83.18) 22.87,84.27 24.29,85.69 PG4531.2
PWR_5V_SW1: length 20.1
  TOP w0.203: PU4503.18 28.73,66.9 v3(28.42,66.58)
  TOP w0.508: v1(27.08,77.82) 27.08,78.5 26.98,78.61 v3(26.98,78.73)
  L6 w0.635: v3(28.42,66.58) 26.89,66.58 24.49,68.98 24.49,74.42 26.96,76.88 26.96,78.71 v3(26.98,78.73)
  BOTTOM w0.508: PC4518.2 27.39,65.55 v3(28.42,66.58)
PWR_5V_VBST1: length 3.7
  TOP w0.203: PU4503.17 v2(28.1,67.3) 27.95,67.45 v1(27.95,67.86)
  BOTTOM w0.508: PR4509.1 27.34,68.06 v2(28.1,67.3)
PWR_5V_VBST1_1: length 3.1
  BOTTOM w0.508: PC4518.1 26.02,67.84 PR4509.2 25.33,68.27 v1(24.92,68.67)
PWR_5V_VCLK: length 4.8
  TOP w0.102: PU4503.19 29.13,66.5 28.35,65.72 v2(28.35,65.25)
  BOTTOM w0.102: AFTP4501.1 29.12,63.59 PR4503.1 28.42,65.25 v2(28.35,65.25)
PWR_5V_VFB1: length 4
  TOP w0.203: PU4503.2 31,64.46 30.89,64.36
  TOP w0.254: v2(30.13,63.98) 30.22,63.89 v1(30.68,63.89) 30.89,64.1 30.89,64.36
  BOTTOM w0.254: PR4515.2 30.89,62.9 PR4520.1 30.32,63.79 v2(30.13,63.98)
PWR_5V_VO1: length 24.4
  TOP w0.203: v2(30.89,69.46) 31,69.35 PU4503.14
  L3 w0.508: v2(27.95,69.69) 30.66,69.69 v2(30.89,69.46)
  BOTTOM w0.508: v2(27.95,69.69) 27.92,69.67 24.29,69.67 23.43,70.53 v1(23.43,75.96) 23.43,83.99 24.11,84.67 PG4532.2
PWR_CHG_1: length 6.4
  BOTTOM w0.254: PD4406.K 31.53,20.92 30.26,19.65 30.26,19.25 30.87,18.64 v1(31.93,18.64) PR4403.1
PWR_CHG_ACDET: length 5.9
  TOP w0.203: PU4401.6 37.48,12.5 37.37,12.39 37.37,11.51 v1(36.94,11.08)
  TOP w0.254: v1(36.94,11.08) PC4402.1 PR4411.1 35.02,11.02 35.02,9.62 PR4444.2
PWR_CHG_ACN: length 22.8
  TOP w0.203: 37.5,14.5 PU4401.1
  TOP w0.254: v2(34.86,17.29) 34.73,17.16 34.73,16.58 ; v1(34.78,16.58) 34.73,16.58 ; 34.73,16.58 34.73,15.88 35.3,15.31 36.37,15.31 37.17,14.5 37.5,14.5
  L3 w0.254: v2(43.59,27.02) 34.65,18.08 34.65,17.49 v2(34.86,17.29)
  BOTTOM w0.254: v2(43.59,27.02) 43.72,26.89 PG4402.2 ; PC4428.1 PR4421.1 34.96,16.16 PC4416.2 35.02,17.13 v2(34.86,17.29)
PWR_CHG_ACOK: length 170.7
  TOP w0.102: v2(161.22,34.21) D2404.K 161.43,34.89 162.21,35.68 R2469.1 ; PU4401.5 36.75,12.9 v2(36.68,12.97)
  L3 w0.102: v2(161.22,34.21) 161.22,33.37 160.83,32.97 160.83,30.23 160.27,29.67 158.15,29.67 158.14,29.68 157.03,29.68 153.3,25.95 150.95,25.95 150.19,25.2 150.19,25.19 149.94,24.94 143.77,24.94 135.87,17.04 117.06,17.04 114.88,19.21 114.88,19.32 114.7,19.5 106.69,19.5 105.55,20.65 94.57,20.65 92.98,22.24 85.12,22.24 83.57,23.79 74.4,23.79 67.49,16.88 58.31,16.88 57.29,17.9 55.65,17.9 55.54,18 47.94,18 43.77,13.84 43.77,11.02 43.06,10.31 41.61,10.31 39.45,8.15 37.44,8.15 35.54,6.24 35.54,5.88 36.62,4.81 37.82,4.81 v2(38.77,3.85)
  L4 w0.102: v2(38.77,3.85) 39.96,5.05 39.96,6.41 39.83,6.54 39.83,10.18 37.04,12.97 v2(36.68,12.97)
  BOTTOM w0.102: v1(39.33,3.7) 38.92,3.7 v2(38.77,3.85) 38.77,4.32 PR4404.1 PR4410.2 ; v2(36.68,12.97) 36.51,12.79 PR4475.2
PWR_CHG_ACP: length 24.6
  TOP w0.203: PU4401.2 37.5,14.1
  TOP w0.254: 35.54,14.93 35.14,14.93 34.35,15.72 34.35,17.04 v2(34.17,17.21) ; 35.54,14.93 v1(35.54,14.85) ; 35.54,14.93 36.21,14.93 37.02,14.12 37.48,14.12 37.5,14.1
  L3 w0.254: v2(34.17,17.21) 34.27,17.32 34.27,18.24 42.83,26.8 v2(42.83,27.02)
  BOTTOM w0.254: v2(34.17,17.21) 33.97,17.01 PC4432.1 34.13,16.06 PC4418.2 34.32,15.08 34.89,14.51 PR4421.2 PC4428.2 ; PG4406.2 42.7,26.89 v2(42.83,27.02)
PWR_CHG_BAT: length 4.9
  TOP w0.203: PU4401.17 43.23,12.9 43.34,12.79
  TOP w0.254: 43.34,12.79 44.02,12.11 v1(44.23,12.11)
  TOP w0.508: v2(45.69,12.11) v1(44.23,12.11)
  BOTTOM w0.508: PR4408.2 46.69,12.11 v2(45.69,12.11)
PWR_CHG_BATDRV: length 3.6
  TOP w0.203: 43.59,13.3 PU4401.18
  TOP w0.254: 43.59,13.3 44.42,13.3 PR4409.1 45.15,13.79 v1(45.15,14.09)
PWR_CHG_BTST: length 2.6
  TOP w0.203: v1(40.16,16.91) PU4401.25
  TOP w0.508: PR4425.1 v1(40.16,16.91)
PWR_CHG_BTST1: length 5.6
  TOP w0.508: 43.34,19.65 42.6,20.39 v1(41.59,20.39) 40.98,20.39 40.16,19.58 PR4425.2 38.98,19.3 PC4421.1
PWR_CHG_CELL: length 6.2
  TOP w0.203: 43.02,12.35 42.87,12.5 PU4401.16
  TOP w0.254: v1(43.83,10.96) 43.65,10.96 v2(43.34,11.27) 43.34,12.03 43.02,12.35
  BOTTOM w0.254: PR4468.2 PR4445.1 PR4449.2 ; PR4468.2 PR4424.2 ; PR4468.2 43.59,11.02 v2(43.34,11.27)
PWR_CHG_CMPIN: length 1.2
  TOP w0.254: PR4413.1 42.2,6.83 42.58,6.44 TP4401.1
PWR_CHG_CMPIN_1: length 3.7
  TOP w0.203: 41.36,10.26 41.36,10.33 40.96,10.72 PU4401.13
  TOP w0.254: 41.36,10.26 41.56,10.05 41.56,9.03 v1(41.61,8.98) 42.2,8.4 PR4413.2
PWR_CHG_CMPOUT: length 1
  TOP w0.254: PR4415.1 43.15,7.21 TP4402.1
PWR_CHG_CMPOUT_1: length 4
  TOP w0.203: PU4401.14 41.36,10.83 41.69,10.51
  TOP w0.254: PR4415.2 43.09,9.11 v1(42.75,9.45) 41.69,10.51
PWR_CHG_CMSRC: length 2.9
  TOP w0.203: 37.42,13.7 PU4401.3
  TOP w0.254: v1(36.18,13.66) 36.71,13.66 v2(36.74,13.68) 36.81,13.61 37.33,13.61 37.42,13.7
  BOTTOM w0.508: v2(36.74,13.68) PR4439.2
PWR_CHG_HIDRV: length 21
  TOP w0.203: PU4401.26 39.76,16.37 v3(39.4,16.73)
  L6 w1.016: v3(54.26,21.05) 53.75,20.54 43.21,20.54 v3(39.4,16.73)
  BOTTOM w0.254: v1(39.66,17.49) 39.66,16.99 v3(39.4,16.73)
  BOTTOM w0.762: PU4406.1 53.66,20.07 54.26,20.67 v3(54.26,21.05)
PWR_CHG_IADP: length 3.3
  TOP w0.102: PU4401.7 38.13,11.78 v2(37.88,11.52)
  BOTTOM w0.102: v2(37.88,11.52) 38.07,11.33 PC4435.1 PR4472.2 v1(40.44,11.33)
PWR_CHG_IBAT: length 6.1
  TOP w0.102: PU4401.8 38.96,10.21 37.67,8.92 v2(37.67,8.73) 37.47,8.73 v1(37.09,9.11)
  BOTTOM w0.102: PR4473.2 36.1,7.78 PC4436.1 37,7.78 37.67,8.45 v2(37.67,8.73)
PWR_CHG_ILIM: length 5.9
  TOP w0.203: 42.83,14.85 42.83,14.7 42.63,14.5 PU4401.21
  TOP w0.254: PR4471.1 46.39,17.68 PR4470.2 45.67,17.68 v1(44.99,17.01) 42.83,14.85
PWR_CHG_LODRV: length 22.3
  TOP w0.203: v3(41.43,16.35) 40.96,15.88 PU4401.23
  L4 w1.016: v3(52.99,27.27) 51.85,26.13 45.88,26.13 41.43,21.68 v3(41.43,16.35)
  BOTTOM w0.254: v1(41.94,16.86) v3(41.43,16.35)
  BOTTOM w0.762: v3(52.99,27.27) PU4406.8
PWR_CHG_PHASE: length 28.3
  TOP w0.203: v3(38.13,16.73) 38.51,16.73 39.36,15.88 PU4401.27
  TOP w0.508: PC4421.2 38.77,17.37 v3(38.13,16.73) ; v3(56.42,26.38) 56.19,26.16 PC4414.1
  L6 w1.016: v3(38.13,16.73) 38.13,17.27 42.75,21.89 51.92,21.89 v3(56.42,26.38)
  BOTTOM w0.254: v1(37.62,17.24) v3(38.13,16.73)
PWR_CHG_PHASE_R: length 1.9
  TOP w0.508: PR4419.1 v1(53.6,26.16) PC4414.2
PWR_CHG_PMON: length 5.6
  TOP w0.102: PU4401.9 39.36,9.96 38.5,9.1 38.5,8.87 v2(38.36,8.73) 37.93,8.3 v1(37.93,8.18)
  BOTTOM w0.102: v2(38.36,8.73) 38.39,8.71 38.39,8.03 PR4474.2 PC4437.1
PWR_CHG_PROCHOT#: length 4.4
  TOP w0.114: PU4401.10 39.76,10.1 39.82,10.04 39.82,9.66 39.84,9.64 39.84,9.15 v2(39.4,8.71) 39.15,8.46 v1(39.15,8.15)
  BOTTOM w0.114: PR4469.2 39.53,8.22 39.4,8.35 39.4,8.71 v2(39.4,8.71)
PWR_CHG_REGN: length 31.1
  TOP w0.203: 40.8,16.6 40.56,16.37 PU4401.24
  TOP w0.254: 40.8,16.6 41.56,17.37 PC4422.1 42.73,17.98 PD4401.A 44.48,17.37 v2(44.99,17.87) 45.69,18.57 PR4470.1
  L3 w0.254: v2(45.52,10.69) 45.11,10.69 43.91,9.49 43.4,9.49 41.99,9.49 39.83,7.33 39.64,7.33 38.3,7.33 37.37,6.4 37.37,6.01 37.07,5.71 37.01,5.71 v2(36.86,5.56)
  BOTTOM w0.254: v2(44.99,17.87) 45.75,17.87 46.51,17.11 46.51,15.59 46.77,15.33 46.77,13.05 46.55,12.83 46.01,12.83 45.54,13.3 v1(45.12,13.3) 44.48,12.67 PR4449.1 44.67,12.35 45.05,11.97 45.05,11.16 v2(45.52,10.69) ; v2(36.86,5.56) 36.93,5.49 PR4410.1
PWR_CHG_SCL: length 3.5
  TOP w0.114: PG4401.1 41.05,8.15 41.05,9.98 40.94,10.09 40.94,10.13 v1(40.92,10.15) 40.56,10.51 PU4401.12
PWR_CHG_SDA: length 3.4
  TOP w0.114: PU4401.11 40.16,9.8 40.37,9.59 v1(40.37,9.06) 40.37,8.22 PG4408.1
PWR_CHG_SRN: length 3.8
  TOP w0.203: 43.35,13.8 43.26,13.7 PU4401.19
  TOP w0.254: 43.35,13.8 43.89,14.33 ; 43.89,14.33 v1(43.95,14.27) ; 43.89,14.33 44.64,15.08 PR4417.1
PWR_CHG_SRN_R: length 35.7
  TOP w0.254: v2(52.61,15.59) 52.23,15.97 49.44,15.97 48.61,15.14 PC4429.2 PC4412.1 46.26,15.14 PR4417.2
  BOTTOM w0.254: PG4403.1 73.5,25.62 73.25,25.37 73.25,23.21 69.71,19.67 69.71,18.59 66.71,15.59 56.67,15.59 ; v2(52.61,15.59) 52.99,15.21 53.63,15.21 54.64,16.22 55.74,16.22 56.38,15.59 56.67,15.59 ; 56.67,15.59 v1(56.67,15.51)
PWR_CHG_SRP: length 4
  TOP w0.203: 43.21,14.19 43.12,14.1 PU4401.20
  TOP w0.254: v1(44.41,15.51) 44.47,15.45 ; 44.47,15.45 45.12,16.1 PR4438.1 ; 44.47,15.45 43.21,14.19
PWR_CHG_SRP_R: length 34.6
  TOP w0.254: v2(53.34,15.72) 52.58,16.48 49.12,16.48 48.67,16.03 PC4429.1 PC4401.1 46.26,16.03 PR4438.2
  BOTTOM w0.254: 55.28,16.73 v1(55.28,16.86) ; 55.28,16.73 55.95,16.73 56.59,16.1 66.5,16.1 69.2,18.8 69.2,19.88 72.74,23.42 72.74,25.3 72.42,25.62 PG4407.1 ; 55.28,16.73 54.36,16.73 v2(53.34,15.72)
PWR_CHG_VCC: length 8.3
  TOP w0.203: PU4401.28 38.42,15.33 v2(38.4,15.35)
  BOTTOM w0.254: PR4403.2 34.78,18.84 35.34,19.4 36.74,19.4 37.27,18.87 PC4410.1 37.27,17.84 PC4433.1 36.67,16.92 v1(37.68,15.92) 38.24,15.35 v2(38.4,15.35)
PWR_CPUCORE_SNUB: length 3.5
  TOP w0.508: PC4709.1 46.64,59.07 v1(46.92,59.35) 48.06,59.35 48.47,58.95 PR4704.2
PWR_VCCGT_BOOTA: length 3
  BOTTOM w0.203: 45.51,49.38 46.01,48.89 PU4803.35
  BOTTOM w0.508: PR4802.1 44.66,50.26 v1(45.17,49.75) 45.17,49.72 45.51,49.38
PWR_VCCGT_BOOTA_RC: length 2.6
  BOTTOM w0.254: v1(42.87,47.72) 42.87,48.8
  BOTTOM w0.508: PR4802.2 PC4809.1 42.87,48.8
PWR_VCCGT_COMP: length 3.5
  BOTTOM w0.203: v1(29.94,48.34) 30.43,48.34 30.84,48.75 PU4601.4
  BOTTOM w0.254: v1(29.94,48.34) 28.91,48.34 PC4617.2 28.8,48.23 PC4618.2
PWR_VCCGT_COMP_R: length 1.7
  BOTTOM w0.254: PC4618.1 PR4631.2 27.13,47.4 v1(27.13,46.5)
PWR_VCCGT_CSCOMP: length 39.8
  TOP w0.254: v2(33.69,41.12) 32.45,41.12 30.42,43.15 29.11,43.15 v1(28.23,44.04) 27.59,44.67 27.59,45.56 27.85,45.81 v2(28.12,45.81) ; PR4639.2 29.37,49.06 29.96,49.06 30.26,49.35 30.26,49.37 v2(30.39,49.5)
  L3 w0.254: v2(33.69,41.12) 33.73,41.16 36.3,41.16 37.75,39.72 41.82,39.72 42.7,40.61 48.55,40.61 v2(49.44,41.5)
  BOTTOM w0.203: v2(30.39,49.5) 30.44,49.55 PU4601.6
  BOTTOM w0.254: PR4634.2 49.75,42.26 49.44,41.94 v2(49.44,41.5) ; v2(28.12,45.81) 27.95,45.99 26.91,45.99 26.45,46.45 26.45,48.48 27.08,49.12 PR4640.2 27.27,49.88 PC4620.1 PC4621.1 28.92,49.94 29.24,49.62 29.24,49.62 29.52,49.35 30.24,49.35 v2(30.39,49.5)
PWR_VCCGT_CSNA: length 58.3
  TOP w0.254: v2(28.86,57.33) v1(28.86,56.64) PR4646.2
  L4 w0.254: v2(28.86,57.33) 29.62,57.33 30.32,56.63 30.32,56.2 32.04,54.48 32.04,52.83 31.4,52.2 31.4,48.82 33.51,46.7 35.08,46.7 35.44,46.34 35.44,45.36 36.46,44.34 37.9,44.34 39,45.43 41.56,45.43 42.55,46.42 45.4,46.42 46.39,45.43 46.39,42.77 47.47,41.69 47.47,40.89 48.64,39.72 50.86,39.72 51.73,40.58 55.84,40.58 58.45,43.2 58.45,46.61 57.34,47.72 55.15,47.72 v2(54.9,47.97)
  BOTTOM w0.254: PG4809.1 v2(54.9,47.97)
PWR_VCCGT_CSP1: length 4.6
  BOTTOM w0.203: PU4601.10 30.82,51.15 30.34,51.63 30.34,51.85
  BOTTOM w0.254: PR4651.1 28.92,53.43 PC4623.2 29.88,52.61 29.88,52.6 v1(29.9,52.57) 30.34,52.13 30.34,51.85
PWR_VCCGT_CSP2: length 4.1
  BOTTOM w0.203: 29.88,51.28 30.13,51.28 30.66,50.75 PU4601.9
  BOTTOM w0.254: 29.88,51.28 29.12,51.28 28.71,51.68 v1(28.68,51.68) 28.16,52.21 PR4671.2
PWR_VCCGT_CSPA: length 67.6
  TOP w0.254: v2(28.86,58.01) 28.23,58.01 27.34,57.12 v1(27.34,55.85) 27.34,52.06 PR4637.1
  L4 w0.254: v2(54.9,47.21) 55.02,47.34 57.18,47.34 58.07,46.45 58.07,43.45 55.63,41.01 51.62,41.01 50.71,40.1 48.8,40.1 47.85,41.05 47.85,41.94 46.9,42.89 46.9,45.69 45.75,46.83 42.32,46.83 41.31,45.81 38.74,45.81 37.67,44.75 36.63,44.75 35.82,45.56 35.82,46.5 35.12,47.2 33.63,47.2 31.78,49.04 31.78,52.04 32.42,52.67 32.42,54.64 30.7,56.36 30.7,56.79 29.61,57.88 28.99,57.88 v2(28.86,58.01)
  BOTTOM w0.254: PG4808.1 v2(54.9,47.21) ; v2(28.86,58.01) 27.72,58.01 27.15,57.44 PR4651.2
PWR_VCCGT_CSREF: length 7.2
  TOP w0.254: PR4646.1 28.86,53.05 v1(29.32,52.6) 29.83,52.09 v2(29.83,51.81) 29.69,51.67 29.69,50.91 v2(29.9,50.7) 30.51,50.7 PC4626.1
  BOTTOM w0.203: PU4601.8 30.52,50.35 30.16,50.7 v2(29.9,50.7)
  BOTTOM w0.254: v2(29.83,51.81) 29.79,51.81 PC4623.1
PWR_VCCGT_CSSUM: length 8
  TOP w0.254: PR4638.2 27.21,49.85 PR4637.2 28.95,50.36 29.29,50.03 v2(29.98,50.03)
  BOTTOM w0.203: v2(29.98,50.03) 30.03,49.98 30.59,49.98 30.61,49.95 PU4601.7
  BOTTOM w0.254: PC4620.2 PC4621.2 28.7,50.83 29.01,50.52 v1(29.04,50.52) 29.52,50.03 v2(29.98,50.03)
PWR_VCCGT_DIFFOUT: length 5.5
  TOP w0.254: PR4625.1 28.1,47.34 28.84,46.6 v1(28.99,46.6) 29.42,46.6 29.83,47.01 29.86,47.01 v2(30,47.15)
  BOTTOM w0.203: PU4601.2 30.97,47.95 30.65,47.63 30.62,47.63 30.14,47.15 v2(30,47.15)
  BOTTOM w0.254: PR4626.1 29.62,47.15 v2(30,47.15)
PWR_VCCGT_DISB#A: length 3.4
  BOTTOM w0.203: 47.66,50.51 47.82,50.35 PU4803.2
  BOTTOM w0.254: 47.66,50.51 47.66,50.72 47.98,51.05 47.98,51.74 47.96,51.76 v1(47.96,51.78) 47.96,51.8 PR4807.1
PWR_VCCGT_FB: length 6.9
  TOP w0.254: PC4614.2 29.24,47.79 v2(30,47.79)
  BOTTOM w0.203: v2(30,47.79) 30.3,47.79 30.53,48.01 30.56,48.01 30.76,48.21 30.9,48.35 PU4601.3
  BOTTOM w0.254: v1(28.81,45.66) 28.81,45.93 PR4626.2 28.16,47.29 28.05,47.4 ; 28.05,47.4 PC4617.1 29.24,47.78 30,47.78 v2(30,47.79) ; 28.05,47.4 PR4631.1
PWR_VCCGT_FB_R: length 1.8
  TOP w0.254: v1(29.9,48.38) 29.87,48.42 PC4614.1 PR4625.2
PWR_VCCGT_GLA: length 3.5
  BOTTOM w0.203: 50.82,48.08 50.96,48.23 50.96,48.36 50.84,48.49 ; 50.82,48.08 PU4803.10 ; 50.82,48.08 50.82,47.88 50.62,47.68 PU4803.11 ; 50.84,48.49 50.96,48.61 50.96,48.78 50.85,48.89 PU4803.8 ; 50.84,48.49 PU4803.9
PWR_VCCGT_ICCMAX: length 4
  BOTTOM w0.203: PU4601.18 34,52.94 34.01,52.95 34.01,53.95 v1(33.84,54.12) 33.84,54.24 33.78,54.29
  BOTTOM w0.254: PR4662.1 32.77,55.3 33.78,54.29
PWR_VCCGT_ILIM: length 3.5
  BOTTOM w0.203: PU4601.5 30.72,49.15 30.43,48.86 30.28,48.86
  BOTTOM w0.254: 30.28,48.86 29.45,48.86 29.12,49.19 v1(29.06,49.19) 28.24,49.19 PR4640.1
PWR_VCCGT_ILIM_NTC: length 33.1
  TOP w0.254: PR4639.1 28.04,49.37 PR4638.1 v1(27.21,46.98) 27.21,44.42 28.86,42.77 30.26,42.77 32.42,40.61 v2(34.07,40.61)
  L3 w0.254: v2(50.07,41.5) 50.07,41.37 48.8,40.1 42.73,40.1 41.97,39.34 37.59,39.34 36.15,40.78 34.24,40.78 v2(34.07,40.61)
  BOTTOM w0.254: v2(50.07,41.5) 50.07,41.81 50.64,42.39 PR4634.1
PWR_VCCGT_IOUT: length 3.9
  TOP w0.254: v1(30.96,49.02) 30.96,48.13 PC4615.1 R9934.1 30.98,46.93 v2(31.47,46.45)
  BOTTOM w0.203: PU4601.1 31.47,47.43 v2(31.47,46.45)
PWR_VCCGT_NTC: length 28.8
  L4 w0.254: v2(28.86,59.02) 30.39,59.02 31.67,57.74 31.67,57.41 34.07,55.01 34.07,53.82 35.08,52.8 38.8,52.8 40.04,51.56 40.04,50.56 40.33,50.26 43.34,50.26 44.48,51.4 v2(45.55,51.4)
  BOTTOM w0.254: v2(45.55,51.4) PR4656.2 ; PR4655.1 PR4661.1 28.92,56.51 30.13,57.72 30.13,58.59 v1(30.11,58.62) 29.7,59.02 v2(28.86,59.02)
PWR_VCCGT_PHASEDA: length 4
  BOTTOM w0.203: 46.14,48.49 PU4803.34 ; 46.14,48.49 45.37,48.49 ; 46.14,48.49 45.98,48.33 45.98,47.86 46.15,47.68 PU4803.32
  BOTTOM w0.508: PC4809.2 44.84,48.86 v1(45.22,48.49) 45.37,48.49
PWR_VCCGT_PWMA: length 21.7
  TOP w0.254: v1(48.55,52.47) v2(48.55,51.91)
  L4 w0.254: v2(33.2,53.34) 33.65,53.34 34.58,52.42 38.64,52.42 39.66,51.4 39.66,50.36 40.13,49.88 43.59,49.88 44.61,50.89 46.01,50.89 46.9,51.78 48.42,51.78 v2(48.55,51.91)
  BOTTOM w0.203: 48.8,50.89 48.8,50.44 48.62,50.26 PU4803.4 ; PU4601.16 v2(33.2,53.34)
  BOTTOM w0.254: v2(48.55,51.91) 48.55,51.53 48.8,51.28 48.8,50.89
PWR_VCCGT_PWMB: length 2.3
  TOP w0.254: v2(33.18,53.99) 32.59,53.99 TP4601.1
  BOTTOM w0.203: PU4601.17 33.6,53.01 33.68,53.09 33.68,53.57 33.26,53.99 v2(33.18,53.99)
PWR_VCCGT_SWA: length 0.6
  TOP w0.508: v2(52.15,43.53) 51.59,43.53 v1(51.57,43.5)
PWR_VCCGT_TSENSE: length 5.3
  TOP w0.254: v2(30.77,53.05) 31.53,52.29 PC4630.1
  BOTTOM w0.203: PU4601.11 30.93,51.55 30.74,51.74 30.74,53.03 v2(30.77,53.05)
  BOTTOM w0.254: v2(30.77,53.05) v1(30.03,53.79) 29.81,54.01 PR4655.2
PWR_VCCGT_VCCA: length 4.3
  BOTTOM w0.203: 49.7,51.01 49.82,50.89 49.82,50.47 49.42,50.07 PU4803.6
  BOTTOM w0.254: 49.7,51.01 49.18,51.53 v1(49.18,51.78) 49.18,52.36 PR4803.1 PC4808.1
PWR_VCCGT_VSN: length 4.4
  TOP w0.254: PR4619.1 PC4612.1 30.77,45.25 31.33,45.81 v2(31.53,45.81)
  BOTTOM w0.203: v2(31.53,45.81) 31.95,46.23 31.95,46.4 32,46.45 PU4601.48
  BOTTOM w0.254: v1(31.09,45.47) 31.19,45.47 v2(31.53,45.81)
PWR_VCCGT_VSN_R: length 3.8
  TOP w0.254: PC4612.2 PR4619.2 PC4611.2 PR4618.2 31.77,42.96 v1(31.71,42.89)
PWR_VCCGT_VSP: length 4.3
  TOP w0.254: v1(32.09,45.74) 32.21,45.61 32.49,45.61 v2(32.67,45.43) PC4611.1 33.43,43.97 PR4617.2
  BOTTOM w0.114: v2(32.67,45.43) 32.23,45.88 32.23,46.11 32.23,46.12 32.23,46.29 32.39,46.45 PU4601.47
PWR_VCCSA_BST: length 2.6
  BOTTOM w0.305: PR5001.2 46.87,66.85 v1(46.49,66.47) 46.44,66.41 45.35,66.41 PU5002.1
PWR_VCCSA_BST_RC: length 2.4
  BOTTOM w0.508: PC5005.1 46.98,70.28 v1(47.06,70.2) 47.06,69.12 PR5001.1
PWR_VCCSA_COMP: length 5.3
  TOP w0.254: v2(34.45,45.43) 34.14,45.13 v1(34.14,44.86) 34.14,44.63 34.32,44.45 34.32,44.23 PC4604.2 35.66,42.89 PC4602.1
  BOTTOM w0.203: v2(34.45,45.43) 34.25,45.43 33.97,45.72 33.97,46.27 34,46.3 PU4601.43
PWR_VCCSA_COMP_L: length 1.2
  TOP w0.254: PR4672.2 35.72,43.72 PC4604.1
PWR_VCCSA_COMP_R: length 0.9
  TOP w0.254: PC4602.2 36.86,42.96 PR4602.1
PWR_VCCSA_CSN: length 53.1
  L3 w0.254: v2(38.72,42.2) 38.89,42.37 38.89,44.29 39.37,44.77 39.37,66.86 42.7,70.2 49.31,70.2 50.86,71.75 v2(50.86,71.98)
  BOTTOM w0.203: 34.93,45.81 34.93,46.27 34.79,46.41 PU4601.41
  BOTTOM w0.254: 34.93,45.81 34.96,45.79 34.96,45.31 35.4,44.86 PC4607.1 PC4606.1 35.26,43.64 35.26,42.56 34.96,42.26 34.96,41.29 35.3,40.95 37.47,40.95 v1(38.11,41.59) v2(38.72,42.2) ; PG5001.1 51.16,73.62 50.9,73.35 PR4606.2 50.9,72.02 v2(50.86,71.98)
PWR_VCCSA_CSN_NTC: length 40.2
  TOP w0.254: v1(49.36,71.57) 49.74,71.95 v2(49.74,72.03)
  L3 w0.254: v2(49.74,72.03) 49.74,71.9 48.86,71.02 42.26,71.02 38.61,67.37 38.61,46.16 37.88,45.43 37.88,43.15 v2(37.62,42.89)
  BOTTOM w0.254: PR4606.1 50.01,72.29 v2(49.74,72.03) ; PR4609.2 v2(37.62,42.89)
PWR_VCCSA_CSP: length 44.3
  TOP w0.254: v1(51.01,73.63) v2(50.45,73.63)
  L3 w0.254: v2(50.45,73.63) 50.32,73.5 50.32,71.85 49.12,70.64 42.54,70.64 38.99,67.09 38.99,44.92 38.26,44.19 v2(38.26,42.64)
  BOTTOM w0.254: v2(50.45,73.63) 50.45,74.77 50.25,74.97 PG5011.1 ; v2(38.26,42.64) 37.37,41.75 PR4612.2
PWR_VCCSA_CSP1B: length 5.9
  BOTTOM w0.203: 35.47,45.81 35.26,46.02 35.26,46.4 35.2,46.47 PU4601.40
  BOTTOM w0.254: PR4612.1 35.69,42.55 PR4609.1 36.29,43.15 PC4606.2 PC4607.2 36.29,45.01 v1(35.72,45.59) 35.69,45.59 35.47,45.81
PWR_VCCSA_DRVH: length 6.4
  TOP w0.508: v1(46.67,72.62) 46.67,71.99 v3(46.64,71.96)
  L6 w0.635: v3(46.64,71.96) 46.64,68.8 v3(45.88,68.04)
  BOTTOM w0.305: PU5002.8 45.8,68.12 v3(45.88,68.04) ; PU5001.4 46.43,72.18 v3(46.64,71.96)
PWR_VCCSA_DRVL: length 14.2
  L6 w0.635: v3(42.18,79.22) 42.7,79.22 43.72,78.2 43.72,70.2 43.21,69.69 v3(43.21,69.06)
  BOTTOM w0.305: v3(43.21,69.06) 43.73,68.54 PU5002.5 ; v3(42.18,79.22) 42.22,79.18 PU5003.4
  BOTTOM w0.508: v1(43.21,69.74) v3(43.21,69.06)
PWR_VCCSA_ICCMAX: length 3.6
  BOTTOM w0.203: PU4601.20 34.79,52.98 34.71,53.07 34.71,53.94
  BOTTOM w0.254: PR4660.1 34.65,55.2 v1(34.75,55.1) 34.83,55.02 34.83,54.07 34.71,53.94
PWR_VCCSA_ILIM: length 3.6
  TOP w0.254: PR4611.1 34.96,46.58 v2(34.45,46.07) 34.37,45.99 v1(33.53,45.99) 33.51,46.02 PC4632.1
  BOTTOM w0.203: v2(34.45,46.07) 34.39,46.12 PU4601.42
PWR_VCCSA_IOUT: length 5.4
  TOP w0.254: v2(36.99,45.69) 36.42,46.26 PC4609.2 35.15,45.56 PR4613.1
  BOTTOM w0.203: PU4601.39 35.6,46.32 36.1,45.81
  BOTTOM w0.254: 36.1,45.81 36.86,45.81 v2(36.99,45.69) 37.29,45.38 v1(37.29,45.13)
PWR_VCCSA_PWM: length 30.5
  L3 w0.508: v2(37.88,47.08) 37.74,47.08 37.17,47.66 37.17,52.6 37.97,53.4 37.97,62.37 v2(37.37,62.97)
  L4 w0.508: v2(44.99,65.5) 44.99,65.88 44.18,66.69 41.19,66.69 41,66.89 39.98,66.89 39.31,66.22 39.31,65.04 37.37,63.1 v2(37.37,62.97)
  BOTTOM w0.203: v2(37.88,47.08) 37.75,47.08 37.28,47.55 PU4601.36
  BOTTOM w0.305: v2(44.99,65.5) 44.73,65.76 PU5002.2
  BOTTOM w0.356: v2(37.37,62.97) 36.64,62.97 v1(36.52,62.84)
PWR_VCCSA_SW: length 9.1
  L6 w0.635: v3(47.78,74.01) 46.64,74.01 45.44,72.81 45.44,69.56 v3(45.06,69.18)
  BOTTOM w0.305: PU5002.7 44.73,68.85 v3(45.06,69.18) 45.06,69.93 PC5005.2
  vias: v1(48.55,79.19)
PWR_VCCSA_VSN: length 4.1
  BOTTOM w0.203: 33.6,45.43 PU4601.44
  BOTTOM w0.254: PC4603.1 34.58,44.62 v1(34.5,44.7) 34.46,44.74 PR4605.1 33.6,44.77 33.6,45.43
PWR_VCCSA_VSN_R: length 7.3
  BOTTOM w0.254: PC4603.2 33.64,43.85 PR4605.2 33.56,42.96 PC4605.2 32.99,42.39 32.99,40.1 33.24,39.85 v1(33.74,39.85) PR4604.1
PWR_VCCSA_VSP: length 3.3
  BOTTOM w0.203: 33.2,45.69 PU4601.45
  BOTTOM w0.254: 33.2,45.69 33.2,45.67 v1(33.19,45.66) 33.2,45.66 33.2,45.24 32.88,44.93 32.86,44.93 PC4608.1 PR4608.1
PWR_VCCSA_VSP_R: length 4.4
  BOTTOM w0.254: PR4608.2 PC4608.2 32.61,43.78 PC4605.1 32.61,41.57 v1(32.56,41.52) 32.61,41.47 32.61,40.99 PR4607.2
PWR_VCORE_ADDR_BOOT: length 3.2
  BOTTOM w0.203: v1(35.45,54.05) 35.11,53.72 35.11,53.23 35.2,53.15 PU4601.21
  BOTTOM w0.254: PR4663.1 35.72,55.43 35.72,54.32 v1(35.45,54.05)
PWR_VCORE_ALERT#: length 2.9
  BOTTOM w0.114: PU4601.33 38.09,48.75 38.76,48.08 38.76,47.79 PR4666.2
PWR_VCORE_BOOT: length 4.5
  BOTTOM w0.203: PU4701.35 41.65,61.2 41.29,61.56 41.18,61.56 40.93,61.82
  BOTTOM w0.508: v1(39.35,64.23) 39.35,63.29 PR4701.2 39.66,63.09 40.93,61.82
PWR_VCORE_BOOT_RC: length 2.4
  BOTTOM w0.508: v1(37.2,61.74) 37.26,61.69 PC4706.1 PR4701.1
PWR_VCORE_COMP: length 3.2
  TOP w0.254: PC4619.2 37.17,51.58 37.5,51.91 v2(37.88,51.91) PC4601.2
  BOTTOM w0.203: PU4601.26 37.42,51.55 37.78,51.91 v2(37.88,51.91)
  BOTTOM w0.254: v2(37.88,51.91) 38.28,52.31 v1(38.28,52.32)
PWR_VCORE_COMP_R: length 2
  TOP w0.254: PC4601.1 37.05,53.5 v1(36.96,53.41) 36.96,52.48 PR4636.2
PWR_VCORE_CSN: length 31.8
  TOP w0.254: v1(51.04,60.8) v2(50.45,60.8)
  L4 w0.254: v2(40.55,51.35) 41.29,52.09 43.04,52.09 43.5,52.55 45.88,52.55 46.64,53.31 46.64,54.41 47.07,54.83 48.17,54.83 v2(48.67,54.32) 48.93,54.07 53.91,54.07 54.77,54.93 54.77,58.37 52.59,60.55 50.71,60.55 v2(50.45,60.8)
  BOTTOM w0.203: PC4634.2 38.12,50.83 38.08,50.79 37.41,50.79 37.37,50.75 PU4601.28
  BOTTOM w0.254: PC4634.2 PC4616.2 40.55,51.35 v2(40.55,51.35) ; PG4708.1 v2(50.45,60.8) ; v2(48.67,54.32) 48.67,55.02 PR4633.2
PWR_VCORE_CSNNTC: length 10.6
  L4 w0.254: v2(41.69,50.77) 41.69,51.45 41.94,51.71 43.19,51.71 43.65,52.16 46.04,52.16 47.02,53.15 47.02,54.07 v2(47.28,54.32)
  BOTTOM w0.254: v2(41.69,50.77) 41.75,50.7 41.75,50.09 PR4629.1 ; v1(46.46,54.46) 46.6,54.32 v2(47.28,54.32) 47.28,54.9 PR4633.1
PWR_VCORE_CSP: length 26.6
  TOP w0.254: v1(49.82,60.09) 50.4,60.09 v2(50.45,60.04)
  L4 w0.254: v2(40.85,52.47) 42.88,52.47 43.34,52.93 45.71,52.93 46.26,53.48 46.26,54.57 46.91,55.21 49.05,55.21 49.69,54.58 53.6,54.58 54.36,55.34 54.36,58.23 52.43,60.17 50.58,60.17 v2(50.45,60.04)
  BOTTOM w0.254: PR4627.2 40.01,52.47 v2(40.85,52.47) ; PG4707.1 v2(50.45,60.04)
PWR_VCORE_CSP_1A: length 7.9
  BOTTOM w0.203: PU4601.29 37.52,50.35 37.63,50.46 38.18,50.46 38.32,50.32
  BOTTOM w0.254: 38.32,50.32 38.7,49.94 PC4634.1 PC4616.1 40.1,50.01 40.78,50.01 PR4629.2 40.86,50.8 41.24,51.19 41.24,51.61 41.23,51.63 v1(41.23,51.73) 41.05,51.91 39.55,51.91 PR4627.1
PWR_VCORE_DISB#: length 5.6
  BOTTOM w0.203: PU4701.2 43.25,62.6 43.06,62.78 42.79,62.78 42.57,63.01 42.57,63.23 42.48,63.32
  BOTTOM w0.254: v1(40.72,66.63) 41.43,65.91 41.43,65.48 41.62,65.29 PR4703.1 42.13,64.36 42.13,63.67 42.48,63.32
